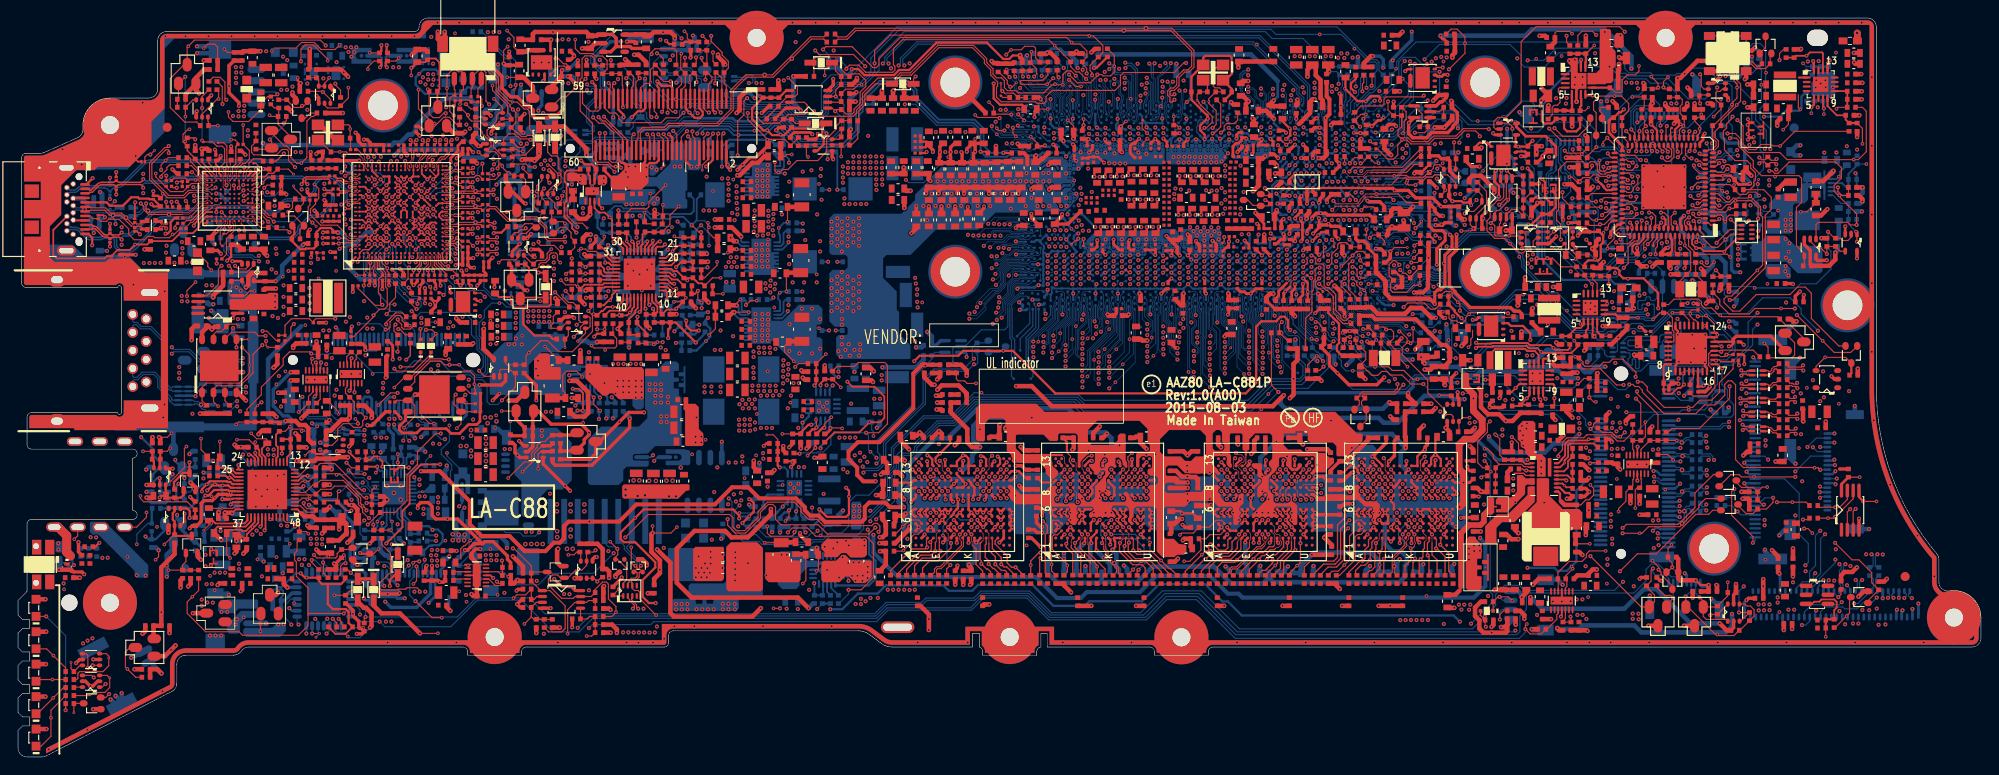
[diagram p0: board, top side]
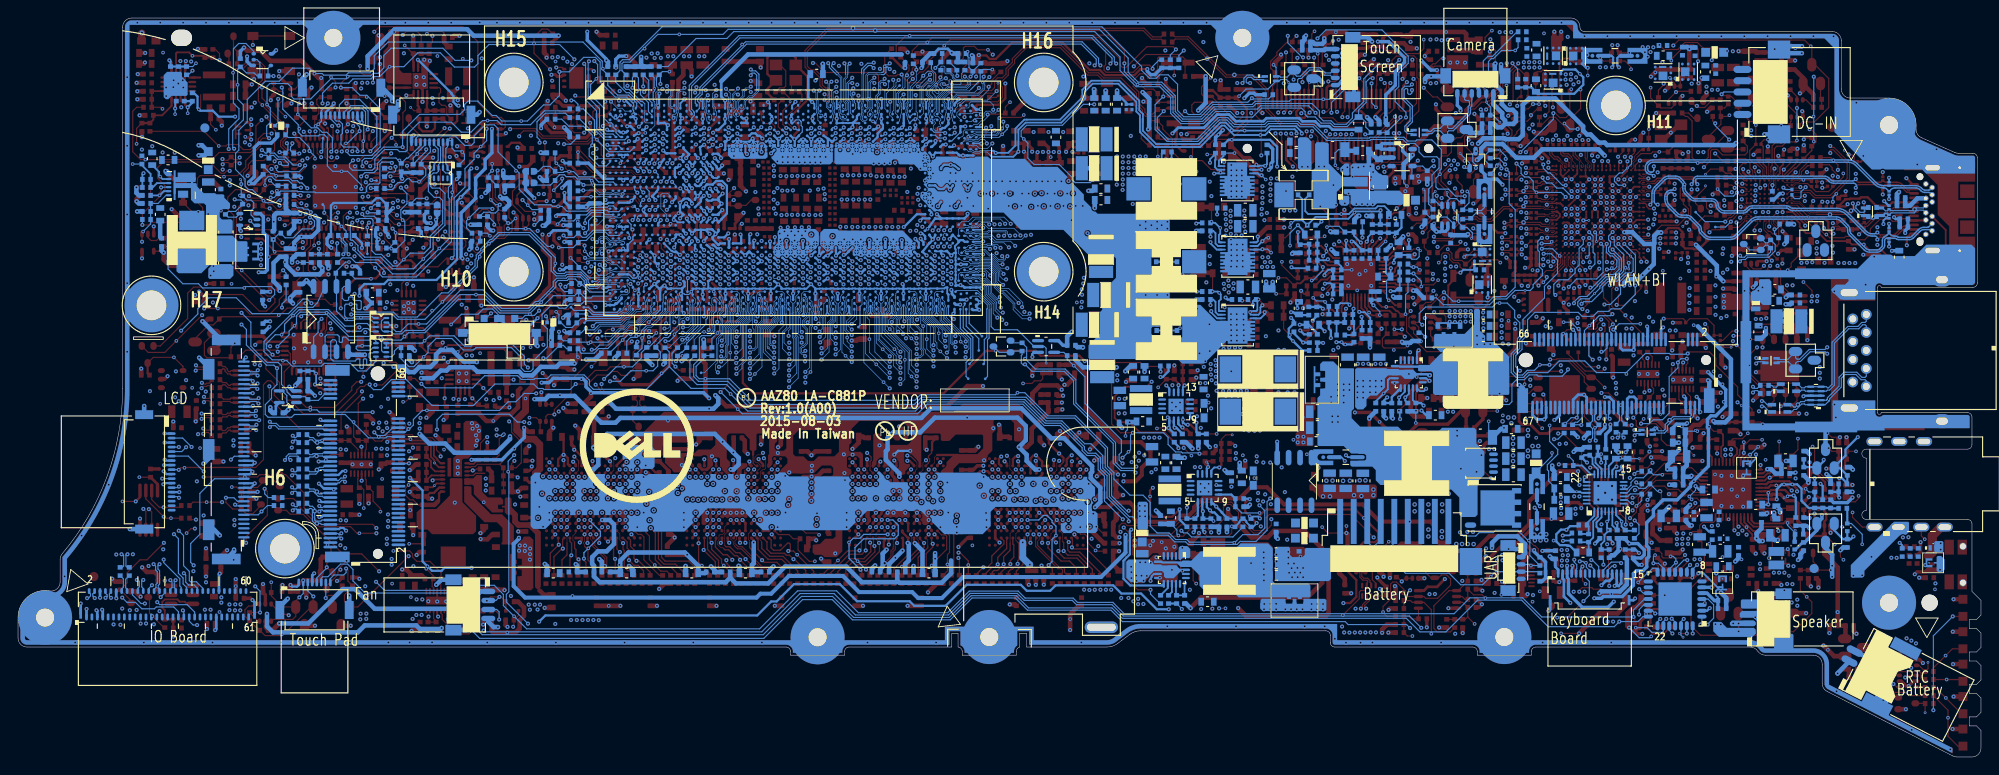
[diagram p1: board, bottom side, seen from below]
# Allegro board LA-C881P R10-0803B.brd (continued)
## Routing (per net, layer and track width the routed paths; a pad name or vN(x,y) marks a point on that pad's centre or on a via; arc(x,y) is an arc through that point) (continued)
+1.0VA_XDP: length 114.6
  TOP w0.127: RC138.1 77.11,77.2 v2(77.11,78.19) ; JXDP1.44 68.1,68.87 v2(68.33,69.1) ; JXDP1.43 68.1,74.3 68.28,74.49 68.28,75.54 67.92,75.9 CC28.1 67.79,75.62 v2(67.49,75.32)
  IN1 w0.081: v2(67.49,75.32) 67.49,75.32 67.49,75.31 68.55,76.36 69.67,76.36 70.15,76.85 70.69,76.85 72.31,78.47 76.84,78.47 v2(77.11,78.19)
  BOTTOM w0.127: RC216.2 69.06,71.79 68.22,72.62 68.22,74.91 67.82,75.32 v2(67.49,75.32) ; RC216.2 69.27,71.01 70.32,69.96 71.83,69.96 72.21,70.34 73.19,70.34 73.88,71.03 74.74,71.03 74.99,71.28 74.99,71.61 75.39,72.01 79.82,72.01 80.82,71.01 82.67,71.01 83.29,71.63 84.91,71.63 86.26,70.28 88.77,70.28 89.91,71.41 89.91,73.16 91.12,74.38 93.74,74.38 95.53,76.17 95.53,77.68 98.34,80.49 138.4,80.49 139.16,79.73 142.58,79.73 145.69,76.62 RC115.2 ; RC216.2 68.83,71.01 68.26,70.44 68.26,69.9 CC29.1 67.87,69.1 v2(68.33,69.1)
+1.0VAP: length 22.1
  IN1 w0.203: v2(203.89,64.78) 203.43,64.32 203.43,58.76 202.46,57.79 202.46,54.97 200.46,52.97 196.14,52.97 195.58,53.53 195.58,54.85 196.14,55.41 v2(196.17,55.41)
  BOTTOM w0.203: v2(203.89,64.78) 204.01,64.65 PC707.1 PR704.1
  vias: v2(196.13,57.49) v2(196.55,57.02) v2(196.62,55.03) v3(196.47,56.07)
+1.0VS_VCCIO: length 170.5
  TOP w0.127: RC132.1 76.43,79.54 v2(75.95,80.02)
  TOP w0.305: UE5.B51 177.8,59.06 177.47,59.06 176.72,58.31 176.72,57.78 v2(176.64,57.71)
  TOP w0.381: v2(127.43,57.79) 127.86,57.36 CC252.1 128.12,57.11 128.63,56.6 CC186.1 128.63,55.94 v2(128.91,55.66)
  TOP w0.508: CC248.1 CC251.1 CC250.1 CC253.1 ; RC2.1 122.28,67.33 v2(122.49,67.12) ; CC252.1 128.75,57.36 CC249.1 ; RE70.1 177.39,72.32 v2(176.94,72.78)
  IN1 w0.381: v2(75.95,80.02) 75.35,80.61 70.62,80.61 69.08,79.07 69.08,77.75 68.64,77.31 68.13,77.31 67.57,76.74 67.05,76.74 66.58,76.27 61.75,76.27 60.45,74.98 v2(60.45,74.8) ; v2(122.49,67.12) 122.16,67.45 122.16,69.36 120.82,70.7 118.16,70.7 117.22,71.64 114.28,71.64 113.28,70.64 113.28,69.7 113,69.43 112.49,69.43 112.49,69.43 111.23,69.43 110.52,68.72 108.18,68.72 107.65,68.18 99.79,68.18 99.52,68.46 94.8,68.46 v2(94.34,68.92) ; v2(165.23,69.71) 165.23,69.5 165.61,69.12 166.12,69.12 168.36,71.36 175.7,71.36 176.94,72.6 v2(176.94,72.78)
  IN2 w0.381: v2(60.45,74.8) 58.46,72.81 58.46,71.65 v2(58.27,71.46)
  IN3 w0.381: v2(94.34,68.92) 94.06,68.92 92.08,66.94 83.53,66.94 81.93,68.54 79.95,68.54 79.38,67.97 74.05,67.97 73.46,68.57 73.46,69.79 72.98,70.27 71.97,70.27 71.69,69.99 59.73,69.99 v2(58.27,71.46)
  IN3 w0.457: v2(168.51,55.34) 168.49,55.34 168.49,55.32 169.06,54.75 171.56,54.75 171.73,54.92 174.49,54.92 176.64,57.07 v2(176.64,57.71)
  IN4 w0.508: v2(122.49,67.12) 124.42,65.19 126.57,65.19 127.08,64.68 127.08,60.82 128.5,59.39 133.48,59.39 135.3,57.57 v2(135.3,57.26)
  BOTTOM w0.254: UCPU1.AM42 128.51,56.05 v2(128.91,55.66) 128.91,56.5 UCPU1.AL42
  BOTTOM w0.381: v2(168.51,55.34) 168.49,55.32 168.49,55.29 168.64,55.44 168.64,60.37 167.03,61.98 167.03,64.25 165.99,65.29 165.99,66.29 165.23,67.05 v2(165.23,69.71) ; CE50.1 177.06,58.31 176.77,58.02 176.77,57.83 v2(176.64,57.71)
  vias: v2(134.37,55.66) v2(135.28,55.66) v2(167.5,55.65) v2(167.54,54.77) v2(167.94,55.2) v2(167.94,54.34) v3(166.57,55.51)
+1.0VS_VCCIOP: length 7.5
  TOP w0.508: v2(170.69,45.98) 170.89,45.78 171.27,45.78 PR1408.1
  IN4 w0.254: v2(170.69,45.98) 168.99,47.68 168.98,47.68 167.46,49.2 167.46,50.2 167.64,50.38 168.4,50.38 168.4,50.37 v2(168.58,50.2)
+1.2V_DDR: length 207.2
  TOP w0.076: 115.83,33.51 115.88,33.46 115.9,33.46 116.1,33.26 116.1,32.64 116.44,32.3 UD20.C12
  TOP w0.127: UD22.F2 152.02,24.3 ; UD19.H3 104.17,25.1 ; 101.82,32.83 101.82,32.71 101.97,32.56 UD19.E12 ; 136.25,33.54 136.25,32.6 135.94,32.3 UD21.E12 ; 141.27,28.3 141.27,28.89 141.06,29.1 UD21.N8
  TOP w0.152: v2(138.56,21.88) 139.12,22.44 139.57,22.44 140.43,23.29 140.43,24.05 140.35,24.12 UD21.M2
  TOP w0.254: v2(129.8,28.43) 129.29,28.94 CD157.1 ; v2(120.02,28.7) 119.69,29.03 UD20.H8 ; CD6.1 125.93,33.82 v2(126.17,33.58) ; UD20.K8 120.99,29.18 v2(120.67,29.5) ; 101.82,32.83 101.82,33.2 v2(102.29,33.68) 103.42,34.81 CD152.1 ; UD20.G12 UD20.H12 ; UD20.H12 119.69,33.34 119.84,33.49 120.52,33.49 v2(120.58,33.55) ; UD20.H12 UD20.H11 ; UD19.A8 99.62,28.82 v2(99.11,28.3) 99.09,28.33 99.09,29.68 99.24,29.83 99.55,29.83 UD19.A9 ; UD20.M2 UD20.L2 121.64,24.01 121.74,23.91 121.74,23.3 v2(121.44,23) ; UD19.G5 103.84,27.02 103.84,27.17 104.17,27.5 UD19.H6 104.19,27.5 104.29,27.6 104.29,28.55 v2(104.32,28.57) 104.17,28.72 104.17,29.1 UD19.H8 ; CD60.1 157.28,35.34 v2(157.28,33.52) ; CD7.1 129.04,33 v2(129.72,32.32) ; v2(153,25.5) 153.32,25.18 UD22.H3 ; UD19.R12 108.97,32.55 108.97,33.08 v2(108.71,33.33) ; UD20.P6 UD20.P5 ; UD19.K8 UD19.K6 105.47,27.42 v2(105.78,27.11) 106.12,26.77 UD19.L5 ; v2(149.75,31.9) 150.07,32.22 UD22.C12 ; UD19.E8 102.22,29.03 v2(101.9,28.7) ; UD19.D6 101.57,27.43 v2(101.9,27.1) ; v2(157.28,33.52) 157.16,33.52 156.8,33.16 156.8,32.53 ; v2(157.28,33.52) 157.39,33.52 157.87,33.04 157.87,32.3 ; v2(104.5,27.1) 104.17,26.78 UD19.H5 ; v2(104.5,27.1) 104.82,26.78 UD19.J5 ; v2(104.5,27.1) 104.82,27.43 UD19.J6 ; v2(137.1,23.77) 137.1,23.77 137.1,24.3 UD21.G2 ; v2(151.7,28.7) 151.7,28.77 UD22.E8 ; v2(125.2,33.55) 124.57,33.55 124.24,33.22 UD20.R12 ; 156.8,32.53 UD22.N12 ; 156.8,32.53 156.8,32.49 156.61,32.3 156.57,32.3 ; UD21.A9 132.64,29.9 132.24,29.5 v2(132.24,28.63) 132.72,29.1 UD21.A8 ; UD22.U9 159.17,29.82 159.64,29.35 159.64,29.24 v2(159.66,29.22) 159.54,29.1 UD22.U8 ; UD22.G2 152.67,24.22 v2(152.35,23.9) 152.02,24.23 152.02,24.3 ; 117.74,32.3 UD20.E12 ; v2(99.26,31.89) 99.62,31.53 UD19.A11 ; 157.87,32.3 UD22.R12 ; 157.87,32.3 157.87,32.3 ; v2(139.83,23.76) 139.7,23.88 UD21.L2 ; UD19.M2 106.77,24.26 v2(106.32,23.81) 106.12,24.01 UD19.L2 ; UD22.P4 157.22,25.98 v2(157.55,26.3) 157.55,26.37 UD22.P5 157.22,26.78 v2(157.55,27.1) 157.32,27.33 157.32,27.36 157.22,27.46 UD22.P6 ; 154.96,26.31 v2(154.96,26.3) ; UD19.K12 105.47,33.12 105.16,33.44 104.9,33.44 v2(104.86,33.47) 104.17,32.79 104.17,32.3 UD19.H12 UD19.G12 ; UD19.K12 UD19.L12 ; UD19.K12 UD19.K11 ; v2(129.76,30.46) 129.76,30.45 129.73,30.48 128.81,30.48 128.45,30.84 CD158.1 ; UD20.F2 118.39,24.3 118.39,23.82 v2(118.29,23.72) ; 136.25,34.25 136.25,33.54 ; 104.17,25.1 103.99,25.28 103.99,25.29 103.85,25.43 v2(103.85,25.5) ; v2(135.48,26.3) 135.15,26.63 UD21.D5 134.83,27.02 v2(134.83,27.1) ; 101.25,27.04 v2(101.25,27.1) ; v2(107.26,28.56) 107.42,28.72 UD19.N8 ; UD21.U9 144.02,29.9 v2(144.13,29.79) ; v2(156.09,34.09) 156.01,34.09 155.27,33.36 UD22.L12 UD22.K12 ; v2(137.43,24.7) 137.75,25.03 UD21.H3 ; v2(118.07,28.67) 117.74,29 UD20.E8 ; v2(156.9,28.7) 156.9,28.77 UD22.N8 ; UD21.F2 136.43,24.3 136.18,24.04 v2(136.18,23.8) ; UD19.U11 110.23,31.71 110.23,31.71 v2(110.67,31.71) 111.06,31.71 111.82,30.95 CD29.1 ; UD22.E12 151.37,32.4 150.43,33.34 v2(150.29,33.34) ; UD19.D4 101.74,26.07 101.75,26.07 101.9,26.21 v2(101.9,26.3) ; UD19.P5 108.07,26.8 v2(107.77,27.1) 108.07,27.4 UD19.P6 ; UD20.H9 119.69,29.83 v2(120.02,29.5) 120.02,29.58 UD20.J9 UD20.J10 ; UD22.U11 159.21,31.5 v2(159.56,31.15) ; UD20.H3 119.69,24.95 UD20.G2 119.04,24.3 119.04,23.79 v2(119.08,23.74) ; 142.3,32.3 UD21.R12 ; v2(116.77,26.3) 116.77,26.38 UD20.D5 116.77,27.02 v2(116.77,27.1) ; UD19.H9 UD19.J9 104.83,29.9 105.15,30.21 v2(105.15,30.3) 104.82,30.63 UD19.J10 104.17,31.35 UD19.H11 ; v2(129.74,31.73) CD175.1 ; CD57.1 147.09,31.58 147.85,32.34 v2(148.16,32.34) 148.16,32.34 148.64,31.86 148.64,31.63 UD22.A11 ; UD19.N12 107.42,32.3 107.42,33.05 107.14,33.33 106.9,33.33 v2(106.84,33.4) ; UD19.P4 108.07,25.97 v2(107.75,26.29) ; CD155.1 113.53,33.51 115.83,33.51 ; v2(100.87,32.81) 100.92,32.76 100.92,32.3 UD19.C12 ; UD22.M2 UD22.L2 155.27,24.03 155.47,23.83 v2(155.47,23.81) ; v2(138.06,31.11) 137.75,31.42 UD21.H11 ; UD20.U11 v2(126.11,31.5)
  TOP w0.305: UD19.K5 105.47,26.8 v2(105.78,27.11) ; v2(103.85,24.7) 103.52,24.38 UD19.G2 ; UD19.F2 102.87,24.04 v2(102.64,23.81)
  TOP w0.32: v2(127.97,53.1) 127.61,52.75 CC258.1 ; CD170.1 162.03,28.94 v2(162.08,28.89) ; v2(138.03,53.1) 138.02,53.1 CC259.1 ; CD169.1 v2(160.73,32.87) ; v2(134.24,49.08) 134.34,49.18 CC178.1 CC176.1 ; CC257.1 131.67,53.06 v2(131.63,53.1)
  TOP w0.381: v2(156.09,34.09) 156.13,34.13 156.13,34.4 156.38,34.65 CD172.1 ; CD179.1 151.81,34.86 v2(150.29,33.34) ; v2(122.22,34.58) 122.5,34.86 CD5.1 ; v2(118.81,33.97) 118.05,34.72 CD1.1 ; CD155.1 CD148.1
  TOP w0.508: RC171.1 130.02,57.74 v2(129.79,57.97) ; CD159.1 115.01,35.85 114.33,36.53 109.65,36.53 v2(109.6,36.48) 110.28,35.8 CD86.1 ; CD4.1 97.84,29.06 v2(98.32,28.58) ; RD17.1 100.56,42.15 101.4,41.3 v2(101.69,41.3) ; v2(98.4,32.9) 98.32,32.98 CD8.1 ; v2(105.54,21.34) 105.54,21.19 105.77,20.96 CD149.1 CD151.1 ; CD168.1 147.45,33.74 v2(148.01,34.3) 148.89,35.18 CD59.1 ; RD21.1 v2(101.98,39.33) ; v2(157.3,38.72) 156.89,38.31 RD22.1 ; v2(106.74,36.36) 106.85,36.24 CD37.1 ; CD3.1 97.68,31.58 v2(98.11,31.15) ; v2(98.91,25.56) 98.91,25.31 97.33,23.73 CD153.1 ; CC179.1 123.1,48.98 v2(123.23,49.11) ; CD33.1 100.5,35.55 v2(100.05,36) 99.7,35.65 CD2.1 ; v2(127.13,22.59) CD160.1 CD154.1 ; CD91.1 v2(143.56,22.44) ; CD63.1 CD175.1
  IN2 w0.254: v2(118.07,28.67) 118.07,28.01 117.16,27.1 v2(116.77,27.1) v2(116.77,26.3)
  IN3 w0.508: v2(165.71,47.28) 162.89,47.28 162.3,46.68 161.64,46.68 160.83,45.88 160.83,44.69 159.66,43.52 159.21,43.52 157.45,41.76 157.45,38.87 v2(157.3,38.72)
  BOTTOM w0.127: UCPU1.AU23 138.33,52.8 v2(138.03,53.1)
  BOTTOM w0.152: UCPU1.BB41 129.33,49.21 ; v2(134.24,49.08) 134.29,49.13 UCPU1.BB32
  BOTTOM w0.178: UCPU1.BB23 139.27,49.9 139.29,49.85 139.29,49.12 v2(139.44,48.96) ; v2(123.23,49.11) 123.22,49.12 123.22,49.66 123.22,49.95 UCPU1.BB51
  BOTTOM w0.254: UCPU1.BB47 125.58,49.91 125.58,49.19 v2(125.65,49.11) ; UCPU1.AU28 v2(135.28,53.1) ; UCPU1.AU35 v2(131.63,53.1) ; 129.33,49.21 129.33,48.64 129.29,48.6 v2(129.29,48.6) ; UCPU1.AU42 v2(127.97,53.1) ; v2(120.58,33.55) 120.16,33.97 v2(118.81,33.97)
  BOTTOM w0.381: CC240.1 101.85,45.68 102.38,46.2 UC2.5
  BOTTOM w0.508: CD34.1 117.45,22.87 v2(118.29,23.72) ; v2(100.89,47.18) 101.4,46.67 CC240.1 ; CD171.1 151.11,20.53 CD64.1 150.98,21.8 150.09,22.69 143.82,22.69 v2(143.56,22.44) 142.34,21.22 CD58.1 141.58,20.41 CD89.1 ; v2(119.08,23.74) 118.97,23.64 118.97,21.8 119.36,21.42 CD41.1 ; CD85.1 136.25,20.53 CD62.1 136.37,21.29 136.18,21.49 v2(136.18,23.8) ; v2(121.44,23) 121.87,22.56 121.87,21.12 122.15,20.84 CD156.1
  BOTTOM w0.762: v2(105.54,21.34) 105.56,21.34 106.32,22.11 v2(106.32,23.81)
  vias: v2(101.25,26.3) v2(110.62,32.93) v2(110.64,28.98) v2(119.37,27.1) v2(120.67,27.1) v2(121.32,27.1) v2(129.77,29.19) v2(132.24,31.58) v2(133.5,33.74) v2(135.62,28.61) v2(137.44,27.11) v2(138.07,29.49) v2(138.08,27.11) v2(138.73,27.09) v2(138.78,28.61) v2(139.38,27.09) v2(140.81,33.36) v2(141.33,27.1) v2(141.33,26.3) v2(144.15,32.39) v2(150.4,27.1) v2(150.4,26.3) v2(151.05,27.1) v2(153,27.1) v2(153.65,30.3) v2(153.65,29.5) v2(153.65,28.7) v2(154.3,29.5) v2(154.3,27.1) v2(154.95,28.7) v2(160.99,23.13) v2(161,22.51) v2(161.01,21.9) v2(161.55,23.45) v2(161.57,22.86) v2(162.14,23.47) v2(162.22,22.88) v3(145.69,37.32)
+1.2V_DDRP: length 17.8
  TOP w0.508: v2(174.32,30.97) 174.04,30.69 PC609.1 PR603.1
  BOTTOM w0.254: v2(174.32,30.97) 172.92,29.57 172.92,21.7 v3(172.38,21.15) 171.88,20.66 170.82,20.66 170.49,20.99 v2(167.49,20.99)
+1.2V_MEM_CPUCLK: length 2
  TOP w0.127: v3(130.18,55.18) 130.04,55.32 130.04,55.44 129.82,55.66 v2(129.79,55.66)
  TOP w0.254: RC171.2 130.02,55.89 v2(129.79,55.66)
  BOTTOM w0.254: v2(129.79,55.66) 129.4,56.05 UCPU1.AM40
+1.8V_PGPP: length 8
  TOP w0.381: RC304.2 149.98,60.14 145.29,60.14 145.1,60.33 v3(144.53,60.33) 144.04,60.33 143.6,59.89 v2(143.6,59.75)
  BOTTOM w0.254: UCPU1.AF16 143.6,59.59 v2(143.6,59.75)
+1.8VA: length 357.2
  TOP w0.254: v2(108.26,74.74) 108.26,73.08 108.97,72.37 111.42,72.37 111.65,72.14 R1334.1
  TOP w0.457: RH150.2 156.46,52.1 155.91,51.55 v2(154.89,51.55)
  TOP w0.508: R79.1 161.2,36.09 v2(161.65,36.53) ; RC304.1 152.38,60.16 152.38,60.62 152.62,60.87 153.31,60.87 CC272.1 154.15,60.41 v2(154.79,61.05) ; RH150.2 RH144.2 156.52,54.36 RH149.2 RH152.2 RH151.2 ; C1169.1 v2(30.28,42.71) ; v2(82.42,16.52) 81.48,15.58 72.77,15.58 72.39,15.96 72.39,21.55 v2(70.92,23.02)
  IN1 w0.508: v2(167.89,69.75) 167.89,69.71 167.23,69.05 167.23,68.16 167.46,67.93 167.46,66.33 167.11,65.97 163.83,65.97 161.19,63.33 161.19,61.76 160.48,61.05 158.83,61.05 158.37,61.5 v2(158.37,61.68)
  IN2 w0.381: v2(167.49,32.98) 167.92,33.41 170.05,33.41 171.17,32.29 171.17,28.36 171.91,27.62 171.91,20.41 168.45,16.95 164.01,16.95 163.89,16.84 162.81,16.84 161.33,15.35 160.79,15.35 160.55,15.11 160.55,14.6 160.34,14.4 158.56,14.4 v2(158.2,14.76) ; v2(161.65,36.53) 161.9,36.53 162.22,36.85 162.22,38.42 161.84,38.8 161.84,41.78 163.36,43.31 163.36,46.43 161.84,47.95 161.17,47.95 160.83,48.29 160.83,49.55 158.83,51.55 v2(154.89,51.55)
  IN2 w0.457: v2(42.91,17.61) 42.93,17.63 42.93,18.42 43.43,18.93 46.13,18.93 46.6,18.46 49.19,18.46 49.53,18.8 53.31,18.8 53.57,19.06 56.83,19.06 57.37,18.53 60.15,18.53 60.36,18.74 62.22,18.74 64.11,20.62 66.31,20.62 67.92,22.23 70.13,22.23 v2(70.92,23.02)
  IN2 w0.508: v2(154.79,61.05) 154.64,61.05 152.65,63.03 152.65,65.76 v2(152.86,65.97)
  IN3 w0.381: v2(82.42,16.52) 83.24,15.71 94.97,15.71 95.53,16.26 99.59,16.26 100.27,15.59 125.36,15.59 125.53,15.77 131.16,15.77 133.25,13.67 157.11,13.67 v2(158.2,14.76) ; v2(126.98,74.99) 126.63,74.99 126.14,74.49 126.14,73.01 126.55,72.6 127.63,72.6 127.99,72.24 128.42,72.24 129.46,73.29 135.18,73.29 136.3,72.16 136.77,72.16 137.34,72.73 137.34,74.57 138.9,76.13 144.41,76.13 144.77,75.78 151.24,75.78 152.59,74.43 153.62,74.43 155.56,72.49 155.56,69 155.22,68.67 154.74,68.67 154.56,68.84 153.42,68.84 153.11,68.54 152.17,68.54 151.71,68.08 151.71,66.48 152.22,65.97 v2(152.86,65.97)
  IN3 w0.508: v2(154.79,61.05) 157.73,61.05 v2(158.37,61.68)
  VCC w0.254: v2(108.26,74.74) 108.42,74.9 111.31,74.9 112.1,74.11 120.85,74.11 121.33,73.63 123.04,73.63 123.48,74.08 123.48,74.6 124.75,75.87 125.8,75.87 126.68,74.99 v2(126.98,74.99)
  IN4 w0.356: v2(154.79,61.05) 154.31,61.05 153.09,59.83 153.09,58.58 151.56,57.06 151.56,54.87 v2(154.89,51.55)
  BOTTOM w0.203: 153.18,61.43 153.13,61.38 152.44,61.38 152.31,61.51 UCPU1.AA1
  BOTTOM w0.381: v2(161.65,36.53) 161.65,35.45 164.12,32.98 v2(167.49,32.98) ; v2(42.91,17.61) 42.11,17.61 41.92,17.8 39.82,17.8 38.57,19.05 38.57,20.35 38.24,20.67 37.5,20.67 37.08,21.09 37.08,22 36.86,22.23 36.86,23.18 37.1,23.42 37.1,26.01 36.35,26.76 36.35,27.46 35.27,28.53 33.71,28.53 32.23,30.01 32.23,30.29 30.24,32.28 30.24,36.48 30.35,36.6 30.35,37.47 29.97,37.85 29.43,37.85 28.32,38.96 28.32,40.75 v2(30.28,42.71)
  BOTTOM w0.508: 153.18,61.43 154.41,61.43 v2(154.79,61.05) CC212.1
  vias: v3(29.67,42.78)
+1.8VAP: length 16
  TOP w0.254: PU800.14 173.42,77.34 v2(173.44,77.36) ; 169.09,71.69 169.09,70.57 169.37,70.29 170.18,70.29 170.66,70.77 PC801.1 PR802.1 171.55,69.76 171.89,69.42 172.91,69.42 173.33,69.84 PR806.2
  BOTTOM w0.254: v2(168.94,72.27) 169.09,72.27 169.21,72.4 169.49,72.68 169.49,73.35 169.7,73.55 169.7,73.65 173.41,77.36 v2(173.44,77.36)
  vias: v3(168.45,77.48)
+1.8VS_AUDIO: length 39.7
  TOP w0.203: v2(23.75,27.06) 24.17,27.48 UA2.36
  TOP w0.508: v2(23.75,27.06) 23.7,27.11 v2(22.96,27.11) 22.96,26.64 CA78.1 ; v2(33.1,23.02) 33.49,22.63 RA81.1
  IN3 w0.508: v2(33.52,34.88) 32.82,35.58 32.82,36.28 33.3,36.76 33.3,37.42 32.94,37.78 32.18,37.78 31.75,38.21 29.86,38.21 v2(29.19,38.88) ; v2(23.75,27.06) 26.8,27.06 31.01,22.84 32.21,22.84 32.39,23.02 v2(33.1,23.02)
  IN4 w0.508: v2(23.75,27.06) 24.41,27.06 26.34,28.99 29.82,28.99 30.91,30.08 30.91,31.61 32.84,33.54 32.84,34.41 33.31,34.88 v2(33.52,34.88)
  BOTTOM w0.508: CA83.1 22.96,26.69 v2(22.96,27.11) ; RA82.1 v2(33.52,34.88) ; v2(23.75,27.06) 23.85,26.96 RA63.1
  vias: v3(28.55,39.4)
+1.8VU: length 61.6
  TOP w0.254: UD21.A6 133.02,27.5 v2(132.65,27.12) 133.07,26.7 UD21.A5 ; UD21.U3 143.6,25.17 v2(143.93,25.5) 143.89,25.54 143.76,25.54 143.6,25.7 UD21.U4 143.6,25.98 v2(143.93,26.3) 143.6,26.63 143.6,26.7 ; UD19.A4 99.62,25.86 99.95,25.54 v2(99.95,25.5) 99.95,25.48 99.62,25.16 UD19.A3 ; CD147.1 98.88,30.44 v2(99.01,30.31) 99.4,30.7 UD19.A10 ; 143.6,26.7 143.6,26.77 v2(143.93,27.1) 143.6,27.43 UD21.U6 ; 143.6,26.7 UD21.U5 ; UD19.U10 110.3,30.7 v2(110.67,31.07) ; UD20.U10 126.03,30.7 v2(126.05,30.72) ; v2(148.4,31.07) 148.77,30.7 UD22.A10 ; v2(143.98,31.11) 143.98,31.08 UD21.U10 ; CD90.1 130.37,27.04 v2(129.16,27.04) 129.16,27.1 128.98,27.28 CD42.1 ; v2(110.35,26.3) 110.02,26.63 110.02,26.7 UD19.U5 110.03,26.7 v2(110.4,27.08) 110.02,27.46 UD19.U6 ; UD20.A3 115.14,25.19 115.45,25.5 v2(115.47,25.5) 115.47,25.55 115.14,25.87 UD20.A4 ; UD21.A10 133.18,30.7 v2(132.69,31.19) ; UD22.A3 148.77,25.17 v2(149.1,25.5) 148.77,25.83 UD22.A4 ; CD145.1 113.61,30.46 v2(114.69,30.46) 114.9,30.46 UD20.A10 ; UD22.A6 148.77,27.49 v2(148.39,27.11) 148.77,26.73 UD22.A5 ; UD20.U3 125.54,25.17 v2(125.87,25.5) 125.54,25.83 UD20.U4 125.54,25.98 v2(125.87,26.3) 125.54,26.63 UD20.U5 125.54,26.78 v2(125.87,27.1) 125.54,27.43 UD20.U6 ; UD21.A3 133.2,25.17 v2(133.53,25.5) 133.2,25.83 UD21.A4 ; v2(160.4,30.45) 159.42,30.45 UD22.U10 ; UD20.A5 115.01,26.7 v2(114.59,27.12) 114.88,27.41 115.05,27.41 UD20.A6 ; UD19.A6 99.42,27.5 99.09,27.17 v2(99.09,27.12) 99.08,27.12 99.07,27.1 99.47,26.7 UD19.A5
  TOP w0.305: UD19.U3 110.35,25.43 v2(110.35,25.5) 110.02,25.83 UD19.U4 110.02,25.98 v2(110.35,26.3)
  TOP w0.32: v2(160.4,30.45) 161.07,30.45 CD144.1
  TOP w0.381: CD143.1 113.01,25.99 113.46,25.54 v2(113.64,25.54) ; v2(143.93,27.1) 144.15,26.88 CD165.1 ; v2(143.98,31.11) 143.98,31.12 144.81,31.12 145.24,30.69 CD163.1 ; v2(113.64,24.9) 113.08,24.9 112.75,25.23 CD164.1 ; v2(143.93,25.5) 144.04,25.61 CD162.1
  TOP w0.508: v2(98.49,27.01) 98.27,26.78 CD92.1 97.33,26.12 97.2,25.99 CD146.1
  TOP w0.762: v2(159.97,27.75) 160.4,28.18 v2(160.4,30.45) 160.4,31.48 159.92,31.96 159.92,34.68 160.5,35.26 161.44,35.26 161.51,35.33 161.52,35.33 162.41,36.22 162.41,36.23 162.47,36.29 162.47,37.42 161.49,38.4 v3(161.49,39.79) 161.49,40.24 160.57,41.17
  vias: v2(158.86,27.1) v2(158.86,26.3) v2(159.55,25.55)
+1.8VUP: length 17.5
  TOP w0.203: PU900.14 168.72,44.63 168.3,45.04 167.48,45.04 167.25,45.27 163.91,45.27 163.33,44.69 PL901.2
  TOP w0.508: 162.08,40.9 162.33,40.65 162.33,38.81 163.11,38.03 164.33,38.03 v3(165.08,37.29) 165.83,37.29 PC901.1 PR902.1 168.94,38.19 PR906.2
+3.3V_ALW_DEG: length 3.8
  BOTTOM w0.127: RE76.2 168.28,66.3 168.28,66.89 v3(168.52,67.13) 168.64,67.25 169.35,67.25 169.65,67.55 JDEG1.1
+3.3V_PGPP: length 14.9
  TOP w0.305: v2(144.35,59.78) 144.37,59.75 CC268.1 144.37,58.75 v2(143.7,58.07)
  TOP w0.381: CC268.1 144.53,59.04 145.25,59.04 145.38,59.17 v3(145.4,59.17) 145.68,58.89 146.6,58.89 147.04,58.44 RC211.2 ; CC267.1 144.81,62.29 144.45,61.93 144.45,61.6 v2(144.36,61.51) ; v2(143.03,63.1) CC265.1 v2(143.03,61.4)
  IN4 w0.381: v2(143.7,58.07) 143.98,58.07 144.44,57.61 v2(144.44,57.28)
  BOTTOM w0.254: v2(144.35,59.78) 144.35,59.8 143.99,60.16 UCPU1.AD15 144.36,60.54 144.36,60.85 144.36,60.86 144.36,61.16 144.36,61.16 v2(144.36,61.51) 144.02,61.85 UCPU1.Y15 143.88,61.96 143.45,61.96 UCPU1.Y16 143.32,61.85 143.03,61.55 v2(143.03,61.4) ; v2(144.44,57.28) 143.99,56.83 UCPU1.AK15 ; UCPU1.AG15 143.99,58.36 v2(143.7,58.07) ; UCPU1.T16 143.34,63.42 v2(143.03,63.1)
+3.3V_SPI: length 2.5
  TOP w0.254: 144.26,57.89 v2(143.63,57.26) ; 144.26,57.89 144.63,58.25 RC213.2 ; 144.26,57.89 v3(144.26,57.89)
  BOTTOM w0.254: v2(143.63,57.26) 143.63,57.36 143.34,57.65 UCPU1.AJ16
+3.3VDX_SSD:
  vias: v2(176.74,26.2) v2(176.75,39.74) v2(176.76,26.91) v2(176.76,25.54) v2(176.95,37.1) v2(176.86,36.5) v2(176.88,24.22) v2(176.89,23.62) v2(177.36,36.14) v2(177.74,37.1) v2(177.82,36.52) v3(177.52,38.85)
+3V_LDO: length 71.9
  TOP w0.381: PR281.1 63.48,33.04 64.11,33.67 PQ222.1 64.56,35.01 v3(66.73,37.18) 67.78,38.24 v2(69.47,38.24) ; v2(56.21,71.37) 55.73,70.89 PC210.1
  IN3 w0.508: v2(56.21,71.37) 56.21,70.77 58.01,68.97 58.01,67.4 ; 58.01,67.4 56.67,66.05 56.67,61.94 57.2,61.41 60.39,61.41 62.54,59.26 63.91,59.26 64.49,58.68 66.57,58.68 67.29,57.97 67.29,56.24 68.28,55.25 68.28,51.75 68.86,51.16 70.08,51.16 74.57,46.67 77.29,46.67 v2(77.95,47.33) ; 58.01,67.4 59.54,67.4 v2(60.77,66.16)
  IN4 w0.381: v2(77.95,47.33) 73.64,43.01 73.64,40.08 72.2,38.64 70.89,38.64 70.49,38.24 v2(69.47,38.24)
+3V_PCH: length 292
  TOP w0.254: RC23.2 156.24,65.39 156.23,65.39 156.08,65.24 156.08,65.24 155.7,64.86 RC12.2
  TOP w0.305: v2(141.71,57.24) 141.71,57.75 CC223.1 ; RC26.2 150.67,55.61 149.78,56.5 RH148.1
  TOP w0.356: v2(158.9,57.95) 159.12,57.73 159.12,56.48 158.33,55.69 158.33,52.31 157.86,51.84 157.52,51.84 157.2,51.51 v2(157.2,50.26) ; v2(141.71,57.24) 141.54,57.24 141.35,57.43 R9.1
  TOP w0.381: CC209.1 141.03,62.32 v2(141.09,62.26) ; RC213.1 146.15,57.85 v2(146.51,57.49) ; v2(157.44,63.15) 156.75,63.84 RC14.2 ; v2(142.6,56.23) 142.79,56.42 CC224.1 ; v2(64.19,75.24) 63.98,75.45 RC133.1 ; RC211.1 148.44,57.49 148.68,57.24 149.37,57.24 149.78,56.83 RH148.1 ; 156.6,50.86 v2(157.2,50.26)
  TOP w0.508: RC187.1 RC74.1 141.96,44.04 141.53,43.62 v3(141.53,41.97) 141.53,40.22 v2(141.12,39.81) ; RC12.2 155.63,64.9 155.06,64.9 v2(154.94,64.78) ; RC26.2 RC184.1 150.67,53.81 RC186.1 150.85,53.68 151.74,52.79 RC183.1 151.74,51.46 152.34,50.86 156.6,50.86
  IN1 w0.254: v2(86.69,80.48) 86.11,80.48 82.99,77.36 79.89,77.36 78.07,79.18 72.69,79.18 72.39,79.48 72.39,79.69 72,80.08 71.04,80.08 69.52,78.56 69.52,77.5 68.88,76.87 68.34,76.87 67.77,76.3 67.24,76.3 66.74,75.8 64.75,75.8 v2(64.19,75.24)
  IN1 w0.381: v2(159.59,58.96) 158.9,58.28 v2(158.9,57.95) 158.9,57.59 159.28,57.21 159.28,56.22 158.39,55.32 158.39,53.91 157.74,53.25 153.33,53.25 152.68,53.91 v2(152.68,54.57) ; v2(154.94,64.78) 156.57,66.41 156.57,70.16 157.57,71.17 157.57,73.25 154.15,76.67 153.16,76.67 v2(152.53,77.3)
  IN1 w0.508: v2(185.8,52.89) 183.85,52.89 182.8,51.85 182.8,49.12 180.68,47 179.4,47 v2(179.27,47.13)
  IN2 w0.381: v2(154.94,64.78) 154.69,64.78 153.9,63.99 153.9,62.59 154.88,61.61 156.76,61.61 157.74,60.63 158.33,60.63 159.59,59.37 v2(159.59,58.96)
  IN2 w0.508: v2(154.76,44.1) 155.14,44.48 156.77,44.48 v2(159.72,41.54)
  IN3 w0.254: v2(86.69,80.48) 86.92,80.7 152.63,80.7 153.31,80.02 154.18,80.02 v2(154.65,80.49)
  IN3 w0.508: v2(181.41,26.24) 181.41,26.39 180.82,26.99 180.82,28.08 178.77,30.13 178.21,30.13 177.04,31.3 177.04,32.29 178.08,33.33 ; v2(179.27,47.13) 180.57,45.83 180.62,45.83 182.98,43.47 182.98,39.18 178.82,35.01 178.82,34.07 178.08,33.33 ; 178.08,33.33 182.25,33.33 184,35.09 184.86,35.09 186.18,36.41 187.52,36.41 189.5,34.43 192.31,34.43 193.71,35.82 195.81,35.82 196.42,35.21 198.38,35.21 199.06,35.89 201.54,35.89 v2(201.55,35.9)
  BOTTOM w0.203: UCPU1.V19 141.39,62.56 v2(141.09,62.26)
  BOTTOM w0.254: JAPS1.1 201.54,35.89 v2(201.55,35.9) ; v2(142.6,56.23) 142.69,56.32 UCPU1.AK17 ; UCPU1.AJ19 v2(141.71,57.24) ; UCPU1.AJ21 139.44,57.66 v2(139,58.1)
  BOTTOM w0.305: v2(157.2,50.26) 157.2,50.51 156.95,50.76 RH59.1 ; v2(158.9,57.95) 158.42,58.43 156.87,58.43 RC283.1
  BOTTOM w0.381: v2(154.65,80.49) 154.65,79.55 152.53,77.43 v2(152.53,77.3) ; RC17.2 156.87,63.71 v2(157.44,63.15) ; v2(159.72,41.54) 158.9,41.54 158.42,42.02 155.16,42.02 154.79,41.65 154.79,41.08 154.13,40.42 141.73,40.42 v2(141.12,39.81) ; v2(157.21,47.29) 157,47.08 RC288.1 ; RC13.1 159.77,70.14 v2(159.77,69.77)
  BOTTOM w0.508: RC191.2 RC189.2 ; RC189.2 RC185.2 RC188.2 ; RC189.2 148.67,76.85 v2(148.67,77.69) ; UH8.8 185.13,52.22 v2(185.8,52.89) 186.21,52.49 CC9.1 ; v2(152.53,77.3) 152.35,77.12 152.35,76.64 RC236.1 ; RH58.1 174.4,44.13 174.11,43.84 v2(174.11,43.83) ; v2(159.59,58.96) 159.36,58.96 158.9,59.42 RC284.1 RC285.1 ; RC73.2 153.8,44.1 v2(154.76,44.1) ; RC25.2 RC15.2 RC17.2
  vias: v2(182.02,26.27)
+3V_PCH_DSW: length 363.1
  TOP w0.305: v2(142.35,59.73) 142.35,59.46 142.52,59.29 142.52,57.36 142.36,57.21 v2(142.36,57.24)
  TOP w0.381: v2(151.6,42.13) 150.77,41.31 147.68,41.31 v3(146.4,42.58) 145.52,43.47 145.52,44.54 144.63,45.42 RC67.1
  TOP w0.457: RC214.2 158.85,45.31 158.43,45.73 157.93,45.73 155.09,48.57 150.62,48.57 150.24,48.95 148.84,48.95
  TOP w0.508: RC95.1 148.84,48.95 RC72.2 ; v2(156.08,43) 156.74,43 CC280.1 CC279.1 158.85,43.9 RC214.2 ; RC243.2 144.91,45.83 RC67.1 ; v2(68.37,77.92) 68.87,77.92 69.7,77.1 RC241.1
  IN1 w0.457: 55.89,78.89 57.3,80.3 67.84,80.3 68.43,79.71 68.43,77.98 v2(68.37,77.92) ; v2(23.85,71.13) 22.18,69.45 17.49,69.45 15.29,67.25 15.29,64.13 15.65,63.77 16.69,63.77 17.34,64.42 18.38,64.42 18.92,63.88 20.23,63.88 20.68,63.43 20.68,61.6 18.92,59.84 18.92,57.9 20.75,56.07 20.75,54.19 22.4,52.53 22.4,38.95 20.96,37.5 19.94,37.5 v2(19.36,38.08)
  IN1 w0.508: v2(151.6,42.13) 152.04,42.58 155.66,42.58 v2(156.08,43) ; 55.89,78.89 46.87,78.89 v2(45.85,79.91)
  IN2 w0.381: 149.56,51.98 149.56,48.37 154.93,43 v2(156.08,43)
  IN3 w0.457: v2(78.79,28.05) 77.47,28.05 76.56,28.97 76.56,30.85 72.07,35.34 66.17,35.34 64.69,36.81 54.36,36.81 52.76,35.21 52.76,31.78 51.23,30.26 46.81,30.26 45.82,29.27 45.82,26.48 44.27,24.93 37.69,24.93 35.54,27.09 35.54,32.43 34.76,33.21 34.76,36.93 33.1,38.59 32.37,38.59 31.61,39.35 29.87,39.35 29.55,39.68 28.34,39.68 26.16,37.5 19.94,37.5 v2(19.36,38.08)
  IN4 w0.457: v2(94.92,24.65) 93.96,24.65 92.99,25.61 92.56,25.61 91.75,26.42 85.4,26.42 84.2,27.62 84.2,27.8 83.69,28.31 82.32,28.31 81.27,27.26 79.25,27.26 78.79,27.72 v2(78.79,28.05) ; v2(23.85,71.13) 23.85,72.6 27.64,76.39 36.5,76.39 38.42,78.31 42.03,78.31 42.37,78.65 44.81,78.65 45.85,79.69 v2(45.85,79.91) ; v2(162.23,24.32) 162.03,24.32 160.99,25.35 160.99,31.31 161.39,31.71 161.39,33.04 160.95,33.49 160.18,33.49 159.39,34.28 159.39,36.79 158.78,37.4 157.77,37.4 154.55,40.62 154.55,41.31 153.33,42.53 151.99,42.53 v2(151.6,42.13)
  BOTTOM w0.254: v2(142.36,57.24) 142.36,57.33 UCPU1.AJ17 ; v2(142.35,59.73) 142.32,59.75 142.32,59.88 UCPU1.AD18
  BOTTOM w0.305: v2(142.35,59.73) 142.35,59.83 UCPU1.AD17
  BOTTOM w0.457: v2(162.23,24.32) 162.23,24.22 162.82,23.63 162.82,18.96 161.54,17.69 135.87,17.69 135.43,18.12 134.24,18.12 132.27,20.09 126.28,20.09 124.49,18.3 118.59,18.3 117.93,17.64 115.29,17.64 112.96,19.97 97.64,19.97 94.92,22.69 v2(94.92,24.65)
+3V_TBT: length 12.7
  TOP w0.127: v2(50.49,56.71) 49.97,57.24 RT21.1
  TOP w0.203: v2(40.22,58.89) UT1.H9
  TOP w0.254: RT33.1 RT34.1 46.84,52.36 v2(46.89,52.31)
  TOP w0.381: v2(32.39,58.51) 32.21,58.33 RT46.2 ; RT51.1 v2(34.19,48.19) ; RT26.1 v2(37.15,51.61)
  IN3 w0.089: v2(46.89,52.31) 47.31,51.89 47.54,51.89 47.74,51.69 48.43,51.69 48.65,51.91 48.65,52.54 48.86,52.74 49.43,52.74 50.07,53.38 50.07,56.28 v2(50.49,56.71)
  vias: v2(24.4,48.59) v2(24.98,48.6) v2(32.39,53.93) v2(32.51,54.82) v2(36.95,56.23) v2(44.75,48.73) v2(44.76,48.15) v2(45.73,50.21)
+3V_TBT_PWR:
  vias: v3(47.93,48.27)
+3V_TBT_S0: length 0.5
  TOP w0.203: UT1.R13 v2(44.13,60.84)
  vias: v2(24.24,52.1) v2(24.7,51.74)
+3V_VC: length 199.6
  TOP w0.203: U722.B1 25.66,64.62 25.81,64.77 v2(25.81,64.96) ; C1354.1 21.95,65.74 22.31,65.38 22.31,64.76 22.51,64.57 U722.H1
  TOP w0.305: PU203.8 61.81,18.46 61.39,18.88 60.35,18.88 v2(59.49,19.74)
  TOP w0.381: v2(22.49,66.7) 22.49,66.52 22.18,66.21 C1354.1 ; PQ223.5 56.6,33.88 57.12,34.41 57.12,35.64 PR275.1 PC218.1 57.13,38.31 PQ221.3 57.71,38.39 59.16,36.93 62.5,36.93 63.36,36.07 v2(63.36,35.98) 63.36,35.75 62.83,35.21 62.83,34.84 PQ222.3 61.93,33.95 PR281.2 PR278.1 ; PR260.1 56.01,18.6 55.47,18.6 v2(55.32,18.45)
  TOP w0.508: v2(54.92,22.26) 56.03,21.14 PR261.1 ; PR259.1 65.59,16.47 v2(65.74,16.33) ; v2(65.59,19.88) 65.59,20.58 65.3,20.86 PR256.1 64.87,23.07 64.29,23.66 PR255.1 PR257.1
  IN1 w0.508: v2(22.49,66.7) 22.98,66.21 25.45,66.21 25.76,65.91 ; v2(25.81,64.96) 25.76,65.01 25.76,65.91 ; 25.76,65.91 26.79,66.94 26.79,67.74 v2(27.18,68.13)
  IN3 w0.508: v2(65.59,19.88) 65.59,20.44 68.01,22.86 69.6,22.86 75.05,28.31 75.05,31.5 71.81,34.73 64.61,34.73 v2(63.36,35.98)
  IN4 w0.508: v2(59.49,19.74) 59.49,19.85 57.07,22.26 v2(54.92,22.26) ; v2(55.32,18.45) 55.32,17.87 54.03,16.57 51.58,16.57 50,14.99 42.69,14.99 42.11,14.41 39.86,14.41 39.21,15.07 39.21,16.19 38.89,16.51 38.04,16.51 35.71,18.83 35.71,24.22 36.3,24.8 36.3,31.76 35.73,32.33 35.73,33.16 36.03,33.46 36.03,34.62 35.51,35.14 35.51,39.46 36.17,40.12 36.17,40.39 36.17,40.4 36.17,40.9 36.17,40.9 36.17,41.27 36.78,41.88 38.83,41.88 39.68,42.74 41.12,42.74 41.43,42.43 42.55,42.43 46.71,46.59 46.71,47.95 50.28,51.52 51.22,51.52 54.65,54.96 54.65,59.43 55.28,60.06 55.28,67.55 v2(55.8,68.07)
  BOTTOM w0.508: v2(55.8,68.07) 55.22,68.65 52.85,68.65 52.75,68.56 51.3,68.56 50.85,69 50.85,72.36 50.14,73.07 47.23,73.07 44.15,69.98 44.15,69.51 43.71,69.07 43.31,69.07 42.41,68.18 41.75,68.18 41.48,67.9 27.41,67.9 v2(27.18,68.13)
+3VA_TBT: length 26.4
  TOP w0.254: UT1.F8 v2(39.57,58.24) ; QT19.2 30.66,58.73 30.66,58.01 30.38,57.73 R1462.1 30.38,57.27 31.31,56.34 31.87,56.34 31.95,56.43 32.82,56.43 33.12,56.73 RT113.1 RT46.1 33.12,58.25 33.57,58.69 34.71,58.69 34.95,58.45 CT57.1
  TOP w0.305: RT36.1 44.3,52.74 43.89,52.33 v2(43.89,52.36) 43.89,52.38 43.66,52.61 RT35.1 ; v2(46.3,51.98) 46.36,52.04 46.36,52.51 46.2,52.66 RT23.1 RT22.1 ; RT25.1 v2(39.6,52.33)
  TOP w0.356: RT47.1 45.19,51.99 v2(45.15,52.02)
  TOP w0.381: v2(35.5,58.17) 35.42,58.25 CT57.1
  BOTTOM w0.508: v2(39.57,58.24) 38.69,58.24 37.38,56.93 36.34,56.93 36.31,56.9 ; v2(39.6,52.33) 39.6,52.6 39.18,53.02 37.99,53.02 v3(36.85,54.16) 36.31,54.69 36.31,56.9 ; 36.31,56.9 36.25,56.97 36.25,57.82 35.87,58.2 35.52,58.2 v2(35.5,58.17)
+3VA_TBT_LC: length 45.8
  TOP w0.127: v2(48.34,72.26) 48.49,72.4 RT6.1 RT7.1 49.2,72.9 50.06,72.9 RT8.1 RT9.1 ; UT1.R6 44.13,57.59 v2(44.13,57.59) ; v2(47.22,51.27) 46.97,51.52 CT50.1
  IN4 w0.081: v2(48.34,72.26) 48.55,72.05 50.08,72.05 51.2,73.17 52.53,73.17 52.92,72.78 52.92,71.93 52.65,71.66 52.36,71.66 52.07,71.37 52.07,70.82 53.46,69.43 53.46,66.88 54.2,66.14 54.2,61.5 53.61,60.91 53.61,59.9 53.79,59.72 53.79,55.3 51.71,53.22 49.9,53.22 49.53,52.85 49.01,52.85 48.56,52.4 48.56,51.89 47.94,51.27 v2(47.22,51.27)
  BOTTOM w0.127: v2(44.13,57.59) 44.13,56.91 44.59,56.45 44.59,54.59 45.04,54.14 45.04,53.73 45.81,52.95 46.89,52.95 47.4,52.44 47.4,51.45 v2(47.22,51.27)
+3VALW: length 412.6
  TOP w0.127: C1162.1 183.06,33.56 v3(183.66,32.96)
  TOP w0.254: PU401.5 171.8,58.27 172.26,58.73 173.94,58.73 PU402.5 175.25,58.27 PC405.1 175.9,57.84 175.9,57.1 175.62,56.82 175.62,55.36 175.36,55.1 174.22,55.1 173.84,54.72 PR1423.1 ; PR404.1 170.03,60.42 170.62,61.01 170.62,62.46 170.36,62.72 PJP15.1 ; PU600.13 171.08,29.9 171.67,29.3 172.11,29.3 PC606.1 ; PR403.1 169.09,60.23 167.92,59.06 v2(167.59,59.06) ; v2(164.31,62.19) 164.31,63.38 163.85,63.85 PU400.8 163.85,64.94 v2(163.97,65.07)
  TOP w0.305: v2(86.86,71.75) 86.6,72.01 PU201.8 85.18,72.01 PR254.1 ; UC9.5 166.28,69.91 167.3,68.88 169.5,68.88 v3(169.85,68.54) 170.64,67.75 170.64,66.76 170.41,66.53 ; PR252.1 85.7,68.89 86.11,69.3 87.93,69.3 v2(88.13,69.11) ; PR403.1 PR404.1
  TOP w0.381: PR224.1 92.87,73.62 v2(93.02,73.77) ; UC8.5 v2(204.05,55.33) ; v2(173.07,57.85) 173.49,58.27 PU402.5 ; QH8.5 7.48,8.4 v2(8.01,7.87) 8.31,7.87 8.84,8.4 QH8.2 ; UC13.5 199.51,55.27 199.67,55.11 200.7,55.11 200.7,55.11 v2(200.7,55.11) ; v2(6.44,10.42) 6.83,10.82 7.15,10.82 QH9.5 ; QH9.2 8.36,10.82 v2(8.34,10.83) ; RT113.2 31.78,56.98 v2(31.62,56.83) ; v2(66.98,19.92) 66.98,19.85 PR100.1 ; C375.1 45.95,21.19 v2(45.92,21.22) ; v3(53.42,40.32) v2(52.68,39.58) ; v2(28.59,52.79) C1289.1 26.24,52.79 U699.5
  TOP w0.457: v2(84.91,34.51) 84.91,34.02 PR1523.1
  TOP w0.508: v2(86.03,75.54) 87.39,75.54 PR226.1 ; C1322.1 v2(195.94,14.08) ; Q41.2 v2(8.33,5.3) ; v2(156.07,43.67) 155.93,43.8 CC271.1 157.2,44.41 RC214.1 ; PR1415.1 v2(204.57,72.98) ; v2(197.84,78.57) 197.79,78.52 PR1424.1 ; PR708.1 v2(204.67,63.2) ; PR1405.1 178.54,47.52 v2(177.57,46.55) 176.82,45.81 PR1404.1 ; v2(171.86,28.66) 172.24,28.66 PC606.1 ; v2(51.69,47.51) 51.66,47.48 51.66,45.3 52.8,44.17 UC11.5 ; PR1522.1 v2(89.51,43.44) ; PR253.1 92.25,69.5 v2(92.41,69.66) ; v2(204.06,68.79) PR1414.1 ; v2(54.46,39.55) 55.32,39.55 PQ221.1 ; v2(187.48,72.53) 187.88,72.53 RE84.1 ; PR1503.1 v2(86.84,34.25)
  IN1 w0.381: v2(40.74,17.24) 38.8,17.24 38.61,17.05 38.14,17.05 35.47,19.72 27.39,19.72 v2(27.06,20.05)
  IN1 w0.508: v2(164.31,62.19) 165.38,63.25 167.04,63.25 169.9,66.12 v2(169.9,66.58) ; v2(204.57,72.98) 203.66,72.07 203.66,69.2 v2(204.06,68.79) 204.67,68.18 v2(204.67,63.2) ; v2(8.33,5.3) 8.33,7.55 v2(8.01,7.87) 6.44,9.44 v2(6.44,10.42) 6.85,10.83 v2(8.34,10.83) 8.34,11.22 7.85,11.72 5.77,11.72 4.01,13.47 4.01,19.24 5.04,20.27 6.1,20.27 6.81,20.98 11.01,20.98 13.77,18.22 13.77,15.77 14.25,15.29 16.33,15.29 19.24,18.2 22.61,18.2 23.53,19.12 26.14,19.12 v2(27.06,20.05)
  IN2 w0.508: 34.9,45.05 34.9,45.4 31.62,48.68 v2(31.62,56.83) 31.62,61.32 30.58,62.36 30.58,63.12 30.13,63.57 30.13,67.34 28.17,69.3 26.6,69.3 ; v2(187.43,34.33) 186.72,34.33 185.78,35.27 185.78,42.34 185.02,43.1 183.79,43.1 183.07,43.82 v2(183.07,47.52) ; v2(204.57,72.98) 203.33,74.23 203.33,76.49 201.83,77.99 198.43,77.99 v2(197.84,78.57)
  IN3 w0.381: v2(59.03,29.22) 55.88,26.07 48.79,26.07 47.6,24.88 47.6,24.3 47.22,23.92 47.22,21.16 46.73,20.67 46.28,20.67 45.92,21.03 v2(45.92,21.22)
  IN3 w0.457: v2(61.06,74.76) 61.06,74.05 62.18,72.93 64.4,72.93 65.12,73.65 78.4,73.65 78.49,73.57 78.51,73.57 80,72.07 86.53,72.07 v2(86.86,71.75)
  IN3 w0.508: v2(86.86,71.75) 87.76,72.65 89.93,72.65 90.31,72.27 91.52,72.27 v2(93.02,73.77) ; v2(173.07,57.85) 173.01,57.9 171.67,57.9 170.51,59.06 v2(167.59,59.06) ; v2(92.41,69.66) 91.24,68.49 88.47,68.49 88.13,68.83 v2(88.13,69.11)
  IN4 w0.508: v2(61.06,74.76) 61.06,75.93 61.1,75.97 61.1,77.39 61.1,77.39 61.1,79.6 v2(61.09,79.61) ; v2(204.06,68.79) 202.16,68.79 200.42,67.06 v2(200.42,67.06) ; v2(187.48,72.53) 187.87,72.92 187.87,77.13 v2(189.17,78.43) 190.61,79.87 196.55,79.87 v2(197.84,78.57) ; 199.83,48.75 199.33,48.75 193.89,54.19 193.89,57.78 193.3,58.37 v2(193.08,58.37) ; 199.83,48.75 203.18,45.4 v2(203.18,40.6) ; 199.83,48.75 199.83,54.24 v2(200.7,55.11) 203.83,55.11 v2(204.05,55.33) 204.85,56.13 204.85,59.19 203.11,60.93 203.11,61.64 v2(204.67,63.2)
  IN4 w1.016: 26.75,70.57 28.84,72.66 30.64,72.66 31.12,73.14 32.09,73.14 32.75,72.48 34.82,72.48 38.66,76.31
  BOTTOM w0.254: v2(201.54,32.99) 201.44,32.89 200.76,32.89 JAPS1.7 ; v2(201.54,34.89) JAPS1.3
  BOTTOM w0.305: v2(195.94,14.08) 195.81,14.2 195.81,15.54 JIO1.49 ; 45.77,19.31 45.77,19.77 45.92,19.92 JKB1.3 45.92,21.21 v2(45.92,21.22)
  BOTTOM w0.381: v2(173.07,57.85) 173.07,57.85 173.08,57.85 173.08,58.3 PC402.1 ; 45.77,19.31 45.77,18.13 44.24,16.6 41.38,16.6 v2(40.74,17.24) ; v2(189.17,78.43) 189.57,78.03 U729.5 ; UC10.5 193.2,58.49 v2(193.08,58.37)
  BOTTOM w0.508: v2(163.97,65.07) 163.97,64.46 PC401.1 PC400.1 ; v2(156.07,43.67) 157.69,43.67 158.06,43.29 159.79,43.29 160.74,42.34 161.78,42.34 162.19,42.75 166.85,42.75 167.34,43.24 169.9,43.24 170.26,42.88 170.92,42.88 171.77,42.03 v2(173.09,42.03) ; v2(93.02,73.77) 92.3,73.05 92.3,69.77 v2(92.41,69.66) ; v2(31.62,56.83) 29.31,54.52 29.31,53.51 v2(28.59,52.79) ; v2(86.84,34.25) PR1503.1 ; v2(164.31,62.19) 164.11,61.98 163.64,61.98 163.3,61.64 163.3,61.29 PR411.1 ; PR410.1 v2(167.59,59.06) ; PR705.1 204.39,62.32 204.67,62.59 v2(204.67,63.2) ; v2(86.03,75.54) 86.03,72.57 v2(86.86,71.75)
  vias: v2(25.5,69.54) v2(25.5,68.92) v2(34.19,43.6) v2(34.82,44.28) v2(35.13,40.1) v2(35.33,40.75) v2(40.51,41.52) v2(40.5,40.92) v2(40.46,40.31) v2(41.63,76.54) v2(42.27,76.54) v2(51.68,48.09) v2(57.25,77.05) v2(58.1,77.08) v2(58.9,77.05) v2(60.42,79.64) v2(73,16.98) v2(73.03,16.38) v2(73.64,16.98) v2(73.66,16.38) v2(74.27,16.98) v2(74.3,16.38) v2(75.29,16.39) v2(75.92,16.39) v2(76.56,16.39) v2(77.19,16.39) v2(78.21,17) v2(78.21,16.39) v2(78.84,17) v2(78.84,16.39) v2(79.53,16.98) v2(79.55,16.39) v2(168.55,15.76) v2(173.03,15.76) v2(173.61,15.76) v2(173.99,34.32) v2(174.03,15.32) v2(174.42,33.93) v2(176.84,34.18) v2(176.86,33.48) v2(177.47,34.21) v2(178.09,34.21) v2(181.41,34.1) v2(182.02,34.15) v2(199.97,39.48) v2(200.38,39.91) v3(198.49,40.96)
+3VALW_5085: length 145
  TOP w0.203: UE5.A52 180.36,57.82 180.36,57.46 179.85,56.95 179.45,56.95 179.15,56.65 179.15,56.12 179.48,55.79 CE41.1
  TOP w0.254: UE5.B3 187.21,60.27 186.53,60.27 v2(186.51,60.28) ; UE5.A26 181.86,68.72 181.86,69.56 v2(181.2,70.21) ; CE64.1 183.24,55.86 183.54,56.16 183.54,57.37 183.36,57.54 183.36,57.82 UE5.A58 ; v2(178.18,71.87) 177.85,71.54 177.65,71.54 RE69.1 ; CE38.1 190.05,64.52 188.06,64.52 UE5.A11 ; v2(169.12,64.13) 169.44,63.8 PJP15.2 169.44,62.09 CE46.1 ; CE63.1 184.32,70.63 184.32,70.07 183.86,69.61 183.86,68.72 UE5.A22 ; UE5.A41 176.93,63.02 176.81,62.9 176.28,62.9 175.95,63.23 175.95,63.28 175.18,64.04 v2(175.18,64.17)
  TOP w0.305: v2(192.19,63.63) 192.09,63.53 190.91,63.53 190.48,63.97 CE38.1 ; RE69.1 176.89,70.95 176.53,70.6 176.53,69.28 178.01,67.8 UE5.B35 ; RE55.2 173.15,59.29 172.06,59.29 v2(172.01,59.24)
  TOP w0.381: CE41.1 179.68,56.46 v2(179.65,56.49) ; v2(183.06,56.51) 183.03,56.47 182.83,56.47 182.35,55.99 CE17.1 CE64.1
  TOP w0.508: CE14.1 CE63.1 184,70.54 v2(183.74,70.29) ; v2(181.2,70.21) CE40.1 ; RE25.1 184.13,75.29 v2(184.18,75.35) 184.45,75.35 v3(184.93,75.82) 186.35,77.25 189.82,77.25 190.94,78.37 192.38,78.37 v2(192.73,78.72) ; RE3.1 173.18,62.09 CE44.1 173,62.95 172.4,63.55 v2(171.59,63.55)
  IN1 w0.381: v2(186.51,60.28) 186.72,60.28 187.1,59.9 187.1,59.17 186.64,58.71 185.32,58.71 183.19,56.57 183.13,56.57 v2(183.06,56.51)
  IN2 w0.381: v2(176.21,60.91) 176.43,60.91 176.84,61.31 176.84,61.96 176.41,62.38 174.81,62.38 173.79,63.41
  IN2 w0.508: v2(179.65,56.49) 179.64,56.5 179.64,56.86 180.42,57.64 181.13,57.64 181.61,57.16 181.61,56.85 182.17,56.3 182.83,56.3 183.04,56.51 v2(183.06,56.51)
  IN3 w0.381: v2(186.51,60.28) 190.41,60.28 191.34,61.22 v2(192.24,61.22)
  IN3 w0.508: v2(172.01,59.24) 172.34,59.24 173.18,60.09 173.18,62.78 174.57,64.17 v2(175.18,64.17)
  IN4 w0.508: v2(192.24,61.22) 192.24,61.27 192.84,61.87 192.84,62.62 ; 192.84,62.62 192.84,62.92 192.19,63.57 v2(192.19,63.63) ; 192.84,62.62 192.98,62.62 193.7,63.34 193.7,65.38 194.32,65.99 194.32,66.48 195.04,67.21 195.04,69.3 194.36,69.98 194.36,77.09 v2(192.73,78.72) ; v2(178.18,71.87) 178.36,71.87 181.84,75.35 v2(184.18,75.35)
  BOTTOM w0.254: RE53.1 183.08,57.97 183.08,61.19 182.8,61.48 178.59,61.48 178.05,62.02 177.6,62.02 RE87.2 ; RE52.1 179.65,57.03 v2(179.65,56.49)
  BOTTOM w0.381: v2(176.21,60.91) 176.68,60.44 RE88.2 ; RE102.1 189.04,68.81 189.34,68.51 189.34,68.49 189.66,68.17 189.68,68.17 189.73,68.12 191.08,68.12 191.59,67.6 191.59,64.39 192.19,63.8 v2(192.19,63.63) 191.63,63.63 191.62,63.63 RE79.2 ; RE75.1 175.18,64.86 RE74.1 175.29,64.27 v2(175.18,64.17) ; RE53.1 183.52,57.53 183.52,56.91 183.18,56.57 183.13,56.57 v2(183.06,56.51) ; v2(172.01,59.24) 172.47,59.24 172.72,59.5 172.72,60.18 RE65.1 ; RE88.2 RE87.2 ; RE88.2 RE56.2 ; RE76.1 168.89,64.36 v2(169.12,64.13) ; RE93.2 193.14,78.31 v2(192.73,78.72)
  BOTTOM w0.508: RE81.1 189.39,58.46 189.39,60.1 189.13,60.36 187.63,60.36 ; 187.63,60.36 CE43.1 186.59,60.36 v2(186.51,60.28) ; 187.63,60.36 188.09,60.82 RE73.2 RE86.2 ; RE72.1 RE75.1
+3VALW_23017: length 24.2
  TOP w0.203: RE13.1 35.23,13.65 36.34,13.65 RE14.1
  TOP w0.254: 34.37,19.19 34.37,16.96 34.93,16.41 36.36,16.41 36.68,16.09 36.68,14.88 RE14.1 ; 34.37,19.19 33.73,19.19 33.38,19.54 RE27.1 v3(32.03,19.9) 31.85,19.9 v2(31.37,20.38) ; 34.37,19.19 35.84,19.19 36.3,19.64 RE24.1
  BOTTOM w0.203: 28.98,18.86 29.41,18.42 29.41,17.93 29.19,17.7 CE3.1 ; 28.98,18.86 29.26,18.86 30.79,20.38 v2(31.37,20.38) ; 28.98,18.86 PJP14.2
  BOTTOM w0.381: CE10.1 CE3.1 29.58,17.36 30.4,18.18 30.96,18.18 UE4.5
+3VALWP: length 12.7
  IN1 w0.203: v2(88.34,19.29) 88.09,19.03 80.12,19.03 v2(79.57,19.59)
  BOTTOM w0.203: PU500.14 89.32,19.21 89.32,18.01 PR504.2 PR502.1 88.37,19.26 v2(88.34,19.29)
  vias: v2(79.59,22.71) v2(79.59,22.11) v2(79.58,21.53) v2(79.57,20.84) v2(79.57,20.2) v3(81,21.51)
+3VLP: length 223.5
  TOP w0.254: v2(184.91,54.24) 185.01,54.34 RE57.2
  TOP w0.508: v2(17.48,12.36) 17.46,12.36 v3(16.98,11.88) 16.29,11.18 D122.2
  IN1 w0.254: v2(159.99,15.02) 160.69,14.31 161.48,14.31 162.91,15.74 165.65,15.74 165.96,15.44 166.33,15.44 166.95,14.82 174.21,14.82 179.88,20.49 179.88,25.34 175.94,29.28 175.94,34.9 175.68,35.16 175.68,42.07 175.74,42.13 175.74,42.86 175.56,43.04 175.56,43.93 176.79,45.17 177.58,45.17 178.21,45.8 178.21,47.42 179.16,48.37 180.78,48.37 181.48,49.07 181.48,50.43 181.92,50.86 181.92,52.31 182.7,53.09 182.7,54.23 183.21,54.75 184.4,54.75 v2(184.91,54.24) ; v2(17.48,12.36) 17.46,12.36 17.46,12.44 19.18,14.16 26.95,14.16 27,14.21 29.85,14.21 30.14,13.91 31.12,13.91 31.42,14.21 37.98,14.21 38.53,13.65 39.16,13.65 39.65,14.14 39.65,14.82 39.64,14.82 39.64,15.22 39.65,15.22 39.65,15.33 39.84,15.52 41.66,15.52 42.7,14.48 49.22,14.48 49.78,14.48 50.86,15.56 54.17,15.56 54.5,15.24 58.47,15.24 59.3,16.07 64.51,16.07 64.85,15.73 70.09,15.73 71.88,17.53 85.42,17.53 v2(86.53,16.42) 87.13,17.02 89.5,17.02 v2(90.12,16.39)
  BOTTOM w0.254: v2(159.99,15.02) 159.3,15.71 135.79,15.71 134.24,17.26 133.64,17.26 131.71,19.18 126.62,19.18 124.72,17.28 118.87,17.28 118.36,16.77 114.88,16.77 112.55,19.1 106.54,19.1 105.88,18.44 103.28,18.44 102.68,19.04 96.28,19.04 95.38,18.14 93.2,18.14 91.45,16.39 v2(90.12,16.39)
+3VS: length 619.4
  TOP w0.254: v2(159.16,61.68) 160.17,61.68 160.33,61.53 160.99,61.53 UC7.5
  TOP w0.305: v2(159.16,61.68) 158.8,62.04 RN20.1 158.8,63.27 QC2.2
  TOP w0.356: v2(157.43,54.62) 157.43,56.39 158.36,57.32 158.36,58.1 158.05,58.4 157.1,58.4 156.59,58.91 RC280.2
  TOP w0.381: C1204.1 60.3,76.16 v2(60.36,76.22) ; v2(158.12,60.03) 157.73,60.03 157.23,60.54 157.23,60.79 RC280.2 ; v2(62.12,77.3) R1179.2 ; 51.54,23.65 48.78,26.41 v3(47.65,26.41) 46.36,26.41 45.95,26.82 45.95,27.8 45.52,28.23 44.68,28.23 44.35,27.9 v2(44.35,27.62) ; 51.54,23.65 51.78,23.9 52.72,23.9 54.31,22.31 54.31,21.93 54.66,21.58 R1141.2 ; 51.54,23.65 50.58,23.65 49.89,22.96 v2(49.58,22.96) ; RC177.2 RC176.2 156.67,66.71 157.61,66.71 157.94,66.38 RN19.1 158.87,66.16 158.87,65.23 QC2.5 158.87,65.23 158.87,65.02 159.56,64.32 v2(159.92,64.32) ; v2(45.34,21.22) 45.24,21.12 45.24,20.66 C377.1 ; PR905.2 164.49,39.98 164.39,39.89 v2(164.39,39.81) ; 156.84,48.74 v2(157.33,48.74) ; v2(176.84,34.96) 176.84,35.06 176.63,35.26 PR600.2 PR601.2 ; RC291.1 152.63,72.71 v2(152.65,72.73) ; RC225.1 159.7,71.5 159.7,70.48 159.22,70 159.22,69.86 158.65,69.29 156.85,69.29 156.28,68.71 154.77,68.71 154.3,69.18 154.3,70.33 v2(154.34,70.36) 154.34,70.39 UC12.5
  TOP w0.457: v2(36.73,34.46) 37.06,34.79 R81.1
  TOP w0.508: v2(204.04,21.04) 203.53,20.53 202.67,20.53 202.29,20.15 RC190.1 ; RC49.1 RC237.1 149.53,49.87 RC50.1 150.14,49.92 150.88,49.18 153.9,49.18 154.56,49.84 155.73,49.84 156.84,48.74 ; v2(185.24,74.28) 185.65,73.87 RE83.1 ; v2(176.58,38.26) 176.2,37.88 RC59.1 ; v2(169.83,72.3) 169.77,72.24 169.77,71.71 ; R884.2 163.7,14.64 v2(163.5,14.44) ; v2(150.32,77.78) 150.12,77.78 149.33,76.98 RC178.2 RC175.2 ; 41,44.54 40.87,44.41 40.87,42.17 v2(40.81,42.11) ; 171.43,14.06 170.99,14.06 170.81,14.24 v2(170.81,14.31) ; C1324.1 195.3,20.48 v2(195.43,20.35) ; RC225.1 159.11,72.73 v2(159.03,72.81) ; v2(62.99,51.75) 63.14,51.9 PR1095.1 ; v2(167.14,15.33) 167.14,15.75 166.68,16.21 R1103.2 ; QZ9.3 59.2,74.41 59.84,75.05 C1204.1
  IN1 w0.381: v2(51.26,48.9) 51.26,49.54 53.37,51.65 53.37,51.9 53.8,52.33 54.89,52.33 56.87,50.35 61.6,50.35 v2(62.99,51.75) ; v2(159.03,72.81) 159.03,72.32 161.65,69.7 161.65,66.05 v2(159.92,64.32) ; v2(191.54,72.6) 190.42,73.72 185.8,73.72 v2(185.24,74.28) 184.69,73.72 180.7,73.72 180.51,73.53 175.62,73.53 174.01,71.92 170.22,71.92 v2(169.83,72.3) ; v2(150.32,77.78) 150.32,77.64 150.04,77.35 150.04,76.23 152.55,73.72 152.55,72.82 v2(152.65,72.73) ; v2(192.54,44.35) 192.54,45.48 196.19,49.13 v2(196.19,50.43) ; v2(151.61,44.23) 150.78,44.23 149.07,45.93 v2(149.07,46.08)
  IN1 w0.457: v2(36.73,34.46) 36.73,34.96 36.14,35.54 36.14,38.11 36.79,38.76 38.86,38.76 39.51,39.4 39.51,41.51 40.16,42.16 40.77,42.16 v2(40.81,42.11)
  IN1 w0.508: v2(176.58,38.26) 176.94,38.26 178,39.33 178,39.46 v2(178.6,40.06) 178.82,39.85 178.82,39.4 179.17,39.05 179.17,36.03 178.36,35.21 177.04,35.21 176.84,35.01 v2(176.84,34.96) ; v2(66.93,79.38) 65.61,78.06 62.88,78.06 v2(62.12,77.3)
  IN2 w0.381: v2(124.56,73.39) 124.54,73.41 124.28,73.41 123.95,73.08 123.95,72.5 124.33,72.13 125.02,72.13 125.25,72.36 126.97,72.36 127.59,72.98 127.59,73.65 128.14,74.2 128.34,74.2 128.63,74.5 130.06,74.5 130.5,74.06 134.42,74.06 134.77,74.42 134.77,77.26 135.15,77.63 138.43,77.63 139.11,76.95 144.58,76.95 144.71,76.81 149.5,76.81 150.32,77.64 v2(150.32,77.78) ; v2(169.83,72.3) 169.83,72.21 170.33,71.71 177.01,71.71 178.31,70.42 v2(179.68,70.42) ; v2(157.43,54.62) 157.08,54.62 154.29,51.83 154.29,51.3 156.86,48.74 v2(157.33,48.74) ; v2(124.23,76.92) 124.23,77.63 121.34,80.53 91.57,80.53 91.06,80.02 88.24,80.02 85.93,77.71 84.27,77.71 83.89,77.34 80.72,77.34 77.38,80.67 70.84,80.67 70.34,80.17 67.41,80.17 66.93,79.69 v2(66.93,79.38)
  IN2 w0.508: v2(170.81,14.31) 170.7,14.21 168.96,14.21 167.84,15.33 v2(167.14,15.33) 165.8,15.33 165.26,15.86 164.09,15.86 163.5,15.27 v2(163.5,14.44) ; v2(195.43,20.35) 193.19,22.59 193.19,23.98 188.92,28.24 188.92,33.19 188.44,33.66 186.42,33.66 185.1,34.98 185.1,39.84 v2(184.86,40.09) 183.22,38.44 179.22,38.44 178.6,39.06 v2(178.6,40.06) ; v2(44.35,27.62) 43.87,28.1 43.87,30.29 43.11,31.04 42.04,31.04 41.1,31.99 41.1,33.12 42.21,34.23 43.85,34.23 44.73,35.1 v2(44.73,35.49) 44.73,35.6 44.32,36.01 43.99,36.01 43.06,36.94 43.06,40.31 41.63,41.74 41.19,41.74 v2(40.81,42.11)
  IN3 w0.381: v2(152.65,72.73) 152.65,72.61 154.34,70.92 v2(154.34,70.36) ; v2(158.12,60.03) 159.16,61.07 v2(159.16,61.68) 158.88,61.96 158.88,63.28 v2(159.92,64.32) ; v2(169.83,72.3) 169.83,72.33 169.22,71.71 167.72,71.71 167.28,72.14 166.35,72.14 165.38,71.17 160.92,71.17 159.28,72.81 v2(159.03,72.81) ; v2(51.26,48.9) 48.51,46.16 48.51,43.16 46.46,41.11 41.82,41.11 v2(40.81,42.11)
  IN3 w0.508: v2(178.6,40.06) 177.64,40.06 176.72,40.98 174.18,40.98 173.46,40.26 171.14,40.26 170.97,40.42 167.02,40.42 166.92,40.32 164.7,40.32 164.39,40.01 v2(164.39,39.81) ; v2(151.61,44.23) 152.69,44.23 153.11,44.65 153.11,45.51 153.41,45.81 154.4,45.81 v2(157.33,48.74) ; v2(149.07,46.08) 149.07,45.23 147.42,43.58 v2(147.42,43.49) ; v2(85.42,38.69) 86.06,38.69 87.55,40.19 87.55,41.64 88.72,42.81 90.07,42.81 90.68,43.42 95.73,43.42 v2(95.91,43.24) ; v2(190.19,15.87) 190.19,16.69 192.3,18.8 192.3,20.01 192.65,20.35 v2(195.43,20.35) 197.05,21.98 199.47,21.98 200.94,20.51 203.51,20.51 v2(204.04,21.04)
  IN4 w0.356: v2(49.58,22.96) 47.31,20.68 45.56,20.68 45.34,20.9 v2(45.34,21.22)
  IN4 w0.381: v2(66.04,70.98) 66.04,67.54 64.01,65.51 64.01,63.69 63.27,62.95 63.27,62.32 61.26,60.31 61.26,56.34 60.21,55.29 60.21,51.48 60.63,51.06 62.31,51.06 v2(62.99,51.75) ; v2(124.23,76.92) 123.95,76.64 123.95,74 v2(124.56,73.39) ; v2(196.19,50.43) 192.05,54.57 192.05,58.09 191.05,59.09 191.05,66.18 191.38,66.51 191.38,71.84 191.35,71.87 191.35,72.32 191.38,72.35 191.38,72.44 v2(191.54,72.6)
  IN4 w0.508: v2(85.42,38.69) 84.81,38.08 78.18,38.08 76.81,36.71 74.17,36.71 73.21,35.75 70.95,35.75 69.23,37.47 68.94,37.47 67.39,39.02 63.76,39.02 63.2,39.59 63.2,41.33 61.65,42.88 61.65,45.35 62.74,46.44 62.74,47.48 64.18,48.93 64.18,50.81 63.25,51.75 v2(62.99,51.75)
  BOTTOM w0.203: JKB1.4 45.42,20.86 45.34,20.94 v2(45.34,21.22)
  BOTTOM w0.254: JLPDE1.1 179.63,71.19 179.63,70.47 v2(179.68,70.42) 179.83,70.42 180.15,70.74 JLPDE1.2 ; v2(192.54,44.35) 192.75,44.13 JEDP.40
  BOTTOM w0.305: RC245.1 149.2,45.96 v2(149.07,46.08) ; U683.5 188.82,39.33 189.21,38.95 189.21,38.31 CS44.1 ; RC292.1 156.82,60.18 157.96,60.18 v2(158.12,60.03) ; v2(195.43,20.35) 195.51,20.27 195.51,18.41 JIO1.50
  BOTTOM w0.381: v2(150.32,77.78) 151.12,77.78 151.49,77.41 RC277.1 ; RH563.1 48.69,19.49 48.31,19.87 48.31,21.63 48.84,22.16 RH562.1 49.58,22.8 v2(49.58,22.96) ; v2(157.33,48.74) 157.02,49.05 RC246.1 156.73,49.04 RC272.1 ; RH440.2 RH441.2 ; v2(184.86,40.09) 185.37,40.6 R220.1 ; v2(60.36,76.22) 61.04,76.22 v2(62.12,77.3) ; v2(66.93,79.38) 65.74,79.38 63.96,77.6 63.96,77.1 64.99,76.07 64.99,74.54 66.04,73.48 v2(66.04,70.98)
  BOTTOM w0.457: v2(44.73,35.49) 45.19,35.95 RC47.1
  BOTTOM w0.483: v2(23.86,47.6) 23.86,46.92 24.32,46.47 RT241.1
  BOTTOM w0.508: RC63.1 62.64,51.75 v2(62.99,51.75) ; RC27.1 151.18,44.69 151.59,44.28 151.61,44.28 v2(151.61,44.23) ; RH441.2 159.56,63.97 v2(159.92,64.32) ; v2(66.04,70.98) 66.04,70.34 RC137.1 ; RC16.1 RC21.1 148.06,44.13 v2(147.42,43.49) ; v2(190.19,15.87) 190.19,14.5 189.51,13.83 180.11,13.83 179.34,14.6 173.62,14.6 173.23,14.21 170.91,14.21 v2(170.81,14.31) ; v2(189.81,38.79) 189.81,38.44 189.56,38.19 CS44.1 ; RE60.1 100.48,44.08 99.64,43.24 v2(95.91,43.24) ; RC228.1 R220.1
  vias: v2(38.75,47.54) v2(39.34,47.55)
+3VS_AUDIO: length 269.4
  TOP w0.381: RC9.1 157.71,49.16 158.15,48.72 v2(158.35,48.72)
  TOP w0.508: LA14.1 37.18,24.41 v2(36.55,23.78) ; RA37.1 14.9,35.45 v2(14.92,35.48) ; RA18.1 19.15,19.21 v2(18.87,18.93)
  IN1 w0.508: v2(14.92,35.48) 14.92,34.95 15.37,34.51 15.37,32.57 16.56,31.38 v2(17.14,31.38) ; v2(32.61,37.04) 33.73,37.04 34.73,36.04 34.73,33.07 35.56,32.24 35.56,26.42 35.03,25.89 35.03,24.9 36.14,23.78 v2(36.55,23.78)
  IN2 w0.381: v2(162.66,28.03) 163.53,27.16 163.53,21.54 161.8,19.81 158.44,19.81 156.49,17.87 132.31,17.87 131.34,18.84 126.81,18.84 125.3,17.33 118.61,17.33 116.94,19 108.26,19 106.89,19 105.76,17.87 103.86,17.87 99.16,22.57 99.16,23.72 98.86,24.02 98.86,24.04 v2(98.68,24.22) ; v2(57.56,19.54) 58.03,19.07 59.91,19.07 60.12,19.28 62,19.28 63.88,21.17 64.46,21.17 65.51,22.21 v2(65.51,22.84) ; v2(158.35,48.72) 158.64,48.72 159.93,47.43 161.65,47.43 162.8,46.28 162.8,43.47 161.32,41.99 161.32,37.73 161.07,37.49 v2(161.07,37.04)
  IN3 w0.508: v2(19.03,33.61) 22.07,36.66 30.49,36.66 30.59,36.76 32.33,36.76 v2(32.61,37.04) ; v2(41.48,23.61) 41.48,22.44 41.28,22.23 41.28,20.96 40.08,19.77 39,19.77 ; v2(98.68,24.22) 97.48,25.42 97.48,34.23 96.37,35.34 95.62,35.34 93.15,37.8 v2(87,37.8) ; v2(36.55,23.78) 36.55,22.85 37.39,22.01 37.9,22.01 39,20.91 39,19.77 ; 39,19.77 30.84,19.77 30.46,20.15 30.46,21.17 28.93,22.69 27.03,22.69 25.25,20.91 25.25,20.66 24.43,19.84 19.78,19.84 v2(18.87,18.93)
  IN4 w0.381: v2(162.66,28.03) 164.3,29.66 164.3,33.65 163.24,34.71 162.54,34.71 161.07,36.17 v2(161.07,37.04) ; v2(57.56,19.54) 57.56,19.62 56.34,20.83 54.46,20.83 54.25,20.62 53.1,20.62 53.06,20.66 50.7,20.66 48.5,18.46 46.73,18.46 45.66,19.53 43.91,19.53 42.44,21 42.44,21.78 41.48,22.74 v2(41.48,23.61)
  IN4 w0.508: v2(65.51,22.84) 65.51,23.5 71.9,29.89 74.05,29.89 79.54,35.38 83.5,35.38 85.93,37.8 v2(87,37.8) ; v2(19.03,33.61) 18.09,32.67 18.09,32 17.47,31.38 v2(17.14,31.38)
  BOTTOM w0.381: RA80.2 34.2,36.52 33.78,36.94 32.72,36.94 v2(32.61,37.04)
  BOTTOM w0.508: RA19.1 19.36,33.94 v2(19.03,33.61) ; RA38.1 16.68,30.92 v2(17.14,31.38)
  vias: v3(33.2,36.69)
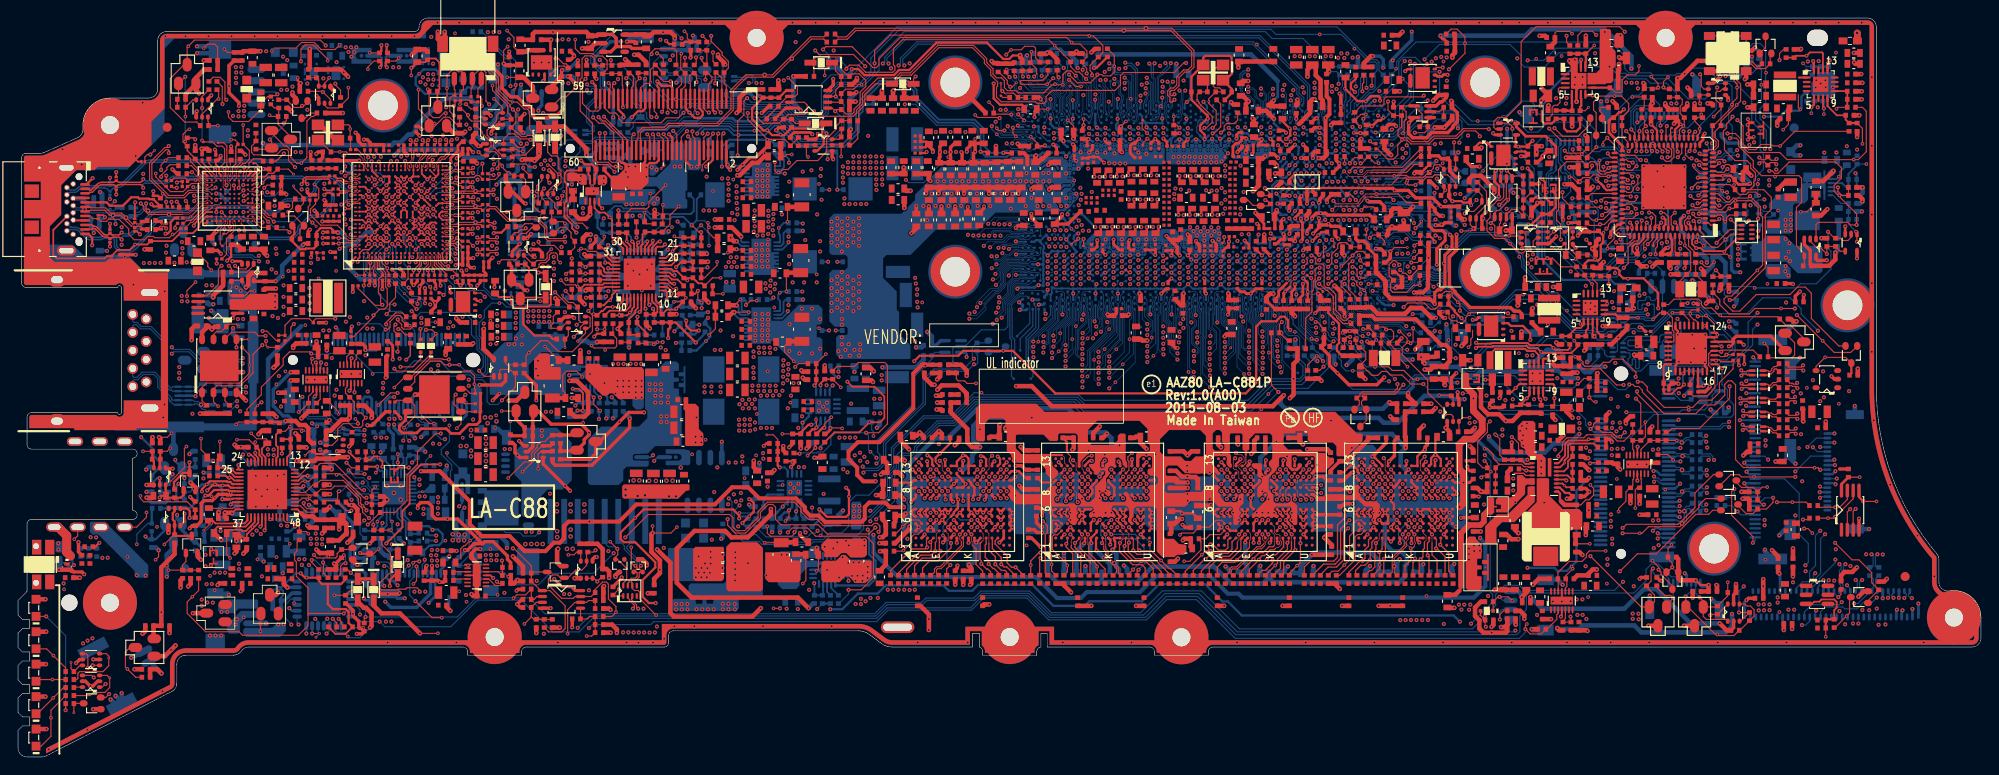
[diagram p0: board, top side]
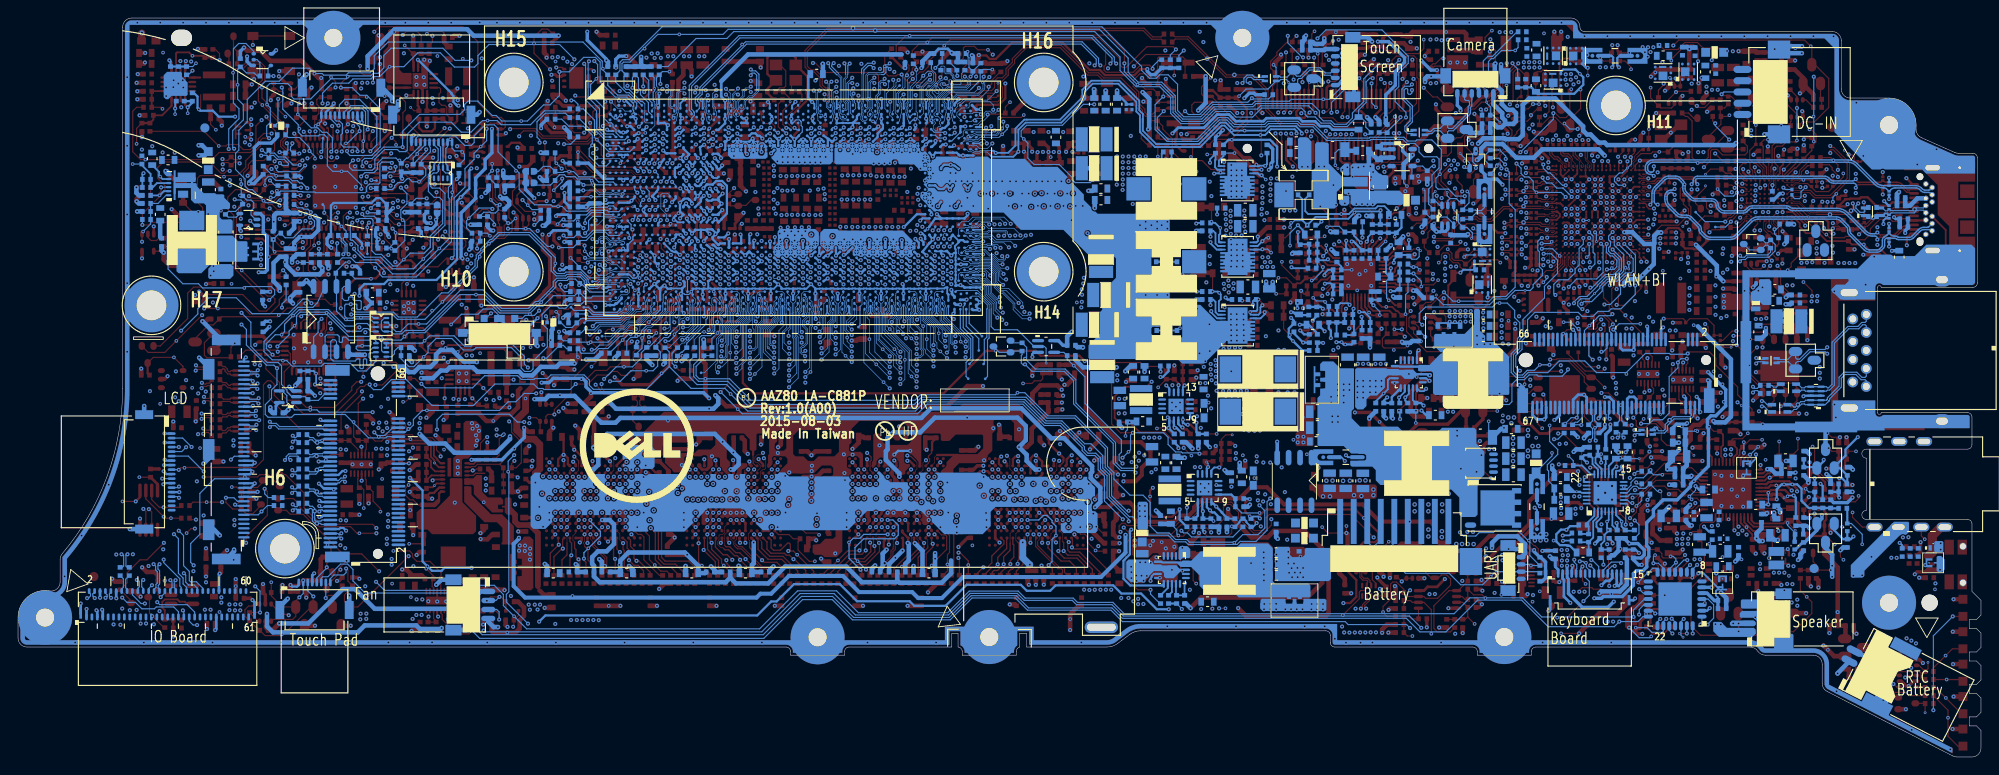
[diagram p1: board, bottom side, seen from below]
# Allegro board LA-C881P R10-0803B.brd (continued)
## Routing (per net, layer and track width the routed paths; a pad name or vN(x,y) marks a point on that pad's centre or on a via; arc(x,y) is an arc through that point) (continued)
+3VS_CAM: length 19.8
  TOP w0.127: v3(54.32,78.83) 53.89,78.4 v2(53.89,76.95)
  TOP w0.381: R2670.2 55.54,76.76 C1220.1 54.07,76.76 v2(53.89,76.95)
  BOTTOM w0.508: 52.81,70.25 51.91,70.25 51.6,70.56 51.6,71.46 51.96,71.81 52.53,71.81 53.16,72.45 53.16,73.91 53.95,74.7 53.95,76.88 v2(53.89,76.95) ; 52.81,70.25 53.19,69.87 53.66,69.87 54.05,70.27 C4.1 C1221.1 ; 52.81,70.25 52.81,70.63 53.12,70.95 53.12,71.46 54.1,72.44 JCAM.1
+3VS_CR: length 1.1
  TOP w0.508: C1325.1 v2(196.95,20.02)
  vias: v2(179.16,15.91) v2(179.17,15.33) v2(179.8,15.9) v2(179.83,15.27) v2(196.44,16.34) v2(196.95,19.39) v2(197.08,16.34) v3(176.3,19.24)
+3VS_NGFF: length 18.7
  TOP w0.508: R80.1 32.59,34.83 32.22,35.2 32.22,36.49 31.86,36.84 31.23,36.84 30.79,37.28 v2(29.68,37.28)
  BOTTOM w0.508: 31.41,47.79 27.75,44.13 27.75,37.76 28.39,37.13 29.53,37.13 v2(29.68,37.28)
  vias: v2(33.88,47.33) v2(34.52,47.33) v2(47.73,47.62) v2(48.29,47.8) v3(31.88,47.91)
+3VS_TP: length 101.2
  TOP w0.254: v3(186.17,19.6) 186.69,19.08 v2(187.58,19.08)
  TOP w0.381: QH7.5 190.36,16.97 190.36,17.98 R1104.2 ; R1105.2 190.36,14.35 190.36,15.07 QH7.2
  TOP w0.508: R1299.1 184.22,21.96 Q40.2 184.22,19.83 184.44,19.6 v3(186.17,19.6) ; v2(190.63,19.19) R1104.2 ; v2(187.58,19.08) 187.58,18.4 C1225.1 C7.1 ; v2(188.82,14.82) 189.59,14.06 R1105.2 ; v2(172.14,65.44) 172.95,65.44 RE6.1 173.13,64.8 RE7.1 ; C1159.1 v2(167.82,17.74)
  IN1 w0.508: v2(167.82,17.74) 168.58,18.5 171.74,18.5 173.94,20.7 v2(173.94,21.17) ; v2(172.14,65.44) 171.8,65.44 170.51,64.15 170.51,63.52 169.33,62.34 169.33,60.98 168.37,60.02 168.37,56.06 v2(168.1,55.79)
  IN2 w0.508: v2(173.94,21.17) 172.92,22.19 172.92,32.85 169.92,35.86 169.92,37.77 171.31,39.16 171.31,40.51 170.18,41.64 170.18,42.76 171.3,43.88 171.3,55.23 170.16,56.37 168.68,56.37 v2(168.1,55.79)
  BOTTOM w0.254: JTP1.1 186.66,19.09 186.84,18.91 187.4,18.91 v2(187.58,19.08)
  BOTTOM w0.508: v2(188.82,14.82) 185.6,14.82 181.79,18.63 180.41,18.63 178.23,16.45 169.11,16.45 v2(167.82,17.74)
+3VS_TPM: length 21.4
  TOP w0.254: U15.22 188.21,46.07 190.29,46.07 C96.1 190.31,45.84 190.04,45.58 v2(189.84,45.58) ; U15.14 186.41,42.77 186.41,41.11 C95.1 186.92,41.11 v2(187.05,41.23) ; RH126.1 190.89,43.53 v2(190.96,43.47)
  TOP w0.381: Q72.3 194.48,46.69 190.65,46.69 190.31,46.35 C96.1
  IN3 w0.508: v2(189.84,45.58) 189.84,45.73 187.69,47.88 183.77,47.88 183.52,48.13 v2(183.17,48.13)
  BOTTOM w0.508: RC229.1 186.54,41.74 v2(187.05,41.23)
  vias: v2(184.28,40.37)
+3VS_TS: length 17.8
  TOP w0.381: 66.36,78.84 65.78,78.26 U728.3 ; 66.36,78.84 66.37,78.85 66.37,79.76 65.94,80.2 65.01,80.2 U728.1 ; 66.36,78.84 67.91,78.84 68.11,78.63 RH357.1
  TOP w0.508: R2671.2 55.79,79.59 C1208.1 57.13,80.22 57.35,80.45 v3(59.35,80.45) 63.06,80.45 C8.1 64.22,80.03 64.34,80.16 U728.1
+3VS_TSLDO: length 12
  TOP w0.508: U728.5 68.54,80.16 C1223.1 69.56,80.17 RH357.2 70.14,80.03 70.54,80.43 v3(71.58,80.43) 72.44,80.43 72.87,79.99 v2(72.87,79.74)
  BOTTOM w0.508: v2(72.87,79.74) 72.87,79.35 73.09,79.13 73.94,79.13 74.14,79.33 C1222.1 C5.1 72.87,78.44 72.76,78.56 71.65,78.56 JTS.6
+5V_USB_P2: length 2
  TOP w0.127: v2(18.75,51.14) 18.75,51.75 v3(19.7,52.7)
  vias: v2(18.16,51.16) v2(18.19,50.58) v2(18.8,50.56)
+5VALW: length 209.8
  TOP w0.076: U722.H10 22.76,59.72 22.76,59.31 22.32,58.87
  TOP w0.127: v2(22.01,58.33) 22.01,58.56 22.32,58.87
  TOP w0.203: v2(36.78,40.65) 36.93,40.8 36.93,41.48 U720.4 ; U716.4 171.3,16.33 171.3,15.68 v2(171.2,15.58) ; U719.4 51.93,20.15 52.43,20.15 52.61,19.96 52.61,19.95 52.63,19.93 52.61,19.91 52.61,19.89 52.64,19.92 52.67,19.92 v2(52.72,19.86) ; v2(179.71,34.43) 179.68,34.4 179.68,33.5 U717.4 ; v2(33.05,43.77) 33.12,43.7 33.12,42.9 U664.4
  TOP w0.254: CZ86.1 167.23,67.19 166.28,67.19 UZ19.3 ; v2(51.31,50.6) 50.96,50.6 UZ23.3 ; v2(167.81,46.29) 167.81,47.01 166.99,47.83 165.65,47.83 165.34,48.14 164.81,48.14 UZ22.3
  TOP w0.305: CZ88.1 158.52,79.38 158.24,79.66 158.09,79.66 157.83,79.92 v2(157.83,80.04) ; UZ25.3 157.21,75.68 157.35,75.68 157.51,75.52 157.99,75.52 158.19,75.73 158.6,75.73 v2(158.62,75.7) ; UZ26.3 58.42,75.17 v2(58.27,75.02)
  TOP w0.381: CZ86.1 167.31,66.66 v2(166.78,66.66)
  TOP w0.457: v2(22.01,58.33) 21.34,57.66 C1347.1
  TOP w0.508: PR1127.2 69.7,47.96 v2(70.1,47.56) ; LED14.2 v2(3.12,13.9) ; v2(193.65,19.73) v3(193.65,18.96) C1321.1 ; PR105.2 v2(36.04,71.46) ; v2(75.22,49.81) 74.68,50.35 PR1128.2 ; LED11.2 v2(3.04,6.7) ; LED10.2 v2(3.09,10.3) ; LED13.2 v2(3.15,3.1) ; LED12.2 v2(3.04,17.5)
  IN1 w0.508: v2(179.02,76.37) 179.02,76.39 179.83,75.57 182.47,75.57 183.36,74.68 184.48,74.68 184.71,74.91 190.04,74.91 190.96,74 192.79,74 196.43,70.35 196.43,62.71 195.1,61.38 195.1,53.31 198.22,50.19 198.22,46.64 200.29,44.57 v2(200.29,42.79) ; v2(167.81,46.29) 166.75,45.23 166.75,43.98 v2(166.9,43.82) ; 158.88,75.7 v2(158.62,75.7) ; 158.88,75.7 158.9,75.68 158.93,75.68 159.16,75.45 159.16,74.1 160.1,73.16 160.1,72.3 162.56,69.83 162.56,69.4 162.84,69.12 162.84,68.74 164.92,66.66 v2(166.78,66.66) ; 158.88,75.7 159.23,75.7 159.79,76.26 159.79,78.08 v2(157.83,80.04)
  IN2 w0.508: v2(36.04,71.46) 36.04,70.92 36.29,70.67 36.29,66.88 v2(36.14,66.72) ; v2(179.71,34.43) 179.89,34.43 182.28,32.04 184.71,32.04 186.36,30.39 186.36,27.31 187.22,26.45 189.81,26.45 191.87,24.39 191.87,21.51 v2(193.65,19.73)
  IN3 w0.508: v2(179.71,34.43) 180.49,34.43 181.1,35.04 182.52,35.04 184.2,36.71 185.29,36.71 185.7,37.12 187.71,37.12 189.76,35.06 192.05,35.06 195.73,38.74 197.59,38.74 200.29,41.45 v2(200.29,42.79)
  IN4 w0.508: v2(24.51,58.44) 24.02,57.95 22.39,57.95 v2(22.01,58.33) ; v2(176.13,43.32) 176.13,42.05 177.93,40.25 177.93,39.3 178.31,38.92 178.74,38.92 179.25,38.41 179.25,34.88 v2(179.71,34.43)
  BOTTOM w0.305: C376.1 47.22,21.09 46.92,20.79 JKB1.1
  BOTTOM w0.508: v2(166.9,43.82) 166.95,43.87 168.35,43.87 169.65,45.17 170.92,45.17 171.43,44.66 171.43,43.9 172.06,43.27 173.3,43.27 173.86,42.71 174.46,42.71 175.07,43.32 v2(176.13,43.32) ; v2(157.83,80.04) 167.26,80.04 167.97,80.76 176.02,80.76 177.58,79.2 179.02,77.76 v2(179.02,76.37) ; v2(65.47,56.79) 65.47,56.79 PR1080.2 ; v2(47.84,22.26) 47.56,21.98 C376.1
  vias: v2(27.71,54.95) v2(28.15,54.11) v2(28.53,51.17) v2(28.52,50.51) v2(28.52,49.9) v2(28.61,56.43) v2(28.63,53.73) v2(28.68,55.82) v2(51.89,22.42) v2(51.92,21.83) v2(52.48,22.42) v2(52.5,21.84) v2(53.13,22.42) v2(53.09,21.83) v2(53.97,18.21) v2(56.61,49.48) v2(56.61,48.89) v2(56.61,48.31) v2(57.2,49.5) v2(57.2,48.9) v2(57.2,48.31) v2(57.78,49.5) v2(57.79,48.9) v2(57.79,48.29) v2(58.37,49.48) v2(58.37,48.85) v2(58.37,48.27) v2(58.97,49.5) v2(58.95,48.91) v2(58.95,48.29) v2(60.68,49.36) v2(67.13,13.83) v2(67.73,13.83) v2(68.31,13.81) v2(68.89,13.81) v2(69.48,13.81) v2(70.08,13.8) v2(70.66,13.82) v2(96.51,18.56) v2(97.1,18.56) v2(97.71,18.56) v2(98.33,18.55) v2(98.93,18.53) v2(99.51,18.56) v2(153.37,15.18) v2(153.97,15.2) v2(154.56,15.2) v2(155.18,15.2) v2(155.8,15.2) v2(156.45,15.2) v2(193.13,16.93) v2(193.15,16.27) v2(193.71,16.94) v2(193.74,16.27) v2(194.35,16.93) v2(194.35,16.3) v3(52.42,23.07) v3(53.21,17.99)
+5VALWP: length 22.6
  IN1 w0.254: v2(54.46,45.81) 53.63,44.98 52.18,44.98 51.73,44.52 51.73,39.16 53.13,37.76 60.61,37.76 v2(61.85,39)
  BOTTOM w0.203: PU501.14 63.04,40.93 63.04,39.6 PR511.2
  BOTTOM w0.254: v2(61.85,39) 62.13,39.28 PR511.2
  vias: v2(55.09,45.81) v2(55.25,46.44) v2(55.91,45.78) v3(55.92,46.74)
+5VS: length 291.5
  TOP w0.254: v2(62.48,66.18) 62.89,65.77 63.68,65.77 64.16,65.29 PC1097.1 64.16,64.79 63.97,64.6 PU1305.6
  TOP w0.508: v2(164.55,14.41) 164.98,14.41 165.25,14.69 ; R886.2 162.32,17.23 161.67,16.58 161.67,15.65 162.15,15.16 162.15,14.25 162.61,13.8 v3(163.53,13.8) 165.07,13.8 165.25,13.98 165.25,14.69 ; 165.25,14.69 C1102.2
  IN1 w0.457: 57.63,57.9 57.13,57.39 57.13,56.98 v2(57.19,56.92)
  IN1 w0.508: 57.63,57.9 57.63,60.68 61.24,64.28 61.24,64.93 v2(62.48,66.18) ; v2(85.55,65.95) 85.12,65.95 84.28,65.11 84.28,61.58 85.5,60.36 v2(85.5,57.74) 85.22,57.74 84.81,57.34 84.81,51.72 85.5,51.04 v2(85.5,50.14) 85.46,50.17 84.07,50.17 84.05,50.15 83.54,50.15 83.52,50.17 81.69,50.17 79.35,47.84 v2(79.35,46.69)
  IN2 w0.508: v2(57.19,56.92) 57.13,56.98 56.61,56.98 56.07,56.44 56.07,54.69 54.47,53.09 52.6,53.09 50.39,50.89 50.39,49.92 v2(49.33,48.85)
  IN3 w0.508: v2(57.19,56.92) 57.13,56.98 56.62,56.98 56.32,56.69 56.32,56.07 56.74,55.65 57.63,55.65 58.36,56.38 59.51,56.38 59.92,55.97 61.8,55.97 62.74,55.03 63.17,55.03 66.24,51.95 66.24,49.66 71.36,44.54 78.6,44.54 79.35,45.3 v2(79.35,46.69) ; 54.69,17.82 54.69,17.36 54.23,16.9 50.52,16.9 49.71,17.71 v2(49.71,17.97) ; 54.69,17.82 54.74,17.77 59.49,17.77 60.14,17.12 61.85,17.12 62.22,17.49 67.09,17.49 68.94,19.34 78.08,19.34 80.19,17.23 91.8,17.23 92.69,16.34 94.69,16.34 95.19,16.84 99.83,16.84 100.5,16.16 125.12,16.16 125.3,16.34 131.4,16.34 133.43,14.31 156.69,14.31 157.82,15.44 158.5,15.44 158.9,15.04 158.9,13.86 159.01,13.75 163.91,13.75 164.52,14.36 164.52,14.37 v2(164.55,14.41) ; 54.69,17.82 54.69,21.57 54.28,21.98 54.28,23.17 v2(54.25,23.2)
  IN4 w0.508: v2(49.33,48.85) 49.33,47.66 46.84,45.17 46.84,44.28 47.23,43.89 47.23,42.35 43.19,38.31 41.1,38.31 40.44,37.65 40.44,36.55 40.87,36.12 41.12,36.12 41.51,35.72 41.51,31.95 43.28,30.18 43.28,27.15 44.5,25.93 51.53,25.93 v2(54.25,23.2) ; v2(49.71,17.97) 48.84,17.1 v2(45.57,17.1)
  BOTTOM w0.203: PU1102.2 84.65,49.08 84.94,49.36 84.94,50.5 85.19,50.76 PC1129.1 v2(85.5,50.14) ; PU1101.2 84.66,56.7 84.94,56.98 84.94,58.12 85.19,58.38 PC1119.1 v2(85.5,57.74) ; v2(85.55,65.95) 85.55,66.33 84.94,66.94 ; 84.94,66.94 PC1114.1 ; 84.94,66.94 84.94,66.28 84.99,66.23 84.99,65.44 84.72,65.17 PU1100.2
  BOTTOM w0.305: v2(45.57,17.1) 46.28,17.81 46.28,19.65 46.42,19.8 JKB1.2
  BOTTOM w0.508: JFAN1.4 165.62,15 165.03,14.41 v2(164.55,14.41) ; JUART.1 50.6,22.6 50.6,23.63 51.44,24.47 53.54,24.47 54.25,23.76 v2(54.25,23.2)
+5VS_AUDIO: length 1
  BOTTOM w0.508: v2(32.28,27.97) 32.74,27.52 CA97.1
  vias: v2(21.81,20.45) v2(22.4,20.45) v2(22.98,20.45) v2(32.48,24.23) v2(32.51,23.64) v2(33.03,24.8) v2(33.14,24.21) v2(33.15,23.63) v2(33.74,24.19) v2(33.74,23.6) v2(45.82,22.39) v2(45.92,22.97) v2(45.92,21.8) v2(46.41,22.39) v2(46.53,22.97) v2(46.51,21.8) v2(46.51,21.22) v3(21.31,20.1)
+AVDD1: length 18.6
  TOP w0.203: v2(23.7,31.94) 24.16,31.48 UA2.26
  IN2 w0.508: v2(23.7,31.94) 21.34,31.94 21.06,32.22 20.27,32.22 19.81,31.75 19.81,30.2 19.38,29.78 18.87,29.78 18.28,29.18 18.28,28.26 21.46,25.08 v2(22.48,25.08)
  BOTTOM w0.508: v2(23.7,31.94) 23.27,31.94 22.79,31.45 CA103.1 22.15,32.46 CA102.1
  vias: v3(23.9,32.98)
+AVDD2: length 7.9
  TOP w0.203: UA2.40 26.66,25.98 25.38,24.7 CA80.1
  TOP w0.508: CA80.1 25.36,24.15 24.93,24.15 24.42,24.66 CA82.1 v2(24.23,23.96)
  BOTTOM w0.508: RA63.2 24.36,25.36 24.9,24.83 v3(24.9,24.25) 24.9,24.25 24.61,23.96 v2(24.23,23.96)
+DVDD: length 22.3
  TOP w0.203: UA2.1 30.99,27.48 31.43,27.03
  TOP w0.508: CA5.1 35.94,26.37 35.64,26.07 v2(35.64,25.26) ; CA5.1 35.9,26.32 CA31.1 CA42.1 CA4.1 32.74,26.7 31.76,26.7 31.43,27.03 ; CA5.1 36.43,25.9 36.43,24.85 ; RA76.1 31.95,34.38 v2(32,34.32) ; 36.43,24.85 35.61,24.02 RA81.2 ; 36.43,24.85 LA14.2
  IN3 w0.508: v2(35.64,25.26) 33.25,27.64 33.25,33.08 v2(32,34.32)
+DVDDIO: length 10.1
  TOP w0.203: UA2.9 31.13,30.68 31.65,31.2 v2(32.13,31.2)
  BOTTOM w0.127: v3(31.47,36.15) RA80.1
  BOTTOM w0.508: CA104.1 33.02,31.1 32.23,31.1 v2(32.13,31.2) ; CA104.1 CA7.1 32.65,32.36 CA6.1 32.8,33.51 RA82.2 RA80.1 ; CA104.1 CA105.1
+PVDD1: length 1.1
  TOP w0.203: UA2.41 27.06,25.72 v2(26.9,25.56)
  vias: v2(26.01,24.67) v2(26.47,25.12) v3(26.01,25.51)
+PVDD2:
  vias: v2(29.19,25.71) v2(29.86,25.64) v3(28.01,26.37)
+V1.8S_EDRAM: length 10.1
  TOP w0.127: v3(114.27,71.89) R1334.2
  TOP w0.254: v2(112.79,71) 112.79,71.64 R1334.2
  TOP w0.508: v2(116,68.36) 115.74,68.63 RC232.1
  IN4 w0.508: v2(116,68.36) 116,70.3 114.84,71.46 113.25,71.46 v2(112.79,71)
  BOTTOM w0.254: UCPU1.H63 116.41,67.7 116,68.11 v2(116,68.36)
+VBUS_DC_SS: length 138.3
  TOP w0.127: v2(44.59,13.72) v3(46.59,13.72)
  TOP w0.508: PD302.2 39.47,16.79 40.33,15.94 42.38,15.94 v2(44.59,13.72) ; PR267.1 v2(60.12,14.36)
  IN2 w0.508: v2(32.1,71.82) 31.89,71.61 31.27,71.61 30.62,72.25 28.29,72.25 27.28,73.27 24.63,73.27 22.63,71.26 22.63,69.22 21.22,67.81 21.22,66.48 19.96,65.22 19.96,64.4 20.65,63.71 20.65,60.35 20.14,59.84 20.14,58.45 20.56,58.03 20.56,57.02 21.31,56.27 22.06,56.27 22.85,57.05 24.68,57.05 25.15,56.58 25.15,54.04 26.75,52.43 26.75,48.62 29.02,46.35 29.02,42.35 v2(28.95,42.27)
  IN4 w0.508: v2(46.05,76.93) 45.42,76.93 44.03,75.54 39.14,75.54 35.06,71.46 32.47,71.46 v2(32.1,71.82) ; v2(60.12,14.36) 58.01,14.36 56.44,15.93 51.84,15.93 49.63,13.72 v2(44.59,13.72) 38.39,13.72 37.47,14.64 32.56,14.64 32.09,15.11 32.09,15.71 33.2,16.81 33.2,21.86 34.52,23.18 34.52,26.37 33.3,27.59 33.3,32.88 34.16,33.74 34.16,34.95 34.42,35.2 34.42,38.92 34.06,39.28 34.06,40.45 33.48,41.03 29.93,41.03 28.95,42.02 v2(28.95,42.27)
+VCC0V9_CIO: length 5.4
  TOP w0.203: UT1.R12 UT1.R11 v2(44.13,59.54)
  TOP w0.254: v2(44.13,59.54) UT1.R9 v2(44.13,58.89) UT1.R8
  TOP w0.305: CT101.1 49.24,54.67 48.65,54.67 v2(48.55,54.57)
  TOP w0.356: CT103.1 CT102.1 CT101.1
  BOTTOM w0.127: v2(44.13,59.54) v1(43.52,59.54)
+VCC0V9_DP: length 9.8
  TOP w0.203: UT1.L12 41.85,60.52 v2(41.52,60.19) 41.85,59.87 UT1.L11 ; UT1.M6 42.49,57.92 v2(42.18,58.23) 41.87,57.92 UT1.L6 ; UT1.V12 45.1,60.51 v2(44.78,60.19) 44.45,60.52 UT1.T12 ; UT1.T11 v2(44.78,59.54) 44.97,59.74 44.97,59.74 UT1.V11
  TOP w0.254: UT1.M8 42.49,58.57 v2(42.17,58.88) UT1.L8 ; UT1.V13 44.78,60.84 v2(44.78,60.84) ; v2(49.2,53.98) 49.38,53.81 CT62.1
  TOP w0.305: CT62.1 CT63.1 CT65.1 CT64.1 CT66.1 51.92,53.65 51.66,53.91 CT67.1 CT68.1
  vias: v3(49.76,54.03)
+VCC0V9_PCIE: length 4.6
  TOP w0.203: UT1.M13 42.5,61.17 v2(42.17,61.49) 42.17,61.51 42.32,61.65 42.34,61.65 UT1.M15 ; UT1.N19 v2(42.82,63.44) UT1.N18 ; v2(42.17,62.14) UT1.M16 42.18,62.79 v2(42.17,62.79) UT1.M18 v2(42.17,63.44) ; v2(42.17,63.44) UT1.L19 ; v2(42.17,63.44) 41.85,63.12 UT1.L18
  vias: v2(42.52,66.63)
+VCC0V9_USB: length 2.4
  TOP w0.127: UT1.R16 43.8,62.46 v2(43.48,62.14) UT1.R15
  TOP w0.381: CT93.1 CT94.1 49.15,66.89 v2(48.69,66.43)
+VCC_CORE: length 46.6
  TOP w0.508: RC140.1 134.87,72.4 v2(134.6,72.67)
  IN3 w0.508: v2(134.6,72.67) 134.56,72.7 v2(131.55,72.7) 129.72,72.7 v2(129.69,72.68)
  BOTTOM w0.127: 132.54,68.13 UCPU1.J33 ; UCPU1.J33 132.54,67.5 ; UCPU1.J33 132.2,67.83 ; UCPU1.J33 132.85,67.83 ; UCPU1.AM33 133,55.75 ; UCPU1.AM33 133,56.35 ; UCPU1.AM33 133.32,56.05 ; UCPU1.AM33 132.66,56.05 ; 129.9,67.4 129.93,67.36 UCPU1.K38 ; 131.17,56.4 131.17,56.39 UCPU1.AM37 ; 132.46,56.04 132.45,56.05 UCPU1.AM35 ; UCPU1.AL33 133.45,56.2 133.45,56.19 ; UCPU1.AL33 133.45,56.83 ; UCPU1.AL33 133.12,56.53 133.12,56.52 ; UCPU1.AL33 133.78,56.53 133.78,56.52 ; 132.08,67.69 UCPU1.K35 ; UCPU1.K35 132.08,66.97 ; UCPU1.K35 132.39,67.36 ; UCPU1.K35 131.72,67.36 131.7,67.34 ; 129.02,56.99 UCPU1.AK40 ; UCPU1.AK40 129.34,57.41 ; UCPU1.AK40 129.34,56.61 ; UCPU1.AK40 129.7,56.99 129.71,56.98 ; 133.38,56.98 133.37,56.99 UCPU1.AK33 ; 133.35,67.34 133.33,67.36 UCPU1.K33 ; 131.17,67.66 UCPU1.K37 ; UCPU1.K37 130.86,67.36 ; UCPU1.K37 131.51,67.36 131.52,67.34 ; UCPU1.K37 131.17,67.02 ; v2(133.23,57.43) 133.23,57.54 133,57.31 UCPU1.AK33 ; 130.71,67.52 UCPU1.J37 ; UCPU1.J37 131.02,67.83 ; UCPU1.J37 130.38,67.83 ; UCPU1.J37 130.71,68.14 ; v2(130.7,68.54) 130.71,68.53 ; UCPU1.K38 130.25,67 ; UCPU1.K38 130.56,67.36 ; UCPU1.K38 130.25,67.68 ; UCPU1.AK37 131.17,56.65 131.17,56.65 ; UCPU1.AK37 131.17,57.33 131.17,57.34 ; UCPU1.AK37 131.49,56.99 ; 131.63,56.85 UCPU1.AL37 ; UCPU1.AL37 131.95,56.53 131.95,56.52 ; UCPU1.AL37 131.29,56.53 131.29,56.52 ; UCPU1.AM38 129.94,56.05 129.8,56.19 UCPU1.AL40 ; UCPU1.AM38 130.57,56.05 ; UCPU1.AM38 130.25,56.39 ; UCPU1.AM38 130.25,55.76 ; UCPU1.K33 133,67.69 ; UCPU1.K33 132.69,67.36 ; UCPU1.K33 133,66.92 ; 127.86,67.34 127.85,67.36 UCPU1.K43 ; 129.71,67.4 129.67,67.36 UCPU1.K40 ; UCPU1.AK35 132.08,57.31 132.08,57.31 ; UCPU1.AK35 131.76,56.99 ; UCPU1.AK35 132.08,56.65 132.08,56.65 ; UCPU1.AM35 132.08,55.76 ; UCPU1.AM35 132.08,56.39 132.08,56.4 ; UCPU1.AM35 131.74,56.05 ; 127.51,67.69 UCPU1.K43 ; UCPU1.K43 127.51,66.95 127.52,66.94 ; 130.25,56.69 UCPU1.AK38 130.25,57.28 ; UCPU1.K42 128.42,67.69 128.38,67.74 ; UCPU1.K42 128.73,67.36 ; UCPU1.K42 128.42,66.98 ; UCPU1.K42 128.08,67.36 128.07,67.34 ; 134.37,68.12 UCPU1.J30 134.06,67.83 ; UCPU1.AM32 133.91,56.38 ; UCPU1.AM32 133.57,56.05 ; UCPU1.AM32 133.91,55.81 133.8,55.71 ; 129.8,56.82 UCPU1.AL40 ; UCPU1.AL40 129.46,56.53 ; UCPU1.AL40 130.14,56.53 ; UCPU1.J40 128.56,67.83 ; UCPU1.J40 129.19,67.83 ; UCPU1.J40 128.88,68.13 ; UCPU1.J40 128.88,67.52 ; UCPU1.K40 129.34,66.97 ; UCPU1.K40 129.03,67.36 ; UCPU1.K40 129.34,67.68 ; 131.17,55.74 UCPU1.AM37 ; UCPU1.AM37 130.82,56.05 ; UCPU1.AM37 131.48,56.05 ; UCPU1.AK33 133,56.68
  BOTTOM w0.203: UCPU1.A34 131.92,72.28 131.67,72.53 131.67,72.58 v2(131.55,72.7) ; v2(129.69,72.68) 129.67,72.68 129.44,72.46 UCPU1.A39 ; UCPU1.A30 134.4,72.48 v2(134.6,72.67) ; UCPU1.G30 134.8,68.29 v2(134.39,68.52) 133.97,68.29 UCPU1.G32 ; UCPU1.G33 133,68.32 v2(132.49,68.6) 132.08,68.37 UCPU1.G35 ; UCPU1.A44 v2(126.97,73.17)
  BOTTOM w0.254: UCPU1.G40 129.09,68.54 v2(128.87,68.54) 128.67,68.54 UCPU1.G42 ; UCPU1.G38 130.5,68.54 v2(130.7,68.54) 130.92,68.54 UCPU1.G37
  BOTTOM w0.305: PC1237.1 130.12,75.55 130.12,73.11 v2(129.69,72.68)
  vias: v2(91.53,65.52) v2(91.53,64.89) v2(91.53,64.31) v2(91.53,63.72) v2(91.7,61.99) v2(91.68,61.35) v2(92.09,66) v2(92.09,65.37) v2(92.09,64.73) v2(92.27,61.36) v2(92.69,66.63) v2(92.69,66) v2(92.69,65.36) v2(92.69,64.73) v2(92.91,61.36) v2(93.32,66.63) v2(93.32,66) v2(93.32,65.36) v2(93.32,64.73) v2(93.54,61.36) v2(93.96,66.63) v2(93.96,66) v2(93.96,65.36) v2(93.96,64.73) v2(94.12,61.37) v2(94.59,66.63) v2(94.59,66) v2(94.59,65.36) v2(94.59,64.73) v2(95.23,66.63) v2(95.23,66) v2(95.23,65.36) v2(95.23,64.73) v2(95.23,64.09) v2(95.23,63.51) v2(95.24,62.92) v2(95.86,66.63) v2(95.86,66) v2(95.86,65.36) v2(95.89,64.73) v2(95.89,64.09) v2(95.89,63.51) v2(101.84,69.35) v2(103.47,69.35) v2(105.12,69.35) v2(128.19,66.58) v2(128.3,62.47) v2(128.3,61.88) v2(128.42,63.08) v2(128.8,66.61) v2(128.75,65.97) v2(129.03,62.98) v2(129.34,65.97) v2(129.34,60.13) v2(129.41,66.58) v2(129.52,64.47) v2(129.92,65.97) v2(130,66.61) v2(130.05,58.78) v2(130.44,58.35) v2(130.51,65.97) v2(130.61,66.58) v2(130.72,64.48) v2(130.66,60.16) v2(130.71,55.61) v2(130.85,58.77) v2(130.83,57.87) v2(131.09,65.97) v2(131.19,66.56) v2(131.24,58.32) v2(131.6,58.78) v2(131.63,57.89) v2(131.64,57.3) v2(131.62,55.63) v2(131.8,66.58) v2(131.75,66) v2(131.93,64.47) v2(131.93,60.16) v2(132.01,58.33) v2(132.39,66.58) v2(132.39,66) v2(132.44,62.85) v2(132.4,58.78) v2(132.4,57.87) v2(132.54,55.63) v2(132.77,58.33) v2(132.97,66.58) v2(132.97,66) v2(133.02,62.85) v2(133.1,60.13) v2(133.2,64.47) v2(133.2,58.73) v2(133.3,58.08) v2(133.53,61.43) v2(133.55,66.1) v2(133.55,63.13) v2(133.73,60.28) v2(133.93,65.06) v2(133.93,64.45) v2(133.93,62.67) v2(133.93,60.87) v2(133.96,65.64) v2(133.96,61.83) v3(126.8,72.22)
+VCC_CORE_G0: length 1.1
  TOP w0.127: v2(134.25,66.99) 133.91,66.65 T122.1
  BOTTOM w0.254: v2(134.25,66.99) 133.91,67.33 UCPU1.K32
+VCC_CORE_G1: length 1.5
  TOP w0.127: v2(133.83,57.69) 133.83,57.23 T123.1
  BOTTOM w0.127: UCPU1.AK32 133.83,57.07 v2(133.83,57.69)
+VCC_EDRAM:
  vias: v2(95.01,39.75) v2(95.01,38.13) v2(95.64,39.75) v2(95.67,38.13) v2(117.7,61.23) v2(117.88,63.15) v2(117.93,61.83) v2(118.01,62.49) v3(117.2,63.97)
+VCC_EDRAM_P: length 15.8
  TOP w0.203: v2(92.02,41.64) 92.58,41.08 95.05,41.08 96.13,40 96.13,37.61 95.66,37.14 v3(94.46,37.14) 93.35,36.03 90.6,36.03 PR1506.1
  TOP w0.508: PC1505.1 94.68,41.8 v2(94.87,41.61)
+VCC_EOPIO: length 0.1
  BOTTOM w0.254: UCPU1.AG62 117.21,58.39
  vias: v2(91.15,35.44) v2(91.73,35.44) v2(92.32,35.44) v2(92.9,35.44) v2(117.46,58.83) v2(118.03,59.03) v2(118.15,58.41) v2(118.81,58.38) v3(116.89,58.61)
+VCC_EOPIO_P: length 9.1
  TOP w0.254: v2(88.91,27.48) 89.75,26.65 91.89,26.65 92.2,26.96 v3(92.2,28.91) 92.2,29.55 v2(91.89,29.87)
  BOTTOM w0.254: v2(88.91,27.48) 88.91,26.34 PR1519.1
  vias: v2(91.56,31.93) v2(92.04,31.59)
+VCC_GT: length 90.7
  TOP w0.254: v2(123.85,61.86) 123.85,61.48 PC1346.1 ; PC1219.1 126.54,58.45 126.54,58.81 v2(126.57,58.84) ; PC1336.1 125.25,58.43 v2(125.25,58.81) ; PC1345.1 126.42,61.5 v2(126.42,61.86) ; PC1221.1 125.73,64.88 v2(125.73,64.55) ; v2(121.92,64.42) 121.92,64.75 PC1347.1 ; PC1344.1 121.41,58.4 v2(121.41,58.84) ; v2(123.19,64.55) 123.19,64.88 PC1223.1 ; PC1342.1 117.2,66.36 v2(117.41,66.15) ; PC1222.1 124.49,64.91 v2(124.49,64.55) ; PC1348.1 120.63,64.73 v2(120.63,64.39) ; PC1220.1 123.98,58.43 v2(123.98,58.81) ; PC1330.1 125.12,61.48 v2(125.12,61.86) ; PC1337.1 122.68,58.4 v2(122.68,58.81) ; v2(120.14,58.81) 120.14,58.4 PC1333.1 ; PC1349.1 119.43,64.8 v2(119.43,64.39)
  TOP w0.305: v2(118.85,67.09) 119.22,67.46 PC1338.1
  TOP w0.381: v2(99.67,61.15) PC1249.1
  TOP w0.457: RC161.1 111.61,67.01 111.99,66.63 111.99,65.74
  BOTTOM w0.127: UCPU1.K55 121.48,67.36 ; UCPU1.K55 120.77,67.36 ; UCPU1.K55 121.11,67.67 ; UCPU1.K55 121.11,67.02 ; 117.52,65.71 UCPU1.M62 ; UCPU1.M62 117.16,65.4 ; UCPU1.M62 116.82,65.71 ; 119.28,57.34 119.28,57.33 UCPU1.AK58 ; UCPU1.K60 118.37,67.72 118.36,67.73 ; UCPU1.K60 118.37,66.99 ; UCPU1.K60 118.71,67.36 ; UCPU1.J52 122.81,67.83 ; UCPU1.J52 122.48,68.13 ; UCPU1.J52 122.15,67.83 ; UCPU1.L62 117.16,66.95 ; UCPU1.L62 116.85,66.62 ; UCPU1.L62 117.51,66.62 ; UCPU1.L62 117.16,66.32 ; 123.04,67.83 UCPU1.J50 ; UCPU1.J50 123.4,68.13 ; UCPU1.J50 123.4,67.47 ; UCPU1.J50 123.75,67.83 ; 125.81,67.83 UCPU1.J45 ; UCPU1.J45 126.49,67.83 ; UCPU1.J45 126.14,67.47 ; UCPU1.J45 126.14,68.13 ; 126.02,56.99 UCPU1.AK46 ; UCPU1.AK46 125.68,56.6 ; UCPU1.AK46 125.33,56.99 ; UCPU1.AK46 125.68,57.33 ; UCPU1.AK53 122.02,56.65 122.02,56.65 ; UCPU1.AK53 122.02,57.36 122.02,57.36 ; UCPU1.AK53 122.42,56.99 ; 124.77,55.74 UCPU1.AM48 ; UCPU1.AM48 124.42,56.05 ; UCPU1.AM48 125.08,56.05 ; UCPU1.AM48 124.77,56.42 ; UCPU1.AL60 118.82,56.88 118.82,56.88 ; UCPU1.AL60 118.82,56.17 118.82,56.17 ; UCPU1.AL60 119.18,56.53 119.18,56.52 ; UCPU1.AL60 118.41,56.53 118.36,56.57 118.37,56.58 UCPU1.AK60 ; 124.42,67.36 UCPU1.K48 ; UCPU1.K48 124.77,66.99 ; UCPU1.K48 124.77,67.7 ; UCPU1.K48 125.14,67.36 ; UCPU1.R63 116.98,64.34 117.16,64.16 UCPU1.T62 ; UCPU1.R63 116.69,63.97 ; UCPU1.R63 116.37,64.34 ; UCPU1.R63 116.69,64.68 ; 122.81,56.52 122.81,56.53 UCPU1.AL53 ; 117.52,62.05 UCPU1.Y62 ; UCPU1.Y62 116.83,62.05 ; UCPU1.Y62 117.16,61.72 ; UCPU1.Y62 117.16,62.4 ; 122.48,56.19 122.48,56.2 UCPU1.AL53 ; 120.19,56.4 120.2,56.39 UCPU1.AM56 119.83,56.05 119.81,56.07 ; UCPU1.AK42 128.72,56.99 ; UCPU1.AK42 128.42,56.68 ; UCPU1.AK42 128.11,56.99 ; UCPU1.AK42 128.42,57.33 ; 121.11,56.63 121.11,56.63 UCPU1.AK55 ; UCPU1.AU63 116.23,53.1 v2(116.08,53.1) ; 116.69,65.56 UCPU1.N63 ; UCPU1.N63 116.32,65.25 ; UCPU1.N63 117.01,65.25 ; UCPU1.N63 116.69,64.93 ; UCPU1.J58 118.82,67.5 118.82,67.5 ; UCPU1.J58 119.15,67.83 119.15,67.83 ; UCPU1.J58 118.82,68.13 ; UCPU1.J58 118.49,67.83 ; 118.99,56.05 UCPU1.AM58 ; UCPU1.AM58 119.28,56.39 ; UCPU1.AM58 119.61,56.05 ; UCPU1.AM58 119.28,55.76 ; 118.92,57.01 118.94,56.99 UCPU1.AK58 ; 117.03,62.51 UCPU1.W63 116.69,62.16 ; UCPU1.AM53 121.71,56.05 ; UCPU1.AM53 122.36,56.05 ; UCPU1.AM53 122.02,55.74 ; UCPU1.AM53 122.02,56.39 ; UCPU1.AK56 120.48,56.99 ; UCPU1.AK56 120.2,56.65 ; UCPU1.AK56 120.2,57.36 120.19,57.36 ; 127.51,57.31 UCPU1.AK43 ; UCPU1.AK43 127.14,56.99 ; UCPU1.AK43 127.51,56.65 ; UCPU1.AK43 127.86,56.99 ; 122.62,56.05 UCPU1.AM52 ; UCPU1.AM52 122.94,56.37 ; UCPU1.AM52 123.28,56.05 ; UCPU1.AM52 122.94,55.74 ; UCPU1.J56 119.74,67.47 ; UCPU1.J56 119.74,68.1 ; UCPU1.J56 119.36,67.83 ; UCPU1.J56 120.09,67.83 ; UCPU1.AL46 126.49,56.53 ; UCPU1.AL46 125.81,56.53 ; UCPU1.AL46 126.14,56.2 ; UCPU1.AL46 126.14,56.85 ; UCPU1.J60 118.26,67.83 ; UCPU1.J60 117.91,68.13 ; UCPU1.J60 117.91,67.54 ; UCPU1.AL56 120.33,56.53 ; UCPU1.AL56 120.95,56.53 ; UCPU1.AL56 120.65,56.26 ; UCPU1.AL56 120.65,56.85 ; 124.92,67.83 UCPU1.J46 ; UCPU1.J46 125.22,67.47 ; UCPU1.J46 125.58,67.83 ; UCPU1.J46 125.22,68.13 ; 123.85,67.02 UCPU1.K50 ; UCPU1.K50 123.85,67.7 ; UCPU1.K50 123.53,67.36 ; UCPU1.K50 124.22,67.36 ; 123.85,57.33 UCPU1.AK50 ; UCPU1.AK50 123.85,56.65 ; UCPU1.AK50 124.19,56.99 ; UCPU1.AL53 122.48,56.85 122.48,56.85 ; UCPU1.AL53 122.15,56.53 122.15,56.52 ; UCPU1.T62 116.82,63.88 ; UCPU1.T62 117.16,63.55 ; 122.94,56.6 122.94,56.6 UCPU1.AK52 ; UCPU1.J43 127.05,67.51 ; UCPU1.J43 127.05,68.11 ; UCPU1.J43 126.72,67.83 ; UCPU1.BB57 119.56,48.45 v2(119.46,48.35) ; 121.21,67.83 UCPU1.J53 ; UCPU1.J53 121.57,67.5 ; UCPU1.J53 121.94,67.83 ; UCPU1.J53 121.57,68.1 ; 122.56,56.99 UCPU1.AK52 ; UCPU1.AK52 122.94,57.26 ; UCPU1.K58 119.28,67.02 ; UCPU1.K58 119.28,67.7 119.28,67.7 ; UCPU1.K58 119.63,67.36 ; UCPU1.K58 118.96,67.36 ; UCPU1.AK55 120.77,56.99 120.75,57.01 ; UCPU1.AK55 121.11,57.33 121.11,57.34 ; UCPU1.AU58 119.13,52.8 v2(118.82,53.1) ; 119.28,56.65 119.28,56.65 UCPU1.AK58 ; 124.31,56.85 UCPU1.AL50 ; UCPU1.AL50 124.31,56.2 ; UCPU1.AL50 124.66,56.53 ; UCPU1.AL50 123.98,56.53 ; UCPU1.K56 120.54,67.36 ; UCPU1.K56 119.87,67.36 ; UCPU1.K56 120.2,67.7 ; UCPU1.K56 120.2,67.02 ; 116.69,61.96 UCPU1.AA63 ; UCPU1.AA63 116.34,61.59 ; UCPU1.AA63 117.03,61.59 ; UCPU1.AA63 116.69,61.25 ; 120.3,67.83 UCPU1.J55 ; UCPU1.J55 120.65,68.1 ; UCPU1.J55 120.65,67.45 ; UCPU1.J55 121.03,67.83 ; 122.02,67.67 UCPU1.K53 ; UCPU1.K53 121.68,67.36 ; UCPU1.K53 122.02,67.04 ; 124.43,56.99 UCPU1.AK48 ; UCPU1.AK48 125.11,56.99 ; UCPU1.AK48 124.77,56.65 ; UCPU1.AK48 124.77,57.36 ; 122.94,67.02 UCPU1.K52 ; UCPU1.K52 122.94,67.7 ; UCPU1.K52 123.26,67.36 ; 124.31,68.13 UCPU1.J48 ; UCPU1.J48 124.66,67.83 ; UCPU1.J48 123.98,67.83 ; UCPU1.J48 124.31,67.5 ; 127.97,56.2 UCPU1.AL43 ; UCPU1.AL43 128.32,56.53 ; UCPU1.AL43 127.97,56.85 ; UCPU1.AL43 127.64,56.53 ; UCPU1.BB66 114.58,50.01 114.58,49.06 114.12,48.6 v2(113.97,48.6) ; 124.19,56.05 UCPU1.AM50 ; UCPU1.AM50 123.85,55.74 ; UCPU1.AM50 123.85,56.42 ; UCPU1.AM50 123.51,56.05 ; UCPU1.AK45 126.25,56.99 ; UCPU1.AK45 126.93,56.99 ; UCPU1.AK45 126.6,57.31 ; UCPU1.AK45 126.6,56.65 ; 116.76,66.51 116.69,66.43 UCPU1.L63 ; UCPU1.L63 116.69,65.82 ; UCPU1.L63 116.98,66.17
  BOTTOM w0.152: 118.63,56.99 UCPU1.AK60
  BOTTOM w0.178: v2(110.71,57.21) 110.89,57.19 111.8,57.19 UCPU1.AK70
  BOTTOM w0.203: UCPU1.A48 124.54,72.04 124.54,72.8 v2(124.54,72.8) ; UCPU1.A53 121.95,72.05 121.95,72.94 v2(122.04,73.02) ; v2(117.03,72.9) 117.05,72.87 UCPU1.A62 ; v2(119.51,72.94) 119.54,72.91 119.54,71.99 UCPU1.A58 ; UCPU1.A66 v2(114.58,73)
  BOTTOM w0.254: 113.44,63.56 UCPU1.U68
  vias: v2(90.27,59.39) v2(90.27,58.63) v2(90.27,57.87) v2(90.27,57.11) v2(90.27,52.92) v2(90.27,52.03) v2(90.27,51.27) v2(90.27,50.38) v2(90.27,49.49) v2(90.91,59.78) v2(90.91,59.01) v2(90.91,58.25) v2(90.91,57.49) v2(90.91,56.73) v2(90.91,53.3) v2(90.91,52.54) v2(90.91,51.65) v2(90.91,50.76) v2(90.91,49.87) v2(91.03,45.04) v2(91.29,44.41) v2(91.42,59.39) v2(91.42,58.63) v2(91.42,57.87) v2(91.42,57.11) v2(91.42,56.09) v2(91.42,53.81) v2(91.42,52.92) v2(91.42,52.03) v2(91.42,51.27) v2(91.42,50.38) v2(91.42,49.49) v2(91.42,48.6) v2(91.42,47.96) v2(91.42,46.57) v2(91.42,45.81) v2(91.8,45.17) v2(92.05,59.78) v2(92.05,59.01) v2(92.05,58.25) v2(92.05,57.49) v2(92.05,56.73) v2(92.05,53.3) v2(92.05,52.54) v2(92.05,51.65) v2(92.05,50.76) v2(92.05,49.87) v2(92.18,45.81) v2(92.3,44.54) v2(92.69,59.39) v2(92.69,58.63) v2(92.69,57.87) v2(92.69,57.11) v2(92.69,52.92) v2(92.69,52.03) v2(92.69,51.27) v2(92.69,50.38) v2(92.69,49.49) v2(92.81,45.17) v2(93.32,59.78) v2(93.32,59.01) v2(93.32,58.25) v2(93.32,57.49) v2(93.32,56.73) v2(93.32,53.3) v2(93.32,52.54) v2(93.32,51.65) v2(93.32,50.76) v2(93.32,49.87) v2(93.32,44.54) v2(93.45,45.81) v2(93.45,45.17) v2(100.46,61.15) v2(100.89,59.57) v2(101.4,62.52) v2(101.8,61.15) v2(102.04,63.88) v2(102.74,63.89) v2(102.79,62.52) v2(103.25,61.15) v2(103.53,63.88) v2(103.58,62.52) v2(104.17,63.88) v2(104.65,61.16) v2(104.78,63.88) v2(105.41,57.95) v2(105.49,63.88) v2(105.66,62.52) v2(106.23,63.88) v2(106.4,62.52) v2(106.48,61.16) v2(107.07,63.88) v2(107.73,63.88) v2(107.87,61.15) v2(108.38,62.52) v2(108.61,63.89) v2(109.12,62.52) v2(109.3,63.88) v2(110,63.88) v2(110.16,60.84) v2(110.36,62.49) v2(110.63,63.9) v2(111.23,63.92) v2(111.81,61.14) v2(111.9,64.79) v2(111.86,63.87) v2(112.46,63.88) v2(112.46,62.05) v2(113.11,63.91) v2(113.11,61.14) v2(113.76,64.8) v2(113.76,63.88) v2(114.35,64.8) v2(114.43,63.92) v2(114.41,61.14) v2(116.29,64.76) v2(116.31,62.05) v2(116.36,61.15) v2(117.42,62.51) v2(117.68,65.29) v2(117.91,67.12) v2(118.74,65.3) v2(118.88,55.67) v2(119.74,67.09) v2(119.72,55.63) v2(120.65,67.06) v2(120.68,57.43) v2(121.08,65.89) v2(121.59,55.67) v2(121.67,66.99) v2(121.67,65.86) v2(122.28,65.86) v2(122.48,57.44) v2(122.47,55.67) v2(122.88,65.87) v2(123.38,55.67) v2(124.32,67.08) v2(124.29,57.42) v2(124.31,55.73) v2(125.2,66.91) v2(125.19,57.44) v2(126.14,57.44) v3(123.47,73.03)
+VCC_SA: length 39.1
  TOP w0.127: PC1327.1 135.97,68.73
  TOP w0.305: PC1315.1 137.34,68.59 137.96,68.59 v2(138,68.54) 138,68.39 137.64,68.03 PC1325.1 PC1324.1 ; PC1328.1 134.8,66.68 134.8,67.75 135.15,68.11 135.41,68.11 135.79,68.49 PC1327.1 ; PC1317.1 138.02,59.42 138.25,59.19 138.25,58.66 PC1322.1 PC1323.1 ; 135.97,68.73 136.22,68.73 136.3,68.65 136.3,68.62 v2(136.3,68.62) ; v2(140.69,69.27) 140.46,69.5 RC168.1
  TOP w0.381: PC1326.1 136.41,67.43 136.22,67.24 v2(136.22,67.06)
  TOP w0.508: PC1317.1 137.8,59.9 v2(137.31,60.38) ; v2(135.41,76.51) 135.41,77.1 PC1310.1 PC1313.1 ; v2(138.38,66.68) 138.07,66.38 137.77,66.38 PC1319.1 PC1320.1 PC1318.1 137.64,63.38 v2(137.03,62.77) ; PC1314.1 135.92,73.36 v2(136.53,72.75) 136.25,72.48 PC1311.1 ; v2(138.97,64.05) 138.97,64.04 138.79,64.22 PC1316.1
  IN4 w0.254: v2(140.69,69.27) 140.36,69.27 139.19,68.11 138.44,68.11 v2(138,68.54)
  BOTTOM w0.127: UCPU1.J27 136.2,68.18 136.2,68.18 ; UCPU1.J27 136.5,67.83 ; UCPU1.J27 135.89,67.83 ; UCPU1.J27 136.2,67.52 ; UCPU1.K25 137.57,67.67 ; UCPU1.K25 137.57,67.06 ; UCPU1.K25 137.87,67.36 ; 135.74,67.97 UCPU1.G28 136.07,68.29 ; 135.74,67.06 UCPU1.K28 ; UCPU1.K28 136.06,67.36 136.07,67.37 ; UCPU1.K28 135.74,67.67 ; 138.48,67.67 UCPU1.K23 ; UCPU1.K23 138.18,67.36 ; UCPU1.K23 138.82,67.36 138.84,67.34 ; UCPU1.K23 138.48,67.06 ; 134.83,67.67 UCPU1.K30 134.83,67.06 ; 136.54,67.09 136.65,67.2 UCPU1.K27 ; 138.94,67.53 UCPU1.J22 138.64,67.83 ; 136.35,67.36 UCPU1.K27 ; UCPU1.K27 136.65,67.67 ; UCPU1.J23 138.03,68.15 ; UCPU1.J23 138.03,67.53 ; UCPU1.J23 138.32,67.83 ; UCPU1.J23 137.67,67.83
  BOTTOM w0.203: UCPU1.G23 138.43,68.29 138.43,68.3 v2(138,68.54) 137.59,68.32 137.57,68.32 UCPU1.G25 UCPU1.G27
  BOTTOM w0.254: UCPU1.G27 v2(136.3,68.62) ; UCPU1.AK23 UCPU1.AK25 137.57,57.89 v2(137.65,57.97)
  vias: v2(76.07,60.65) v2(76.4,64.4) v2(76.68,60.64) v2(77.33,60.63) v2(78.12,64.19) v2(78.78,64.2) v2(78.84,63.61) v2(78.84,62.98) v2(78.84,62.34) v2(78.84,61.71) v3(77.11,62.8)
+VCCPLL_OC: length 34.6
  TOP w0.305: CC261.1 139.39,57.5 138.97,57.5 138.95,57.48 v2(138.91,57.48)
  IN4 w0.457: v2(159.52,45.74) 159.52,47.09 160.81,48.39 160.81,49.56 159.48,50.89 155.65,50.89 155.36,50.6 154.3,50.6 153.93,50.98 152.72,50.98 152.06,51.64 152.06,52.78 150.65,54.18 150.65,55.51 149.16,57 149.16,57.73 148.58,58.31 145.31,58.31 144.89,58.73 140.19,58.73 139.73,58.27 139.73,57.77 139.32,57.36 139.04,57.36 v2(138.91,57.48)
  BOTTOM w0.305: v2(138.91,57.48) 138.91,57.45 138.92,57.45 138.92,56.55 UCPU1.AL23
  vias: v3(158.73,46.26)
AGND: length 36.7
  TOP w0.127: v3(20.31,35.33) 20.31,34.1 20.99,33.42 CA109.2 ; v2(15.65,35.48) 16.57,35.48 v3(17.03,35.94) ; v3(15.26,21.88) 15.6,22.22 v2(15.6,22.95)
  TOP w0.203: CA110.1 21.76,25.17 22.15,25.56 25.25,25.56 25.86,26.17 UA2.38 ; UA2.25 24.46,32.03 24.46,32.03 v2(24.46,32.39)
  TOP w0.254: QA1.4 18.77,27.58 19.05,27.3 19.05,26.55 v2(19.03,26.53)
  TOP w0.381: CA68.1 6.71,22.77 v2(6.71,23.83) ; v2(17.16,32) 16.46,32 QA3.1
  TOP w0.457: v2(20.3,21.87) 19.93,22.23 QA9.3
  TOP w0.508: v2(15.65,35.48) 15.79,35.34 CA40.2 ; v2(16.69,24.88) 16.69,25.64 QA1.1 ; QA3.4 v2(14.27,30.19) ; v2(22.54,24.08) 21.77,24.85 CA110.1 ; CA107.1 27.08,36.22 v2(26.69,35.82) ; CA82.2 24.23,22.79 v2(24.03,22.59) ; v2(14.26,28.79) 14.83,28.79 CA74.2 ; CA80.2 25.38,22.95 v2(24.99,22.56) ; v2(19.15,30.44) 19.68,29.92 QA6.3
  BOTTOM w0.203: v2(24.97,33.56) 24.97,33.13 25.55,32.55 JPA1.1
  BOTTOM w0.381: RA60.2 16.36,28.23 14.82,28.23 v2(14.26,28.79) ; v2(20.57,31.57) 20.63,31.52 21.17,31.52 CA103.2 ; v2(19.03,26.53) 19.61,26.53 RA61.2
  BOTTOM w0.508: CA101.2 22.91,24.08 v2(22.54,24.08) ; CA102.2 v2(21.64,32.85) ; CA29.1 19.69,22.86 20.04,22.5 20.04,22.12 v2(20.3,21.87) ; CA69.2 15.29,23.25 v2(15.6,22.95) ; RA30.2 19.15,30.74 v2(19.15,30.44) ; RA35.2 14.49,32.17 v2(14.22,31.89) ; RA20.2 v2(14.26,29.42)
  vias: v2(6.2,21.29) v2(20.57,30.91) v2(20.8,22.44) v2(21.44,23.07)
GND: length 2697.7
  TOP w0.127: v3(83.83,16.49) v2(84.54,16.49) ; RT187.2 RT188.2 17.74,63.86 v2(17.63,63.75) ; UT1.A22 UT1.B22 UT1.C22 ; v2(36.96,62.35) 36.96,62.36 UT1.A16 ; 116.43,34.01 116.43,33.74 116.79,33.38 116.79,33.21 116.66,33.07 116.66,32.79 116.81,32.64 116.81,32.58 UD20.D12
  TOP w0.152: v2(43.42,54.91) UT1.P1 UT1.P2 ; UT1.G22 UT1.G23 40.2,65.58 40.2,65.82 40.03,65.99 v2(40.03,66.06) ; 44.34,55.46 UT1.T1 ; 44.34,55.46 44.34,55.92 UT1.T2 ; 44.34,55.46 44.34,55.35 44.14,55.14 v2(44.14,54.91) ; 37.9,55.46 UT1.B2 38.28,56.3 38.93,56.3 UT1.E4 ; 37.9,55.46 UT1.B1 ; 37.9,55.46 UT1.B1 ; UT1.AC2 UT1.AC1 ; 38.36,65.12 UT1.C22 38.36,65.12 ; 38.36,65.12 UT1.C23 38.36,65.66 v2(37.85,66.18) ; UT1.AB6 UT1.AC6 48.01,57.76 v2(48.13,57.63) ; v2(42.96,66.14) 42.96,65.58 UT1.N23 UT1.N22 ; UT1.W23 45.72,65.58 45.72,65.96 v2(46.03,66.26) ; UT1.AC12 UT1.AB12 ; v2(37.7,54.95) 37.7,55.26 UT1.B1 ; UT1.AB18 UT1.AC18 47.56,63.28 48.01,63.28 v2(48.18,63.1) ; 47.1,55.46 47.1,55.32 v2(47.45,54.97) ; 47.1,55.46 UT1.AB2 ; 47.1,55.46 UT1.AB1 ; UT1.AB22 UT1.AC22 47.73,65.12 v2(48.01,65.39) ; v2(41.38,66.13) 41.38,65.95 41.12,65.69 UT1.J23 41.12,65.12 UT1.J22 ; v2(36.28,60.87) 36.28,60.88 36.35,60.82 36.83,60.82 37.09,61.08 37.09,61.28 37.25,61.44 UT1.A14 UT1.B14 ; UT1.R23 43.88,65.58 43.88,65.12 ; 47.56,58.68 UT1.AC8 ; 47.56,58.68 47.1,58.68 UT1.AB8 ; 47.56,58.68 48.01,58.68 v2(48.17,58.51) ; UT1.A18 37.44,63.28 v2(36.8,63.28) ; v2(39.22,66.09) 39.28,66.04 39.28,65.58 ; UT1.Y20 45.72,65.1 UT1.W22 ; 166.03,31.48 167.05,31.48 167.29,31.25 167.99,31.25 PU600.4 ; 40.66,55.46 UT1.H1 ; 40.66,55.46 UT1.H2 ; 40.66,55.46 40.66,55.1 v2(40.91,54.85) ; 39.28,65.58 UT1.E23 ; 39.28,65.58 39.28,65.12 ; v2(48.06,64.23) 48.03,64.2 47.56,64.2 UT1.AC20 UT1.AB20 ; UT1.M2 UT1.M1 42.5,55.03 42.36,54.89 v2(42.36,54.89) ; 39.28,65.12 UT1.E22 ; 39.28,65.12 39.28,65.12 ; v2(48.18,59.55) 48.13,59.6 47.56,59.6 UT1.AC10 UT1.AB10 ; UT1.B20 37.9,64.2 37.44,64.2 ; UT1.U23 UT1.U22 ; 37.44,64.2 37.44,64.2 v2(36.91,64.2) ; 37.44,64.2 UT1.A20 ; UT1.AB14 UT1.AC14 47.97,61.44 48.17,61.23 v2(48.17,61.29) ; v2(36.86,58.68) 36.86,58.68 UT1.A8 ; v2(42.04,66.13) UT1.L23 UT1.L22 ; 43.88,65.12 43.88,64.5 UT1.R20 ; 43.88,65.12 UT1.R22 ; v2(48.25,62.21) 48.14,62.21 47.99,62.36 47.56,62.36 UT1.AC16 47.56,62.36 47.1,62.36 UT1.AB16 ; v2(36.92,57.96) 37.12,57.76 UT1.A6 ; UT1.A10 37.44,59.6 36.96,59.6 v2(36.93,59.62) ; v2(41.5,54.92) 41.5,54.96 41.58,55.03 UT1.K1 UT1.K2 ; UT1.A12 UT1.B12 ; UT1.AA23 UT1.AA22
  TOP w0.203: D76.2 v2(10.9,62.42) ; UT1.AA22 46.64,64.66 UT1.Y20 46.39,64.42 v2(46.06,64.09) ; UT1.B6 38.44,57.76 UT1.D6 38.6,57.92 v2(38.93,57.59) ; v2(13.06,66.7) 13.06,66.32 13.31,66.06 D87.2 ; UT1.V16 45.42,62.79 v2(45.42,62.79) 45.75,63.12 UT1.W18 ; v2(38.93,57.59) 39.25,57.27 UT1.E5 ; v2(38.93,57.59) UT1.E6 ; v2(38.93,57.59) UT1.D5 ; v2(45.43,58.24) 45.75,57.92 UT1.W6 ; U722.G8 U722.H8 22.13,60.97 22.01,60.85 v2(22.01,60.46) ; UT1.L5 v2(42.17,57.59) 42.5,57.27 UT1.M5 ; UT1.A1 37.09,55.11 v2(37.09,54.95) ; UT1.N9 43.15,59.22 v2(42.82,58.89) ; JXDP1.31 71.1,74.25 70.94,74.4 v2(70.94,74.96) ; UT1.T6 44.45,57.92 v2(44.77,58.24) ; UT1.R18 v2(44.13,62.79) 44.32,62.98 44.32,62.98 UT1.T18 v2(44.78,62.79) ; UT1.E15 39.25,61.82 v2(38.92,61.49) UT1.D15 ; UT1.H15 40.87,61.49 v2(40.87,61.49) UT1.J15 ; UT1.R5 43.8,57.27 v2(43.47,57.59) UT1.N5 ; D75.2 v2(10.9,64.91) ; v2(32.94,40.01) 33.12,40.19 33.12,40.84 U664.11 ; 39.28,65.12 39.28,65.04 UT1.F20 ; U719.11 U719.15 ; UT1.D11 v2(38.92,60.19) 39.25,59.87 UT1.E11 ; UT1.W20 45.74,64.42 v2(45.43,64.11) 45.12,64.42 UT1.V20 44.8,64.72 UT1.U22 ; v2(37.01,44.26) 36.93,44.18 U720.11 ; v2(38.29,62.14) 38.3,62.14 38.08,62.36 UT1.B16 ; UT1.B18 38.48,63.28 38.6,63.15 UT1.D18 v2(38.93,62.79) ; PU600.15 171.7,30.8 v2(171.81,30.69) ; UT1.D8 38.6,58.57 v2(38.93,58.89) 39.25,58.57 UT1.E8 ; UT1.D16 v2(38.93,62.14) ; UT1.AB12 47.01,60.52 46.73,60.23 46.73,59.97 UT1.AB10 ; UT1.M11 UT1.M12 v2(42.82,60.84) UT1.N12 UT1.N11 ; UT1.F16 39.9,62.47 39.88,62.47 39.58,62.16 v2(39.58,62.14) 39.58,62.11 39.25,62.44 UT1.E16 ; v2(169.49,39.73) 169.22,40.01 PU900.8 ; PU1305.4 64.47,61.68 64.47,61.25 v2(64.82,60.89) ; v2(13.01,61.55) 12.95,61.5 D82.2 ; UT1.H12 40.55,60.52 v2(40.22,60.84) UT1.H13 ; UT1.B12 UT1.D12 38.6,60.52 v2(38.93,60.84) UT1.D13 ; UT1.L13 41.85,61.16 v2(41.53,60.84) ; UT1.T5 44.53,57.35 45.02,57.35 UT1.V5 45.1,57.27 v2(45.43,57.59) UT1.W5 ; v2(41.52,61.49) UT1.L15 ; UT1.J13 41.2,61.17 v2(40.87,60.84) 41.2,60.52 UT1.J12 ; UT1.N15 43.15,61.8 42.84,61.49 42.84,61.5 42.83,61.51 42.82,61.5 v2(42.82,61.49) 42.84,61.51 43.15,61.2 UT1.N13 ; UT1.F6 v2(39.58,57.59) UT1.F5 ; UT1.V9 v2(44.78,58.89) UT1.T9 ; v2(13.53,58.01) 13.53,58.01 13.21,58.33 12.96,58.33 D83.2 ; U716.11 U716.15 171.3,17.26 v2(171.3,17.26) ; UT1.A10 UT1.B10 38.22,59.6 UT1.D9 38.6,59.22 v2(38.92,59.54) 39.25,59.22 UT1.E9 ; UT1.Y13 46.67,61.44 UT1.AB14 ; v2(39.57,59.54) 39.9,59.22 UT1.F9 ; UT1.J5 41.06,57.12 40.69,57.12 UT1.H5 40.55,57.27 ; v2(47.45,54.97) 47.56,55.09 UT1.AC1 ; D78.2 9.41,60.12 arc(9.46,60.11) 9.5,60.08 9.65,59.93 v2(9.65,59.9) ; UT1.B8 38.07,58.68 v2(38.29,58.89) ; PJP300.2 41.76,31.68 42.19,32.11 43.36,32.11 v2(43.36,32.11) ; UT1.W13 UT1.V15 v2(44.78,62.14) UT1.T16 ; UT1.J18 v2(40.87,62.79) 40.87,62.79 UT1.H16 ; UT1.Y9 46.3,59.32 45.85,59.32 UT1.W9 ; v2(179.68,30.66) 179.68,31.45 U717.11 ; UT1.T20 UT1.R20 ; 168.22,40.65 PU900.6
  TOP w0.254: U722.L1 20.6,64.88 v2(20.57,64.88) ; UD21.M4 140.52,25.73 140.53,25.73 140.68,25.57 v2(140.68,25.5) ; 152.02,26.7 UD22.F5 ; 152.02,26.7 152.02,26.78 v2(151.7,27.1) ; 152.02,26.7 152.02,25.9 UD22.F4 151.37,25.9 ; JXDP1.49 66.6,73.05 66.6,71.85 67.18,71.27 v2(67.18,71) ; v2(191.55,43.58) 191.55,44.53 191.41,44.66 C135.2 ; UD22.P3 157.22,25.18 v2(156.9,25.5) 156.9,25.57 UD22.N4 ; UD20.M12 122.29,32.3 122.29,32.61 v2(122.12,32.77) ; v2(132.51,60.16) 132.51,60.55 PC1205.2 ; v2(135.64,33.05) 135.59,33 135.59,32.93 135.15,32.49 135.15,32.3 UD21.D12 ; v2(184.17,46.85) 184.17,47.24 183.91,47.51 U15.32 ; v2(74.7,65.49) 74.1,66.09 JXDP1.20 ; v2(16.37,58.07) 16.59,58.07 16.93,58.42 16.93,59.36 17.39,59.81 C618.2 ; UD22.E5 151.37,26.78 v2(151.7,27.1) ; v2(154.3,25.5) 154.3,25.57 UD22.J4 ; UD22.R5 157.87,26.7 157.87,26.63 v2(158.2,26.3) 158.52,26.62 158.52,26.7 UD22.T5 ; JUSBC1.A12 7.82,58.04 8.23,57.63 v2(8.23,56.78) ; UD21.P12 141.65,32.3 141.65,33.03 v2(141.66,33.04) ; v2(157.55,28.7) 157.55,28.77 UD22.P8 ; UD20.M6 122.29,27.43 v2(122.62,27.1) ; U15.16 187.41,43.13 187.17,43.37 v2(187.17,43.8) ; v2(103.2,27.1) 103.52,27.43 UD19.G6 ; UT1.W8 45.75,58.57 v2(45.43,58.89) ; PC1271.2 100.69,67.65 PC1245.2 100.81,68.28 PC1270.2 PC1273.2 ; v2(122.62,27.1) 122.62,27.02 UD20.N5 122.62,26.38 v2(122.62,26.3) 122.94,25.98 UD20.N4 ; v2(122.62,27.1) 122.94,27.43 UD20.N6 ; v2(123.27,25.5) 123.59,25.18 UD20.P3 ; UT1.L20 v2(42.17,64.09) UT1.M19 ; v2(140.68,27.1) 140.35,27.43 UD21.M6 ; v2(140.68,27.1) 141,26.78 UD21.N5 141,26.63 v2(140.68,26.3) 140.9,26.08 140.9,26 UD21.N4 141.33,25.57 v2(141.33,25.5) 141.65,25.18 141.65,25.1 UD21.P3 ; v2(140.68,27.1) 140.68,27.15 141,27.47 141,27.5 UD21.N6 ; PU800.8 174.04,73.41 v2(174.73,73.41) ; UD22.C6 149.75,27.18 v2(149.75,27.1) 149.73,27.08 150.07,26.74 UD22.C5 ; RT40.1 32.58,55.57 32.5,55.49 v2(32.5,55.45) ; UT1.R19 v2(43.47,64.09) UT1.R20 ; UD20.H10 119.69,30.62 119.04,29.97 UD20.G9 119.04,29.84 119.22,29.66 119.22,29.28 UD20.G8 119.04,29.03 v2(118.72,28.7) ; UT1.V6 45.1,57.92 v2(44.77,58.24) 44.45,58.57 UT1.T8 ; UD21.G3 UD21.G4 137.1,25.97 v2(137.43,26.3) ; v2(134.37,57.21) 134.37,57.24 134.39,57.26 CC181.2 ; UD22.K10 154.62,30.48 155.2,29.9 UD22.L9 155.27,29.82 v2(154.95,29.5) 155.27,29.18 UD22.L8 ; UD21.K10 139.33,30.42 139.7,30.05 UD21.L9 139.7,29.82 v2(139.38,29.5) 139.7,29.18 UD21.L8 ; v2(118.07,26.3) 117.74,25.98 UD20.E4 ; v2(118.07,26.3) 118.39,25.98 UD20.F4 ; v2(118.07,26.3) 118.07,26.38 UD20.F5 118.07,27.02 v2(118.07,27.1) ; UD19.E5 102.22,26.78 v2(102.55,27.1) ; v2(103.2,25.5) 103.52,25.82 UD19.G4 ; UD22.T3 158.52,25.03 v2(158.2,24.7) 158.52,24.38 UD22.T2 ; UD22.E6 151.37,27.5 151.37,27.43 v2(151.7,27.1) ; UE5.B54 179.61,59.28 179.63,59.3 v2(179.63,59.31) ; v2(102.55,27.1) 102.55,27.2 102.85,27.5 UD19.F6 ; v2(102.55,27.1) 102.87,26.78 UD19.F5 102.87,26.63 v2(102.55,26.3) ; v2(102.55,27.1) 102.22,27.43 UD19.E6 ; UD20.C6 116.44,27.43 v2(116.12,27.1) 116.12,27.02 UD20.C5 ; v2(118.07,27.1) 117.74,27.43 UD20.E6 ; v2(118.07,27.1) 118.39,27.43 UD20.F6 UD20.G6 ; v2(118.07,27.1) 117.74,26.78 UD20.E5 ; UD19.M5 106.82,26.7 107.1,26.43 v2(107.1,26.28) 107.42,26.61 UD19.N5 ; v2(185.35,59.28) 185.35,59.18 185.61,58.92 185.61,58.67 UE5.B66 ; U15.23 188.21,46.57 187.47,46.57 187.22,46.82 v2(187.22,46.85) ; v2(143.28,32.7) 142.95,32.37 142.95,32.3 UD21.T12 ; 67.16,65.87 67.09,65.94 66.93,65.94 66.6,66.28 66.6,67.33 JXDP1.50 ; UD20.J4 120.43,25.82 120.43,25.74 v2(120.67,25.5) ; UD21.B5 133.53,27.02 v2(133.53,27.1) 133.53,27.18 UD21.B6 ; v2(69.72,65.41) 69.72,65.54 70.1,65.92 70.82,65.92 71.1,66.2 JXDP1.32 ; v2(101.25,28.66) 101.25,28.74 101.57,29.07 UD19.D8 ; UD22.D8 150.4,28.78 v2(150.4,28.7) ; UT1.J8 41.2,58.57 v2(40.87,58.89) 40.55,58.57 UT1.H8 ; RC141.2 134.67,73.68 CC22.2 134.67,74.13 YC1.4 133.96,75.09 134.66,75.79 134.66,77.62 134.48,77.8 131.74,77.8 131.51,77.57 131.51,76.79 YC1.2 130.69,75.98 130.2,75.49 CC21.2 130.2,73.44 130.21,73.43 130.21,72.92 132.01,71.12 v2(132.01,70.83) 131.93,70.83 131.17,70.06 131.17,69.55 131.67,69.05 v2(131.67,68.55) ; UD21.D8 135.15,28.83 v2(134.94,28.62) ; UE5.B11 187.21,64.27 186.38,64.27 v2(186.39,64.28) ; UD19.B12 100.27,32.4 99.97,32.7 v2(99.95,32.7) ; v2(138.89,23.77) 139.05,23.93 UD21.K2 ; UD22.T4 158.21,25.59 v2(158.21,25.5) ; v2(76.35,65.52) 77.1,66.26 JXDP1.8 ; UZ25.5 154.17,76.33 153.95,76.11 v2(153.92,76.11) ; UD22.H10 153.32,30.62 152.94,30.24 152.94,30.17 UD22.G9 152.67,29.9 152.67,29.98 v2(152.35,30.3) ; CC209.2 139.74,61.4 v2(139.74,61.4) ; v2(123.92,26.29) 123.92,26.22 UD20.R4 ; UD20.F12 118.39,32.37 118.88,32.86 v2(119.13,32.86) ; v2(37.05,47.76) 36.93,47.65 RT49.1 ; UD21.M12 140.35,32.3 140.35,32.84 v2(140.42,32.91) ; v2(151.7,27.1) 152.02,27.43 152.02,27.5 UD22.F6 ; UD20.G3 119.04,25.1 119.04,25.9 UD20.G4 119.04,25.98 v2(119.37,26.3) ; v2(119.67,22.89) 119.61,22.95 119.61,24.22 UD20.H2 ; UD22.R6 157.87,27.5 157.87,27.43 v2(158.2,27.1) 158.52,27.42 158.52,27.5 UD22.T6 ; UD21.F5 136.45,26.78 v2(136.13,27.1) ; JXDP1.19 74.1,71.91 v2(74.5,71.51) 75.08,70.93 75.67,70.93 75.97,71.23 75.97,71.61 75.6,71.98 JXDP1.13 ; JXDP1.7 77.1,71.76 v2(77.34,71.51) ; UD22.B5 149.42,26.78 v2(149.1,27.1) 149.1,27.18 UD22.B6 ; v2(45.43,58.89) 45.1,58.57 UT1.V8 ; v2(45.43,58.89) 45.75,59.21 UT1.W9 ; v2(136.78,30.3) 137.1,29.98 137.1,29.9 UD21.G9 137.75,30.55 UD21.H10 ; v2(131.29,60.16) 131.29,60.6 PC1204.2 ; v2(68.12,71) 68.78,71.66 69.29,71.66 69.6,71.97 JXDP1.37 ; v2(79.02,65.15) 78.6,65.58 JXDP1.2 ; UD22.J12 154.06,32.39 v2(154.06,32.84) ; v2(8.28,64.23) 7.59,63.54 JUSBC1.A1 ; UD21.G8 136.78,28.78 v2(136.78,28.7) 136.78,27.82 UD21.G6 ; UD22.K2 154.62,23.75 v2(154.62,23.74) ; v2(105.97,28.58) 105.97,28.95 UD19.L8 UD19.L9 105.76,30.26 105.76,30.41 UD19.K10 ; UZ22.5 161.82,48.51 v2(161.42,48.51) ; CD159.2 116.38,34.95 116.38,34.07 116.43,34.01 ; UD20.R5 124.24,26.63 v2(124.57,26.3) 124.89,26.62 124.89,26.7 UD20.T5 ; UD19.P3 108.07,25.17 v2(108.4,25.5) 108.72,25.82 UD19.R4 ; UD20.J12 120.34,32.66 v2(120.58,32.9) ; UD22.G8 152.67,29.02 v2(152.35,28.7) 152.35,28.38 152.67,28.06 152.67,27.5 UD22.G6 ; UD19.D12 101.45,32.42 101.45,33.03 101,33.48 v2(100.89,33.48) ; 134.5,25.1 134.5,25.12 134.18,25.45 v2(134.18,25.5) ; 134.5,25.1 UD21.C3 ; 134.5,25.1 UD21.D3 ; v2(157.55,25.5) 157.87,25.82 UD22.R4 ; v2(70.94,74.96) 71.42,74.48 72.39,74.48 72.6,74.27 JXDP1.25 ; UD21.P8 141.65,29.1 141.65,28.63 v2(141.69,28.59) ; v2(155.6,27.1) 155.6,27.13 155.92,27.46 UD22.M6 UD22.N6 156.57,27.5 156.57,27.43 v2(156.9,27.1) ; v2(155.6,27.1) 155.27,27.43 UD22.L6 ; v2(155.6,27.1) 155.92,26.78 UD22.M5 ; 151.37,25.9 151.37,25.95 151.05,26.28 v2(151.05,26.3) ; 151.37,25.9 UD22.E4 ; v2(137.7,23.77) 137.75,23.82 UD21.H2 ; UD20.R6 124.24,27.43 v2(124.57,27.1) 124.57,27.18 UD20.T6 ; v2(132.56,64.45) 132.56,64.16 PC1206.2 ; UD20.K2 121.21,24.08 121.21,23.58 v2(121.19,23.57) ; v2(106.45,26.3) 106.45,26.22 UD19.M4 106.77,25.83 v2(107.1,25.51) 107.42,25.83 UD19.N4 ; PC1290.2 100.69,67.01 v2(100.81,67.14) ; v2(23.2,55.08) 23.65,55.52 R1468.2 ; UD21.T2 142.95,24.38 v2(142.63,24.7) 142.95,25.03 UD21.T3 ; UD21.M5 140.21,26.84 140.03,27.02 v2(140.03,27.1) 140.03,27.17 UD21.L6 ; UT1.T13 44.45,61.17 v2(44.13,61.49) 44.45,61.81 UT1.T15 ; v2(124.57,25.5) 124.57,25.58 UD20.T4 ; v2(138.46,32.94) 138.4,32.88 138.4,32.3 UD21.J12 ; v2(123.92,28.7) 123.59,29.03 UD20.P8 ; v2(149.75,24.7) 149.42,24.38 UD22.B2 ; UD20.K10 120.99,30.55 UD20.L9 UD20.L8 121.64,29.03 v2(121.32,28.7) ; v2(134.18,24.7) 133.85,24.38 UD21.B2 ; UD22.M4 155.92,25.98 v2(155.6,26.3) ; UD21.T4 142.95,25.82 v2(142.63,25.5) 142.3,25.83 UD21.R4 ; UD20.B12 115.79,32.39 v2(115.48,32.7) ; PC1207.2 131.32,64.13 v2(131.32,64.47) ; v2(122.62,25.5) 122.62,25.57 UD20.M4 121.96,26.23 v2(121.96,26.32) 122.29,26.64 UD20.M5 122,26.99 122,27.14 UD20.L6 ; JXDP1.14 75.6,65.75 v2(75.34,65.49) ; D79.2 v2(10.2,59.17) ; UD20.T2 124.89,24.38 v2(124.57,24.7) 124.89,25.03 UD20.T3 ; U722.L11 21.01,59.35 v2(20.75,59.09) ; UD20.B6 115.76,27.5 115.47,27.2 v2(115.47,27.1) 115.79,26.78 UD20.B5 ; UD20.B2 115.79,24.38 v2(116.12,24.7) ; RH129.1 153.52,53.17 152.88,53.81 RH139.1 ; v2(136.13,27.1) 135.8,27.43 UD21.E6 ; v2(136.13,27.1) 135.8,26.78 UD21.E5 ; v2(136.13,27.1) 136.45,27.43 UD21.F6 ; v2(102.87,32.96) 102.87,32.96 102.87,32.3 UD19.F12 ; PC1277.2 PC1343.2 118.85,66.58 PC1287.2 119.86,66.58 v2(120.5,65.95) ; v2(109.7,32.7) 109.37,32.37 109.37,32.37 UD19.T12 ; UD19.T5 109.37,26.63 v2(109.05,26.31) ; v2(157.21,57.16) 157.21,57.25 156.59,57.87 RH146.1 ; UD21.R5 142.3,26.63 v2(142.63,26.3) 142.95,26.63 UD21.T5 ; UD19.T4 109.37,25.82 v2(109.05,25.5) ; CZ82.2 161.72,67.73 162.15,68.16 163.05,68.16 UZ19.5 ; v2(152.13,32.81) 152.02,32.71 152.02,32.3 UD22.F12 ; v2(106.84,32.81) 106.77,32.74 106.77,32.3 UD19.M12 ; 172.92,72.71 v2(172.93,72.7) ; v2(184.29,43.86) 183.91,43.48 U15.9 ; C1279.2 15.53,62.28 D77.2 v2(15.01,62.78) ; UD22.G3 152.35,25.42 v2(152.35,25.5) 152.35,25.56 152.67,25.88 UD22.G4 ; UD21.F4 136.45,25.98 v2(136.13,26.3) 135.8,25.98 UD21.E4 ; UD21.T6 142.95,27.43 v2(142.63,27.1) 142.3,27.43 UD21.R6 ; v2(128.75,60.16) 128.75,60.6 PC1202.2 ; PR290.2 53.63,58.19 52.84,58.19 v2(52.78,58.12) ; v2(23.82,48.69) 23.82,48.84 24.22,49.23 US2.1 ; UD22.D12 150.3,32.72 v2(150.3,32.75) ; v2(42.82,58.89) 43.15,58.57 UT1.N8 ; UD21.C5 134.49,26.7 134.18,27.01 v2(134.18,27.1) 134.18,27.19 134.49,27.5 UD21.C6 ; PC1209.2 128.88,64.03 v2(128.88,64.47) ; JXDP1.59 64.1,74.49 v2(63.7,74.89) ; UD21.B12 133.85,32.38 v2(133.53,32.7) ; v2(88.75,69.14) 88.75,68.87 PQ218.1 ; PU1401.16 199.25,76.22 199.25,76.98 199.28,77.01 199.25,77.03 199.28,77.06 199.25,77.09 199.25,77.11 199.28,77.14 v2(199.19,77.22) ; U722.A1 26.39,64.86 v2(26.39,65.24) ; UD22.C3 150.07,25.1 150.07,25.18 v2(150.4,25.5) 150.72,25.18 UD22.D3 ; UD22.H2 153.32,23.75 v2(153.32,23.74) ; v2(157.28,32.94) 157.22,32.88 157.22,32.3 UD22.P12 ; UD22.M12 155.92,32.3 155.92,32.47 v2(156.22,32.76) ; UD19.P12 108.07,32.3 108.07,32.54 v2(108.34,32.81) ; UD19.H10 104.17,30.62 103.87,30.32 v2(103.85,30.32) 103.52,29.99 UD19.G9 ; v2(149.1,32.7) 149.42,32.38 149.42,32.3 UD22.B12 ; UD19.N6 107.42,27.43 v2(107.1,27.11) 106.77,27.44 UD19.M6 106.61,27.34 106.61,27.33 106.44,27.16 v2(106.44,27.12) 106.12,27.44 UD19.L6 ; v2(102.55,26.3) 102.87,25.98 UD19.F4 ; v2(102.55,26.3) 102.22,25.98 UD19.E4 ; UE5.B60 182.61,58.9 182.8,59.09 182.8,59.65 182.6,59.85 v2(182.49,59.85) ; UT1.H20 UT1.J20 UT1.J19 v2(40.87,63.44) ; v2(138.73,26.3) 138.4,25.97 UD21.J4 ; UD20.D3 117.09,25.18 v2(116.77,25.5) 116.44,25.17 UD20.C3 ; UD22.N5 156.57,26.7 156.57,26.63 v2(156.9,26.3) ; UD22.T12 158.52,32.3 158.52,32.37 v2(158.85,32.7) ; JXDP1.26 72.6,68.74 v2(72.24,69.1) ; UD20.D8 116.77,28.78 v2(116.77,28.7) ; PC1203.2 130.02,60.6 v2(130.02,60.16) ; 40.55,57.27 v2(40.23,57.59) ; UT1.N20 42.83,64.09 v2(42.82,64.09) UT1.M20 ; D80.2 v2(10.2,56.65) ; JXDP1.38 69.6,66.08 69.16,65.64 69.16,65.49 v2(69.09,65.41) ; CC217.2 141.1,58.07 v2(141.07,58.05)
  TOP w0.305: UD19.J4 104.82,25.82 v2(104.5,25.5) ; v2(138.96,68.59) 139.24,68.31 PC1324.2 ; v2(42.44,37.58) 42.44,37.69 CT47.2 ; C96.2 191.16,46.06 v2(191.49,45.73) ; UD19.C3 100.92,25.27 101.15,25.5 v2(101.25,25.5) 101.32,25.5 101.57,25.25 UD19.D3 ; UD19.G3 103.2,25.42 v2(103.2,25.5) ; v2(55.67,56.92) 54.82,56.08 PQ206.4 ; PC1300.2 127.48,68.23 v2(127.1,68.62) ; v2(120.63,68.54) 120.63,68.33 120.85,68.11 PC1339.2 ; UD19.F6 103.17,27.21 103.17,27.13 v2(103.2,27.1) ; U699.3 24.85,54.89 24.73,55.01 v2(23.79,55.01) ; R1405.2 41.15,52.38 v2(41.18,52.35) ; v2(118.78,68.55) 118.63,68.4 PC1338.2 ; v2(125.22,32.7) 124.89,32.37 124.89,32.3 UD20.T12 ; UD19.C5 100.72,26.9 100.72,26.91 100.6,27.03 v2(100.6,27.1) 100.6,27.18 100.71,27.29 UD19.C6 ; PC1291.2 132.94,56.93 132.6,57.27 v2(132.54,57.27) ; RT44.1 v2(33.81,57.62) ; PC1279.2 122.2,56.27 121.57,56.9 v2(121.57,57.42) ; v2(59.16,79.59) 59.07,79.5 UZ26.5 ; UD21.F12 136.6,32.45 136.6,32.73 v2(136.66,32.79) ; v2(109.05,26.31) 108.72,26.64 UD19.R5 ; PC1327.2 135.47,69.31 135.2,69.05 135.2,68.62 v2(135.21,68.62) ; v2(120.66,55.71) 120.37,56 PC1278.2 ; v2(41.58,44.12) 41.58,45.65 41.1,46.14 C1216.2 ; v2(50.5,67.12) 50.09,67.52 CT93.2 CT94.2 ; C1354.2 21.95,67.29 v2(21.84,67.4) ; PC1097.2 65.08,65.06 65.89,64.25 ; v2(47.92,52.12) 47.92,51.59 UZ23.5 ; UD19.P8 108.07,29.03 v2(108.4,28.7) ; v2(126.19,55.71) 126.21,55.73 PC1281.2 PC1283.2 ; v2(103.76,28.33) 103.76,28.36 103.52,28.59 103.52,29.1 UD19.G8 ; UD19.H2 104.17,23.77 v2(104.17,23.77) ; v2(179.93,47.68) 180.13,47.68 C97.2 ; v2(163.68,69.22) 163.87,69.03 164.38,69.03 UC9.3 ; CT62.2 49.38,52.59 v2(49.1,52.31) 48.74,52.66 R1403.2 ; v2(105.47,23.77) 105.47,24.3 UD19.K2 ; v2(136.11,57.3) 136.2,57.22 136.2,57.22 136.58,56.84 CC182.2 ; PC1275.2 129.34,68.08 v2(129.8,68.54) ; UD19.T6 109.22,27.34 109.21,27.34 109.05,27.18 109.05,27.17 ; v2(104.88,32.86) 104.82,32.8 104.82,32.3 UD19.J12 ; CT74.2 CT84.2 CT83.2 34.38,59.44 v2(33.77,59.44) ; PC1322.2 137.69,59.01 137.49,59.22 137.49,59.17 v2(137.49,59.17) ; UD20.P12 123.59,32.3 123.59,33.03 v2(123.6,33.04) ; PC1284.2 126.59,68.18 v2(126.19,68.59) PC1341.2 ; v2(119.76,57.35) 119.76,57.24 119.74,57.21 119.74,56.65 119.37,56.29 119.12,56.29 PC1282.2 ; UD19.B6 100.09,27.32 99.95,27.18 v2(99.95,27.1) 99.95,27.03 100.1,26.88 100.1,26.87 UD19.B5 ; v2(40.42,51.93) 40.42,51.97 40.44,51.98 RT39.1 ; UD19.R6 108.9,27.32 108.9,27.32 109.05,27.17 ; UD19.B2 100.46,24.49 100.6,24.63 v2(100.6,24.7) ; UD19.T3 UD19.T2 109.37,24.27 v2(108.9,23.8) ; v2(136.93,66.91) 137.06,67.04 PC1325.2 ; PC1301.2 134.14,56.6 CC185.2 134.33,57.17 v2(134.37,57.21) ; CT71.2 CT81.2 ; v2(38.95,52.36) 39.04,52.45 RT3.1 ; v2(162.83,60.42) 162.44,60.04 UC7.3 ; 109.05,27.17 v2(109.05,27.1) ; v2(50.95,52.31) 51.28,52.64 CT64.2 CT66.2 ; v2(124.38,68.59) 123.93,68.13 PC1340.2 123.7,68.11 123.42,67.83 123.42,66.99 123.9,66.51 PC1286.2 ; PC407.2 165.8,58.46 PU400.4 ; v2(127.97,55.63) 128.04,55.71 CC186.2 127.39,56.22 PC1285.2 ; v2(202.75,58.88) UC8.3 ; v2(143.03,58.07) 143.03,58.45 CC268.2 ; PC1280.2 123.44,56.27 123.23,56.48 123.23,57.22 v2(123.34,57.34) ; CC177.2 138.58,50.58 139.45,49.72 RC5.2 ; RT45.1 v2(33.86,56.98) ; CT57.2 33.89,58.25 v2(33.84,58.2) ; v2(42.36,54.18) 42.77,53.77 RT2.1 ; v2(50.27,52.26) 50.01,52.51 CT63.2 CT65.2 ; UE5.B18 186.61,67.87 186.61,68.13 186.97,68.49 186.97,68.98 v2(187.16,69.17)
  TOP w0.32: CC258.2 127.38,51.95 v2(126.85,51.43) ; v2(160.81,32.24) 160.81,32.03 161.09,31.75 CD144.2 ; CC259.2 137.31,51.95 v2(136.79,51.43) 136.29,51.43 136.09,51.62 135.64,51.62 CC256.2 ; CC257.2 131.67,51.56 v2(131.81,51.43)
  TOP w0.356: CC261.2 139.64,56.94 140.12,57.43 CC125.2 140.49,57.94 v2(140.41,58.01) ; CT102.2 50.48,55.33 v2(50.51,55.37) ; CT102.2 CT103.2 RT4.1 ; CT102.2 CT101.2 50.2,54.29 v2(50.6,54.29) ; CT67.2 CT68.2 52.25,55 v2(52.66,55.41) ; RT37.1 44.93,52.65 44.55,52.27 v2(44.55,52.19) RT38.1 ; CT50.2 46.71,50.81 v2(46.3,50.4) RT43.1 ; PQ217.1 53.26,70.17 52.52,69.43 v2(52.52,69.17) ; PC1021.1 66.9,47.91 v2(66.51,47.52) 66.9,47.12 PC1095.1
  TOP w0.381: v2(32.11,62.98) 32.11,62.63 32.36,62.38 RT50.1 RT48.1 ; v2(61.69,74.91) 61.22,75.38 C1204.2 ; PQ209.1 21.07,73.05 v2(21.44,73.41) ; RC85.1 162.44,58.68 162.44,59.77 ; v2(147.78,29.42) 147.5,29.7 CD87.2 ; v2(112.45,60.28) 112.45,59.83 PC1226.2 ; v2(141.68,67.93) 141.02,67.27 RC166.2 ; CZ92.2 158.47,73.16 158.01,72.7 157.81,72.7 157.36,72.25 156.69,72.25 UC12.3 ; v2(189.76,72.88) 189.76,73.15 QE12.4 ; v2(51.28,23.07) 50.78,23.07 50.32,22.61 C1199.2 ; CC24.2 147.22,47.28 v2(147.78,47.28) 148.39,47.28 CC25.2 ; PQ216.1 51.6,68.05 51.35,67.79 v2(51.08,67.79) ; v2(148.08,28.1) 147.17,28.1 146.86,27.8 CD165.2 ; v2(27.23,65.26) 27.25,65.24 CT152.2 ; v2(130.71,57.26) 130.71,57.17 131.09,56.79 PC1303.2 131.09,56.18 PC1292.2 ; PC1244.2 105.28,67.48 v2(105.28,67.17) ; PC1244.2 PC1232.2 ; PC1244.2 106.2,67.79 v2(106.2,67.17) 106.02,66.99 PC1247.2 ; v2(149.74,61.72) 149.85,61.62 151.11,61.62 151.59,61.13 RC44.2 ; v2(86.77,24.85) 86.77,24.62 87.55,23.83 PC510.2 ; QE13.1 158.58,36.71 v2(158.41,36.53) ; 61.07,48.87 PQ208.4 ; 61.07,48.87 60.96,48.87 60.91,48.81 60.64,48.81 60.31,48.48 PR282.2 ; 61.07,48.87 61.55,48.87 v2(61.71,48.71) ; PR273.2 55.91,17.48 v2(55.37,16.95) 55.73,16.6 PC216.2 ; v2(32.47,67.13) 32.47,66.37 CT97.2 ; v2(104.67,67.12) 104.75,67.04 PC1252.2 ; v2(201.22,42.25) 201.54,41.93 UZ24.2 ; CD164.2 112.45,24.32 v2(113.46,23.3) ; v2(59.1,16.51) 58.18,16.51 PU203.4 ; CC224.2 144.12,55.97 v2(144.37,55.72) ; CT80.2 CT72.2 42.81,67.23 43.16,66.89 v2(43.16,66.76) ; PC1350.2 110.96,58.97 v2(110.71,58.72) ; PC1408.2 179.16,49.64 v2(179.31,49.79) 179.15,49.95 179.15,50.76 PC1402.2 ; PC212.2 84.43,69.86 v2(84.12,69.56) ; PQ219.4 63.74,21.94 63.98,22.18 v2(64.21,22.18) ; v2(58.94,65.1) 58.96,65.1 59.43,64.63 PQ215.1 ; PQ218.4 90.33,66.57 90.45,66.46 v2(90.45,66.33) ; PC1208.2 130.1,64.08 v2(130.1,64.45) ; CZ87.2 168.62,66 169.16,66.54 v2(169.16,66.69) 169.74,67.27 CE42.2 ; v2(88.37,33.21) 89.11,33.21 PC1506.2 ; v2(48.67,22.87) 48.64,22.89 C1200.2 ; PC1291.2 132.94,56.18 PC1305.2 ; v2(172.84,56.51) 172.51,56.84 PU402.3 ; v2(187.7,41.09) 187.7,41.03 187.2,40.52 C95.2 ; QE13.4 159.88,39.14 159.88,39.76 159.74,39.9 v2(159.74,40.47) ; v2(33.1,66.94) 33.3,67.14 CT43.2 33.81,66.53 CT96.2 ; CT144.2 24.81,67.26 v2(25.24,66.83) ; CE46.2 169.1,61.52 168.73,61.52 168.58,61.36 ; v2(171.44,59.6) 171.4,59.65 RE85.2 ; v2(37.01,27.95) 36.7,27.95 CA23.1 ; v2(57.51,39.58) 57.51,41.23 56.16,42.58 RE101.2 ; RE103.2 198.86,54.64 198.86,56.22 198.21,56.87 198.21,57.49 UC13.3 ; CD145.2 CD29.2 111.81,31.86 111.35,32.32 v2(110.69,32.32) ; PR406.2 168.68,63.59 v2(168.76,63.66) ; CT52.2 34.69,56 34.66,56.04 v2(34.66,56.06) ; v2(191.8,17.41) 192,17.61 C1321.2 ; CC179.2 121.86,49.22 CC260.2 ; v2(64.12,57.76) 64.12,57.23 63.58,56.69 PR1121.2 ; PC1252.2 PC1251.2 ; PC1252.2 PC1247.2 ; PC1251.2 103.48,66.49 103.46,66.51 103.46,67.12 v2(103.47,67.13) 103.47,67.64 103.92,68.09 PC1243.2 ; PC1251.2 PC1250.2 102.21,66.51 102.29,66.59 v2(102.29,67.12) 102.29,67.75 PC1242.2 ; v2(185.9,50.33) 186.28,50.33 R60.2 ; 162.44,59.77 UC7.3 162.44,59.77 ; v2(52.46,71.15) 52.14,71.47 PQ217.4 ; RT164.1 38.16,67.94 37.77,68.33 CT44.2 37.77,68.97 v2(37.46,69.28) ; v2(153.52,46.47) 153.04,45.99 CC23.2 ; RC114.2 118.74,68.59 v2(118.78,68.55) ; CT85.2 33.21,60.32 v2(32.89,60.64) ; U48.4 v2(204.28,26.45) ; v2(144.12,70.87) 143.98,70.87 RC3.2 ; PC1352.2 PC1217.2 108.62,66.06 PC1224.2 108.5,65.93 PC1246.2 PC1247.2 ; R1162.2 61.32,77.38 v2(61.71,77.77) 61.71,77.87 C1203.2 ; v2(135.31,67.14) 135.83,67.66 PC1326.2 ; v2(56.93,58.02) 56.49,57.58 PQ206.1 ; v2(33.12,73.36) 33.36,73.13 33.36,72.54 PQ207.4 ; PR301.2 35.89,22.11 35.23,21.45 v2(35.08,21.45) ; C1167.2 C1293.2 38.23,45.84 38.54,45.53 v2(38.54,45.16) ; v2(19.84,71.66) 19.77,71.6 PQ209.4 ; v2(142.4,62.24) 142.24,62.08 CC206.2 ; v2(143.68,66.46) 143.68,66.99 143.88,67.18 CC264.2 ; v2(115.85,60.23) 115.85,60.02 115.04,59.21 PC1351.2 116.48,59.14 CC187.2 ; v2(51.22,41.28) 53.64,41.28 54.1,41.73 UC11.3 ; PC606.2 173.84,28.91 v2(174.35,29.42) 173.97,29.8 PC607.2 ; C614.2 198.12,51.23 v2(198.16,51.27) ; v2(143.68,63.1) 143.68,62.71 CC265.2 ; PR269.2 83.31,72.22 82.58,71.48 82.5,71.48 v2(82.53,71.46) ; CD120.2 152.73,35.09 152.73,33.42 v2(152.13,32.81) ; v2(145.24,61.56) 145.24,61.89 145.72,62.37 CC267.2 ; PC1335.2 107.19,60.91 v2(107.19,61.1) ; v2(142.59,67.97) 142.59,67.94 142.98,67.55 CC203.2 ; PU201.4 90.45,74.55 v2(90.45,75.24) ; C1278.2 C355.2 47.21,19.41 v2(46.79,19.41) 46.61,19.59 45.97,19.59 C375.2 C377.2 ; C1229.2 180.09,19.92 v2(179.93,19.77) ; v2(37.58,13.66) 38.12,13.66 RE89.2 38.1,14.27 37.9,14.27 37.82,14.36 37.82,15.03 37.17,15.68 v3(37.17,15.88) 37.17,16.27 36.4,17.04 RE59.2 ; v2(56.06,69.25) 55.73,69.58 PC210.2 ; CT81.2 40.54,67.94 CT100.2 RT12.2 39.09,68.16 38.74,68.51 v2(38.37,68.51) ; v2(4.55,20.77) 5.93,20.77 6.17,20.53 7.09,20.53 v2(7.34,20.28) ; PC907.2 163.29,39.22 v2(163.29,38.78) 164.71,38.78 PR904.2 ; v2(46.3,50.4) 46.3,49.96 45.86,49.51 CZ90.2 ; C1226.2 182.18,19.58 182.37,19.58 v2(182.42,19.53) ; CD38.2 160.14,26.56 v2(160.11,26.53) ; v2(44.57,68.94) 44.17,69.33 CT99.2 ; v2(165.74,34.91) 165.74,33.99 PR608.2 ; 168.58,61.36 v2(168.58,61.5) ; 168.58,61.36 168.13,60.92 PR412.2 ; v2(148.15,31.6) 148.11,31.56 147.94,31.56 147.05,30.67 CD57.2 ; 169.71,56.97 169.89,56.97 v2(170.69,57.77) ; 169.71,56.97 PU401.3 ; 169.71,56.97 PQ400.4 ; v2(33.99,61.79) 34.14,61.65 34.14,61.38 CT86.2 CT91.2 CT92.2 ; CC211.2 146.61,65.54 v2(146.61,65.87) 146.28,66.2 RC1.1 ; CC195.2 v2(141.83,70.81) ; PC1317.2 139.46,59.86 PC1323.2 ; v2(150.67,56.41) 151.17,56.41 151.26,56.31 151.3,56.31 151.61,56 CC204.2 ; v2(113.64,26.78) 113.64,27.34 113.31,27.67 CD143.2 ; CD168.2 145.64,31.81 CD163.2 ; PC1342.2 117.2,67.83 v2(117.06,67.97) ; CC34.2 127.99,45.83 128.45,45.37 v2(128.65,45.37) ; v2(149.71,46.11) 149.89,45.93 CC26.2 ; C1223.2 68.43,79.38 v2(67.56,79.38) ; v2(129.21,25.76) 129.49,25.49 RD58.2 ; v2(55.6,35.06) 56.13,34.53 PQ223.4 ; v2(20.37,67.5) 20.42,67.45 C1345.2 ; PQ218.1 87.67,68.55 PC213.2 ; C1220.2 v2(54.5,78.28) ; v2(37.85,66.18) 35.75,66.18 35.7,66.23 CT98.2 CT95.2 ; RC219.1 74.65,77.65 v2(74.61,77.61) ; PC1245.2 101.07,67.8 101.52,67.35 v2(101.52,67.15) ; v2(85.57,34.37) 85.95,34.76 PR1507.2 ; C1347.2 22.14,56.22 v2(22.52,55.84) ; v2(157.3,59.01) 158.05,59.01 158.33,59.29 CC225.2 ; RT190.2 23.65,67.75 v2(23.65,67.75) ; PQ223.1 58.27,32.52 v3(60.71,30.08) 61.25,29.54 v2(61.25,29.55) ; QE12.1 188.1,74.76 v2(188.87,75.53) ; PC214.2 v2(61.49,14.39) ; RC139.1 v2(63.09,77.38) ; v2(184.24,41.4) 184.16,41.49 CA72.2 183.19,41.16 C98.2 ; v2(105.39,61.05) PC1248.2
  TOP w0.406: QE14.4 v2(35.38,33.93)
  TOP w0.508: v2(186.74,54.19) 187.07,53.86 CE53.2 ; v2(76.56,54.95) PC1132.1 ; CC271.2 155.92,46.11 v2(155.04,45.23) ; CD153.2 v2(95.58,23.73) ; CC179.2 121.02,48.98 v2(120.9,49.09) ; v2(94.95,42.81) 94.55,43.2 PC1505.2 ; PC1500.2 87.3,41.87 v2(87.07,42.1) ; PR215.2 20.64,77.3 v2(20.63,77.29) ; PC1415.2 PC1416.2 v2(191.87,74.63) ; v2(142.98,59.73) 142.98,60.13 143.26,60.41 CC205.2 ; v2(13.82,13.67) 14.12,13.98 CH95.2 ; CD178.2 v2(162.3,25.02) ; v2(64.24,46.06) PR1067.1 PC1020.1 ; PC1257.2 104.24,63.2 ; PC1257.2 104.98,63.18 v2(104.98,62.52) ; PC1257.2 PC1218.2 PC1258.2 ; 104.24,63.2 104.24,62.57 v2(104.24,62.56) ; 104.24,63.2 PC1332.2 PC1331.2 ; v2(25.3,52.12) 25.54,52.36 25.54,53.31 25.93,53.7 C1289.2 ; v2(95.76,31.35) 95.98,31.58 CD3.2 96.44,32.59 CD8.2 ; v2(152.27,37.79) 152.63,37.42 RD26.2 ; CD166.2 145.26,34.15 v2(143.05,34.15) ; v2(170.33,52.16) PC1403.2 ; v2(111,62.52) 111,62.85 PC1225.2 PC1228.2 ; RC65.2 161.01,64.12 161.39,64.5 162.33,64.5 163.81,63.03 v2(163.81,62.65) ; v2(191.44,33.46) 191.85,33.87 C6.2 C1145.2 ; v2(62.84,55.79) 63.04,55.58 PR1094.2 ; 101.07,60.28 v2(101.07,61.1) ; C1341.2 v2(29.97,61.17) ; v2(139.61,63.18) 140.16,63.73 CC218.2 ; v2(101.24,63.92) 101.07,64.09 101.07,64.73 PC1235.2 PC1211.2 ; PC1419.2 195.2,70.49 v2(195.2,70.06) ; CC280.2 CC279.2 158.28,41.32 v2(158.34,41.26) ; CD92.2 95.93,26.35 96.29,25.99 CD146.2 RD53.2 95.93,24.39 v2(95.61,24.39) ; v2(24.97,42.71) 24.22,42.71 23.53,43.39 UT6.9 ; CMOS1.2 149.05,42.4 v2(149.5,41.94) ; v2(174.73,63.28) 174.4,62.95 CE44.2 174.12,62.98 RE58.1 ; v2(73.1,51.16) 73.33,51.39 PR1126.1 ; RE68.2 174.12,68.79 v2(173.91,69) ; v2(180.72,54.44) 180.11,54.44 CE41.2 ; v2(61.44,39.84) PC524.2 ; PC204.2 92.58,74.63 93.09,75.14 v2(93.09,75.35) ; PC1210.2 98.31,73.1 PC1230.2 98.3,73.97 v2(98.43,74.1) ; RH153.2 146.96,55.85 v2(147.17,55.64) ; v2(173.79,45.09) 173.97,45.27 PR1425.2 PC1411.2 PR1406.2 ; CD167.2 135.33,34.74 v2(135.38,34.68) ; C1199.2 50.32,22.11 50.9,21.52 U719.15 50.9,17.91 C1201.2 50.52,17.87 v2(50.32,18.07) ; C1164.2 176.89,32.67 177.04,32.52 C1158.2 177.52,32.17 v2(177.78,31.91) ; PC1418.2 v2(204.52,75.78) ; C1159.2 166.9,17.69 v2(166.85,17.74) 167.36,18.25 PC612.2 ; v2(50.5,45.91) 50.37,45.78 C1298.2 C713.2 ; CA106.2 31.17,35.54 v2(30.79,35.92) ; CA27.1 v2(34.62,29.17) ; v2(34.8,31.94) 34.65,32.09 CA24.1 ; v2(69.75,21.27) 69.75,21.45 69.27,21.93 PD101.1 ; v2(111.1,30.11) 111.51,29.7 CD150.2 CD161.2 ; CD160.2 128.37,21.67 v2(128.7,22.01) ; CC217.2 141.25,58.91 CC223.2 ; SW2.3 v2(188.82,76.11) ; v2(142.57,34.68) 142.21,35.04 CD30.2 142.08,35.41 CD176.2 ; CA35.2 113.27,73.19 v2(113.45,73) ; v2(174.35,31.84) 174.31,31.84 173.68,32.47 PR605.2 ; PC1354.2 112.67,63.2 v2(112.45,62.98) ; C1254.2 v2(170.1,15.3) ; PR247.2 50.72,69.2 50.5,68.97 50.5,68.44 RT1.1 50.59,68.28 v2(51.08,67.79) ; v2(133.89,46.68) 134.09,46.88 CC31.2 ; RH557.2 159.44,80.17 CZ88.2 CZ84.2 159.44,78.14 159.16,77.86 v2(159.16,77.61) ; RC293.1 R1216.2 22.76,52.31 21.67,51.22 21.67,51.01 v2(21.64,51.01) ; CD133.2 100.13,16.77 101.07,15.83 v3(101.07,15.3) v2(101.07,14.09) ; v2(111.25,34.42) 111.65,34.02 CD148.2 CD155.2 ; v2(139.66,60.69) 139.66,60.48 139.42,60.23 PC1317.2 ; v2(47.45,44.61) 47.45,45.02 47.73,45.3 ; CD132.2 107.19,16.93 v2(107.77,16.93) ; CA5.2 37.66,27.5 37.2,27.95 v2(37.01,27.95) ; R1188.1 178.91,37.82 178.41,37.32 v2(178.41,37.02) ; v2(47.35,80.48) 47.35,79.38 JAR1.5 46.58,79.67 v2(46.58,80.48) ; v2(166.83,47.2) 166.8,47.18 CZ89.2 ; PR106.2 29.97,72.02 v2(30.39,71.6) ; v2(141.71,48.9) 141.33,49.28 RC7.2 ; CC28.2 66.85,76.82 CC33.2 ; CC28.2 CC269.2 ; CC28.2 67.79,77 v2(67.36,77.43) ; C1102.1 166.17,14.72 v2(166.19,14.69) ; PC905.2 171.81,38.34 v2(172.49,37.65) ; v2(108.97,36.86) 108.89,36.78 CD86.2 107.89,35.54 CD37.2 ; RC86.1 119.48,78.57 v2(119.1,78.19) ; CE21.2 187.58,50.61 v2(187.3,50.33) ; CC202.2 139.36,65.97 v2(139.69,65.64) ; PC616.2 165.27,31.59 PC614.2 ; v2(136.5,75.02) 135.93,75.02 135.67,74.76 ; CD139.2 v2(140.31,16.77) ; CD63.2 130.2,33.91 v2(129.77,33.49) 129.34,33.91 CD7.2 ; v2(107.75,62.52) 107.75,63 PC1258.2 ; CE62.2 v2(183.36,53.55) ; CA54.1 CA56.1 29.49,19.21 v2(29.9,18.8) ; R7.2 CA33.2 28.33,38.08 v2(28.68,37.74) ; v2(160.17,45.6) 160.66,46.08 CZ83.2 ; PR1407.2 v2(175.84,47.81) ; PR709.2 204.24,62.32 204.65,61.91 v2(204.65,61.65) ; v2(166.4,50.1) 166.45,50.15 166.45,50.86 PC1404.2 ; CD60.2 158.85,36.09 v2(158.41,36.53) ; PC806.2 PC804.2 PC803.2 177.56,76.14 177.65,76.23 177.65,76.89 v2(177.66,76.89) ; R1175.1 v2(167.97,14.18) ; RH129.1 153.57,52.16 152.96,52.16 v2(152.86,52.05) ; v2(165.08,58.41) 165.11,58.44 PC407.2 ; CD135.2 v2(119.1,16.77) ; v2(129.17,26.41) 128.85,26.41 128.6,26.16 128.6,26.16 128.33,25.89 CD42.2 127.96,24.9 CD154.2 ; C722.2 174.27,27.36 v2(174.3,27.39) 174.27,27.42 C720.2 ; CD129.2 v2(146.91,16.77) ; CD196.2 158.65,16.54 v2(159.37,16.54) ; QE14.1 34.18,36.11 C1218.2 34.67,36.2 35.9,37.44 36.59,37.44 v2(36.78,37.63) 36.81,37.65 R1186.1 C1166.2 ; CC220.2 145.95,70.37 v2(145.7,70.12) ; v2(163.83,18.51) 163.88,18.56 PC611.2 PC613.2 ; v2(30.53,45.4) 30.53,45.58 30.86,45.91 C715.2 C1297.2 ; PR1502.2 87.07,42.76 v2(86.92,42.91) ; v2(182.78,72.53) 182.78,72.32 183.11,71.99 CE14.2 CE63.2 ; v2(81.64,32.88) 81.64,32.15 PC1513.2 ; v2(203.73,77.07) 203.87,76.92 PC1413.2 ; v2(149.05,68.59) 148.95,68.49 RC312.1 RC242.1 ; v2(180.7,32.47) 180.87,32.65 C1162.2 ; PC604.2 173.25,22.74 v2(173.58,22.41) ; v2(44.04,40.19) 44.07,40.22 UT5.9 ; v2(28.85,18.25) 28.6,17.99 DA4.1 ; v2(144.26,51.4) 144.5,51.16 CC270.2 CC213.2 ; C1213.2 33.3,45.25 C712.2 v2(33.12,46.11) ; PR606.2 173.74,33.36 173.92,33.17 v2(174.22,33.17) ; v2(174.14,13.98) 174.07,14.06 172.31,14.06 ; v2(168.07,49.82) 168,49.74 PC1410.2 ; v2(32.11,25.69) 32.33,25.46 33.07,25.46 CA4.2 ; YT1.4 33.54,70.15 v2(34.42,69.27) 35.24,68.45 YT1.2 ; RT5.2 50.67,66.13 v2(50.93,65.87) ; R1468.2 24.36,56.83 C1348.2 ; PC1212.2 PC1216.2 v2(95.86,73.95) ; RE91.2 196.72,48.6 196.98,48.35 v2(197.33,48.35) ; v2(100.76,62.54) 100.76,62.9 PC1256.2 PC1331.2 ; v2(129.33,51.43) 129.26,51.36 CC175.2 129.03,50.15 CC194.2 ; RC227.2 159.13,70.72 v3(158.28,69.88) 158.27,69.86 v2(157.2,69.86) ; RC90.2 111.2,67.78 v2(110.92,68.06) ; v2(177.11,69.45) 177.11,69.48 177.06,69.53 CE61.2 ; RC91.2 113.71,66.4 113.59,66.4 113.18,66 PC1353.2 112.88,66.67 v2(112.95,66.74) ; v2(109.73,62.52) 109.73,62.85 PC1228.2 ; v2(170.59,37.4) 170.28,37.7 PC906.2 ; C1169.2 v2(30.28,41.79) ; CE13.2 184.89,71.89 185.22,72.22 v2(185.22,72.53) ; v2(34.6,30.21) 33.99,30.21 CA30.1 ; v2(125.3,46.21) 124.76,46.21 124.59,46.38 CC35.2 ; v2(66.29,20) 66.29,20.15 66.68,20.53 PD100.1 ; v2(114.33,65.72) 114.61,66 PC1227.2 ; CD172.2 155.47,36.28 155.96,36.76 v2(155.98,36.76) ; C1212.2 C1214.2 v2(31.45,37.58) ; C1168.2 198.07,38.59 198.07,37.27 v2(198.1,37.25) ; v2(47.98,16.21) 47.55,16.65 C352.2 ; RC109.1 107.34,71.51 H16.1 ; PC1331.2 102.16,62.9 v2(102.16,62.54) ; CD197.2 96.29,21.34 RD51.2 v2(95.64,22.84) ; PC1511.2 87.73,34.45 v2(87.5,34.22) ; v2(172.45,69.97) 172.44,69.98 PR804.2 ; RD116.2 v2(156.82,39.2) ; RD115.2 102.44,40.09 v2(101.85,40.09) ; RC20.2 152.02,58.05 152.02,58.42 v2(152.46,58.86) 152.61,58.71 CC272.2 153.77,59.52 v2(153.73,59.56) ; v2(136.84,33.63) 137.17,33.96 137.17,35.1 CD119.2 ; v2(28.36,43.21) 28.37,43.21 28.78,43.62 RE90.2 ; CD168.2 147.45,32.83 v2(148.23,33.61) 149.8,35.18 CD59.2 CD179.2 ; C1280.2 v2(14.03,56.33) ; C1275.2 74.11,38.69 PC314.2 ; v2(194.62,22.95) 195.3,22.26 C1324.2 ; v2(144.63,41.74) 144.37,42 RC75.1 143.97,41.97 RC220.2 ; RE77.2 CE55.2 v2(186.03,72.53) ; PC1414.2 v2(203.71,78.13) ; PC903.2 PC904.2 172.44,42.66 v2(173.03,42.66) ; v2(70.64,60.71) PC1134.2 ; CD174.2 CD175.2 130.65,31.07 130.02,31.07 130.01,31.07 129.8,31.07 v2(129.75,31.12) 129.13,31.12 128.49,31.75 CD158.2 ; C1304.2 C721.2 175.21,42.55 v2(175.26,42.6) ; v2(30.46,73.75) 30.46,73.47 30.82,73.1 PQ101.3 ; PC1316.2 140.08,64.75 v2(139.49,64.75) ; CE49.2 v2(189.84,51.62) ; v2(188.47,19.08) 188.52,19.03 C1225.2 ; PC1315.2 137.14,70.71 v2(136.99,70.86) ; v2(177.65,77.66) 177.75,77.56 PC805.2 ; v2(35.08,21.45) 35.28,21.24 RE22.1 RE23.1 ; RC7.2 RC89.2 RC88.2 ; RC7.2 RC6.2 RC5.2 ; PC1229.2 114.63,63.2 v2(114.4,62.98) ; PC1228.2 PC1334.2 PC1258.2 ; CD182.2 130.12,23.32 RD57.2 129.41,24.22 v2(129.25,24.05) ; CC176.2 CC178.2 134.34,51.37 v2(134.29,51.43) ; CD61.2 CD87.2 ; PC102.1 v2(69.88,18.17) ; v2(84.37,75.09) 84.37,74.55 84.43,74.48 PC211.2 PR268.2 ; PC1311.2 138.51,71.71 CC199.2 138.79,71.38 v2(139.36,70.81) ; v2(180.34,74.79) 180.44,74.68 CE52.2 ; v2(73.06,49.13) PC1084.2 ; v2(34.6,27.77) 34.21,27.39 CA25.1 ; v2(22.28,27.15) 22.23,27.1 CA78.2 ; PR219.2 32.36,76.44 v2(32.36,78.57) ; PC1240.2 PC1236.2 v2(98.27,65.41) ; C2.2 27.41,51.98 v2(28.61,51.98) ; v2(161.09,34.5) 161.46,34.13 CD169.2 ; RD25.2 102.44,38.57 v2(101.93,38.57) ; CD140.2 v3(152.26,16.77) v2(150.98,16.77) ; RD19.2 102.29,42.6 RD112.2 102.31,42.22 v2(101.98,41.9) ; PR271.2 PC215.2 64.95,18.88 v2(65.02,18.96) ; CE17.2 181.81,54.87 v2(181.36,54.42) ; v2(95.2,29.06) CD4.2 95.99,29.12 CD147.2 ; v2(169.01,72.88) 169.49,73.36 PC802.2 169.82,73.41 v2(169.06,74.18) ; v2(132.36,27.97) 132.28,27.9 CD90.2 ; RA41.2 18.03,19.59 v2(18.03,18.8) ; R540.2 MC3.2 191.97,28.66 v2(191.36,28.66) ; v2(105.64,19.11) 105.77,19.23 CD149.2 ; R1187.1 181.08,36.41 v2(181.33,36.66) ; v2(146.08,52.31) 146.79,51.6 CC214.2 ; C1161.2 v2(179.93,26.88) ; RC96.2 CC267.2 ; PQ219.1 v2(61.76,19.84) ; v2(19.26,46.25) 19.26,47.48 19.62,47.84 C1346.2 ; v2(173.97,24.62) 173.97,25.55 C719.2 ; CA31.2 CA42.2 34.01,25.08 v2(33.73,24.8) ; CC177.2 138.53,51.01 138.94,51.42 v2(139.29,51.42) ; R545.2 v2(191.24,29.42) ; v2(153.62,80.48) 153.24,80.1 CZ85.2 ; v2(124.45,51.43) 124.56,51.32 CC174.2 ; CZ82.2 162.28,67.52 v2(162.38,67.62) ; v2(204.22,17.79) 204.82,18.39 Q71.3 ; PC807.2 169.44,80.03 v2(168.83,80.03) ; v2(62.87,50.24) 62.33,50.77 PC1006.1 ; DA3.1 v2(19.41,15.96) ; PC1417.2 v2(204.65,74.81) ; v2(116.99,34.1) 117.14,34.24 CD1.2 CD159.2 ; PC1249.2 99.67,58.66 v2(99.14,58.12) ; R1161.2 207.06,19.47 v2(207.37,19.77) ; CD173.2 133.17,34.67 133.48,34.36 v2(133.48,34.38) ; CZ86.2 RZ75.2 v2(169.09,67.78) ; PC205.2 PR230.2 v2(92.94,72.73) ; v2(97.13,73.95) 97.08,73.9 PC1233.2 ; MD10.1 v2(184.86,14.56) ; C1217.2 v2(28.87,40.42) ; v2(173.97,80.04) PC800.2 ; v2(27.64,55.61) 27.28,55.97 C1349.2 C1350.2 ; PC900.2 v2(170.56,44.31) ; v2(125.22,34.18) 124.53,34.87 CD6.2 124.04,35.54 123.91,35.41 CD5.2 ; v2(35.06,73.93) 34.66,74.33 PQ207.1 ; v2(83.92,31.84) 83.62,31.53 PC1517.2 ; RC122.2 78.33,77.05 77.67,77.71 v2(77.67,77.94) ; PR1108.2 v2(77.32,58.76) ; v2(25.29,39.57) 24.41,40.44 UT6.4 ; CD157.2 129.77,29.85 v2(129.77,29.85) ; CD136.2 v2(133.83,16.77) ; CZ92.2 157.66,73.47 v2(157.02,72.83) ; RE63.2 CE64.2 183.24,54.34 v2(183.36,54.21) ; PC406.2 PR412.2 ; PQ220.3 60.23,21.18 59.82,21.6 59.82,23 v4(59.92,23.1) ; CD33.2 101.44,35.41 v2(102.19,36.16) 102.51,35.84 CD152.2 ; CA53.1 24.87,18.55 v2(24.71,18.4) ; RE54.1 181.23,71.84 CE40.2 181.2,72.37 v2(181.36,72.53) 181.33,72.55 RE78.2 ; RE103.2 200.95,54.5 201.65,55.2 v2(201.65,55.97) ; v2(167.23,53.22) 167.23,53.22 PC1405.2 ; v2(20.37,67.5) 20.99,67.5 21.21,67.28 R1472.1 ; CD162.2 145.3,24.7 v2(144.96,24.36) 144.96,24.35 145.77,23.53 CD91.2 ; CD118.2 119.3,35.94 v2(120.04,36.68) ; v2(62.6,78.63) C8.2 64.05,79.21 U728.2 ; C1325.2 v2(196.95,23.15) ; v2(191.9,72.09) PC1406.2 ; 102.46,60.28 v2(102.46,61.1) ; PR270.2 65.91,14.69 66.45,14.16 v2(66.45,13.78) ; CD151.2 v2(104.88,19.1) ; CD2.2 97.89,35.11 v2(98.87,34.14) ; PC1400.2 174.85,54.26 PR1402.2 175.62,54.59 v2(175.94,54.92) ; CZ78.2 v2(153.34,73.87) ; PC610.2 165.19,24.69 165.72,24.16 166.45,24.16 v2(166.48,24.19) ; PC1096.2 76.15,50.91 v2(76.62,50.44) ; v2(108.03,77.22) 108.26,77 108.68,77 RC112.1 RC110.1 110.4,76.93 RC113.1 ; C1211.2 v2(200.58,37.22) ; PR1417.2 v2(204.32,71.21) ; v2(48.62,48.68) 49.07,48.22 CZ91.2 ; C1292.2 v2(178.92,28.15) ; PC405.2 175.11,57.21 175.11,56.75 174.78,56.42 v2(174.68,56.42) 175.06,56.04 PR407.2 ; C2973.2 v2(12.93,9.74) ; CD180.2 v2(103.99,19.12) ; v2(166.5,24.85) 166.47,24.85 166.09,25.22 PC608.2 ; R1140.2 R290.1 55.04,19.26 v2(55.42,19.64) 55.55,19.52 PC217.2 ; MD9.1 v2(180.9,14.56) ; v2(171.48,35.7) 170.92,35.14 PC603.2 ; v2(175.18,20.81) 174.73,20.81 174.27,20.35 C1264.2 173.03,20.15 C1258.2 ; v2(116.84,18.27) 116.05,19.06 RD52.2 RD54.2 ; v2(103.95,34.59) 104.42,35.06 CD117.2 ; RE2.1 v2(171.76,66.51) ; 103.99,60.28 v2(103.99,61.1) ; RC163.2 v2(108.51,67.8) ; PC1103.2 v2(77.32,59.65) ; C7.2 v2(185.83,17.69) ; v2(146.67,18.65) 146.28,19.04 RD55.2 RD56.2 ; 180.06,44.54 179.43,44.54 v2(179.32,44.64) ; C1163.2 v2(179.93,28.09) ; CA55.1 22.33,19.26 v2(22.15,19.08) ; v2(39.22,37.63) 39.27,37.68 39.27,38.19 38.46,39 C1160.2 ; PR272.2 v2(57.51,13.75) ; v2(99.04,62.82) 98.59,62.82 PC1215.2 ; v2(204.57,73.87) PR1418.2 ; C1208.2 v2(59.16,79.59) ; v2(192.33,64.5) 191.75,65.08 CE45.2 191.39,64.88 CE38.2 ; v2(168.09,19.12) 168.74,19.77 C1257.2 ; v2(191.62,75.22) 191.75,75.35 SW2.1 ; C1215.2 v2(34.27,45.12) ; v2(76.43,55.84) PC1099.1 ; CD170.2 161.92,29.85 162.32,29.46 v2(162.33,29.47) 162.38,29.42 PC618.2 PR610.2 ; PC617.2 PR608.2 ; C1322.2 v2(196.85,14.21) ; PC1214.2 v2(98.34,60.92) ; R1027.1 v2(204.14,43.09) ; C1143.2 v2(195.02,32.79) ; C2983.2 v2(6.86,19.9) ; CT151.2 v2(19.66,67.89) ; RC167.2 v2(138.28,57.97) ; RE97.2 v2(200.1,57.57) ; v2(161.16,44.03) PC902.2 ; C1309.2 v2(16.82,13.75) ; CD142.2 v2(124.05,16.77)
  GND1 w0.203: 14.61,50.58 JUSB2.10 ; JUSB2.10 13.1,50.58 ; JUSB2.10 14.61,52.48 ; JUSB2.10 13.1,52.48 ; JUSB2.10 16.13,52.48 ; JUSB2.10 16.13,50.58 ; JUSB2.10 16.13,51.53 ; JUSB2.10 13.1,51.53 ; H18.1 53.96,12.24 ; H18.1 51.82,14.38 ; H18.1 52.89,11.87 ; H18.1 54.33,13.31 ; H18.1 51.45,13.31 ; H18.1 52.89,14.75 ; H18.1 53.96,14.38 ; H18.1 51.82,12.24 ; 5.73,63.98 JUSBC1.B12 ; JUSBC1.B12 6.6,63.59 ; JUSBC1.B12 6.12,63.11 ; JUSBC1.B12 6.51,63.2 ; H17.1 204.52,51.64 ; H17.1 203,48.04 ; H17.1 200.92,50.12 ; H17.1 205.08,50.12 ; H17.1 201.48,51.64 ; H17.1 203,52.2 ; H17.1 204.52,48.6 ; H17.1 201.48,48.6 ; JUSB2.11 16.13,37.78 ; JUSB2.11 14.61,37.78 ; JUSB2.11 13.1,37.78 ; JUSB2.11 14.61,39.68 ; JUSB2.11 16.13,38.73 ; JUSB2.11 13.1,38.73 ; JUSB2.11 13.1,39.68 ; JUSB2.11 16.13,39.68 ; 13.63,42.21 JUSB2.4 ; JUSB2.4 13.45,41.61 ; JUSB2.4 13.63,41.01 ; JUSB2.4 14.82,42.21 ; JUSB2.4 14.23,40.83 ; JUSB2.4 14.23,42.39 ; JUSB2.4 15,41.61 ; JUSB2.4 14.82,41.01 ; H19.1 111.48,13.31 ; H19.1 110.04,14.75 ; H19.1 108.6,13.31 ; H19.1 108.97,14.38 ; H19.1 111.11,12.24 ; H19.1 108.97,12.24 ; H19.1 110.04,11.87 ; H19.1 111.11,14.38 ; 38.98,73.82 H11.1 ; H11.1 42.58,72.3 ; H11.1 42.02,73.82 ; H11.1 40.5,74.38 ; H11.1 42.02,70.78 ; H11.1 40.5,70.22 ; H11.1 38.42,72.3 ; H11.1 38.98,70.78 ; SW3.4 2.54,18.79 ; SW3.4 1.45,19.88 ; SW3.4 2.54,19.88 ; SW3.4 2.7,19.33 ; SW3.4 2,18.63 ; SW3.4 2,20.03 ; SW3.4 1.45,18.79 ; H13.1 215.88,16.54 ; H13.1 216.25,15.47 ; H13.1 213.37,15.47 ; H13.1 214.81,16.91 ; H13.1 213.74,14.4 ; H13.1 215.88,14.4 ; H13.1 214.81,14.03 ; H13.1 213.74,16.54 ; 9.13,16.05 H12.1 ; H12.1 10.2,15.68 ; H12.1 11.27,18.19 ; H12.1 9.13,18.19 ; H12.1 10.2,18.56 ; H12.1 11.64,17.12 ; H12.1 11.27,16.05 ; H12.1 8.76,17.12 ; 161.28,76.37 H15.1 ; H15.1 161.28,73.33 ; H15.1 164.32,76.37 ; H15.1 162.8,76.93 ; H15.1 164.88,74.85 ; H15.1 162.8,72.77 ; H15.1 164.32,73.33 ; H15.1 160.72,74.85 ; 5.73,57.6 JUSBC1.B1 ; JUSBC1.B1 6.51,58.38 ; JUSBC1.B1 6.12,58.47 ; 4.14,56.19 JUSBC1.3 ; JUSBC1.3 5.37,56.91 ; JUSBC1.3 6.6,56.19 ; JUSBC1.3 4.14,56.91 ; JUSBC1.3 6.6,55.47 ; JUSBC1.3 4.14,55.47 ; JUSBC1.3 5.37,55.47 ; H10.1 164.32,55.37 ; H10.1 162.8,55.93 ; H10.1 162.8,51.77 ; H10.1 160.72,53.85 ; H10.1 161.28,55.37 ; H10.1 164.88,53.85 ; H10.1 164.32,52.33 ; H10.1 161.28,52.33 ; 12.13,45.71 JUSB2.7 ; JUSB2.7 12.72,45.89 ; JUSB2.7 13.32,45.71 ; JUSB2.7 12.72,44.33 ; JUSB2.7 12.13,44.51 ; JUSB2.7 13.5,45.11 ; JUSB2.7 11.95,45.11 ; JUSB2.7 13.32,44.51 ; 1.14,66.11 JUSBC1.1 ; JUSBC1.1 3.6,66.11 ; JUSBC1.1 2.37,64.67 ; JUSBC1.1 3.6,64.67 ; JUSBC1.1 3.6,65.39 ; JUSBC1.1 1.14,65.39 ; JUSBC1.1 1.14,64.67 ; JUSBC1.1 2.37,66.11 ; JUSB2.12 5.53,52.97 ; JUSB2.12 3.12,53.92 ; JUSB2.12 5.53,53.92 ; JUSB2.12 3.12,52.97 ; JUSB2.12 4.33,53.92 ; 186.68,24.64 H6.1 ; H6.1 189.72,21.6 ; H6.1 186.12,23.12 ; H6.1 189.72,24.64 ; H6.1 188.2,21.04 ; H6.1 188.2,25.2 ; H6.1 190.28,23.12 ; H6.1 186.68,21.6 ; SW3.3 2.54,22.84 ; SW3.3 2.7,23.38 ; SW3.3 2.54,23.93 ; SW3.3 1.45,22.84 ; SW3.3 2,22.68 ; 9.13,69.05 H1.1 ; H1.1 10.2,71.56 ; H1.1 11.27,69.05 ; H1.1 10.2,68.68 ; H1.1 11.64,70.12 ; H1.1 11.27,71.19 ; H1.1 9.13,71.19 ; H1.1 8.76,70.12 ; H9.1 184.26,79.8 ; H9.1 183.89,78.73 ; H9.1 182.82,81.24 ; H9.1 181.38,79.8 ; H9.1 181.75,78.73 ; H9.1 181.75,80.87 ; H9.1 182.82,78.36 ; H9.1 183.89,80.87 ; 102.48,52.33 H14.1 ; H14.1 101.92,53.85 ; H14.1 104,55.93 ; H14.1 105.52,55.37 ; H14.1 105.52,52.33 ; H14.1 102.48,55.37 ; H14.1 106.08,53.85 ; H14.1 104,51.77 ; H4.1 81.96,81.24 ; H4.1 80.89,78.73 ; H4.1 81.96,78.36 ; H4.1 80.89,80.87 ; H4.1 83.4,79.8 ; H4.1 80.52,79.8 ; H4.1 83.03,78.73 ; H4.1 83.03,80.87 ; JUSBC1.2 6.6,66.11 ; JUSBC1.2 6.6,65.39 ; JUSBC1.2 5.37,66.11 ; JUSBC1.2 5.37,64.67 ; JUSBC1.2 4.14,66.11 ; JUSBC1.2 4.14,64.67 ; JUSBC1.2 4.14,65.39 ; 1.14,56.19 JUSBC1.4 ; JUSBC1.4 1.14,55.47 ; JUSBC1.4 3.6,56.91 ; JUSBC1.4 3.6,55.47 ; JUSBC1.4 2.37,56.91 ; JUSBC1.4 1.14,56.91 ; JUSBC1.4 3.6,56.19 ; JUSBC1.4 2.37,55.47 ; JUSB2.13 5.53,37.27 ; JUSB2.13 5.53,37.75 ; JUSB2.13 5.53,36.79 ; 101.92,74.85 H16.1 ; H16.1 104,72.77 ; H16.1 102.48,73.33 ; H16.1 105.52,76.37 ; H16.1 105.52,73.33 ; H16.1 106.08,74.85 ; H16.1 102.48,76.37 ; H16.1 104,76.93 ; H7.1 130.16,14.35 ; H7.1 130.16,12.21 ; H7.1 129.09,14.72 ; H7.1 130.53,13.28 ; H7.1 128.02,12.21 ; H7.1 129.09,11.84 ; H7.1 128.02,14.35 ; H7.1 127.65,13.28
  GND2 w0.203: JUSB2.11 14.61,39.68 ; JUSB2.11 13.1,39.68 ; JUSB2.11 13.1,38.73 ; JUSB2.11 14.61,37.78 ; JUSB2.11 16.13,37.78 ; JUSB2.11 16.13,39.68 ; JUSB2.11 16.13,38.73 ; JUSB2.11 13.1,37.78 ; H1.1 11.27,69.05 ; H1.1 11.27,71.19 ; H1.1 9.13,69.05 ; H1.1 10.2,71.56 ; H1.1 9.13,71.19 ; H1.1 8.76,70.12 ; H1.1 11.64,70.12 ; H1.1 10.2,68.68 ; H19.1 111.11,14.38 ; H19.1 110.04,14.75 ; H19.1 108.97,14.38 ; H19.1 108.97,12.24 ; H19.1 111.48,13.31 ; H19.1 108.6,13.31 ; H19.1 110.04,11.87 ; H19.1 111.11,12.24 ; JUSB2.12 5.53,53.92 ; JUSB2.12 3.12,53.92 ; JUSB2.12 3.12,52.97 ; JUSB2.12 5.53,52.97 ; JUSB2.12 4.33,53.92 ; JUSBC1.B1 6.12,58.47 ; JUSBC1.B1 5.73,57.6 ; JUSBC1.B1 6.51,58.38 ; 10.2,15.68 H12.1 ; H12.1 9.13,16.05 ; H12.1 10.2,18.56 ; H12.1 8.76,17.12 ; H12.1 11.64,17.12 ; H12.1 11.27,16.05 ; H12.1 9.13,18.19 ; H12.1 11.27,18.19 ; H6.1 189.72,24.64 ; H6.1 186.12,23.12 ; H6.1 188.2,25.2 ; H6.1 188.2,21.04 ; H6.1 186.68,24.64 ; H6.1 190.28,23.12 ; H6.1 189.72,21.6 ; H6.1 186.68,21.6 ; H4.1 81.96,81.24 ; H4.1 81.96,78.36 ; H4.1 83.03,78.73 ; H4.1 80.89,80.87 ; H4.1 80.52,79.8 ; H4.1 83.4,79.8 ; H4.1 83.03,80.87 ; H4.1 80.89,78.73 ; 1.14,66.11 JUSBC1.1 ; JUSBC1.1 3.6,66.11 ; JUSBC1.1 3.6,65.39 ; JUSBC1.1 1.14,65.39 ; JUSBC1.1 3.6,64.67 ; JUSBC1.1 2.37,66.11 ; JUSBC1.1 2.37,64.67 ; JUSBC1.1 1.14,64.67 ; SW3.3 2.54,23.93 ; SW3.3 1.45,22.84 ; SW3.3 2,22.68 ; SW3.3 2.7,23.38 ; SW3.3 2.54,22.84 ; H17.1 204.52,48.6 ; H17.1 200.92,50.12 ; H17.1 204.52,51.64 ; H17.1 201.48,48.6 ; H17.1 203,52.2 ; H17.1 203,48.04 ; H17.1 205.08,50.12 ; H17.1 201.48,51.64 ; 214.81,14.03 H13.1 ; H13.1 215.88,14.4 ; H13.1 216.25,15.47 ; H13.1 215.88,16.54 ; H13.1 213.37,15.47 ; H13.1 214.81,16.91 ; H13.1 213.74,16.54 ; H13.1 213.74,14.4 ; 104,51.77 H14.1 ; H14.1 106.08,53.85 ; H14.1 102.48,55.37 ; H14.1 104,55.93 ; H14.1 105.52,52.33 ; H14.1 101.92,53.85 ; H14.1 102.48,52.33 ; H14.1 105.52,55.37 ; 12.13,44.51 JUSB2.7 ; JUSB2.7 13.5,45.11 ; JUSB2.7 12.13,45.71 ; JUSB2.7 13.32,44.51 ; JUSB2.7 12.72,45.89 ; JUSB2.7 13.32,45.71 ; JUSB2.7 12.72,44.33 ; JUSB2.7 11.95,45.11 ; 162.8,51.77 H10.1 ; H10.1 162.8,55.93 ; H10.1 164.32,55.37 ; H10.1 164.88,53.85 ; H10.1 161.28,52.33 ; H10.1 161.28,55.37 ; H10.1 164.32,52.33 ; H10.1 160.72,53.85 ; H15.1 164.32,76.37 ; H15.1 164.32,73.33 ; H15.1 162.8,72.77 ; H15.1 164.88,74.85 ; H15.1 161.28,73.33 ; H15.1 162.8,76.93 ; H15.1 161.28,76.37 ; H15.1 160.72,74.85 ; 4.14,56.91 JUSBC1.3 ; JUSBC1.3 6.6,55.47 ; JUSBC1.3 4.14,55.47 ; JUSBC1.3 5.37,55.47 ; JUSBC1.3 6.6,56.19 ; JUSBC1.3 4.14,56.19 ; JUSBC1.3 5.37,56.91 ; JUSBC1.4 3.6,56.91 ; JUSBC1.4 1.14,56.91 ; JUSBC1.4 2.37,55.47 ; JUSBC1.4 3.6,55.47 ; JUSBC1.4 1.14,56.19 ; JUSBC1.4 1.14,55.47 ; JUSBC1.4 3.6,56.19 ; JUSBC1.4 2.37,56.91 ; 127.65,13.28 H7.1 ; H7.1 128.02,12.21 ; H7.1 130.53,13.28 ; H7.1 129.09,11.84 ; H7.1 128.02,14.35 ; H7.1 129.09,14.72 ; H7.1 130.16,12.21 ; H7.1 130.16,14.35 ; 13.45,41.61 JUSB2.4 ; JUSB2.4 14.82,42.21 ; JUSB2.4 14.23,40.83 ; JUSB2.4 13.63,42.21 ; JUSB2.4 13.63,41.01 ; JUSB2.4 14.82,41.01 ; JUSB2.4 14.23,42.39 ; JUSB2.4 15,41.61 ; 181.75,78.73 H9.1 ; H9.1 183.89,80.87 ; H9.1 181.38,79.8 ; H9.1 181.75,80.87 ; H9.1 183.89,78.73 ; H9.1 182.82,81.24 ; H9.1 184.26,79.8 ; H9.1 182.82,78.36 ; JUSBC1.B12 6.51,63.2 ; JUSBC1.B12 6.6,63.59 ; JUSBC1.B12 5.73,63.98 ; JUSBC1.B12 6.12,63.11 ; 1.45,18.79 SW3.4 ; SW3.4 2.54,19.88 ; SW3.4 2.54,18.79 ; SW3.4 1.45,19.88 ; SW3.4 2.7,19.33 ; SW3.4 2,18.63 ; SW3.4 2,20.03 ; JUSBC1.2 6.6,66.11 ; JUSBC1.2 5.37,66.11 ; JUSBC1.2 6.6,65.39 ; JUSBC1.2 4.14,65.39 ; JUSBC1.2 4.14,64.67 ; JUSBC1.2 4.14,66.11 ; JUSBC1.2 5.37,64.67 ; JUSB2.13 5.53,37.27 ; JUSB2.13 5.53,36.79 ; JUSB2.13 5.53,37.75 ; 101.92,74.85 H16.1 ; H16.1 105.52,73.33 ; H16.1 105.52,76.37 ; H16.1 106.08,74.85 ; H16.1 102.48,76.37 ; H16.1 104,76.93 ; H16.1 102.48,73.33 ; H16.1 104,72.77 ; 51.82,12.24 H18.1 ; H18.1 53.96,14.38 ; H18.1 51.45,13.31 ; H18.1 54.33,13.31 ; H18.1 51.82,14.38 ; H18.1 52.89,11.87 ; H18.1 52.89,14.75 ; H18.1 53.96,12.24 ; H11.1 42.02,70.78 ; H11.1 40.5,74.38 ; H11.1 42.58,72.3 ; H11.1 38.98,70.78 ; H11.1 38.98,73.82 ; H11.1 38.42,72.3 ; H11.1 40.5,70.22 ; H11.1 42.02,73.82 ; 13.1,52.48 JUSB2.10 ; JUSB2.10 14.61,52.48 ; JUSB2.10 14.61,50.58 ; JUSB2.10 13.1,50.58 ; JUSB2.10 13.1,51.53 ; JUSB2.10 16.13,51.53 ; JUSB2.10 16.13,50.58 ; JUSB2.10 16.13,52.48
  VCC w0.203: JUSB2.7 13.5,45.11 ; JUSB2.7 13.32,44.51 ; JUSB2.7 13.32,45.71 ; 14.61,50.58 JUSB2.10 ; JUSB2.10 13.1,52.48 ; JUSB2.10 16.13,51.53 ; JUSB2.10 13.1,50.58 ; JUSB2.10 14.61,52.48 ; JUSB2.10 13.1,51.53 ; JUSB2.10 16.13,50.58 ; JUSB2.10 16.13,52.48 ; 4.14,66.11 JUSBC1.2 ; JUSBC1.2 4.14,64.67 ; JUSBC1.2 4.14,65.39 ; H14.1 106.08,53.85 ; H14.1 102.48,55.37 ; H14.1 104,55.93 ; H14.1 104,51.77 ; H14.1 102.48,52.33 ; H14.1 105.52,52.33 ; H14.1 101.92,53.85 ; H14.1 105.52,55.37 ; 13.1,37.78 JUSB2.11 ; JUSB2.11 14.61,39.68 ; JUSB2.11 16.13,39.68 ; JUSB2.11 13.1,39.68 ; JUSB2.11 13.1,38.73 ; JUSB2.11 16.13,38.73 ; JUSB2.11 16.13,37.78 ; JUSB2.11 14.61,37.78 ; 201.48,51.64 H17.1 ; H17.1 203,52.2 ; H17.1 204.52,51.64 ; H17.1 201.48,48.6 ; H17.1 204.52,48.6 ; H17.1 203,48.04 ; H17.1 200.92,50.12 ; JUSB2.4 14.23,42.39 ; JUSB2.4 13.45,41.61 ; JUSB2.4 14.82,41.01 ; JUSB2.4 14.82,42.21 ; JUSB2.4 14.23,40.83 ; JUSB2.4 15,41.61 ; JUSB2.4 13.63,42.21 ; JUSB2.4 13.63,41.01 ; 4.14,56.91 JUSBC1.3 ; JUSBC1.3 4.14,56.19 ; JUSBC1.3 5.37,56.91 ; JUSBC1.3 4.14,55.47 ; JUSBC1.3 5.37,55.47 ; JUSBC1.3 6.6,55.47 ; 5.61,36.64 4.96,36.64 4.32,37.27 3.69,36.64 3.02,36.64 ; 2.37,64.67 JUSBC1.1 ; JUSBC1.1 3.6,65.39 ; JUSBC1.1 3.6,64.67 ; 2.37,55.47 JUSBC1.4 ; JUSBC1.4 3.6,55.47 ; JUSBC1.4 3.6,56.19 ; JUSBC1.4 3.6,56.91 ; JUSBC1.4 2.37,56.91 ; JUSB2.12 4.33,53.92 ; JUSB2.12 3.12,53.92 ; JUSB2.12 5.53,53.92
  GND3 w0.203: 1.45,22.84 SW3.3 ; SW3.3 2.54,22.84 ; SW3.3 2,22.68 ; SW3.3 2.7,23.38 ; SW3.3 2.54,23.93 ; 38.42,72.3 H11.1 ; H11.1 42.58,72.3 ; H11.1 42.02,73.82 ; H11.1 38.98,70.78 ; H11.1 40.5,70.22 ; H11.1 42.02,70.78 ; H11.1 38.98,73.82 ; H11.1 40.5,74.38 ; 10.2,15.68 H12.1 ; H12.1 11.27,16.05 ; H12.1 10.2,18.56 ; H12.1 9.13,18.19 ; H12.1 11.64,17.12 ; H12.1 11.27,18.19 ; H12.1 9.13,16.05 ; H12.1 8.76,17.12 ; 14.23,40.83 JUSB2.4 ; JUSB2.4 14.82,41.01 ; JUSB2.4 15,41.61 ; JUSB2.4 13.63,42.21 ; JUSB2.4 13.45,41.61 ; JUSB2.4 14.23,42.39 ; JUSB2.4 13.63,41.01 ; JUSB2.4 14.82,42.21 ; 8.76,70.12 H1.1 ; H1.1 9.13,69.05 ; H1.1 10.2,71.56 ; H1.1 9.13,71.19 ; H1.1 11.27,71.19 ; H1.1 10.2,68.68 ; H1.1 11.64,70.12 ; H1.1 11.27,69.05 ; 1.14,56.19 JUSBC1.4 ; JUSBC1.4 2.37,56.91 ; JUSBC1.4 2.37,55.47 ; JUSBC1.4 3.6,56.19 ; JUSBC1.4 3.6,56.91 ; JUSBC1.4 1.14,56.91 ; JUSBC1.4 3.6,55.47 ; JUSBC1.4 1.14,55.47 ; 14.61,50.58 JUSB2.10 ; JUSB2.10 13.1,52.48 ; JUSB2.10 16.13,51.53 ; JUSB2.10 13.1,51.53 ; JUSB2.10 16.13,50.58 ; JUSB2.10 13.1,50.58 ; JUSB2.10 14.61,52.48 ; JUSB2.10 16.13,52.48 ; 214.81,14.03 H13.1 ; H13.1 214.81,16.91 ; H13.1 213.74,16.54 ; H13.1 215.88,14.4 ; H13.1 216.25,15.47 ; H13.1 215.88,16.54 ; H13.1 213.74,14.4 ; H13.1 213.37,15.47 ; 3.12,53.92 JUSB2.12 ; JUSB2.12 5.53,53.92 ; JUSB2.12 3.12,52.97 ; JUSB2.12 5.53,52.97 ; JUSB2.12 4.33,53.92 ; JUSBC1.2 6.6,65.39 ; JUSBC1.2 4.14,64.67 ; JUSBC1.2 6.6,66.11 ; JUSBC1.2 5.37,64.67 ; JUSBC1.2 5.37,66.11 ; JUSBC1.2 4.14,66.11 ; JUSBC1.2 4.14,65.39 ; 51.45,13.31 H18.1 ; H18.1 53.96,14.38 ; H18.1 51.82,14.38 ; H18.1 52.89,14.75 ; H18.1 52.89,11.87 ; H18.1 51.82,12.24 ; H18.1 54.33,13.31 ; H18.1 53.96,12.24 ; 186.68,21.6 H6.1 ; H6.1 189.72,21.6 ; H6.1 188.2,25.2 ; H6.1 186.12,23.12 ; H6.1 189.72,24.64 ; H6.1 190.28,23.12 ; H6.1 188.2,21.04 ; H6.1 186.68,24.64 ; JUSB2.11 16.13,38.73 ; JUSB2.11 13.1,39.68 ; JUSB2.11 16.13,37.78 ; JUSB2.11 13.1,38.73 ; JUSB2.11 14.61,37.78 ; JUSB2.11 16.13,39.68 ; JUSB2.11 14.61,39.68 ; JUSB2.11 13.1,37.78 ; 102.48,76.37 H16.1 ; H16.1 105.52,76.37 ; H16.1 106.08,74.85 ; H16.1 102.48,73.33 ; H16.1 104,76.93 ; H16.1 104,72.77 ; H16.1 101.92,74.85 ; 4.14,56.19 JUSBC1.3 ; JUSBC1.3 6.6,56.19 ; JUSBC1.3 4.14,55.47 ; JUSBC1.3 5.37,55.47 ; JUSBC1.3 5.37,56.91 ; JUSBC1.3 6.6,55.47 ; JUSBC1.3 4.14,56.91 ; H10.1 164.32,52.33 ; H10.1 164.32,55.37 ; H10.1 161.28,55.37 ; H10.1 164.88,53.85 ; H10.1 162.8,51.77 ; H10.1 162.8,55.93 ; H10.1 161.28,52.33 ; H10.1 160.72,53.85 ; 1.14,66.11 JUSBC1.1 ; JUSBC1.1 3.6,65.39 ; JUSBC1.1 3.6,66.11 ; JUSBC1.1 3.6,64.67 ; JUSBC1.1 2.37,66.11 ; JUSBC1.1 1.14,64.67 ; JUSBC1.1 1.14,65.39 ; JUSBC1.1 2.37,64.67 ; H19.1 111.11,12.24 ; H19.1 111.48,13.31 ; H19.1 108.97,12.24 ; H19.1 108.6,13.31 ; H19.1 108.97,14.38 ; H19.1 110.04,11.87 ; H19.1 111.11,14.38 ; 200.92,50.12 H17.1 ; H17.1 204.52,51.64 ; H17.1 205.08,50.12 ; H17.1 203,52.2 ; H17.1 203,48.04 ; H17.1 201.48,51.64 ; H17.1 204.52,48.6 ; H17.1 201.48,48.6 ; SW3.4 2.54,18.79 ; SW3.4 2.7,19.33 ; SW3.4 1.45,18.79 ; SW3.4 2.54,19.88 ; SW3.4 2,18.63 ; SW3.4 1.45,19.88 ; SW3.4 2,20.03 ; JUSB2.13 5.53,37.75 ; JUSB2.13 5.53,37.27 ; JUSB2.13 5.53,36.79 ; H14.1 104,55.93 ; H14.1 105.52,52.33 ; H14.1 104,51.77 ; H14.1 102.48,52.33 ; H14.1 105.52,55.37 ; H14.1 106.08,53.85 ; H14.1 102.48,55.37 ; H14.1 101.92,53.85 ; 12.13,45.71 JUSB2.7 ; JUSB2.7 13.5,45.11 ; JUSB2.7 11.95,45.11 ; JUSB2.7 12.72,45.89 ; JUSB2.7 12.13,44.51 ; JUSB2.7 13.32,44.51 ; JUSB2.7 13.32,45.71 ; JUSB2.7 12.72,44.33 ; 162.8,72.77 H15.1 ; H15.1 162.8,76.93 ; H15.1 164.88,74.85 ; H15.1 164.32,76.37 ; H15.1 161.28,76.37 ; H15.1 164.32,73.33 ; H15.1 161.28,73.33 ; H15.1 160.72,74.85 ; 181.75,80.87 H9.1 ; H9.1 182.82,81.24 ; H9.1 181.38,79.8 ; H9.1 183.89,78.73 ; H9.1 184.26,79.8 ; H9.1 181.75,78.73 ; H9.1 182.82,78.36 ; H9.1 183.89,80.87 ; H4.1 83.4,79.8 ; H4.1 80.89,80.87 ; H4.1 83.03,78.73 ; H4.1 83.03,80.87 ; H4.1 80.89,78.73 ; H4.1 81.96,78.36 ; H4.1 80.52,79.8 ; H4.1 81.96,81.24 ; 128.02,12.21 H7.1 ; H7.1 129.09,11.84 ; H7.1 130.16,12.21 ; H7.1 130.53,13.28 ; H7.1 130.16,14.35 ; H7.1 128.02,14.35 ; H7.1 127.65,13.28
  BOTTOM w0.127: UCPU1.F68 113.24,69.32 114.21,68.35 UCPU1.G66 ; v2(144.26,51.4) 143.91,51.4 143.82,51.32 143.38,51.32 142.95,51.75 UCPU1.AW16 ; UCPU1.D34 131.86,70.32 131.48,70.7 131.1,70.7 130.99,70.58 130.99,70.56 130.91,70.48 130.91,70.06 130.79,69.94 130.79,69.36 131.17,68.98 UCPU1.F37 ; v2(78.18,22.46) 78.16,22.46 ; UCPU1.AK18 142.04,56.79
  BOTTOM w0.152: v2(149,53.74) 149,53.4 149.27,53.13 149.59,53.13 150.02,53.55 UCPU1.AT4 ; UCPU1.AJ4 150.12,56.87 149.58,57.41 149.58,57.74 UCPU1.AH6 ; v2(150.9,71.18) 151.03,71.18 151.38,70.82 151.61,70.82 152.12,71.33 UCPU1.C1 ; UCPU1.BB60 118.25,49.99 118.25,49.12 v2(118.22,49.09)
  BOTTOM w0.178: v2(133.07,48.22) 132.99,48.3 132.99,49.71 UCPU1.BB34 ; UCPU1.BB38 130.64,50 130.64,49.05 v2(130.67,49.03) ; UCPU1.AG71 110.89,58.5 110.73,58.66 v2(110.71,58.72) ; v2(135.76,48.88) 135.61,49.03 135.61,49.92 135.62,49.93 UCPU1.BB30 ; v2(110.74,55.76) 110.82,55.84 111.53,55.84 UCPU1.AM71 ; UCPU1.BB43 128.03,49.15 v2(127.99,49.11) ; v2(115.88,49.09) 115.9,49.11 115.9,49.97 115.92,50 UCPU1.BB64 ; v2(138.02,49.05) 137.97,49.1 137.97,49.61 UCPU1.BB26 ; v2(110.92,68.06) 110.96,68.09 UCPU1.H71 ; UCPU1.BB18 141.64,49.93 141.64,49.09 141.67,49.06 141.67,48.94 v2(141.71,48.9) ; v2(110.72,53.5) 110.72,53.49 110.89,53.49 UCPU1.AT71
  BOTTOM w0.203: UCPU1.AW12 145.34,51.99 144.16,51.99 UCPU1.AW14 ; 113.76,52.3 113.76,52.67 113.81,52.72 113.81,52.9 113.76,53.07 UCPU1.AT68 113.76,53.88 113.79,53.91 113.79,54.2 113.76,54.23 UCPU1.AP68 113.76,55.1 113.79,55.13 113.79,55.43 113.76,55.46 UCPU1.AM68 ; PU1100.3 85.05,64.77 v2(85.08,64.74) ; UCPU1.G10 146.56,68.29 v2(146.25,67.98) ; UCPU1.P21 140.11,64.36 140.23,64.25 140.63,64.25 UCPU1.P20 ; 141.25,51.99 141.23,52.02 UCPU1.AU20 ; 141.25,51.99 141.28,51.96 UCPU1.AW18 142.2,51.96 142.23,51.99 142.52,51.99 142.55,51.96 UCPU1.AW16 ; 141.25,51.99 140.96,51.99 140.93,51.96 UCPU1.AW21 140.13,51.96 140.1,51.99 139.81,51.99 139.78,51.96 UCPU1.AW23 138.81,51.96 138.78,51.99 138.48,51.99 138.45,51.96 UCPU1.AW26 137.58,51.96 137.55,51.99 137.26,51.99 137.23,51.96 UCPU1.AW28 136.35,51.96 136.32,51.99 136.03,51.99 136,51.96 UCPU1.AW30 135.13,51.96 135.1,51.99 134.8,51.99 134.77,51.96 UCPU1.AW32 133.95,51.96 v2(133.45,52.45) 133.09,52.08 UCPU1.AW34 132.6,51.96 132.57,51.99 132.28,51.99 132.24,51.96 UCPU1.AW36 131.37,51.96 131.34,51.99 131.05,51.99 131.02,51.96 UCPU1.AW38 130.33,51.96 v2(129.82,52.47) 129.33,51.98 UCPU1.AW41 128.87,51.96 128.85,51.98 128.53,51.98 128.52,51.96 UCPU1.AW43 127.64,51.96 127.61,51.99 127.32,51.99 127.29,51.96 UCPU1.AW45 126.42,51.96 126.39,51.99 126.09,51.99 126.06,51.96 UCPU1.AW47 125.25,51.96 125.22,51.99 124.93,51.99 124.9,51.96 UCPU1.AW49 124,51.96 123.97,51.99 123.67,51.99 123.64,51.96 UCPU1.AW51 122.83,51.96 122.8,51.99 122.51,51.99 122.48,51.96 UCPU1.AW53 121.6,51.96 121.57,51.99 121.28,51.99 121.25,51.96 UCPU1.AW55 120.38,51.96 120.35,51.99 120.05,51.99 120.02,51.96 UCPU1.AW57 119.1,51.96 119.07,51.99 118.78,51.99 118.75,51.96 UCPU1.AW60 117.88,51.96 117.85,51.99 117.55,51.99 117.52,51.96 UCPU1.AW62 116.65,51.96 116.62,51.99 115.84,51.99 UCPU1.AW64 115.78,51.98 115.02,51.98 114.91,52.1 UCPU1.AW66 114.71,51.44 UCPU1.AY66 UCPU1.BA66 ; UCPU1.AH67 113.44,57.29 UCPU1.AK68 113.44,57.1 113.85,56.69 113.85,56.42 113.76,56.33 UCPU1.AM68 ; UCPU1.AK11 145.31,56.17 145.21,56.17 145.1,56.05 UCPU1.AM13 ; UCPU1.D44 UCPU1.D45 126.28,70.36 125.9,70.36 125.88,70.33 125.58,70.33 125.55,70.36 UCPU1.D47 UCPU1.D48 ; D84.2 v2(10.2,64.27) ; PU1101.3 84.79,56.3 85.5,57.01 v2(85.5,57.13) ; JEDP.36 191.91,41.87 v2(191.76,41.72) ; v2(152.45,69.62) 152.3,69.46 UCPU1.F1 ; v2(136.93,66.91) 137.11,67.09 UCPU1.J25 ; UCPU1.J28 135.34,67.77 135.34,67.17 v2(135.31,67.14) ; UCPU1.AL64 115.94,56.15 115.89,56.11 115.51,56.11 115.47,56.15 UCPU1.AL65 115.3,56.15 115.26,56.11 114.88,56.11 114.83,56.15 UCPU1.AL66 ; v2(120.9,49.09) 120.86,49.14 UCPU1.BB55 ; v2(114.25,55.64) 113.95,55.94 UCPU1.AM68 ; v2(43.97,31.05) 44.07,30.95 44.07,30.62 43.97,30.51 PU300.22 ; PU1500.16 90.06,40.89 v2(90.4,41.23) ; v2(85.41,49.48) 85.5,49.48 85.5,49.41 84.76,48.68 PU1102.3 ; UCPU1.F40 v2(129.8,68.54) UCPU1.F38 ; v2(10.82,59.14) 10.82,59.53 10.57,59.78 D91.2 ; v2(191.06,37.37) JEDP.27 ; UCPU1.AF15 144.62,59.33 144.89,59.6 v2(145.04,59.6)
  BOTTOM w0.254: UCPU1.AU38 130.25,52.78 v2(129.82,52.47) ; UCPU1.L11 146.53,65.79 v2(146.61,65.87) 146.61,65.58 UCPU1.N10 ; UCPU1.AN58 v2(118.82,55.01) ; v2(184.46,32.79) JNGFF2.39 ; UCPU1.L4 150.48,66.81 v2(150.65,66.64) 150.83,66.81 UCPU1.L2 ; UCPU1.V18 142.04,62.6 v2(142.4,62.24) ; UCPU1.E6 148.35,69.59 148.06,69.88 v2(148.06,69.91) ; UCPU1.AD62 118.08,60.22 119.5,58.81 v2(119.53,58.81) ; UCPU1.AR53 121.94,54.1 121.64,53.81 v2(121.54,53.81) ; v2(139.62,62.52) 140.09,62.05 UCPU1.Y21 ; UCPU1.AW49 v2(124.45,51.43) UCPU1.BA49 ; UCPU1.E56 120.07,69.71 119.85,69.71 v2(119.72,69.85) 119.72,69.85 119.53,70.04 UCPU1.D58 UCPU1.B58 ; UCPU1.AR58 v2(118.82,53.74) UCPU1.AT58 ; UCPU1.Y21 UCPU1.Y20 140.85,61.73 141.28,61.73 UCPU1.Y19 ; UCPU1.Y21 140.09,61.75 v2(139.74,61.4) 140.09,61.05 UCPU1.AB21 ; UCPU1.AP38 v2(129.8,54.37) ; UCPU1.AN38 130.25,55.31 130.6,55.01 v2(130.71,55.01) UCPU1.AN37 ; UCPU1.G60 118.37,68.32 v2(118.78,68.55) 119.25,68.29 UCPU1.G58 ; JTAG1.2 171.3,59.75 v2(171.44,59.6) ; UCPU1.J42 127.95,67.84 127.95,68.54 127.9,68.59 ; UCPU1.AD19 141.39,60.22 141.69,60.52 v2(141.69,60.59) 142.04,60.94 UCPU1.AB18 ; UCPU1.T2 150.83,64.16 v2(150.65,63.98) 150.48,64.16 UCPU1.T4 ; v2(122.46,53.74) 122.58,53.74 UCPU1.AR52 ; v2(116.08,55.01) 116.26,55.16 116.28,55.16 116.42,55.3 UCPU1.AN63 ; UCPU1.AK16 143.04,57.12 v2(143.04,57.24) ; v2(110.93,70.06) 111.1,69.9 UCPU1.E71 ; UCPU1.D30 134.17,70.55 v2(134.17,70.82) 134.17,71.11 UCPU1.B30 ; UCPU1.AW62 v2(117.08,51.43) UCPU1.BA62 ; JNGFF2.15 183.96,26.79 184.13,26.63 v2(184.38,26.63) ; UCPU1.E15 144.33,69.23 v2(144.43,69.23) 144.59,69.23 UCPU1.F13 ; v2(127.97,54.4) 128.4,54.75 UCPU1.AP42 ; v2(141.68,54.37) 142.12,54.73 UCPU1.AP18 ; UCPU1.AR23 v2(138.03,53.74) UCPU1.AT23 ; UCPU1.P20 140.75,64.36 v2(141.04,64.75) 141.39,65.18 UCPU1.N19 141.39,65.25 v2(141.73,65.67) 142,66.04 UCPU1.L18 ; UCPU1.AM55 121,56.05 v2(120.66,55.71) ; v2(144.37,55.72) 144.4,55.72 144.78,56.06 144.79,56.06 UCPU1.AM13 ; UCPU1.U10 146.79,62.99 146.97,62.72 146.97,62.7 147.44,62.24 UCPU1.W9 147.41,62.2 147.08,61.87 v2(147.08,61.79) ; v2(123.34,69.9) 123.65,69.59 UCPU1.E50 ; UCPU1.AR5 v2(149,53.74) ; UCPU1.AN33 v2(132.54,55.01) ; UCPU1.AK22 139.92,56.99 UCPU1.AK21 140.74,57.47 UCPU1.AJ20 140.74,57.69 v2(140.41,58.01) ; UCPU1.V17 142.69,62.53 v2(142.4,62.24) ; 142.04,56.79 142.04,56.61 v2(141.68,56.25) ; UCPU1.AM45 v2(127.05,55.63) UCPU1.AL45 ; v2(149.05,68.59) 149.35,68.29 UCPU1.G5 ; UCPU1.F23 138.56,68.94 138.9,68.59 v2(138.96,68.59) ; UCPU1.AG21 140.09,58.34 v2(140.41,58.01) ; v2(110.89,51.97) 111.02,52.1 UCPU1.AV71 UCPU1.AV70 UCPU1.AV69 112.94,52.25 113.12,52.25 v2(113.24,52.36) 113.26,52.34 113.72,52.34 UCPU1.AV68 ; UCPU1.B14 144.31,71.07 v2(144.12,70.87) 144.31,70.68 UCPU1.D14 ; UCPU1.AW28 v2(136.79,51.43) UCPU1.BA28 ; UCPU1.AR43 v2(127.05,53.74) ; JNGFF2.9 182.18,25.29 182.07,25.41 181.71,25.41 v2(181.41,25.11) ; UCPU1.D39 129.65,70.52 v2(129.65,70.82) 129.65,71.13 UCPU1.B39 ; D89.2 v2(10.2,59.17) ; UCPU1.AG18 UCPU1.AG17 142.69,58.41 v2(143.03,58.07) 143.03,58.18 UCPU1.AG16 ; UCPU1.AG18 UCPU1.AJ18 ; UCPU1.AG18 UCPU1.AG19 ; UCPU1.AE65 115.43,59.73 116,59.73 UCPU1.AE64 UCPU1.AF63 ; UCPU1.AE65 115.39,59.8 115.82,60.23 v2(115.85,60.23) ; UCPU1.AE65 UCPU1.AE66 UCPU1.AE67 UCPU1.AE68 UCPU1.AE69 112.47,60.08 112.47,60.26 v2(112.45,60.28) ; UCPU1.J35 131.63,68.51 v2(131.67,68.55) ; 149.74,61.73 149.96,61.51 UCPU1.AA4 UCPU1.AA2 ; 149.74,61.73 149.39,62.08 UCPU1.W6 ; 149.74,61.73 v2(149.74,61.72) ; UCPU1.B44 v2(126.97,70.84) UCPU1.D44 ; JEDP.10 192.75,28.87 191.58,28.87 v2(191.36,28.66) ; UCPU1.BA57 v2(119.56,51.43) UCPU1.AW57 119.56,52.38 v2(119.66,52.48) ; D90.2 10.24,61.17 v2(10.74,61.68) ; UCPU1.A67 113.9,72.49 113.45,72.94 v2(113.45,73) ; v2(152.46,58.86) 152.41,58.91 151.84,58.91 UCPU1.AF1 ; UCPU1.J38 v2(129.8,68.54) ; UCPU1.AN28 v2(135.28,55.01) UCPU1.AP28 ; JNGFF1.1 31.25,39.67 v2(31.55,39.96) ; v2(147.17,53.74) UCPU1.AR8 ; UCPU1.B22 v2(139.36,70.81) UCPU1.D22 140.09,69.59 UCPU1.E21 ; v2(182.78,72.53) 182.78,72.42 183.65,71.55 JLPDE1.9 ; JNGFF2.21 183.15,28.29 184.14,28.29 184.28,28.43 v2(184.38,28.43) ; UCPU1.AB8 148.11,61.13 148.4,60.85 v2(148.4,60.7) 148.4,60.49 148.09,60.18 UCPU1.AD8 ; UCPU1.AJ4 UCPU1.AL4 150.46,56.21 150.67,56.42 v2(150.67,56.41) 150.67,56.37 150.84,56.21 UCPU1.AL2 ; UCPU1.AU10 146.77,52.8 147.07,52.5 v2(147.2,52.5) ; UCPU1.AR55 120.75,53.74 v2(120.63,53.74) ; UCPU1.AU20 141.23,52.8 v2(140.77,53.1) 141.23,53.45 UCPU1.AT20 ; v2(148.06,68.57) 148.26,68.57 UCPU1.G6 ; UCPU1.AH67 114.09,57.91 114.18,57.82 v2(114.43,57.48) ; UCPU1.AP32 v2(133.45,54.37) ; UCPU1.K65 UCPU1.K64 v2(116.31,66.63) UCPU1.K63 ; v2(136.2,55.66) UCPU1.AM27 ; UCPU1.F68 UCPU1.D69 112.72,69.97 v2(112.71,69.97) ; UCPU1.F32 133.91,68.92 133.58,68.59 133.37,68.59 v2(133.37,68.6) ; v2(191.24,29.42) 191.29,29.37 192.75,29.37 JEDP.11 ; PC1289.2 PC1274.2 94.84,72.6 95.36,73.12 PC1241.2 ; v2(141.68,67.93) 142.14,67.67 UCPU1.H18 UCPU1.K18 ; UCPU1.AW18 141.84,51.83 v2(141.84,51.32) 141.84,50.87 UCPU1.BA18 ; UCPU1.P17 v2(142.36,64.78) ; UCPU1.AN30 v2(134.37,55.01) ; UCPU1.F27 136.39,69.2 136,69.2 UCPU1.F28 135.53,68.94 v2(135.21,68.62) ; UCPU1.AR16 v2(142.6,53.74) ; UCPU1.G63 116.68,68.35 v2(117.06,67.97) 117.45,67.58 UCPU1.K61 ; UCPU1.G48 v2(124.38,68.59) ; UCPU1.F8 v2(147.17,69.18) ; UCPU1.AN40 v2(128.88,55.01) ; v2(139.66,60.69) 139.66,60.7 140.09,60.28 UCPU1.AD21 UCPU1.AD20 ; v2(133.37,68.6) 133.03,68.94 UCPU1.F33 ; v2(133.37,68.6) 133.45,68.52 UCPU1.J32 ; UCPU1.AR42 v2(127.97,53.74) UCPU1.AT42 ; UCPU1.AW10 146.66,51.96 v2(147.2,52.5) ; UCPU1.AW10 UCPU1.BA10 ; UCPU1.AW10 146.21,52.31 v2(146.08,52.31) 145.73,51.96 UCPU1.AW12 ; UCPU1.AU32 v2(133.45,52.45) ; UCPU1.BA14 144.13,51.1 144.26,51.23 v2(144.26,51.4) 144.13,51.53 UCPU1.AW14 143.85,52.25 143.85,52.68 UCPU1.AU15 ; v2(139.69,65.64) 139.69,65.55 140.04,65.2 UCPU1.N21 140.29,65.4 140.29,65.54 140.74,65.98 UCPU1.L20 ; v2(138.96,68.59) 139.05,68.59 139.4,68.94 UCPU1.F22 ; v2(138.96,68.59) 139.27,68.29 UCPU1.G22 139.33,68.22 139.33,67.43 UCPU1.K22 ; UCPU1.U70 v2(112.45,62.98) UCPU1.U69 ; UCPU1.BA53 v2(122.04,51.43) UCPU1.AW53 ; v2(125.25,53.74) 125.68,54.08 UCPU1.AR46 ; UCPU1.AF17 142.98,59.62 v2(142.98,59.73) 142.98,59.81 UCPU1.AD16 ; v2(191.75,38.97) 191.84,38.87 192.75,38.87 JEDP.30 ; UCPU1.F2 150.99,69.31 150.66,69.31 v2(150.65,69.3) 150.63,69.31 150.32,69.31 UCPU1.F4 ; UCPU1.H15 143.97,67.51 UCPU1.K16 v2(143.68,66.46) ; UCPU1.AB16 143.68,61.35 v2(143.68,61.43) 143.99,61.12 UCPU1.AB15 ; UCPU1.AJ15 144.31,57.97 144.8,57.97 UCPU1.AH13 144.84,57.69 v2(145.16,57.36) ; UCPU1.AW8 147.74,51.96 v2(147.2,52.5) ; v2(114.25,55.64) 114.74,56.13 UCPU1.AL66 ; v2(149.76,63.88) 149.49,64.33 UCPU1.R6 ; UCPU1.E18 v2(141.68,69.81) ; UCPU1.AR48 124.77,54.09 v2(124.32,53.74) ; UCPU1.AP70 v2(113.19,54.67) UCPU1.AP68 ; v2(149.03,65.02) 149.39,65.37 UCPU1.N6 ; UC2.3 104.88,44.9 104.88,44.9 105.07,44.9 105.28,44.69 105.28,44.42 v2(105.25,44.39) ; UCPU1.AT63 v2(116.08,53.74) UCPU1.AR63 ; 136.92,70.36 UCPU1.D25 ; 136.92,70.36 UCPU1.D26 ; 136.92,70.36 136.99,70.44 136.99,70.86 ; UCPU1.E65 115.37,69.65 115.23,69.8 115,69.8 114.58,70.22 UCPU1.D66 v2(114.58,70.84) UCPU1.B66 ; UCPU1.AP63 v2(116.08,54.37) ; UCPU1.AT28 v2(135.28,53.74) UCPU1.AR28 ; UCPU1.AR35 v2(131.63,53.74) UCPU1.AT35 ; UCPU1.AM8 v2(147.17,55.64) 147.17,54.95 146.98,54.75 UCPU1.AP10 ; 127.9,68.59 128.41,68.94 UCPU1.F42 ; 127.9,68.59 127.51,68.31 UCPU1.G43 127.43,68.29 v2(127.1,68.62) ; CA111.2 30.2,25.03 v2(30.73,25.56) ; v2(142.4,62.24) 142.69,61.95 UCPU1.Y17 ; JNGFF2.33 183.15,31.3 182.25,31.3 181.81,31.73 v2(181.48,31.73) ; UCPU1.AN42 128.19,55.63 v2(127.97,55.63) UCPU1.AM43 ; UCPU1.AY3 150.83,50.85 151.37,50.31 UCPU1.BA2 151.65,50.15 UCPU1.BA1 v2(152.63,50.15) ; v2(147.09,67.32) 147.1,67.32 UCPU1.J8 ; UCPU1.C5 149.47,71.01 v2(149.28,70.82) 149.24,70.78 UCPU1.D6 ; UCPU1.AL35 v2(132.54,57.27) ; 136.99,70.86 v2(136.99,70.86) ; 136.99,70.86 137.4,70.86 UCPU1.C25 ; UCPU1.AP20 141.23,54.72 v2(140.74,54.32) ; UCPU1.AW32 v2(134.29,51.43) UCPU1.BA32 ; v2(144.41,65.65) 144.65,65.4 UCPU1.N13 144.93,65.3 144.93,64.43 UCPU1.R13 ; UCPU1.AW6 148.95,51.94 v2(148.95,51.4) 148.98,51.38 UCPU1.BA6 UCPU1.BB6 ; v2(126.19,55.71) 126.03,55.71 UCPU1.AM46 125.68,56.07 UCPU1.AL48 ; UCPU1.AF4 150.4,58.86 v2(150.62,58.63) 150.85,58.86 UCPU1.AF2 ; D85.2 v2(10.2,61.91) ; UCPU1.P19 141.39,64.23 v2(141.71,63.92) 142.04,63.58 UCPU1.T18 142.21,63.36 142.52,63.36 UCPU1.T17 ; UCPU1.AK8 148.09,57.08 v2(147.74,57.43) ; JEDP.17 192.75,32.37 191.82,32.37 v2(191.54,32.65) 191.76,32.87 192.75,32.87 JEDP.18 ; v2(131.67,68.55) 131.69,68.55 UCPU1.F35 ; v2(131.67,68.55) 131.56,68.55 UCPU1.F37 ; v2(19.7,40.03) 19.63,40.09 DI1.8 DI1.3 ; UCPU1.AG19 141.33,58.55 140.79,58.55 UCPU1.AG20 140.41,58.17 v2(140.41,58.01) ; UCPU1.AG19 141.39,58.37 v2(141.07,58.05) ; UCPU1.AP35 v2(131.63,54.37) ; UCPU1.AH64 116.06,57.93 116.06,57.82 v2(116.31,57.43) ; UCPU1.BB70 111.85,49.59 111.18,49.59 v2(111.15,49.62) 111.49,49.95 UCPU1.BA71 111.39,50.15 v2(111.08,50.46) 111.42,50.8 UCPU1.AY71 ; UCPU1.AL65 115.39,55.87 v2(115.17,55.64) ; JNGFF2.27 183.89,29.79 184.38,30.29 184.38,30.33 v2(184.42,30.33) ; v2(139.61,63.18) 139.61,63.29 139.83,63.52 UCPU1.T21 ; v2(136.11,57.3) 136.2,57.22 UCPU1.AL28 ; UCPU1.K66 UCPU1.K67 113.66,67.05 UCPU1.K68 113.35,66.74 v2(112.95,66.74) UCPU1.K70 UCPU1.K71 ; v2(126.85,51.43) UCPU1.BA45 ; UCPU1.AD13 145.04,59.86 v2(145.04,59.6) ; v2(143.51,53.74) UCPU1.AR15 ; UCPU1.AW36 v2(131.81,51.43) UCPU1.BA36 ; UCPU1.D18 v2(141.83,70.81) UCPU1.B18 ; UCPU1.AN32 v2(133.45,55.01) ; 139.32,51.42 139.32,50.79 UCPU1.BA23 ; 139.32,51.42 139.32,51.91 UCPU1.AW23 ; 139.32,51.42 v2(139.29,51.42) ; UCPU1.AF10 146.79,59.22 146.49,59.51 v2(146.49,59.58) ; UCPU1.G45 v2(126.19,68.59) ; JEDP.16 192.01,31.87 v2(191.8,31.66) 192.08,31.37 JEDP.15 ; UCPU1.AN35 v2(131.63,55.01) ; UCPU1.D62 116.95,70.42 116.95,70.73 v2(117.04,70.82) 117.05,70.84 UCPU1.B62 ; JNGFF2.57 184.12,37.3 v2(184.25,37.42) ; UCPU1.B48 124.52,71.31 124.52,71.31 124.72,71.11 124.72,70.8 UCPU1.D47 125.16,69.94 v2(125.22,69.88) 125.42,69.68 125.59,69.68 UCPU1.E46 ; UCPU1.BB67 113.9,49.3 v2(114.02,49.18) ; v2(201.68,30.26) 201.55,30.39 200.76,30.39 JAPS1.12 ; UCPU1.AW41 v2(129.33,51.43) UCPU1.BA41 ; v2(199.92,29.39) JAPS1.14 ; UCPU1.AA65 v2(115.75,61.12) ; UCPU1.AN20 141.2,55.4 140.85,55.09 140.81,55.09 v2(140.79,55.11) ; v2(150.54,72.82) 150.36,72.82 UCPU1.A5 ; UCPU1.L17 142.69,65.98 v2(142.99,65.59) 142.99,65.65 143.29,66.04 UCPU1.L16 ; UCPU1.AT2 UCPU1.AT4 ; UCPU1.T15 143.68,63.21 v2(143.68,63.1) 143.34,62.77 UCPU1.V16 ; D88.2 v2(10.2,56.65) ; v2(146.23,67.3) 145.92,66.99 UCPU1.J11 UCPU1.J13 ; UCPU1.N65 115.39,65.39 115.06,65.72 v2(114.33,65.72) 113.89,65.62 UCPU1.N68 ; v2(191.77,40.37) JEDP.33 ; v2(152.86,52.05) 152.5,52.05 152.38,52.17 UCPU1.AV1 ; v2(136.55,58.01) 136.65,57.91 UCPU1.AK27 ; v2(145.24,61.56) 145.24,61.57 144.84,61.98 UCPU1.W13 ; JNGFF2.45 183.15,34.3 v2(184.46,34.3) ; UCPU1.AP23 v2(138.03,55.01) UCPU1.AN23 ; v2(201.65,31.71) 201.33,31.39 JAPS1.10 ; 191.57,30.34 191.57,30.29 191.98,29.87 192.75,29.87 JEDP.12 ; 191.57,30.34 191.6,30.37 JEDP.13 ; 191.57,30.34 v2(191.54,30.36) ; v2(110.97,71.89) 111.01,71.85 UCPU1.B71 UCPU1.A70 ; UCPU1.AK69 112.77,57.17 112.95,57.35 113.26,57.35 UCPU1.AK68 ; JAPS1.8 v2(201.61,32.39) ; UCPU1.AR11 145.8,54.08 145.8,54.06 v2(145.39,53.74) ; UCPU1.B34 132.01,71.25 v2(132.01,70.83) 132.01,70.41 UCPU1.D34 ; UCPU1.AP58 v2(118.82,54.37) ; v2(116.31,57.43) 116.61,57.04 116.69,57.04 UCPU1.AK63 UCPU1.AM61 v2(116.99,55.66) ; v2(116.31,57.43) 116.67,57.89 116.67,57.93 UCPU1.AH63 ; UCPU1.B53 v2(122.01,70.81) UCPU1.D53 121.84,70.16 121.84,69.73 121.99,69.59 UCPU1.E53 122.43,69.19 122.43,68.8 UCPU1.G52 ; v2(148.37,65.88) UCPU1.L8 ; UCPU1.U67 v2(114.4,62.98) UCPU1.U66 115.14,63.02 115.64,63.02 UCPU1.U64 UCPU1.U63 ; UCPU1.AL32 v2(134.37,57.21) ; JNGFF2.51 183.15,35.79 v2(184.46,35.79) ; UCPU1.AA68 v2(113.77,61.12) ; v2(137.11,55.66) UCPU1.AM25 ; v2(126.18,53.74) 126.18,53.76 126.53,54.1 UCPU1.AR45 ; v2(140.77,53.74) 140.92,53.74 141.23,53.98 141.23,54.1 UCPU1.AR20 ; UCPU1.AL38 v2(130.71,57.26) ; UCPU1.E11 145.8,70.02 v2(145.7,70.12) 146.04,70.36 UCPU1.D11 UCPU1.D10 UCPU1.B10 ; UCPU1.AM60 v2(117.91,55.66) ; UCPU1.AM21 v2(139.85,55.64) ; UCPU1.G55 v2(120.63,68.54)
  BOTTOM w0.305: JKB1.15 39.92,20.36 39.92,19.27 40.21,18.98 v2(40.64,18.98) 40.42,19.2 40.42,20.36 JKB1.14 ; v2(157.7,54.09) 157.66,54.05 157.26,54.05 157,54.31 RC4.2 ; UCPU1.AL58 119.74,57.33 v2(119.76,57.35) ; 48.48,37.46 49.29,37.46 49.75,37.92 JNGFF1.67 ; 48.48,37.46 48.25,37.69 JNGFF1.61 ; 48.48,37.46 v2(48.46,37.45) ; UCPU1.AL55 v2(121.57,57.42) ; v2(41.73,39.94) 41.23,39.94 40.75,39.45 40.75,38.78 JNGFF1.31 ; JIO1.63 191.56,15.91 191.56,17.18 v2(191.8,17.41) ; UCPU1.AT56 120.49,53.74 v2(120.63,53.74) ; JNGFF1.21 38.25,39.71 38.5,39.96 39.03,39.96 39.25,39.74 JNGFF1.25 39.25,37.66 v2(39.22,37.63) ; v2(36.78,37.63) 36.75,37.66 36.75,38.77 JNGFF1.15 ; v2(47.98,16.21) 47.81,16.39 JKB1.17 ; v2(32.94,40.01) 32.75,39.82 32.75,38.78 JNGFF1.7 ; UCPU1.AL52 123.34,56.58 v2(123.34,57.34) ; v2(35.27,47.67) 35.5,47.44 JNGFF1.10 ; v2(208.7,17.67) 208.71,17.68 JIO1.6 ; v2(137.11,55.66) 136.72,56.05 UCPU1.AM27 ; JNGFF1.28 40,45.39 39.75,45.14 38.57,45.14 v2(38.54,45.16) 38.5,45.21 38.5,46.32 JNGFF1.22 ; C401.1 9.46,59.71 v2(9.65,59.9) ; JKB1.13 40.92,19.85 41.22,19.54 41.63,19.54 v2(42.11,19.06) ; JNGFF1.55 46.75,38.77 46.75,37.92 47.27,37.4 v2(47.35,37.4) ; v2(37.05,47.76) 37,47.71 JNGFF1.16 ; JIO1.1 210.21,16.42 v2(210.21,16.42) ; JIO1.62 210.86,17.02 v2(210.86,17.03) ; JTP1.4 185.16,19.36 185.16,20.17 v2(184.95,20.38) ; v2(42.44,37.58) 42.25,37.77 JNGFF1.37 ; UCPU1.AR50 123.87,54.1 124.23,53.74 v2(124.32,53.74) ; v2(209.11,16.28) 209.01,16.18 209.01,15.54 JIO1.5 ; v2(173.91,69) 174.15,68.76 JDEG1.10 ; JNGFF1.43 43.75,39.56 43.75,39.56 43.75,39.9 v2(44.04,40.19) 44.7,40.19 45.25,39.65 45.25,38.78 JNGFF1.49 ; CC212.2 157.18,61.63 v2(157.18,62.59) ; JIO1.12 206.91,18.41 206.91,17.62 v2(206.91,17.61) ; JIO1.7 208.41,15.54 208.41,16.27 v2(208.48,16.34) ; v2(38.38,17.59) 38.58,17.4 39.03,17.4 JKB1.16
  BOTTOM w0.356: PC402.2 171.85,58.63 171.4,59.08 171.4,59.56 v2(171.44,59.6) ; PU200.2 59.16,58.58 59.42,58.31 59.68,58.31 59.81,58.44 ; 59.81,58.44 59.97,58.28 60.39,58.28 v2(60.43,58.31) ; 59.81,58.44 PU200.1
  BOTTOM w0.381: v2(79.02,65.15) 78.77,65.41 78.77,65.68 v3(78.76,65.69) 78.76,65.89 78.59,66.06 78.59,67.46 79.05,67.93 PR1104.2 ; v2(157.3,59.01) RH556.2 ; PR413.2 165.71,58.8 165.32,58.41 v2(165.08,58.41) ; UC10.3 191.3,60.3 190.93,60.3 190.59,59.96 190.59,58.19 190.14,57.75 190.14,54.06 190.41,53.79 v2(191.11,53.79) ; v2(41.73,36.89) 41.73,36.51 42.29,35.95 C1302.2 ; v2(81.74,73.11) 81.19,73.66 80.67,73.66 80.51,73.49 RC136.1 ; v2(29.9,18.8) 29.92,18.83 30.96,18.83 UE4.6 ; v2(186.39,64.28) 186.59,64.47 CE54.2 ; v2(4.47,23.01) 4.66,23.2 DA5.2 ; PR1507.2 85.95,34.76 v2(85.57,34.37) ; PC1114.2 84.94,68.74 v3(84.61,69.06) v2(84.12,69.56) ; v2(160.53,62.01) 161.49,62.98 RH443.2 ; C616.2 190.48,47.17 v2(189.92,47.74) ; v2(57.75,71.72) 57.75,71.95 58.1,72.31 JCAM.6 ; v2(180.72,54.44) 180.23,54.44 179.86,54.07 CC8.1 ; v2(21.99,62.52) 22.3,62.52 22.97,61.86 R1473.2 ; v2(157.21,57.16) 156.64,57.16 RC19.2 ; v2(25.3,52.12) 24.96,52.46 CT163.2 ; C617.2 v2(189.84,51.62) ; U683.3 187.3,40.63 187.7,41.03 v2(187.7,41.09) ; v2(70.94,74.96) 71.35,74.56 JTS.1 ; CE50.2 178.13,58.48 178.13,57.77 v2(177.8,57.44) 177.98,57.26 177.98,56.6 CE68.2 ; JCAM.3 55.7,74.05 55.8,74.15 v2(55.8,74.61) ; v2(53.09,63.51) 53.7,64.12 54.86,64.12 55.04,64.3 55.04,64.64 55.43,65.03 PQ224.3 ; U729.3 191.95,76.73 192.39,77.17 v2(192.39,77.74) ; v2(48.67,22.87) 48.64,22.89 C376.2 ; v2(179.31,49.79) 179.15,49.79 PC1409.2 179.17,50.99 PC1401.2
  BOTTOM w0.457: v2(69.57,75.27) 69.57,73.38 JTS.8
  BOTTOM w0.508: PC1129.2 v2(87.1,50.76) ; PR283.2 63.12,46.16 63.32,45.96 64.14,45.96 v2(64.24,46.06) ; C1301.2 44.04,35.44 v2(44.04,35.37) ; PR246.2 v2(61.44,63.53) ; PR1099.1 PC1131.1 ; v2(111.96,77.86) 111.86,77.76 CA32.2 ; v2(23.39,17.99) 23.27,18.12 JSPK1.5 ; JEDP.43 196.65,34.12 196.65,33.13 v2(197.23,32.55) ; v2(21.67,50.24) 21.16,50.24 21.02,50.38 C265.2 ; v2(166.6,71.56) 166.89,71.27 JDEG1.12 ; PC1215.2 98.59,62.82 v2(99.04,62.82) ; v2(72.2,58.34) 72.12,58.25 PC1074.2 ; C1274.2 58.79,57.9 57.05,57.9 v2(56.93,58.02) ; v2(27.26,21.7) 26.9,22.06 CA3.2 ; C398.1 C401.1 ; v2(95.3,36.53) 95.63,36.86 PC1510.2 ; v2(197.71,44.31) 196.65,43.24 196.65,43.02 JEDP.44 ; v2(67.56,79.38) 68.04,79.86 69.7,79.86 JTS.7 ; CD156.2 123.06,20.89 v2(122.71,21.24) ; CA98.2 35.5,26.87 v2(34.6,27.77) ; JFAN1.1 166.48,18.37 166.85,17.99 v2(166.85,17.74) ; v2(67.18,71) 66.78,70.6 CC32.2 ; CA112.2 31.13,22.82 CA2.2 ; PC1238.2 98.4,74.08 v2(98.43,74.1) ; JDEG1.11 175.66,71.86 v2(175.66,72.75) ; PC107.2 32.21,78.72 v2(32.36,78.57) 32.56,78.77 PC106.2 ; v4(141.73,46.31) 141.71,46.29 CC27.2 ; v2(185.78,75.75) 186.25,75.28 186.25,74.27 JLPDE1.11 ; v2(34.6,30.21) 33.99,30.21 CA30.1 ; CE10.2 CE3.2 28.27,17.66 v2(28.85,18.25) ; RE66.2 CE59.2 174.91,60.46 v2(174.92,60.45) ; v2(67.75,65.53) 67.92,65.7 PC1086.2 66.97,66.32 PC209.2 66.59,66.51 PU202.2 ; JCAM.8 53.25,76.03 v2(53.25,76.86) ; v2(98.27,65.41) 98.27,65.36 98.3,65.33 PC1309.2 ; v2(21.18,48.71) 21.55,48.35 C303.2 22.69,48.35 21.52,49.51 v2(21.44,49.51) ; 22.04,78.86 JP100.6 ; 22.04,78.86 v2(19.86,78.86) ; 22.04,78.86 22.04,78.86 22.41,78.5 22.41,78.49 22.02,78.1 v2(19.88,78.1) ; JNGFF1.69 50.85,39.55 50.85,40.91 v2(51.22,41.28) ; PR509.2 65.38,37.68 v2(65.27,37.57) ; RC48.2 146.03,43.75 v2(146.2,43.57) ; SW1.5 160.32,45.75 v2(160.17,45.6) ; CA97.2 32.74,26.15 32.28,25.69 v2(32.11,25.69) ; v2(83.67,24.95) PR1517.2 ; PC1517.2 83.62,31.53 v2(83.92,31.84) ; v2(22.28,27.15) 22.29,27.16 22.29,27.42 CA83.2 ; v2(30.28,41.79) 30.15,41.66 JNGFF1.68 ; v2(187.88,17.56) 188.76,16.68 JTP1.9 ; C3.2 21.39,51.27 v2(21.64,51.01) ; DA1.1 17.25,36.56 H22.1 ; JTP1.10 181.06,16.31 v2(181.06,17.91) ; v2(183.36,54.21) 183.36,54.54 183.49,54.67 CE56.2 ; RE82.1 187.17,58.68 CE43.2 186.56,59.44 v2(186.54,59.42) ; v2(157.2,69.86) 156.59,69.25 RH145.1 ; v2(163.81,62.65) PC401.2 PC400.2 ; v2(33.5,34.1) 34.24,33.36 CA6.2 34.35,32.81 34.8,32.37 v2(34.8,31.94) 33.99,31.94 CA7.2 CA104.2 ; JLPDE1.12 177.4,74.27 176.3,73.17 v2(176.3,72.78) ; JEDP.45 195.26,46.27 v2(197.33,48.35) ; JP100.7 v2(24.03,69.09) ; v2(91.54,27.34) 91.03,26.83 PC1519.2 ; CD34.2 v3(116.05,22) v2(116.05,22.61) ; JAPS1.19 203.81,37.99 v2(203.81,38.94) ; v2(179.32,44.64) 180.87,44.64 UH8.4 ; v2(94.95,42.81) 94.36,43.39 PC1503.2 ; v2(166.83,47.2) 168.33,47.2 SW1.4 ; v2(167.97,14.18) 168.08,14.07 JFAN1.5 ; CD58.2 v2(143.74,21.2) ; C4.2 C1221.2 55.42,69.25 v2(56.06,69.25) 56.74,69.25 DI3.1 ; v2(60.43,58.31) 60.81,58.7 PC203.2 ; PC1119.2 v2(87.08,58.38) ; v2(187.4,54.87) 187.4,55.28 CE65.2 186.89,55.79 CE22.2 ; v2(88.37,33.21) 88.37,33.21 89.14,33.21 PC1515.2 ; v2(78.59,52.71) 78.59,52.32 PC1109.2 79.32,52.29 v2(79.32,52.74) ; v2(78.03,24.22) 78.21,24.39 PC100.2 ; PC1239.2 v2(97.13,73.95) ; JEDP.42 196.65,25.22 196.05,25.22 v2(195.43,24.6) ; v2(150.01,21.19) 149.58,20.76 CD64.2 ; v2(81.13,28) 81.36,27.77 PR1518.2 ; v2(204.65,61.65) 204.42,61.43 PC700.2 ; PC701.2 201.88,56.19 v2(201.65,55.97) ; CD181.2 121.16,21.41 v3(120.46,22.1) v2(119.67,22.89) ; v2(82.26,32.64) 82.26,32.01 PC1513.2 ; CC9.2 186.98,51.57 v3(187.62,50.94) 187.62,50.64 v2(187.3,50.33) ; PR1526.2 88.21,34.93 v2(87.5,34.22) ; JCAM.7 59.46,75.52 v3(61.01,75.52) 61.44,75.52 61.69,75.28 v2(61.69,74.91) ; PC1005.2 64.62,57.11 64.62,57.21 64.12,57.71 v2(64.12,57.76) ; v2(140.92,21.14) 140.54,20.76 CD89.2 CD183.2 ; CS44.2 188.19,38.19 187.82,38.56 v2(187.82,38.55) ; DI4.1 73.48,75.27 v2(73.05,74.84) ; CE4.2 v2(29.38,20.39) ; v2(68.99,60.05) 69.11,60.05 69.52,59.65 PC1091.2 ; PC403.2 165.58,62.95 v2(165.94,62.59) ; v2(68.12,71) 67.67,70.54 CC29.2 ; v2(173.79,45.09) 174.12,45.42 RH56.1 ; JAPS1.20 203.81,25.29 v2(205.39,25.29) ; CD171.2 153.04,21.68 v2(153.31,21.95) ; v2(193.84,23.01) 193.84,22.83 JEDP.41 ; PC1237.2 128.5,76.89 v2(128.52,76.92) ; CD88.2 159.11,21.17 v2(159.36,21.42) ; PC1064.1 71.6,55.84 v2(72.09,56.32) ; v2(10.82,6.78) 10.82,6.79 11.51,6.1 ; C397.1 C402.1 9.32,62.47 v2(9.1,62.69) ; v2(84.56,24.92) PC1520.2 PR1527.2 ; v2(65.23,51.11) 65.1,50.99 PC1004.2 ; v2(137.85,21.21) 137.77,21.13 CD62.2 ; PC312.2 47.35,31.71 47.57,31.93 v2(47.57,32.33) ; v2(10.28,6.37) 10.28,6.4 10.82,5.86 JRTC1.3 11.51,6.1 ; PC1312.2 75.34,66.96 v2(75.34,65.49) ; 11.51,6.1 v2(11.51,7.09) ; PC1098.1 PC1019.1 v2(67.79,45.45) ; v2(68.2,60.05) 68.17,60.03 PC1087.2 ; v2(20.75,59.09) 20.79,59.14 RT200.2 ; v2(76.43,55.84) 76.33,55.94 PC1083.2 ; v2(74.91,80.04) 75.06,79.89 75.06,79.59 C1222.2 C5.2 ; CD85.2 134.44,20.68 v2(133.99,21.14) ; CC240.2 100.28,45.47 99.67,45.47 v2(99.64,45.45) ; JFAN1.6 169.5,19.67 170.84,19.67 v2(171.4,19.11) ; JUART.6 51.64,23.07 v2(51.28,23.07) ; CD41.2 v2(118.44,21.19) ; v2(155.92,21.39) 155.78,21.26 CD177.2 CD184.2 ; PC1214.2 v2(98.34,60.92) ; v2(95.86,73.95) PC1241.2 ; RH147.1 159.77,67.04 v2(159.82,67.09) ; v2(16.51,20) v3(16.51,21.22) 16.51,22.46 17.25,23.2 DA2.1 ; v2(204.6,60.54) PR701.2 ; CC4.1 CC5.1 158.6,47.35 158.5,47.46 v2(158.5,48.01) ; CC266.2 143.61,44.48 v2(144.17,43.93) ; PR1071.1 PC1065.1 ; RH442.2 RH443.2 ; 14.02,11.75 v2(12.55,11.01) ; v2(92.81,42.73) PC1504.2 ; PC1420.2 PR1422.2
  vias: v2(3.4,0.85) v2(4.47,23.71) v2(4.93,67.44) v2(7.06,65.74) v2(7.21,12.61) v2(7.72,12.91) v2(7.68,3.01) v2(8.26,13.17) v2(11.5,58.78) v2(11.5,56.83) v2(12.8,52.41) v2(13.18,20.16) v2(13.83,72.61) v2(13.89,64.71) v2(13.89,62.58) v2(13.96,54.81) v2(14.16,20.12) v2(14.59,54.81) v2(15.19,54.82) v2(15.82,54.82) v2(16.03,7.29) v2(16.1,37.68) v2(16.28,51.67) v2(16.26,39.11) v2(16.36,79.97) v2(16.42,55.97) v2(16.49,56.73) v2(17.36,54.84) v2(17.88,43.27) v2(17.88,42.63) v2(17.88,42) v2(18.19,57.14) v2(18.59,79.99) v2(20.8,21.17) v2(20.9,52.34) v2(21.13,79.99) v2(21.3,13.47) v2(21.39,21.22) v2(21.52,52.34) v2(21.91,13.47) v2(22.54,13.47) v2(23.6,60.47) v2(23.69,79.99) v2(24.17,76.55) v2(24.21,75.97) v2(24.19,75.37) v2(24.19,74.79) v2(24.2,60.47) v2(24.64,38.37) v2(24.78,76.55) v2(24.79,75.94) v2(25.02,60.46) v2(26.26,79.97) v2(26.39,31.2) v2(26.39,29.68) v2(26.39,27.77) v2(27.66,31.2) v2(27.66,29.68) v2(27.66,27.77) v2(28.24,48.92) v2(28.8,79.97) v2(28.84,48.71) v2(28.8,31.2) v2(28.8,29.68) v2(28.8,27.87) v2(29.21,74.04) v2(29.47,52.34) v2(29.46,51.06) v2(29.46,49.96) v2(29.85,74.03) v2(29.95,56.04) v2(30.01,53.93) v2(30.46,74.38) v2(31.18,21.94) v2(31.31,79.99) v2(31.47,62.98) v2(31.79,21.94) v2(32.11,41.87) v2(32.92,41.87) v2(33.78,79.99) v2(33.99,63.61) v2(34.16,41.87) v2(35.88,64.88) v2(35.92,42.5) v2(36.32,79.99) v2(36.98,42.5) v2(37.95,42.5) v2(38.43,35.11) v2(38.93,79.99) v2(40.89,35.42) v2(41.02,12.7) v2(41.45,79.99) v2(43.99,79.99) v2(45.89,68.92) v2(46.55,81.48) v2(46.58,27.62) v2(46.59,26.99) v2(47.16,68.97) v2(48.64,12.7) v2(48.7,68.6) v2(48.95,81.48) v2(50.01,41.87) v2(50.99,64.07) v2(51.03,60.46) v2(51.03,58.69) v2(51.05,61.86) v2(51.49,81.48) v2(52.13,80.43) v2(52.43,45.81) v2(52.61,56.73) v2(52.77,80.43) v2(53.14,61.93) v2(53.14,49.16) v2(53.06,45.87) v2(53.19,48.47) v2(53.19,47.84) v2(53.19,47.14) v2(53.19,46.5) v2(53.4,80.43) v2(54.17,81.48) v2(55.24,49.33) v2(55.24,48.74) v2(55.21,48.16) v2(55.22,47.57) v2(56.78,81.48) v2(58.57,38.3) v2(59.16,38.31) v2(59.32,81.48) v2(59.91,12.7) v2(60.3,56.6) v2(61.16,42.36) v2(61.79,81.48) v2(63.48,42.5) v2(63.88,62.78) v2(64.41,81.5) v2(66.52,41.74) v2(66.52,41.11) v2(66.95,81.5) v2(67.16,41.74) v2(67.16,41.11) v2(67.16,40.47) v2(67.45,64.92) v2(67.53,12.7) v2(67.56,63.15) v2(67.68,64.36) v2(67.67,54.7) v2(67.67,52.28) v2(67.79,41.74) v2(67.79,41.11) v2(67.79,40.47) v2(68.49,65.53) v2(68.56,41.74) v2(68.56,41.11) v2(68.56,40.47) v2(68.56,39.85) v2(68.85,12.68) v2(68.96,53.56) v2(69.19,41.74) v2(69.19,41.11) v2(69.19,40.47) v2(69.2,39.89) v2(69.41,81.48) v2(69.4,16.46) v2(70.21,52.28) v2(70.33,54.7) v2(70.46,12.68) v2(71.32,45.45) v2(71.69,13.12) v2(71.87,45.15) v2(71.96,81.48) v2(72.35,77.34) v2(72.66,77.85) v2(72.82,14.5) v2(74.5,81.48) v2(75.04,14.5) v2(75.18,35.54) v2(75.18,34.91) v2(75.22,20.97) v2(75.21,19.95) v2(75.29,37.68) v2(75.53,20.45) v2(75.81,35.54) v2(75.81,34.91) v2(75.85,20.98) v2(75.82,19.95) v2(76.13,20.46) v2(76.23,21.47) v2(76.43,19.95) v2(76.49,20.95) v2(76.77,20.44) v2(76.86,22.76) v2(76.85,22.12) v2(76.86,21.46) v2(77.03,81.48) v2(78.16,21.71) v2(78.16,20.97) v2(79.65,28.36) v2(80.05,39.15) v2(80,37.43) v2(80.02,36.84) v2(80.02,36.22) v2(80.38,39.63) v2(80.42,38.69) v2(80.62,37.46) v2(80.62,36.85) v2(80.6,36.19) v2(80.75,39.17) v2(81.12,39.67) v2(81.09,38.69) v2(81.22,37.46) v2(81.21,36.84) v2(81.23,36.21) v2(81.45,39.18) v2(81.49,41.21) v2(81.47,40.62) v2(81.64,58.3) v2(81.61,44.99) v2(81.62,44.39) v2(81.59,43.23) v2(81.61,42.64) v2(81.62,42.06) v2(81.74,60.64) v2(81.74,60.05) v2(81.74,59.47) v2(81.74,58.89) v2(81.83,49.15) v2(81.83,48.54) v2(81.83,47.95) v2(81.8,47.37) v2(81.8,46.78) v2(81.8,46.2) v2(81.75,39.68) v2(81.77,38.69) v2(81.77,37.12) v2(81.8,36.35) v2(81.92,56.87) v2(81.92,56.26) v2(81.92,55.66) v2(81.92,55.05) v2(81.92,54.42) v2(82.02,65.11) v2(82.02,64.52) v2(82.02,63.94) v2(82.02,63.36) v2(82.02,62.77) v2(82.02,62.19) v2(82.04,57.87) v2(82.13,40.62) v2(82.19,45.44) v2(82.23,44.86) v2(82.16,41.2) v2(82.43,40.1) v2(82.43,36.51) v2(82.53,74.79) v2(82.53,55.05) v2(82.6,65.11) v2(82.6,64.52) v2(82.6,63.94) v2(82.6,63.36) v2(82.6,62.77) v2(82.6,62.19) v2(82.55,56.87) v2(82.55,56.26) v2(82.55,55.66) v2(82.58,54.42) v2(82.59,49.15) v2(82.57,48.55) v2(82.59,47.95) v2(82.56,47.37) v2(82.56,46.78) v2(82.56,46.2) v2(82.65,57.87) v2(82.67,33.72) v2(82.7,33.1) v2(82.66,14.5) v2(82.78,45.42) v2(82.81,44.84) v2(82.8,41.2) v2(82.78,40.61) v2(82.93,52.55) v2(82.97,51.95) v2(83.12,40.11) v2(83.07,36.51) v2(83.19,65.69) v2(83.19,65.11) v2(83.19,64.52) v2(83.19,63.94) v2(83.19,63.36) v2(83.19,62.77) v2(83.19,62.19) v2(83.24,58.05) v2(83.19,56.87) v2(83.19,56.26) v2(83.19,55.66) v2(83.17,55.05) v2(83.21,54.42) v2(83.22,49.15) v2(83.22,48.54) v2(83.22,47.95) v2(83.2,47.37) v2(83.2,46.78) v2(83.2,46.2) v2(83.26,60.61) v2(83.26,60.03) v2(83.26,59.42) v2(83.26,58.78) v2(83.41,45.42) v2(83.45,44.84) v2(83.43,41.2) v2(83.44,40.61) v2(83.51,52.88) v2(83.46,52.27) v2(83.47,51.55) v2(83.74,58.45) v2(83.66,36.51) v2(83.82,60.26) v2(83.8,59.67) v2(83.77,59.09) v2(83.82,57.84) v2(83.78,40.1) v2(84.01,52.51) v2(83.95,51.91) v2(84.04,45.28) v2(84.07,41.2) v2(84.1,40.61) v2(84.47,40.15) v2(84.82,40.64) v2(84.94,44.03) v2(84.91,43.44) v2(84.9,42.83) v2(84.9,42.19) v2(84.89,41.46) v2(85.29,16.46) v2(85.45,42.43) v2(85.37,41.82) v2(85.46,43.61) v2(85.49,43.02) v2(85.7,30.31) v2(85.7,29.42) v2(85.93,81.48) v2(86.06,41.49) v2(86.13,29.85) v2(86.64,41.49) v2(86.64,32.17) v2(86.59,30.31) v2(86.59,29.42) v2(87.22,32.17) v2(88.51,81.48) v2(88.88,39.33) v2(88.88,38.44) v2(89.33,38.87) v2(89.72,41.25) v2(89.76,39.33) v2(89.76,38.44) v2(89.77,20.76) v2(90.28,14.5) v2(91.05,81.48) v2(91.49,22.16) v2(92.12,21.54) v2(92.55,20.09) v2(92.72,21.6) v2(92.92,19.56) v2(93.14,20.12) v2(93.31,21.6) v2(93.45,32.88) v2(93.55,81.48) v2(93.74,20.12) v2(93.69,19.54) v2(93.89,21.58) v2(94.29,21.11) v2(94.27,20.51) v2(94.27,19.85) v2(95.83,42.38) v2(95.83,41.79) v2(96.09,81.48) v2(96.87,76.42) v2(98.63,81.48) v2(98.93,76.97) v2(99.54,53.17) v2(99.52,46.14) v2(99.62,52.54) v2(99.75,51.29) v2(99.77,51.9) v2(99.77,50.5) v2(99.83,49.89) v2(99.82,12.71) v2(101.17,81.48) v2(102.19,34.72) v2(102.89,67.14) v2(103.71,81.48) v2(104.08,67.14) v2(105.39,12.71) v2(106.15,49.39) v2(106.25,81.48) v2(107.16,57.87) v2(108.15,48.07) v2(108.79,81.48) v2(108.76,49.87) v2(108.86,59.11) v2(109.02,57.84) v2(109.22,55.91) v2(111.33,81.48) v2(112.67,44.36) v2(113.81,46.7) v2(113.76,44.87) v2(113.87,81.48) v2(115.94,12.7) v2(116.23,43.34) v2(116.41,81.48) v2(118.09,45.3) v2(118.09,43.52) v2(118.11,41.03) v2(118.95,81.48) v2(119.14,62.7) v2(119.28,46.47) v2(119.91,43.8) v2(119.91,41.97) v2(120.02,64.37) v2(120.58,76.02) v2(120.8,58.81) v2(121.08,43.87) v2(121.28,64.44) v2(121.49,81.48) v2(122.07,58.81) v2(122.17,76.36) v2(122.56,64.42) v2(122.81,74.15) v2(123.24,61.86) v2(123.37,58.81) v2(123.56,12.7) v2(123.83,64.55) v2(124.03,81.48) v2(124.51,61.86) v2(124.64,58.81) v2(124.69,74.61) v2(125.12,64.55) v2(125.3,44.41) v2(125.81,61.86) v2(125.93,58.81) v2(126.37,64.52) v2(126.57,81.48) v2(126.72,76.69) v2(127.08,47.13) v2(127.08,45.27) v2(129.11,81.48) v2(129.33,75.06) v2(129.31,47.61) v2(129.95,62.85) v2(130.48,43.9) v2(130.45,41.54) v2(130.86,45.98) v2(131.65,81.48) v2(131.83,62.88) v2(132.23,45.98) v2(132.23,44.15) v2(132.26,42.33) v2(133.91,43.14) v2(134.19,81.48) v2(135.27,12.7) v2(135.61,60.21) v2(135.66,65.62) v2(135.66,60.87) v2(135.99,62.7) v2(136.6,47.3) v2(136.58,46.11) v2(136.6,44.28) v2(136.6,42.53) v2(136.73,81.48) v2(138.07,47.23) v2(138.13,44.31) v2(139.27,81.48) v2(139.73,45.04) v2(140.51,74.58) v2(141.5,74) v2(141.66,77.76) v2(141.81,81.48) v2(142.24,77.76) v2(142.89,12.7) v2(143.33,77.76) v2(143.92,77.76) v2(143.87,74.84) v2(144.35,81.48) v2(145.1,77.76) v2(145.69,77.76) v2(146.3,74.13) v2(146.89,81.48) v2(148.4,59.58) v2(149.43,81.48) v2(150.51,12.7) v2(151.97,81.48) v2(154.06,57.47) v2(154.23,55.89) v2(154.51,81.48) v2(157.05,81.48) v2(158.13,12.7) v2(159.59,81.48) v2(162.13,81.48) v2(164.67,81.48) v2(165.75,12.7) v2(165.91,30.9) v2(165.87,30.18) v2(165.91,29.58) v2(166.59,81.5) v2(166.67,36.19) v2(166.87,36.74) v2(166.89,35.13) v2(166.99,35.7) v2(167.01,34.55) v2(167.44,44.54) v2(167.44,37.04) v2(167.37,36.43) v2(168.04,44.57) v2(168.04,41.7) v2(168.06,42.57) v2(168.22,39.71) v2(168.89,42.56) v2(168.9,41.71) v2(169.01,32.85) v2(169.02,32.15) v2(169.01,31.45) v2(169.75,81.48) v2(170.31,17.26) v2(171.87,12.72) v2(172.12,77.24) v2(172.29,81.48) v2(172.29,17.28) v2(172.74,77.37) v2(172.73,74.59) v2(172.78,75.43) v2(173.6,75.46) v2(173.59,74.59) v2(173.93,50.38) v2(173.93,49.36) v2(173.97,52.28) v2(174.36,12.71) v2(174.51,50.38) v2(174.46,49.69) v2(174.83,81.48) v2(174.98,50.02) v2(174.98,49.34) v2(176.72,12.71) v2(177.06,81.47) v2(178.66,32.47) v2(179.68,32.47) v2(180.32,63.25) v2(180.34,60.97) v2(180.42,65.54) v2(180.99,12.7) v2(181.51,23.17) v2(182.04,23.5) v2(182.6,65.57) v2(182.61,63.27) v2(182.6,60.99) v2(184.26,42) v2(184.84,61.17) v2(184.91,65.49) v2(184.91,63.23) v2(185.62,43.8) v2(185.78,46.85) v2(185.98,45.33) v2(186.79,81.48) v2(187.2,45.35) v2(188.61,12.7) v2(189.33,81.48) v2(191.87,81.48) v2(194.41,81.48) v2(195.1,65.19) v2(196.13,59.6) v2(196.13,59) v2(196.13,58.42) v2(196.13,54.48) v2(196.09,53.9) v2(196.23,12.7) v2(196.44,53.43) v2(196.71,60.25) v2(196.71,59.61) v2(196.71,59.02) v2(196.71,58.43) v2(196.95,81.48) v2(196.98,40.55) v2(197.22,26.8) v2(197.82,40.35) v2(197.84,35.82) v2(198.35,20.61) v2(198.6,77.17) v2(199.16,41.82) v2(199.49,81.48) v2(199.53,75.09) v2(199.47,74.29) v2(199.7,72.09) v2(199.8,77.22) v2(200.03,74.73) v2(200.54,75.09) v2(200.58,74.33) v2(201.37,73.34) v2(201.52,19.57) v2(201.77,67.08) v2(202.03,81.48) v2(202.11,16.19) v2(202.73,14.73) v2(202.92,67.78) v2(203.33,21.19) v2(203.61,14.81) v2(203.85,12.7) v2(204.06,67.4) v2(204.21,14.8) v2(204.57,81.48) v2(204.65,16.32) v2(205.07,22.49) v2(205.41,16.29) v2(205.7,75.44) v2(205.7,67.82) v2(205.7,60.2) v2(205.7,52.58) v2(205.7,44.96) v2(205.92,37.35) v2(206.25,16.47) v2(206.45,14.66) v2(206.91,22.47) v2(207.21,14.71) v2(207.75,30.21) v2(210.76,24.56) v2(211.47,12.7) v2(212.64,20.04) v3(11.85,55.52) v3(12.15,22.21) v3(27.05,28.94) v3(29.38,53.3) v3(29.52,31.36) v3(48.95,18.38) v3(52.43,48.41) v3(52.93,36.52) v3(53.05,37.9) v3(65.06,41.49) v3(68.28,53.95) v3(69.22,51.78) v3(69.73,64.38) v3(75.51,22.25) v3(76.29,35.2) v3(81.9,33.47) v3(81.97,38.06) v3(83.22,57.43) v3(83.19,42.8) v3(83.92,49.88) v3(84.84,30.19) v3(91.11,19.9) v3(100.33,50.44) v3(103.23,66.57) v3(137.47,79.07) v3(194.12,52.5) v3(195.29,60.63) v3(201.38,74.29) v4(51.82,37.68) v4(51.92,35.37) v4(51.92,34.73) v4(51.92,34.1) v4(51.92,33.46) v4(51.92,32.83) v4(51.92,32.19) v4(52.11,37.03) v4(52.45,37.68) v4(53.09,37.25) v4(56.3,23.62) v4(56.95,23.63) v4(57.58,23.63) v4(58.22,23.63) v4(59.79,28.03) v4(59.79,27.26) v4(59.82,25.05) v4(59.83,24.39) v4(60.91,23.1) v4(61.32,28.03) v4(61.32,27.26) v4(61.32,25.23) v4(61.32,24.47) v4(61.54,23.1) v4(62.84,28.03) v4(62.84,27.26) v4(67.41,29.68) v4(67.41,29.04) v4(68.75,28.96) v4(69.57,29.04) v4(72.24,28.91) v4(73,28.91)
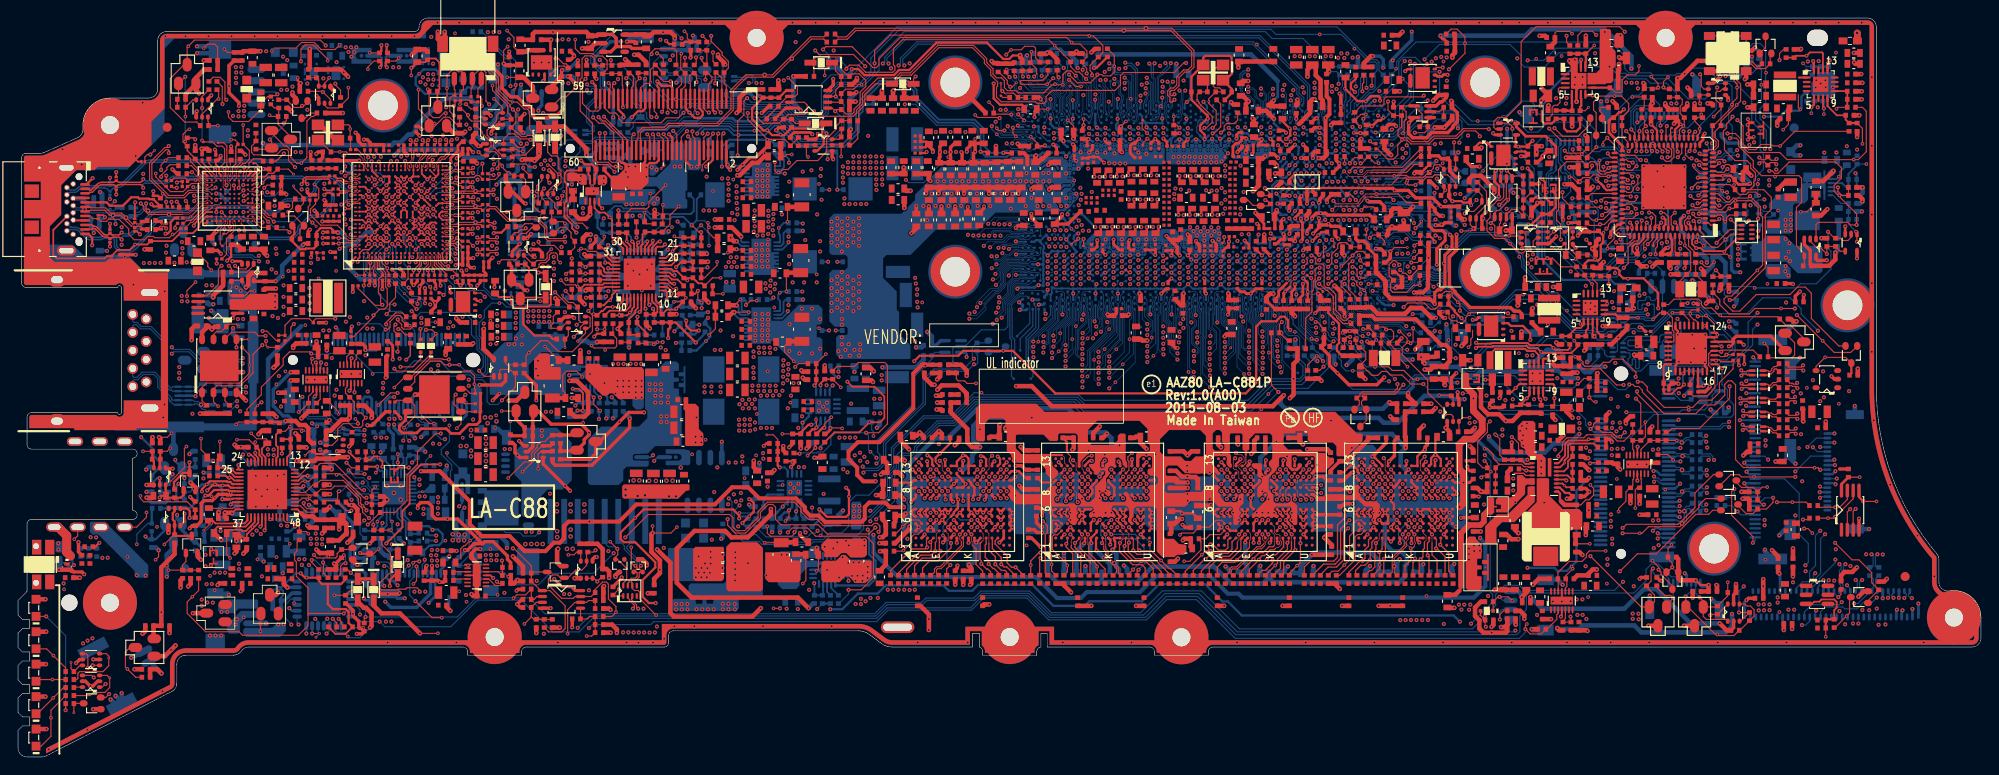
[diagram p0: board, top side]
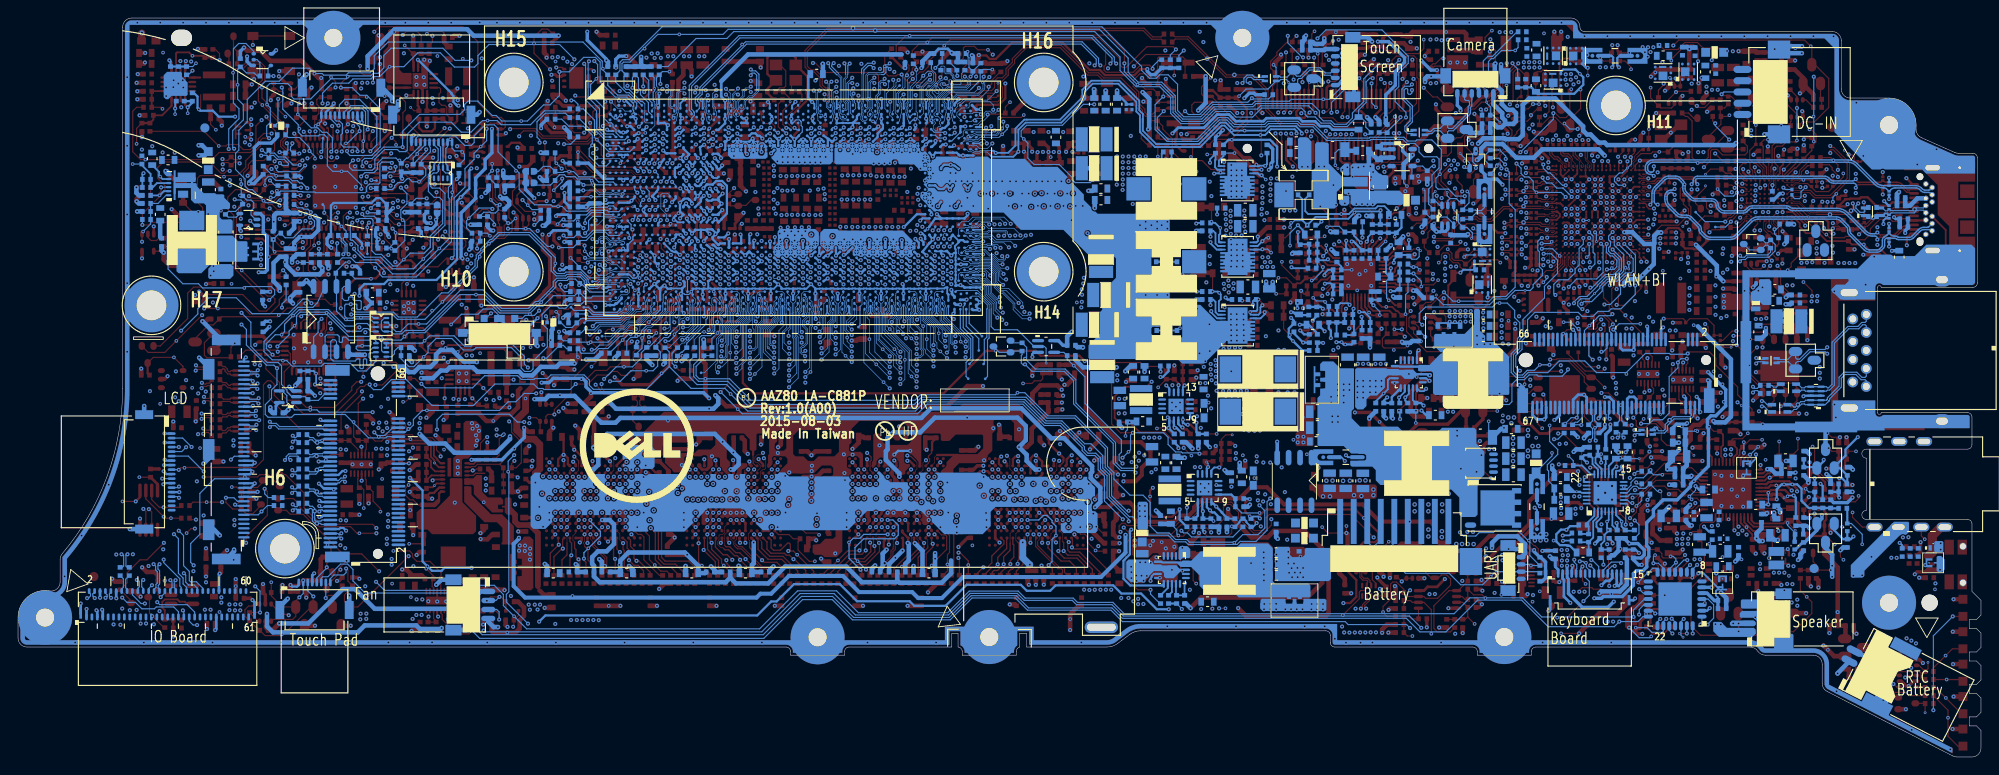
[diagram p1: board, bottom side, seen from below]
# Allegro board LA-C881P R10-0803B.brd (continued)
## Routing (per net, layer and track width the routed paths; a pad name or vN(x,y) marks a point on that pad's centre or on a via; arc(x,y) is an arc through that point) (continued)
GNDA_CHG: length 41.1
  TOP w0.381: v2(39.01,23.68) 39.47,24.14 PC331.2
  TOP w0.508: PR322.2 40.41,28.03 v4(40.94,28.55) 40.58,28.91 PC332.2 ; v2(37.64,21.32) 37.13,21.84 PQ302.3
  IN3 w0.508: v2(46,25.21) 45.11,24.32 39.65,24.32 v2(39.01,23.68) ; v2(45.19,33.87) 44.81,34.25 40.68,34.25 v2(40.23,33.8)
  IN4 w0.508: v2(46,25.21) 45.97,25.23 44.3,25.23 42.62,26.91 42.62,28.39 v4(42.46,28.55)
  BOTTOM w0.254: PC311.2 44.76,25.61 45.59,25.61 v2(46,25.21) 46.03,25.23 46.61,25.23 47.12,24.72 47.12,23.91 46.71,23.5 45.97,23.5 45.92,23.45 45.78,23.45 45.75,23.43 45.61,23.43 PC309.1
  BOTTOM w0.381: PC331.2 39.47,24.14 v2(39.01,23.68) 38.08,23.68 37.36,22.97 37.36,22.44 37.72,22.08 38.56,22.08 PR310.1 38.58,21.9 38,21.32 v2(37.64,21.32)
  BOTTOM w0.508: v2(45.19,33.87) 44.92,34.13 PC334.1 44.06,34.38 PC336.2 ; PR317.2 40.97,22.39 40.73,22.39 40.21,22.9 40.21,24.11 PC318.1 PC331.2 ; v2(40.23,33.8) 40.49,34.06 PC337.2
  vias: v4(40.94,30.07) v4(41.7,29.31) v4(42.46,30.07)
VBUS_ACOK: length 83.8
  TOP w0.127: PQ220.1 57.07,20.53 PR261.2 ; PR263.2 58.88,13.88 60.33,13.88 60.71,14.26 60.71,16.77 59.02,18.46 PU203.1 58,18.46 PC217.1 PR261.2 ; v2(54.92,23.15) 55.02,23.15 56.95,21.22 PR261.2 ; PR213.1 59.5,56.76 58.23,56.76 58.23,56.77 57.97,56.77 57.76,56.98 v2(57.76,57.17) ; v2(56.46,68.06) 56.06,67.65 55.46,67.65 54.84,68.27 PR248.1
  IN4 w0.081: v2(56.46,68.06) 56.74,67.78 56.74,59.9 57.76,58.89 v2(57.76,57.17) 57.76,56.46 51.48,50.17 50.62,50.17 49.75,49.3 49.75,47.48 48.29,46.02 48.29,42.81 42.07,36.59 42.07,33.35 42.57,32.85 42.57,31.52 43.7,30.38 43.7,27.32 44.68,26.35 52.07,26.35 54.92,23.5 v2(54.92,23.15)
VBUS_HV_DIS#: length 143.6
  TOP w0.127: v2(129.6,77.01) 129.34,77.01 128.28,75.95 122.69,75.95 122.33,75.59 122.33,74.58 121.71,73.97 114.75,73.97 114.08,73.3 114.08,72.75 113.85,72.53 113.08,72.53 112.9,72.71 109.09,72.71 108.57,73.23 108.57,74.33 108.7,74.45 108.7,74.9 107.93,75.67 107.93,76.26 107.23,76.96 107.23,77.39 105.91,78.7 102.16,78.7 99.12,75.66 98,75.66 97.04,74.7 PD206.1 95.12,74.7 93.95,73.53 93.95,72.35 93.29,71.69 93.29,70.71 PR287.1 93.18,68.61 92.47,67.9 PR274.2 ; UE5.B2 186.82,59.77 186.74,59.85 186.18,59.85 185.88,60.14 v2(185.88,60.28)
  IN1 w0.081: v2(174.99,78.09) 172.27,78.09 171.91,77.73 166.56,77.73 v2(166.35,77.52)
  IN3 w0.089: v2(166.35,77.52) 166.06,77.82 160.52,77.82 159.74,77.05 157.71,77.05 157.33,76.67 157.33,76.23 156.32,75.22 154.25,75.22 154.04,75.44 153.2,75.44 153.01,75.44 151.66,76.79 145.9,76.79 145.55,77.14 140.87,77.14 139.97,78.05 130.42,78.05 129.6,77.24 v2(129.6,77.01) ; v2(174.99,78.09) 177.33,75.76 184.61,75.76 185.42,74.95 189.76,74.95 193.17,71.54 193.17,71.02 194.96,69.22 194.96,67.17 193.85,66.06 193.85,62.69 192.94,61.78 192.94,61.07 192.39,60.52 192.09,60.52 190.11,58.54 187.89,58.54 187.07,59.37 187.07,59.46 186.64,59.88 186.28,59.88 v2(185.88,60.28)
VBUSSENSE: length 3.1
  TOP w0.127: v2(149.99,57.59) 150.32,57.93 RC20.1 151.61,57.29 v1(151.61,56.92)
  BOTTOM w0.127: v2(149.99,57.59) 149.99,58.02 UCPU1.AG4
VCC0V9_LVR_OUT: length 5.2
  TOP w0.203: UT1.J11 41.2,59.87 v2(40.87,60.19) 40.55,59.87 UT1.H11 ; UT1.H18 v2(40.22,62.79) 40.22,62.79 UT1.F18
  TOP w0.254: v2(31.97,65.23) 32.05,65.31 CT97.1 CT96.1 CT95.1 CT98.1
VCC0V9_SVR: length 4.1
  TOP w0.203: v2(39.58,60.84) 39.25,60.52 UT1.E12 ; v2(39.58,60.84) 39.25,61.17 UT1.E13 ; v2(39.58,60.84) 39.9,61.17 UT1.F13 ; UT1.F12 39.58,60.19 v2(39.58,60.19) 39.58,60.19 UT1.F11 ; UT1.F15 v2(39.58,61.49)
  TOP w0.229: v2(42.18,59.54) 42.5,59.22 UT1.M9 ; UT1.J9 41.2,59.22 v2(41.52,59.54) 41.85,59.22 UT1.L9
  vias: v2(32.33,52.04) v2(32.35,51.21) v2(32.36,50.37) v2(32.36,49.61) v2(36.16,60.28) v2(36.25,59.69) v2(36.36,59.09) v3(33.35,53.09)
VCC1V8A_TBT_LDO: length 7
  TOP w0.127: RT201.2 18.31,68.25 18.31,69.1 18.85,69.64 v3(19.03,69.64)
  TOP w0.152: RT201.2 18.78,67.3 19.66,66.41 CT151.1 19.66,66.24 20.55,65.35 20.68,65.35 21.4,64.64 21.4,64.59 U722.K1
VCC1V8D_TBT_LDO: length 5.3
  TOP w0.127: v1(30.57,64.66) 30,65.24 CT152.1
  TOP w0.152: U722.A2 26.27,63.97 26.68,64.39 27.39,64.39 27.79,64.78 28.35,64.78 CT152.1
VCC3V3_TBT_LDO: length 106.1
  TOP w0.203: U722.G1 23.01,64.48 23.01,65.19 v2(22.91,65.29)
  TOP w0.305: RT17.1 RT16.1 RT18.1 51.26,38.25 51.26,37.25 50.9,36.89 49.99,36.89 49,35.9 48.06,35.9 47.52,36.43 44.73,36.43 44.26,35.96 42.66,35.96 42.31,36.31 42.31,36.71 43,37.39 43,38.05 UT5.8
  TOP w0.381: v2(29.78,62.42) 29.63,62.57 R1460.1 R1454.1 29.24,63.51 R1475.1 ; v2(38.76,36.81) 38.79,36.79 39.27,36.79 40.79,38.31 CT47.1 ; v2(17.13,65.21) 17.62,64.73 R1478.1
  TOP w0.508: R1474.1 R1477.1 v2(20.19,38.11) ; R1476.1 21.81,47.75 v2(21.51,47.46) 21.13,47.84 C1346.1 20.88,47.6 20.42,47.14 UT6.8
  IN1 w0.508: v2(20.19,38.11) 21.51,39.43 v2(21.51,47.46)
  IN2 w0.508: v2(22.91,65.29) 23.54,65.29 24.38,66.13 27.31,66.13 28.36,65.07 28.36,63.84 v2(29.78,62.42)
  IN3 w0.381: v2(20.19,38.11) 24.09,42.01 25.31,42.01 25.63,42.33 27.13,42.33 28.27,41.18 31.52,41.18 32.36,40.34 32.36,39.81 32.82,39.35 33.42,39.35 34.58,38.19 37.31,38.19 38.68,36.81 v2(38.76,36.81)
  IN3 w0.508: v2(22.91,65.29) 21.82,66.38 18.3,66.38 v2(17.13,65.21) 16.55,65.8 15.62,65.8 15.09,65.27 15.09,63.98 15.81,63.25 15.81,61.2 16.31,60.7 18.03,60.7 18.79,59.94 20.78,59.94 21.41,59.31 21.41,58.85 21.17,58.61 21.17,57.56 v2(21.82,56.9)
  IN4 w0.508: v2(21.51,47.46) 22.71,48.65 22.71,52.56 21.21,54.06 21.21,56.32 21.82,56.93 v2(21.82,56.9)
  BOTTOM w0.508: RT199.2 21.55,57.17 v2(21.82,56.9)
VCC3V3_TBT_SX: length 3.3
  TOP w0.076: 21.76,64.66 21.76,64.38 21.92,64.22 22.26,64.22 U722.H2
  TOP w0.152: C1345.1 20.42,66 21.76,64.66
VCC_3V3_PCIE: length 15.7
  TOP w0.203: v2(41.52,62.14) 41.52,62.14 UT1.L16
  TOP w0.381: CT99.1 44.46,69.97 v2(44.76,69.68)
  IN2 w0.381: v2(44.76,69.68) 43.79,69.68 42.98,68.87 42.98,68.11 43.46,67.62 44.78,67.62 45.03,67.37 45.03,66.53 43.56,65.06 42.09,65.06 41.58,64.55 41.58,62.18 41.53,62.13 v2(41.52,62.14)
  BOTTOM w0.127: v3(46.22,70.3) 45.6,69.68 v2(44.76,69.68)
VCC_3V3_USB2: length 6.5
  TOP w0.127: v2(40.27,66.61) 39.73,67.15 CT100.1 ; UT1.J16 40.88,62.14 v2(40.87,62.14)
  IN4 w0.081: v2(40.27,66.61) 40.54,66.34 40.54,66.23 41.34,65.43 41.34,62.61 40.87,62.14 v2(40.87,62.14)
VCC_EDRAM_SENSE: length 49.9
  IN2 w0.102: v2(89.05,34.27) 89.05,34.2 88.67,33.82 88.24,33.82 87.99,34.07 87.99,34.96 87.61,35.34 87.61,37.03 88.3,37.73 92.2,37.73 92.53,37.4 96.78,37.4 98.44,39.05 98.44,42.21 102.56,46.34 104,46.34 107.36,49.7 107.36,51.11 108.2,51.95 108.71,51.95 108.97,52.21 108.97,54.15 109.54,54.72 110.43,54.72 112.52,56.82 112.52,57.99 113.78,59.24 116.43,59.24 116.6,59.42 116.6,59.46 116.69,59.55 116.69,59.83 116.46,60.05 v2(116.46,60.21)
  BOTTOM w0.254: v2(89.05,34.27) 89.05,34.44 89.51,34.89 PR1509.2 ; v2(116.46,60.21) 116.46,60.45 UCPU1.AC63
VCC_EOPIO_SENSE: length 53.4
  IN2 w0.102: v2(116.08,55.64) 115.58,56.14 113.41,56.14 112.14,54.87 112.14,53.6 110.97,52.43 110.59,52.43 109.58,51.42 109.58,48.45 106.5,45.37 104.29,45.37 103.61,44.69 102.78,44.69 99.72,41.63 99.72,38.36 97.03,35.67 94.64,35.67 94.36,35.39 93.73,35.39 92.99,36.13 90.8,36.13 90.07,35.4 90.07,34.02 88.63,32.58 88.21,32.58 87.86,32.22 87.86,29.42 87.08,28.64 87.08,25.25 87.4,24.93 v2(87.38,24.93)
  BOTTOM w0.076: UCPU1.AL63 116.59,56.07 v2(116.08,55.64)
  BOTTOM w0.254: PR1520.2 87.22,25.08 v2(87.38,24.93)
VCC_GT_SENSE: length 81
  TOP w0.203: v2(68.73,48.85) 68.68,48.8 PR1093.1 68.68,48.09 69.7,47.08 PC1014.1
  TOP w0.254: RC161.2 109.32,67.01 v2(109.32,67.04)
  IN2 w0.254: v2(68.73,48.85) 68.43,49.16 68.43,49.87 66.52,51.77 66.52,56.6 67.16,57.24 67.16,58.84 67.74,59.42 70.46,59.42 71.55,60.51 71.55,65.49 72.67,66.61 74.19,66.61 75.46,67.88 75.46,69.07 v2(75.36,69.17)
  BOTTOM w0.076: UCPU1.J70 111.99,67.43 111.85,67.29 111.84,67.29 111.84,67.28 111.59,67.17 111.17,67.17 111.01,67.32 109.81,67.32 109.76,67.27
  BOTTOM w0.203: 109.76,67.27 109.55,67.27 v2(109.32,67.04) 107.95,67.04 107.14,67.85 107.14,69.73 106.15,70.72 105.87,70.72 102.18,70.72 99.72,73.19 99.72,74.02 98.7,75.04 95.61,75.04 93.4,72.83 93.4,71.76 92.99,71.36 92.99,69.49 91.52,68.02 86.77,68.02 84.39,70.4 83.8,70.4 82.91,69.5 v3(81.71,69.5) 79.41,69.5 78.93,69.99 76.02,69.99 75.36,69.34 v2(75.36,69.17) ; PC1098.2 PR1093.1 68.68,48.8 v2(68.73,48.85)
VCCIO_SENSE: length 46.9
  TOP w0.203: PR1409.2 172.19,45.37 171.98,45.17 170.6,45.17 v3(170.38,45.39) 170.07,45.7 167.75,45.7 167.52,45.93 163.52,45.93 163.45,45.86 161.89,45.86 161.84,45.91 v2(161.78,45.97)
  TOP w0.254: v2(138.03,55.66) 137.39,56.3 RC165.2
  IN2 w0.254: v2(138.03,55.66) 138.03,55.76 139.55,57.29 139.55,58.38 140.18,59.01 147.55,59.01 148.63,57.93 148.63,56.69 151.7,53.62 151.7,52.45 152.66,51.49 153.17,51.49 155.93,48.73 155.93,47.53 157.5,45.96 158.52,45.96 159.36,45.12 160.56,45.12 161.31,45.86 161.68,45.86 v2(161.78,45.97)
  BOTTOM w0.254: UCPU1.AM23 138.42,56.05 v2(138.03,55.66)
VCCSENSE: length 88.9
  TOP w0.127: RC140.2 135.33,70.67 134.95,70.29 134.13,70.29 133.83,70 133.83,69.63 v2(133.48,69.27)
  TOP w0.203: PR1079.1 PC1090.1 74.88,54.09 PC1132.2 PC1092.1 73.61,54.95 v2(73.03,54.36)
  IN2 w0.089: v2(133.48,69.27) 133.33,69.27 132.94,68.89 132.94,68.46 132.32,67.84 127.6,67.84 127.29,67.53 124.04,67.53 122.88,66.37 120.26,66.37 119.93,66.04 118.84,66.04 118.3,65.5 118.3,64.94 117.96,64.6 117.96,64.35 117.58,63.97 116.43,63.97 114.99,62.52 111.61,62.52 110.91,63.22 100.7,63.22 100.52,63.39 98.24,63.39 97.03,64.6 97.03,66.1 96.09,67.04 83.19,67.04 82.08,65.93 79.74,65.93 79.3,66.38 78.08,66.38 77.62,65.92 77.62,62.09 78.77,60.94 78.77,58.12 77.37,56.73 75.82,56.73 74.05,54.96 73.27,54.96 73.03,54.72 v2(73.03,54.36)
  BOTTOM w0.127: v3(74.27,52.88) 74.13,52.88 73.03,53.98 v2(73.03,54.36) ; v2(133.48,69.27) 133.6,69.27 133.91,69.58 UCPU1.E32
VCCST_EN: length 72.8
  TOP w0.127: v2(158.09,76.51) 157.38,76.51 UZ25.4 ; 198.21,55.59 198.21,54.63 RE103.1 ; 198.21,55.59 198.21,55.87 197.33,56.74 197.33,60.98 197.9,61.55 197.9,64.22 197.61,64.51 193.46,64.51 192.55,65.43 192.55,66.17 190.91,67.81 190.91,68.41 190.65,68.67 v2(189.95,68.67) ; 198.21,55.59 UC13.4
  IN3 w0.089: v2(167.51,77.3) 167.2,76.98 167.2,74.24 164.72,71.76 161.51,71.76 159.26,74.01 159.26,76.46 158.98,76.74 158.31,76.74 v2(158.09,76.51)
  BOTTOM w0.127: v2(189.95,68.67) 189.98,68.67 190.22,68.91 190.22,70.01 189.81,70.42 189.81,72.03 v3(190.18,72.4) 190.18,74.42 189.87,74.74 187.9,74.74 187.48,74.32 187.48,73.3 187.2,73.02 185.33,73.02 183.1,75.26 181.37,75.26 181.05,75.57 178.69,75.57 178.4,75.87 177.83,75.87 177.23,76.46 177.23,77.83 176.42,78.65 170.66,78.65 169.32,77.3 v2(167.51,77.3)
VCCST_PWRGD: length 9
  BOTTOM w0.076: UCPU1.B65 115.04,71.87 115.04,72.09 114.99,72.21 114.99,72.47 115.18,72.66 115.18,73.2 114.47,73.91 112.26,73.91 112.09,74.08
  BOTTOM w0.127: 112.09,74.08 111.05,75.12 111.05,76.01 RC78.2 110.77,76.29 v3(109.7,76.29)
VCCSTG_EN: length 80.8
  TOP w0.254: PR1401.1 177.39,54.26 177.68,53.97 177.68,53.54 178.11,53.12 180.36,53.12 181.99,51.49 v2(181.99,49.79) ; v2(168.05,68.38) 167.54,67.87 RZ75.1 167.5,67.74 166.17,67.74 UZ19.4 166.17,68.92 UC9.4
  TOP w0.381: v2(159.61,57.97) 159.61,56.27 158.83,55.48 158.83,52.27 159.48,51.62 159.48,51.52 161.13,49.87 165.61,49.87 166.01,49.46 166.57,49.46 166.85,49.18 RZ76.1
  IN1 w0.381: v2(159.61,57.97) 159.79,57.79 161.19,57.79 163.66,60.27 163.66,61.33 163.22,61.77 163.22,62.85 164.21,63.84 166.81,63.84 168.52,65.55 168.52,67.9 v2(168.05,68.38)
  IN2 w0.254: v2(159.61,57.97) 159.76,57.97 159.84,57.9 161.27,57.9 163.09,59.72 163.62,59.72 164.06,59.29 164.06,58.75 164.88,57.93 168.56,57.93 169.41,58.78 170.85,58.78 171.31,58.33 172.39,58.33 172.59,58.52 173.07,58.52 173.56,58.03 173.56,57.62 173.53,57.59 173.53,56.78 174.61,55.7 174.61,51.58 176.84,49.35 177.24,49.35 177.75,49.86 177.75,50.89 179.27,52.41 180.67,52.41 181.99,51.09 v2(181.99,49.79)
VIN_1V_PRIM:
  vias: v2(83.17,29.99) v3(80.62,30.95)
VIN_PRIM:
  vias: v3(201.72,78.16)
VIN_VCC_EDRAM:
  vias: v2(85.77,40.1) v3(85.7,39.33)
VIN_VCCIO:
  vias: v2(176.88,50.48) v2(177.04,49.83) v2(177.09,51.7) v3(176.33,50.3)
VSS_EDRAM_SENSE: length 48.6
  TOP w0.127: v2(88.47,34.3) v3(87.61,33.44)
  TOP w0.254: PR1510.2 88.47,34.78 v2(88.47,34.3)
  IN2 w0.102: v2(117.7,59.52) 117.15,59.52 116.84,59.22 116.8,59.22 116.54,58.96 113.89,58.96 112.8,57.87 112.8,56.7 110.54,54.44 109.65,54.44 109.25,54.03 109.25,52.06 108.88,51.7 108.35,51.7 107.64,50.99 107.64,49.58 104.12,46.06 102.82,46.06 98.82,42.06 98.82,38.89 96.94,37.02 92.37,37.02 92.04,37.35 89.7,37.35 89.02,36.67 89.02,36.03 88.47,35.49 v2(88.47,34.3)
  BOTTOM w0.254: v2(117.7,59.52) 117.46,59.77 UCPU1.AE63
VSS_EOPIO_SENSE: length 59.4
  TOP w0.127: v2(86.16,24.95) 86.16,24.78 85.87,24.5 83.49,24.5 83.14,24.85 v3(83.14,25.6)
  IN2 w0.102: v2(117.65,58.1) 116.84,58.1 116.66,57.92 115.88,57.92 115.82,57.97 114.28,57.97 113.37,57.07 113.37,56.66 111.79,55.08 111.79,53.83 110.8,52.84 110.57,52.84 109.2,51.47 108.59,51.47 107.93,50.81 107.93,49.54 103.45,45.07 102.62,45.07 99.33,41.78 99.33,38.58 96.8,36.05 95.1,36.05 94.64,36.51 90.79,36.51 89.73,35.44 89.73,34 88.54,32.81 88.04,32.81 87.63,32.39 87.63,29.52 86.85,28.74 86.85,25.64 v2(86.16,24.95)
  BOTTOM w0.254: PR1521.2 86.34,25.13 v2(86.16,24.95) ; v2(117.65,58.1) 117.48,58.1 117.16,57.78 UCPU1.AJ62
VSS_GT_SENSE: length 81.5
  TOP w0.203: RC163.1 107.44,67.17 v2(106.81,67.17) ; PU1000.6 69.16,51.01 69.16,49.56 v2(68.99,49.39)
  IN2 w0.254: v2(68.99,49.39) 68.81,49.56 68.81,50.12 66.9,52.03 66.9,56.44 67.54,57.08 67.54,58.68 67.9,59.04 70.62,59.04 71.93,60.35 71.93,65.33 72.83,66.23 74.35,66.23 75.87,67.75 75.87,69.12 v2(75.95,69.2)
  BOTTOM w0.076: 109.91,66.76 110.28,67.13 110.96,67.13 111.1,67 111.62,67 112.04,67.17 112.32,67.17 112.58,67.43 UCPU1.J69
  BOTTOM w0.203: v2(68.99,49.39) 68.96,49.36 68.38,49.36 67.77,48.75 PC1022.2 67.77,47.38 PC1019.2 ; 109.91,66.76 109.76,66.61 107.37,66.61 v2(106.81,67.17) 106.81,69.6 106.01,70.39 102.05,70.39 99.39,73.05 99.39,73.89 98.57,74.71 95.74,74.71 93.73,72.69 93.73,71.63 93.32,71.22 93.32,69.35 91.66,67.69 86.64,67.69 84.26,70.07 83.94,70.07 82.89,69.02 v3(79.96,69.02) 79.43,69.02 78.79,69.66 76.15,69.66 75.95,69.45 v2(75.95,69.2)
VSSIO_SENSE: length 47
  TOP w0.203: v2(161.78,45.38) 161.9,45.51 161.97,45.51 161.99,45.53 163.59,45.53 163.66,45.6 167.38,45.6 167.61,45.37 168.58,45.37 v3(169.01,44.95) 169.12,44.84 172.36,44.84 173.08,45.55 PR1410.2
  TOP w0.381: RC167.1 138.28,56.32 v2(138.94,55.66)
  IN2 w0.254: v2(138.94,55.66) 138.94,56.14 139.93,57.13 139.93,58.22 140.34,58.63 147.36,58.63 148.25,57.74 148.25,56.54 151.32,53.46 151.32,52.29 153.25,50.37 153.25,49.63 154.24,48.64 154.73,48.64 155.54,47.83 155.54,47.38 157.34,45.58 158.37,45.58 159.2,44.74 160.72,44.74 161.46,45.48 161.67,45.48 v2(161.78,45.38)
  BOTTOM w0.254: v2(138.94,55.66) UCPU1.AM22
VSSSENSE: length 87.3
  TOP w0.127: RC141.1 133.45,72.46 133.45,69.94 132.72,69.2 v2(132.56,69.2)
  TOP w0.203: PC1099.2 74.85,55.86 PC1092.2 73.28,55.86 v2(73,55.58) 73,55.08 72.49,54.56 71.51,54.56 PU1000.18
  IN2 w0.089: v2(132.56,69.2) 132.51,69.2 132.08,68.77 132.08,68.36 131.78,68.06 127.51,68.06 127.2,67.75 123.95,67.75 122.79,66.58 120.17,66.58 119.84,66.25 118.75,66.25 118.09,65.59 118.09,65.03 117.88,64.83 116.97,64.83 115.57,63.43 100.79,63.43 100.61,63.61 98.32,63.61 97.24,64.69 97.24,66.19 96.18,67.26 83.1,67.26 81.99,66.15 79.83,66.15 79.39,66.59 77.99,66.59 77.41,66.01 77.41,62 78.55,60.85 78.55,58.21 77.28,56.94 75.73,56.94 73.96,55.18 73.25,55.18 73,55.43 v2(73,55.58)
  BOTTOM w0.127: v2(73,55.58) 72.64,55.94 v3(72.64,56.78) ; UCPU1.E33 132.96,69.59 v2(132.56,69.2)
+AC_IN: length 4.4
  TOP w0.381: v2(56.33,61.41) 56.2,61.41 54.89,62.72 PQ213.3
  TOP w0.508: PR233.1 54.13,63.84 54.38,63.59 PQ213.3
  vias: v2(48.97,77.1) v2(48.97,76.51) v2(49.56,77.1) v2(49.56,76.51) v2(50.14,77.1) v2(50.14,76.51) v2(50.72,77.1) v2(50.72,76.51) v2(58.04,65.77) v2(58.32,65.24) v2(58.47,66.18) v2(59.08,66.24) v2(59.46,65.78)
+DC_IN: length 47.5
  TOP w0.127: v2(31.39,77.2) 31.39,78.55 31.88,79.03 32.76,79.03 34.36,77.43 v3(34.36,77.27)
  TOP w0.508: v2(36.62,75.49) v3(36.14,75.97) 35.83,76.29 PR208.1 ; PD204.2 57.81,66.66 v3(57.31,66.16) 57.15,66.32 55.99,66.32 v2(55.93,66.25)
  IN1 w0.508: v2(31.39,77.2) 31.39,77.4 31.81,77.81 35.92,77.81 36.62,77.11 v2(36.62,75.49)
  IN2 w0.508: v2(36.62,75.49) 37.24,74.88 37.24,70.93 41.01,67.15 41.34,67.15 v2(41.76,66.73)
  BOTTOM w0.508: v2(55.93,66.25) 55.87,66.25 55.45,66.67 55.45,67.52 54.95,68.02 53.09,68.02 51.58,66.51 49.61,66.51 48.69,67.43 42.45,67.43 v2(41.76,66.73)
  vias: v2(29.41,77.71) v2(29.87,77.33)
+DC_IN_SS: length 122.1
  TOP w0.508: PR266.1 v2(65.76,13.8) ; v2(39.05,14.35) 39.22,14.53 39.22,15.95 38.62,16.55 38.38,16.55 37.69,17.23 PD301.2
  IN2 w0.508: v2(65.76,13.8) 64.75,13.8 63.51,15.04 54.51,15.04 54.1,15.44 51.61,15.44 50.9,14.73 43.45,14.73 42.87,14.15 39.25,14.15 v2(39.05,14.35) 38.48,14.93 37.95,14.93 37.26,15.62 37.26,15.81 33.4,19.67 31.22,19.67 30.53,20.35 30.53,22.44 31.47,23.37 31.47,24.19 33.15,25.87 33.15,31.76 34.13,32.74 34.13,38.58 33.55,39.15 33.55,42.1 31.55,44.1 31.55,46.23 29.68,48.1 28.17,48.1 27.39,48.88 27.39,52.7 25.79,54.3 25.79,56.85 24.94,57.69 21.79,57.69 21.4,58.08 21.4,59.89 21.29,60 21.29,63.98 21.27,63.99 21.27,65.43 21.86,66.02 22.84,66.02 24.67,67.85 24.67,69.76 25.1,70.2 25.45,70.2 26.23,70.97 33.67,70.97 34.45,71.75 34.45,74.75 33.89,75.3 v2(33.88,75.3)
  BOTTOM w0.127: v2(39.05,14.35) 37.93,13.23 36.73,13.23 v3(36.59,13.38)
+DCIN_JACK: length 12.2
  TOP w0.127: v3(22.89,78.55) 23.25,78.19 PC105.1 ; v3(35.68,79.01) 35.18,78.51 33.64,78.51 32.86,79.29 31.46,79.29 30.84,78.67 28.45,78.67
  TOP w0.508: PC105.1 PC104.1 24.99,78.32 PC103.1 v2(26.9,78.32)
  vias: v2(27.53,78.32) v3(28.17,78.34)
+INV_PWR_SRC:
  vias: v2(193.8,26.3) v2(193.8,25.72) v3(193.88,21.88)
+LCDVDD: length 0.9
  TOP w0.381: 202.16,31.96 202.16,31.96 R289.1
  vias: v2(193.9,35.14) v2(193.91,34.55) v3(197.61,34.27)
+PBATT: length 65.8
  TOP w0.254: PD300.2 41.77,20.16 41.25,19.64 v2(41.25,18.98)
  IN1 w0.254: v2(39.42,33.82) 39.23,33.82 36.36,30.95 36.36,25.02 37.43,23.95 37.43,22.3 38.25,21.47 38.25,20.96 38.74,20.48 39.88,20.48 41.25,19.11 v2(41.25,18.98)
  IN4 w0.406: v2(76.99,24.11) 74.17,24.11 67.01,16.95 65.35,16.95 64.21,15.81 58.88,15.81 55.63,19.06 55.09,19.06 54.74,18.7 54.74,18.11 53.78,17.15 51.34,17.15 49.76,15.58 43.56,15.58 41.25,17.89 v2(41.25,18.98)
  BOTTOM w0.254: v2(39.42,33.82) 39.22,34.02 PR324.2
+PP_HV: length 63.5
  TOP w0.127: U722.A6 U722.A7 U722.B7
  TOP w0.254: U722.A8 26.55,60.97 v2(26.65,61.07)
  TOP w0.508: PR289.1 62.69,57.59 63.07,57.97 v2(63.55,57.97) ; v2(60.26,68.94) 59.59,68.27 PD205.2
  IN2 w0.508: v2(32.1,74.72) 32.1,75.64 33.24,76.78 34.46,76.78 34.87,76.37 35.68,76.37 36.09,76.78 38.31,76.78 39.41,77.87 41.85,77.87 43.24,79.27 53.77,79.27 54.14,79.64 v2(54.44,79.64)
  IN3 w0.508: v2(63.55,57.97) 62.95,57.97 62.52,57.55 61.73,57.55 61.28,58 61.28,58.42 60.6,59.09 59.13,59.09 v2(58.41,59.81)
  IN4 w0.508: v2(54.44,79.64) 58.22,79.64 59.32,78.54 60.06,78.54 60.47,78.12 60.47,77.45 59.75,76.74 59.75,74.28 61.14,72.89 61.14,69.82 60.26,68.94 v2(60.26,68.94) 60.05,68.73 60.05,66.81 60.08,66.77 60.08,64.67 59.89,64.47 59.89,63.57 58.41,62.1 v2(58.41,59.81)
  vias: v2(26.54,61.88) v2(27.14,61.68) v2(28.49,61.78) v2(28.47,61.16)
+PWR_SRC_AC: length 2.8
  BOTTOM w0.127: v3(47.6,33.74) 47.6,33.4 PL300.1
+RTC_CELL_VBAT: length 8.2
  TOP w0.254: UE5.B64 184.61,58.93 184.45,59.1 184.45,59.64 v2(184.86,60.05)
  BOTTOM w0.457: v2(184.86,60.05) 184.48,59.67 184.48,58.46 185.22,57.72 v3(186.36,57.72) 186.56,57.72 187.17,57.11 CE65.1
  BOTTOM w0.508: RE32.2 CE65.1
+RTCBATT: length 4.2
  TOP w0.508: v2(15.91,9.28) 15.45,9.74 C2973.1 RTCR1.2
  BOTTOM w0.508: JRTC1.1 15.91,9.28 v2(15.91,9.28)
+RTCVCC: length 293.9
  TOP w0.254: 147.17,44.51 RC56.2 146.91,44.51 146.36,45.07 146.36,45.7 146.58,45.93 146.58,48.08 145.39,49.27 CC213.1
  TOP w0.305: v2(143.93,49.25) 144.42,49.74 CC270.1
  TOP w0.457: v2(44.7,31.71) 46.79,31.71 50.14,28.36 50.14,25.82 51.44,24.52 54.53,24.52 56.21,22.84 58.52,22.84 59.46,23.78 60.12,23.78 60.58,24.24 60.58,25.61 61.09,26.12 v3(63.4,26.12) 66.7,26.12 68.61,28.03 77.32,28.03 79.22,29.93 81.02,29.93 82.25,28.7 86.33,28.7 87.31,27.72 87.31,27.37 87.9,26.79 88.84,26.79 89.53,26.1 93.62,26.1 93.95,26.43 93.95,27.73 94.45,28.23 96.24,28.23 96.75,27.72 v2(98.3,27.72)
  TOP w0.508: CC270.1 CC213.1 ; v2(188.77,51.72) 188.95,51.9 RE31.1 ; D122.3 15.04,13.19 CH95.1 C1309.1 v2(15.9,16.07) 15.9,21.04 17.37,22.52 RA16.1 ; v2(24.03,34.65) 24.31,34.38 RA54.1 ; RC57.2 RC69.2 147.17,44.51 ; v2(30.91,32.85) 32.91,32.85 33.16,33.11 35.28,33.11 35.45,33.27 36.58,33.27 v2(36.6,33.24)
  IN1 w0.508: v2(15.9,16.07) 15.9,18.23 17.49,19.82 25.8,19.82 26.98,20.99 27.45,20.99 31.4,24.95 31.4,27.46 30.91,27.95 v2(30.91,32.85) 30.23,33.54 30.23,33.59 28.94,34.87 26.46,34.87 26.25,34.65 v2(24.03,34.65)
  IN2 w0.508: v2(184.05,54.26) 184.05,54.44 183.67,54.82 182.88,54.82 181.69,53.63 179.1,53.63 178.55,53.08 176.13,53.08 175.72,52.67 v2(175.72,51.8) ; v2(160.5,39.71) 160.31,39.52 158.79,39.52 156.16,42.15 154.66,42.15 154.05,42.76 149.53,42.76 146.89,45.4 146.89,48.02 144.83,50.07 144.07,50.07
  IN3 w0.508: v2(175.72,51.8) 175.72,48.78 175.16,48.22 175.16,43.9 174.45,43.19 173.71,43.19 173.25,43.65 172.32,43.65 171.71,43.04 169.76,43.04 169.39,43.41 167.38,43.41 166.69,42.72 164.57,42.72 163.03,41.18 162.22,41.18 160.76,39.71 v2(160.5,39.71) ; v2(44.7,31.71) 44.7,32.6 44.02,33.28 41.17,33.28 40.71,32.83 39.07,32.83 38.65,33.24 v2(36.6,33.24) ; v2(188.77,51.72) 189.43,52.38 190.7,52.38 193.04,54.72 193.04,57.69 v2(193.05,57.7)
  BOTTOM w0.152: UCPU1.BB14 144.13,49.46 v2(143.93,49.25)
  BOTTOM w0.254: v2(140.79,56.3) 141.39,56.82 UCPU1.AK19
  BOTTOM w0.508: v2(188.77,51.72) 188.77,52.1 189.46,52.79 189.46,54.82 188.77,55.51 RE32.1 188.06,54.57 187.05,53.55 184.38,53.55 184.05,53.88 v2(184.05,54.26) 184.38,54.59 RE36.1 ; v2(160.5,39.71) 159.3,39.71 158.93,40.07 156.06,40.07 153.09,37.09 151.51,37.09 150.98,37.63 117.58,37.63 116.51,38.69 106.47,38.69 103.15,35.37 101.73,35.37 98.63,32.27 98.63,31.63 98.78,31.48 98.78,30.95 97.71,29.88 97.71,28.3 v2(98.3,27.72)
+SDC_IN: length 82.9
  TOP w0.508: PR206.1 20.66,76.29 19.74,75.36 PQ205.3 19.74,74.66 ; 19.74,74.66 18.59,73.52 PR204.1 ; 19.74,74.66 19.74,74 v2(20.09,73.64)
  IN1 w0.508: v4(48.24,24.71) 47.13,25.82 45.16,25.82 44.55,25.21 41.86,25.21 41.17,25.89 41.17,26.25 40.31,27.12 40.31,30.81 41.4,31.91 41.4,32.8 42.45,33.84 43.94,33.84 46.74,36.64 46.74,40.88 48.69,42.83 48.69,45.25 50.06,46.62 51.66,46.62 52.31,47.26 52.31,49.69 54,51.38 v2(54,51.72) ; v2(35.35,77.1) 34.61,76.36 29.57,76.36 28.37,77.56 23.85,77.56 22.66,76.36 21.72,76.36 20.09,74.74 v2(20.09,73.64)
  IN3 w0.508: v2(62.06,58.81) 61.92,58.95 61.92,58.99 60.13,60.78 57.24,60.78 55.05,58.59 55.05,53.84 54,52.79 v2(54,51.72)
  BOTTOM w0.508: v2(62.06,58.81) 61.7,59.17 PR223.1
  vias: v2(20.39,17.46) v2(20.38,16.79) v2(20.92,19.18) v2(21.01,17.14) v2(21.51,19.2) v2(21.62,17.13) v2(36.36,78.75) v2(36.67,78.23) v2(36.94,78.76) v2(36.98,77.71) v2(37.29,78.21) v2(37.54,78.76) v3(47.42,24.01) v4(48.24,24.06) v4(48.9,24.67) v4(48.87,24.04) v4(49.51,24.04) v4(49.56,24.67)
+TPM_LPM: length 9.5
  TOP w0.203: v2(184.86,41.33) 184.47,40.94 184.15,40.94 183.5,40.3 182.77,40.3 182.6,40.47 C98.1 CA72.1 182.6,43.45 182.73,43.57 U15.8
  BOTTOM w0.203: v2(184.86,41.33) 184.73,41.46 v3(184.73,42.55) 185.01,42.83 RC228.2 RC229.2
+V_DDR_REF_CA: length 19.9
  TOP w0.508: RD111.1 CD185.1 104.65,43.52 105.27,42.9 v2(105.27,42.3)
  IN2 w0.508: v2(105.27,42.3) 106.83,42.3 108.54,44 108.54,46.14 110.41,48.01 110.41,50.73 110.9,51.22 111.33,51.22 111.9,51.79 112.93,51.79 113.14,51.57 113.99,51.57 v2(114.26,51.84)
  BOTTOM w0.305: v2(114.26,51.84) 114.18,51.76 114.18,51.38 113.9,51.1 UCPU1.AY67
+V_DDR_REFA_R: length 22.8
  TOP w0.508: RD113.1 CD186.1 105.26,40.34 104.36,41.23 102.49,41.23 v2(102.01,40.75)
  IN2 w0.508: v2(112.56,50.75) 112.22,50.42 112.22,48.35 109.73,45.86 109.73,43.49 107.26,41.03 102.29,41.03 v2(102.01,40.75)
  BOTTOM w0.305: v2(112.56,50.75) 112.58,50.73 UCPU1.AY68
+V_DDR_REFB_R: length 57.4
  TOP w0.508: v2(110.74,41.16) 112.47,41.16 114.71,38.92 139.22,38.92 v2(140.44,40.14) ; v2(152.17,39.36) 152.34,39.2 CD187.1 RD114.1
  IN2 w0.508: v2(113.27,50.19) 113.27,47.9 110.74,45.37 v2(110.74,41.16)
  BOTTOM w0.305: UCPU1.BA67 113.76,50.19 v2(113.27,50.19)
  BOTTOM w0.508: v2(152.17,39.36) 151.45,38.64 v3(141.12,38.64) 140.64,38.64 140.11,39.18 140.11,39.81 v2(140.44,40.14)
+VCHGR:
  vias: v3(74.8,33.59) v4(68.3,30.69) v4(68.94,30.69) v4(70.03,30.65) v4(70.78,30.64) v4(71.95,30.66) v4(72.63,30.66) v4(73.53,32.11)
+VR_CAP: length 7.3
  TOP w0.127: v2(189.15,65.48) 189.23,65.48 189.5,65.75 189.84,65.75 CE45.1 ; v2(185.95,65.64) 185.93,65.64 185.93,65.39 186.55,64.77 187.21,64.77 UE5.B12
  BOTTOM w0.127: v2(189.15,65.48) 189.15,65.14 188.96,64.95 186.62,64.95 185.95,65.61 v2(185.95,65.64)
+VREFCA: length 86.8
  TOP w0.254: v2(120.02,26.3) 119.76,26.04 119.76,25.97 UD20.H4 ; UD19.H4 104.17,25.96 v2(103.84,26.29) ; v2(138.08,26.3) 137.75,25.97 UD21.H4 ; UD22.H4 153.32,25.98 v2(153,26.3)
  TOP w0.381: CD180.1 103.99,20.74 104.22,20.98 104.22,21.23 v2(104.24,21.24)
  TOP w0.457: v2(95.15,30.59) 93.8,30.59 93.12,31.28 93.12,32.1 92.15,33.07 92.15,33.9 93.19,34.93 95.58,34.93 99.34,38.69 99.34,42.55 100.33,43.54 RD17.2 100.58,43.52 RD19.1 RD111.2
  IN2 w0.508: 100.1,26.37 98.78,26.37 98.57,26.16 98,26.16 96.98,27.19 96.98,28.76 v2(95.15,30.59)
  BOTTOM w0.508: 114.28,21.8 114.28,20.38 115.32,19.34 120.02,19.34 120.24,19.57 ; CD183.1 138.79,19.9 ; 138.79,19.9 138.15,19.26 134.57,19.26 132.7,21.13 125.9,21.13 124.17,19.4 120.41,19.4 120.24,19.57 ; 138.79,19.9 139.29,19.39 153.26,19.39 153.9,20.02 CD184.1 153.9,21.22 154.1,21.42 154.1,22.18 153.47,22.82 152.5,22.82 151.69,23.63 151.69,25.81 152.18,26.3 v2(153,26.3) ; CD181.1 120.24,19.57
  vias: v3(111.91,23.48)
+VREFDQ_A: length 37.5
  TOP w0.127: UD20.J11 120.34,31.42 v2(120.02,31.1)
  TOP w0.254: v2(104.5,31.9) 104.82,31.58 UD19.J11
  TOP w0.508: RD113.2 RD21.2 103.51,38.46 RD25.1 103.48,38.26 105.33,36.41 CD117.1 105.33,34.93 105.88,34.39 v2(106.75,34.39) ; CD118.1 120.37,35.41 v2(120.83,35.87)
  BOTTOM w0.508: v2(120.02,31.1) 120.02,31.47 121.51,32.97 121.51,33.93 121.33,34.12 121.33,35.37 v2(120.83,35.87) 120.67,36.03 117.7,36.03 116.08,37.65 v3(112.5,37.65) 106.91,37.65 105.99,36.74 105.99,35.14 v2(106.75,34.39) 105.89,33.54 105.89,32.85 104.94,31.9 v2(104.5,31.9)
+VREFDQ_B: length 30.7
  TOP w0.254: v2(154.3,31.9) 153.97,31.57 153.97,31.5 UD22.J11 ; UD21.J11 138.4,31.57 v2(138.73,31.9)
  TOP w0.508: CD119.1 138.4,33.82 v2(138.44,33.79) ; RD22.2 RD114.2 153.9,38.29 RD26.1 153.9,35.48 CD120.1 v2(153.97,34.31)
  BOTTOM w0.508: v2(138.73,31.9) 138.41,31.9 137.85,32.46 137.85,33.2 v2(138.44,33.79) v3(139.62,34.97) 140.5,35.85 152.44,35.85 v2(153.97,34.31) 153.42,33.77 153.42,32.43 153.95,31.9 v2(154.3,31.9)
-DCIN_JACK: length 6.6
  TOP w0.381: v3(23.41,74.45) 23.41,73.71 24.51,72.61 v2(24.51,72.26)
  TOP w0.406: PC105.2 23.41,76.71 v3(23.41,74.45)
  TOP w0.508: PC104.2 PC105.2
  vias: v2(24.47,71.68) v2(24.47,71.08) v2(25.11,72.27) v2(25.07,71.69) v2(25.07,71.09)
AC_DET: length 4.4
  TOP w0.127: v3(20.6,78.66) 21.05,79.11 21.82,79.11 22.15,78.78 PR215.1
  TOP w0.508: PR206.2 PR215.1
AC_DIS: length 267.2
  TOP w0.127: UE5.A50 179.36,57.82 179.36,57.64 178.69,56.96 177.47,56.96 v2(177.32,57.11) ; v2(32.84,22.41) 33.17,22.08 35.26,22.08 35.41,22.23 35.41,22.58 35.85,23.02 PR301.1 36.93,23.02 PQ302.2 ; v2(35.21,74.71) 35.21,74.58 35.79,74 PR228.1
  IN1 w0.081: v2(32.84,22.41) 33.12,22.41 34.39,23.68 34.39,25.65 33.89,26.15 33.89,32.19 32.89,33.2 32.89,35.25 29.87,38.27 28.42,38.27 27.48,37.33 24.22,37.33 23.22,38.34 23.22,52.87 21.57,54.52 21.57,56.4 21.38,56.59 21.38,59.61 21.17,59.82 21.17,60.94 21.49,61.26 21.49,64.58 18.92,67.15 18.92,68.55 19.41,69.04 20.53,69.04 21.05,68.52 22.87,68.52 24.77,70.41 27.69,70.41 30.85,73.58 30.85,75.38 31.41,75.94 34.16,75.94 34.8,75.3 34.8,74.71 v2(35.21,74.71)
  IN2 w0.089: v2(35.21,74.71) 35.21,74.58 36.78,73.01 36.78,70.78 37.03,70.53 37.03,67.62 39.09,65.57 43.26,65.57 44.4,66.71 v2(44.4,66.81)
  IN3 w0.089: v2(44.4,66.81) 44.87,67.28 48.6,67.28 51.08,69.76 51.08,70.98 52.1,71.99 52.53,71.99 52.76,72.22 52.76,73.9 57.78,78.92 61.75,78.92 61.98,79.14 62.79,79.14 62.97,78.96 68.77,78.96 70.91,76.82 79.22,76.82 80.28,75.75 83.95,75.75 85.03,76.83 90.69,76.83 92.91,79.05 151.11,79.05 151.87,78.29 155.52,78.29 155.61,78.2 169.45,78.2 171.16,76.49 171.16,73.61 v2(170.66,73.11)
  IN4 w0.081: v2(177.32,57.11) 177.29,57.11 177.17,57.24 177.17,58.61 176.26,59.52 176.1,59.52 ; 171.66,72.02 170.66,73.02 v2(170.66,73.11)
  IN4 w0.089: 176.1,59.52 175.03,59.52 174.4,60.15 174.4,61.49 173.23,62.66 173.23,64.27 173.14,64.36 173.14,66.4 173.6,66.86 173.6,68.65 173.43,68.82 173.43,70.89 172.3,72.02 171.66,72.02
AC_PRESENT: length 61.8
  TOP w0.127: RC243.1 144.58,47.79 144.58,47.89 144.2,48.27 v2(143.99,48.27) ; UE5.A54 181.36,57.41 v2(180.84,56.89)
  IN3 w0.089: v2(180.84,56.89) 180.84,56.84 180.59,57.08 178.79,57.08 175.65,53.95 173.09,53.95 172.57,53.43 168.91,53.43 164.7,49.22 161.25,49.22 160.32,48.28 159.88,48.28 154.56,42.96 151.46,42.96 151.19,42.69 144.31,42.69 139.52,47.48 139.52,48.4 140.03,48.9 141.17,48.9 141.68,48.4 142.89,48.4 143.19,48.09 143.82,48.09 v2(143.99,48.27)
  BOTTOM w0.076: UCPU1.AY15 143.25,50.53 143.25,50.25 143.14,50.14 143.14,48.31 143.45,48 143.72,48 v2(143.99,48.27)
ACAV_IN: length 202.5
  TOP w0.127: v3(187.05,56.73) 186.64,57.13 v2(186.21,57.13) 186.36,57.29 UE5.A64
  IN1 w0.081: v2(41.9,21.34) 41.9,20.75 43.1,19.54 43.1,18.02 43.35,17.78 43.35,17.04 43.7,16.68 46.7,16.68 47.32,17.31 48.49,17.31 49.66,18.48 53.42,18.48 55.17,20.23 62.22,20.23 64.85,17.6 67.17,17.6 69.53,19.96 71.61,19.96 76.26,24.61 78.48,24.61 79.02,24.07 89.33,24.07 89.97,23.43 89.97,22.79 91.2,21.56 91.2,18.36 91.63,17.94 92.41,17.94 93.17,18.7 94.53,18.7 94.78,18.96 101.15,18.96 102.74,17.37 111.31,17.37 111.76,16.91 115.75,16.91 116.94,15.72 125.63,15.72 127.13,17.21 131.6,17.21 133.78,15.04 151.33,15.04 152.7,16.41 157.32,16.41 159.1,18.19 161.74,18.19 163.11,19.55 171.91,19.55 173.17,20.81 173.17,33.12 171.91,34.39 171.91,36.58 171.46,37.03 171.46,38.08 172.57,39.19 172.57,42.81 172.97,43.21 172.97,44.84 173.71,45.58 174.17,45.58 176.34,47.75 176.34,48.14 178.14,49.94 178.14,51.81 179.49,53.15 179.49,54.92 179.25,55.15 179.25,56.65 179.93,57.33 180.97,57.33 181.39,56.91 181.39,56.78 182.51,55.65 184.57,55.65 185.1,56.19 185.1,56.22 186.01,57.13 v2(186.21,57.13)
  BOTTOM w0.127: PR314.1 41.9,21.86 v2(41.9,21.34)
ACAV_IN_NB: length 6.5
  TOP w0.127: UE5.B20 185.61,67.87 185.61,67.38 v2(185.47,67.24)
  BOTTOM w0.127: v3(184.86,66.39) 184.86,66.62 v2(185.47,67.24) 185.47,67.64 186.57,68.74 187.82,68.74 RE102.2 187.91,69.27 187.91,70.05 DE11.2
ALW_PWRGD_3V_5V: length 120.4
  TOP w0.381: v2(56.93,56.33) 57.78,56.33 58.14,55.97 PR280.2 ; v2(67.87,37.55) 67.87,36.55 63.69,32.38 59.61,32.38 59.3,32.68 PR277.1
  TOP w0.508: v2(87.71,16.52) 86.54,17.69 74.75,17.69 73.1,19.33 73.1,23.12 75.06,25.08 78.46,25.08 79.17,24.37 80.98,24.37 83.54,26.93 v2(83.54,27.52)
  IN1 w0.508: v2(79.63,32.67) 79.63,32.95 79.27,33.31 74.35,33.31 72.01,35.65 69.77,35.65 v2(67.87,37.55)
  IN2 w0.406: v2(50.02,41.19) 49.42,41.19 49.02,41.59 49.02,45.58 50.17,46.72 51.94,46.72 52.49,47.27 52.49,50.08 53.39,50.99 53.39,51.95 53.75,52.31 54.51,52.31 56.72,54.52 56.72,55.46 56.93,55.67 v2(56.93,56.33)
  IN2 w0.508: v2(92.15,19.54) 91.59,20.1 87.48,20.1 86.72,19.34 86.72,17.51 v2(87.71,16.52) ; v2(83.54,27.52) 83.54,28.43 79.63,32.34 v2(79.63,32.67)
  IN4 w0.508: v2(50.02,41.19) 50.02,41.2 51,40.22 58.9,40.22 61.32,37.8 63.29,37.8 64.53,36.56 66.88,36.56 v2(67.87,37.55)
  BOTTOM w0.203: v2(92.15,19.54) 92.15,19.8 92.02,19.92 92.02,20.06 91.77,20.31 PU500.9
  BOTTOM w0.508: PR506.1 67.87,37.65 v2(67.87,37.55) ; v2(87.71,16.52) 88.21,17.03 PR502.2
ALWON: length 182.5
  TOP w0.127: v2(92.15,18.55) 93.56,18.55 94.92,19.91 94.92,23.68 94.11,24.49 88.52,24.49 87.6,25.41 85.91,25.41 v2(85.42,24.93) ; UE5.A60 184.36,57.13 v2(184.46,57.03)
  IN1 w0.081: v2(78.87,32.67) 78.65,32.89 74.17,32.89 71.83,35.22 66.73,35.22 v2(64.46,37.5)
  IN1 w0.089: v2(184.46,57.03) 183.5,56.08 182.69,56.08 181.81,56.96 181.81,57.08 181.1,57.79 179.66,57.79 178.82,56.95 178.82,54.98 179.06,54.73 179.06,53.34 178.27,52.55 177.98,52.26 177.71,51.99 177.71,51.4 177.4,51.09 176.49,51.09 175.97,50.57 175.97,48.9 175.17,48.1 175.17,47.67 172.54,45.04 172.54,43.39 172.14,42.99 172.14,39.36 170.99,38.22 170.99,37.22 170.54,36.76 170.54,35.15 172.75,32.94 172.75,20.99 171.74,19.98 162.93,19.98 161.57,18.63 158.92,18.63 157.12,16.84 152.53,16.84 151.16,15.46 133.96,15.46 131.78,17.65 126.95,17.65 125.45,16.15 117.12,16.15 115.93,17.34 111.94,17.34 111.48,17.8 102.92,17.8 101.23,19.48 94.7,19.48 94.36,19.14 92.74,19.14 v2(92.15,18.55)
  IN2 w0.089: v2(78.87,32.67) 78.87,32.42 82.88,28.41 82.88,27.47 v2(85.42,24.93)
  BOTTOM w0.127: v2(92.15,18.55) 92.15,18.08 91.1,17.03 PR503.1
  BOTTOM w0.203: v2(64.46,37.5) 64.49,37.53 PR510.1
AUD_PWR_EN: length 214.5
  TOP w0.127: v2(32.64,44.19) 32.54,44.1 32.54,43.67 32.72,43.49 U664.5 ; U664.3 33.52,43.66 v2(33.63,43.77) ; v2(53.7,21.79) 53.75,21.74 R1141.1 R1140.1 53.67,20.15 53.27,20.55 U719.5 ; v3(37.43,37.51) 37.72,37.22 v2(37.72,36.99)
  IN4 w0.081: v2(154.04,47.8) 154.04,47.77 154.82,46.99 154.82,46.31 155.73,45.4 155.73,44.59 156.71,43.61 156.71,41.15 160.44,37.42 160.44,36.01 162.31,34.14 163,34.14 163.73,33.41 163.73,29.97 162.06,28.3 162.06,27.44 163.46,26.05 163.46,22.97 160.6,20.11 147.98,20.11 147.57,20.51 145.07,20.51 144.57,20.01 124,20.01 123.6,20.41 107.2,20.41 105.85,21.77 100.85,21.77 99.68,22.94 97.84,22.94 97.52,23.26 97.52,25.45 97.43,25.54 97.43,29.26 96.61,30.08 96.61,33.5 95.54,34.57 90.81,34.57 90,35.38 86.55,35.38 85.96,34.79 85.96,34.17 85.63,33.84 84.39,33.84 84.03,33.48 84.03,33.48 82.57,32.02 78.8,32.02 77.7,30.92 76.85,30.92 74.03,28.1 71.57,28.1 69.12,25.65 69.12,24.46 66.02,21.36 63.89,21.36 61.85,19.31 59.3,19.31 56.8,21.82 53.72,21.82 ; 53.72,21.82 53.8,21.89 53.8,22.54 52.83,23.5 51,23.5 50.88,23.38 45.27,23.38 41.99,26.65 41.99,28.13 41.79,28.33 41.79,28.6 40.49,29.9 40.49,31.38 40.88,31.78 40.88,32.86 40.39,33.36 39.15,33.36 38.54,33.98 38.54,34.42 37.38,35.58 37.38,36.65 v2(37.72,36.99) ; 53.72,21.82 v2(53.7,21.79)
  BOTTOM w0.076: UCPU1.BA7 148.72,50.03 148.72,49.84 148.87,49.69 149.17,49.69 150.09,48.78 150.34,48.78 150.93,48.19
  BOTTOM w0.127: v2(37.72,36.99) 36.78,36.99 36.35,37.42 35.33,37.42 34.6,38.16 34.6,42.21 33.63,43.18 v2(33.63,43.77) 33.63,43.86 33.29,44.19 v2(32.64,44.19) ; 150.93,48.19 153.65,48.19 v2(154.04,47.8)
AUDIO_VREF: length 2.7
  TOP w0.203: UA2.28 23.99,30.68 23.67,31 v2(23.44,31) 23.25,31 23.05,31.2 CA87.1
AUX_EN_WOWL: length 201.5
  TOP w0.127: QE14.2 34.85,34.58 35.47,35.2 35.47,36.38 36.09,36.99 36.81,36.99 37.22,36.57 38.04,36.57 38.25,36.79 38.25,37.32 v2(38.58,37.65) 38.05,38.19 37.68,38.19 37.31,38.56 37.31,39.4 R1186.2 36.33,40.39 36.33,40.89 36.53,41.1 U720.3 ; UE5.B38 178.01,65.77 178.53,65.77 v2(178.74,65.57)
  IN2 w0.089: v2(38.58,37.65) 38.58,39.38 39.35,40.14 39.35,46.62 40.07,47.34 40.07,49.24 41.1,50.27 41.1,51.36 42.27,52.53 42.27,53.21 42.98,53.93 42.98,55.05 43.36,55.43 45.83,55.43 47.26,56.86 47.26,66.12 50.94,69.8 50.94,70.52 53.15,72.73 53.15,73.82 57.92,78.58 58.89,78.58 v2(59.84,79.54)
  IN3 w0.089: v2(179.74,74.19) 179.52,73.96 177.51,73.96 172.32,79.15 155.46,79.15 155.25,78.93 152.14,78.93 151.33,79.74 91.19,79.74 89.95,78.51 89.95,78.24 89.2,77.48 84.76,77.48 83.69,76.4 80.55,76.4 79.48,77.47 77.15,77.47 76.15,78.46 73.58,78.46 73.24,78.81 72.44,78.81 72.26,78.63 71.3,78.63 69.89,80.04 60.26,80.04 59.84,79.63 v2(59.84,79.54)
  IN4 w0.089: v2(179.74,74.19) 179.74,74.09 177.71,72.05 177.71,71.32 177.91,71.13 177.91,69.37 178.14,69.14 178.14,66.16 v2(178.74,65.57)
B+: length 104.8
  TOP w0.254: v2(167.51,65.31) 167.95,64.88 PR402.1 ; PR409.1 168.06,61.81 168.37,62.11 v2(168.68,62.11)
  TOP w0.381: v2(197.71,51.65) 197.21,51.14 C614.1 ; R78.1 159.04,42.06 v2(159.59,42.6) ; v2(196.95,52.47) 196.89,52.54 C615.1 ; v2(56.52,51.77) 56.24,51.77 55.6,52.41 55.3,52.41 PQ204.3 54.76,54.44 PR201.1
  TOP w0.762: PL1402.1 204.1,80.31 v5(204.06,80.35)
  IN1 w0.381: v2(159.59,42.6) 160.22,42.6 162.36,40.47 162.36,37.19 163.22,36.33 v2(163.22,35.57)
  IN1 w0.508: v5(204.06,80.35) 201.68,77.96 196.43,77.96 194.51,79.89 189.07,79.89 186.02,76.83 181.04,76.83 v2(177.8,80.07)
  IN3 w0.762: 197.33,71.61 197.33,77.02 198.5,78.19 201.91,78.19 v5(204.06,80.35)
  BOTTOM w0.254: v2(179.92,51.19) 179.92,51.94 179.38,52.48 177.2,52.48 176.74,52.94 171.38,52.94 169.1,55.21 169.1,61.7 v2(168.68,62.11) 167.73,63.07 167.73,65.1 v2(167.51,65.31)
  BOTTOM w0.381: C616.1 190.37,48.35 v2(189.84,48.35) ; C617.1 190.67,50.27 v2(190.4,50)
  BOTTOM w0.508: v2(66.02,37.58) 66.27,37.83 PR508.1 ; v2(173.25,35.85) 172.18,34.78 170.41,34.78 169.39,33.77 164.74,33.77 163.22,35.29 v2(163.22,35.57) ; v2(197.76,67.88) 197.4,67.88 PL700.1 197.11,66.76 v2(197.76,66.76)
  vias: v2(58.24,54.43) v2(58.83,54.42) v2(59.44,55.5) v2(59.45,54.87) v2(59.47,54.18) v2(59.47,53.48) v2(59.47,52.81) v2(70.08,41.36) v2(70.08,40.73) v2(70.71,41.36) v2(70.71,40.73) v2(70.71,40.09) v2(70.71,39.33) v2(71.35,41.36) v2(71.35,40.73) v2(71.35,40.09) v2(71.35,39.33) v2(71.35,37.8) v2(71.35,37.17) v2(71.98,37.8) v2(71.98,37.17) v2(72.11,39.96) v2(72.11,39.33) v2(80.37,33.36) v2(80.37,32.76) v2(92.74,26.7) v2(92.76,27.86) v2(92.77,27.28) v2(92.94,16.98) v2(93.35,27.87) v2(93.33,26.71) v2(93.36,27.29) v2(93.53,17.55) v2(93.53,16.96) v2(94.04,17.28) v2(94.59,17.64) v2(95.4,17.64) v2(159.89,16.9) v2(160.16,16.36) v2(160.47,16.9) v2(161.01,16.34) v2(161.15,16.91) v2(163.12,17.87) v2(172.95,17.48) v2(173.15,37.63) v2(173.25,36.45) v2(173.26,37.05) v2(173.58,17.48) v2(174.39,36.99) v2(176.35,21.97) v2(176.35,21.33) v2(180.47,51.39) v2(195.25,17.71) v2(195.25,17.13) v3(195.45,16.09)
B+_1.0V: length 1.7
  TOP w0.508: PC702.1 196.08,63.8 PC705.1
  vias: v2(194.31,64.02) v2(194.31,63.43) v3(194.96,64.4)
B+_3V:
  vias: v2(89.51,23.33) v2(90.45,23.15) v2(91.88,23.98) v2(92.18,23.48) v2(93.9,24.04) v2(93.91,23.45) v3(90.91,23.83)
B+_5V:
  vias: v2(63.35,44.92) v2(66.02,43.62) v2(66.61,43.62) v2(67.2,43.62) v2(67.97,43.63) v2(68.56,43.62) v2(69.15,43.63) v3(65.15,45.17)
BAT1_LED#: length 187.6
  TOP w0.127: v2(175.63,61.02) 174.14,61.02 RE104.2 ; UE5.A40 177.16,63.52 176.59,63.52 v2(176.47,63.39)
  IN1 w0.081: v2(43.24,21.86) 42.94,21.56 42.94,20.9 43.87,19.97 48.42,19.97 50.88,22.43 50.88,23.23 51.25,23.6 55.07,23.6 56.25,22.41 63.04,22.41 63.89,21.57 67.23,21.57 67.99,22.32 71.54,22.32 76.5,27.29 82.88,27.29 83.52,26.64 91.31,26.64 91.93,26.03 92.47,26.03 94.93,23.57 94.93,23 96.94,20.98 102.76,20.98 103.12,20.62 109.94,20.62 110.15,20.42 110.99,20.42 112.3,19.11 117.2,19.11 118,18.31 125.48,18.31 126.31,19.14 132.42,19.14 133.51,18.04 147.08,18.04 147.42,18.38 156.49,18.38 158.22,20.1 160.9,20.1 163.68,22.88 163.68,25.13 166.31,27.76 166.31,31.97 166.17,32.12 166.17,35.84 166.07,35.94 166.07,37.51 166.52,37.96 166.52,40.01 167.17,40.66 168.78,40.66 169.65,41.52 169.65,44.28 172.57,47.2 172.57,52.05 174.91,54.4 174.91,54.82 175.5,55.4 175.5,57.71 175.15,58.06 175.15,59.38 175.36,59.6 175.36,60.75 v2(175.63,61.02)
  IN2 w0.089: v2(175.63,61.02) 175.63,60.92 176.04,60.51 176.54,60.51 177.2,61.16 177.2,62.66 v2(176.47,63.39)
  BOTTOM w0.127: JKB1.10 42.42,21.14 43.13,21.86 v2(43.24,21.86)
BAT2_LED#: length 184.7
  TOP w0.127: UE5.B43 178.01,63.27 178.52,63.27 v2(178.66,63.13)
  IN1 w0.081: v2(43.36,21.25) 43.36,20.79 43.96,20.18 48.34,20.18 50.66,22.5 50.66,23.4 51.07,23.81 55.16,23.81 56.34,22.63 63.13,22.63 63.98,21.78 67.14,21.78 67.9,22.54 71.4,22.54 71.65,22.79 v2(71.65,23.2) 75.95,27.49 82.98,27.49 83.62,26.85 91.94,26.85 95.17,23.63 95.17,23.59 95.5,23.25 95.89,23.25 97.94,21.19 102.88,21.19 103.24,20.84 110.03,20.84 110.24,20.63 111.08,20.63 112.39,19.33 117.29,19.33 117.84,18.78 125.65,18.78 126.21,19.35 132.51,19.35 133.61,18.25 147,18.25 147.33,18.59 156.41,18.59 158.13,20.31 160.81,20.31 163.47,22.97 163.47,25.22 165.16,26.91 165.16,34.02 165.31,34.17 165.31,37.09 166.31,38.08 166.31,40.09 167.08,40.87 168.7,40.87 169.44,41.61 169.44,45.33 172.35,48.24 172.35,52.18 174.71,54.53 174.71,54.91 175.28,55.48 175.28,57.63 174.52,58.39 174.52,60.77 174.65,60.9 174.65,61.89 174.92,62.17 176.98,62.17 177.94,63.13 v2(178.66,63.13)
  BOTTOM w0.127: RE105.2 178.61,63.08 v2(178.66,63.13) ; JKB1.9 42.92,20.82 v2(43.36,21.25)
BAT_LED#_LV1: length 13.2
  TOP w0.127: R910.2 v2(5.28,5.19) ; LED12.1 v2(3.13,15.6)
  BOTTOM w0.127: v2(5.28,5.19) 5.28,13.45 v2(3.13,15.6)
BAT_LED#_LV2: length 4.6
  TOP w0.127: R911.2 5.28,9.89 v3(3.93,11.25) 3.17,12 LED14.1
BAT_LED#_LV3: length 3.4
  TOP w0.127: R912.2 v3(3.81,8.59) 2.19,8.59 LED10.1
BAT_LED#_LV4: length 4.5
  TOP w0.127: LED11.1 2.15,4.8 v3(3.9,6.55) 5.06,7.71 R913.2
BAT_LED#_LV5: length 7.3
  TOP w0.127: LED13.1 2.55,1.2 3.66,2.31 v3(3.66,4.35) 3.66,5.19 R916.2
BATBTN#: length 244.5
  TOP w0.203: RPE5.4 190.7,57.51 189.32,56.13 187.03,56.13 186.69,56.48 v2(186.21,56.48) 185.75,56.93 185.75,57.39 185.86,57.5 UE5.A63
  IN1 w0.508: v2(5.06,19.26) 5.55,19.26 7.26,17.55 7.26,16.49 10.95,12.8 14.92,12.8 17.2,15.07 20.57,15.07 22.89,17.38 36.48,17.38 37.45,16.41 38.78,16.41 39,16.63 42.12,16.63 43.16,15.59 49.32,15.59 50.41,16.67 54.63,16.67 54.95,16.34 57.45,16.34 58.67,17.56 59.95,17.56 60.34,17.18 67.71,17.18 69.62,19.09 77.14,19.09 78.79,20.74 78.79,22.78 79.33,23.32 85.64,23.32 91.49,17.48 92.54,17.48 93.35,18.28 95.93,18.28 96.3,17.91 101.07,17.91 102.74,16.23 115.83,16.23 116.76,15.3 125.81,15.3 127.31,16.79 131.42,16.79 133.6,14.61 151.5,14.61 152.7,15.81 157.34,15.81 159.3,17.77 161.92,17.77 163.28,19.13 164.48,19.13 166.5,17.1 168.12,17.1 168.88,17.87 172,17.87 174.57,20.44 174.57,21.24 175.08,21.75 175.08,25.2 173.6,26.68 173.6,33.3 172.33,34.57 172.33,36.76 171.88,37.21 171.88,37.9 173.7,39.72 173.7,43 173.46,43.24 173.46,44.05 173.86,44.46 174.01,44.46 176.48,46.92 176.48,47.15 176.78,47.46 176.78,47.98 178.59,49.78 178.59,51.23 179.93,52.58 179.93,55.03 v2(180.47,55.56)
  IN4 w0.381: v2(186.21,56.48) 185.42,55.69 183.41,55.69 182.86,55.13 180.9,55.13 v2(180.47,55.56)
  vias: v3(5.11,18.6)
BATDRV#: length 46.8
  IN3 w0.508: v2(41.12,36.89) 40.87,36.89 40.59,37.17 40.59,37.93 41.17,38.52 49.43,38.52 v2(50.5,37.45)
  IN4 w0.406: v2(78.09,34.98) 77.2,34.1 71.78,34.1 69.9,35.98 64.29,35.98 63.65,36.61 58.83,36.61 58.46,36.97 54.25,36.97 52.96,38.26 51.21,38.26 50.5,37.55 v2(50.5,37.45)
  BOTTOM w0.381: PR323.2 41.63,35.8 41.12,36.31 v2(41.12,36.89)
  BOTTOM w0.406: PQ305.4 v2(78.09,34.98)
BATT_LED#_LV1: length 39.9
  TOP w0.127: Q41.3 9.73,6.6 v2(10.11,6.98)
  IN3 w0.089: v2(34.32,15.34) 33.62,16.04 24.17,16.04 23.26,15.13 16.89,15.13 14.88,13.13 11.11,13.13 10.39,12.4 7.79,12.4 6.01,10.63 6.01,8.28 7.3,6.98 v2(10.11,6.98)
  BOTTOM w0.127: v2(34.32,15.34) 33.94,14.97 UE4.25
BATT_LED#_LV2: length 30.3
  TOP w0.127: v2(8.28,10.17) QH9.1
  IN3 w0.089: v2(32.98,15.32) 32.47,15.83 24.26,15.83 23.35,14.92 16.98,14.92 14.97,12.91 11.28,12.91 8.53,10.17 v2(8.28,10.17)
  BOTTOM w0.127: v1(33.06,13.29) 33.29,13.52 UE4.26 33.29,15.01 v2(32.98,15.32)
BATT_LED#_LV3: length 32.4
  TOP w0.127: QH9.4 7.54,11.47 7.75,11.26 v2(7.75,9.89) ; v2(32.64,13.7) v1(33.47,13.7)
  IN3 w0.089: v2(7.75,9.89) 7.96,9.67 8.36,9.67 11.38,12.7 16.52,12.7 18.08,14.25 23.95,14.25 23.96,14.24 24.3,14.24 24.31,14.25 24.5,14.25 25.79,15.54 31.61,15.54 32.64,14.51 v2(32.64,13.7)
  BOTTOM w0.127: UE4.27 v2(32.64,13.7)
BATT_LED#_LV4: length 31.9
  TOP w0.127: v2(9.72,8.1) 9.68,8.1 9.33,7.75 QH8.1
  IN3 w0.089: v2(9.72,8.1) 9.41,8.4 8.26,8.4 7.99,8.67 7.99,8.98 11.49,12.48 16.61,12.48 17.11,12.98 23.53,12.98 25.88,15.33 31.47,15.33 31.99,14.81 v2(31.99,13.7)
  BOTTOM w0.127: UE4.28 v2(31.99,13.7)
BATT_LED#_LV5: length 27.6
  TOP w0.127: v2(8.41,8.82) 8.18,9.05 QH8.4
  IN3 w0.089: v2(8.41,8.82) 8.41,9.06 11.6,12.25 16.74,12.25 17.25,12.76 23.62,12.76 24.7,13.84 30.35,13.84 31.13,14.62 v2(31.13,14.69)
  BOTTOM w0.127: UE4.1 30.96,14.86 v2(31.13,14.69)
BATT_PRS: length 10.2
  TOP w0.127: v3(65.71,23.89) v2(66.5,23.1) 66.55,23.05 66.55,22.44 66.28,22.17 PD100.3 66.52,21.93 67.54,20.91 67.54,19.67 67.16,19.29 PRP100.8
  BOTTOM w0.127: v2(66.5,23.1) 66.27,23.33 65.51,23.33 65.1,23.73 65.1,26.14 JBATT1.5
BATT_VREF: length 12.1
  TOP w0.127: v2(164.36,61.28) 164.43,61.28 165.15,62 PU400.6 ; PC407.1 164.38,58.47 ; 164.38,58.47 164.38,59.12 164.5,59.24 PU400.2 ; 164.38,58.47 v2(164.97,59.06)
  BOTTOM w0.127: v2(164.97,59.06) 164.97,59.32 165.63,59.98 PR413.1 PR410.2 166.13,60.45 165.41,60.45 165.33,60.37 164.84,60.37 164.54,60.66 164.54,61.1 v2(164.36,61.28) 164.82,61.28 v3(165.35,61.82)
BC_CLK_ECE1117: length 195.2
  TOP w0.127: v3(43.83,21.55) 43.99,21.71 v2(44.52,21.71) ; UE5.A20 184.86,68.72 184.86,69.33 184.81,69.38 v2(184.81,69.43)
  IN1 w0.081: v2(184.81,69.43) 184.81,66.34 183.44,64.96 180.46,64.96 180.31,65.12 178.56,65.12 177.65,64.2 177.65,63.72 176.72,62.79 174.67,62.79 174,62.12 174,61.13 173.9,61.03 173.9,58.13 174.41,57.62 174.41,57.08 174.06,56.74 174.06,54.79 168.78,49.51 168.78,44.75 165.08,41.05 164.8,41.05 164.63,41.05 163.79,40.21 163.79,39.56 164.06,39.29 164.06,37.12 163.87,36.94 163.87,33.91 164.06,33.73 164.06,28.49 155.75,20.18 125.86,20.18 125.29,19.61 118.55,19.61 117.75,20.42 112.84,20.42 110.8,22.46 102.9,22.46 102.66,22.23 98.09,22.23 96.66,23.65 96.66,26.68 92.16,31.18 91.75,31.18 90.25,32.69 88.19,32.69 87.85,33.03 83.88,33.03 81.59,30.74 76.62,30.74 72.87,27 63.95,27 63.24,26.29 60.14,26.29 58.29,24.44 50.81,24.44 50.03,23.66 50.03,22.82 48.03,20.82 45.18,20.82 44.52,21.48 v2(44.52,21.71)
  BOTTOM w0.127: v2(44.52,21.71) 44.17,21.71 43.79,21.33 43.79,21.06 43.42,20.7 JKB1.8
BC_DAT_ECE1117: length 219.3
  TOP w0.127: RPE5.1 190.68,59.01 v2(190.05,59.65) ; v2(44.11,17.29) 45.94,15.46 v3(47.02,15.46) ; v2(185.7,66.43) 185.69,66.42 185.44,66.42 185.02,66.84 185.02,67.78 UE5.B21
  IN1 w0.089: v2(190.05,59.65) 188.12,57.72 186.23,57.72 184.89,56.38 184.89,56.29 184.46,55.86 182.6,55.86 181.6,56.87 181.6,56.99 181.05,57.54 179.84,57.54 179.04,56.74 179.04,55.06 179.27,54.82 179.27,53.25 177.93,51.9 177.93,50.15 176.37,48.6 176.06,48.6 175.39,47.92 175.39,47.58 172.76,44.95 172.76,43.3 172.35,42.9 172.35,39.27 171.21,38.13 171.21,37.13 170.92,36.84 170.92,35.07 172.96,33.03 172.96,20.9 171.83,19.77 163.02,19.77 161.65,18.4 159.01,18.4 157.22,16.62 152.62,16.62 151.25,15.25 133.87,15.25 131.69,17.43 127.03,17.43 125.54,15.93 117.03,15.93 115.84,17.13 111.85,17.13 111.4,17.58 102.83,17.58 101.24,19.17 94.7,19.17 94.45,18.92 93.09,18.92 92.32,18.15 91.71,18.15 91.42,18.45 91.42,21.65 91.03,22.03 91.03,23.13 89.88,24.28 79.11,24.28 78.57,24.82 76.17,24.82 71.52,20.18 69.44,20.18 67.08,17.81 64.95,17.81 62.32,20.44 55.09,20.44 53.33,18.69 49.57,18.69 48.4,17.52 47.23,17.52 47.21,17.5 44.32,17.5 v2(44.11,17.29)
  IN4 w0.089: v2(190.05,59.65) 190.05,59.99 189.46,60.58 189.46,61.5 189.15,61.8 189.15,63.08 187.54,64.69 187.54,65.78 186.76,66.56 186.76,66.56 186.43,66.56 186.25,66.73 186,66.73 v2(185.7,66.43)
  BOTTOM w0.127: v2(44.11,17.29) 43.46,17.94 43.46,19.49 43.92,19.95 JKB1.7
BC_INT#_ECE1117: length 196.2
  TOP w0.127: UE5.A19 185.36,69.34 v2(185.45,69.43) ; v3(43.87,19.21) 44.22,19.55 v2(44.22,21.14)
  IN1 w0.081: v2(44.22,21.14) 44.22,21.13 44.74,20.61 48.17,20.61 50.24,22.68 50.24,23.57 50.9,24.23 55.33,24.23 55.5,24.06 58.21,24.06 60.22,26.07 63.33,26.07 64.04,26.78 72.96,26.78 76.71,30.53 81.68,30.53 83.97,32.82 87.76,32.82 88.11,32.47 90.17,32.47 91.67,30.98 92.08,30.98 96.45,26.6 96.45,23.56 98.01,22.01 102.76,22.01 103,22.25 110.72,22.25 112.76,20.21 117.66,20.21 118.47,19.4 125.38,19.4 125.95,19.97 155.9,19.97 164.27,28.34 164.27,33.81 164.08,34 164.08,36.85 164.27,37.04 164.27,39.38 164,39.65 164,40.12 164.72,40.84 165.17,40.84 169,44.68 169,45.5 171.92,48.42 171.92,52.34 174.27,54.69 174.27,56.65 174.63,57.01 174.63,57.69 174.11,58.22 174.11,60.95 174.21,61.05 174.21,62.04 174.75,62.58 176.8,62.58 177.86,63.64 177.86,64.12 178.65,64.91 180.21,64.91 180.4,64.72 183.53,64.72 185.06,66.26 185.06,69.05 v2(185.45,69.43)
  BOTTOM w0.127: v2(44.22,21.14) 44.42,20.93 44.42,20.36 JKB1.6
BEEP: length 243.9
  TOP w0.127: v2(32.54,44.77) 32.36,44.95 30.13,44.95 29.42,44.24 29.42,43.47 27,41.06 27,40.19 25.4,38.59 RA24.1 ; v2(186.06,67.24) 186.06,67.25 186.07,67.24 186.09,67.26 186.09,67.84 UE5.B19
  IN3 w0.089: v2(186.06,67.24) 185.66,66.84 185.54,66.84 184.38,65.68 184.38,64.83 183.08,63.53 183.08,60.03 182.93,59.88 182.93,57.95 183.46,57.42 183.46,55.65 181.82,54.02 179.08,54.02 177.49,52.42 177.49,51.53 177.17,51.22 176.71,51.22 176.36,50.87 176.36,48.66 176.42,48.59 176.42,45.89 180.52,41.79 180.52,40.05 179.81,39.34 174.29,39.34 174.01,39.61 171.15,39.61 170.52,38.99 166.43,38.99 165.9,38.46 163.75,38.46 163.57,38.46 163.22,38.11 162.87,38.11 162.2,37.45 162.2,34.66 163.16,33.7 163.16,32.28 162.64,31.76 162.46,31.76 160.53,29.83 160.53,28.88 159.45,27.79 159.45,26.13 158.95,25.63 158.95,23.85 155.83,20.74 135.22,20.74 134.42,21.54 133.32,21.54 133.22,21.45 125.17,21.45 124.51,22.11 118.19,22.11 116.73,20.64 105.58,20.64 104.35,21.88 98.9,21.88 96.74,24.04 96.74,33.16 95.26,34.63 90.07,34.63 89.87,34.83 87.69,34.83 84.79,37.73 84.79,39.89 85.22,40.32 85.22,40.81 84.97,41.06 84.58,41.06 84.48,41.16 84.48,41.54 82.37,43.65 70.91,43.65 68.39,46.17 65.55,46.17 64.67,47.05 62.9,47.05 v2(61.99,47.96)
  BOTTOM w0.127: v2(32.54,44.77) 32.63,44.69 34.47,44.69 34.56,44.78 37.24,44.78 39.36,42.65 42.67,42.65 43.96,43.95 46.78,43.95 48.08,42.65 50.24,42.65 50.76,42.13 51.59,42.13 52.13,42.67 52.13,44.74 51.43,45.44 51.43,46.44 51.17,46.7 51.17,48.19 51.74,48.76 51.74,49.55 52.56,50.37 v3(53.42,50.37) 53.77,50.37 54.2,49.93 61.63,49.93 62.33,49.23 62.33,48.3 v2(61.99,47.96)
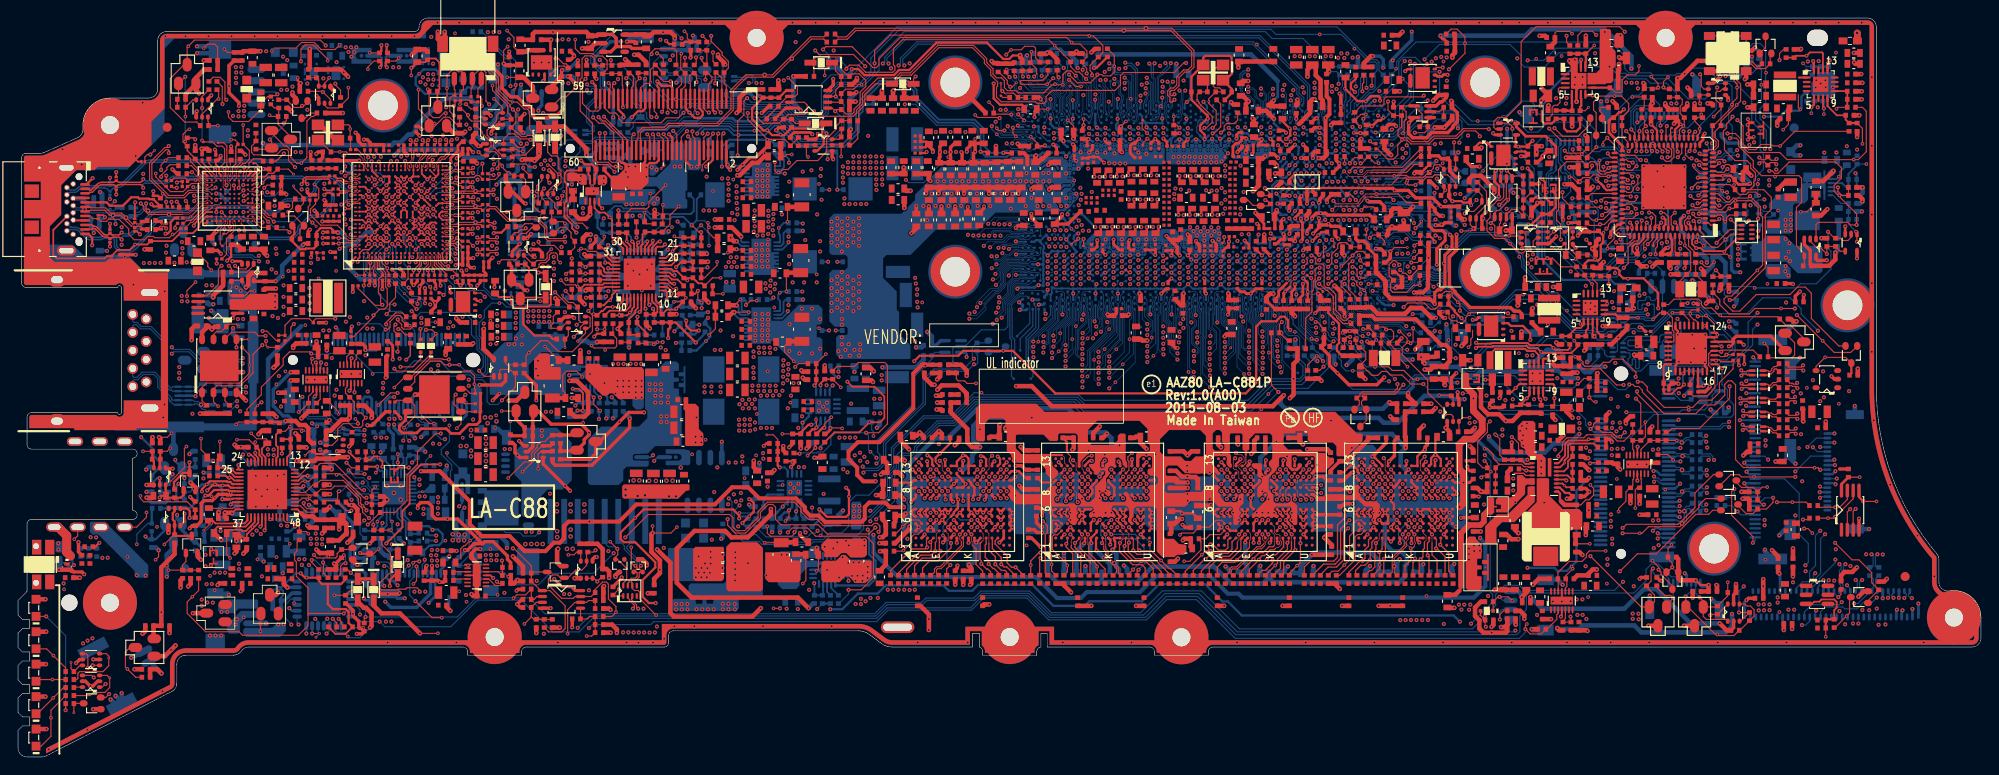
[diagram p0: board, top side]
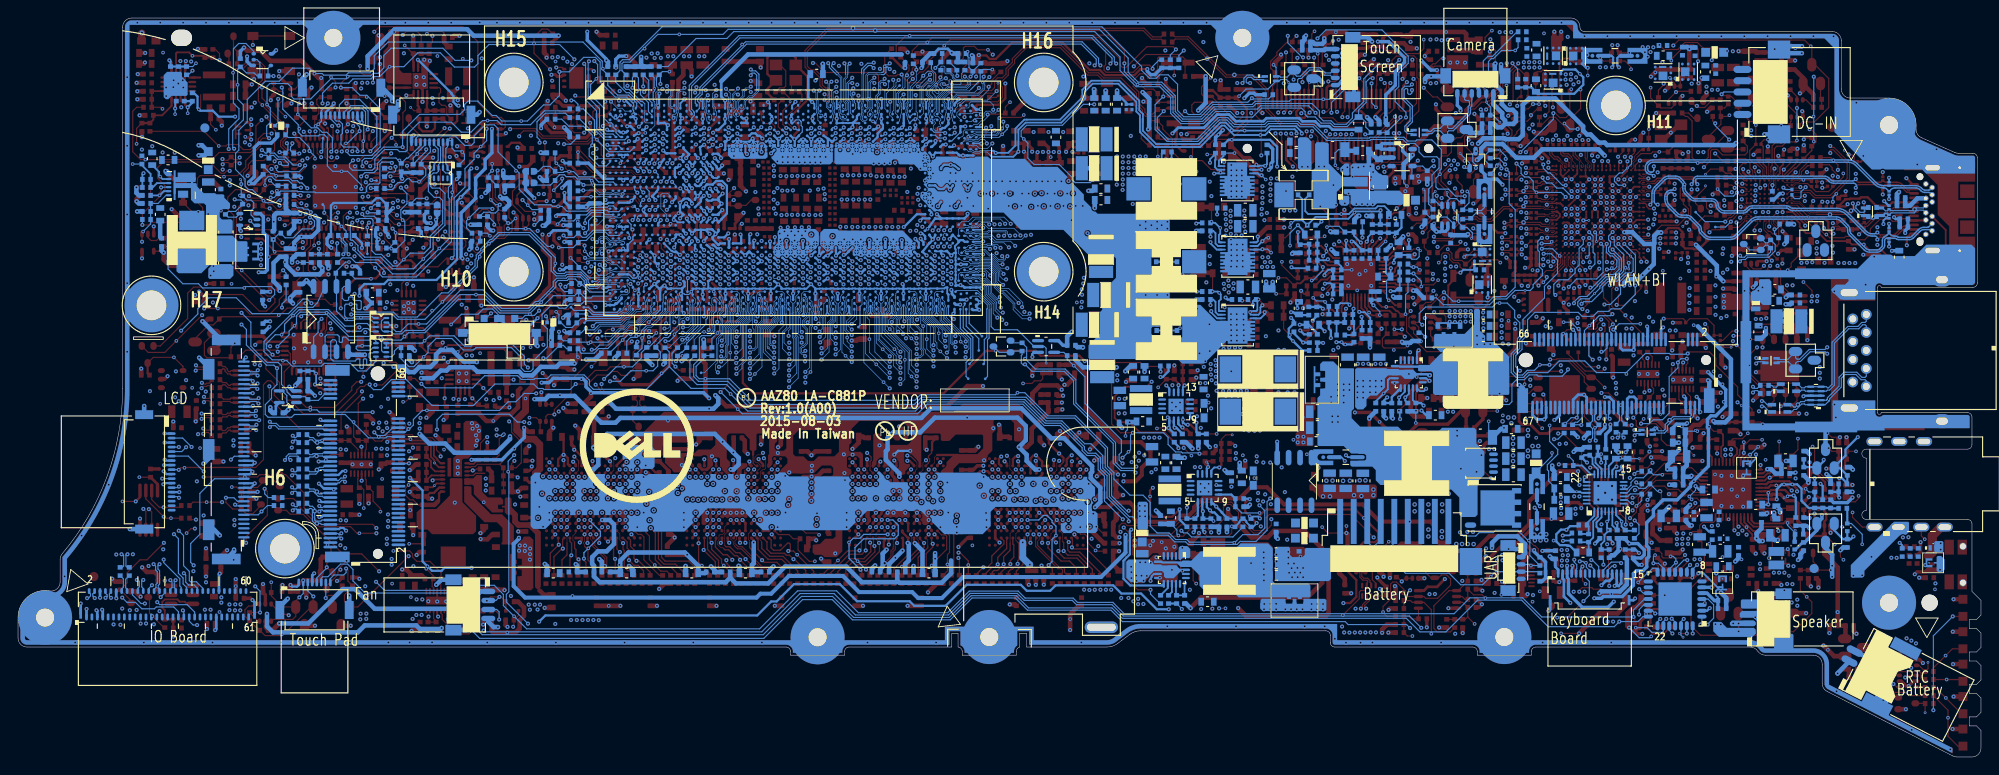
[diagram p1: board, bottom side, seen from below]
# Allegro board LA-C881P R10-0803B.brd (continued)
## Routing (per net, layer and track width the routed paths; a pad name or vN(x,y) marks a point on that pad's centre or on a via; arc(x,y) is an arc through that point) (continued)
BIA_PWM_EC: length 53.7
  TOP w0.127: UE5.B25 183.11,67.72 183.48,67.35 183.48,66.74 183.29,66.56 v2(183.03,66.56) ; D73.3 190.05,31.33 190.98,31.33 191.24,31.07 v3(192.63,31.07) v2(197.21,31.07)
  IN4 w0.089: v2(197.21,31.07) 197.67,31.54 197.67,33.42 195.22,35.87 195.22,48.56 193.45,50.33 193.21,50.33 189.72,53.82 189.72,57.6 188.98,58.35 188.3,58.35 187.66,58.99 187.66,60.64 187.5,60.79 187.5,62.74 186.46,63.78 185.5,63.78 183.03,66.25 v2(183.03,66.56)
BOARD_ID: length 7.7
  TOP w0.127: v2(185.71,63.11) 186.37,63.77 UE5.B10
  BOTTOM w0.127: v2(185.71,63.11) 186.3,63.7 186.57,63.7 186.82,63.95 187.39,63.95 187.91,64.47 CE54.1 189.15,64.47 v3(189.17,64.49) 189.41,64.73 189.76,64.73 RE79.1
BQ24777_REGN: length 25.6
  TOP w0.203: PR325.1 37.57,32.98 36.79,33.75 v2(36.79,33.88) ; v2(40.87,23.7) 42.65,25.48 42.65,27.29 43.45,28.09 43.45,31.19 44.73,32.47 v2(46.84,32.47)
  IN3 w0.203: v2(46.84,32.47) 45.7,32.47 44.4,33.77 40.97,33.77 40.53,33.32 39.26,33.32 38.7,33.88 v2(36.79,33.88)
  BOTTOM w0.203: PR312.1 40.87,23.88 v2(40.87,23.7)
BST_1.0V: length 2.4
  TOP w0.508: PR703.1 200.32,63.9 201.44,65.02 v2(201.44,65.05)
BST_3V: length 2.7
  TOP w0.127: PR500.1 88.81,20.85 v3(88.62,20.66)
  TOP w0.508: PR500.1 88.62,22.63 v2(88.62,23.21)
BST_5V: length 2.3
  TOP w0.508: PR505.1 v2(62.4,45.13)
  BOTTOM w0.203: v2(62.4,45.13) 62.59,44.94 PU501.1
BT_RADIO_DIS#: length 46.3
  TOP w0.127: DZ2.1 44.68,44.16 43.81,43.29 v2(42.44,43.29) ; v2(34.93,15.33) 35.36,14.89 RE13.2
  IN4 w0.081: v2(42.44,43.29) 42.25,43.49 35.59,43.49 34.65,42.54 34.65,41.49 34.52,41.37 34.52,39.47 34.84,39.15 34.84,35.03 34.59,34.77 34.59,33.57 33.72,32.7 33.72,27.77 34.95,26.54 34.95,22.27 34.44,21.76 34.44,16.6 34.93,16.11 v2(34.93,15.33)
  BOTTOM w0.127: v2(34.93,15.33) 35.24,15.01 UE4.23 35.24,13.97 35.37,13.84 36.52,13.84 37.04,14.35 v3(38.31,14.35)
BT_RADIO_DIS#_R: length 4.4
  TOP w0.127: DZ2.2 44.68,47.47 v2(44.65,47.51)
  BOTTOM w0.127: v3(46.31,48.25) 45.49,48.25 44.75,47.51 v2(44.65,47.51) 44.5,47.36 44.5,46.32 JNGFF1.46
CAM_CBL_DET#: length 142.4
  TOP w0.102: 150.09,62.48 149.54,62.48 148.9,61.84 148.9,61.71 148.57,61.38 146.27,61.38 145.96,61.69 v2(145.96,61.71)
  TOP w0.127: RC280.1 155.58,61.52 154.1,61.52 153.15,62.48 v3(150.7,62.48) 150.09,62.48
  IN3 w0.089: v2(145.96,61.71) 147.36,63.11 150.61,63.11 153.34,65.84 153.34,66.2 153.01,66.53 153.01,67.57 153.8,68.36 154.29,68.36 154.57,68.08 155.2,68.08 155.96,68.84 155.96,72.45 155.92,72.48 155.92,72.64 153.77,74.79 153.47,74.79 153.47,74.79 152.74,74.79 151.39,76.14 145.63,76.14 145.28,76.49 138.75,76.49 136.97,74.71 136.97,73.67 136.66,73.36 135.96,73.36 135.66,73.66 130.38,73.66 129.57,74.47 129.33,74.47 128.02,75.78 124.41,75.78 123.51,74.87 123.51,73.93 123.09,73.52 121.03,73.52 119.82,72.31 119.21,72.31 118.87,72.65 118.87,73.6 118.61,73.85 112.7,73.85 111.81,72.97 110.47,72.97 110.33,72.83 108.59,72.83 106.36,70.6 100.6,70.6 99.69,71.51 91.49,71.51 91,71.02 89.59,71.02 89.24,70.68 79.61,70.68 77.88,72.4 65.64,72.4 64.89,71.65 60.23,71.65 59.46,72.42 56.07,72.42 v2(55.5,71.85)
  BOTTOM w0.127: UCPU1.AB11 146.14,61.53 v2(145.96,61.71) ; RH438.1 55.36,71.71 v2(55.5,71.85)
CAM_CBL_DET#_R: length 4
  BOTTOM w0.127: v1(53.38,70.44) 54.15,71.22 RH438.2 54.45,72.15 54.9,72.61 JCAM.2
CFG0: length 52.1
  TOP w0.127: v2(110.66,75.48) 110.53,75.61 RC113.2 ; v2(76.27,75.17) 76.3,75.19 76.3,75.9 RC126.1 76.55,75.9 77,75.46 77,75.02 v1(76.81,74.82) 76.6,74.61 76.6,73.06 JXDP1.9
  IN4 w0.081: v2(110.66,75.48) 110.21,75.93 108.71,75.93 107.35,74.57 107.35,73.37 105.71,71.73 105.37,71.73 105.03,71.39 100.16,71.39 98.58,72.98 95.6,72.98 95.26,73.31 92.61,73.31 92.11,73.81 87.8,73.81 87.42,73.43 82.61,73.43 82.46,73.58 77.86,73.58 v2(76.27,75.17)
  BOTTOM w0.076: v2(110.66,75.48) 110.74,75.4 110.74,74.17 111.34,73.57 113.66,73.57 114.18,73.04 114.18,72.84 114.33,72.69 114.33,72.54 114.34,72.54 114.34,72.18 114.33,72.17 114.3,72.08 114.3,71.94 114.31,71.85 114.33,71.77 114.34,71.71 114.34,71.6 114.33,71.59 114.33,71.55 114.31,71.49 114.28,71.4 114.24,71.21 114.2,70.96 114.12,70.69 114.12,70.58 UCPU1.E68
CFG1: length 47.4
  TOP w0.127: v2(76.66,71.51) 76.52,71.51 76.1,71.93 JXDP1.11 ; v1(110.78,74.82) 110.33,74.37 v2(110.1,74.37) 109.77,74.71 109.77,75.08 108.83,76.02 RC112.2
  IN4 w0.081: v2(110.1,74.37) 110.1,73.28 109.5,72.68 108.33,72.68 106.2,70.54 105.86,70.54 105.49,70.18 99.31,70.18 98.91,70.58 96.1,70.58 95.37,71.31 91.63,71.31 91.22,70.9 84.59,70.9 84.44,71.04 79.48,71.04 78.61,71.92 77.06,71.92 v2(76.66,71.51)
  BOTTOM w0.076: v2(110.1,74.37) 110.1,74.03 111.08,73.06 112.8,73.06 113.23,72.63 113.35,72.63 113.54,72.43 113.54,72.2 113.77,71.97 113.77,71.79 UCPU1.B67
CFG2: length 49.2
  TOP w0.127: v2(75.41,71.43) 75.1,71.75 JXDP1.15
  IN4 w0.081: v2(111.19,74.24) 110.61,74.82 109.99,74.82 109.68,74.5 109.68,73.24 109.37,72.93 108.29,72.93 106.11,70.75 105.77,70.75 105.41,70.39 99.4,70.39 99,70.79 96.19,70.79 95.46,71.52 91.55,71.52 91.13,71.1 84.67,71.1 83.91,71.87 79.97,71.87 79.35,72.48 76.45,72.48 75.41,71.44 v2(75.41,71.43)
  BOTTOM w0.076: UCPU1.D65 115.04,70.58 115.04,70.69 114.96,70.96 114.96,71.07 114.93,71.18 114.83,71.5 114.82,71.55 114.82,71.8 114.86,71.89 114.86,72.08 114.82,72.18 114.82,72.54 114.99,72.71 114.99,73.14 114.39,73.75 111.68,73.75 v2(111.19,74.24)
CFG3: length 50.8
  TOP w0.127: v2(75.29,74.89) 75.29,75.62 RC121.2 74.82,75.88 74.52,75.58 v1(74.52,74.82) 74.6,74.75 JXDP1.17 ; RC110.2 109.64,75.84 v2(110.03,75.45)
  IN4 w0.081: v2(75.29,74.89) 75.97,74.89 77.59,73.27 79.66,73.27 80.24,72.69 92.04,72.69 92.41,72.32 97.61,72.32 97.97,71.97 99.29,71.97 100.08,71.18 105.11,71.18 105.45,71.53 105.79,71.53 108.05,73.79 108.05,73.92 109.58,75.45 v2(110.03,75.45)
  BOTTOM w0.076: UCPU1.D67 114.05,71.16 114.05,71.26 114.08,71.32 114.17,71.57 114.17,71.75 114.11,71.94 114.11,72.09 114.17,72.21 114.17,72.62 114.02,72.77 114.02,72.97 113.61,73.38 111.29,73.38 110.54,74.14 110.54,74.94 v2(110.03,75.45)
CFG4: length 48.4
  TOP w0.127: JXDP1.27 72.1,72.93 72.1,72.09 72.6,71.59 v2(72.96,71.59) ; v2(110.22,71.29) 110.18,71.33 108.38,71.33 RC109.2 108.26,72.14 107.74,72.66 v3(107.74,72.66)
  IN4 w0.081: v2(110.22,71.29) 110.22,72.04 109.81,72.45 108.4,72.45 106.28,70.34 105.95,70.34 105.58,69.97 99.23,69.97 98.83,70.37 96.02,70.37 95.29,71.1 91.72,71.1 91.3,70.69 84.5,70.69 84.35,70.83 79.4,70.83 79.13,71.1 75.87,71.1 75.79,71.03 73.52,71.03 v2(72.96,71.59)
  BOTTOM w0.076: UCPU1.E70 111.93,70.01 111.74,70.21 111.33,70.21 110.94,70.6 110.67,70.6 110.22,71.04 v2(110.22,71.29)
CFG5: length 48.6
  TOP w0.127: JXDP1.29 71.6,71.73 v2(71.45,71.59)
  IN4 w0.081: v2(109.6,71.81) 109.2,72.22 108.46,72.22 106.37,70.13 106.03,70.13 105.67,69.76 99.14,69.76 98.74,70.16 95.93,70.16 95.2,70.9 91.81,70.9 91.39,70.48 84.41,70.48 84.27,70.63 79.31,70.63 79.08,70.85 75.92,70.85 75.88,70.82 72.14,70.82 71.45,71.51 v2(71.45,71.59)
  BOTTOM w0.076: v2(109.6,71.81) 109.6,72.37 109.94,72.71 112.09,72.71 112.27,72.53 112.27,72.14 112.4,72.02 113.11,72.02 113.64,71.48 113.64,71.15 113.18,70.69 UCPU1.C68
CFG6: length 47.7
  TOP w0.127: v2(70.87,71) 70.87,71.4 70.6,71.66 JXDP1.33
  IN4 w0.081: v2(70.87,71) 71.28,70.59 76.56,70.59 76.62,70.65 78.99,70.65 79.22,70.42 84.18,70.42 84.33,70.27 91.48,70.27 91.89,70.69 95.11,70.69 95.84,69.96 98.65,69.96 99.78,68.83 105.48,68.83 105.61,68.97 105.61,69.41 106.12,69.92 106.49,69.92 108.57,72 108.84,72 v2(109.02,71.81)
  BOTTOM w0.076: UCPU1.D68 111.99,70.53 111.67,70.85 110.82,70.85 110.62,71.05 110.62,71.43 110.39,71.66 109.98,71.66 109.78,71.46 109.37,71.46 v2(109.02,71.81)
CFG7: length 49.6
  TOP w0.127: v2(70.28,71) 70.1,71.18 70.1,73.05 JXDP1.35 ; v3(111.65,70.63) 110.97,71.3 v2(110.97,71.31)
  IN4 w0.081: v2(110.97,71.31) 110.55,70.88 109.95,70.88 109.45,71.38 108.25,71.38 107.2,70.34 107.2,69.82 106.01,68.62 99.69,68.62 98.57,69.75 95.76,69.75 95.03,70.48 91.98,70.48 91.56,70.06 84.24,70.06 84.09,70.21 79.14,70.21 78.91,70.44 76.71,70.44 76.65,70.38 71.44,70.38 71.35,70.29 70.99,70.29 v2(70.28,71)
  BOTTOM w0.076: UCPU1.C67 113.23,71.38 111.9,71.38 111.77,71.51 111.08,71.51 110.97,71.4 v2(110.97,71.31)
CFG8: length 43.6
  TOP w0.127: 76.6,67.33 76.6,68.56 77.11,69.07 v2(77.11,69.17) ; 76.6,67.33 76.6,66.36 75.92,65.68 v1(75.92,65.11) ; 76.6,67.33 JXDP1.10
  IN4 w0.081: v2(77.11,69.17) 77.11,68.94 77.32,68.74 78.54,68.74 78.76,68.96 82.07,68.96 82.99,68.05 91.43,68.05 91.88,68.5 98.05,68.5 99.83,66.71 106.96,66.71 107.23,66.98 107.23,68.08 107.8,68.65 108.19,68.65 109.02,69.48 109.02,69.74 109.28,70 v2(109.82,70)
  BOTTOM w0.076: UCPU1.F71 111.87,69.45 110.19,69.45 109.82,69.82 v2(109.82,70)
CFG9: length 42.3
  TOP w0.127: v2(76.53,69.17) 76.1,68.74 76.1,67.33 JXDP1.12
  IN4 w0.081: v2(76.53,69.17) 76.53,69.38 76.97,69.81 78.65,69.81 78.88,69.58 82.33,69.58 83.25,68.67 91.17,68.67 91.62,69.12 93.11,69.12 93.74,69.75 94.87,69.75 95.5,69.12 98.31,69.12 99.43,68 106.27,68 107.54,69.27 107.67,69.27 108.05,69.66 v2(108.05,70.01)
  BOTTOM w0.076: 108.86,68.84 108.96,68.75 111.07,68.75 111.33,68.49 111.6,68.49 111.71,68.55 111.85,68.55 112.08,68.48 112.22,68.48 112.43,68.56 112.69,68.56 UCPU1.G69
  BOTTOM w0.127: v2(108.05,70.01) 108.05,69.66 v3(108.61,69.1) 108.86,68.84
CFG10: length 45.2
  TOP w0.127: v3(108.6,69.77) 108.85,69.52 v2(109.45,69.52) ; JXDP1.16 75.1,68.65 74.83,68.92 v2(74.83,69.43)
  IN4 w0.081: v2(109.45,69.52) 109.37,69.52 108.3,68.44 107.89,68.44 107.44,67.99 107.44,66.82 107.12,66.51 99.75,66.51 97.96,68.29 91.96,68.29 91.51,67.84 82.9,67.84 81.99,68.75 78.84,68.75 78.62,68.53 75.21,68.53 74.83,68.92 v2(74.83,69.43)
  BOTTOM w0.076: UCPU1.F70 112.3,69.02 112.04,69.02 111.47,69.27 109.7,69.27 v2(109.45,69.52)
CFG11: length 46.5
  TOP w0.127: v2(110.4,69.82) 110.4,69.19 v3(110.72,68.87) ; v2(74.35,68.87) 74.6,68.62 JXDP1.18
  IN4 w0.081: v2(110.4,69.82) 110.4,69.59 109.71,68.9 109.05,68.9 108.38,68.23 107.98,68.23 107.65,67.9 107.65,66.73 107.21,66.3 99.66,66.3 97.88,68.07 92.04,68.07 91.6,67.63 82.81,67.63 81.9,68.54 78.93,68.54 78.71,68.32 74.89,68.32 v2(74.35,68.87)
  BOTTOM w0.076: UCPU1.G68 113.01,68.88 112.93,68.95 112.93,69.43 112.78,69.58 112.17,69.58 112.1,69.65 111.66,69.65 111.64,69.63 110.59,69.63 v2(110.4,69.82)
CFG12: length 47.5
  TOP w0.127: JXDP1.28 72.1,68.58 71.64,69.04 v2(71.64,69.11)
  IN4 w0.081: v2(71.64,69.11) 73.1,67.65 79.84,67.65 81.03,66.47 82.78,66.47 83.32,67 91.86,67 92.3,67.45 97.63,67.45 99.4,65.67 108.82,65.67 109.75,66.61 109.75,68.03 v2(109.7,68.08)
  BOTTOM w0.076: UCPU1.H70 112.23,67.86 112,67.86 111.87,67.81 111.76,67.81 111.62,67.86 111.47,67.86 111.13,67.52 110.26,67.52 v2(109.7,68.08)
CFG13: length 49.1
  TOP w0.127: v2(71.04,69.1) 71.6,68.54 JXDP1.30 71.6,65.55 v1(71.35,65.3)
  IN4 w0.081: v2(71.04,69.1) 71.91,69.96 76.82,69.96 76.88,70.02 78.74,70.02 78.96,69.79 82.42,69.79 83.27,68.94 87.35,68.94 88.05,69.65 91.74,69.65 92.15,70.06 94.85,70.06 95.59,69.33 98.4,69.33 99.52,68.21 106.18,68.21 107.62,69.65 107.62,70.16 107.95,70.49 v2(108.48,70.49)
  BOTTOM w0.076: v2(108.48,70.49) 108.48,69.66 108.67,69.46 108.76,69.46 108.98,69.25 108.98,69.16 109.2,68.94 111.31,68.94 UCPU1.G71
CFG14: length 49.4
  TOP w0.127: JXDP1.34 70.6,67.33 70.6,68.93 v2(70.43,69.1)
  IN4 w0.081: v2(110.31,68.08) 110.31,66.79 108.99,65.46 99.31,65.46 97.54,67.24 92.39,67.24 91.94,66.8 83.41,66.8 82.87,66.26 80.94,66.26 79.75,67.45 71.68,67.45 70.43,68.69 v2(70.43,69.1)
  BOTTOM w0.076: UCPU1.H69 112.84,68.36 112.38,68.36 112.22,68.31 112.08,68.31 111.86,68.37 111.74,68.37 111.63,68.33 111.22,68.33 111.03,68.51 110.59,68.51 110.31,68.23 v2(110.31,68.08)
CFG15: length 52.2
  TOP w0.127: v2(69.82,69.1) 70.1,68.82 70.1,67.33 JXDP1.36 ; v3(106.21,71.24) 106.48,70.97 108.85,70.97 v2(108.92,70.9)
  IN4 w0.081: v2(69.82,69.1) 70.63,69.91 71.26,69.91 71.52,70.17 76.73,70.17 76.79,70.23 78.82,70.23 79.05,70 82.5,70 83.35,69.15 87.27,69.15 87.97,69.85 91.65,69.85 92.07,70.27 94.94,70.27 95.67,69.54 98.48,69.54 99.6,68.42 106.1,68.42 107.41,69.73 107.41,70.25 108.06,70.9 v2(108.92,70.9)
  BOTTOM w0.076: v2(108.92,70.9) 109.07,70.75 109.07,69.39 109.14,69.32 109.14,69.25 109.29,69.1 111.43,69.1 111.84,68.91 111.84,68.9 111.85,68.9 111.99,68.76 UCPU1.G70
CFG16: length 45.7
  TOP w0.127: JXDP1.6 77.6,67.33 77.6,69.07 v2(77.7,69.17)
  IN4 w0.081: v2(114.94,69.24) 115.1,69.24 115.39,69.53 115.39,70.04 115.01,70.42 114.25,70.42 114.18,70.49 111.5,70.49 111.32,70.67 109.36,70.67 107.75,69.07 107.63,69.07 106.36,67.79 99.34,67.79 98.22,68.91 95.41,68.91 94.79,69.54 93.82,69.54 93.2,68.91 91.7,68.91 91.25,68.46 83.16,68.46 82.25,69.38 78.79,69.38 78.56,69.6 78.05,69.6 77.7,69.26 v2(77.7,69.17)
  BOTTOM w0.127: v2(114.94,69.24) 115.02,69.33 116.15,69.33 116.48,69.65 UCPU1.E63
CFG17: length 44.9
  TOP w0.127: v2(78.28,69.2) 78.1,69.01 JXDP1.4
  IN4 w0.081: v2(78.28,69.2) 78.31,69.2 78.34,69.17 82.16,69.17 83.07,68.25 91.34,68.25 91.79,68.71 93.28,68.71 93.91,69.33 94.7,69.33 95.33,68.71 98.14,68.71 99.26,67.58 106.44,67.58 107.72,68.86 107.84,68.86 109.44,70.46 111.15,70.46 112.07,69.55 112.99,69.55 113.24,69.8 113.24,69.88 113.63,70.27 114.1,70.27 114.53,69.84 114.53,69.03 114.92,68.64 v2(114.96,68.64)
  BOTTOM w0.127: UCPU1.F63 116.04,69 115.72,68.68 115,68.68 v2(114.96,68.64)
CFG18: length 49.5
  TOP w0.127: v2(72.7,69.48) 73.1,69.07 73.1,67.33 JXDP1.24
  IN4 w0.081: v2(72.7,69.48) 74.31,67.86 79.92,67.86 81.11,66.67 82.7,66.67 83.24,67.21 91.77,67.21 92.22,67.66 97.71,67.66 99.49,65.88 107.5,65.88 109.27,67.65 109.27,68.33 109.42,68.49 113.05,68.49 113.43,68.87 114.02,68.87 114.28,69.12 114.28,69.46 v2(113.87,69.86)
  BOTTOM w0.076: UCPU1.E66 114.45,69.68 v2(113.87,69.86)
CFG19: length 47.3
  TOP w0.127: JXDP1.22 73.6,67.33 73.6,68.81 v2(74.24,69.45)
  IN4 w0.081: v2(74.24,69.45) 73.89,69.1 73.89,68.74 74.51,68.12 78.8,68.12 79.01,68.33 81.81,68.33 82.73,67.42 91.69,67.42 92.13,67.86 97.8,67.86 99.57,66.09 107.41,66.09 109.04,67.72 109.04,68.41 109.33,68.7 112.96,68.7 113.54,69.28 v2(113.87,69.28)
  BOTTOM w0.127: UCPU1.F66 114.15,69 v2(113.87,69.28)
CFG_RCOMP: length 1.9
  TOP w0.127: v2(118.24,70.11) v3(118.24,70.8)
  TOP w0.254: RC114.1 118.09,69.81 118.24,69.97 v2(118.24,70.11)
  BOTTOM w0.254: v2(118.24,70.11) 118.24,69.72 UCPU1.E60
CHAGER_SRC:
  vias: v3(49.35,35.42) v4(49.12,34.5) v4(49.76,34.5) v4(50.27,36.28) v4(50.27,35.65) v4(50.27,33.99) v4(50.27,33.36)
CHARGER_SMBCLK: length 202.3
  TOP w0.127: v2(179.61,60.25) 179.61,60.17 179.22,59.77 UE5.B50 ; v3(36.67,31.85) 37.11,31.4 v2(38.46,31.4)
  IN1 w0.081: v2(43.99,18.34) 43.99,18.47 44.52,19 45.49,19 45.78,18.71 48.09,18.71 49.38,20 50.64,20 52.01,21.36 54.51,21.36 54.72,21.58 62.7,21.58 63.45,20.82 67.1,20.82 68.17,21.89 71.72,21.89 76.7,26.87 82.69,26.87 83.33,26.23 91.13,26.23 91.77,25.59 92.23,25.59 93.01,24.81 93.01,23.49 93.66,22.85 94.47,22.85 96.75,20.57 102.52,20.57 102.9,20.19 109.76,20.19 109.97,19.99 110.81,19.99 112.12,18.68 117.02,18.68 117.83,17.87 125.65,17.87 126.5,18.72 132.22,18.72 133.33,17.61 147.24,17.61 147.59,17.96 156.68,17.96 158.4,19.69 161.1,19.69 164.11,22.69 164.11,24.95 166.75,27.59 166.75,32.15 166.66,32.24 166.66,33.57 168.02,34.94 168.02,37.1 170.07,39.15 170.07,42.44 171.47,43.84 171.47,45.49 173,47.02 173,50.68 177.36,55.04 177.36,55.8 176.21,56.95 176.21,57.86 178.33,59.99 179.35,59.99 v2(179.61,60.25)
  IN4 w0.081: v2(38.46,31.4) 38.46,30.87 38.79,30.54 38.79,30.32 39.4,29.71 39.4,28.6 40.85,27.14 40.85,25.67 39.79,24.61 39.79,23.53 39.33,23.07 39.33,20.98 40.02,20.28 41.76,20.28 43.7,18.34 v2(43.99,18.34)
  BOTTOM w0.127: RE56.1 178.3,60.02 179.46,60.02 179.61,60.17 v2(179.61,60.25) ; PR311.1 38.15,31.71 v2(38.46,31.4)
CHARGER_SMBDAT: length 192.8
  TOP w0.127: UE5.A47 176.95,60.02 176.03,59.1 v2(175.55,59.1) 175.43,58.99 174.37,58.99 RE55.1
  IN1 w0.081: v2(175.55,59.1) 175.55,58.02 175.79,57.77 175.79,55.4 175.12,54.73 175.12,54.31 172.78,51.98 172.78,47.11 171.25,45.58 171.25,43.93 169.86,42.53 169.86,41.43 168.87,40.45 167.25,40.45 166.73,39.93 166.73,37.88 166.27,37.42 166.27,36.02 166.43,35.86 166.43,32.16 166.52,32.07 166.52,27.67 163.89,25.04 163.89,22.81 160.98,19.9 158.31,19.9 156.59,18.17 147.5,18.17 147.16,17.82 133.42,17.82 132.32,18.93 126.41,18.93 125.58,18.1 117.91,18.1 117.11,18.89 112.21,18.89 110.9,20.2 110.06,20.2 109.85,20.41 102.98,20.41 102.61,20.77 96.84,20.77 94.56,23.05 93.74,23.05 93.23,23.57 93.23,24.89 92.31,25.8 91.85,25.8 91.22,26.44 83.43,26.44 82.79,27.08 76.6,27.08 71.62,22.1 68.08,22.1 67.34,21.36 63.21,21.36 62.78,21.79 54.65,21.79 53.62,22.82 51.69,22.82 47.88,19.01 45.77,19.01 45.05,19.74 43.81,19.74 42.73,20.82 42.73,21.87 42,22.6 41.11,22.6 38,25.72 38,30.21 v2(38.25,30.46)
  BOTTOM w0.127: PR309.1 38.1,30.31 v2(38.25,30.46)
CHG_BTS:
  vias: v1(44.85,29.43)
CHG_BTS_C: length 9.4
  BOTTOM w0.127: v3(47.86,36.79) 47.86,35.02 46.97,34.12 46.97,33.58 48.12,32.43 48.12,31.87 47.98,31.73 47.98,30.63 47.35,30 PR308.2
  BOTTOM w0.254: PC322.1 PR308.2
CHG_LGATE: length 10.3
  IN1 w1.016: 54.29,33.15 54.29,32.08 53.5,31.29 45.66,31.29 45.44,31.07
  vias: v2(44.54,30.79) v2(44.55,30.18) v2(54,34.17) v2(54.59,34.16)
CHG_SW: length 14.8
  IN1 w1.016: 47.47,28.41 47.78,28.71 54.65,28.71 58.14,32.2 58.14,34.76
  vias: v2(46.6,28.84) v2(46.62,28.25) v2(58.13,36.22) v2(58.13,35.64)
CHG_UGATE: length 11
  IN4 w1.016: 46.46,29.93 50.9,29.93 55.44,25.39
  BOTTOM w0.127: v2(57,24.98) 56.87,25.1
  vias: v2(44.55,28.91) v2(45.14,28.92) v2(56.36,24.98)
CL_CK: length 164.4
  TOP w0.127: R1212.2 41.72,47.27 41.72,47.82 v2(41.89,47.99)
  IN3 w0.089: v2(41.89,47.99) 43.1,47.99 43.32,48.2 43.32,48.33 42.9,48.74 42.9,48.88 43.01,48.99 43.16,48.99 43.57,48.58 43.69,48.58 44.64,49.53 46.58,49.53 46.8,49.74 46.8,50.31 46.89,50.4 47.06,50.4 47.15,50.31 47.15,49.74 47.24,49.65 47.42,49.65 47.51,49.74 47.51,50.31 47.6,50.4 47.78,50.4 47.87,50.31 47.87,49.74 47.95,49.65 48.13,49.65 48.25,49.77 48.25,50.14 48.33,50.22 48.51,50.22 48.6,50.14 48.6,49.72 48.67,49.65 49.48,49.65 49.66,49.83 49.66,49.96 49.32,50.3 49.32,50.42 49.45,50.55 49.57,50.55 49.91,50.21 50.04,50.21 54.21,54.38 54.21,59.05 54.92,59.77 54.92,67.5 54.48,67.95 54.48,72.11 55.79,73.43 56.62,73.43 56.7,73.51 56.7,74.02 56.8,74.13 56.95,74.13 57.05,74.02 57.05,73.4 57.15,73.3 57.3,73.3 57.41,73.4 57.41,74.08 57.49,74.17 57.67,74.17 57.76,74.08 57.76,73.4 57.87,73.3 58.01,73.3 58.12,73.4 58.12,74.08 58.21,74.17 58.5,74.17 58.59,74.08 58.59,73.4 58.7,73.3 58.84,73.3 58.95,73.4 58.95,74.07 60.15,75.27 60.59,75.27 61.46,76.13 64.29,76.13 65.25,77.1 65.25,77.4 65.58,77.73 65.96,77.73 66.19,77.5 66.19,77.2 67.17,76.22 69.91,76.22 70.44,75.7 78.23,75.7 79.99,73.94 89.89,73.94 90.34,74.39 91.55,74.39 93.04,75.88 99.14,75.88 101.17,77.91 106.33,77.91 109.2,75.04 113.84,75.04 115.8,77 120.45,77 121.44,77.99 130.01,77.99 130.28,78.26 140.06,78.26 140.96,77.36 145.64,77.36 145.99,77 151.75,77 151.86,76.89 153.54,76.89 v2(153.87,77.22)
  BOTTOM w0.127: v2(153.87,77.22) 153.5,76.85 153.5,75.4 v3(153.64,75.25) 154.28,74.62 154.28,73.49 152.82,72.03 152.82,70.91 152.27,70.37 151.97,70.37 151.79,70.19 151.79,69.92 151.46,69.59 151.46,69.27 150.99,68.8 UCPU1.G3
CL_CK_R: length 2.7
  TOP w0.127: v2(42.11,44.96) 42.16,45.01 42.16,45.91 R1212.1
  BOTTOM w0.127: v2(42.11,44.96) 41.91,44.96 41.5,45.37 41.5,46.32 JNGFF1.34
CL_DAT: length 160.9
  TOP w0.127: v2(43.68,49.48) 43.99,49.16 R1210.2
  IN3 w0.089: v2(154.46,77.2) 154.46,77.33 154.08,77.71 151.66,77.71 151.57,77.62 151.57,77.3 151.49,77.22 151.29,77.22 151.21,77.3 151.21,78.03 150.8,78.44 149.76,78.44 149.67,78.36 149.67,77.36 149.58,77.27 149.4,77.27 149.31,77.36 149.31,78.36 149.23,78.44 148.57,78.44 148.48,78.36 148.48,78.23 148.39,78.14 148.22,78.14 148.13,78.23 148.13,78.36 148.03,78.45 144.81,78.45 144.7,78.34 144.7,77.65 144.63,77.57 144.42,77.57 144.35,77.65 144.35,78.36 144.26,78.44 143.21,78.44 143.12,78.36 143.12,78.13 143.03,78.04 142.85,78.04 142.76,78.13 142.76,78.36 142.68,78.44 130.11,78.44 129.88,78.21 121.35,78.21 120.36,77.21 115.71,77.21 115.32,76.82 107.73,76.82 106.41,78.14 94.72,78.14 93.35,76.77 93.35,76.49 91.46,74.61 90.25,74.61 89.8,74.16 80.1,74.16 78.33,75.93 70.51,75.93 70,76.44 67.26,76.44 66.41,77.29 66.41,77.59 66.05,77.95 65.49,77.95 65.04,77.49 65.04,77.19 64.2,76.35 61.37,76.35 60.5,75.48 59.96,75.48 58.86,74.39 56.52,74.39 55.96,73.82 55.88,73.82 54.26,72.2 54.26,67.5 54.35,67.41 54.54,67.41 54.65,67.31 54.65,67.16 54.54,67.05 54.35,67.05 54.26,66.97 54.26,66.79 54.35,66.7 54.48,66.7 54.59,66.59 54.59,66.45 54.48,66.34 54.35,66.34 54.26,66.25 54.26,66.08 54.35,65.99 54.4,65.99 54.49,65.9 54.49,65.72 54.4,65.63 54.35,65.63 54.26,65.54 54.26,65.37 54.35,65.28 54.4,65.28 54.49,65.19 54.49,65.01 54.4,64.92 54.35,64.92 54.26,64.83 54.26,64.65 54.35,64.57 54.4,64.57 54.49,64.48 54.49,64.3 54.4,64.21 54.35,64.21 54.26,64.12 54.26,63.94 54.35,63.85 54.4,63.85 54.49,63.76 54.49,63.59 54.4,63.5 54.35,63.5 54.26,63.41 54.26,63.23 54.35,63.14 54.4,63.14 54.49,63.05 54.49,62.88 54.4,62.79 54.35,62.79 54.26,62.7 54.26,62.52 54.35,62.43 54.4,62.43 54.49,62.34 54.49,62.16 54.4,62.08 54.35,62.08 54.26,61.99 54.26,61.81 54.35,61.72 54.4,61.72 54.49,61.63 54.49,61.45 54.4,61.36 54.35,61.36 54.26,61.28 54.26,61.1 54.35,61.01 54.4,61.01 54.71,60.7 54.71,59.86 53.77,58.93 53.77,54.56 50.96,51.74 50.52,51.74 50.43,51.65 50.43,50.97 50.34,50.89 50.16,50.89 50.07,50.97 50.07,51.65 49.98,51.74 49.77,51.74 49.55,51.53 49.55,51.4 49.68,51.28 49.68,51.15 49.56,51.02 49.43,51.02 49.3,51.15 49.18,51.15 48.64,50.62 46.67,50.62 46.41,50.89 43.88,50.89 43.64,50.64 43.64,49.55 43.68,49.51 v2(43.68,49.48)
  BOTTOM w0.127: UCPU1.G2 151.79,69.13 152.6,69.13 153.29,69.82 153.29,71.94 154.55,73.2 154.55,77.11 v2(154.46,77.2)
CL_DAT_R: length 5
  TOP w0.127: v2(40.84,48.01) 40.84,48.24 41.88,49.28 42.66,49.28 R1210.1
  BOTTOM w0.127: JNGFF1.32 41,47.03 41.22,47.25 41.22,47.63 v2(40.84,48.01)
CL_RST#: length 158.8
  TOP w0.127: R1200.2 43.51,47.48 42.76,47.48 42.57,47.67 42.57,47.98 42.14,48.41 v2(42.14,48.55)
  IN3 w0.089: v2(42.14,48.55) 43.41,49.82 43.41,50.77 43.78,51.14 46.46,51.14 46.76,50.83 48.55,50.83 49.76,52.04 49.76,52.46 50.03,52.72 51.64,52.72 53.56,54.65 53.56,60.72 54.05,61.21 54.05,66.28 53.96,66.36 53.27,66.36 53.16,66.47 53.16,66.62 53.27,66.72 53.96,66.72 54.05,66.81 54.05,66.99 53.96,67.08 52.42,67.08 52.31,67.18 52.31,67.33 52.42,67.43 53.96,67.43 54.05,67.52 54.05,72.32 55.83,74.1 55.88,74.1 56.38,74.6 58.75,74.6 59.84,75.7 60.41,75.7 61.28,76.56 62.97,76.56 64.57,78.16 66.14,78.16 66.62,77.68 66.62,77.38 67.35,76.66 70.09,76.66 70.59,76.16 78.46,76.16 80.24,74.38 88.97,74.38 93.19,78.6 107.72,78.6 108.88,77.44 119.02,77.44 120.01,78.42 129.73,78.42 129.93,78.63 150.92,78.63 151.66,77.89 154.36,77.89 154.99,77.25 v2(154.99,76.92)
  BOTTOM w0.127: v2(154.99,76.92) 154.84,76.77 154.84,72.92 153.61,71.69 153.61,69.75 152.67,68.8 UCPU1.G1
CL_RST#_R: length 8.4
  TOP w0.127: v2(40.79,47.43) 41.02,47.43 41.28,47.68 41.28,48.31 41.97,49.01 42.37,49.01 42.62,48.75 42.62,48.42 R1200.1
  BOTTOM w0.127: JNGFF1.30 40.5,47.14 v2(40.79,47.43) 40.15,48.07 v3(37.8,48.07)
CLK0_PCIE_TBT: length 114.5
  TOP w0.127: v2(44.78,63.44) UT1.V19
  IN4 w0.091: v2(127.02,74.37) 127.13,74.48 127.28,74.48 127.42,74.34 127.42,74.2 127.51,74.12 128.09,74.12 128.64,74.66 128.64,75.5 128.99,75.86 128.99,77.81 126.32,80.48 91.52,80.48 90.93,79.88 86.44,79.88 86.37,79.96 85.92,79.96 83.24,77.28 80.93,77.28 77.72,80.49 54.33,80.49 53.61,79.76 49.28,79.76 47.44,77.93 47.44,73.39 43.13,69.07 43.13,68.27 43.54,67.86 44.22,67.86 45.21,66.87 45.21,64.77 44.73,64.28 44.73,63.91 44.8,63.85 45.11,63.85 45.2,63.76 45.2,63.57 45.15,63.51 44.84,63.51 v2(44.78,63.44)
  BOTTOM w0.076: UCPU1.C42 127.53,71.13 127.53,71.19 127.47,71.28 127.38,71.57 127.38,71.75 127.43,71.94 127.43,72.09 127.38,72.21 127.38,72.49 127.53,72.65 127.53,73.86 v2(127.02,74.37)
CLK0_PCIE_TBT#: length 115
  TOP w0.127: v2(44.13,63.44) UT1.T19
  IN4 w0.091: v2(126.99,73.79) 127.13,73.92 128.17,73.92 128.83,74.58 128.83,75.42 129.18,75.78 129.18,77.89 126.4,80.67 91.44,80.67 90.85,80.07 86.52,80.07 86.45,80.15 85.84,80.15 83.16,77.47 81.01,77.47 77.8,80.68 54.25,80.68 53.53,79.96 49.2,79.96 47.24,78.01 47.24,73.47 42.93,69.15 42.93,68.19 43.46,67.67 44.14,67.67 45.02,66.79 45.02,64.85 44.54,64.36 44.54,63.85 v2(44.13,63.44)
  BOTTOM w0.076: UCPU1.D42 127.43,70.58 127.43,70.69 127.35,70.96 127.35,71.07 127.32,71.18 127.22,71.5 127.21,71.55 127.21,71.8 127.25,71.89 127.25,72.08 127.21,72.18 127.21,72.56 127.37,72.72 127.37,73.74 127.27,73.84 127.04,73.84 v2(126.99,73.79)
CLK1_PCIE_WLAN: length 130.9
  IN4 w0.091: v2(127.56,74.93) 127.77,75.14 127.77,75.24 127.3,75.71 125.83,75.71 124.85,76.69 124.85,77.5 122.48,79.88 93.23,79.88 90.78,77.43 88.08,77.43 87.32,76.66 80.71,76.66 78.22,79.15 72.83,79.15 70.38,76.69 66.82,76.69 65.1,74.97 65.1,72.88 63.32,71.1 63.32,70.69 64.06,69.95 64.06,66.47 63.37,65.78 63.37,63.97 62.64,63.23 62.64,62.57 59.78,59.71 59.78,56.82 55.8,52.85 55.8,50.91 55.21,50.32 53.61,50.32 52.53,49.24 52.53,47.44 51.64,46.54 50.27,46.54 49.17,45.45 49.17,41.51 45.49,37.83 45.49,35.36 44.48,34.35 43.26,34.35 42.99,34.62 42.99,34.87 v2(42.75,35.11)
  BOTTOM w0.076: v2(127.56,74.93) 127.76,74.73 127.76,72.7 127.95,72.51 127.95,72.18 127.82,72.04 127.69,72.04 127.64,72.09 UCPU1.A42
  BOTTOM w0.127: JNGFF1.39 42.75,38.06 42.87,37.94 42.87,37.34 C1302.1 42.85,36.41 42.85,35.21 v2(42.75,35.11)
CLK1_PCIE_WLAN#: length 131.1
  IN4 w0.091: v2(128.14,74.93) 127.96,75.12 127.96,75.32 127.38,75.9 125.91,75.9 125.04,76.77 125.04,77.58 122.56,80.07 93.15,80.07 90.7,77.62 88,77.62 87.24,76.85 80.79,76.85 78.3,79.34 72.75,79.34 70.3,76.88 66.74,76.88 64.91,75.05 64.91,72.96 63.13,71.18 63.13,70.61 63.87,69.87 63.87,66.55 63.18,65.86 63.18,64.05 62.44,63.31 62.44,62.65 59.59,59.79 59.59,56.9 55.61,52.93 55.61,50.99 55.13,50.51 53.53,50.51 52.34,49.32 52.34,47.52 51.56,46.74 50.19,46.74 48.98,45.53 48.98,41.59 45.3,37.91 45.3,35.44 44.4,34.54 43.34,34.54 43.18,34.7 43.18,34.86 v2(43.41,35.09)
  BOTTOM w0.076: v2(128.14,74.93) 127.93,74.72 127.93,72.77 128.12,72.58 128.12,72.11 127.67,71.66 UCPU1.B42
  BOTTOM w0.127: v2(43.41,35.09) 43.1,35.4 43.1,36.43 C1301.1 43.12,37.28 43.12,37.9 43.25,38.03 JNGFF1.41
CLK_ITPXDP_N: length 28.8
  TOP w0.127: RC297.2 89.44,79.92 87.94,79.92 83.7,75.69 v4(82.84,75.69) 80.75,75.69 79.11,74.04 79.11,71.87 77.54,70.31 72.14,70.31 71.7,69.87 69.33,69.87 68.8,69.34 68.8,68.61 68.6,68.41 JXDP1.42
CLK_ITPXDP_N_R: length 55.3
  TOP w0.127: RC297.1 90.97,79.9 91.9,79.9 92.86,80.87 v4(125.15,80.87) 128.03,80.87 130.48,78.41 130.48,76.55 129.93,76 129.45,76 128.83,75.38 128.83,74.49 128.31,73.98 127.98,73.98 127.82,73.82 127.82,73.53 127.96,73.39 128.17,73.39 v2(128.32,73.54)
  IN4 w0.091: v2(128.32,73.54) 128.5,73.36 129.06,73.36 129.26,73.16 129.26,72.45 129.17,72.36 129.17,70.74 127.74,69.31 127.16,69.31 v2(127.08,69.23)
  BOTTOM w0.127: v2(127.08,69.23) 127.38,68.94 UCPU1.F43
CLK_ITPXDP_P: length 28.3
  TOP w0.127: JXDP1.40 69.1,68.53 69.05,68.58 69.05,69.23 69.44,69.62 71.81,69.62 72.24,70.05 77.65,70.05 79.36,71.77 79.36,73.94 80.86,75.44 83.81,75.44 v4(85.86,77.49) 88.04,79.67 89.4,79.67 RC298.2
CLK_ITPXDP_P_R: length 55.7
  TOP w0.127: RC298.1 90.97,79.65 92,79.65 92.97,80.61 v4(122.7,80.61) 127.92,80.61 130.23,78.31 130.23,76.65 129.83,76.25 129.34,76.25 128.58,75.49 128.58,74.6 128.21,74.23 127.88,74.23 127.57,73.92 127.57,73.42 127.81,73.19 127.81,72.79 127.91,72.68 128.07,72.68 v2(128.32,72.93)
  IN4 w0.091: v2(128.32,72.93) 128.47,72.78 128.65,72.78 128.73,72.86 128.73,73.09 128.8,73.17 128.98,73.17 129.07,73.08 129.07,72.53 128.98,72.44 128.98,70.82 127.66,69.5 127.46,69.5 127.38,69.58 127.38,69.76 127.31,69.83 v2(127.08,69.83)
  BOTTOM w0.127: UCPU1.E43 127.51,69.73 127.41,69.83 v2(127.08,69.83)
CLK_LPC_DEBUG: length 47
  IN1 w0.081: v2(183.44,72.53) 182.51,71.59 178.62,71.59 177.13,70.11 176.85,70.11 176.25,69.5 173.15,69.5 171.09,67.45 171.09,66 169.62,64.52 169.62,63.89 168.96,63.23 168.5,63.23 167.69,62.41 167.69,61.78 166.25,60.34 166.25,52.42 161.87,48.04 159.17,48.04 158.31,47.18 v2(157.79,47.18)
  BOTTOM w0.127: 184.15,71.22 JLPDE1.10 ; 184.15,71.22 184.15,70.55 v3(184.49,70.21) ; 184.15,71.22 184.15,71.74 183.44,72.45 v2(183.44,72.53) ; RC22.2 157.3,46.19 CC5.2 157.79,46.67 v2(157.79,47.18)
CLK_PCI_MEC: length 45.3
  TOP w0.127: RE80.1 180.49,70.65 180.49,70.14 v2(180.62,70.01) 180.3,69.69 180.3,69.24 180.36,69.18 180.36,68.72 UE5.A29
  IN1 w0.081: v2(180.62,70.01) 180.32,69.71 180.32,69.12 179.92,68.72 178.67,68.72 177.39,67.45 176.91,67.45 176.88,67.42 175.82,67.42 175.79,67.45 175.54,67.45 174.03,65.94 174.03,64.96 173.97,64.89 173.97,64.52 172.89,63.45 172.89,61.83 169.78,58.72 169.78,57.53 170.98,56.33 170.98,54.62 166.83,50.46 166.83,49.44 164.88,47.49 164.88,46.75 162.64,44.5 159.77,44.5 v2(159.53,44.26)
  BOTTOM w0.127: RC18.2 156.92,45.3 157.3,45.68 CC4.2 157.73,45.68 159.16,44.26 v2(159.53,44.26)
CLK_PCIE_MMI: length 129.7
  IN4 w0.091: v2(204.62,19.64) 204.43,19.83 204.43,20.05 203.71,20.78 202.04,20.78 200.09,22.73 196.53,22.73 194.79,24.47 194.79,27.84 193.84,28.79 193.84,31.9 190.6,35.14 190.47,35.14 186.61,38.99 186.61,47.08 179.52,54.17 179.52,54.78 178.45,55.84 178.45,57.28 178.66,57.5 178.66,58.05 176.85,59.86 176.85,61.68 176.13,62.41 175.02,62.41 174.31,63.11 174.31,64.81 174.24,64.88 174.24,65.84 174.69,66.29 174.69,67.89 175.34,68.54 175.34,71.13 172.22,74.25 172.22,76.41 169.19,79.43 168.62,79.43 168.15,79.91 159.2,79.91 158.87,79.58 155.67,79.58 155.46,79.37 153.2,79.37 152.59,79.98 137.24,79.98 134.81,77.56 134.81,74.23 134.31,73.73 131.06,73.73 130.53,73.21 130.53,69.93 130.22,69.62 129.96,69.62 v2(129.8,69.79)
  BOTTOM w0.127: JIO1.20 204.51,18.72 204.34,18.89 204.34,19.49 204.5,19.64 v2(204.62,19.64) ; UCPU1.E38 129.99,69.59 v2(129.8,69.79)
CLK_PCIE_MMI#: length 129.6
  IN4 w0.091: v2(203.91,19.64) 204.09,19.64 204.24,19.8 204.24,19.97 203.63,20.58 201.96,20.58 200.01,22.54 196.45,22.54 194.6,24.39 194.6,27.76 193.65,28.71 193.65,31.82 190.52,34.94 190.39,34.94 186.42,38.91 186.42,47 179.32,54.09 179.32,54.7 178.26,55.76 178.26,57.36 178.47,57.58 178.47,57.97 176.66,59.78 176.66,61.6 176.05,62.21 174.94,62.21 174.12,63.03 174.12,64.73 174.05,64.8 174.05,65.92 174.5,66.37 174.5,67.97 175.14,68.62 175.14,71.05 172.02,74.17 172.02,76.33 169.11,79.24 168.54,79.24 168.07,79.71 159.28,79.71 158.95,79.38 155.75,79.38 155.54,79.18 153.12,79.18 152.51,79.79 137.32,79.79 135,77.48 135,74.15 134.39,73.54 131.14,73.54 130.72,73.13 130.72,69.85 130.3,69.43 130.04,69.43 v2(129.8,69.18)
  BOTTOM w0.127: v2(129.8,69.18) 129.39,69.59 UCPU1.E40 ; v2(203.91,19.64) 203.99,19.64 204.09,19.54 204.09,18.88 203.91,18.7 203.91,18.41 JIO1.22
CLK_PCIE_SSD: length 111.8
  IN4 w0.091: v2(189.87,37.19) 189.79,37.12 189.33,37.12 188.52,37.93 188.52,46.56 187.29,47.79 186.76,47.79 180.13,54.42 180.13,55 179.14,55.99 179.14,57.01 179.26,57.13 179.26,58.31 177.49,60.08 177.49,61.89 176.37,63 176.27,63 175.99,63.29 175.99,63.42 175.79,63.61 175.79,64.59 175.39,65 175.39,66.97 175.94,67.52 175.94,71.8 175.2,72.54 175.2,72.93 175.48,73.21 175.48,76.75 173.36,78.87 171.86,78.87 170.09,80.64 155.65,80.64 155.02,80.02 153.43,80.02 152.83,80.62 131.7,80.62 130.23,79.14 130.23,74.91 129.87,74.55 129.36,74.55 129.08,74.27 129.08,74.15 v2(128.88,73.95)
  BOTTOM w0.076: UCPU1.C40 128.59,71.01 128.52,71.08 128.52,71.26 128.59,71.32 128.83,71.32 128.98,71.41 129.04,71.57 129.04,71.77 129.01,71.82 129,71.85 129,71.9 128.99,71.94 128.99,72.05 129.04,72.19 129.04,72.89 129.11,72.96 129.11,73.72 v2(128.88,73.95)
  BOTTOM w0.127: JNGFF2.55 183.81,36.79 183.95,36.66 188.79,36.66 189.16,37.02 189.69,37.02 v2(189.87,37.19)
CLK_PCIE_SSD#: length 111.8
  IN4 w0.091: v2(189.87,36.61) 189.55,36.93 189.25,36.93 188.33,37.85 188.33,46.48 187.21,47.59 186.68,47.59 179.93,54.34 179.93,54.92 178.94,55.91 178.94,57.09 179.07,57.21 179.07,58.23 177.29,60 177.29,61.81 176.29,62.81 176.19,62.81 175.79,63.21 175.79,63.34 175.6,63.53 175.6,64.51 175.19,64.92 175.19,67.05 175.74,67.6 175.74,71.72 175.01,72.46 175.01,73.01 175.29,73.29 175.29,76.67 173.28,78.67 171.78,78.67 170.01,80.45 155.73,80.45 155.1,79.83 153.35,79.83 152.75,80.43 131.78,80.43 130.42,79.06 130.42,74.83 129.95,74.35 129.44,74.35 129.28,74.19 129.28,74.1 129.43,73.95 v2(129.52,73.95)
  BOTTOM w0.076: UCPU1.D40 129.06,70.65 129.06,71.07 129.12,71.27 129.14,71.35 129.19,71.5 129.19,71.52 129.2,71.55 129.2,71.8 129.17,71.89 129.17,71.89 129.17,71.92 129.15,71.97 129.15,72.02 129.2,72.16 129.2,72.82 129.27,72.89 129.27,73.71 v2(129.52,73.95)
  BOTTOM w0.127: JNGFF2.53 183.86,36.29 183.97,36.4 188.9,36.4 189.26,36.77 189.71,36.77 v2(189.87,36.61)
CLK_SMB: length 13.8
  TOP w0.127: 69.29,20.53 68.96,20.86 68.96,21.07 v2(69.11,21.22) ; 69.29,20.53 PD101.3 ; 69.29,20.53 69.01,20.53 68.92,20.44 68.92,19.96 68.58,19.62 68.15,19.62 68.05,19.52 68.05,19.39 68.16,19.29 PRP100.6 68.16,18.72 68.4,18.47 68.81,18.47 68.99,18.3 68.99,17.56 v3(70.8,15.75)
  BOTTOM w0.127: v2(69.11,21.22) 68.96,21.37 68.96,21.72 67.54,23.14 67.54,23.33 68.1,23.89 JBATT1.3
CLK_TP_SIO: length 70.3
  TOP w0.127: v2(174.47,22.28) 180.11,16.65 MD9.3 181.59,17.23 181.59,17.98 180.7,18.87 C1229.1 181.2,19.52 181.2,20.71 v2(181.41,20.91) ; v2(171.2,57.41) 171.15,57.46 171.15,59.14 170.71,59.57 170.71,60.49 170.94,60.71 170.94,65.18 171.81,66.05 173.61,66.05 RE6.2 174.48,66.05 174.92,66.05 175.23,65.74 175.23,65.08 175.64,64.68 176.13,64.68 176.31,64.86 176.62,64.86 176.78,65.02 177.16,65.02 UE5.A37
  IN2 w0.089: v2(174.47,22.28) 174.47,26.34 173.48,27.34 173.48,33.06 170.84,35.7 170.84,36.43 171.04,36.64 171.04,38.29 171.74,38.99 171.74,56.87 v2(171.2,57.41)
  BOTTOM w0.127: JTP1.8 183.16,19.79 182.75,20.2 181.67,20.2 181.41,20.46 v2(181.41,20.91)
CLKREQ_PCIE#0: length 264.9
  TOP w0.127: 48.72,57.59 48.82,57.59 49.17,57.24 RT21.2 ; 48.72,57.59 48.38,57.25 47.94,57.25 47.89,57.3 UT1.AC5 ; 48.72,57.59 v2(48.72,57.59)
  IN1 w0.081: v2(63.35,18.5) 62.28,18.5 61.7,19.08 56.25,19.08 56.23,19.06 54.99,19.06 54.58,18.66 54.58,18.05 54.08,17.55 50.1,17.55 49.65,17.1 47.41,17.1 46.74,16.42 43.52,16.42 41.37,18.57 39.76,18.57 37.08,21.24 37.08,23.87 36.06,24.9 36.06,31.07 37.52,32.53 37.52,35.3 37.06,35.76 37.06,36.99 38.3,38.24 40.12,38.24 41.39,39.51 41.95,39.51 43.49,41.04 43.49,48.41 43.22,48.68 43.22,49.75 44.55,51.09 46.25,51.09 47.3,52.13 47.3,53.27 47.9,53.88 48.5,53.88 49.38,54.76 49.38,56.93 v2(48.72,57.59)
  IN4 w0.081: v2(146.26,53.74) 146.44,53.74 146.71,54.01 146.71,55.87 147.03,56.19 148.7,56.19 149.64,55.25 149.64,54.01 151.22,52.43 151.22,50.55 152.5,49.27 154.24,49.27 154.56,49.59 154.91,49.59 156.07,48.43 156.07,46.83 156.98,45.92 156.98,45.1 157.96,44.13 157.96,42.67 159.04,41.58 159.04,40.59 161.34,38.29 163.42,38.29 164.29,37.42 164.29,35.3 165.31,34.28 165.31,23.35 161.03,19.07 147.54,19.07 147.14,19.47 145.5,19.47 145,18.97 123.53,18.97 123.12,19.37 106.77,19.37 106.26,19.88 101.27,19.88 99.24,21.9 97.41,21.9 96.48,22.83 96.48,25.02 96.38,25.11 96.38,28.84 95.54,29.68 94.22,29.68 92.78,31.12 92.78,31.73 91.93,32.58 88.2,32.58 87.39,31.76 85.6,31.76 84.32,30.48 79.47,30.48 75.52,26.53 72.96,26.53 67.65,21.22 67.65,19.63 67.11,19.09 66.46,19.09 65.87,18.5 v2(63.35,18.5)
  BOTTOM w0.076: v2(146.26,53.74) 146.35,53.74 UCPU1.AR10
  BOTTOM w0.127: v2(48.72,57.59) 48.81,57.59 49.17,57.22 49.17,56.24 49.01,56.08 49.01,54.42 48.67,54.07 48.67,53.44 49.7,52.41 49.7,52.09 50.01,51.77 v1(50.58,51.77) 51.69,51.77 52.63,50.83 53.89,50.83 54.53,50.19 59.65,50.19 60.42,50.95 RC63.2
CLKREQ_PCIE#1: length 195
  IN2 w0.089: v2(44.35,36.84) 44.58,36.84 45.49,35.92 45.49,34.96 44.12,33.59 42.48,33.59 41.74,32.85 41.74,32.34 42.39,31.68 43.66,31.68 44.35,32.37 46.23,32.37 53.54,25.05 55.68,25.05 56.21,24.52 58.01,24.52 60.02,26.53 63.07,26.53 64.43,27.89 75.73,27.89 v2(77.24,29.4)
  IN4 w0.081: v2(77.24,29.4) 77.8,29.4 79.33,30.92 84.17,30.92 85.15,31.9 85.15,32.5 85.44,32.79 87.35,32.79 88.16,33.61 88.58,33.61 88.99,33.19 91.9,33.19 93.2,31.9 93.2,31.3 94.4,30.1 95.71,30.1 96.8,29.01 96.8,25.29 96.9,25.19 96.9,23 97.59,22.32 99.42,22.32 101.44,20.29 106.44,20.29 106.94,19.79 123.3,19.79 123.7,19.38 144.83,19.38 145.33,19.89 147.32,19.89 147.72,19.49 160.86,19.49 164.89,23.52 164.89,34.1 163.87,35.12 163.87,37.25 163.25,37.87 161.17,37.87 157.54,41.5 157.54,43.96 156.57,44.93 156.57,45.74 155.65,46.66 155.65,47.46 155.65,48 155.16,48.49 154.56,48.49 154.43,48.62 152.56,48.62 150.8,50.38 150.8,52.11 149.81,53.1 148.72,53.1 v2(148.08,53.74)
  BOTTOM w0.127: UCPU1.AT7 148.25,53.74 v2(148.08,53.74) ; JNGFF1.45 44.25,37.66 44.76,37.14 45.03,37.14 RC47.2 44.37,36.86 v2(44.35,36.84)
CLKREQ_PCIE#3: length 42.9
  TOP w0.127: RC59.2 174.83,36.94 174.83,36.73 v2(174.49,36.4)
  IN2 w0.089: v2(160.31,40.34) 159.93,39.96 158.98,39.96 156.37,42.58 154.83,42.58 154.23,43.18 149.71,43.18 148.57,44.32 148.57,46.69 148.69,46.82 148.69,48.98 146.53,51.14 146.53,52.83 v2(146.26,53.1)
  BOTTOM w0.076: UCPU1.AT10 146.6,53.45 v2(146.26,53.1)
  BOTTOM w0.127: JNGFF2.52 175.6,36.05 174.84,36.05 v2(174.49,36.4) 174.38,36.4 173.94,36.84 173.94,37.45 172.94,38.45 v3(172.44,38.45) 164.39,38.45 163.42,39.42 162.57,39.42 161.64,40.34 v2(160.31,40.34)
CLKREQ_PCIE#5: length 80.8
  TOP w0.127: v2(201.98,17.74) 202.29,18.04 RC190.2
  IN4 w0.081: v2(171.32,36.33) 170.47,35.47 170.47,31.36 173.75,28.07 173.75,26.94 175.83,24.86 175.83,23.19 180.35,18.67 186.55,18.67 187.01,18.21 193.47,18.21 193.65,18.39 196.79,18.39 197.9,17.28 201.52,17.28 v2(201.98,17.74) ; v2(149,52.54) 149,51.95 149.42,51.53 149.42,51.1 152.31,48.21 154.25,48.21 154.39,48.07 154.99,48.07 155.24,47.82 155.24,47.04 155.24,46.48 156.15,45.57 156.15,44.76 157.12,43.78 157.12,41.33 161,37.45 161.36,37.45 v2(161.65,37.17)
  BOTTOM w0.076: v2(149,52.54) 148.93,52.54 148.67,52.8 UCPU1.AU7
  BOTTOM w0.127: v2(201.98,17.74) 201.51,18.21 201.51,18.41 JIO1.30 ; v2(171.32,36.33) 171.32,37.4 170.69,38.03 163.27,38.03 162.41,37.17 v2(161.65,37.17)
CLKRUN#: length 57.9
  TOP w0.127: UE5.A32 178.86,69.03 178.51,69.38 178.51,69.38 v2(178.44,69.46)
  IN1 w0.081: v2(149.2,46.72) 149.35,46.57 149.84,46.57 150.74,45.66 158.63,45.66 159.33,44.97 162.45,44.97 164.3,46.82 164.3,47.57 165.86,49.13 165.86,50.16 170.52,54.81 170.52,56.14 169.32,57.34 169.32,59.42 172.29,62.39 172.29,63.87 173.57,65.15 173.57,66.72 174.93,68.08 175.77,68.08 175.82,68.03 175.83,68.03 175.83,68.03 175.84,68.03 175.88,67.99 175.9,67.99 176.02,67.88 176.69,67.88 176.81,67.99 177.26,67.99 177.29,68.03 177.3,68.03 177.31,68.03 177.32,68.03 178.44,69.15 v2(178.44,69.46)
  BOTTOM w0.076: 148.13,47.79 148.06,47.86 147.63,47.86 146.79,48.7 146.79,48.94 146.28,49.45 146.28,50.43 146.23,50.48 146.23,51.29 145.95,51.57 UCPU1.AW11
  BOTTOM w0.127: RC27.2 150.27,46.14 149.84,46.57 149.35,46.57 v2(149.2,46.72) 148.9,46.72 148.64,46.97 148.64,47.28 148.13,47.79
COMP_IA: length 3.7
  TOP w0.203: v2(72.85,53.45) 72.61,53.45 72.3,53.76 PU1000.16
  BOTTOM w0.203: v2(72.85,53.45) 72.85,53.63 72.42,54.06 PR1123.2
  BOTTOM w0.254: PC1056.2 PR1123.2
COMP_VSA: length 3.7
  TOP w0.203: v2(69.83,57.21) 69.83,57.21 69.83,56.92 69.56,56.66 PU1000.24
  BOTTOM w0.254: PR1090.1 PC1081.1 68.68,56.27 69.62,57.21 69.83,57.21 69.83,57.21 v2(69.83,57.21)
CORE_SNUB: length 3.2
  TOP w0.127: PC1115.1 v3(85.38,59.39)
  TOP w0.508: PR1101.2 PC1115.1
CORE_SW:
  vias: v2(85.4,62.24) v2(85.57,63.84) v2(87.07,64.96) v2(88.04,65.11) v2(88.67,60.21) v2(89.1,65.26) v2(89.05,64.47) v2(89.15,61.83) v3(88.88,63.59)
CORE_VID0: length 80.1
  TOP w0.127: PR1419.1 204.65,72.09 205.08,71.66 205.08,67.17 204.2,66.29 v3(203.68,66.29) 196.28,66.29 195.49,67.08 191.99,67.08 191.16,67.91 191.16,68.58 190.55,69.19 v2(189.68,69.19)
  IN3 w0.089: v2(189.68,69.19) 188.6,70.27 185.03,70.27 183.83,71.47 179.11,71.47 178.71,71.08 174.82,71.08 170.89,67.15 168.59,67.15 168.21,67.53 164.44,67.53 162.93,66.03 161.78,66.03 161.15,65.4 161.15,61.59 160.7,61.15 160.17,61.15 159.69,60.67 159.69,60.41 157.6,58.31 157.14,58.31 156.27,57.44 154.67,57.44 154.13,57.98 151.27,57.98 150.03,56.74 146.46,56.74 145.85,56.13 145.2,56.13 144.96,55.89 144.96,55.44 v2(145.37,55.03)
  BOTTOM w0.076: v2(145.37,55.03) 145.74,55.4 UCPU1.AN11
CORE_VID1: length 86.2
  TOP w0.127: PR1420.1 197.16,69.43 v3(195.53,67.8) 194.73,67.8 194.56,67.97 193.39,67.97 192.83,67.4 192.03,67.4 191.41,68.02 191.41,70.04 v2(190.78,70.67)
  IN1 w0.081: v2(190.78,70.67) 190.78,71.1 189.89,71.99 188.61,71.99 187.68,72.92 184.54,72.92 184.31,73.15 180.94,73.15 180.42,72.63 177.83,72.63 175.99,70.79 170.28,70.79 169.44,69.96 169.44,69.35 170.63,68.17 170.63,66.25 167.23,62.85 167.23,61.97 165.79,60.53 165.79,52.61 164.01,50.83 156.39,50.83 156.26,50.71 152.4,50.71 149.44,53.68 149.44,55.18 148.47,56.14 145.22,56.14 144.88,55.8 144.88,55.64 v2(144.38,55.14)
  BOTTOM w0.127: UCPU1.AN13 144.64,55.4 v2(144.38,55.14)
CPU_B+: length 18.7
  IN1 w0.203: v2(63.48,57.36) 63.73,57.11 64.53,57.11 66.31,58.89 74.22,58.89 77.65,55.46 v2(79.1,55.46)
  BOTTOM w0.203: PR1066.2 v2(63.48,57.36)
  vias: v2(76.18,41.11) v2(76.18,40.47) v2(76.94,41.11) v2(76.94,40.47) v2(77.32,45.17) v2(77.95,45.17) v2(77.95,41.11) v2(77.95,40.47) v2(78.55,54.38) v2(78.86,54.92) v2(79.24,60.37) v2(79.19,54.39) v2(79.51,59.57) v2(79.46,54.92) v2(79.73,63.33) v2(79.73,62.7) v2(79.73,62.06) v2(79.74,61.46) v2(79.73,55.46) v2(79.81,60.82) v2(79.83,60.2) v2(79.77,54.37)
CPU_DDI1_AUXN: length 100.5
  TOP w0.127: v2(53.13,55.83) 53,55.96 52.37,55.96 CT26.2
  IN2 w0.076: v2(123.4,68.57) 123.16,68.81 123.04,68.81 122.99,68.76 122.99,68.27 122.92,68.2 122.82,68.2 122.76,68.26 122.76,70.5 122.73,70.53 122.73,70.54
  IN2 w0.102: 122.73,70.54 122.73,70.85 121.59,71.99 115.73,71.99 115.43,72.29 112.22,72.29 111.64,71.71 111.64,71.02 111.21,70.6 109.7,70.6 108.38,69.27 107.77,69.27 107.04,68.54 100.25,68.54 96.95,71.84 91.25,71.84 90.91,72.18 80.91,72.18 80.33,72.75 79.38,72.75 78.71,73.42 70.59,73.42 70.44,73.27 68.97,73.27 67.82,72.12 65.07,72.12 64.35,71.41 63.66,71.41 59.01,66.76 58.38,66.76 57.52,65.9 57.03,65.9 56.69,65.57 56.69,65.07 55.09,63.47 55.09,62.96 53.41,61.29 51.43,61.29 50.98,60.84 50.27,60.84 49.7,60.27 49.7,58.2 50.09,57.81 50.09,55.13 50.28,54.94 51.81,54.94 52.03,54.72 53.07,54.72 53.86,55.51 53.86,56.08 53.75,56.19 53.49,56.19 v2(53.13,55.83)
  BOTTOM w0.127: UCPU1.G50 123.85,68.51 123.8,68.57 v2(123.4,68.57)
CPU_DDI1_AUXN_C: length 9.7
  TOP w0.127: v2(45.43,60.19) 45.75,59.87 UT1.W11 ; v2(50.95,55.76) 51.1,55.91 51.34,55.91 CT26.1
  IN4 w0.091: v2(50.95,55.76) 50.93,55.78 50.32,55.78 49.46,56.64 49.46,57.23 49.16,57.54 49.16,58.32 48.56,58.92 47.3,58.92 46.92,59.3 45.69,59.3 45.44,59.56 45.44,59.82 45.43,59.84 v2(45.43,60.19)
CPU_DDI1_AUXP: length 100.5
  TOP w0.127: CT25.2 52.26,56.21 52.92,56.21 v2(53.13,56.42)
  IN2 w0.076: 122.95,70.54 122.95,70.53 122.92,70.5 122.92,69.06 123.01,68.98 123.18,68.98 v2(123.39,69.19)
  IN2 w0.102: 122.95,70.54 122.95,70.95 121.68,72.22 115.82,72.22 115.53,72.51 112.13,72.51 111.42,71.8 111.42,71.12 111.12,70.82 109.61,70.82 108.29,69.5 107.68,69.5 106.94,68.76 100.35,68.76 97.05,72.06 91.34,72.06 91,72.4 81,72.4 80.42,72.98 79.47,72.98 78.8,73.64 70.5,73.64 70.35,73.49 68.87,73.49 67.73,72.35 64.97,72.35 64.26,71.63 63.57,71.63 58.92,66.98 58.28,66.98 57.43,66.13 56.93,66.13 56.47,65.66 56.47,65.16 54.86,63.56 54.86,63.06 53.32,61.52 51.34,61.52 50.89,61.07 50.17,61.07 49.47,60.37 49.47,58.1 49.86,57.72 49.86,55.04 50.19,54.71 51.72,54.71 51.94,54.5 53.16,54.5 54.08,55.42 54.08,56.18 53.84,56.42 v2(53.13,56.42)
  BOTTOM w0.127: UCPU1.F50 v2(123.39,69.19)
CPU_DDI1_AUXP_C: length 9.7
  TOP w0.127: UT1.Y11 46.4,59.87 v2(46.08,60.19) ; v2(50.95,56.35) 51.14,56.16 51.35,56.16 CT25.1
  IN4 w0.091: v2(46.08,60.19) 45.63,59.74 45.63,59.64 45.77,59.5 47,59.5 47.38,59.11 48.64,59.11 49.35,58.4 49.35,57.62 49.66,57.31 49.66,56.72 50.4,55.98 50.6,55.98 50.95,56.33 v2(50.95,56.35)
CPU_DDI2_AUXN: length 117.2
  TOP w0.127: v2(53.15,57.66) 53.02,57.53 52.33,57.53 CT107.2
  IN2 w0.076: v2(124.31,69.81) 124.15,69.66 123.98,69.66 123.9,69.73 123.9,70.42 123.93,70.45 123.93,70.46
  IN2 w0.102: 123.93,70.46 123.93,70.98 123.24,71.68 123.24,73.53 123.54,73.83 123.54,77.44 121.09,79.89 91.85,79.89 91.31,79.35 90.49,79.35 89.82,78.69 89.82,78.17 89.56,77.91 87.8,77.91 86.88,77 84.66,77 84.35,76.69 80.48,76.69 78.33,78.85 76.46,78.85 76.37,78.75 66.17,78.75 65.13,77.71 65.13,77.27 64.72,76.86 59.6,76.86 59.06,76.31 58.41,76.31 53.85,71.75 53.85,71.05 52.91,70.11 52.38,70.11 49.4,67.14 49.4,66.47 49.05,66.12 49.05,64.06 48.67,63.67 48.67,58.23 49.16,57.74 49.16,54.7 50.4,53.46 51.07,53.46 51.4,53.78 53.51,53.78 54.79,55.06 54.79,56.99 54.12,57.66 53.15,57.66 v2(53.15,57.66)
  BOTTOM w0.127: UCPU1.E48 124.53,69.59 v2(124.31,69.81)
CPU_DDI2_AUXN_C: length 9.2
  TOP w0.127: UT1.W12 45.75,60.52 v2(45.43,60.84) ; v2(50.95,57.65) 51.1,57.51 51.3,57.51 CT107.1
  IN4 w0.091: v2(45.43,60.84) 45.63,61.04 45.63,61.24 45.87,61.49 47.25,61.49 50.04,58.71 50.04,57.89 50.31,57.61 50.91,57.61 v2(50.95,57.65)
CPU_DDI2_AUXP: length 117.2
  TOP w0.127: CT108.2 52.29,57.28 52.95,57.28 v2(53.15,57.08)
  IN2 w0.076: 123.71,70.46 123.71,70.45 123.74,70.42 123.74,69.66 123.85,69.55 123.85,69.02 123.93,68.94 124.21,68.94 124.31,69.05 v2(124.31,69.18)
  IN2 w0.102: 123.71,70.46 123.71,70.89 123.01,71.59 123.01,73.62 123.32,73.92 123.32,77.35 121,79.67 91.94,79.67 91.4,79.13 90.58,79.13 90.04,78.6 90.04,78.08 89.65,77.69 87.89,77.69 86.98,76.77 84.75,76.77 84.44,76.46 80.39,76.46 78.23,78.62 76.56,78.62 76.46,78.53 66.26,78.53 65.35,77.62 65.35,77.17 64.81,76.63 59.69,76.63 59.15,76.09 58.5,76.09 54.07,71.66 54.07,70.96 53,69.89 52.47,69.89 49.63,67.05 49.63,66.37 49.28,66.02 49.28,63.97 48.89,63.58 48.89,58.32 49.38,57.83 49.38,54.8 50.5,53.68 50.98,53.68 51.3,54 53.42,54 54.57,55.16 54.57,56.9 54.03,57.44 53.79,57.44 53.68,57.33 53.68,57.2 53.81,57.08 53.81,56.85 53.71,56.75 53.53,56.75 53.43,56.85 53.43,57 53.35,57.08 v2(53.15,57.08)
  BOTTOM w0.127: v2(124.31,69.18) 124.55,68.94 UCPU1.F48
CPU_DDI2_AUXP_C: length 9.2
  TOP w0.127: v2(50.95,57.07) 51.14,57.25 51.39,57.25 CT108.1 ; v2(46.08,60.84) 46.08,60.82 46.38,60.52 UT1.Y12
  IN4 w0.091: v2(46.08,60.84) 46.03,60.8 45.94,60.8 45.82,60.92 45.82,61.16 45.95,61.3 47.17,61.3 49.85,58.63 49.85,57.81 50.25,57.4 50.62,57.4 v2(50.95,57.07)
CPU_DP1_CTRL_CLK: length 260.8
  TOP w0.127: v2(46.08,57.59) 46.4,57.27 UT1.Y5 ; RC175.1 150.24,75.62 150.24,74.53 v2(150.19,74.48)
  IN2 w0.089: v2(46.08,57.59) 46.53,57.14 46.53,56.54 45.68,55.68 43.3,55.68 42.76,55.14 42.76,54.02 42.05,53.3 42.05,52.64 37.9,48.49 37.9,43.21 38.36,42.75 38.36,41.58 37.74,40.96 37.74,39.96 37.19,39.4 37.19,37.45 36.79,37.06 36.79,36.03 37.52,35.3 37.52,34.85 37.88,34.48 37.88,32.31 36.79,31.22 36.79,29.89 36.13,29.23 36.13,26.14 36.79,25.48 36.79,24.9 35.93,24.03 35.93,20.57 36.62,19.88 38.24,19.88 39.84,18.28 41.33,18.28 42.16,17.46 42.16,17.46 42.68,16.94 43.17,16.94 43.95,17.72 49.08,17.72 49.45,17.35 50.47,17.35 50.91,17.79 55.17,17.79 59.66,17.79 60.04,17.41 63.17,17.41 63.88,18.12 67.13,18.12 68.68,19.67 70.39,19.67 75.79,25.07 79.17,25.07 79.72,24.52 86,24.52 86.13,24.39 87.78,24.39 88.09,24.7 89.21,24.7 89.84,25.33 92.64,25.33 93.46,24.51 93.46,23.23 93.79,22.89 94.97,22.89 95.56,22.31 96.14,22.31 97.84,22.31 103.29,16.86 106.18,16.86 107.31,17.99 107.85,17.99 115.38,17.99 116.19,17.17 116.92,17.17 118.38,15.72 125.12,15.72 127.23,17.83 130.92,17.83 133.03,15.72 150.92,15.72 152.03,16.84 157.04,16.84 158.88,18.68 162.13,18.68 164.61,21.16 164.61,34.35 165.1,34.85 165.1,38.2 163.77,39.53 163.77,40.65 164.62,41.49 164.62,47.19 159.01,52.79 159.01,54.64 157.54,56.11 157.13,56.11 157.13,56.11 156.77,56.11 155.7,57.18 154.54,57.18 154.09,56.73 152.83,56.73 152.58,56.99 152.58,58.1 152.04,58.63 152.04,60.6 149.49,63.15 148.11,63.15 147.63,63.63 147.63,64.02 147.33,64.32 146.76,64.32 v2(145.2,65.88)
  IN3 w0.089: v2(150.19,74.48) 150.01,74.66 149.35,74.66 148.77,74.08 148.77,73.52 146.43,71.18 146.43,70.06 145.77,69.4 145.77,66.68 145.2,66.11 v2(145.2,65.88)
  BOTTOM w0.076: v2(145.2,65.88) 144.84,66.28 UCPU1.L13
CPU_DP1_CTRL_DATA: length 256.7
  TOP w0.127: UT1.R4 43.79,56.62 v2(43.47,56.93) ; RC178.1 149.33,74.84 149.17,74.68 v2(149.17,73.87)
  IN2 w0.089: v2(43.47,56.93) 43.47,56.29 42.57,55.39 42.26,55.39 41.91,55.04 41.91,53.89 40.78,52.76 40.78,52.14 40.86,52.05 40.86,51.75 37.69,48.58 37.69,44.02 37.47,43.8 37.47,41.9 36.38,40.81 36.38,36.13 37.3,35.21 37.3,34.76 37.67,34.39 37.67,32.4 36.58,31.31 36.58,29.98 35.92,29.32 35.92,26.05 36.58,25.39 36.58,24.99 35.71,24.12 35.71,20.48 36.53,19.67 38.15,19.67 39.75,18.07 41.24,18.07 42.63,16.68 44.39,16.68 45.22,17.51 48.99,17.51 49.36,17.13 50.56,17.13 51,17.57 55.08,17.57 59.57,17.57 59.95,17.19 63.26,17.19 63.97,17.9 67.22,17.9 68.77,19.45 70.48,19.45 75.88,24.85 79.08,24.85 79.63,24.3 85.92,24.3 86.04,24.18 87.87,24.18 88.18,24.48 89.29,24.48 89.93,25.12 92.55,25.12 93.24,24.42 93.24,23.14 93.7,22.68 94.88,22.68 95.47,22.09 96.23,22.09 97.75,22.09 103.2,16.64 106.27,16.64 107.4,17.77 107.76,17.77 115.29,17.77 116.1,16.96 116.83,16.96 118.29,15.5 125.21,15.5 127.32,17.61 130.83,17.61 132.94,15.5 151.03,15.5 152.15,16.62 157.24,16.62 159.08,18.46 162.22,18.46 164.82,21.07 164.82,34.26 165.32,34.76 165.32,38.29 163.99,39.62 163.99,40.56 164.84,41.41 164.84,47.27 159.23,52.88 159.23,54.73 157.63,56.33 157.04,56.33 156.86,56.33 155.79,57.4 154.72,57.4 153.05,59.07 153.05,59.25 153.05,60.45 152.77,60.73 152.23,60.73 149.56,63.39 148.25,63.39 147.87,63.77 147.87,64.12 147.43,64.56 146.96,64.56 145.83,65.68 145.83,65.83 v2(145.78,65.88)
  IN3 w0.089: v2(149.17,73.87) 149.17,73.62 146.71,71.15 146.71,66.81 v2(145.78,65.88)
  BOTTOM w0.127: v2(43.47,56.93) 43.47,55.72 v3(43.74,55.46) ; UCPU1.L12 145.49,66.18 v2(145.78,65.88)
CPU_DP1_HPD: length 255.1
  TOP w0.076: 46.86,55.13 46.86,55.69 UT1.AA2
  TOP w0.127: v2(147.78,65.87) 147.74,65.91 147.74,65.93 148.31,66.51 148.84,66.51 RC312.2 ; v2(47.73,54.46) 47.71,54.46 47.68,54.49 47.33,54.49 46.86,54.96 46.86,55.13
  IN1 w0.081: v2(47.73,54.46) 47.7,54.43 47.7,53.97 46.54,52.81 43.51,52.81 41.34,50.64 39.64,50.64 37.38,48.38 36.46,48.38 v2(36.38,48.3)
  IN2 w0.089: v2(147.78,65.87) 148.18,65.46 150.22,65.46 151.56,64.12 151.56,62.31 152.49,61.38 153.09,61.38 154.39,60.08 155.36,60.08 157.05,58.4 157.35,58.4 157.94,57.81 157.94,57.68 158.51,57.11 164.05,57.11 165.99,55.16 165.99,48.24 166.18,48.05 166.18,42.67 166.58,42.27 166.58,40.78 166.49,40.69 166.49,39.47 168.28,37.68 168.28,34.95 166.49,33.16 166.49,27.16 165.57,26.25 165.57,20.9 162.49,17.81 159.51,17.81 157.58,15.88 152.33,15.88 151.3,14.86 132.67,14.86 130.56,16.96 127.59,16.96 125.48,14.86 118.02,14.86 116.56,16.31 115.83,16.31 115.02,17.12 108.67,17.12 107.54,16 102.93,16 97.48,21.45 95.2,21.45 94.61,22.03 93.43,22.03 92.6,22.87 92.6,24.15 92.36,24.39 90.12,24.39 89.56,23.83 88.45,23.83 83.42,18.8 69.04,18.8 67.49,17.26 64.24,17.26 63.53,16.54 59.68,16.54 59.32,16.91 56.42,16.91 55.84,16.32 55.13,16.32 54.53,16.92 51.27,16.92 50.83,16.49 49.09,16.49 48.72,16.86 46.69,16.86 45.86,16.03 42.36,16.03 42.32,16.07 40.3,16.07 39.18,17.19 38.09,17.19 34.46,20.82 34.46,21.7 35.02,22.26 35.02,27.26 35.27,27.5 35.27,29.59 35.93,30.25 35.93,32.29 35.69,32.53 35.69,33.26 36,33.57 36,34.56 35.73,34.82 35.73,41.58 35.52,41.79 35.52,43.7 36.4,44.59 36.4,48.32 v2(36.38,48.3)
  BOTTOM w0.127: UCPU1.L9 147.44,66.26 147.78,65.92 v2(147.78,65.87)
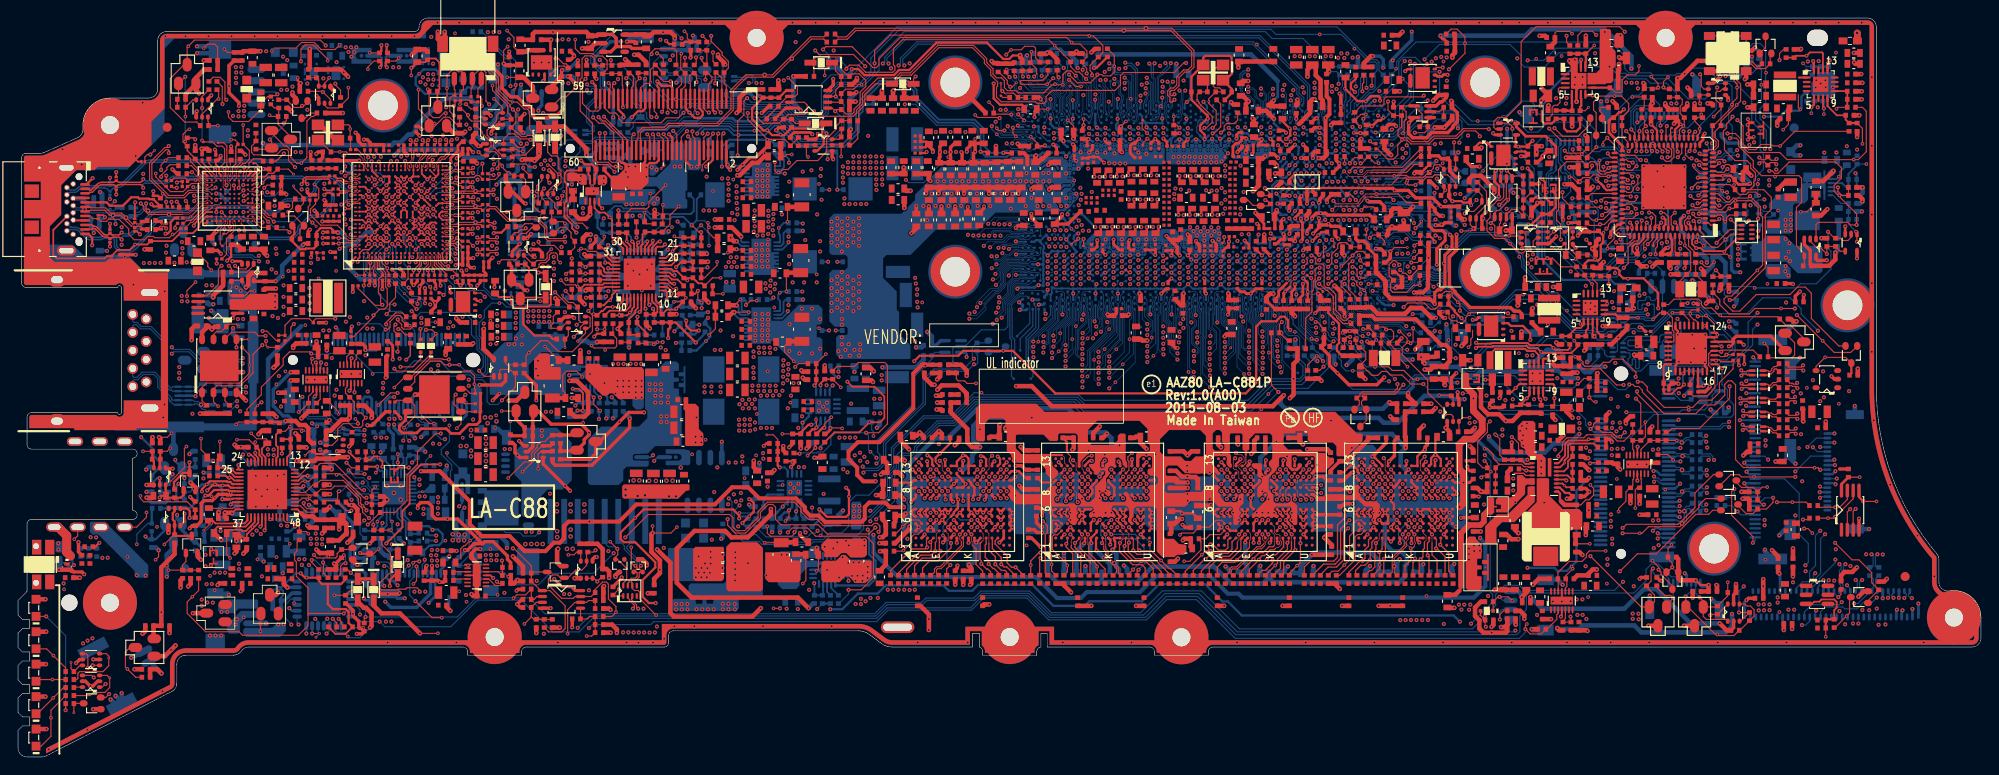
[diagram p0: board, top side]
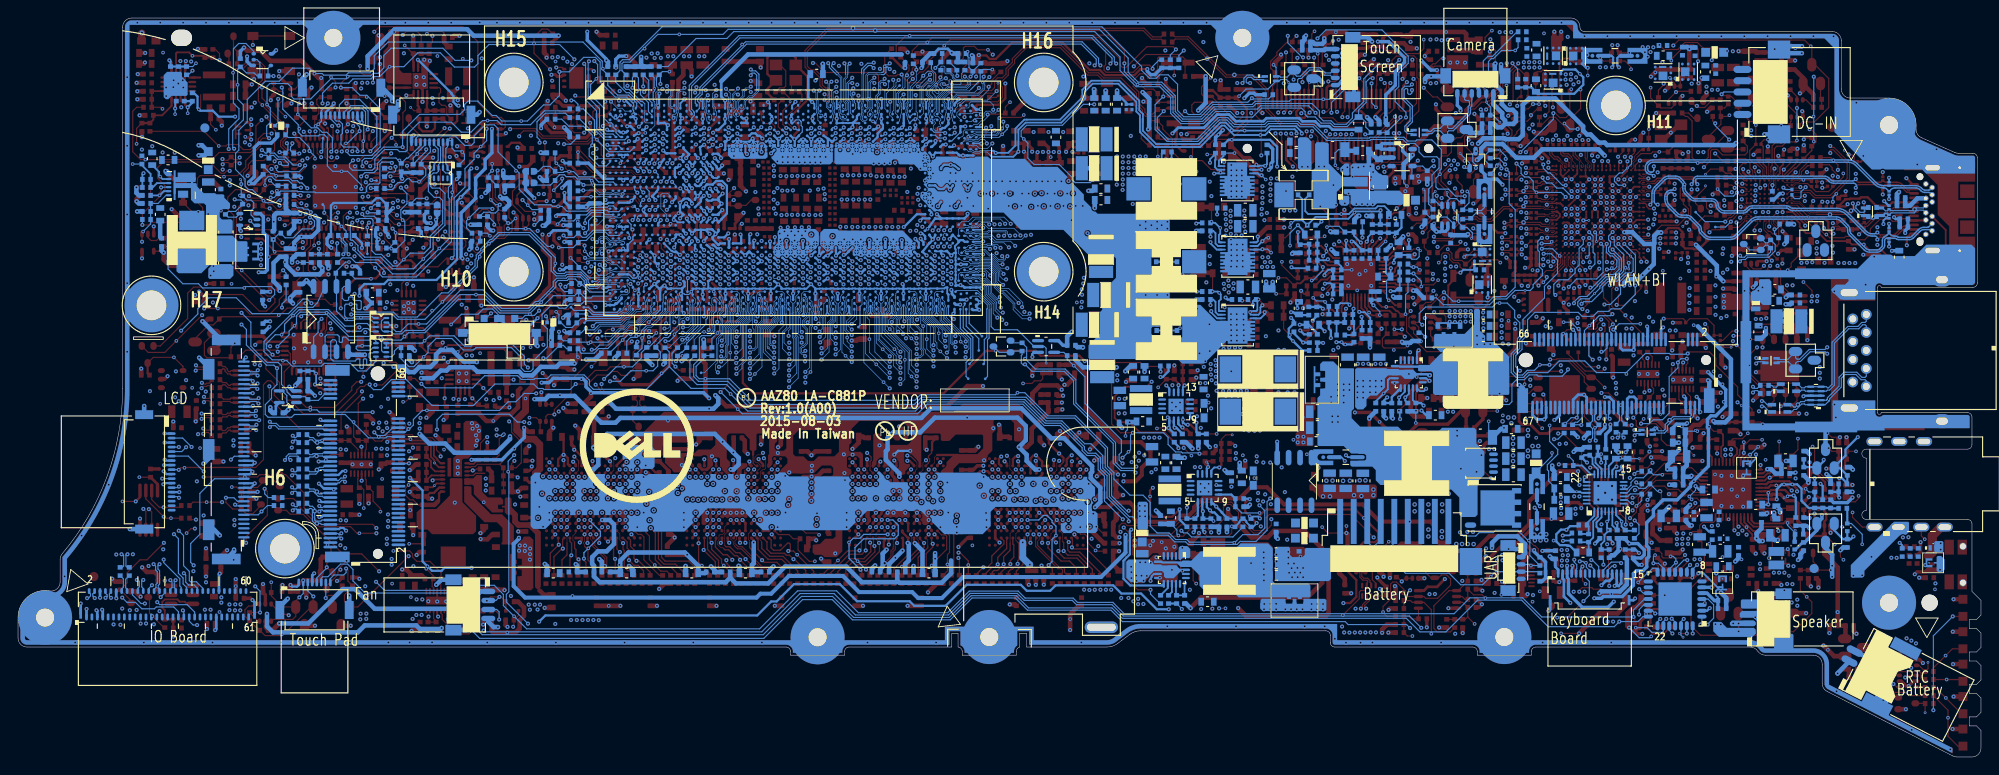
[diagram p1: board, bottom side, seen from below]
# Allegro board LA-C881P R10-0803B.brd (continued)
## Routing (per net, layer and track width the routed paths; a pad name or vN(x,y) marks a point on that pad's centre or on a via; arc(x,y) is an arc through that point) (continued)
CPU_DP2_CTRL_CLK: length 264.8
  TOP w0.076: 150.3,65.13 150.28,65.13 150.26,65.11 149.7,65.11 149.21,64.62 148.72,64.62 v2(148.37,64.97)
  TOP w0.127: UT1.Y8 46.4,58.57 v2(46.08,58.89) ; RC176.1 155.37,66.63 153.88,65.13 150.3,65.13
  IN1 w0.081: v2(36.82,48.8) 37.49,48.8 39.54,50.85 41.25,50.85 43.42,53.02 46.15,53.02 47.02,53.88 47.02,55.61 47.42,56.02 47.42,58.4 46.97,58.86 46.1,58.86 v2(46.08,58.89)
  IN2 w0.089: v2(36.82,48.8) 36.82,48.1 36.61,47.9 36.61,44.5 36.37,44.25 36.37,41.68 35.95,41.27 35.95,34.91 36.21,34.64 36.21,33.48 35.9,33.17 35.9,32.62 36.14,32.38 36.14,30.16 35.48,29.5 35.48,27.41 35.24,27.17 35.24,22.17 34.68,21.61 34.68,20.91 37.59,17.99 38.63,17.99 38.99,17.64 41.06,17.64 42.45,16.25 45.63,16.25 46.46,17.07 48.81,17.07 49.18,16.7 50.74,16.7 51.18,17.14 54.62,17.14 55.22,16.54 55.75,16.54 56.35,17.14 59.39,17.14 59.77,16.76 63.44,16.76 64.15,17.47 67.4,17.47 68.95,19.02 70.66,19.02 75.23,23.59 78.75,23.59 79.03,23.87 85.74,23.87 85.86,23.75 88.05,23.75 88.36,24.05 89.47,24.05 90.11,24.68 92.37,24.68 92.81,24.24 92.81,22.96 93.52,22.25 94.7,22.25 95.29,21.66 97.57,21.66 103.02,16.21 106.45,16.21 107.58,17.34 115.11,17.34 115.92,16.53 116.65,16.53 118.11,15.07 125.39,15.07 127.5,17.18 130.65,17.18 132.76,15.07 151.21,15.07 152.33,16.19 157.54,16.19 159.38,18.03 162.4,18.03 165.25,20.89 165.25,32.23 168.06,35.04 168.06,37.59 166.27,39.38 166.27,40.23 165.68,40.81 165.68,46.43 165.3,46.81 165.3,48.57 164.88,48.99 164.88,49.91 165.78,50.81 165.78,55.07 163.96,56.89 159.94,56.89 159.28,56.23 158.35,56.23 157.82,56.76 157.04,56.76 156.78,57.02 156.78,57.96 154.89,59.85 154.31,59.85 153,61.16 152.41,61.16 151.35,62.22 151.35,64.03 150.82,64.55 148.79,64.55 v2(148.37,64.97)
  BOTTOM w0.127: UCPU1.N7 148.74,65.33 v2(148.37,64.97)
CPU_DP2_CTRL_DATA: length 255.7
  TOP w0.127: RC177.1 153.6,65.45 148.15,65.45 147.74,65.04 v2(147.74,64.97) ; UT1.N4 43.14,56.62 42.82,56.93 v2(42.82,58.23)
  IN2 w0.089: v2(147.74,64.97) 148.37,64.33 149.96,64.33 150.22,64.08 150.22,63.04 152.32,60.94 152.86,60.94 153.26,60.54 153.26,59.16 154.81,57.62 155.88,57.62 156.95,56.54 157.72,56.54 159.45,54.82 159.45,52.97 165.08,47.34 165.08,46.72 165.45,46.36 165.45,38.95 166.21,38.2 166.21,33.49 165.04,32.32 165.04,20.98 162.31,18.25 159.26,18.25 157.42,16.4 152.24,16.4 151.12,15.29 132.85,15.29 130.74,17.4 127.41,17.4 125.3,15.29 118.2,15.29 116.74,16.74 116.01,16.74 115.2,17.55 107.67,17.55 107.49,17.55 106.36,16.43 103.11,16.43 97.66,21.88 96.32,21.88 95.38,21.88 94.79,22.46 93.61,22.46 93.03,23.05 93.03,24.33 92.46,24.9 90.02,24.9 89.38,24.27 88.27,24.27 87.96,23.96 85.95,23.96 85.83,24.09 79.54,24.09 78.99,24.63 75.97,24.63 70.57,19.24 68.86,19.24 67.31,17.69 64.06,17.69 63.35,16.98 59.86,16.98 59.48,17.35 51.09,17.35 50.65,16.92 49.27,16.92 48.9,17.29 46.37,17.29 45.54,16.46 42.54,16.46 41.15,17.85 39.08,17.85 38.72,18.21 37.68,18.21 35.5,20.39 35.5,24.21 36.36,25.08 36.36,25.3 35.7,25.96 35.7,29.41 36.36,30.07 36.36,31.4 37.45,32.49 37.45,34.3 37.08,34.67 37.08,35.12 36.16,36.04 36.16,41.18 36.58,41.6 36.58,43.22 37.47,44.11 37.47,48.67 40.01,51.21 40.01,53.73 40.5,54.22 40.5,55.04 41.12,55.65 42.3,55.65 42.82,56.18 v2(42.82,58.23)
  BOTTOM w0.127: UCPU1.N8 148.09,65.32 v2(147.74,64.97) ; v1(42.67,57.2) 42.67,58.07 v2(42.82,58.23)
CPU_DP2_HPD: length 258.8
  TOP w0.127: v2(148.98,65.88) 149.11,65.88 RC242.2 150.55,65.9 v3(150.97,65.9) ; UT1.Y6 46.4,57.93 v2(46.08,58.25)
  IN1 w0.081: v2(38.4,50.59) 38.86,51.05 41.17,51.05 43.38,53.27 46.11,53.27 46.81,53.97 46.81,55.7 47.21,56.1 47.21,57.86 46.82,58.25 v2(46.08,58.25)
  IN2 w0.089: v2(148.98,65.88) 150.1,65.88 151.79,64.2 151.79,63.29 154.49,60.59 156.98,60.59 158.37,59.2 158.37,57.86 158.69,57.54 164.23,57.54 166.42,55.34 166.42,50.96 167.04,50.34 167.04,48.69 168.44,47.3 168.44,43.74 167.01,42.31 167.01,40.6 166.95,40.54 166.95,39.61 168.71,37.86 168.71,34.77 166.97,33.04 166.97,31.98 167.19,32.2 167.52,32.2 167.75,31.96 167.75,31.63 167.52,31.4 167.19,31.4 166.97,31.61 166.97,19.78 164.54,17.35 163.78,17.35 163.64,17.21 162.5,17.21 161.15,15.87 158.56,15.87 157.12,14.42 132.38,14.42 130.93,15.87 130.36,16.44 127.78,16.44 125.76,14.42 117.24,14.42 116.48,15.19 115.83,15.83 112.07,15.83 111.64,16.27 111.46,16.44 108.71,16.44 107.8,15.53 101.44,15.53 100.05,16.93 95.35,16.93 94.98,16.56 91.45,16.56 91.22,16.79 89.95,16.79 89.18,16.02 83.49,16.02 81.61,17.9 70.83,17.9 69.96,17.04 64.33,17.04 63.4,16.11 55.04,16.11 54.44,16.71 51.36,16.71 50.92,16.27 49,16.27 48.66,16.61 46.75,16.61 45.95,15.82 42.27,15.82 42.23,15.86 40.21,15.86 39.09,16.98 38,16.98 34.25,20.73 34.25,21.79 34.8,22.35 34.8,27.35 35.05,27.59 35.05,29.68 35.71,30.34 35.71,32.2 35.47,32.44 35.47,33.35 35.78,33.66 35.78,34.47 35.51,34.74 35.51,38.72 34.73,39.5 34.73,40.71 35.3,41.28 35.3,43.79 35.91,44.41 35.91,48.79 37.71,50.59 v2(38.4,50.59)
  BOTTOM w0.127: UCPU1.L7 148.74,66.13 v2(148.98,65.88)
CPU_POPIRCOMP: length 3.3
  TOP w0.254: v2(142.6,53.1) 143.1,52.6 v3(143.1,51.62) RC88.1
  BOTTOM w0.305: UCPU1.AT16 v2(142.6,53.1)
CPU_XDP_PRDY#: length 48.8
  TOP w0.127: v2(77.98,71.51) 77.6,71.89 JXDP1.5
  IN3 w0.089: v2(118.2,73.45) 118.17,73.41 113.18,73.41 112.52,72.75 110.56,72.75 110.42,72.62 108.68,72.62 106.45,70.38 100.51,70.38 99.6,71.29 91.58,71.29 91.09,70.8 89.68,70.8 89.05,70.18 86.4,70.18 85.29,69.07 83.64,69.07 82.58,70.13 79.41,70.13 78.02,71.51 v2(77.98,71.51)
  BOTTOM w0.076: UCPU1.D61 117.73,70.55 118.03,70.85 118.03,71.18 118.01,71.21 118.01,71.48 118.16,71.64 118.16,73.41 v2(118.2,73.45)
CPU_XDP_PREQ#: length 54.4
  TOP w0.127: JXDP1.3 78.1,75.3 RC138.2 77.36,75.87 v2(77.36,74.76)
  IN3 w0.089: v2(77.36,74.76) 78.19,74.76 80.25,72.69 82.37,72.69 82.97,73.3 90.16,73.3 90.61,73.74 92.05,73.74 92.72,74.42 94.47,74.42 95.67,73.21 100.45,73.21 102.24,71.42 106.51,71.42 108.35,73.27 110.16,73.27 110.29,73.4 111.64,73.4 112.52,74.28 118.79,74.28 v2(119.55,73.52)
  BOTTOM w0.076: v2(119.55,73.52) 119.93,73.15 119.93,72.69 119.78,72.54 119.78,72.17 119.81,72.1 119.81,71.89 119.8,71.86 119.8,71.83 119.79,71.82 119.78,71.8 119.78,71.55 119.79,71.5 119.88,71.18 119.92,71.07 119.92,70.96 119.99,70.69 119.99,70.58 UCPU1.D56
CPVEE: length 3.1
  TOP w0.203: UA2.34 23.85,28.28 v2(23.6,28.03)
  BOTTOM w0.127: v2(23.6,28.03) v3(23.6,29.32)
  BOTTOM w0.254: C1205.1 23.62,28 v2(23.6,28.03)
CSI2_COMP: length 1.6
  TOP w0.381: v2(144.43,69.84) 143.86,69.84 RC3.1
  BOTTOM w0.254: UCPU1.E13 144.64,69.84 v2(144.43,69.84)
CSSN_1: length 7.2
  IN3 w0.203: v2(48.95,27.82) 49.05,27.72 49.05,27.47 46.84,25.25 46.84,24.6 46.71,24.47 46.51,24.47 v2(46.41,24.57)
  BOTTOM w0.203: v2(46.41,24.57) 46.38,24.6 45.64,24.6 PR304.1 ; PR300.2 49.27,28.15 v2(48.95,27.82)
CSSP_1: length 7.5
  IN3 w0.203: v2(49.53,27.67) 49.38,27.52 49.38,27.33 47.17,25.11 47.17,24.46 46.82,24.11 46.51,24.11 v2(46.38,23.99)
  BOTTOM w0.203: v2(49.53,27.67) 49.27,27.41 PR300.3 ; PR303.1 45.44,24.01 46.36,24.01 v2(46.38,23.99)
CV2_ON: length 5.9
  TOP w0.127: UE5.A9 188.06,63.52 189.95,63.52 R251.2 190.53,62.88 190.98,62.42 191.74,62.42 192,62.68 192.81,62.68 v3(193.19,62.3)
DAT_SMB: length 11.7
  TOP w0.127: 68.31,20.53 PD101.2 ; 68.31,20.53 68.31,20.53 68.71,20.93 68.71,21.01 v2(68.5,21.22) 68.38,21.22 68.05,21.55 v3(68.05,23.28) ; 68.31,20.53 68.63,20.53 68.7,20.46 68.7,20.05 68.49,19.84 68.06,19.84 67.8,19.58 67.8,19.4 67.66,19.26 PRP100.7
  BOTTOM w0.127: v2(68.5,21.22) 68.71,21.42 68.71,21.62 67.28,23.04 67.28,23.43 66.6,24.11 JBATT1.4
DAT_TP_SIO: length 89.7
  TOP w0.127: C1226.1 181.84,18.8 182.72,17.93 183.38,17.93 v2(183.67,17.64) 182.93,16.9 MD9.2 ; RE7.2 174.12,64.83 174.6,65.31 174.6,65.56 v2(174.65,65.61) ; v2(179.12,64.41) 178.75,64.77 178.01,64.77 UE5.B40
  IN2 w0.089: v2(174.65,65.61) 174.97,65.61 175.74,66.38 176.97,66.38 177.15,66.2 177.15,65.67 178.38,64.45 178.99,64.45 179.12,64.32 v2(179.12,64.41)
  IN3 w0.089: v2(183.67,17.64) 184.28,18.24 190.27,18.24 191.03,19.01 191.03,19.65 193.1,21.71 194.83,21.71 196.7,23.58 199.87,23.58 200.41,23.05 v2(201.7,23.05)
  IN4 w0.089: v2(179.12,64.41) 179.17,64.41 179.69,63.88 180.98,63.88 183.13,61.73 183.13,59.42 184.2,58.36 186.48,58.36 188.01,56.82 188.01,54.53 187.83,54.35 187.83,53.82 188.64,53.01 189.02,53.01 190.8,51.23 190.8,49.11 193.99,45.91 193.99,35.88 196.01,33.86 196.01,26.17 198.22,23.96 200.79,23.96 v2(201.7,23.05)
  BOTTOM w0.127: v2(183.67,17.64) 183.66,17.64 JTP1.7
DBC_I2C_EN: length 193.5
  TOP w0.127: v2(204.75,28.36) v3(206.22,28.36)
  TOP w0.254: v2(204.75,28.36) 204.28,28.84 U48.5
  IN1 w0.254: v2(58.34,13.67) 58.47,13.8 63.93,13.8 64.88,14.75 70.49,14.75 71.15,15.41 94.16,15.41 94.96,16.21 100.59,16.21 101.95,14.86 115.23,14.86 116.23,13.86 126.44,13.86 127.91,15.33 130.82,15.33 132.93,13.22 175,13.22 175.58,13.8 192.86,13.8 197.87,18.8 197.87,20.02 197.45,20.44 197.45,21.97 198.81,23.33 200.08,23.33 201.32,24.57 201.67,24.57 204.75,27.66 v2(204.75,28.36)
  IN2 w0.254: v2(30.1,16.52) 30.76,16.52 33.02,14.26 38.18,14.26 38.94,13.5 42.93,13.5 43.66,14.22 51.11,14.22 51.82,14.94 53.89,14.94 54.3,14.53 57.49,14.53 v2(58.34,13.67)
  BOTTOM w0.254: v2(30.1,16.52) 30.39,16.23 30.96,16.23 UE4.2
DCIN_ACOK: length 321.5
  TOP w0.127: v2(51.35,76.97) 51.35,76.92 53.05,75.21 53.05,73.92 54.59,72.39 54.59,72.17 v2(54.91,71.85) 55.25,71.51 55.25,70.39 PR250.1 55.28,69.29 55.4,69.29 55.86,68.84 56.36,68.84 56.49,68.97 57.1,68.97 57.3,68.77 57.3,68.24 57.29,68.23 57.29,67.82 56.25,66.79 55.04,66.79 PR249.1 ; v2(23.1,72.93) 22.96,73.07 22.96,74.89 22.42,75.43 21.65,75.43 PR217.1 ; v2(64.08,22.95) 63.88,22.74 PR255.2 63.09,22.61 PQ219.5 63.09,21.27 62.56,20.74 61.87,20.74 61.02,19.88 PQ220.2 60.19,19.88 59.87,20.2 59.29,20.2 58.85,19.76 58.85,19.07 60.31,17.61 61.63,17.61 61.82,17.81 PU203.7 63.6,17.81 PC215.1 64.03,18.6 64.85,19.41 65.28,19.41 65.51,19.19 65.51,17.54 66.35,16.7 v3(66.35,16.09) 66.35,16.04 65.89,15.58 PR262.2
  IN2 w0.089: v2(23.1,72.93) 24.15,73.98 27.47,73.98 28.53,72.92 31.33,72.92 33.12,74.71 33.12,75.7 33.56,76.14 34.2,76.14 34.6,75.73 35.95,75.73 36.36,76.14 38.58,76.14 39.67,77.23 42.11,77.23 43.42,78.54 49.86,78.54 51.35,77.06 v2(51.35,76.97) ; v2(64.08,22.95) 64.08,22.94 61.64,20.49 51.78,20.49 51.25,19.96 42.18,19.96 42.11,19.9 38.84,19.9 38.37,20.37 37.91,20.37 37.02,21.26 37.02,21.73 36.88,21.87 36.88,23.06 37.22,23.4 37.22,25.66 36.56,26.32 36.56,29.05 37.22,29.71 37.22,31.04 38.32,32.13 38.32,34.66 37.95,35.03 37.95,36.64 38.18,36.86 38.18,37.14 37.8,37.52 37.8,39.4 38.18,39.78 38.18,40.78 38.91,41.52 38.91,44.21 v2(38.55,44.57)
  IN3 w0.089: v2(54.91,71.85) 54.91,71.91 55.64,72.64 59.55,72.64 60.32,71.87 64.8,71.87 65.55,72.62 77.97,72.62 79.69,70.9 89.16,70.9 89.5,71.23 90.91,71.23 91.41,71.73 99.77,71.73 100.69,70.82 106.27,70.82 108.5,73.05 110.24,73.05 110.38,73.19 111.72,73.19 112.61,74.07 118.7,74.07 119.08,73.69 119.08,72.74 119.3,72.52 119.73,72.52 120.94,73.73 123,73.73 123.29,74.02 123.29,74.96 124.32,75.99 129.19,75.99 129.74,75.44 129.74,74.6 130.47,73.87 135.03,73.87 135.95,74.79 135.95,76.46 136.18,76.69 138.64,76.69 138.66,76.71 145.37,76.71 145.72,76.35 151.48,76.35 152.83,75.01 153.38,75.01 153.86,75.01 154.08,74.79 158.12,74.79 161.36,71.55 165.24,71.55 166.2,72.51 167.66,72.51 168.55,73.39 169.51,73.39 170.88,72.03 173,72.03 173.98,73.01 173.98,73.52 174.52,74.06 176.82,74.06 177.17,73.71 179.93,73.71 181.13,74.92 183.78,74.92 185.68,73.02 v2(188.95,73.02)
  IN4 w0.081: v2(54.91,71.85) 54.26,71.21 54.26,66.96 54.86,66.37 54.86,60.23 54.23,59.61 54.23,55.16 51.85,52.77 50.06,52.77 49.75,52.46 49.75,51.58 46.16,47.99 46.16,47.28 45.6,46.72 40.7,46.72 v2(38.55,44.57)
  BOTTOM w0.127: v2(188.95,73.02) 188.97,73 188.97,70.39 DE11.1
DCIN_ACOK#: length 184.8
  TOP w0.127: v2(60.39,62.28) 60.33,62.21 60.33,61.82 60.07,61.57 PR284.1 ; v2(22.7,72.45) 22.7,72.49 22.66,72.53 22.66,74.38 PR220.1 ; v2(49.71,72.45) 50.24,71.92 PR251.1 ; PQ219.2 PQ219.3 63.91,19.84 v2(64.27,19.48) 64.74,19.95 PR256.2
  IN2 w0.089: v2(22.7,72.45) 23.19,72.45 24.51,73.76 27.38,73.76 28.44,72.7 31.42,72.7 33.34,74.62 33.34,75.61 33.65,75.92 34.11,75.92 34.51,75.51 36.04,75.51 36.44,75.92 38.67,75.92 39.69,76.94 42.12,76.94 43.51,78.33 46.32,78.33 49.71,74.94 v2(49.71,72.45) 50.15,72.45 58.06,80.36 62.6,80.36 63.3,79.66 v2(63.3,79.36) ; v2(64.27,19.48) 64.27,18.81 63.08,17.62 60.13,17.62 59.71,18.04 54.97,18.04 54.36,18.66 53.73,18.66 53.48,18.4 51.22,18.4 50.38,17.57 49.54,17.57 49.17,17.94 43.86,17.94 43.08,17.15 42.77,17.15 41.42,18.5 39.93,18.5 38.28,20.15 37.82,20.15 36.81,21.17 36.81,21.64 36.15,22.3 36.15,23.95 37.01,24.81 37.01,25.57 36.35,26.23 36.35,29.14 37.01,29.8 37.01,31.13 38.1,32.22 38.1,34.57 37.73,34.94 37.73,35.39 37.01,36.11 37.01,36.97 37.4,37.36 37.4,39.31 37.96,39.87 37.96,40.87 38.7,41.61 38.7,42.8 38.12,43.38 38.12,48.13 v2(38.75,48.76)
  IN4 w0.081: v2(63.3,79.36) 63.86,78.8 63.86,76.93 62.47,75.54 62.47,74.73 62.64,74.55 62.64,66.96 62,66.33 62,65.16 60.9,64.05 60.9,62.8 60.39,62.29 v2(60.39,62.28) ; v2(38.75,48.76) 40.58,46.93 45.51,46.93 45.95,47.37 45.95,48.08 49.54,51.67 49.54,52.54 49.97,52.98 51.76,52.98 53.99,55.21 53.99,59.81 53.81,59.99 53.81,60.82 54.4,61.41 54.4,66.23 53.67,66.96 53.67,69.51 53.27,69.91 53.27,72.86 52.76,73.38 50.64,73.38 v2(49.71,72.45)
  BOTTOM w0.127: v2(49.71,72.45) v3(49.04,72.45)
DDI1_PTX_TBRX_N0: length 83.1
  TOP w0.127: CT18.2 50.11,58.45 50.26,58.45 v2(50.44,58.63)
  IN2 w0.102: v2(120.65,69.81) 120.52,69.81 120.42,69.91 120.42,70.07 119.69,70.8 117.95,70.8 117.38,70.23 116.6,70.23 116.37,70.46 114.77,70.46 114.69,70.39 114.39,70.39 114.27,70.51 113.6,70.51 113.16,70.08 113.16,69.7 110.98,67.52 109.83,67.52 109.67,67.67 108.96,67.67 108,66.71 100.37,66.71 98.89,68.19 96.53,70.54 87.3,70.54 86.94,70.19 80.23,70.19 78.2,72.22 71.12,72.22 70.97,72.07 69.93,72.07 68.35,70.49 67.5,70.49 60.85,63.84 59.68,63.84 56.08,60.23 54.7,60.23 54.47,60 52.64,60 52.15,59.51 52.15,59.03 51.41,58.28 50.79,58.28 v2(50.44,58.63)
  BOTTOM w0.127: UCPU1.E55 121.07,69.55 120.91,69.55 v2(120.65,69.81)
DDI1_PTX_TBRX_N0_C: length 2.7
  TOP w0.076: 48.67,58.46 48.63,58.46 48.32,58.15 48.03,58.15 47.73,58.45 47.42,58.45 47.35,58.38 47.35,58.3 47.43,58.22 UT1.AC7
  TOP w0.127: 48.67,58.46 48.82,58.46 49,58.63 CT18.1
DDI1_PTX_TBRX_N1: length 78
  TOP w0.127: v2(52.88,59.3) 52.77,59.18 52.67,59.18 52.56,59.29 52.26,59.29 52.13,59.41 CT20.2
  IN2 w0.102: v2(118.84,69.79) 118.53,69.48 118.14,69.48 118.03,69.37 116.09,69.37 115.37,68.66 115.37,67.76 115.03,67.42 111.88,67.42 110.47,66 100.06,66 96.51,69.55 93.53,69.55 93.18,69.19 91.01,69.19 90.38,69.83 87.61,69.83 86.93,69.14 82.62,69.14 82.49,69.27 80.13,69.27 78.5,70.9 72.26,70.9 71.6,70.24 69.11,70.24 68.66,69.78 67.79,69.78 63.02,65.01 63.02,63.84 62.31,63.13 59.97,63.13 56.21,59.37 55.13,59.37 54.98,59.22 52.96,59.22 v2(52.88,59.3)
  BOTTOM w0.127: UCPU1.E58 119.04,69.59 v2(118.84,69.79)
DDI1_PTX_TBRX_N1_C: length 4.7
  TOP w0.076: UT1.AC9 47.47,59.22 47.47,59.32 47.52,59.37 47.78,59.37 47.88,59.27 47.88,59.15 47.97,59.06 48.28,59.06 48.34,59.12 48.36,59.12
  TOP w0.127: CT20.1 51.35,59.33 v4(50.76,59.33) 48.9,59.33 48.69,59.12 48.36,59.12
DDI1_PTX_TBRX_N2: length 85.4
  TOP w0.127: CT22.2 49.93,60.41 50.11,60.22 50.28,60.22 v2(50.44,60.38)
  IN2 w0.102: v2(50.44,60.38) 50.74,60.09 51.2,60.09 51.86,60.74 53.55,60.74 57.38,64.58 60.47,64.58 61.83,65.94 61.83,66.49 63.58,68.24 63.58,69.42 64.53,70.37 66.08,70.37 66.48,70.76 66.48,71.22 66.89,71.64 68.04,71.64 69.17,72.77 70.63,72.77 70.79,72.94 78.49,72.94 79.34,72.09 80.02,72.09 80.54,71.57 80.54,71.21 80.83,70.92 86.67,70.92 87.01,71.26 96.84,71.26 100.09,68 107.22,68 107.98,68.76 110.28,68.76 112.14,70.62 112.14,71.33 112.59,71.78 115.12,71.78 115.4,71.5 120.01,71.5 121.36,70.15 121.36,69.71 121.44,69.63 121.67,69.63 121.77,69.53 121.77,69.38 v2(121.57,69.18)
  BOTTOM w0.127: UCPU1.F53 121.81,68.94 v2(121.57,69.18)
DDI1_PTX_TBRX_N2_C: length 2.5
  TOP w0.076: 48.41,60.23 48.4,60.23 48.37,60.2 47.93,60.2 47.84,60.29 47.4,60.29 47.35,60.23 47.35,60.13 47.42,60.06 UT1.AC11
  TOP w0.127: 48.41,60.23 48.42,60.24 49.24,60.24 49.34,60.34 CT22.1
DDI1_PTX_TBRX_N3: length 82.2
  TOP w0.127: v2(60.71,57.74) 60.49,57.53 58.9,57.53 58.67,57.76 58.67,58.82 57.56,59.94 55.93,59.94 55.67,59.68 54.42,59.68 53.03,61.08 52.35,61.08 CT24.2
  IN2 w0.102: v2(60.71,57.74) 60.84,57.61 61.09,57.61 61.32,57.84 61.32,61.13 63.78,63.59 63.78,64.21 67.88,68.31 72.13,68.31 74,70.18 78.2,70.18 79.82,68.56 82.1,68.56 82.24,68.43 96.61,68.43 99.76,65.29 110.76,65.29 111.39,65.92 112.76,65.92 113.19,66.35 114.75,66.35 114.88,66.22 115.18,66.22 115.65,66.69 115.65,66.93 116.27,67.55 117.24,67.55 117.82,68.13 119.01,68.13 119.33,68.45 119.33,68.72 119.74,69.13 119.74,69.13 v2(119.74,69.13)
  BOTTOM w0.127: v2(119.74,69.13) 119.74,69.13 119.74,69.12 119.93,68.94 UCPU1.F56
DDI1_PTX_TBRX_N3_C: length 4.5
  TOP w0.076: 48.87,61.12 48.81,61.06 48.5,61.06 48.35,60.91 48.04,60.91 47.78,61.17 47.57,61.17 47.52,61.12 47.52,61.01 UT1.AC13
  TOP w0.127: CT24.1 51.37,61.12 v4(50.76,61.12) 48.87,61.12
DDI1_PTX_TBRX_P0: length 83.2
  TOP w0.127: v2(50.44,58.05) 50.3,58.2 50.12,58.2 CT17.2
  IN2 w0.102: v2(120.63,69.18) 120.19,69.61 120.19,69.97 119.59,70.58 118.04,70.58 117.48,70.01 116.51,70.01 116.28,70.24 114.86,70.24 114.78,70.16 114.3,70.16 114.17,70.29 113.69,70.29 113.39,69.99 113.39,69.6 111.07,67.29 109.73,67.29 109.58,67.45 109.05,67.45 108.09,66.49 100.27,66.49 98.73,68.03 96.44,70.32 87.39,70.32 87.03,69.96 80.14,69.96 78.11,71.99 71.21,71.99 71.06,71.85 70.02,71.85 68.44,70.27 67.59,70.27 60.94,63.62 59.78,63.62 56.17,60.01 54.79,60.01 54.56,59.78 52.73,59.78 52.38,59.42 52.38,58.94 51.5,58.06 50.46,58.06 v2(50.44,58.05)
  BOTTOM w0.127: v2(120.63,69.18) 120.87,69.18 UCPU1.F55
DDI1_PTX_TBRX_P0_C: length 2.5
  TOP w0.076: UT1.AB7 47.26,58.06 47.33,58.06 47.41,57.98 48.39,57.98 48.61,58.2 48.67,58.2
  TOP w0.127: 48.67,58.2 48.94,58.2 49.15,58 CT17.1
DDI1_PTX_TBRX_P1: length 78
  TOP w0.127: CT19.2 52.29,59.04 52.46,59.04 52.57,58.93 52.67,58.93 v2(52.88,58.71)
  IN2 w0.102: v2(118.84,69.14) 118.72,69.26 118.23,69.26 118.12,69.15 116.18,69.15 115.6,68.56 115.6,67.66 115.13,67.19 111.98,67.19 110.56,65.77 99.97,65.77 96.42,69.33 93.62,69.33 93.27,68.97 90.92,68.97 90.29,69.6 87.71,69.6 87.02,68.92 82.53,68.92 82.4,69.05 80.04,69.05 78.41,70.67 72.35,70.67 71.7,70.02 69.21,70.02 68.75,69.56 67.89,69.56 63.24,64.91 63.24,63.75 62.4,62.9 60.06,62.9 56.3,59.15 55.22,59.15 55.08,59 53.17,59 v2(52.88,58.71)
  BOTTOM w0.127: UCPU1.F58 119.04,68.94 v2(118.84,69.14)
DDI1_PTX_TBRX_P1_C: length 4.7
  TOP w0.076: 48.36,58.87 48.35,58.87 48.32,58.9 47.9,58.9 47.88,58.92 47.32,58.92 UT1.AB9
  TOP w0.127: 48.36,58.87 48.8,58.87 49,59.07 51.36,59.07 CT19.1
DDI1_PTX_TBRX_P2: length 85.4
  TOP w0.127: CT21.2 50.12,59.97 50.27,59.97 v2(50.44,59.8)
  IN2 w0.102: v2(50.44,59.8) 50.51,59.87 51.3,59.87 51.95,60.52 53.64,60.52 57.47,64.35 60.56,64.35 62.05,65.85 62.05,66.39 63.81,68.15 63.81,69.33 64.62,70.14 66.17,70.14 66.7,70.67 66.7,71.13 66.99,71.41 68.13,71.41 69.27,72.55 70.73,72.55 70.89,72.71 78.4,72.71 79.25,71.87 79.92,71.87 80.32,71.47 80.32,71.12 80.74,70.7 86.77,70.7 87.1,71.03 96.74,71.03 100,67.78 107.32,67.78 108.08,68.54 110.37,68.54 112.37,70.53 112.37,71.24 112.68,71.56 115.03,71.56 115.3,71.28 119.91,71.28 121.13,70.06 121.13,68.98 v2(121.57,68.54)
  BOTTOM w0.127: UCPU1.G53 121.77,68.54 v2(121.57,68.54)
DDI1_PTX_TBRX_P2_C: length 2.5
  TOP w0.076: 48.42,59.99 48.41,59.99 48.36,60.03 48.01,60.03 47.8,59.83 47.35,59.83 47.11,60.06 UT1.AB11
  TOP w0.127: 48.42,59.99 49.13,59.99 CT21.1
DDI1_PTX_TBRX_P3: length 82
  TOP w0.127: CT23.2 52.3,60.83 52.92,60.83 54.32,59.43 55.78,59.43 56.03,59.69 57.45,59.69 58.42,58.72 58.42,57.65 58.8,57.28 60.59,57.28 v2(60.71,57.16)
  IN2 w0.102: v2(60.71,57.16) 60.93,57.39 61.19,57.39 61.54,57.74 61.54,61.03 64,63.49 64,64.11 67.98,68.09 72.22,68.09 74.09,69.96 78.11,69.96 79.73,68.34 82.01,68.34 82.14,68.21 96.52,68.21 99.67,65.06 110.85,65.06 111.48,65.69 112.85,65.69 113.28,66.13 114.66,66.13 114.78,66 115.28,66 115.88,66.6 115.88,66.84 116.36,67.32 117.33,67.32 117.91,67.91 119.11,67.91 119.36,68.16 119.56,68.16 119.74,68.34 v2(119.74,68.54)
  BOTTOM w0.127: v2(119.74,68.54) 119.9,68.54 120.15,68.29 UCPU1.G56
DDI1_PTX_TBRX_P3_C: length 4.7
  TOP w0.076: UT1.AB13 47.34,60.74 48.42,60.74 48.57,60.89 48.84,60.89 48.86,60.86 48.87,60.86
  TOP w0.127: CT23.1 51.35,60.86 48.87,60.86
DDI2_PTX_TBRX_N0: length 96.3
  TOP w0.127: CT30.2 50.14,61.97 50.35,61.97 v2(50.52,62.14)
  IN2 w0.102: v2(50.52,62.14) 50.52,62.38 50.45,62.45 50.17,62.45 50.1,62.38 50.1,62.02 49.97,61.89 49.79,61.89 49.65,62.03 49.65,63.33 49.91,63.59 49.91,65.64 50.67,66.4 51.29,66.4 51.74,66.86 51.74,67.14 52.99,68.39 53.99,68.39 55.28,69.68 55.5,69.68 56.85,71.03 56.85,72.2 60.2,75.55 61.64,75.55 61.88,75.8 64.88,75.8 65.78,76.7 72.66,76.7 72.86,76.9 79.04,76.9 80.11,75.83 84.97,75.83 85.23,76.1 87.45,76.1 88.35,77 91.25,77 92.54,78.29 108.37,78.29 109.44,77.22 114.38,77.22 115.94,78.78 120.85,78.78 122.2,77.43 122.2,76.98 122.49,76.69 122.66,76.69 122.87,76.48 v2(122.87,76.45)
  BOTTOM w0.076: 123.96,75.86 123.96,75.84 124,75.79 124,73.17 123.99,73.1 123.99,73.09 123.98,73.02 123.98,73 123.98,73 123.98,72.78 arc(124,72.62) 124.06,72.48 arc(124.11,72.34) 124.09,72.2 arc(124.05,72.01) 124.07,71.82 124.07,71.49 124.04,71.42 124.04,71.22 124.12,71.07 124.12,70.79 123.98,70.65 123.7,70.65 123.61,70.74 123.61,70.9 123.72,71.01 UCPU1.C50
  BOTTOM w0.127: 123.96,75.86 123.96,76.22 123.44,76.73 123.15,76.73 v2(122.87,76.45)
DDI2_PTX_TBRX_N0_C: length 2.4
  TOP w0.076: UT1.AC15 47.45,62.01 47.45,62.01 47.45,62.09 47.5,62.14 47.73,62.14 48.04,61.82 48.36,61.82 48.39,61.86 48.41,61.86
  TOP w0.127: 48.41,61.86 48.69,61.86 48.81,61.98 49.13,61.98 CT30.1
DDI2_PTX_TBRX_N1: length 84.9
  TOP w0.127: v2(52.77,62.97) 52.57,62.77 52.3,62.77 CT32.2
  IN2 w0.102: v2(121.65,75.26) 121.43,75.04 121.19,75.04 120.74,74.58 114.43,74.58 113.82,73.97 112.17,73.97 110.74,72.55 108.26,72.55 106.22,70.52 99.63,70.52 96.79,73.36 92.76,73.36 92.15,73.97 90.24,73.97 89.42,73.16 83.01,73.16 82.42,73.75 79.74,73.75 79.14,74.35 70.2,74.35 70.08,74.23 68.59,74.23 67.45,73.08 64.67,73.08 63.93,72.34 62.88,72.34 60.53,69.99 60.21,69.99 57.11,66.89 55.54,66.89 54.81,66.16 54.81,64.54 53.07,62.79 52.95,62.79 v2(52.77,62.97)
  BOTTOM w0.076: UCPU1.C52 122.69,71.01 122.76,71.09 122.76,71.28 122.7,71.34 122.53,71.34 122.47,71.39 122.43,71.55 122.42,71.57 122.42,71.75 122.48,71.94 122.48,72.09 122.42,72.21 122.42,72.47 122.57,72.62
  BOTTOM w0.089: v2(121.65,75.26) 121.65,75.16 121.78,75.03 122.1,75.03 122.33,74.81 122.33,73.65 122.63,73.35 122.63,72.9 122.57,72.83 122.57,72.62
DDI2_PTX_TBRX_N1_C: length 4.6
  TOP w0.076: 48.53,62.78 48.52,62.78 48.48,62.74 47.98,62.74 47.87,62.85 47.87,62.93 47.75,63.05 47.52,63.05 47.47,63 47.47,62.9 UT1.AC17
  TOP w0.127: 48.53,62.78 48.54,62.79 v4(50.76,62.79) 51.38,62.79 CT32.1
DDI2_PTX_TBRX_N2: length 90.8
  TOP w0.127: CT34.2 50.11,63.65 50.31,63.65 v2(50.44,63.79)
  IN2 w0.102: v2(121.08,76.97) 120.87,76.76 120.59,76.76 120.24,77.12 115.76,77.12 113.55,74.91 110.91,74.91 110.52,74.52 110.52,73.89 109.86,73.23 107.56,73.23 105.51,71.18 102.27,71.18 98.67,74.79 90.06,74.79 89.09,73.82 83.26,73.82 82.7,74.38 80.05,74.38 78.57,75.85 73.43,75.85 73.23,75.65 70.56,75.65 69.77,74.86 68.32,74.86 67.17,73.72 64.39,73.72 63.64,72.97 62.61,72.97 60.39,70.75 59.88,70.75 57.31,68.18 57.17,68.18 56.52,67.52 55.28,67.52 54.06,66.3 54.06,64.72 53.48,64.14 51.87,64.14 51.32,63.6 50.64,63.6 v2(50.44,63.79)
  BOTTOM w0.076: 121.97,75.98 121.99,75.98 122.03,75.93 123.45,75.93 123.74,75.65 123.74,72.88 123.54,72.69 123.54,72.14 123.62,72.06 123.72,72.06 123.81,72.15 UCPU1.A50
  BOTTOM w0.127: v2(121.08,76.97) 121.24,76.82 121.54,76.82 121.76,76.6 121.76,76.06 121.84,75.98 121.97,75.98
DDI2_PTX_TBRX_N2_C: length 2.6
  TOP w0.076: 48.39,63.84 48.38,63.84 48.32,63.79 47.93,63.79 47.75,63.97 47.45,63.97 47.37,63.89 47.37,63.79 47.42,63.74 47.56,63.74 UT1.AC19
  TOP w0.127: CT34.1 49.15,63.65 48.94,63.65 48.75,63.84 48.39,63.84
DDI2_PTX_TBRX_N3: length 91.6
  TOP w0.127: CT36.2 50.12,64.93 50.37,64.93 v2(50.5,64.8)
  IN2 w0.102: v2(122.79,74.79) 122.61,74.97 122.36,74.97 122.1,75.23 122.1,75.45 121.52,76.03 121.52,77.14 121.13,77.53 115.59,77.53 114.54,76.49 110.19,76.49 109.37,75.68 109.37,74.86 108.22,73.71 107.41,73.71 105.33,71.64 102.41,71.64 98.27,75.78 92.9,75.78 92.62,75.5 91.28,75.5 91.11,75.67 89.64,75.67 88.21,74.23 83.71,74.23 82.75,75.2 79.83,75.2 78.76,76.26 73.17,76.26 72.97,76.06 66.11,76.06 63.42,73.38 62.4,73.38 60.28,71.26 59.77,71.26 57.71,69.2 56.9,69.2 56.27,68.57 55.17,68.57 54.14,67.53 53.31,67.53 52.31,66.53 52.31,65.71 51.64,65.04 50.73,65.04 v2(50.5,64.8)
  BOTTOM w0.076: UCPU1.D51 123.25,70.88 122.94,71.18 122.94,71.49 123.15,71.7 123.15,71.81 123,71.97 123,72.96 123.24,73.21 123.24,74.81 123.06,74.99 122.91,74.99 122.79,74.87 v2(122.79,74.79)
DDI2_PTX_TBRX_N3_C: length 2.7
  TOP w0.076: 48.5,64.94 48.49,64.94 48.45,64.98 48.36,64.98 48.1,64.72 48.02,64.72 47.73,64.42 47.4,64.42 47.35,64.47 47.35,64.58 47.43,64.66 UT1.AC21
  TOP w0.127: 48.5,64.94 49.13,64.94 CT36.1
DDI2_PTX_TBRX_P0: length 96.3
  TOP w0.127: CT29.2 50.09,61.72 50.36,61.72 v2(50.52,61.55)
  IN2 w0.102: v2(50.52,61.55) 50.41,61.67 49.7,61.67 49.43,61.94 49.43,63.42 49.69,63.68 49.69,65.74 50.58,66.63 51.19,66.63 51.52,66.95 51.52,67.23 52.9,68.61 53.9,68.61 55.19,69.9 55.41,69.9 56.62,71.12 56.62,72.29 60.11,75.78 61.54,75.78 61.79,76.02 64.79,76.02 65.68,76.92 72.57,76.92 72.77,77.12 79.13,77.12 80.2,76.06 84.87,76.06 85.14,76.32 87.35,76.32 88.25,77.22 91.16,77.22 92.45,78.51 108.46,78.51 109.53,77.44 114.29,77.44 115.85,79 120.94,79 122.42,77.52 122.42,77.08 122.59,76.91 122.73,76.91 v2(122.86,77.05)
  BOTTOM w0.076: 124.21,75.86 124.21,75.84 124.17,75.79 124.17,73.16 124.16,73.08 124.16,73.07 124.16,73 124.15,73 124.15,72.78 arc(124.16,72.67) 124.21,72.56 arc(124.27,72.35) 124.24,72.14 arc(124.21,72) 124.23,71.87 124.23,71.84 124.23,71.46 124.21,71.39 124.21,71.26 124.29,71.11 124.29,70.72 124.05,70.48 123.93,70.48 UCPU1.D50
  BOTTOM w0.127: 124.21,75.86 124.21,76.32 123.55,76.98 122.93,76.98 v2(122.86,77.05)
DDI2_PTX_TBRX_P0_C: length 2.5
  TOP w0.076: UT1.AB15 47.28,61.72 47.34,61.66 48.34,61.66 48.4,61.6 48.41,61.6
  TOP w0.127: 48.41,61.6 48.79,61.6 48.91,61.72 49.17,61.72 CT29.1
DDI2_PTX_TBRX_P1: length 85
  TOP w0.127: v2(52.77,62.39) 52.64,62.52 52.32,62.52 CT31.2
  IN2 w0.102: v2(121.62,74.66) 121.47,74.81 121.28,74.81 120.83,74.36 114.52,74.36 113.91,73.75 112.26,73.75 110.84,72.33 108.35,72.33 106.32,70.3 99.54,70.3 96.7,73.14 92.67,73.14 92.06,73.75 90.33,73.75 89.51,72.93 82.92,72.93 82.33,73.52 79.65,73.52 79.05,74.13 70.29,74.13 70.17,74 68.69,74 67.54,72.86 64.76,72.86 64.02,72.12 62.98,72.12 60.62,69.76 60.31,69.76 57.21,66.66 55.63,66.66 55.32,66.35 55.32,64.73 53.16,62.57 52.95,62.57 v2(52.77,62.39)
  BOTTOM w0.076: 122.39,72.68 122.39,72.67 122.25,72.54 122.25,72.17 122.27,72.13 122.31,72.05 122.31,71.96 122.25,71.77 122.25,71.55 122.27,71.5 122.34,71.26 122.42,70.87 UCPU1.D52
  BOTTOM w0.089: 122.39,72.68 122.39,72.91 122.45,72.97 122.45,73.28 122.15,73.58 122.15,74.74 122.03,74.85 121.82,74.85 v2(121.62,74.66)
DDI2_PTX_TBRX_P1_C: length 4.6
  TOP w0.076: 48.54,62.54 48.53,62.54 48.49,62.57 47.88,62.57 47.86,62.6 47.32,62.6 UT1.AB17
  TOP w0.127: CT31.1 51.32,62.54 48.54,62.54
DDI2_PTX_TBRX_P2: length 90.8
  TOP w0.127: v2(50.44,63.2) 50.25,63.4 50.12,63.4 CT33.2
  IN2 w0.102: v2(50.44,63.2) 50.61,63.37 51.41,63.37 51.96,63.92 53.57,63.92 54.28,64.63 54.28,66.2 55.38,67.3 56.61,67.3 57.26,67.95 57.4,67.95 59.97,70.52 60.48,70.52 62.71,72.75 63.73,72.75 64.48,73.5 67.26,73.5 68.41,74.64 69.87,74.64 70.65,75.43 73.32,75.43 73.52,75.63 78.48,75.63 79.95,74.16 82.61,74.16 83.17,73.59 89.18,73.59 90.15,74.56 98.57,74.56 102.18,70.96 105.6,70.96 107.66,73.01 109.96,73.01 110.74,73.8 110.74,74.43 111,74.69 113.65,74.69 115.85,76.89 120.14,76.89 120.5,76.54 120.88,76.54 v2(121.08,76.34)
  BOTTOM w0.076: 121.97,75.72 121.99,75.72 122.03,75.77 123.39,75.77 123.57,75.58 123.57,72.95 123.38,72.76 123.38,72.07 123.55,71.9 123.69,71.9 123.81,71.78 UCPU1.B50
  BOTTOM w0.127: 121.97,75.72 121.74,75.72 121.5,75.95 121.5,76.49 121.43,76.56 121.31,76.56 v2(121.08,76.34)
DDI2_PTX_TBRX_P2_C: length 2.6
  TOP w0.076: UT1.AB19 47.24,63.6 47.34,63.49 47.75,63.49 47.88,63.62 48.35,63.62 48.38,63.59 48.39,63.59
  TOP w0.127: CT33.1 49.14,63.4 48.83,63.4 48.64,63.59 48.39,63.59
DDI2_PTX_TBRX_P3: length 91.7
  TOP w0.127: v2(50.5,65.39) 50.29,65.18 50.1,65.18 CT35.2
  IN2 w0.102: v2(122.79,75.39) 122.6,75.19 122.45,75.19 122.33,75.32 122.33,75.54 121.74,76.12 121.74,77.24 121.23,77.75 115.49,77.75 114.45,76.71 110.09,76.71 109.15,75.77 109.15,74.96 108.13,73.93 107.32,73.93 105.24,71.86 102.51,71.86 98.37,76 92.81,76 92.53,75.72 91.37,75.72 91.2,75.89 89.55,75.89 88.11,74.46 83.81,74.46 82.84,75.42 79.92,75.42 78.85,76.49 73.08,76.49 72.87,76.29 66.02,76.29 63.33,73.6 62.3,73.6 60.19,71.48 59.68,71.48 57.62,69.43 56.81,69.43 56.17,68.79 55.08,68.79 54.05,67.76 53.22,67.76 52.09,66.62 52.09,65.8 51.55,65.26 50.62,65.26 v2(50.5,65.39)
  BOTTOM w0.076: UCPU1.C51 123.25,71.16 123.3,71.11 123.45,71.11 123.55,71.21 123.55,71.47 123.32,71.71 123.32,71.88 123.16,72.04 123.16,72.89 123.41,73.14 123.41,74.88 123.13,75.15 123.02,75.15 v2(122.79,75.39)
DDI2_PTX_TBRX_P3_C: length 2.5
  TOP w0.076: UT1.AB21 47.32,64.88 48.03,64.88 48.29,65.15 48.45,65.15 48.49,65.19 48.5,65.19
  TOP w0.127: 48.5,65.19 49.17,65.19 CT35.1
DDR_A0_ZQ0: length 4.4
  TOP w0.127: UD19.B3 99.91,24.73 99.45,24.73 99.16,24.44 99.16,23.83 v3(98.25,22.92) 98.17,22.84 RD51.1
DDR_A0_ZQ1: length 3.9
  TOP w0.127: RD53.1 97.35,24.74 v3(98.16,25.55) 98.91,26.3 99.93,26.3 100.27,25.96 UD19.B4
DDR_A1_ZQ0: length 6.5
  TOP w0.127: RD52.1 116.43,20.53 v3(116.43,21.24) 116.43,21.38 114.77,23.04 114.77,24.49 114.92,24.65 115.34,24.65 UD20.B3
DDR_A1_ZQ1: length 7.7
  TOP w0.127: UD20.B4 115.42,26.27 114.81,26.27 114.76,26.23 114.76,24.89 114.45,24.58 114.45,22.68 114.68,22.45 v3(114.68,21.37) 114.68,20.63 RD54.1
DDR_A_CA1_0: length 44.6
  TOP w0.142: UD19.R2 108.72,24.3 108.41,23.99 108.41,23.64 109.76,22.29 109.76,21.53 110.24,21.05 v2(110.69,21.05) 111.48,20.26 RD59.1
  IN2 w0.102: v2(110.69,21.05) 110.69,21.19 110.72,21.19 114.15,24.62 114.15,27.3 114.93,28.09 115.45,28.09 115.79,28.42 115.79,28.83 115.96,29.01 115.96,30.57 115.65,30.88 115.65,32.07 116.05,32.47 116.05,34.86 118.55,37.36 118.55,37.5 118.21,37.84 118.21,37.98 118.36,38.13 118.5,38.13 118.84,37.79 118.98,37.79 119.13,37.93 119.13,38.07 118.79,38.41 118.79,38.56 118.93,38.7 119.07,38.7 119.41,38.36 119.56,38.36 119.7,38.51 119.7,38.65 119.36,38.99 119.36,39.13 119.51,39.28 119.65,39.28 119.99,38.94 120.13,38.94 120.66,39.47 120.66,42.87 v2(121.08,43.29)
  BOTTOM w0.076: v2(121.08,43.29) 122.73,44.94 122.73,49.21 122.99,49.46 122.99,49.82 122.99,49.82 122.95,49.91 122.95,50.11 122.99,50.2 122.99,50.2 122.99,50.2 122.99,50.21 122.99,50.44 UCPU1.BA51
DDR_A_CA1_1: length 45.4
  TOP w0.142: UD19.P2 108.11,24.26 108.11,23.14 109.1,22.14 v2(109.1,21.38) 109.4,21.08 109.72,21.08 110.59,20.21 RD61.1
  IN2 w0.102: v2(109.1,21.38) 109.86,21.38 110.33,21.85 110.41,21.85 110.88,22.32 110.88,22.47 110.68,22.67 110.68,22.82 110.82,22.96 110.96,22.96 111.17,22.75 111.32,22.75 112.81,24.25 112.81,27.13 113.98,28.3 113.98,31.86 114.08,31.96 114.59,31.96 114.7,32.07 114.7,32.27 114.59,32.37 114.08,32.37 113.98,32.47 113.98,32.72 114.09,32.83 114.61,32.83 115.47,33.69 115.47,34.62 115.37,34.72 114.91,34.72 114.81,34.82 114.81,35.02 114.91,35.13 115.37,35.13 115.47,35.23 115.47,36.08 115.7,36.31 115.84,36.31 116.16,35.99 116.3,35.99 116.45,36.14 116.45,36.28 116.13,36.6 116.13,36.74 116.27,36.88 116.42,36.88 116.73,36.57 116.88,36.57 117.02,36.71 117.02,36.85 116.7,37.17 116.7,37.32 119.76,40.37 119.76,41.18 119.91,41.34 v2(119.91,41.39)
  BOTTOM w0.076: UCPU1.BB54 121.63,49.58 121.63,49.2 121.72,49.11 121.72,47.3 119.41,44.99 v3(119.41,44.08) 119.41,41.89 v2(119.91,41.39)
DDR_A_CA1_2: length 46.5
  TOP w0.142: UD19.N2 107.42,24.3 107.42,23.63 107.32,23.53 107.32,22.15 107.7,21.77 v2(107.7,21.41) 108.19,20.92 108.3,20.92 108.81,20.41 RD63.1
  IN2 w0.102: v2(119.89,42.63) 119.62,42.63 119.47,42.48 119.47,40.49 114.49,35.51 114.49,34.82 114.42,34.75 113.78,34.75 113.65,34.62 113.65,34.44 113.75,34.34 115.06,34.34 115.17,34.22 115.17,34.06 115.06,33.94 113.75,33.94 113.65,33.83 113.65,33.63 113.75,33.53 114.51,33.53 114.63,33.41 114.63,33.26 114.49,33.12 113.75,33.12 113.65,33.02 113.65,28.43 112.48,27.26 112.48,24.41 111.37,23.31 110.22,23.31 109.89,22.97 109.89,22.2 109.69,22.01 108.3,22.01 v2(107.7,21.41)
  BOTTOM w0.076: UCPU1.BA52 122.55,50.11 122.29,49.85 122.29,49.48 122.38,49.39 122.38,46.28 120.68,44.57 120.68,43.42 v2(119.89,42.63)
DDR_A_CA1_3: length 46.1
  TOP w0.076: 107.73,23.72 107.73,24.79 UD19.N3
  TOP w0.142: RD65.1 109.7,20.5 109.51,20.7 109.12,20.7 v2(108.44,21.38) 108.44,22.22 107.73,22.93 107.73,23.72
  IN2 w0.102: v2(108.44,21.38) 108.9,20.93 109.87,20.93 110.47,21.52 110.57,21.52 113.16,24.11 113.16,27.01 114.3,28.15 114.3,29.37 114.4,29.47 114.81,29.47 114.91,29.57 114.91,29.77 114.81,29.87 114.4,29.87 114.4,29.89 114.27,30.03 114.27,31.16 114.99,31.89 114.99,32.8 115.76,33.57 115.76,35.57 115.87,35.68 116.46,35.68 117.48,36.71 117.48,36.85 117.14,37.19 117.14,37.34 117.29,37.48 117.43,37.48 117.77,37.14 117.92,37.14 118.06,37.28 118.06,37.42 117.72,37.77 117.72,37.91 120.37,40.56 120.37,43.75 v2(121.08,44.46)
  BOTTOM w0.076: UCPU1.AY52 122.65,50.72 122.75,50.62 122.82,50.43 122.82,50.23 122.79,50.14 122.79,49.89 122.79,49.88 122.82,49.79 122.82,49.53 122.56,49.26 122.56,45.93 v3(121.87,45.24) v2(121.08,44.46)
DDR_A_CA1_4: length 48.2
  TOP w0.076: 106.92,23.87 107.09,24.05 107.09,24.78 UD19.M3
  TOP w0.142: RD67.1 107.93,20.54 107.61,20.85 107.47,20.85 v2(106.89,21.43) 106.89,21.76 106.76,21.89 106.76,23.71 106.92,23.87
  IN2 w0.102: v2(106.89,21.43) 106.45,21.43 106.32,21.56 106.32,21.84 106.45,21.96 107.09,21.96 107.26,22.13 107.4,22.13 107.64,21.89 107.77,21.89 107.93,22.04 107.93,22.18 107.69,22.42 107.69,22.56 107.91,22.79 108.14,22.79 108.24,22.68 108.24,22.4 108.34,22.3 108.42,22.3 108.55,22.3 108.65,22.4 108.65,22.68 108.75,22.79 109.02,22.79 109.11,22.69 109.11,22.4 109.21,22.3 109.49,22.3 109.59,22.4 109.59,23.09 110.1,23.6 111.2,23.6 112.15,24.55 112.15,27.4 113.32,28.57 113.32,34.76 119.18,40.61 119.18,43.23 119.31,43.37 119.74,43.37 v2(119.89,43.21)
  BOTTOM w0.076: UCPU1.AW52 122.65,51.52 122.33,51.2 122.33,50.58 122.12,50.37 122.12,49.41 122.21,49.32 122.21,46.35 120.37,44.51 120.37,43.7 v2(119.89,43.21)
DDR_A_CA1_5: length 50.6
  TOP w0.076: UD19.F3 103.21,24.76 103.21,24.06 v2(103.52,23.74)
  TOP w0.142: v2(103.52,23.74) 103.52,23.2 102.06,21.74 101.14,21.74 100.38,20.98 RD69.1
  IN2 w0.102: v2(118.09,42.25) 117.33,42.25 115.87,40.79 115.87,40.64 116.54,39.97 116.54,39.83 116.39,39.69 116.25,39.69 115.58,40.36 115.43,40.36 115.29,40.21 115.29,40.07 115.96,39.4 115.96,39.26 115.82,39.11 115.67,39.11 115.25,39.53 115.08,39.53 114.96,39.42 114.96,39.25 115.39,38.82 115.39,38.68 112,35.29 112,29.12 110.83,27.95 110.83,25.11 110.48,24.77 108.12,24.77 106.63,23.27 104,23.27 v2(103.52,23.74)
  BOTTOM w0.076: v2(118.09,42.25) 118.87,43.04 118.87,45.04 120.83,47 120.83,47.23 v3(121.08,47.48) 121.39,47.79 121.39,48.98 121.3,49.06 121.3,49.26 121.09,49.46 121.09,49.83 121.11,49.86 121.14,49.94 121.14,50.06 121.08,50.27 121.08,50.42 121.13,50.58 121.13,50.76 121.06,50.92 120.76,51.21 UCPU1.AY55
DDR_A_CA1_6: length 49.9
  TOP w0.076: UD19.E3 101.89,24.76 101.89,23.9
  TOP w0.142: 101.89,23.9 101.78,23.8 v2(101.78,22.86) 101.33,22.4 100.18,22.4 98.6,20.82 RD71.1
  IN2 w0.102: v2(101.78,22.86) 101.78,22.75 102.28,22.25 106.97,22.25 107.79,23.08 109.17,23.08 109.98,23.89 111.02,23.89 111.82,24.68 111.82,27.54 112.99,28.71 112.99,34.86 118.85,40.72 118.85,43.32 v2(119.91,44.38)
  BOTTOM w0.076: UCPU1.AW54 121.43,51.42 121.74,51.11 121.74,50.56 121.96,50.34 121.96,49.34 122.05,49.25 122.05,46.74 v3(120.56,45.25) 120.31,45 120.31,44.78 v2(119.91,44.38)
DDR_A_CA1_7: length 48.7
  TOP w0.142: UD19.E2 102.22,24.3 102.22,23 v2(102.37,22.86) 102.37,22.72 101.72,22.07 100.32,22.07 99.49,21.24 RD73.1
  IN2 w0.102: v2(119.89,44.97) 119.65,44.97 119.38,44.7 119.38,44.28 119.18,44.08 119.05,44.08 118.95,44.18 118.95,44.59 118.82,44.71 118.64,44.71 118.52,44.59 118.52,40.86 118.28,40.62 118.27,40.62 112.66,35.01 112.66,28.85 111.49,27.67 111.49,24.82 110.85,24.18 109.86,24.18 109.05,23.37 108.61,23.37 108.48,23.5 108.48,23.76 108.36,23.88 108.19,23.88 108.08,23.78 108.08,23.5 107.94,23.37 107.67,23.37 106.89,22.58 102.64,22.58 v2(102.37,22.86)
  BOTTOM w0.076: UCPU1.BA54 121.53,50.12 121.79,49.86 121.79,49.27 121.88,49.18 121.88,47.09 120.2,45.41 120.2,45.27 v2(119.89,44.97)
DDR_A_CA1_8: length 49.2
  TOP w0.142: RD75.1 97.71,20.44 100,22.74 101.11,22.74 101.33,22.96 101.33,23.74 v2(101.23,23.85) 101.23,23.95 UD19.D2
  IN2 w0.102: v2(101.23,23.85) 101.56,23.85 101.97,24.25 107.08,24.25 107.89,25.06 109.43,25.06 109.92,25.55 109.92,27.51 111.67,29.26 111.67,35.39 114.3,38.01 114.3,38.16 113.63,38.82 113.63,38.97 113.78,39.11 113.92,39.11 114.58,38.44 114.73,38.44 114.87,38.59 114.87,38.73 114.21,39.4 114.21,39.54 117.52,42.86 v2(118.06,42.86)
  BOTTOM w0.076: UCPU1.BA55 120.63,50.43 120.63,50.19 120.58,50.06 120.58,49.96 120.63,49.82 120.63,49.41 120.49,49.27 120.49,48.95 120.74,48.7 120.99,48.7 121.21,48.48 121.21,48.12 120.9,47.81 120.85,47.81 120.63,47.58 120.63,47.03 118.69,45.1 118.69,43.49 v2(118.06,42.86)
DDR_A_CA1_9: length 51
  TOP w0.142: RD77.1 96.82,20.68 99.23,23.09 100.69,23.09 v2(100.87,23.26) 100.81,23.32 100.81,24.19 UD19.C2
  IN2 w0.102: v2(100.87,23.26) 100.92,23.31 102.73,23.31 103.13,22.91 106.8,22.91 108.36,24.48 110.67,24.48 111.16,24.96 111.16,27.81 112.33,28.98 112.33,35.21 117.08,39.96 117.08,40.1 116.41,40.77 116.41,40.92 116.55,41.06 116.69,41.06 117.36,40.39 117.51,40.39 117.65,40.53 117.65,40.68 117.44,40.89 117.44,41.35 117.75,41.66 v2(118.11,41.66)
  BOTTOM w0.076: UCPU1.AY54 121.33,50.88 121.33,50.63 121.25,50.41 121.25,50.28 121.31,50.05 121.31,49.91 121.26,49.79 121.26,49.53 121.46,49.33 121.46,49.13 121.55,49.04 121.55,47.42 119.04,44.91 119.04,42.59 v3(118.67,42.22) v2(118.11,41.66)
DDR_A_CA2_0: length 47.5
  TOP w0.127: UD20.R2 124.24,24.3 124.24,23.12 v2(124.44,22.92)
  TOP w0.142: RD79.1 127.88,20.89 127.74,20.89 v3(126.83,21.81) 125.77,22.87 124.49,22.87 v2(124.44,22.92)
  IN1 w0.117: v2(125.25,52.47) 125.44,52.47 125.62,52.29 125.62,51.65 125.45,51.48 125.08,51.48 124.91,51.3 124.91,50.94 124.67,50.71 124.31,50.71 124.14,50.53 124.14,39.27 124.5,38.91 124.5,38.74 124.3,38.55 124.3,38.38 124.47,38.22 124.63,38.22 124.83,38.41 124.99,38.41 125.16,38.25 125.16,38.08 124.97,37.89 124.97,37.72 125.13,37.56 125.3,37.56 125.49,37.75 125.65,37.75 125.82,37.58 125.82,37.42 125.63,37.22 125.63,37.06 125.79,36.89 125.96,36.89 126.15,37.09 126.32,37.09 126.48,36.92 126.48,36.76 126.29,36.56 126.29,36.4 126.45,36.23 126.62,36.23 126.81,36.43 126.98,36.43 127.14,36.26 127.14,36.1 126.95,35.9 126.95,35.74 127.12,35.57 127.28,35.57 127.47,35.76 127.64,35.76 127.95,35.45 127.95,25.44 126.5,23.99 126.21,23.99 125.67,24.53 125.51,24.53 125.32,24.33 125.32,24.17 125.91,23.57 125.91,23.41 125.75,23.24 125.58,23.24 125.42,23.4 124.92,23.4 v2(124.44,22.92)
  BOTTOM w0.076: UCPU1.AU46 125.58,52.8 v2(125.25,52.47)
DDR_A_CA2_1: length 44.9
  TOP w0.142: UD20.P2 123.75,24.14 v2(123.75,22.92) 124.18,22.49 125.58,22.49 127.74,20.33 RD81.1
  IN2 w0.102: v2(124.32,52.47) 124.31,52.47 124.21,52.37 124.21,51.95 124,51.75 124,51.27 124.12,51.15 124.12,39 127.79,35.33 127.79,28.6 127.69,28.5 127.36,28.5 127.25,28.4 127.25,28.19 127.36,28.09 127.95,28.09 128.07,27.97 128.07,27.8 127.95,27.69 127.36,27.69 127.25,27.58 127.25,27.38 127.36,27.28 127.95,27.28 128.07,27.16 128.07,26.99 127.95,26.87 127.36,26.87 127.25,26.77 127.25,26.57 127.36,26.47 127.69,26.47 127.79,26.36 127.79,25.59 124.69,22.49 124.18,22.49 v2(123.75,22.92)
  BOTTOM w0.076: v2(124.32,52.47) 124.66,52.8 UCPU1.AU48
DDR_A_CA2_2: length 44.7
  TOP w0.127: UD20.N2 122.89,24.24 122.89,23.52 v2(122.78,23.41)
  TOP w0.142: RD83.1 125.96,20.9 125.18,21.67 123.82,21.67 122.73,22.76 122.73,23.36 v2(122.78,23.41)
  IN1 w0.117: v2(122.78,23.41) 122.69,23.41 122.75,23.35 123.9,23.35 125.38,24.83 126.91,24.83 127.3,25.22 127.3,26.82 127.19,26.94 126.71,26.94 126.59,27.06 126.59,27.29 126.71,27.41 127.19,27.41 127.3,27.52 127.3,27.76 127.19,27.87 126.71,27.87 126.59,27.99 126.59,28.23 126.71,28.34 127.19,28.34 127.3,28.46 127.3,34.83 123.83,38.31 123.83,51.48 124.33,51.99 124.45,51.99 124.82,52.36 124.82,52.67 v2(125.25,53.1)
  BOTTOM w0.076: v2(125.25,53.1) 125.6,53.45 UCPU1.AT46
DDR_A_CA2_3: length 44.9
  TOP w0.076: UD20.N3 123.27,24.77 123.27,23.94
  TOP w0.142: 123.27,23.94 v2(123.27,23.78) 123.19,23.71 123.19,22.77 123.96,22 125.41,22 126.85,20.56 RD85.1
  IN2 w0.102: v2(123.4,52.47) 122.83,51.91 122.83,49.53 122.73,49.43 122.73,48.78 123.46,48.05 123.46,38.73 126.6,35.59 126.6,33.27 126.5,33.17 126.16,33.17 126.06,33.07 126.06,32.86 126.16,32.76 126.5,32.76 126.6,32.66 126.6,32.46 126.5,32.36 126.16,32.36 126.06,32.25 126.06,32.05 126.16,31.95 126.5,31.95 126.6,31.85 126.6,29.02 126.5,28.92 126.09,28.92 125.98,28.82 125.98,28.62 126.09,28.52 126.5,28.52 126.6,28.41 126.6,28.21 126.5,28.11 126.09,28.11 125.98,28.01 125.98,27.8 126.09,27.7 126.5,27.7 126.6,27.6 126.6,25.52 124.93,23.85 124.32,23.85 124.22,23.95 124.02,23.95 123.92,23.85 123.92,23.75 123.82,23.64 123.41,23.64 v2(123.27,23.78)
  BOTTOM w0.076: v2(123.4,52.47) 123.73,52.8 UCPU1.AU50
DDR_A_CA2_4: length 42.7
  TOP w0.076: UD20.M3 122.61,24.78 122.61,24.16 122.28,23.83
  TOP w0.142: v2(122.28,23.76) 122.28,23.83 122.23,23.78 122.23,22.8 123.68,21.34 124.7,21.34 125.07,20.97 RD87.1
  IN2 w0.102: v2(122.28,23.76) 122.28,23.81 122.71,24.24 124.91,24.24 125.16,24.5 125.16,27.73 125.64,28.2 125.64,34.21 125.74,34.32 126.19,34.32 126.29,34.42 126.29,34.62 126.19,34.72 125.74,34.72 125.64,34.82 125.64,35.03 125.74,35.13 126.19,35.13 126.29,35.23 126.29,35.43 126.19,35.53 125.74,35.53 125.64,35.64 125.64,36.08 123.13,38.59 123.13,47.91 122.4,48.64 122.4,49.56 122.5,49.67 122.5,52.39 v2(122.42,52.47)
  BOTTOM w0.076: UCPU1.AU52 122.75,52.8 v2(122.42,52.47)
DDR_A_CA2_5: length 44
  TOP w0.076: 118.81,23.46 118.7,23.57 118.7,24.68 v2(118.72,24.7)
  TOP w0.142: RD89.1 120.63,20.86 118.81,22.68 118.81,23.46 ; UD20.F3 118.39,25.03 v2(118.72,24.7)
  IN2 w0.102: v2(121.08,42.66) 121.41,42.99 121.82,42.99 121.91,42.9 121.91,42.69 121.62,42.4 121.62,42.13 121.91,41.84 121.91,36.83 121.81,36.73 121.46,36.73 121.36,36.63 121.36,36.42 121.46,36.32 122.2,36.32 122.3,36.22 122.3,36.02 122.2,35.91 121.46,35.91 121.36,35.81 121.36,35.61 121.46,35.51 122.07,35.51 122.2,35.38 122.2,35.19 122.07,35.07 121.71,35.07 121.61,34.97 121.61,34.63 121.51,34.53 121.31,34.53 121.2,34.63 121.2,34.97 121.1,35.07 120.9,35.07 120.8,34.97 120.8,34.63 120.7,34.53 120.49,34.53 120.39,34.63 120.39,34.97 120.29,35.07 119.98,35.07 119.85,34.94 119.85,34.17 119.98,34.04 121.03,34.04 121.16,33.92 121.16,32.69 120.51,32.04 120.51,30.73 119.47,29.69 119.47,28 118.9,27.43 118.9,24.89 v2(118.72,24.7)
  BOTTOM w0.076: v2(121.08,42.66) 123.34,44.92 v3(123.34,46.36) 123.34,48.5 123.6,48.75 123.6,49.31 123.45,49.46 123.45,49.83 123.49,49.94 123.49,50.06 123.43,50.27 123.43,50.42 123.49,50.58 123.49,51.08 UCPU1.AY51
DDR_A_CA2_6: length 46.8
  TOP w0.076: v2(118.07,24.7) 118.07,24.18 117.86,23.97 117.86,23.74
  TOP w0.142: UD20.E3 117.74,25.03 v2(118.07,24.7) ; 117.86,23.74 117.86,23.74 117.86,23.16 119.74,21.28 v3(119.74,21.12) RD91.1
  IN2 w0.102: v2(124.32,53.1) 124.22,53.1 123.83,52.71 123.83,52.26 123.67,52.1 123.67,51.13 123.79,51.01 123.79,38.86 126.89,35.76 126.89,25.4 124.84,23.35 123.57,23.35 123.22,23 122.61,23 122.2,22.59 121.03,22.59 120.31,23.31 120.14,23.31 119.21,24.23 118.54,24.23 v2(118.07,24.7)
  BOTTOM w0.076: v2(124.32,53.1) 124.67,53.45 UCPU1.AT48
DDR_A_CA2_7: length 45
  TOP w0.142: RD93.1 118.95,20.25 118.95,21.6 117.28,23.27 v2(117.28,23.74) 117.74,24.21 UD20.E2
  IN1 w0.117: v2(123.39,53.07) 123.83,52.64 123.83,52.28 123.11,51.57 123.11,49.67 122.81,49.36 122.81,48.85 123.52,48.14 123.52,38.18 127,34.71 127,29.29 125.22,27.52 118.95,27.52 118.62,27.19 118.62,26.25 117.28,24.91 v2(117.28,23.74)
  BOTTOM w0.076: v2(123.39,53.07) 123.78,53.45 UCPU1.AT50
DDR_A_CA2_8: length 43.2
  TOP w0.076: 116.87,23.45 116.87,24.07 UD20.D2
  TOP w0.142: v2(116.77,24.7) 117.09,24.38 UD20.D2 ; RD95.1 117.93,22.15 116.87,23.21 116.87,23.45
  IN2 w0.102: v2(116.77,24.7) 116.17,24.1 115.5,24.1 115.01,24.59 115.01,27.42 115.23,27.64 116.33,27.64 117.19,28.5 117.19,31.65 117.68,32.14 117.68,32.97 117.78,33.07 118.23,33.07 118.34,33.17 118.34,33.37 118.23,33.47 117.78,33.47 117.68,33.58 117.68,33.78 117.78,33.88 118.23,33.88 118.34,33.98 118.34,34.19 118.23,34.29 117.78,34.29 117.68,34.39 117.68,35.14 118,35.46 118,35.6 117.68,35.92 117.68,36.06 117.83,36.2 117.97,36.2 118.28,35.89 118.43,35.89 118.55,36.01 118.55,36.15 118.26,36.44 118.26,36.6 118.38,36.72 118.55,36.72 118.83,36.44 118.98,36.44 119.12,36.58 119.12,36.73 118.84,37.01 118.84,37.18 118.96,37.3 119.13,37.3 119.41,37.01 119.55,37.01 119.7,37.16 119.7,37.3 119.56,37.44 119.56,37.58 119.71,37.72 119.85,37.72 119.99,37.59 120.13,37.59 120.27,37.73 120.27,37.88 120.14,38.01 120.14,38.18 120.26,38.3 120.43,38.3 120.56,38.16 120.7,38.16 121.13,38.59 121.13,40.85 v2(121.08,40.9)
  BOTTOM w0.076: UCPU1.BB50 123.96,49.61 123.96,43.78 v3(121.77,41.59) v2(121.08,40.9)
DDR_A_CA2_9: length 40.2
  TOP w0.142: RD97.1 117.04,22.57 116.32,23.29 v2(116.32,23.66) 116.44,23.79 UD20.C2
  IN2 w0.102: v2(121.08,42.07) 121.18,42.07 121.58,41.67 121.58,37.44 121.4,37.26 121.26,37.26 120.81,37.71 120.67,37.71 120.52,37.57 120.52,37.43 120.97,36.98 120.97,36.83 120.13,35.99 119.99,35.99 119.75,36.22 119.6,36.22 119.46,36.08 119.46,35.94 119.7,35.7 119.7,35.56 119.56,35.42 119.56,35.27 119.46,35.17 118.46,35.17 118.34,35.05 118.34,34.88 118.46,34.76 119.46,34.76 119.56,34.66 119.56,31.25 119.14,30.83 119.14,28.37 118.52,27.75 118.52,26.05 117.58,25.1 117.58,24.67 116.56,23.66 v2(116.32,23.66)
  BOTTOM w0.076: v2(121.08,42.07) v3(122.58,43.57) 123.79,44.78 123.79,49.35 123.61,49.53 123.61,49.79 123.65,49.87 123.66,49.88 123.67,49.91 123.67,50.05 123.61,50.28 123.61,50.41 123.68,50.63 123.88,50.83 UCPU1.AY50
DDR_A_CKE0: length 59.4
  TOP w0.076: v2(105.8,24.7) 105.8,23.98 105.87,23.9 105.87,23.52
  TOP w0.142: v2(105.8,24.7) 105.47,25.03 UD19.K3 ; RD103.1 107.04,20.63 106.3,21.37 106.3,23.09 105.87,23.52
  IN2 w0.102: v2(119.61,46.95) 119.45,46.95 118.81,47.58 117.46,47.58 117.29,47.41 117.29,43.19 111.59,37.5 109.39,37.5 109.27,37.38 109.27,37.21 109.39,37.09 111.79,37.09 111.91,36.97 111.91,36.81 111.79,36.69 110.19,36.69 110.08,36.58 110.08,36.38 110.19,36.28 111.4,36.28 111.51,36.18 111.51,35.98 111.4,35.87 108.86,35.87 108.76,35.77 108.76,35.57 108.86,35.47 110.59,35.47 110.69,35.37 110.69,35.16 110.59,35.06 108.86,35.06 108.76,34.96 108.76,34.76 108.86,34.65 110.69,34.65 110.8,34.55 110.8,34.35 110.69,34.25 109.47,34.25 109.37,34.15 109.37,33.94 109.47,33.84 110.71,33.84 111.14,33.41 111.14,30.91 110.16,29.93 110.16,28.32 109.51,27.68 109.51,26.15 109.27,25.9 108.48,25.9 108.48,25.91 108.16,25.91 107.31,25.05 106.15,25.05 v2(105.8,24.7)
  BOTTOM w0.076: v2(119.61,46.95) 119.61,47.17 120.19,47.75 120.19,48.55 119.93,48.81 119.93,49.79 119.93,49.79 120.05,50.04 120.06,50.04 120.06,50.04 120.2,50.19 UCPU1.BA56
DDR_A_CKE1: length 63.7
  TOP w0.142: v2(105.8,26.3) 105.47,25.98 UD19.K4 ; RD105.1 103.04,20.88 v2(103.45,21.29)
  IN2 w0.102: v2(105.8,26.3) 106.2,26.71 106.79,26.71 106.8,26.7 107.27,26.7 107.28,26.69 107.56,26.69 107.57,26.68 107.58,26.69 107.92,26.69 107.93,26.69 107.93,26.69 108.19,26.69 108.36,26.87 108.36,27.76 107.77,28.35 107.77,28.71 108.56,29.5 108.56,29.8 109.25,30.49 109.7,30.49 110.18,30.97 110.18,33.34 109.98,33.54 109.27,33.54 108.86,33.94 107.24,33.94 107.14,34.04 107.14,34.25 107.24,34.35 108.26,34.35 108.36,34.45 108.36,34.71 108.26,34.81 106.75,34.81 106.63,34.93 106.63,35.1 106.75,35.22 108.26,35.22 108.36,35.32 108.36,35.52 108.26,35.62 107.24,35.62 107.14,35.72 107.14,35.93 107.24,36.03 108.26,36.03 108.36,36.13 108.36,36.33 108.26,36.43 107.24,36.43 107.14,36.54 107.14,36.74 107.24,36.84 108.44,36.84 108.56,36.96 108.56,37.13 108.44,37.25 106.55,37.25 106.43,37.37 106.43,37.53 106.55,37.65 108.26,37.65 108.36,37.76 108.36,38.21 108.46,38.31 108.73,38.31 108.83,38.21 108.83,37.8 108.93,37.7 109.13,37.7 109.24,37.8 109.24,38.21 109.34,38.31 111.94,38.31 116.99,43.36 116.99,47.53 117.35,47.89 118.92,47.89 119.46,47.35 119.99,47.35 v2(120.16,47.19)
  BOTTOM w0.076: v2(120.16,47.19) 120.37,47.4 120.37,48.6 120.16,48.81 120.16,49.65 UCPU1.BB56
  BOTTOM w0.142: v2(105.8,26.3) 104.54,26.3 104.04,26.81 103.63,26.81 103.07,26.25 103.07,26.04 102.64,25.61 v3(102.64,24.57) 103.07,24.14 103.07,21.68 v2(103.45,21.29)
DDR_A_CKE2: length 63.8
  TOP w0.142: v2(124.33,20.78) 124.18,20.63 RD107.1 ; v2(121.32,24.7) 120.99,25.03 UD20.K3
  IN2 w0.102: v2(120.85,48.27) 121.16,48.27 122.69,46.74 122.69,37.59 122.78,37.5 123.58,37.5 123.7,37.38 123.7,37.21 123.58,37.09 122.99,37.09 122.89,36.99 122.89,36.79 122.99,36.69 124.39,36.69 124.51,36.57 124.51,36.4 124.39,36.28 123.19,36.28 123.09,36.18 123.09,35.98 123.19,35.87 125.13,35.87 125.24,35.77 125.24,35.57 125.13,35.47 123.19,35.47 123.09,35.37 123.09,35.16 123.19,35.06 125.12,35.06 125.24,34.95 125.24,34.77 125.12,34.65 123.19,34.65 123.09,34.55 123.09,34.35 123.19,34.25 124.6,34.25 124.71,34.13 124.71,33.96 124.6,33.84 124.12,33.84 124,33.72 124,33.55 124.12,33.44 124.66,33.44 124.79,33.31 124.79,32.43 124.68,32.32 124.52,32.32 124.41,32.43 124.41,32.93 124.31,33.03 124.1,33.03 124,32.93 124,32.59 123.88,32.46 123.62,32.46 123.5,32.33 123.5,31.71 123.37,31.58 123.19,31.58 123.06,31.71 123.06,32.34 122.95,32.46 122.57,32.46 122.07,31.96 122.07,28.27 123.37,26.98 123.37,26.1 123.66,25.82 124,25.82 124.1,25.71 124.1,24.8 123.95,24.65 122.4,24.65 122.28,24.77 122.28,24.88 122.16,25 121.99,25 121.87,24.88 121.87,23.88 121.77,23.78 121.56,23.78 121.32,24.03 v2(121.32,24.7)
  BOTTOM w0.076: UCPU1.AW56 120.42,51.42 120.42,51.22 120.47,51.17 120.47,50.86 120.44,50.8 120.43,50.79 120.43,50.52 120.47,50.44 120.47,50.23 120.41,50.12 120.41,49.9 120.47,49.79 120.47,49.49 120.33,49.35 120.33,48.88 120.75,48.46 120.75,48.4 120.88,48.27 v2(120.85,48.27)
  BOTTOM w0.142: v2(124.33,20.78) 125.6,22.05 v3(125.6,23.81) 125.14,24.27 124.39,24.27 123.96,24.7 v2(121.32,24.7)
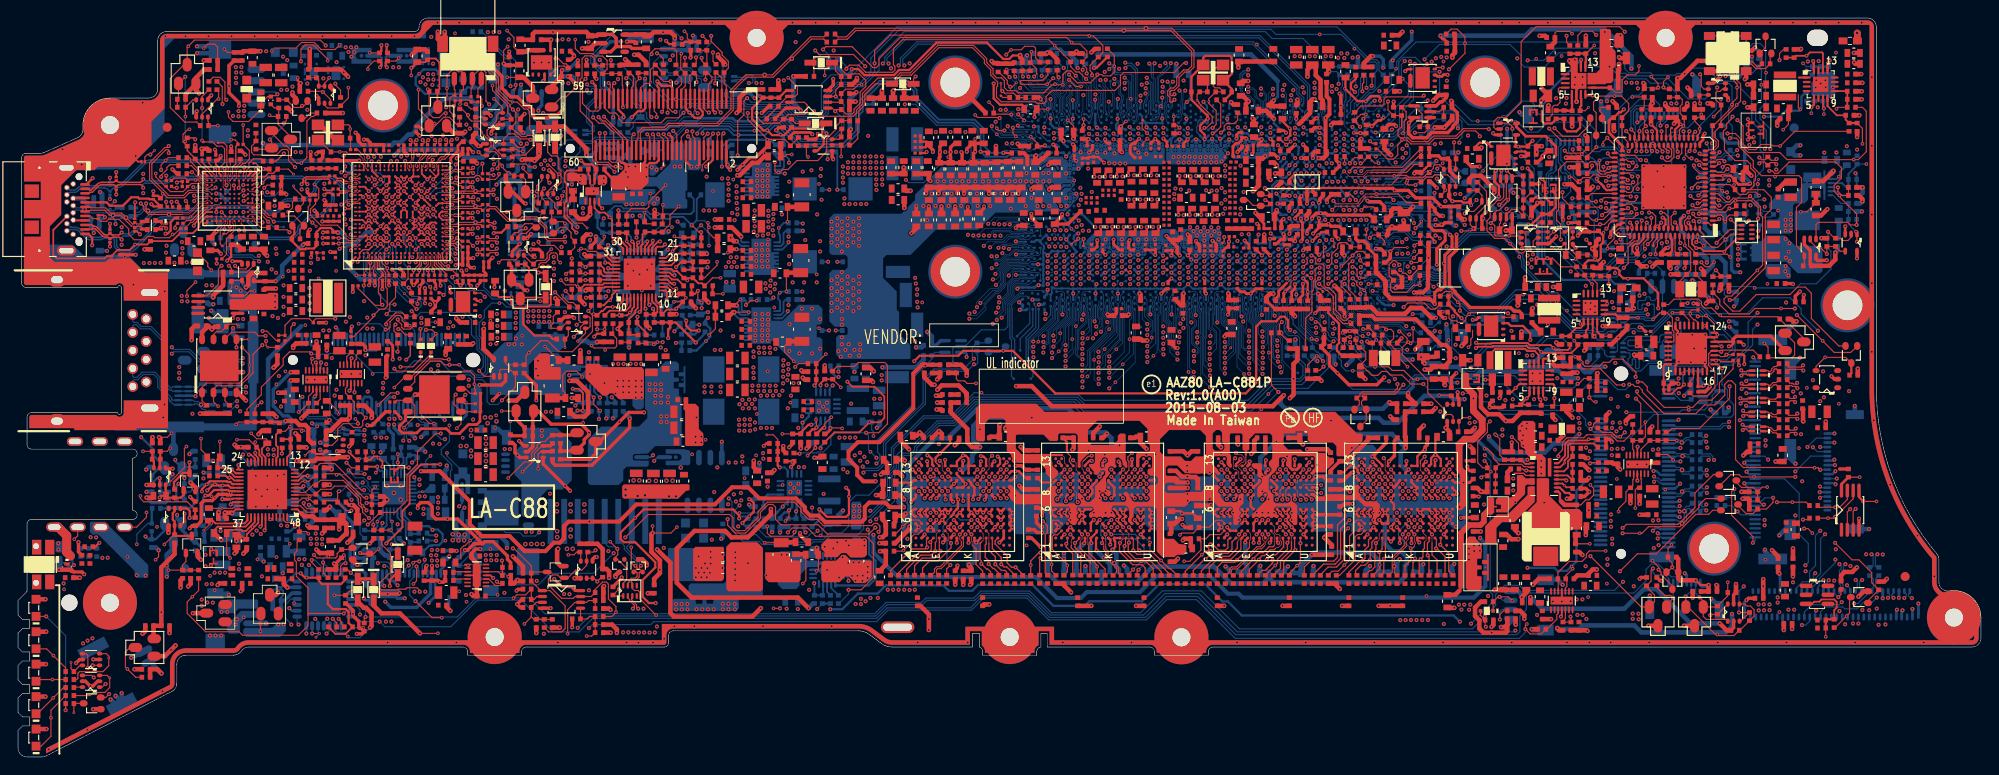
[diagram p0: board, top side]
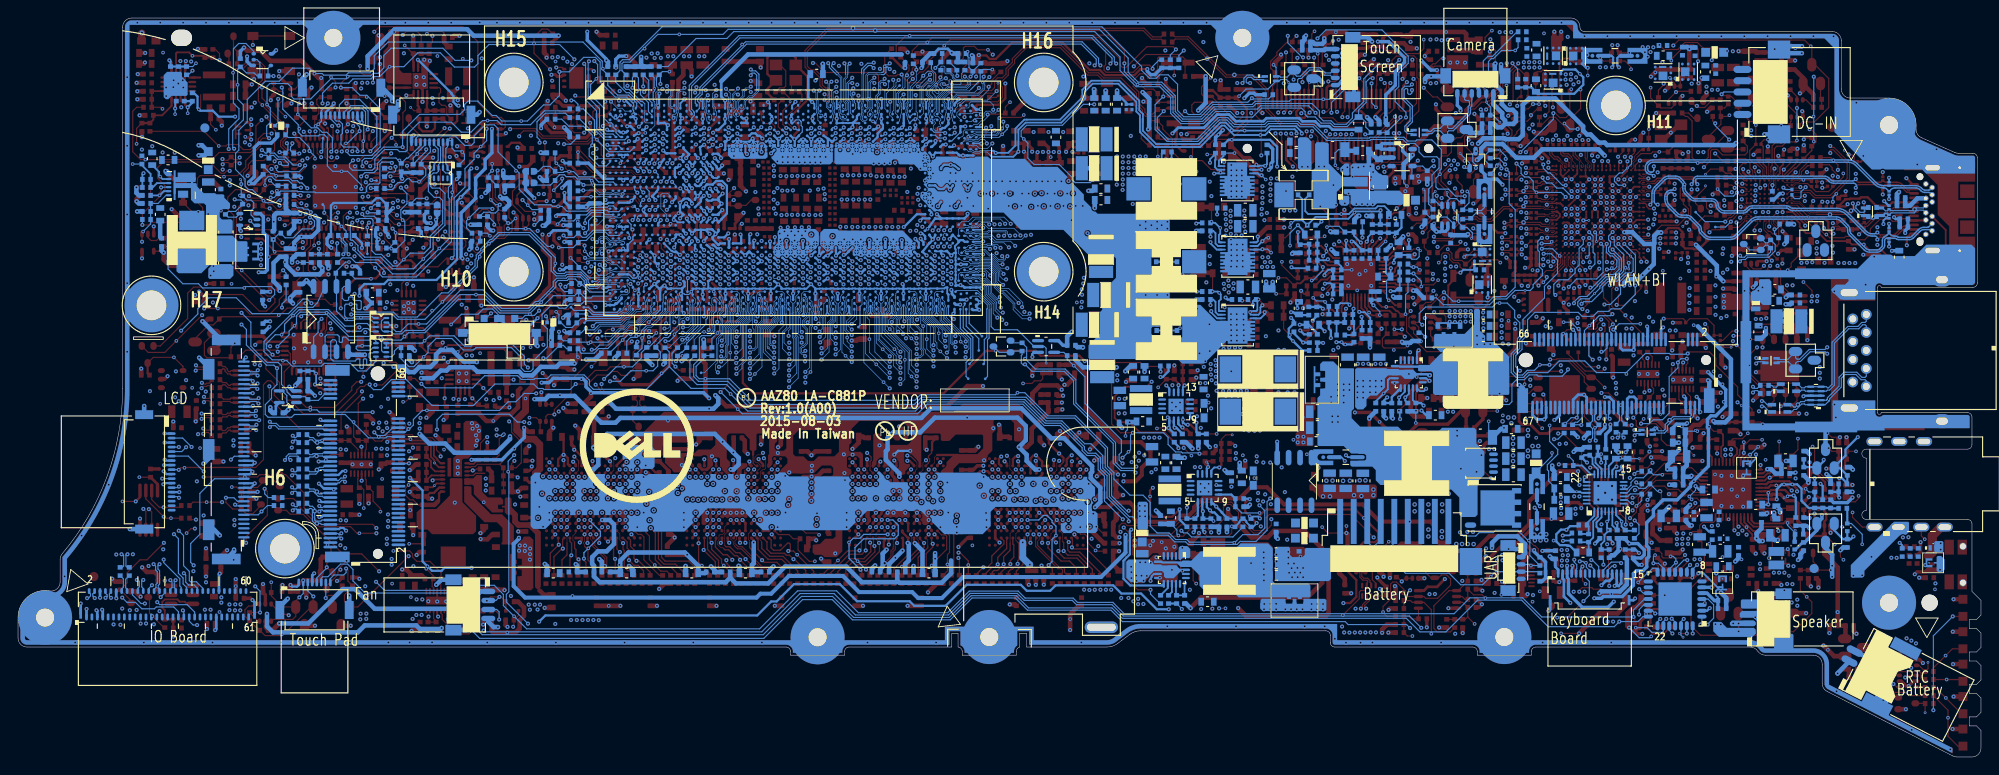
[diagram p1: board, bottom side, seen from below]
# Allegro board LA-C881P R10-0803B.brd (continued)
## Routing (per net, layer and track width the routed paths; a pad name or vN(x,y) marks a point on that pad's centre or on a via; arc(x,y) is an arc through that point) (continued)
DDR_B_D43: length 28.1
  TOP w0.142: UD22.B10 149.42,30.63 v2(149.1,30.3)
  IN4 w0.117: v2(140.03,43.29) 140.23,43.29 140.64,42.88 140.64,42.23 147.55,35.32 147.55,31.3 148.59,30.26 149.06,30.26 v2(149.1,30.3)
  BOTTOM w0.076: v2(140.03,43.29) 139.7,43.29 138.79,44.2 v3(138.79,44.87) 138.79,47.49 138.25,48.03 138.25,48.3 137.62,48.92 137.62,49.35 137.74,49.46 137.74,49.82 137.74,49.82 137.7,49.91 137.7,50.11 137.74,50.2 137.74,50.2 137.74,50.2 137.74,50.21 137.74,50.44 137.7,50.56 137.7,50.82 137.77,50.92 137.77,51.41 138,51.64 UCPU1.AW25
DDR_B_D44: length 29
  TOP w0.142: UD22.C10 150.07,30.79 149.75,31.11 v2(149.74,31.11)
  IN4 w0.117: v2(138.13,46.06) 138.81,46.06 139.4,46.64 139.93,46.64 140.47,46.11 140.47,45.78 140.85,45.4 140.85,45.24 142.31,43.78 142.31,43.66 143.88,42.09 143.88,41.43 144.31,40.99 144.98,40.99 151.11,34.86 151.11,32.5 151.54,32.06 151.54,31.77 151.26,31.49 150.14,31.49 149.74,31.09 v2(149.74,31.11)
  BOTTOM w0.076: v2(138.13,46.06) 138.46,46.39 138.46,47.35 137.9,47.91 137.9,48.18 137.29,48.79 137.29,49.67 UCPU1.BB27
DDR_B_D45: length 32
  TOP w0.142: UD22.C9 150.07,29.9 150.07,29.83 v2(150.4,29.5)
  IN4 w0.076: v2(150.4,29.5) 150.79,29.9 152.48,29.9 152.73,30.14 152.73,32.17 152.5,32.39 152.5,33 151.97,33.54 151.92,33.54
  IN4 w0.117: 151.92,33.54 151.49,33.97 151.49,34.92 145.1,41.3 144.44,41.3 144.2,41.54 144.2,42.2 142.62,43.79 142.62,43.91 141.16,45.37 141.16,45.53 140.77,45.91 140.77,46.23 140.06,46.95 139.27,46.95 138.96,46.64 v2(138.07,46.64)
  BOTTOM w0.076: v2(138.07,46.64) 137.9,46.64 137.64,46.9 137.64,48.2 137.13,48.72 137.13,49.44 137.04,49.53 137.04,50.07 UCPU1.BA27
DDR_B_D46: length 26.4
  TOP w0.142: v2(150.4,31.9) 150.07,31.57 UD22.C11
  IN4 w0.117: v2(139.73,46.21) 139.75,46.21 140.16,45.81 140.16,45.66 140.54,45.27 140.54,45.11 142,43.65 142,43.53 142.21,43.33 142.21,43.16 142,42.96 142,42.79 142.18,42.61 142.31,42.61 142.54,42.83 142.7,42.83 142.87,42.67 142.87,42.5 142.64,42.27 142.64,42.15 142.85,41.94 142.97,41.94 143.2,42.17 143.36,42.17 143.57,41.97 143.57,41.8 143.36,41.6 143.36,41.43 144.31,40.48 145.05,40.48 150.67,34.86 150.67,34.58 150.5,34.41 150.5,34.12 150.67,33.94 150.67,32.52 150.4,32.25 v2(150.4,31.9)
  BOTTOM w0.076: UCPU1.BA25 138.63,50.19 138.78,50.04 138.91,49.77 138.91,49.42 138.91,49.42 138.91,48.32 139.48,47.74 139.48,46.45 v2(139.73,46.21)
DDR_B_D47: length 25.5
  TOP w0.142: v2(149.1,31.9) 149.1,31.82 UD22.B11
  IN4 w0.117: v2(139.73,45.63) 139.75,45.63 140.23,45.14 140.23,44.99 141.7,43.52 141.7,42.66 144.18,40.18 144.92,40.18 149.83,35.27 149.83,34.96 149.72,34.85 149.56,34.85 149.44,34.73 149.44,34.5 149.56,34.38 150.06,34.38 150.19,34.25 150.19,34.04 150.06,33.91 149.56,33.91 149.44,33.79 149.44,33.56 149.56,33.44 149.72,33.44 149.83,33.33 149.83,32.64 v2(149.1,31.9)
  BOTTOM w0.076: v2(139.73,45.63) 139.32,46.03 139.32,47.67 138.74,48.25 138.74,49.35 138.61,49.49 138.61,49.66 UCPU1.BB25
DDR_B_D48: length 42.8
  TOP w0.127: v2(158.85,31.1) 158.52,30.77 158.52,30.7 UD22.T10
  IN1 w0.117: v2(136.2,52.45) 136.2,51.11 136.47,50.84 137.26,50.84 138.81,49.29 138.81,49 140.94,46.87 140.94,45.36 141.38,44.92 141.38,44.31 143.49,42.2 146.2,42.2 151.93,36.47 152.1,36.47 152.37,36.74 152.62,36.74 152.74,36.63 152.74,36.45 152.43,36.14 152.43,35.97 152.99,35.41 153.24,35.41 153.36,35.54 153.36,36.6 153.49,36.73 153.7,36.73 153.83,36.6 153.83,35.49 153.96,35.36 154.17,35.36 154.3,35.49 154.3,36.48 154.42,36.6 154.63,36.6 154.76,36.47 154.76,35.48 154.89,35.36 155.21,35.36 155.33,35.48 155.33,35.57 155.44,35.69 155.68,35.69 155.79,35.57 155.79,35.48 155.91,35.36 157.39,35.36 159.33,33.42 159.33,31.58 v2(158.85,31.1)
  BOTTOM w0.076: UCPU1.AU27 v2(136.2,52.45)
DDR_B_D49: length 43.7
  TOP w0.127: UD22.T11 158.52,31.5 158.52,31.6 158.82,31.9 v2(158.85,31.9)
  IN1 w0.076: v2(136.17,53.1) 136.17,53.05 135.79,52.67 135.79,52.56
  IN1 w0.117: v2(158.85,31.9) 158.85,32.07 158.41,32.51 158.41,33.9 157.26,35.06 155.66,35.06 155.35,34.75 155.35,34.2 155.22,34.07 154.83,34.07 154.7,34.2 154.7,34.75 154.39,35.06 152.91,35.06 146.65,41.31 145.96,41.31 145.85,41.43 145.85,41.77 145.73,41.89 145.49,41.89 145.38,41.77 145.38,41.43 145.26,41.31 143.93,41.31 143.23,42.02 143.06,42.02 142.69,41.65 142.53,41.65 142.36,41.81 142.36,41.98 142.73,42.35 142.73,42.52 142.57,42.68 142.4,42.68 142.03,42.31 141.86,42.31 141.7,42.47 141.7,42.64 142.07,43.01 142.07,43.18 141.91,43.34 141.74,43.34 141.37,42.97 141.2,42.97 141.04,43.13 141.04,43.3 141.41,43.67 141.41,43.84 140.87,44.38 140.87,44.99 140.63,45.23 140.63,46.75 138.51,48.87 138.51,49.16 137.81,49.85 137.65,49.85 137.38,49.59 137.22,49.59 137.05,49.75 137.05,49.92 137.32,50.18 137.32,50.35 137.14,50.52 136.31,50.52 135.79,51.03 135.79,52.56
  BOTTOM w0.076: v2(136.17,53.1) 136.52,53.45 UCPU1.AT27
DDR_B_D50: length 43.8
  TOP w0.127: v2(158.2,29.5) 158.2,29.58 UD22.T9
  IN1 w0.076: 138.15,51.92 138.1,51.98 138.05,51.98 137.62,52.41 137.62,52.51 137.14,52.99 v2(137.14,53.1)
  IN1 w0.117: v2(158.2,29.5) 158.34,29.65 160.63,29.65 161.19,30.21 161.19,31.53 161.59,31.92 161.59,33.8 161.85,34.07 161.85,34.81 159.11,37.55 156.92,37.55 155.88,38.59 152.15,38.59 147.88,42.86 147.88,43.72 146.89,44.71 143.77,44.71 143.15,45.33 143.15,47.31 142.29,48.16 142.29,48.95 141.89,49.36 141.09,49.36 139.82,50.63 139.44,50.63 138.15,51.92
  BOTTOM w0.076: UCPU1.AT25 137.14,53.13 v2(137.14,53.1)
DDR_B_D51: length 42.9
  TOP w0.127: UD22.R9 157.87,29.9 157.55,29.57 v2(157.55,29.5)
  IN1 w0.076: v2(137.11,52.47) 137.15,52.47 137.87,51.75 137.89,51.75 137.94,51.7
  IN1 w0.117: v2(157.55,29.5) 158,29.96 160.5,29.96 160.88,30.34 160.88,31.66 161.28,32.05 161.28,33.93 161.54,34.2 161.54,34.68 158.98,37.25 156.79,37.25 155.75,38.29 151.94,38.29 146.99,43.24 146.99,44.13 146.76,44.36 143.69,44.36 142.84,45.21 142.84,47.18 139.69,50.33 139.32,50.33 137.94,51.7
  BOTTOM w0.076: UCPU1.AU25 v2(137.11,52.47)
DDR_B_D52: length 43.4
  TOP w0.127: UD22.R11 157.87,31.57 v2(158.2,31.9)
  IN1 w0.076: 135.43,52.61 135.43,52.68 135.69,52.94 135.69,53.86 v2(136.2,54.37)
  IN1 w0.117: v2(158.2,31.9) 158.2,32.22 158.05,32.37 158.05,32.86 157.93,32.98 157.81,32.98 157.7,33.1 157.7,33.33 157.81,33.45 157.93,33.45 158.05,33.56 158.05,33.83 157.37,34.51 157.13,34.51 157,34.38 157,33.85 156.88,33.72 156.64,33.72 156.51,33.85 156.51,34.62 156.39,34.75 155.79,34.75 155.66,34.62 155.66,33.8 155.53,33.67 154.52,33.67 154.39,33.8 154.39,34.62 154.27,34.75 152.78,34.75 146.52,41.01 142.67,41.01 140.56,43.11 140.56,44.87 140.31,45.12 140.31,46.64 138.42,48.52 137.34,48.52 136.83,49.03 136.83,49.2 136.92,49.28 136.92,49.45 136.75,49.61 136.59,49.61 136.5,49.53 136.33,49.53 136.17,49.69 136.17,49.86 136.25,49.95 136.25,50.11 136.09,50.28 135.92,50.28 135.84,50.19 135.67,50.19 135.43,50.43 135.43,52.61
  BOTTOM w0.076: UCPU1.AP27 v2(136.2,54.37)
DDR_B_D53: length 41.8
  TOP w0.142: UD22.R10 157.87,30.7 158.2,31.03 v2(158.2,31.1)
  IN1 w0.117: v2(136.2,55.01) 135.78,54.59 135.23,54.59 134.86,54.22 134.86,52.78 135.11,52.52 135.11,50.31 137.21,48.22 138.3,48.22 139.29,47.23 139.29,43.63 139.57,43.35 139.57,42.63 140.2,41.99 141.14,41.99 142.44,40.7 146.39,40.7 153.73,33.36 154.97,33.36 155.15,33.18 155.15,33.02 154.75,32.61 154.75,32.45 154.91,32.28 155.08,32.28 155.48,32.68 155.64,32.68 156,32.33 157.12,32.33 158.2,31.25 v2(158.2,31.1)
  BOTTOM w0.076: UCPU1.AN27 v2(136.2,55.01)
DDR_B_D54: length 47.6
  TOP w0.127: v2(158.17,28.7) 158.17,28.77 157.87,29.08 UD22.R8
  IN1 w0.076: 139.67,52.08 138.76,52.08 138.25,52.59 138.04,52.59 137.67,52.96 137.67,54.09 137.49,54.27 137.49,54.62 137.11,55 v2(137.11,55.01)
  IN1 w0.117: v2(158.17,28.7) 158.62,28.26 160.43,28.26 161.81,29.63 161.81,31.27 162.2,31.67 162.2,33.55 162.47,33.81 162.47,35.06 157.42,40.11 152.07,40.11 150.37,41.82 150.37,42.12 147.17,45.33 146.15,45.33 145.47,46.01 145.47,48.88 144.63,49.72 142.52,49.72 142.24,50 141.75,50 139.67,52.08
  BOTTOM w0.076: UCPU1.AN25 v2(137.11,55.01)
DDR_B_D55: length 45.4
  TOP w0.127: UD22.T8 158.52,28.87 158.68,28.7 v2(158.85,28.7)
  IN1 w0.076: 139.54,51.77 138.76,51.77 138.15,52.38 138.01,52.38 137.51,52.89 137.51,54.02 137.15,54.37 v2(137.11,54.37)
  IN1 w0.117: 139.54,51.77 141.64,49.67 142.01,49.67 142.6,49.08 142.6,48.29 143.45,47.44 143.45,45.46 143.9,45.02 147.04,45.02 150.06,42 150.06,41.59 151.87,39.79 157.31,39.79 162.16,34.93 162.16,33.94 161.89,33.68 161.89,31.8 161.5,31.4 161.5,29.76 160.43,28.69 158.86,28.69 v2(158.85,28.7)
  BOTTOM w0.076: UCPU1.AP25 v2(137.11,54.37)
DDR_B_D56: length 33.9
  TOP w0.142: UD22.M9 156.24,29.58 v2(156.24,29.51)
  IN4 w0.076: v2(156.24,29.51) 156.22,29.53 156.22,29.54 156.21,29.56 156.21,29.56 155.54,30.24 154.74,30.24 154.03,30.94 154.03,31.13 153.48,31.69 153.48,32.39 153.42,32.45 153.42,33.49 153.14,33.77
  IN4 w0.117: 153.14,33.77 153.14,34.73 145.38,42.49 145.38,44.06 145,44.44 143.58,44.44 142.55,45.46 142.55,47.31 141.7,48.16 141.32,48.16 138.44,51.04 138.44,52.55 138.92,53.03 v2(138.92,53.1)
  BOTTOM w0.142: v2(138.92,53.1) 138.92,53.09 139.04,53.09 139.4,53.45 UCPU1.AT22
DDR_B_D57: length 32.3
  TOP w0.142: v2(156.24,30.31) 156.57,29.98 UD22.N9
  IN4 w0.076: v2(156.24,30.31) 156.24,30.31 156.23,30.3 155.98,30.54 154.87,30.54 154.31,31.1 154.31,31.29 153.78,31.81 153.78,32.56 153.68,32.66 153.68,33.6 153.45,33.84 153.45,33.91
  IN4 w0.117: 153.45,33.91 153.45,34.86 145.69,42.62 145.69,44.19 145.13,44.74 143.7,44.74 142.86,45.59 142.86,47.44 141.83,48.46 141.44,48.46 138.82,51.09 138.82,52.36 v2(138.92,52.45)
  BOTTOM w0.076: UCPU1.AU22 139.26,52.8 v2(138.92,52.45)
DDR_B_D58: length 31.2
  TOP w0.076: UD22.M11 155.6,31.82 155.6,32.53
  TOP w0.142: v2(156.08,33.33) 155.6,32.85 155.6,32.53
  IN4 w0.117: v2(156.08,33.33) 156.59,33.84 156.59,34.73 153,38.33 152.11,38.33 149.21,41.22 149.21,41.22 148.78,41.65 148.78,41.65 147.85,42.58 147.85,43.75 146.03,45.58 145.9,45.58 145.47,46.01 145.47,48.78 144.56,49.68 142.5,49.68 142.12,50.06 141.48,50.06 140.36,51.18 140.36,51.42 139.88,51.9 v2(139.88,52.45)
  BOTTOM w0.076: UCPU1.AU21 140.23,52.8 v2(139.88,52.45)
DDR_B_D59: length 31.9
  TOP w0.142: UD22.N11 156.57,31.5 156.57,31.78 156.44,31.91 v2(156.25,31.91)
  IN4 w0.076: 140.76,51.65 140.39,52.02 140.39,52.51 139.88,53.02 v2(139.88,53.1)
  IN4 w0.117: 140.76,51.65 140.76,51.22 141.6,50.37 142.25,50.37 142.63,49.99 144.71,49.99 145.97,48.73 145.97,48.66 146.61,48.02 146.61,45.53 148.25,43.89 148.25,42.62 149.09,41.78 149.09,41.77 149.33,41.53 149.34,41.53 152.24,38.63 153.13,38.63 156.9,34.86 156.9,33.71 156.68,33.5 156.68,32.34 v2(156.25,31.91)
  BOTTOM w0.142: v2(139.88,53.1) 139.96,53.1 UCPU1.AT21
DDR_B_D60: length 37.6
  TOP w0.142: v2(156.25,28.7) 156.25,28.77 UD22.M8
  IN4 w0.076: 152.53,33.61 152.53,33.52 152.88,33.16 152.88,32.3 152.93,32.25 152.93,31.51 153.22,31.23 153.22,29.42 153.53,29.1 155.11,29.1 155.51,28.7 v2(156.25,28.7)
  IN4 w0.117: v2(138.94,55.01) 138.85,55.01 138.15,54.31 137.9,54.31 137.6,54.02 137.6,50.83 138.56,49.87 138.56,48.49 139.67,47.37 140.23,47.37 141.19,46.41 141.19,46.09 141.58,45.7 141.58,45.54 143.04,44.08 143.04,43.96 152.53,34.47 152.53,33.61
  BOTTOM w0.076: UCPU1.AN22 139.22,55.25 v2(138.94,55.01)
DDR_B_D61: length 36.9
  TOP w0.142: UD22.P9 157.22,29.82 v2(156.9,29.5)
  IN4 w0.076: v2(156.9,29.5) 156.9,29.5 156.49,29.1 156.02,29.1 155.19,29.93 154.61,29.93 153.8,30.74 153.8,31.01 153.17,31.63 153.17,32.31 153.15,32.33 153.15,33.3 152.83,33.61 152.83,33.71
  IN4 w0.117: v2(138.94,54.37) 138.44,53.87 138.44,52.88 138.12,52.56 138.12,50.74 138.86,50 138.86,48.61 139.79,47.68 140.41,47.68 140.72,47.99 141.05,47.99 141.19,47.85 141.58,47.85 142.24,47.18 142.24,45.34 143.35,44.23 143.35,44.09 152.83,34.6 152.83,33.71
  BOTTOM w0.076: UCPU1.AP22 v2(138.94,54.37)
DDR_B_D62: length 35.1
  TOP w0.142: v2(156.25,31.1) 156.25,31.09 155.92,30.76 UD22.M10
  IN4 w0.076: 139.95,54.37 140.28,54.03 140.28,52.99 140.74,52.53 140.74,52.18 141.08,51.84
  IN4 w0.117: v2(156.25,31.1) 156.25,31.1 156.71,31.56 157.23,31.56 157.77,32.1 157.77,35.63 153.65,39.76 152.45,39.76 148.56,43.65 148.56,44.01 146.92,45.65 146.92,48.14 146.28,48.79 146.28,48.88 144.86,50.29 142.75,50.29 142.37,50.68 141.74,50.68 141.08,51.33 141.08,51.84 ; 139.95,54.37 v2(139.85,54.37)
  BOTTOM w0.142: UCPU1.AP21 140.27,54.75 139.89,54.37 v2(139.85,54.37)
DDR_B_D63: length 39.7
  TOP w0.142: v2(156.9,30.31) 156.9,30.38 UD22.N10
  IN4 w0.076: 141.5,51.88 141.22,52.16 141.22,54.44 140.95,54.72 140.49,54.72 140.2,55.01 v2(139.85,55.01)
  IN4 w0.117: v2(156.9,30.31) 157.28,29.93 158.95,29.93 160,30.97 160,32.37 158.08,34.28 158.08,35.78 153.79,40.07 152.58,40.07 148.87,43.78 148.87,44.14 147.24,45.76 147.24,48.25 146.58,48.91 146.58,49.03 145.01,50.6 143.18,50.6 141.91,51.88 141.5,51.88
  BOTTOM w0.142: UCPU1.AN21 140.31,55.4 139.91,55.01 v2(139.85,55.01)
DDR_B_DQS0: length 27.1
  TOP w0.076: UD21.G10 137.1,30.8 136.78,31.12 v2(136.78,31.09)
  IN4 w0.114: v2(130.45,45.07) 130.48,45.07 130.68,44.87 131.2,44.87 131.67,44.39 131.67,39.88 132.14,39.41 132.31,39.41 132.54,39.65 132.87,39.65 133.16,39.37 133.16,39.04 132.92,38.8 132.92,38.64 137.77,33.79 137.77,32 136.86,31.09 v2(136.78,31.09)
  BOTTOM w0.076: v2(130.45,45.07) 130.66,44.87 130.79,44.87 130.87,44.95 130.87,45.34 130.75,45.46 130.61,45.46 130.21,45.87 130.21,47.5 130.59,47.88 130.59,48.36 130.14,48.81 130.14,49.3 130.24,49.4 130.24,49.79 130.18,49.9 130.18,49.93 130.18,50.12 130.24,50.23 130.24,50.44 130.2,50.52 130.2,50.8 130.24,50.91 130.33,51.05 130.37,51.1 130.39,51.13 130.42,51.16 130.46,51.21 UCPU1.AY38
DDR_B_DQS1: length 34.2
  TOP w0.076: UD21.P10 141.65,30.7 141.65,30.47 141.7,30.43 141.92,30.43 141.99,30.49 v2(141.99,31.1)
  IN1 w0.114: v2(141.99,31.1) 141.82,30.94 141.82,30.83 142.22,30.44 143.71,30.44 143.91,30.64 144.08,30.64 144.68,31.24 144.68,33.25 142.7,35.23 138.32,35.23 133.06,40.49 133.06,45.57 133.36,45.86 133.71,45.86 v2(133.91,46.06)
  BOTTOM w0.076: v2(133.91,46.06) 133.91,45.93 134.03,45.82 134.24,45.82 134.3,45.88 134.3,47.29 133.54,48.05 133.54,48.26 133.22,48.59 133.22,49.83 133.27,49.94 133.27,49.96 133.27,50.06 133.22,50.19 133.22,50.47 133.25,50.55 133.25,50.77 133.23,50.83 133.18,50.91 133.13,50.93 133.05,50.93 132.99,50.87 UCPU1.BA34
DDR_B_DQS2: length 29.4
  TOP w0.076: v2(134.83,30.3) 135.15,30.63 UD21.D10
  IN1 w0.076: v2(129.87,53.79) 129.87,53.79 129.87,53.8 129.8,53.73 129.8,53.67 129.67,53.54 129.48,53.54 129.31,53.37 129.31,52.88 129.24,52.82 129.24,52.17 129.79,51.61 129.79,51.41 129.78,51.39 129.78,51.37
  IN1 w0.114: v2(134.83,30.3) 134.64,30.49 133.93,30.49 131.91,32.51 131.91,35.67 127.64,39.94 127.64,46.4 127.98,46.74 127.98,48.3 128.53,48.86 128.53,49.51 129.78,50.75 129.78,51.37
  BOTTOM w0.076: UCPU1.AR38 130.13,54 129.87,53.79 v2(129.87,53.79)
DDR_B_DQS3: length 41.3
  TOP w0.076: UD21.L10 139.7,30.77 v2(139.37,31.1)
  IN4 w0.076: 133.83,51.62 133.83,51.64 133.81,51.66 133.81,51.85 134,52.04 134,53.38 133.79,53.6 133.62,53.6 v2(133.45,53.76)
  IN4 w0.114: v2(139.37,31.1) 139.52,30.94 139.52,30.48 140.43,29.57 141.57,29.57 142.24,30.24 144.04,30.24 144.78,30.99 144.78,34.29 141.52,37.55 141.06,37.55 140.39,36.88 140.21,36.88 140.06,37.03 140.06,37.2 140.26,37.4 140.26,37.75 139.99,38.01 139.65,38.01 139.31,37.68 139.15,37.68 138.99,37.84 138.99,38 139.22,38.23 139.22,38.56 138.93,38.84 138.6,38.84 138.38,38.61 138.22,38.61 138.05,38.77 138.05,38.93 138.28,39.16 138.28,39.49 138,39.77 137.67,39.77 137.44,39.55 137.28,39.55 137.12,39.71 137.12,39.87 137.31,40.06 137.31,40.41 137.05,40.67 136.7,40.67 136.51,40.48 136.35,40.48 135.56,41.27 135.56,47.96 135.25,48.28 135.25,49.35 133.83,50.76 133.83,51.62
  BOTTOM w0.076: UCPU1.AR32 133.88,54.11 v2(133.45,53.76)
DDR_B_DQS4: length 32.1
  TOP w0.122: v2(152.35,31.1) 152.37,31.1 152.67,30.8 152.67,30.7 UD22.G10
  IN1 w0.114: v2(136.6,44.87) 136.68,44.87 136.86,45.04 137.11,45.04 137.31,44.84 137.31,41.44 140.08,38.67 145.57,38.67 150.83,33.41 150.83,32.88 151.53,32.17 151.53,31.79 151.9,31.43 152.03,31.43 152.35,31.11 v2(152.35,31.1)
  BOTTOM w0.076: UCPU1.AY30 135.41,51.17 135.31,51.05 135.22,50.91 135.18,50.8 135.18,50.52 135.22,50.44 135.22,50.23 135.16,50.12 135.16,49.9 135.22,49.79 135.22,49.5 135.12,49.4 135.12,48.38 135.78,47.72 135.78,45.46 136.09,45.14 136.32,45.14 v2(136.6,44.87)
DDR_B_DQS5: length 30.9
  TOP w0.122: UD22.D10 150.54,30.52 150.4,30.38 v2(150.4,30.3)
  IN4 w0.076: v2(150.4,30.3) 150.16,30.54 149.53,30.54 149.07,31 149.07,31.15 148.54,31.68 148.54,33.06 148.71,33.23 148.71,33.25 148.71,33.26
  IN4 w0.114: 148.71,33.26 148.82,33.37 148.82,34.65 148.47,35.01 148.47,35.34 148.58,35.45 148.58,35.61 148.41,35.77 148.25,35.77 148.14,35.66 147.81,35.66 147.53,35.94 147.53,36.27 147.64,36.38 147.64,36.54 147.48,36.7 147.32,36.7 147.21,36.6 146.88,36.6 146.6,36.88 146.6,37.21 146.71,37.32 146.71,37.48 146.54,37.64 146.38,37.64 146.27,37.53 145.94,37.53 145.66,37.81 145.66,38.14 145.77,38.25 145.77,38.41 145.61,38.57 145.45,38.57 145.34,38.46 145.01,38.46 144.73,38.75 144.73,39.08 144.84,39.18 144.84,39.35 144.67,39.51 144.51,39.51 144.4,39.4 144.07,39.4 141.07,42.4 141.07,43.27 140.26,44.08 140.01,44.08 v2(139.8,43.87)
  BOTTOM w0.076: v2(139.8,43.87) 139.56,44.12 139.43,44.12 139.15,44.39 139.15,45.56 138.99,45.73 138.99,47.53 138.41,48.11 138.41,49.2 138.2,49.41 138.2,49.82 138.25,49.96 138.25,50.06 138.2,50.19 138.2,50.47 138.23,50.55 138.23,50.77 138.21,50.83 138.16,50.91 138.11,50.93 138.03,50.93 137.96,50.87 137.96,50.66 UCPU1.BA26
DDR_B_DQS6: length 46.1
  TOP w0.076: UD22.P10 157.22,30.7 157.22,30.46 157.3,30.38 157.52,30.38 157.56,30.42 v2(157.56,31.1)
  IN1 w0.076: v2(136.2,53.74) 136.26,53.74 136.58,53.42 136.58,52.18 136.84,51.92 136.99,51.92 137.03,51.88 137.21,51.7 137.28,51.63 137.28,51.5 137.54,51.24 137.54,51.21 137.54,51.21
  IN1 w0.114: 137.54,51.21 139.12,49.63 139.51,49.63 142.22,46.92 142.22,44.43 143.97,42.68 146.47,42.68 151.99,37.16 154.67,37.16 155.7,36.13 157.46,36.13 158.13,35.45 158.46,35.45 159.05,36.04 159.21,36.04 159.37,35.88 159.37,35.72 158.78,35.13 158.78,34.8 159.06,34.52 159.39,34.52 159.98,35.11 160.14,35.11 160.31,34.94 160.31,34.78 159.72,34.2 159.72,33.87 160.01,33.58 160.01,30.97 159.71,30.68 157.53,30.68 157.36,30.85 157.36,30.99 157.47,31.1 v2(157.56,31.1)
  BOTTOM w0.076: UCPU1.AR27 136.53,54 v2(136.2,53.74)
DDR_B_DQS7: length 35.7
  TOP w0.122: v2(155.6,31.1) 155.27,30.78 UD22.L10
  IN4 w0.076: 140.02,50.85 140.01,50.85 139.99,50.85 139.89,50.95 139.89,51.56 139.47,51.99 139.47,53.32 v2(139.88,53.74)
  IN4 w0.114: 140.02,50.85 141.23,49.64 141.92,49.64 142.34,49.22 142.34,48.84 143.49,47.69 143.49,45.89 143.98,45.4 145.47,45.4 146.99,43.88 146.99,42.36 154.09,35.26 155.38,35.26 155.71,34.93 155.71,34.6 155.49,34.38 154.75,34.38 154.63,34.25 154.63,34.05 154.75,33.92 155.4,33.92 155.64,33.67 155.64,33.3 155.4,33.06 154.81,33.06 154.68,32.93 154.68,32.73 154.81,32.6 155.14,32.6 155.37,32.36 155.37,31.33 v2(155.6,31.1)
  BOTTOM w0.122: UCPU1.AR21 140.28,54.1 139.91,53.74 v2(139.88,53.74)
DDR_B_DQS#0: length 27.1
  TOP w0.076: UD21.G11 137.18,31.58 137.18,31.78 137.1,31.86 136.83,31.86 v2(136.78,31.91)
  IN4 w0.114: v2(136.78,31.91) 136.8,31.89 136.8,31.7 136.92,31.59 137.07,31.59 137.57,32.09 137.57,33.7 132.71,38.56 132.71,38.89 132.95,39.12 132.95,39.29 132.79,39.45 132.63,39.45 132.39,39.21 132.06,39.21 131.47,39.8 131.47,44.31 131.12,44.66 130.68,44.66 130.51,44.48 v2(130.48,44.48)
  BOTTOM w0.076: UCPU1.BA38 130.72,50.84 130.72,50.94 130.58,50.99 130.5,50.99 130.44,50.91 130.39,50.83 130.36,50.77 130.36,50.55 130.4,50.47 130.4,50.19 130.35,50.06 130.35,49.96 130.35,49.94 130.4,49.83 130.4,49.33 130.3,49.23 130.3,48.88 130.75,48.43 130.75,47.81 130.37,47.43 130.37,45.94 130.68,45.63 130.82,45.63 131.04,45.41 131.04,44.88 130.85,44.7 130.7,44.7 v2(130.48,44.48)
DDR_B_DQS#1: length 34.3
  TOP w0.076: v2(141.33,31.11) 141.65,31.43 UD21.P11
  IN1 w0.114: v2(141.33,31.11) 141.42,31.11 141.62,30.9 141.62,30.75 142.14,30.23 143.79,30.23 143.99,30.44 144.16,30.44 144.88,31.16 144.88,33.34 142.79,35.43 138.41,35.43 133.26,40.57 133.26,45.48 133.44,45.66 133.72,45.66 v2(133.91,45.47)
  BOTTOM w0.076: v2(133.91,45.47) 134.09,45.65 134.31,45.65 134.47,45.81 134.47,47.36 133.71,48.12 133.71,48.33 133.38,48.65 133.38,49.79 133.44,49.9 133.44,50.12 133.38,50.23 133.38,50.44 133.42,50.52 133.42,50.8 133.37,50.91 133.29,51.05 133.29,51.05 133.16,51.1 133.11,51.1 133.09,51.12 UCPU1.AY34
DDR_B_DQS#2: length 29.3
  TOP w0.122: v2(134.83,31.1) 135.15,31.43 UD21.D11
  IN1 w0.076: 129.98,51.37 129.98,51.39 129.96,51.41 129.96,51.68 129.41,52.24 129.41,52.75 129.47,52.81 129.47,53.3 129.55,53.37 129.67,53.37 129.8,53.25 129.8,53.24 129.87,53.17 v2(129.86,53.17)
  IN1 w0.114: 129.98,51.37 129.98,50.66 128.74,49.42 128.74,48.78 128.18,48.22 128.18,46.65 127.84,46.31 127.84,40.03 132.12,35.75 132.12,32.59 134.02,30.69 134.67,30.69 134.83,30.85 v2(134.83,31.1)
  BOTTOM w0.076: v2(129.86,53.17) 129.98,53.05 130.1,53.05 130.14,53.08 130.21,53.08 130.31,53.18 130.31,53.4 UCPU1.AT38
DDR_B_DQS#3: length 41.4
  TOP w0.076: UD21.L11 139.78,31.58 139.86,31.58 139.88,31.55 139.96,31.55 140.05,31.46 140.05,31.38 140.08,31.35 140.08,31.17 140.01,31.1 v2(140.03,31.1)
  IN4 w0.076: v2(133.4,53.13) 133.4,53.24 133.6,53.44 133.72,53.44 133.84,53.32 133.84,52.1 133.65,51.91 133.65,51.66 133.63,51.64 133.63,51.62
  IN4 w0.114: v2(140.03,31.1) 139.88,31.1 139.73,30.95 139.73,30.57 140.52,29.78 141.48,29.78 142.15,30.45 143.95,30.45 144.58,31.07 144.58,34.21 141.44,37.35 141.14,37.35 140.47,36.68 140.12,36.68 139.86,36.94 139.86,37.29 140.05,37.48 140.05,37.66 139.91,37.81 139.73,37.81 139.4,37.47 139.07,37.47 138.79,37.75 138.79,38.08 139.01,38.31 139.01,38.47 138.85,38.63 138.69,38.63 138.46,38.41 138.13,38.41 137.85,38.69 137.85,39.02 138.08,39.24 138.08,39.41 137.91,39.57 137.75,39.57 137.53,39.34 137.2,39.34 136.92,39.62 136.92,39.95 137.11,40.14 137.11,40.32 136.96,40.47 136.78,40.47 136.59,40.28 136.26,40.28 135.36,41.18 135.36,47.88 135.04,48.19 135.04,49.26 133.63,50.68 133.63,51.62
  BOTTOM w0.076: UCPU1.AT32 134.02,53.35 134.02,53.18 133.92,53.08 133.45,53.08 v2(133.4,53.13)
DDR_B_DQS#4: length 31.9
  TOP w0.122: UD22.G11 152.67,31.58 v2(152.35,31.9)
  IN1 w0.114: v2(152.35,31.9) 152.35,31.78 152.2,31.63 151.98,31.63 151.73,31.88 151.73,32.26 151.03,32.96 151.03,33.5 145.65,38.87 140.16,38.87 137.52,41.52 137.52,44.92 137.19,45.25 136.78,45.25 136.6,45.42 v2(136.6,45.47)
  BOTTOM w0.076: v2(136.6,45.47) 136.44,45.31 136.16,45.31 135.94,45.53 135.94,47.79 135.28,48.45 135.28,49.34 135.38,49.44 135.38,49.83 135.33,49.94 135.33,49.96 135.33,50.06 135.38,50.19 135.38,50.47 135.35,50.55 135.35,50.77 135.37,50.83 135.45,50.95 135.49,51.01 135.49,51.01 135.65,50.98 135.66,50.84 UCPU1.BA30
DDR_B_DQS#5: length 30.9
  TOP w0.122: v2(150.4,31.1) 150.4,31.18 UD22.D11
  IN4 w0.076: v2(150.4,31.1) 150.17,30.88 150.17,30.83 150.04,30.7 149.6,30.7 149.23,31.07 149.23,31.22 148.7,31.75 148.7,32.99 148.79,33.08 148.82,33.11 148.85,33.11 148.86,33.12
  IN4 w0.114: 148.86,33.12 149.02,33.28 149.02,34.74 148.67,35.09 148.67,35.25 148.78,35.36 148.78,35.69 148.5,35.97 148.17,35.97 148.06,35.86 147.9,35.86 147.74,36.03 147.74,36.19 147.85,36.3 147.85,36.63 147.56,36.91 147.23,36.91 147.12,36.8 146.96,36.8 146.8,36.96 146.8,37.12 146.91,37.23 146.91,37.56 146.63,37.84 146.3,37.84 146.19,37.73 146.03,37.73 145.87,37.89 145.87,38.06 145.98,38.17 145.98,38.5 145.69,38.78 145.36,38.78 145.25,38.67 145.09,38.67 144.93,38.83 144.93,38.99 145.04,39.1 145.04,39.43 144.76,39.71 144.43,39.71 144.32,39.6 144.16,39.6 141.28,42.49 141.28,43.35 140.34,44.28 139.98,44.28 v2(139.8,44.46)
  BOTTOM w0.076: v2(139.8,44.46) 139.62,44.28 139.5,44.28 139.32,44.46 139.32,45.63 139.15,45.8 139.15,47.6 138.58,48.18 138.58,49.27 138.36,49.48 138.36,49.79 138.42,49.9 138.42,50.12 138.36,50.23 138.36,50.44 138.4,50.52 138.4,50.8 138.36,50.91 138.27,51.05 138.15,51.1 138.11,51.1 138.06,51.15 138.06,51.3 UCPU1.AY26
DDR_B_DQS#6: length 46.1
  TOP w0.076: UD22.P11 157.22,31.42 v2(156.91,31.11)
  IN1 w0.076: 137.69,51.35 137.68,51.36 137.65,51.36 137.62,51.39 137.45,51.56 137.45,51.7 137.33,51.81 137.15,51.99 137.06,52.09 136.9,52.09 136.74,52.25 136.74,53.57 136.92,53.74 v2(137.11,53.74)
  IN1 w0.114: 137.69,51.35 139.2,49.83 139.59,49.83 142.42,47.01 142.42,44.52 144.05,42.88 146.55,42.88 152.07,37.37 154.75,37.37 155.79,36.33 157.54,36.33 158.21,35.66 158.37,35.66 158.96,36.25 159.29,36.25 159.57,35.96 159.57,35.63 158.99,35.05 158.99,34.88 159.15,34.72 159.31,34.72 159.9,35.31 160.23,35.31 160.51,35.03 160.51,34.7 159.92,34.11 159.92,33.95 160.21,33.66 160.21,30.89 159.8,30.48 157.45,30.48 157.16,30.77 157.16,30.9 156.91,31.15 v2(156.91,31.11)
  BOTTOM w0.076: UCPU1.AR25 137.44,54 v2(137.11,53.74)
DDR_B_DQS#7: length 35.8
  TOP w0.076: v2(154.94,31.1) 155.27,31.43 UD22.L11
  IN4 w0.076: v2(138.97,53.74) 139.25,53.74 139.3,53.69 139.3,51.92 139.73,51.49 139.73,50.88 139.86,50.74 139.86,50.72 139.88,50.7
  IN4 w0.114: v2(154.94,31.1) 155.17,31.33 155.17,32.28 155.05,32.39 154.73,32.39 154.48,32.64 154.48,33.01 154.73,33.26 155.31,33.26 155.44,33.39 155.44,33.59 155.31,33.72 154.67,33.72 154.42,33.96 154.42,34.33 154.67,34.58 155.41,34.58 155.51,34.68 155.51,34.84 155.3,35.06 154,35.06 146.79,42.27 146.79,43.8 145.39,45.2 143.89,45.2 143.28,45.81 143.28,47.61 142.14,48.75 142.14,49.13 141.83,49.44 141.14,49.44 139.88,50.7
  BOTTOM w0.122: v2(138.97,53.74) 138.97,53.74 139.34,54.1 UCPU1.AR22
DDR_B_ODT0: length 80
  TOP w0.076: v2(154.3,28.7) 153.97,29.03 UD22.J8 ; UD21.J8 138.4,28.91 138.07,28.58 v2(138.07,28.58)
  TOP w0.142: v2(147.27,27.36) 147.3,27.34 147.3,26.63 146.41,25.74 146.41,22.15 146,21.74 143.38,21.74 142.72,21.08 RD118.1
  IN1 w0.117: v2(138.07,28.58) 138.56,28.09 140.56,28.09 141.11,27.54 147.09,27.54 v2(147.27,27.36) 147.45,27.54 148.51,27.54 148.74,27.76 148.74,27.9 148.86,28.03 149.08,28.03 149.2,27.9 149.2,27.66 149.32,27.54 149.55,27.54 149.67,27.66 149.67,28.04 149.79,28.15 150.02,28.15 150.14,28.04 150.14,27.66 150.26,27.54 152.1,27.54 152.17,27.47 152.53,27.47 152.58,27.52 153.95,27.52 154.3,27.86 v2(154.3,28.7)
  IN2 w0.102: v2(128.88,47.2) 129.79,47.2 130.06,47.46 130.27,47.46 130.4,47.33 130.4,45.62 129.95,45.16 129.95,41.33 130.22,41.06 130.22,40.92 130.06,40.75 130.06,40.59 130.18,40.47 130.35,40.47 130.79,40.91 130.96,40.91 131.08,40.79 131.08,40.62 130.58,40.13 130.58,39.96 130.7,39.84 130.87,39.84 131.26,40.23 131.43,40.23 131.55,40.11 131.55,39.94 131.4,39.8 131.16,39.55 131.16,39.39 131.28,39.27 131.45,39.27 131.79,39.61 132.03,39.85 132.24,39.85 132.34,39.75 132.34,39.64 131.72,39.02 131.72,38.82 131.83,38.72 132.65,38.72 132.75,38.82 132.75,39.75 132.85,39.85 133.05,39.85 133.16,39.75 133.16,38.82 133.26,38.72 133.46,38.72 133.56,38.82 133.56,39.75 133.66,39.85 133.87,39.85 133.97,39.75 133.97,39.24 134.09,39.12 134.26,39.12 134.37,39.24 134.37,39.75 134.48,39.85 134.93,39.85 135.37,39.41 135.37,38.63 135.96,38.05 142.06,38.05 147.04,33.07 147.04,28.09 147.17,27.96 147.56,27.96 147.68,27.85 147.68,27.54 147.57,27.44 147.35,27.44 v2(147.27,27.36)
  BOTTOM w0.076: v2(128.88,47.2) 128.58,47.51 128.58,48.72 128.86,49 128.86,49.44 128.96,49.54 128.96,49.79 128.84,50.04 128.84,50.04 128.83,50.04 128.69,50.19 UCPU1.BA42
DDR_CHA_EN: length 10.2
  BOTTOM w0.127: RH442.1 160.07,64.98 159.51,65.54 158.78,65.54 RH440.1 158.1,64.87 157.29,64.87 157.2,64.96 v3(156.67,64.96) 156.16,64.96 155.58,64.38 153.95,64.38 153.38,63.8 151.77,63.8 UCPU1.U2
DDR_CHB_EN: length 9.5
  BOTTOM w0.127: UCPU1.U1 153.71,63.5 v3(154.15,63.94) 154.36,64.14 155.75,64.14 156,64.39 156.53,64.39 156.55,64.41 157,64.41 157.19,64.61 157.72,64.61 158.22,64.1 RH441.1 158.73,63.46 160.27,63.46 RH443.1
DDR_VTT_CNTL: length 15.9
  BOTTOM w0.089: 109.83,49.71 109.83,50.25 111.35,51.77 113.64,51.77 UCPU1.AW67
  BOTTOM w0.127: v1(103.73,43.71) 103.73,45.36 103.92,45.55 UC2.2 105.05,45.55 106.91,47.41 109.47,47.41 109.83,47.76 109.83,49.71
DDR_XDP_SMBCLK: length 115.5
  TOP w0.127: JXDP1.53 65.6,74.15 65.71,74.27 65.71,74.6 v2(65.53,74.79) ; v2(157.43,64.17) 157.5,64.17 158.22,63.46 QC2.1 158.22,62.65 RN20.2
  IN1 w0.089: v2(157.43,64.17) 157.64,64.17 158.17,64.7 158.17,66.71 158.34,66.89 158.34,69.09 157.93,69.49 157.93,74.31 155.42,76.82 155.42,77.3 152.26,80.46 88.41,80.46 86.37,78.43 85.36,78.43 83.39,76.46 79.91,76.46 79.65,76.21 70.42,76.21 69.94,75.73 68.81,75.73 68.58,75.5 68.58,74.63 68.05,74.11 66.01,74.11 65.74,74.38 65.74,74.6 65.55,74.79 v2(65.53,74.79)
  BOTTOM w0.127: v2(157.43,64.17) 157.43,63.83 v3(158.37,62.89)
DDR_XDP_SMBDAT: length 110.3
  TOP w0.127: JXDP1.51 66.1,74.12 65.97,74.25 65.97,74.59 v2(66.17,74.79) ; QC2.4 159.52,65.23 159.52,66.33 RN19.2 159.56,66.68 159.35,66.9 v2(159.35,68.2)
  IN1 w0.089: v2(159.35,68.2) 159.35,68.61 158.15,69.81 158.15,74.4 155.68,76.87 155.68,77.35 152.35,80.68 88.32,80.68 86.28,78.65 85.27,78.65 83.3,76.68 79.82,76.68 79.57,76.42 70.33,76.42 69.85,75.94 68.72,75.94 68.36,75.59 68.36,74.72 67.96,74.32 66.1,74.32 65.95,74.47 65.95,74.57 v2(66.17,74.79)
DISPOFF#: length 7.6
  TOP w0.127: D72.1 190.86,27.9 191.75,27.01 192.51,27.01 R540.1 194,27.52 194.74,28.25 v2(194.74,28.76)
  BOTTOM w0.127: JEDP.9 193.46,28.37 193.85,28.76 v2(194.74,28.76)
DMIC_CLK_CODEC: length 14.5
  TOP w0.127: RA58.1 34.14,28.46 35.28,28.46 CA23.2 ; CA23.2 35.46,29.3 v3(35.66,29.51) ; CA23.2 36.4,27.34 v2(36.98,27.34)
  IN1 w0.081: v2(40.64,21.19) 40.64,21.81 39.84,22.6 38.72,22.6 38.12,23.21 38.12,24.04 36.98,25.17 v2(36.98,27.34)
  BOTTOM w0.127: v2(40.64,21.19) 40.94,21.19 41.42,20.71 JKB1.12
DMIC_CLK_CODEC_R: length 2.7
  TOP w0.127: UA2.3 31.08,28.28 31.52,28.72 31.97,28.72 v3(32.11,28.58) 32.43,28.58 32.74,28.28 RA58.2
DMIC_DAT_CODEC: length 18.7
  TOP w0.127: UA2.2 30.71,27.88 31.33,27.88 32.04,27.16 32.82,27.16 CA25.2 32.88,27.55 32.07,27.55 31.7,27.92 v2(31.7,28.18)
  IN3 w0.089: v2(39.93,21.51) 37.15,24.29 34.85,24.29 31.7,27.44 v2(31.7,28.18)
  BOTTOM w0.127: JKB1.11 41.92,20.71 41.01,21.62 40.04,21.62 v2(39.93,21.51)
DPSRC_RBIAS: length 7
  TOP w0.127: v2(43.38,54.32) 43.28,54.22 43.28,53.04 RT2.2 ; v2(43.48,58.24) 43.15,57.92 UT1.N6
  BOTTOM w0.127: v2(43.38,54.32) 43.23,54.32 42.84,54.71 42.84,55.8 43.04,56 43.04,57.8 v2(43.48,58.24)
EC_SLP_S0IX#: length 42.7
  TOP w0.127: UE5.A43 177.11,62.07 176,62.07 v2(175.67,61.74)
  IN3 w0.089: v2(175.67,61.74) 175.37,62.04 174.8,62.04 174.44,61.68 174.44,58.59 174.64,58.39 174.64,57.12 173.42,55.89 171.17,55.89 170.03,57.04 166.6,57.04 166.24,56.67 166.24,52.28 164.35,50.39 158.33,50.39 157.51,49.57 155.18,49.57 v2(154.76,49.16)
  BOTTOM w0.076: UCPU1.AY5 149.47,50.97 149.86,50.58 149.86,50.2 150.03,50.04 150.03,49.6 150.29,49.34 150.68,49.34 150.96,49.05
  BOTTOM w0.127: 150.96,49.05 151.12,48.89 154.5,48.89 v2(154.76,49.16) 155.7,49.16 RC246.2
EDP_AUXN: length 116
  TOP w0.127: C1065.1 196.68,36.01 197.11,36.01 v2(197.25,35.87)
  IN2 w0.076: 125.87,70.36 125.87,70.35 125.84,70.32 125.84,70.15 125.79,70.1 125.79,69.62 125.85,69.57 126,69.57 126.19,69.76 v2(126.19,69.86)
  IN2 w0.102: 125.87,70.36 125.87,70.71 126.63,71.47 127.35,71.47 127.88,72 128.46,72 129.11,72.64 129.11,72.86 129.36,73.12 135.2,73.12 136.04,73.96 136.04,76.46 136.28,76.7 137.88,76.7 138.6,75.98 144.35,75.98 144.5,75.83 152.04,75.83 152.6,75.27 156.74,75.27 158.29,73.72 159.39,73.72 161.47,71.64 164.15,71.64 168.39,75.88 175.45,75.88 177.89,73.45 178.44,73.45 179.05,72.84 180.1,72.84 181.09,71.85 187.92,71.85 190.42,69.35 190.42,68.37 191.31,67.47 191.31,66.16 193.6,63.88 193.6,62.73 193.12,62.25 193.12,60.75 193.5,60.38 193.5,47.42 194.79,46.12 194.79,37.72 196.35,36.15 196.69,36.15 196.82,36.02 196.82,35.77 196.95,35.64 197.13,35.64 197.25,35.77 v2(197.25,35.87)
  BOTTOM w0.127: v2(126.19,69.86) 126.45,69.59 UCPU1.E45
EDP_AUXN_C: length 2.1
  TOP w0.127: L58.1 194.16,36.15 194.29,36.28 194.42,36.28 194.73,35.96 195.08,35.96 C1065.2
EDP_AUXN_CONN: length 2.7
  TOP w0.127: v2(191.38,36.28) 191.5,36.4 191.75,36.4 192,36.15 L58.2
  BOTTOM w0.127: JEDP.25 192.75,36.37 192.24,36.37 192.13,36.48 191.59,36.48 v2(191.38,36.28)
EDP_AUXP: length 116.1
  TOP w0.127: v2(197.25,36.45) 197.06,36.26 196.59,36.26 C1064.1
  IN2 w0.076: 125.65,70.36 125.65,70.35 125.68,70.32 125.68,70.22 125.63,70.16 125.63,69.56 125.78,69.4 125.98,69.4 v2(126.19,69.2)
  IN2 w0.102: v2(197.25,36.45) 197.18,36.38 196.45,36.38 195.02,37.81 195.02,46.22 193.72,47.51 193.72,60.47 193.34,60.85 193.34,62.15 193.83,62.64 193.83,63.97 191.54,66.26 191.54,67.56 190.64,68.46 190.64,69.44 188.01,72.07 181.18,72.07 180.19,73.06 179.15,73.06 178.54,73.67 177.98,73.67 175.54,76.1 168.3,76.1 164.05,71.86 161.56,71.86 159.48,73.94 158.39,73.94 156.84,75.49 152.7,75.49 152.14,76.05 144.59,76.05 144.44,76.2 138.7,76.2 137.98,76.92 136.18,76.92 135.82,76.56 135.82,74.05 135.11,73.34 129.27,73.34 128.88,72.96 128.88,72.73 128.37,72.22 127.79,72.22 127.26,71.69 126.54,71.69 125.65,70.8 125.65,70.36
  BOTTOM w0.127: v2(126.19,69.2) 126.44,68.94 UCPU1.F45
EDP_AUXP_C: length 2.1
  TOP w0.127: C1064.2 195.09,36.22 194.84,36.22 194.52,36.53 194.29,36.53 194.16,36.65 L58.4
EDP_AUXP_CONN: length 2.6
  TOP w0.127: v2(191.36,36.86) 191.41,36.86 191.63,36.65 L58.3
  BOTTOM w0.127: JEDP.26 192.21,36.87 192.07,36.73 191.49,36.73 v2(191.36,36.86)
EDP_BIA_PWM: length 78
  TOP w0.127: v2(178.05,25.41) 178.46,25.82 184.22,25.82 186.07,27.67 186.07,29.29 188.12,31.34 188.76,31.34 D73.2
  IN4 w0.089: v2(178.05,25.41) 177.78,25.14 176.6,25.14 175.98,25.75 175.98,26.82 172.55,30.25 172.55,31.44 172.12,31.87 172.12,36.78 170.87,38.03 170.87,39.97 169.82,41.03 169.82,42.89 169.2,43.5 169.2,44.7 168.27,45.64 167.64,45.64 166.41,46.87 166.41,47.59 165.8,48.2 165.14,48.2 164.47,48.88 164.47,50.34 165.79,51.66 165.79,55.32 161.37,59.74 161.37,62.37 160.33,63.41 158.56,63.41 158.2,63.76 157.09,63.76 156.54,64.31 154.51,64.31 153.55,63.35 146.88,63.35 146.49,63.75 v2(146.49,63.84)
  BOTTOM w0.127: v2(146.49,63.84) 146.14,64.2 UCPU1.R11
EDP_COMP: length 2.2
  TOP w0.127: v2(122.35,69.95) 122.36,69.95 v3(122.94,70.53)
  TOP w0.508: RC2.2 122.28,69.88 v2(122.35,69.95)
  BOTTOM w0.254: v2(122.35,69.95) 122.57,69.74 122.79,69.63 122.9,69.63 UCPU1.E52
EDP_HPD: length 101
  TOP w0.127: RC1.2 v2(147.19,65.85)
  IN4 w0.081: v2(147.19,65.85) 147.6,65.44 149.33,65.44 149.8,64.97 153.34,64.97 154.05,65.68 159.36,65.68 162.3,62.75 162.3,62.04 164.36,59.98 164.36,58.05 166.71,55.7 166.71,51.27 166,50.56 166,49.43 171.49,43.94 171.49,40.99 173.15,39.32 173.15,38.65 173.68,38.13 173.68,35.08 173.59,35 173.59,31.14 174.36,30.37 174.61,30.37 179.49,25.5 179.49,24.34 182.36,21.47 183.83,21.47 184.04,21.25 184.04,20.18 184.48,19.74 191.13,19.74 192.66,21.27 v2(198.32,21.27)
  BOTTOM w0.076: v2(147.19,65.85) 147.19,65.75 UCPU1.L10
  BOTTOM w0.127: v2(198.32,21.27) 198.65,21.6 198.65,23.69 197.64,24.7 197.64,29.25 196.01,30.87 JEDP.14
EDP_TXN_P0: length 116.4
  TOP w0.127: v2(197.43,38.11) 197.43,38.11 197.24,37.91 196.49,37.91 196.32,38.09 C1062.1
  IN2 w0.102: v2(197.43,38.11) 197.43,38.06 197.59,37.91 197.77,37.91 197.87,38.01 197.87,38.46 197.66,38.67 196.48,38.67 195.59,39.57 195.59,46.35 194.2,47.73 194.2,60.64 194.9,61.34 194.9,63.91 195.6,64.62 195.6,66.88 192.46,70.03 192.46,70.9 191.89,71.46 189.37,71.46 187.83,73.01 183.93,73.01 183.4,73.54 179.35,73.54 178.74,74.15 178.18,74.15 175.75,76.58 175.64,76.58 175.61,76.61 170.52,76.61 169.05,78.09 156.07,78.09 155.76,77.78 152.57,77.78 151.8,78.55 131.39,78.55 130.42,77.59 130.42,76.89 128.93,75.4 126.32,75.4 126.07,75.15 125.74,75.15 125.65,75.07 125.65,74.71 125.55,74.61 125.43,74.61 v2(125.25,74.79)
  BOTTOM w0.089: v2(125.25,74.79) 125.57,74.79 125.66,74.7 125.66,72.91 125.46,72.71 125.46,71.47 125.16,71.17 UCPU1.C47
EDP_TXN_P0_C: length 2
  TOP w0.127: C1062.2 195.09,37.99 194.73,37.99 194.56,38.16 194.28,38.16 194.15,38.28 L57.4
EDP_TXN_P0_CONN: length 2.6
  TOP w0.127: L57.3 192.01,38.28 191.95,38.22 191.61,38.22 v2(191.41,38.42)
  BOTTOM w0.127: v2(191.41,38.42) 191.61,38.22 192,38.22 192.16,38.37 JEDP.29
EDP_TXN_P1: length 118.5
  TOP w0.127: C1063.1 196.62,39.79 197,39.79 v2(197.18,39.96)
  IN2 w0.102: v2(127.91,77) 128.02,77 128.3,77.27 128.3,77.42 128.2,77.52 127.62,77.52 127.53,77.61 127.53,77.75 129.6,79.82 152.38,79.82 153.13,79.08 155.22,79.08 155.54,79.4 176.66,79.4 180.12,75.93 184.57,75.93 185.6,74.9 189.38,74.9 190.42,73.85 192.28,73.85 192.99,73.14 192.99,72.37 194.46,70.9 194.46,69.91 197.13,67.24 197.13,61.67 195.46,60 195.46,49.2 197.59,47.07 197.59,45.34 196.98,44.73 196.98,42.75 198.4,41.33 198.4,40.19 197.81,39.6 197.54,39.6 v2(197.18,39.96)
  BOTTOM w0.076: 126.98,75.71 126.96,75.7 126.9,75.7 126.57,75.37 126.57,72.77 126.72,72.62 126.72,72.18 126.69,72.08 126.69,71.89 126.72,71.8 126.72,71.55 126.71,71.5 126.66,71.35 126.63,71.22 126.61,71.18 126.58,71.07 126.58,70.88 126.39,70.69 UCPU1.D46
  BOTTOM w0.127: 126.98,75.71 127.79,76.52 127.79,76.87 v2(127.91,77)
EDP_TXN_P1_C: length 2
  TOP w0.127: L56.4 194.16,39.83 194.29,39.71 195.02,39.71 C1063.2
EDP_TXN_P1_CONN: length 3.1
  TOP w0.127: v2(191.11,39.81) 191.19,39.73 191.86,39.73 191.95,39.83 L56.3
  BOTTOM w0.127: JEDP.32 192.24,39.87 192.07,39.7 191.23,39.7 v2(191.11,39.81)
EDP_TXN_P2: length 114.9
  TOP w0.127: C1066.1 196.32,41.77 196.61,41.48 196.89,41.48 196.99,41.38 197.28,41.38 v2(197.41,41.51)
  IN2 w0.102: v2(197.41,41.51) 197.33,41.59 197.16,41.59 197.08,41.51 197.08,41.36 196.92,41.2 196.74,41.2 196.57,41.37 196.57,47.39 195.06,48.91 195.06,60.23 196.49,61.67 196.49,67.29 193.31,70.47 193.31,71.32 192.58,72.06 192.58,72.72 191.98,73.32 190.28,73.32 189.72,73.87 184.3,73.87 182.65,75.52 178.45,75.52 175.01,78.96 155.73,78.96 155.41,78.64 152.96,78.64 152.2,79.41 130.91,79.41 128.96,77.45 128.96,76.73 128.49,76.26 126.11,76.26 125.88,76.49 125.88,76.74 v2(126.11,76.97)
  BOTTOM w0.076: 125.99,75.78 125.99,75.76 125.95,75.71 125.95,75.48 126.19,75.24 126.19,72.7 125.98,72.49 125.98,71.93 126.01,71.89 126.12,71.89 126.19,71.96 126.23,71.96 126.3,72.03 126.3,72.31 UCPU1.A45
  BOTTOM w0.127: 125.99,75.78 125.99,76.85 v2(126.11,76.97)
EDP_TXN_P2_C: length 2.1
  TOP w0.127: C1066.2 195.09,41.55 194.73,41.55 194.41,41.23 194.29,41.23 194.16,41.35 L59.4
EDP_TXN_P2_CONN: length 2.9
  TOP w0.127: L59.3 192,41.35 191.88,41.23 191.44,41.23 v2(191.24,41.44)
  BOTTOM w0.127: v2(191.24,41.44) 191.42,41.26 192.06,41.26 192.17,41.37 JEDP.35
EDP_TXN_P3: length 120
  TOP w0.127: v2(198.07,43.46) 197.88,43.27 196.48,43.27 196.32,43.44 C1068.1
  IN2 w0.102: v2(125.13,74.21) 125.13,74.11 125.02,74 124.65,74 124.35,74.29 124.28,74.36 124.28,75.4 125.12,76.23 125.12,77.45 128.3,80.63 152.49,80.63 153.31,79.81 154.98,79.81 155.75,80.58 176.39,80.58 180.41,76.56 191.06,76.56 193.7,73.92 193.7,72.58 198.68,67.59 198.68,64.2 201.6,61.29 201.6,57.77 202.44,56.93 202.44,54.86 198.88,51.3 198.88,43.25 198.74,43.1 198.6,43.1 198.49,43.21 198.49,43.75 198.35,43.89 198.07,43.89 197.97,43.79 197.97,43.57 v2(198.07,43.46)
  BOTTOM w0.089: UCPU1.A47 125.16,72.8 125.35,72.98 125.35,73.34 125.48,73.46 125.48,73.86 v2(125.13,74.21)
EDP_TXN_P3_C: length 2.3
  TOP w0.127: C1068.2 195.09,43.33 194.86,43.33 194.58,43.05 194.58,42.92 194.41,42.75 194.29,42.75 194.16,42.88 L60.4
EDP_TXN_P3_CONN: length 3
  TOP w0.127: v2(191.21,42.92) 191.37,42.75 191.76,42.75 191.89,42.88 L60.3
  BOTTOM w0.127: JEDP.38 192.75,42.87 192.15,42.87 192.03,42.75 191.37,42.75 v2(191.21,42.92)
EDP_TXP_P0: length 116.4
  TOP w0.127: C1060.1 196.55,37.66 197.3,37.66 v2(197.43,37.52)
  IN2 w0.102: v2(197.43,37.52) 197.43,37.53 197.59,37.68 197.86,37.68 198.09,37.91 198.09,38.56 197.75,38.9 196.57,38.9 195.81,39.66 195.81,46.44 194.43,47.82 194.43,60.55 195.12,61.25 195.12,63.82 195.83,64.52 195.83,66.98 192.68,70.12 192.68,70.99 191.99,71.69 189.47,71.69 187.92,73.24 184.02,73.24 183.5,73.77 179.44,73.77 178.83,74.38 178.64,74.38 178.64,74.38 178.27,74.38 175.84,76.81 175.73,76.81 175.7,76.84 170.62,76.84 169.14,78.31 155.98,78.31 155.67,78.01 152.66,78.01 151.89,78.77 131.29,78.77 130.2,77.68 130.2,76.98 128.84,75.62 126.22,75.62 125.97,75.37 v2(125.25,75.37)
  BOTTOM w0.089: v2(125.25,75.37) 125.25,75.36 125.84,74.77 125.84,72.84 125.64,72.63 125.64,71.43 UCPU1.C46
EDP_TXP_P0_C: length 2
  TOP w0.127: L57.1 194.15,37.78 194.28,37.91 194.46,37.91 194.62,37.74 195.09,37.74 C1060.2
EDP_TXP_P0_CONN: length 2.5
  TOP w0.127: L57.2 192.06,37.78 191.87,37.97 191.56,37.97 v2(191.43,37.84)
  BOTTOM w0.127: JEDP.28 192.18,37.87 192.09,37.96 191.56,37.96 v2(191.43,37.84)
EDP_TXP_P1: length 118.5
  TOP w0.127: C1061.1 196.65,39.53 197.03,39.53 v2(197.18,39.38)
  IN2 w0.102: v2(127.31,77) 127.31,77.85 129.5,80.04 152.48,80.04 153.22,79.3 155.13,79.3 155.44,79.62 176.75,79.62 180.21,76.16 184.66,76.16 185.7,75.12 189.47,75.12 190.52,74.07 192.37,74.07 193.21,73.23 193.21,72.47 194.69,70.99 194.69,70 197.36,67.33 197.36,61.58 195.69,59.91 195.69,49.29 197.82,47.16 197.82,45.25 197.21,44.64 197.21,42.84 198.62,41.43 198.62,40.1 197.9,39.38 v2(197.18,39.38)
  BOTTOM w0.076: 126.8,75.89 126.78,75.88 126.78,75.81 126.4,75.43 126.4,72.71 126.56,72.55 126.56,72.2 126.52,72.11 126.52,71.86 126.56,71.77 126.56,71.57 126.5,71.41 126.49,71.41 126.4,71.32 126.11,71.32 125.87,71.08 125.87,70.94 125.96,70.85 126.13,70.85 UCPU1.C45
  BOTTOM w0.127: v2(127.31,77) 127.53,76.77 127.53,76.63 126.8,75.89
EDP_TXP_P1_C: length 1.9
  TOP w0.127: L56.1 194.16,39.33 194.29,39.45 195.15,39.45 C1061.2
EDP_TXP_P1_CONN: length 3.2
  TOP w0.127: v2(191.14,39.23) 191.39,39.48 191.86,39.48 192.01,39.33 L56.2
  BOTTOM w0.127: v2(191.14,39.23) 191.35,39.44 192.06,39.44 192.13,39.37 192.75,39.37 JEDP.31
EDP_TXP_P2: length 114.9
  TOP w0.127: v2(197.43,40.93) 197.24,41.13 196.88,41.13 196.79,41.22 196.56,41.22 C1067.1
  IN2 w0.102: v2(125.53,76.95) 125.65,76.82 125.65,76.4 126.02,76.04 128.58,76.04 129.18,76.64 129.18,77.36 131,79.19 152.1,79.19 152.87,78.42 155.5,78.42 155.82,78.74 174.92,78.74 178.36,75.3 182.56,75.3 184.21,73.65 189.63,73.65 190.19,73.09 191.89,73.09 192.35,72.63 192.35,71.97 193.09,71.23 193.09,70.38 196.27,67.2 196.27,61.76 194.83,60.32 194.83,48.82 196.35,47.3 196.35,41.28 196.65,40.98 197.38,40.98 v2(197.43,40.93)
  BOTTOM w0.076: 125.74,75.78 125.74,75.76 125.78,75.71 125.78,75.41 126.02,75.17 126.02,72.76 125.81,72.55 125.81,71.86 125.95,71.73 126.23,71.73 UCPU1.B45
  BOTTOM w0.127: 125.74,75.78 125.74,76.74 v2(125.53,76.95)
EDP_TXP_P2_C: length 2.1
  TOP w0.127: L59.1 194.16,40.85 194.29,40.98 194.52,40.98 194.84,41.3 195.09,41.3 C1067.2
EDP_TXP_P2_CONN: length 2.9
  TOP w0.127: v2(191.26,40.85) 191.39,40.98 191.91,40.98 192.04,40.85 L59.2
  BOTTOM w0.127: v2(191.26,40.85) 191.41,41 192.02,41 192.15,40.87 JEDP.34
EDP_TXP_P3: length 120.1
  TOP w0.127: v2(198.09,42.88) 197.96,43.01 196.57,43.01 C1069.1
  IN2 w0.102: v2(198.09,42.88) 198.83,42.88 199.11,43.16 199.11,51.21 202.67,54.77 202.67,57.02 201.82,57.86 201.82,61.38 198.91,64.3 198.91,67.69 193.92,72.67 193.92,74.02 191.15,76.79 180.5,76.79 176.49,80.8 155.66,80.8 154.89,80.03 153.41,80.03 152.58,80.86 128.21,80.86 124.9,77.55 124.9,76.33 124.06,75.49 124.06,74.27 124.2,74.13 124.55,73.78 124.95,73.78 v2(125.1,73.62)
  BOTTOM w0.089: v2(125.1,73.62) 125.17,73.55 125.17,73.06 124.99,72.87 124.99,72.6 124.87,72.48 124.87,71.96 UCPU1.B47
EDP_TXP_P3_C: length 2.3
  TOP w0.127: L60.1 194.16,42.38 194.29,42.5 194.52,42.5 194.83,42.81 194.83,42.94 194.96,43.07 195.08,43.07 C1069.2
EDP_TXP_P3_CONN: length 2.9
  TOP w0.127: L60.2 191.89,42.38 191.76,42.5 191.38,42.5 191.23,42.35 v2(191.23,42.33)
  BOTTOM w0.127: v2(191.23,42.33) 191.4,42.49 192.09,42.49 192.21,42.37 JEDP.37
EDRAM_OPIO_RCOMP: length 2.8
  TOP w0.127: RC90.1 113.08,68.12 v3(112.38,68.82)
  TOP w0.254: v2(113.95,67.87) 113.85,67.78 RC90.1
  BOTTOM w0.254: v2(113.95,67.87) 114.11,67.7 UCPU1.H66
EMMC_RCOMP: length 5.9
  BOTTOM w0.076: UCPU1.AT1 151.79,53.55 151.99,53.34 152.35,53.34 152.52,53.17 153.57,53.17
  BOTTOM w0.127: 153.57,53.17 154.41,53.17 155.55,54.31 RC4.1 155.6,54.48 v3(156.5,55.38)
EN_0.6V: length 9.6
  TOP w0.127: v3(162.73,34.2) 163.06,34.2 163.69,33.57 163.69,33.13 164.35,32.48 ; 164.35,32.48 166.84,32.48 167.1,32.22 167.53,32.22 167.61,32.15 PU600.2 ; 164.35,32.48 PR611.2 PR609.2 163.96,30.34 PR610.1 PC618.1
EN_1.0V_PRIM_COREP: length 6
  TOP w0.127: PR1512.2 84.29,35.25 83.8,35.75 v1(83.08,35.75)
  TOP w0.254: v2(84.52,32.13) 84.29,32.36 PC1512.1 PR1513.1 PR1512.2
  BOTTOM w0.203: v2(84.52,32.13) 85.08,32.13 85.4,31.8 PU1501.13
EN_1.2V: length 6.5
  TOP w0.127: PC617.1 164.41,33.51 164.41,35.3 v3(163.9,35.82)
  TOP w0.203: PU600.1 167.75,32.6 167.68,32.52 167.26,32.52 166.83,32.95 PR607.2
  TOP w0.254: PR607.2 166.7,32.98 PR608.1 PC617.1
EN_1.8VA: length 4.7
  TOP w0.127: PC800.1 174,78.06 v3(174.9,78.96)
  TOP w0.254: PR801.2 PR800.2 173.1,78.06 PC800.1 173.97,77.12 173.92,77.08 PU800.13
EN_1.8VU: length 4.8
  TOP w0.254: PU900.13 169.22,44.11 169.32,44.2 169.72,44.2 v2(170.1,43.82)
  TOP w0.508: PR901.2 PR900.2 172.26,43.37 171.45,43.37 PC900.1 170.54,43.39 v2(170.1,43.82)
EN_INVPWR: length 71.7
  TOP w0.127: Q71.2 205.27,17.34 R1161.1 205.69,19.34 205.69,20.46 204.27,21.88 203.51,21.88 v2(201.63,23.76) ; v2(182.36,69.43) 182.36,68.72 UE5.A25
  IN4 w0.089: v2(201.63,23.76) 201.17,24.22 198.27,24.22 196.23,26.26 196.23,33.95 194.21,35.97 194.21,46 192.58,47.63 192.58,48.24 193.47,49.13 193.47,49.39 193.18,49.68 192.94,49.68 189.08,53.55 189.08,57.34 188.71,57.7 188.03,57.7 187.01,58.72 187.01,60.37 186.56,60.82 185.53,60.82 185.24,61.1 185.24,61.72 181.09,65.87 181.09,66.34 180.7,66.73 179.45,66.73 179.15,67.04 179.15,67.45 179.45,67.75 180.39,67.75 182.04,69.4 182.34,69.4 v2(182.36,69.43)
EN_INVPWR_R: length 8.6
  TOP w0.127: R535.2 v3(200.58,13.34)
  TOP w0.203: R536.1 201.52,16.29 201.8,16.57 201.8,17.2 201.52,17.48 200.13,17.48 199.87,17.23 199.3,17.23 199.06,16.99 Q70.3
  TOP w0.254: R536.1 200.66,15.27 C613.2 R535.2
EN_PD_HV: length 31.6
  TOP w0.152: v2(29.49,66.96) 28.65,66.13 R1436.2
  IN3 w0.152: v2(29.49,66.96) 30.33,67.8 41.14,67.8 43.92,70.58 49.34,70.58 v2(49.75,70.18)
  IN4 w0.081: v2(49.75,70.18) 50.25,70.18 50.72,69.7 50.72,69.36 51.92,68.16 51.92,66.61 52.77,65.76 v2(52.81,65.76)
  BOTTOM w0.127: PR291.1 53.49,66.44 v2(52.81,65.76)
EN_PRIM_COREP: length 4.9
  TOP w0.254: v2(201.02,77.3) 200.78,77.06 200.78,76.2 PU1401.13
  BOTTOM w0.127: v3(198.06,76.98) 198.43,76.62 PR1412.2
  BOTTOM w0.254: v2(201.02,77.3) 200.89,77.17 PC1412.1 PR1413.1 PR1412.2
EN_VCC_EDRAM: length 4.9
  TOP w0.127: v3(89.63,44.71) PR1501.2
  TOP w0.203: v2(88.37,41.23) 88.57,41.44 PC1500.1 PR1502.1 PR1501.2
  BOTTOM w0.203: PU1500.13 88.56,41.04 v2(88.37,41.23)
EN_VCCIO: length 5
  TOP w0.127: v2(176.51,52.45) PR1401.2 PR1402.1 175.49,53.48 PC1400.1 174.73,53.04 175.22,52.55 PU1400.13
ENLDO_3V5V: length 53.5
  IN1 w0.254: v2(65.89,39.91) 66.43,39.37 68.35,39.37 68.35,39.37 68.76,39.37 68.76,39.37 69.55,39.37 70.08,38.85 76.66,38.85 79.97,35.54 81.64,35.54 82,35.9 89.37,35.9 90.49,34.78 92.05,34.78 92.85,33.99 v2(92.85,33.47)
  IN2 w0.254: v2(94.29,25.23) 93.85,25.66 93.85,28.31 92.85,29.32 v2(92.85,33.47)
  BOTTOM w0.254: PU501.11 64.65,40.66 64.65,40.66 65.38,39.94 PR509.1 PR508.2 66.27,39.53 v2(65.89,39.91) ; v2(94.29,25.23) 94.44,25.08 94.44,22.49 95.15,21.78 95.15,19.78 94.4,19.03 90.85,19.03 PU500.11
ENVDD: length 6.5
  TOP w0.127: D94.1 202.8,44.34 v3(200.51,44.34) 199.51,43.33 UZ24.4
  TOP w0.254: D94.1 203.43,42.58 R1027.2
ENVDD_PCH: length 109.1
  TOP w0.127: UE5.A7 188.6,62.52 189.5,61.62 189.93,61.62 190.33,62.02 191.97,62.02 v2(192.19,62.24) 192.19,62.23 193.34,61.08 193.34,60.14 193.58,59.9 193.58,54.58 v3(192.99,53.99) 190.14,51.14 189.61,51.14 189.3,50.84 189.3,50.43 190.26,49.48 191.04,49.48 192.88,51.32 196.62,51.32 197.45,52.14 198.32,52.14 198.98,51.47 198.98,48.66 202.03,45.61 D94.3
  IN3 w0.089: v2(192.19,62.24) 192.19,62.24 191.7,62.73 191.7,65.61 193.03,66.94 193.03,70.25 191.24,72.04 185.95,72.04 185.62,72.37 185.62,72.77 183.69,74.7 181.22,74.7 180.02,73.5 175.52,73.5 174.96,72.93 174.21,72.93 172.84,71.56 171.98,71.56 171.02,70.6 171.02,69.75 170.6,69.33 169.74,69.33 168.83,70.24 160.53,70.24 159.9,70.87 157.64,70.87 156.74,69.97 156.74,68.51 150.43,62.19 149.37,62.19 148.38,61.2 145.09,61.2 144.88,61.41 144.88,61.83 145.24,62.19 v2(145.24,63.81)
  BOTTOM w0.127: v2(145.24,63.81) 144.84,63.41 UCPU1.U13
EOPIO_RCOMP: length 1.8
  TOP w0.305: RC91.1 115.24,67.59 v2(114.87,67.96)
  BOTTOM w0.254: v2(114.87,67.96) 115.21,67.96 UCPU1.H65
FAN1_PWM: length 99.7
  TOP w0.127: v2(164.43,15.25) 164.43,15.82 164.82,16.21 R1103.1 ; v2(198.18,25.35) 198.6,25.35 v3(199.1,24.84) ; v2(182.96,70.01) 182.86,69.92 182.86,68.72 UE5.A24
  IN3 w0.089: v2(164.43,15.25) 165.2,14.48 165.2,13.91 165.56,13.55 170.97,13.55 172.19,14.77 173.41,14.77 173.62,14.55 176.62,14.55 180.54,18.47 189.08,18.47 192.88,22.27 194.86,22.27 197.94,25.35 v2(198.18,25.35)
  IN4 w0.089: v2(182.96,70.01) 183.69,69.27 183.69,66.13 185.09,64.73 186.59,64.73 187.72,63.6 187.72,60.88 187.87,60.73 187.87,59.97 189.94,57.91 189.94,53.91 191.65,52.2 192.34,52.2 195.44,49.1 195.44,35.96 198.13,33.27 198.13,31.39 196.7,29.96 196.7,26.5 197.85,25.35 v2(198.18,25.35)
  BOTTOM w0.127: v2(164.43,15.25) 164.43,16.1 164.7,16.37 165.62,16.37 JFAN1.3
FAN1_TACH: length 94.8
  TOP w0.127: UE5.B22 184.61,66.99 v2(184.18,66.56) ; D81.2 162.28,15.71 R884.1 162.79,14.53 v2(162.87,14.45)
  IN3 w0.089: v2(162.87,14.45) 162.87,14.87 163.68,15.68 166.1,15.68 167.16,14.63 168.26,14.63 169.05,13.84 170.91,13.84 172.06,14.98 173.5,14.98 173.71,14.77 176.53,14.77 180.45,18.68 185.86,18.68 186.68,19.5 189.61,19.5 195.86,25.76 198.24,25.76 199.47,26.99 199.47,29.09 v2(197.97,30.59)
  IN4 w0.089: v2(197.97,30.59) 197.97,30.57 198.35,30.94 198.35,33.36 195.66,36.05 195.66,49.19 192.06,52.78 191.37,52.78 190.16,54 190.16,58.55 189.42,59.29 189.42,59.67 187.97,61.12 187.97,63.65 186.65,64.97 185.66,64.97 185.33,65.3 185.33,65.83 184.61,66.56 v2(184.18,66.56)
FB_1.8VA: length 3.6
  TOP w0.254: PU800.5 172.42,72.55 172.44,72.53 PR804.1 171.91,71.71 171.88,71.74 PR802.2 PC801.2
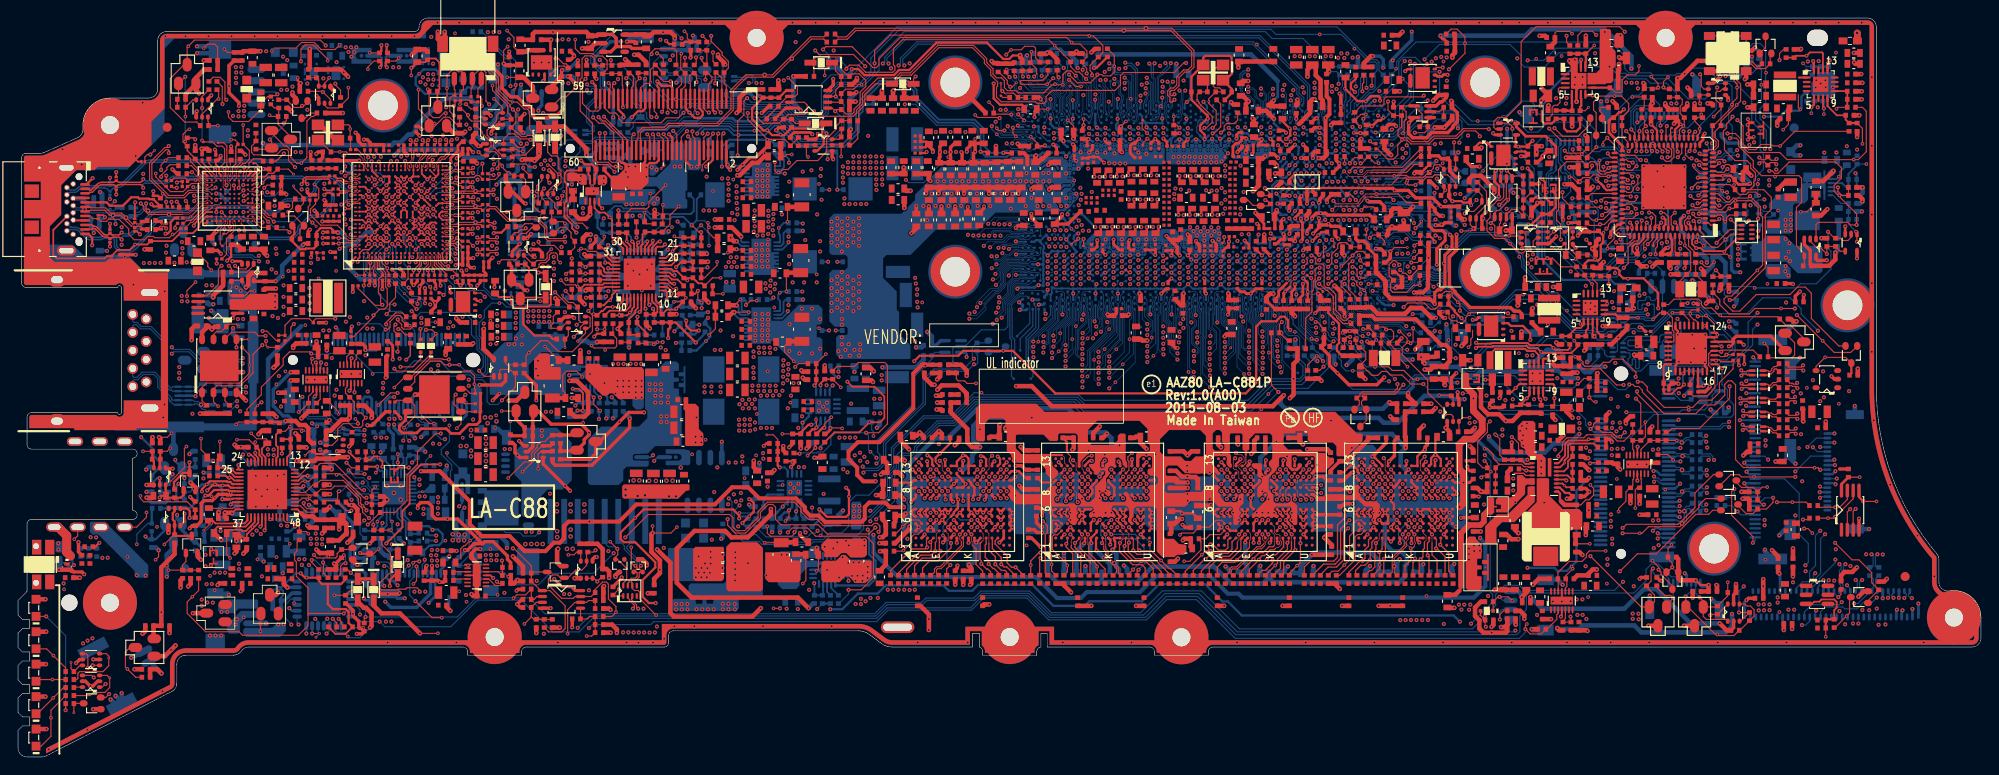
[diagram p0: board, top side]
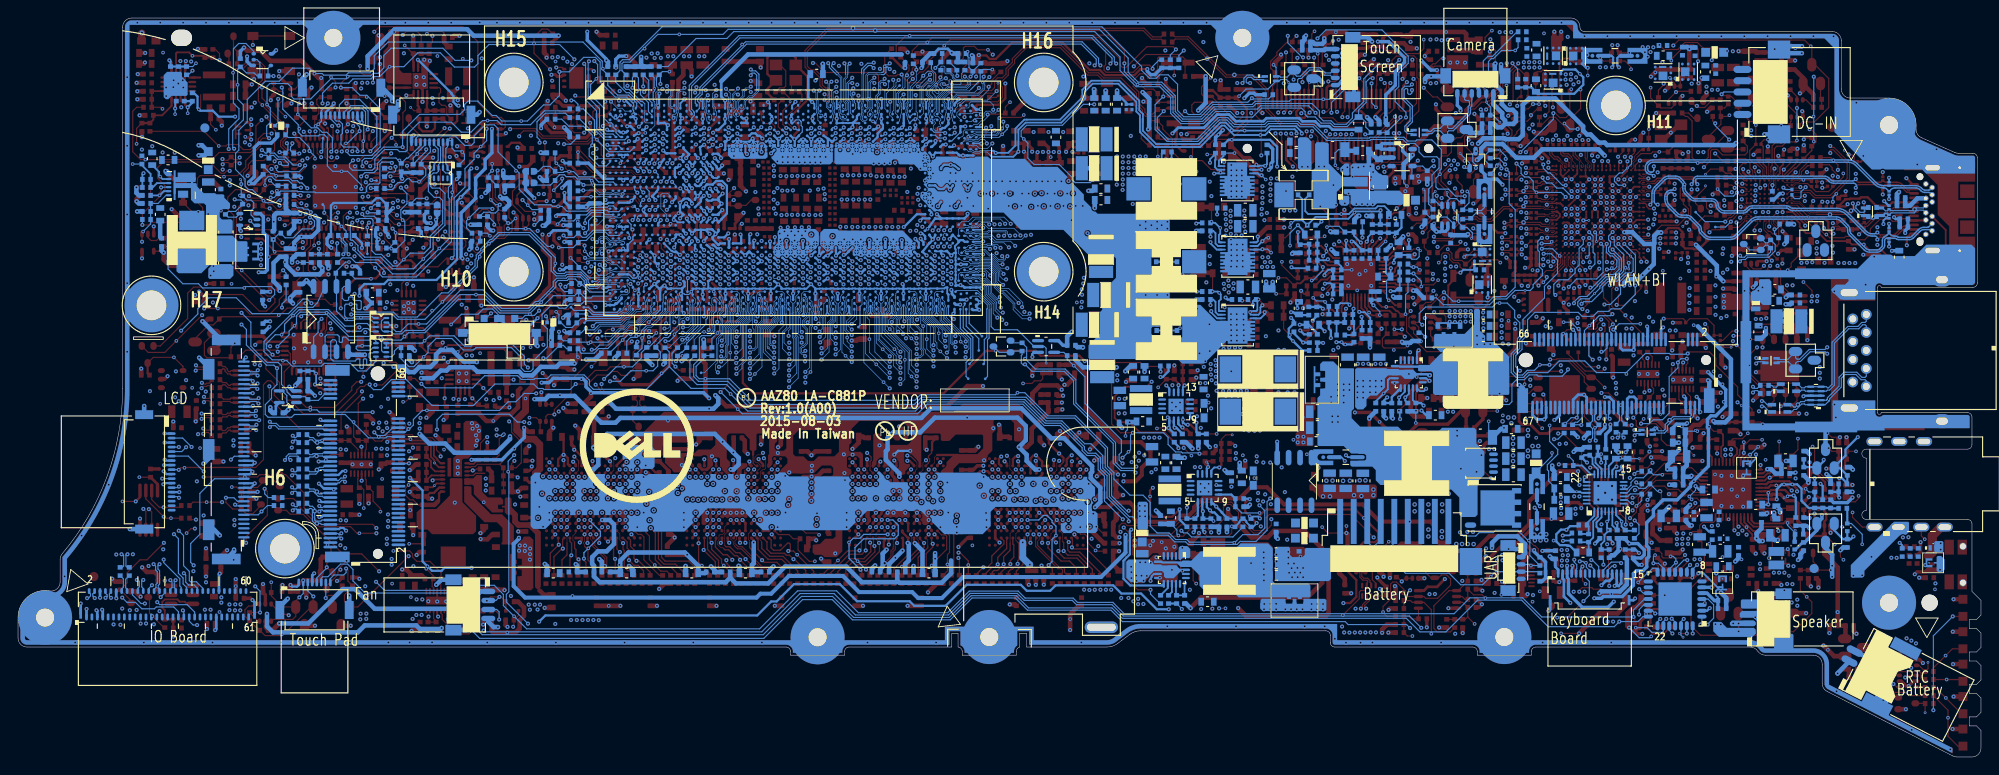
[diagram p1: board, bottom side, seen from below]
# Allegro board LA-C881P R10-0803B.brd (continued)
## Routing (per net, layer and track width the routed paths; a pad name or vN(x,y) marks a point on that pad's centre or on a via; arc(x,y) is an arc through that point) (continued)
FB_1.8VU: length 3.8
  TOP w0.203: PC901.2 166.73,39.12 v2(167.4,39.8) 167.72,40.11 167.72,40.65 PU900.5 ; PC901.2 166.57,38.95 PR904.1 ; PC901.2 PR902.2
FB_IA: length 7.6
  TOP w0.127: PR1096.1 77.06,53.17 v3(77.95,53.17)
  TOP w0.203: PU1000.17 72.5,54.16 72.76,53.91 73.13,53.91 PR1079.2 74.85,53.15 PR1081.2 75.27,52.78 75.49,52.56 75.9,52.56 PR1096.1
FB_VSA: length 7.8
  TOP w0.127: PR1060.1 72.33,59.11 72.33,60.11 v3(73.31,61.09)
  TOP w0.203: PU1000.25 69.16,56.11 69.16,56.77 69.29,56.9 69.29,57.97 PR1077.1 PR1073.1 PR1060.1
FCCM_GT: length 30.9
  TOP w0.203: v2(71.98,50.76) 71.98,51.62 71.84,51.76 PU1000.11
  IN2 w0.203: v2(87.02,51.65) 85.88,51.65 84.63,52.89 84.63,58 85.78,59.14 87.02,59.14 v2(87.08,59.19)
  IN3 w0.203: v2(87.02,51.65) 85.47,51.65 84.02,50.2 81.66,50.2 81.05,49.59 80.57,49.59 80.23,49.93 80.23,50.54 79.83,50.94 74.46,50.94 73.85,50.33 72.73,50.33 72.29,50.76 v2(71.98,50.76)
  BOTTOM w0.203: v2(87.08,59.19) 87,59.27 PR1110.2 ; PR1119.2 v2(87.02,51.65)
FCCM_IA: length 27.1
  TOP w0.203: PU1000.21 70.76,56.46 70.93,56.63 71.53,56.63 v2(71.78,56.88)
  IN4 w0.203: v2(78.11,65.52) 78.11,65.41 78.84,64.68 79.05,64.68 80.44,63.28 80.44,59.54 78.21,57.31 72.21,57.31 v2(71.78,56.88)
  BOTTOM w0.254: PR1103.2 83.49,68.49 v3(83.13,68.49) 78.88,68.49 78.11,67.71 78.11,65.54 78.08,65.52 v2(78.11,65.52)
FCCM_VSA: length 16.3
  TOP w0.203: v2(66.66,57.55) 67.11,57.11 67.11,57.06 67.56,56.6 67.56,56.11 PU1000.29 ; PR1059.2 62.23,65.08 60.96,65.08 60.66,64.78 60.66,63.84 60.87,63.62 60.87,61.72 60.63,61.48 60.63,59.95 61.48,59.1 61.48,58.67 v2(61.95,58.2)
  IN3 w0.203: v2(66.66,57.55) 66.02,58.2 64.29,58.2 64,58.49 62.7,58.49 62.41,58.2 v2(61.95,58.2)
FIVR_EN: length 3.4
  TOP w0.127: RC219.2 74.26,79.75 74.26,80.22 v3(73.95,80.53)
  TOP w0.254: RC218.2 73.99,79.36 RC219.2 75.51,79.36 RC217.1
FIVR_EN_R: length 17.7
  TOP w0.127: v2(75.86,77.58) 75.86,77.26 RC126.2 76.43,76.95 RC132.2 RC217.2 ; v2(67.63,74.75) 67.6,74.72 JXDP1.45
  IN1 w0.081: v2(75.86,77.58) 74.91,76.64 70.24,76.64 69.76,76.15 68.63,76.15 68.13,75.66 68.13,75.26 v2(67.63,74.75)
  BOTTOM w0.127: v3(67.13,72.09) 67.63,72.59 v2(67.63,74.75)
FWP#: length 9.9
  TOP w0.127: v2(185.42,59.88) 185.3,59.88 184.91,59.49 184.91,59.1 185.11,58.9 UE5.B65
  BOTTOM w0.127: v3(189.33,56.05) 189.51,56.22 RE81.2 188.81,58.12 RE82.2 188.65,58.1 188.16,57.62 187.27,57.62 186.28,58.6 185.24,58.6 184.91,58.93 184.91,59.46 185.33,59.88 v2(185.42,59.88)
GPP_B22: length 2.3
  TOP w0.127: RC184.2 149.34,54.7 v2(148.93,55.1) 148.93,55.53 v3(148.77,55.68)
  BOTTOM w0.127: v2(148.93,55.1) 149.22,55.4 UCPU1.AN5
GPP_B23: length 4.4
  TOP w0.127: v3(146.83,54.48) 146.92,54.48 v2(148.08,55.64) 148.55,56.11 149.23,56.11 RC26.1
  BOTTOM w0.076: UCPU1.AM7 148.49,56.05 v2(148.08,55.64)
GPP_C5: length 3.7
  BOTTOM w0.076: UCPU1.W1 153.21,62.17
  BOTTOM w0.127: RC25.1 155.44,62.17 v3(154.23,62.17) 153.21,62.17
GPP_E1: length 1.3
  TOP w0.127: RC51.1 150.31,68.06 v2(150.03,68.33)
  BOTTOM w0.127: v2(150.03,68.33) 150.22,68.14 UCPU1.H3
GT1N: length 25.4
  TOP w0.254: v2(75.54,47.33) 74.65,47.33 74.14,47.84 v2(74.14,48.41)
  IN2 w0.203: v2(90.73,47.33) 90.5,47.1 90.5,46.49 89.94,45.93 85.74,45.93 84.35,47.32 84.35,49.08 83.69,49.74 82.01,49.74 81.07,50.68 79.63,50.68 76.45,47.51 75.72,47.51 v2(75.54,47.33)
  BOTTOM w0.203: PR1135.2 v2(90.73,47.33)
  BOTTOM w0.254: v2(74.14,48.41) 74.14,48.47 73.7,48.92 PR1112.1 ; v2(75.54,47.33) 75.11,46.9 PR1115.1
GT1P: length 23.1
  IN2 w0.203: v2(89.99,47.33) 90.17,47.15 90.17,46.63 89.81,46.26 85.88,46.26 84.68,47.46 84.68,49.22 83.83,50.07 82.14,50.07 81.2,51.01 79.49,51.01 76.32,47.84 75.72,47.84 v2(75.59,47.96)
  BOTTOM w0.203: PR1134.2 v2(89.99,47.33)
  BOTTOM w0.254: PR1118.1 73.64,47.01 74.59,47.96 PR1116.2 v2(75.59,47.96)
GT2N: length 23.2
  IN4 w0.203: v2(90.91,54.95) 90.58,54.62 90.58,54.14 89.92,53.48 81.98,53.48 77.46,48.95 76.78,48.95 v2(76.56,48.73)
  BOTTOM w0.254: v2(76.56,48.73) 76.24,48.41 PR1107.1 76.81,47.53 76.81,46.63 v3(76.34,46.16) 75.29,45.11 PR1120.2 ; PR1133.2 v2(90.91,54.95)
GT2P: length 19.4
  IN4 w0.203: v2(89.89,54.95) 90.25,54.59 90.25,54.27 89.78,53.81 81.84,53.81 77.33,49.3 76.62,49.3 v2(76.56,49.36)
  BOTTOM w0.203: PR1132.2 v2(89.89,54.95)
  BOTTOM w0.254: PR1109.1 75.59,49.03 PR1111.2 76.05,49.11 76.3,49.36 v2(76.56,49.36)
GT_SNUB1: length 4.2
  TOP w0.127: PC1130.1 85.07,45.61 85.07,44.92 v3(86.07,43.91)
  TOP w0.508: PR1114.2 85.57,46.12 PC1130.1
GT_SNUB2: length 3.6
  TOP w0.127: v3(85.26,51.65) PC1125.1
  TOP w0.508: PC1125.1 85.32,53.74 PR1106.2
GT_SW1:
  vias: v2(85.61,48.01) v2(85.57,45.04) v2(86.72,44.79) v2(86.97,49.74) v2(88.11,49.74) v2(88.11,44.79) v2(89,48.6) v2(89,45.3) v3(88.88,47.58)
GT_SW2:
  vias: v2(85.57,55.58) v2(85.57,54.7) v2(85.95,52.66) v2(87.22,52.66) v2(87.35,57.36) v2(88.62,52.66) v2(89,57.24) v2(89,56.09) v3(88.62,53.55)
H_CATERR#: length 7.8
  BOTTOM w0.076: UCPU1.D63 116.6,70.58 116.6,70.69 116.67,70.96 116.67,71.07 116.7,71.18 116.8,71.5 116.81,71.55 116.81,71.8 116.78,71.89 116.78,72.08 116.81,72.18 116.81,72.54 116.66,72.69 116.66,73.06 117.04,73.44 117.04,74.17 116.77,74.45 v1(116.73,74.45) 116.54,74.45 116.02,74.96 116.02,75.9 116.46,76.34
  BOTTOM w0.127: 116.46,76.34 116.46,76.97 RC79.2
H_CPU_SVIDALRT#: length 13.4
  BOTTOM w0.076: RC153.1 115.42,76.58 115.34,76.66 115.07,76.66 114.96,76.55 114.96,75.9 114.88,75.82 114.37,75.82 114.14,75.58 114.14,75.33 113.84,75.03 113.28,75.03 113.18,74.92 113.18,74.7 113.27,74.61 114.13,74.61 114.2,74.68 114.2,75.07 114.29,75.15 114.42,75.15 114.51,75.07 114.51,74.68 114.59,74.61 114.72,74.61 114.82,74.51 114.9,74.51 v3(115.07,74.67) 115.21,74.81 115.37,74.81 115.5,74.68 115.5,74.56 115.19,74.25 115.19,74.14 115.3,74.03 115.41,74.03 115.74,74.37 115.87,74.37 115.96,74.28 115.96,74.15 115.62,73.82 115.62,73.71 115.73,73.6 115.84,73.6 116.16,73.92 116.28,73.92 116.37,73.83 116.37,73.71 116.05,73.39 116.05,73.28 116.05,73.28 116.05,71.99 UCPU1.B63
H_CPUPWRGD: length 8.5
  TOP w0.127: CA35.1 RC77.2 110.48,73.66 109.45,73.66 v2(109.22,73.89) 109.07,74.04 v1(109.07,74.76)
  BOTTOM w0.076: v2(109.22,73.89) 110.23,72.88 112.68,72.88 UCPU1.A68
H_CPUPWRGD_R: length 1.1
  TOP w0.127: RC77.1 109.25,73.19 T9.1
H_PROCHOT#: length 196.5
  TOP w0.127: RC84.1 RC83.2 111.42,75.59 v2(111.51,75.5) ; RE96.2 172.39,60.16 v2(172.09,59.85) ; v2(60.76,51.72) 60.76,51.67 PC1006.2 61.51,51.1 61.51,51.84 PR1124.1
  IN2 w0.089: v2(172.09,59.85) 171.86,60.08 165.91,60.08 v2(165.18,60.82)
  IN3 w0.089: v2(60.76,51.72) 60.76,51.24 59.85,50.33 55.71,50.33 55.22,49.84 53.11,49.84 52.6,49.34 52.6,47.71 51.4,46.51 51.4,45.05 52.28,44.16 52.28,39.26 51.21,38.19 51.21,33.56 48.64,31 46.48,31 45.11,29.63 44.02,29.63 42.72,30.92 39.85,30.92 39.19,30.26 38.66,30.26 38.46,30.06 37.49,30.06 37.01,29.57 v2(37.01,28.53)
  IN4 w0.081: v2(165.18,60.82) 164.08,60.82 162.69,62.2 162.69,62.91 158.97,66.63 154.45,66.63 153.18,65.36 150.15,65.36 149.2,66.3 146.41,66.3 146.2,66.1 146.2,64.98 145.57,64.35 142.09,64.35 142.06,64.32 141.53,64.32 140.84,63.63 128.47,63.63 127.68,64.42 127.68,64.93 126.82,65.78 125.03,65.78 122.4,68.41 122.4,69.33 120.93,70.8 120.5,70.8 119.94,71.36 119.71,71.36 117.58,73.49 113.51,73.49 v2(111.51,75.5) 111.09,75.08 109.76,75.08 108.67,73.99 108.67,73.85 105.95,71.14 105.61,71.14 105.25,70.77 99.67,70.77 98.86,71.58 97.81,71.58 97.45,71.94 92.18,71.94 91.82,72.3 80.08,72.3 79.5,72.88 71.55,72.88 69.24,70.57 69.24,69.1 65.79,65.64 65.79,62.65 64.25,61.11 64.25,58.74 64.57,58.43 64.57,57.49 63.54,56.46 62.87,56.46 62.42,56.02 62.42,53.39 v2(60.76,51.72)
  BOTTOM w0.127: v2(37.01,28.53) 36.73,28.81 PR316.1 ; PR405.2 168.04,58.72 168.04,59.53 v3(167.79,59.77) 166.65,60.92 165.28,60.92 v2(165.18,60.82)
H_PROCHOT#_EC: length 3.7
  TOP w0.127: RE96.1 174.68,59.57 v3(175.13,59.57) 175.21,59.65 175.9,59.65 176.78,60.52 177.16,60.52 UE5.A46
H_PROCHOT#_R: length 10.8
  TOP w0.127: v3(112.45,78.26) 112.45,77.2 RC84.2 113.02,76.34 113.02,75.77 v2(112.75,75.5)
  BOTTOM w0.076: UCPU1.C65 115.25,71.22 115.55,71.52 115.55,73.08 114.53,74.1 112.55,74.1 112.12,74.53 112.12,74.99 112.62,75.5 v2(112.75,75.5)
H_THERMTRIP#: length 80.5
  TOP w0.127: v2(170.49,69.78) 171.4,68.87 173.1,68.87 174.46,70.22 QE9.3 ; RC80.2 115.29,75.59 v2(115.47,75.42)
  IN3 w0.089: v2(170.49,69.78) 169.63,70.63 160.69,70.63 160.06,71.26 157.48,71.26 156.35,70.13 156.35,68.67 155.12,67.45 153.66,67.45 v2(153.62,67.48)
  IN4 w0.081: v2(153.62,67.48) 152.77,68.33 151.97,68.33 151.52,67.89 149.09,67.89 148.59,68.39 148.59,68.79 147.47,69.91 146.28,69.91 145.69,69.33 145.69,67.22 145.42,66.94 141.61,66.94 139.83,65.16 135.07,65.16 133.22,67.01 125.68,67.01 125.3,67.4 125.24,67.4 124.6,68.04 124.18,68.04 123.8,68.42 123.8,70.19 122.39,71.59 121.12,71.59 120.49,72.23 120.49,73.26 119.47,74.28 118.08,74.28 117.65,74.71 116.18,74.71 v2(115.47,75.42)
  BOTTOM w0.076: UCPU1.C63 116.52,71.16 116.52,71.25 116.56,71.32 116.65,71.57 116.65,71.75 116.59,71.94 116.59,72.09 116.65,72.21 116.65,72.47 116.49,72.62 116.49,73.13 116.88,73.51 116.88,73.83 115.47,75.25 v2(115.47,75.42)
H_VCCST_PWRGD: length 37.3
  TOP w0.127: UE5.A44 176.23,61.52 v2(176.2,61.49)
  IN1 w0.081: v2(193.83,67.49) 193.83,65.41 193.6,65.17 192.9,65.17 192.77,65.3 190.62,65.3 190.4,65.07 190.09,64.76 189.53,64.76 189.47,64.69 184.65,64.69 184.07,64.12 182.31,64.12 179.93,61.74 176.45,61.74 v2(176.2,61.49)
  BOTTOM w0.127: U729.2 191.29,77.38 190.98,77.06 190.98,75.58 RE94.2 191.27,75.57 191.61,75.91 192.47,75.91 RE93.1 193.45,76.28 v3(193.45,74.59) 193.45,73 192.81,72.36 192.81,70.7 193.99,69.51 193.99,67.65 v2(193.83,67.49)
H_VCCST_PWRGD_P: length 153.2
  TOP w0.127: v2(72.42,74.96) 71.63,74.96 RC123.1
  IN2 w0.089: v2(179.71,63.04) 179.33,63.04 178.79,63.59 178.36,63.59 177.07,64.87 175.83,64.87 175.58,65.12 174.47,65.12 174.39,65.04 171.76,65.04 171.65,65.15 168.02,65.15 167.79,64.91 166.63,64.91 165.48,66.06 159.39,66.06 158.29,67.16 158.29,68.29 157.93,68.65 156.67,68.65 155.04,67.01 v2(154,67.01)
  IN4 w0.081: v2(154,67.01) 153.37,67.01 153.09,67.29 149,67.29 148.39,66.69 146.25,66.69 145.84,66.28 145.03,66.28 144.8,66.05 144.8,65.72 144.83,65.69 144.83,65.41 144.6,65.19 140.87,65.19 140.03,64.35 139.28,64.35 139.13,64.5 136.5,64.5 136.02,64.02 128.63,64.02 128.06,64.58 128.06,65.09 126.97,66.18 125.27,66.18 124.71,66.73 124.71,67.37 124.44,67.65 123.71,67.65 122.79,68.57 122.79,70.59 122.18,71.21 120.63,71.21 120.1,71.74 120.09,71.74 119.03,72.81 119.03,73.36 118.5,73.89 113.72,73.89 v2(112.12,75.5) 111.56,76.06 111.22,76.06 110.89,76.39 108.62,76.39 106.96,74.73 106.96,73.53 105.55,72.12 105.18,72.12 104.84,71.78 100.32,71.78 98.74,73.36 95.76,73.36 94.93,74.2 87.64,74.2 87.26,73.82 82.77,73.82 82.62,73.97 80.08,73.97 78.01,76.04 73.23,76.04 72.42,75.22 v2(72.42,74.96) ; v2(189.47,75.56) 189.47,75.22 v2(188.54,74.29)
  BOTTOM w0.127: CA32.1 112.29,76.51 112.29,77.61 112.6,77.91 RC71.2 ; CA32.1 111.86,76.11 RC78.1 ; CA32.1 111.86,75.75 v2(112.12,75.5) ; U729.4 190.07,76.42 RE94.1 189.48,75.57 v2(189.47,75.56) ; v2(179.71,63.04) 179.71,63.47 181.24,64.99 v3(181.91,64.99) 182.9,64.99 183.49,65.58 183.49,68.72 183.81,69.04 184.37,69.04 184.49,68.92 186.3,68.92 186.72,69.34 186.72,70.17 188.43,71.89 188.43,74.18 v2(188.54,74.29)
H_VCCST_PWRGD_XDP: length 6
  TOP w0.127: RC124.2 71.6,75.9 RC123.2 70.18,76.26 v1(70.18,74.89) 70.03,74.74 69.57,74.74 69.1,74.26 JXDP1.39
HDA_AUDIO_PD#: length 4.1
  TOP w0.127: v3(32.22,24.77) 31.99,25 RA59.2 31.22,25.69 30.88,26.03 29.69,26.03 29.46,26.26 29.46,26.48 UA2.47
HDA_BIT_CLK: length 6.3
  BOTTOM w0.076: UCPU1.AY22 139.96,50.83 139.85,50.72 139.75,50.61 139.68,50.4 139.68,50.28 139.75,50.05 139.75,49.91 139.69,49.79 139.69,49.53 139.99,49.22 139.99,48.73 139.8,48.54 139.8,48.13 139.98,47.95 139.98,47.27 v3(140.21,47.05) 140.57,46.68
  BOTTOM w0.127: RC93.2 140.82,46.44 140.57,46.68
HDA_BIT_CLK_R: length 137.2
  TOP w0.127: v2(38.66,27.36) 38.66,27.48 38.02,28.12 38.02,28.75 36.08,30.69 33.55,30.69 CA30.2 32.72,30.18 31.88,29.35 31.29,29.35 31.16,29.48 UA2.6
  IN2 w0.089: v2(38.66,27.36) 42.95,27.36 44.04,26.27 50.95,26.27 53.19,24.04 55.09,24.04 56.19,22.95 58.57,22.95 59.33,23.71 61.85,23.71 65,26.86 76.96,26.86 77.75,27.64 79.78,27.64 v2(80.06,27.92)
  BOTTOM w0.127: RC93.1 CC27.1 141.71,44.21 142.57,43.34 142.57,42.32 142.22,41.97 138.86,41.97 136.47,39.58 118.29,39.58 117.68,40.19 107.14,40.19 v3(106.91,40.42) 106.1,40.42 103.53,37.85 100.46,37.85 96.92,34.32 96.92,32.26 96.21,31.55 96.21,30.84 94.43,29.05 92.98,29.05 92.18,28.25 92.18,25.64 91.41,24.86 90.09,24.86 89.36,24.13 88.11,24.13 87.82,23.83 82.75,23.83 81.92,24.67 80.21,24.67 79.47,25.41 79.47,27.33 v2(80.06,27.92)
HDA_SDIN0: length 141.3
  TOP w0.127: v2(38.66,28.77) 38.36,28.77 35.71,31.43 34.19,31.43 RA62.1
  IN2 w0.089: v2(38.66,28.77) 38.7,28.77 39.14,28.33 39.14,28.03 38.89,27.77 38.43,27.77 38.25,27.59 38.25,27.11 38.41,26.96 39.75,26.96 40.09,26.62 42.2,26.62 42.93,25.89 50.32,25.89 52.97,23.24 53.28,23.24 53.85,22.67 55.09,22.67 55.89,21.87 61.09,21.87 65.41,26.18 77.58,26.18 78.49,27.09 79.81,27.09 80.49,27.77 80.49,28.23 v2(80.24,28.48)
  IN4 w0.081: v2(94.56,27.32) 94.36,27.53 94.36,28.07 91.98,30.45 91.74,30.45 91.47,30.72 89.08,30.72 87.11,28.75 81.63,28.75 81.32,29.06 80.97,29.06 80.39,28.48 v2(80.24,28.48)
  BOTTOM w0.127: UCPU1.BA21 140.34,50.48 140.34,49.5 140.65,49.19 140.65,48.04 140.5,47.89 140.5,47.31 140.6,47.21 140.6,47.14 140.98,46.76 141.96,46.76 142.21,46.51 142.21,44.16 142.84,43.53 142.84,42.22 142.29,41.68 139.06,41.68 136.49,39.12 118.35,39.12 117.55,39.92 105.96,39.92 103.64,37.6 100.56,37.6 97.17,34.21 97.17,32.15 96.46,31.44 96.46,28.99 94.8,27.32 v2(94.56,27.32)
HDA_SDIN0_R: length 2.7
  TOP w0.127: UA2.8 31.19,30.28 31.51,30.59 v3(31.85,30.59) 32.28,30.59 32.88,31.2 RA62.2
HDA_SDOUT: length 26
  TOP w0.127: RC187.2 140.84,46.21 RC94.2 139.98,48.01 v2(140.23,48.27) ; RH24.2 157.79,50.25 157.22,49.68 156.75,49.68 156.06,50.38 154.2,50.38 v2(153.75,49.92)
  IN3 w0.089: v2(140.23,48.27) 140.82,48.27 143.69,45.4 145.97,45.4 147.35,46.77 147.35,47.48 148.56,48.69 152.52,48.69 v2(153.75,49.92)
  BOTTOM w0.076: v2(140.23,48.27) 140.18,48.32 140.18,49.31 139.96,49.54 UCPU1.BB22
HDA_SDOUT_R: length 138.8
  TOP w0.127: v2(38.95,26.51) 38.9,26.51 38.23,27.18 38.23,27.55 37.77,28.01 37.77,28.65 36.36,30.06 35.1,30.06 34.75,29.7 33.58,29.7 CA27.2 32.95,29.08 UA2.5 ; RC94.1 139.07,41.28 v2(139.85,40.5)
  IN2 w0.089: v2(80.21,29.3) 80.71,28.8 80.71,27.68 79.9,26.87 78.58,26.87 77.67,25.97 65.5,25.97 61.18,21.65 54.56,21.65 53.19,23.02 52.88,23.02 50.23,25.68 42.84,25.68 42.11,26.4 39.05,26.4 v2(38.95,26.51)
  IN4 w0.081: v2(80.21,29.3) 80.39,29.47 81.5,29.47 81.8,29.17 83.89,29.17 85.86,31.14 91.64,31.14 91.91,30.87 92.15,30.87 95.7,27.32 95.7,26.85 v2(95.23,26.37)
  BOTTOM w0.127: v2(139.85,40.5) v3(137.96,38.6) 137.45,38.09 117.99,38.09 116.93,39.15 106.3,39.15 103.94,36.78 102.2,36.78 99.74,34.32 99.74,34 99.18,33.45 98.33,33.45 97.96,33.08 97.96,31.85 97.26,31.16 97.26,28.41 v2(95.23,26.37)
HDA_SYNC: length 8.4
  BOTTOM w0.076: UCPU1.BA22 139.96,50.55 140.37,50.96 140.7,50.96 140.83,50.84 140.83,50.28 140.68,50.14 140.68,49.46 140.84,49.3 140.84,47.93 140.69,47.78 140.69,47.39 140.79,47.29 140.79,47.25 141.01,47.03 141.37,47.03 141.51,47.17 v3(141.68,47.17) 141.91,47.17 142.72,46.35 RC92.2
HDA_SYNC_R: length 152.8
  TOP w0.127: UA2.10 31.08,31.08 32.09,32.09 CA24.2 33.53,32.57 35.13,32.57 38.09,29.62 v2(38.4,29.62)
  IN4 w0.081: v2(78.87,28.69) 78.56,28.69 75.76,25.89 75.23,25.89 67.17,17.82 63.84,17.82 62.99,16.97 58.95,16.97 55.87,20.06 54.78,20.06 52.88,18.15 51.27,18.15 49.79,16.68 42.98,16.68 41.66,18 41.66,19.37 41.17,19.87 39.85,19.87 39.62,20.1 39.24,20.1 38.59,20.75 38.59,24.32 39.83,25.56 39.83,27.01 39.07,27.77 38.33,27.77 38.15,27.95 38.15,29.37 v2(38.4,29.62)
  BOTTOM w0.127: RC92.1 143.26,44 143.26,42.11 142.47,41.32 139.18,41.32 136.58,38.72 118.35,38.72 117.42,39.66 106.09,39.66 103.73,37.29 101.99,37.29 99.45,34.76 98.76,34.76 97.45,33.45 97.45,32.07 96.72,31.34 96.72,28.88 94.49,26.65 94.12,26.65 93.83,26.36 93.83,25.31 93.13,24.61 90.2,24.61 89.46,23.87 88.25,23.87 87.96,23.58 82.55,23.58 82.2,23.93 80.44,23.93 79.22,25.15 79.22,28.34 v2(78.87,28.69)
HOST_DEBUG_TX: length 12.4
  TOP w0.127: v2(179.74,64.42) 179.74,63.67 179.25,63.18 179.25,62.92 178.97,62.64 178.54,62.64 178.41,62.77 178.01,62.77 UE5.B44
  BOTTOM w0.127: v2(179.74,64.42) 179.32,64.84 178.31,64.84 177.93,65.23 177.93,65.87 177.34,66.46 175.88,66.46 175.29,65.87 174.7,66.46 174.55,66.46 173.15,67.85 JDEG1.8
HOST_SD_WP#: length 81.3
  IN4 w0.081: v2(157.28,59.65) 158.5,58.43 158.5,57.77 159.19,57.08 159.19,52.67 166.69,45.17 166.69,44.65 167.3,44.04 167.3,43.49 166.89,43.08 166.89,39.31 170.05,36.15 170.05,31.18 173.33,27.9 173.33,26.77 175.41,24.68 175.41,21.38 178.33,18.46 186.46,18.46 186.91,18 193.56,18 193.66,18.11 196.78,18.11 197.81,17.07 198.71,17.07 v2(199.52,16.26)
  BOTTOM w0.127: JIO1.37 199.41,16.16 v2(199.52,16.26) ; v3(157.94,59.12) 157.41,59.65 v2(157.28,59.65) 157.11,59.48 156.15,59.48 RC292.2 155.47,60.16 154.73,60.16 154.22,60.66 152.45,60.66 152.3,60.51 151.15,60.51 UCPU1.AB3
HP2_D_L: length 10.9
  TOP w0.203: UA2.32 23.66,29.08
  TOP w0.381: v2(19.04,25.37) 19.34,25.66 RA50.2 19.82,25.66 20.32,26.16 20.32,28.14 20.63,28.44 21.54,28.44 v1(21.85,28.76) 22.24,29.15 23.14,29.15 23.22,29.08 23.66,29.08
  BOTTOM w0.381: RA17.1 19.71,25.61 RA50.2 ; RA50.2 19.34,25.66 v2(19.04,25.37) ; RA50.2 RA48.2
HP2_D_L_C: length 15.1
  TOP w0.127: JHP1.1 13.16,25.51 14.25,26.6 v3(14.25,27.14)
  IN4 w0.381: v2(17.65,26.86) 15.62,26.86 14.28,25.51 JHP1.1
  BOTTOM w0.305: CA29.2 19.79,23.81 20.57,23.03 LA7.2
  BOTTOM w0.381: CA29.2 19.56,23.81 18.21,25.15 DA2.3 17.65,26.45 v2(17.65,26.86)
HP2_D_L_R1: length 2.5
  BOTTOM w0.127: RA17.2 20.63,24.87 21.46,25.71 v3(21.46,25.97)
  BOTTOM w0.381: RA17.2 20.68,24.67 LA7.1
HP2_D_R: length 12
  TOP w0.203: UA2.33 24.61,28.68 23.84,28.68 23.77,28.6 23.35,28.6
  TOP w0.381: 23.35,28.6 v2(22.66,28.6)
  BOTTOM w0.254: RA15.1 16.64,27.59 RA60.1 RA49.2 RA51.2 19.11,27.63 19.91,28.43 19.91,29.76 20.4,30.25 v3(21.85,30.25) 22.11,30.25 22.66,29.7 v2(22.66,28.6)
HP2_D_R_C: length 24.6
  IN1 w0.254: JHP1.2 7.34,36.03 13.97,36.03 14.4,35.59 14.4,34.76 14.86,34.3 14.86,25.18 v2(14.15,24.47)
  BOTTOM w0.254: LA6.2 CA69.1 ; CA69.1 14.45,24.16 v2(14.15,24.47) ; CA69.1 15.29,24.16 16.28,25.15 DA2.2
HP2_D_R_R2: length 5
  BOTTOM w0.127: v3(13.18,23.6) 13.18,24.71 14.38,25.91 LA6.1
  BOTTOM w0.254: RA15.2 14.83,27.54 LA6.1
I2C0_SCK_EDP: length 26.5
  TOP w0.127: R291.2 199.89,27.71 v2(201.65,27.71) 202.12,27.71 202.98,28.56 U48.7 ; v2(192.51,23.76) 192.51,24.46 190.14,26.82 190.14,29.46 v2(190.44,29.76)
  IN1 w0.081: v2(201.65,27.71) 197.76,27.71 195.58,29.89 190.57,29.89 v2(190.44,29.76)
  BOTTOM w0.127: v2(190.44,29.76) 190.44,29.2 190.03,28.79 R287.2 ; JEDP.1 192.75,24.01 v2(192.51,23.76)
I2C0_SCK_EDP_PCH: length 107.6
  TOP w0.127: R291.1 198.4,28.28 v3(196.89,28.28) v2(195.17,28.28)
  IN2 w0.089: v2(164.7,36.34) 164.7,38.29 163.56,39.44 163.56,40.74 164.4,41.58 164.4,47.1 158.76,52.74 158.76,54.59 157.47,55.88 156.66,55.88 156.26,56.28 154.71,56.28 154.48,56.5 152.75,56.5 152.36,56.9 152.36,58.01 151.83,58.54 151.83,60.51 149.72,62.62 v2(149.09,62.62)
  IN3 w0.089: v2(195.17,28.28) 195.17,25.74 189.51,20.08 186.05,20.08 185.08,19.12 180.16,19.12 177.62,16.58 163.42,16.58 162.27,15.43 159.55,15.43 158.7,16.28 158.7,18.4 161.72,21.41 163.85,23.55 163.85,25.91 164.63,26.69 164.63,29.31 165.47,30.14 165.47,34.55 165.19,34.83 165.19,35.85 v2(164.7,36.34)
  BOTTOM w0.127: v2(149.09,62.62) 149.39,62.92 UCPU1.U6
I2C0_SDA_EDP: length 20.6
  TOP w0.127: U48.6 203.63,28.65 v2(201.64,26.66) 201.48,26.5 v3(200.84,26.5) R292.2
  IN1 w0.081: v2(201.64,26.66) 198.3,26.66 197.73,27.24 v2(190.79,27.24)
  BOTTOM w0.127: R288.2 190.13,27.9 v2(190.79,27.24) 191.16,26.87 192.75,26.87 JEDP.6
I2C0_SDA_EDP_PCH: length 107.4
  TOP w0.127: R292.1 198.62,26.34 v2(198.06,26.34)
  IN2 w0.089: v2(148.42,62.64) 148.9,62.16 149.87,62.16 151.61,60.42 151.61,58.45 152.15,57.92 152.15,56.81 152.66,56.29 154.4,56.29 154.62,56.07 156.17,56.07 156.57,55.66 157.38,55.66 158.54,54.5 158.54,52.65 164.18,47.01 164.18,41.67 163.34,40.83 163.34,39.35 164.3,38.39 164.3,36.09 v2(164.7,35.69)
  IN3 w0.089: v2(164.7,35.69) 164.71,35.69 164.93,35.47 164.93,34.7 165.25,34.39 165.25,30.3 164.31,29.37 164.31,26.7 163.62,26.01 163.62,23.64 161.62,21.64 158.46,18.48 158.46,16.18 159.48,15.15 159.48,14.96 159.83,14.61 160.35,14.61 160.95,15.21 162.41,15.21 163.52,16.32 177.72,16.32 180.3,18.9 185.22,18.9 186.11,19.79 189.58,19.79 195.92,26.12 197.85,26.12 v2(198.06,26.34)
  BOTTOM w0.127: v2(164.7,35.69) 164.7,35.69 v3(164.02,35.69) ; UCPU1.U7 148.74,62.96 v2(148.42,62.64)
I2C1_SCK: length 15.4
  TOP w0.127: v2(185.04,17.81) 185.06,17.79 MD10.3 185.29,16.65 188.34,13.6 v3(188.54,13.6) 188.67,13.47 190.4,13.47 R1105.1 191.06,14.06 RH456.2 192.63,15.63 192.63,16.34 192.22,16.75 191.84,16.75 191.62,16.97 QH7.4
  BOTTOM w0.127: JTP1.3 185.66,19.36 185.66,18.43 v2(185.04,17.81)
I2C1_SCK_TP: length 89
  TOP w0.127: QH7.3 191.16,15.07 RH456.1 v2(190.96,16.04)
  IN4 w0.081: v2(191.49,18.93) 191.25,18.69 187.19,18.69 186.74,19.14 182.04,19.14 179.02,22.16 179.02,25.31 174.42,29.9 174.17,29.9 173.1,30.98 173.1,31.55 172.59,32.06 172.59,36.97 171.89,37.67 171.89,39.94 170.28,41.54 170.28,43.09 169.71,43.66 169.71,44.95 165.99,48.67 165.34,48.67 164.93,49.07 164.93,50.15 166.25,51.47 166.25,55.51 163.9,57.86 163.9,59.43 163.51,59.82 162.77,59.82 161.83,60.76 v2(161.83,61.81) 161.83,62.56 160.52,63.87 159.55,63.87 158.57,64.86 157.01,64.86 156.65,65.22 154.24,65.22 153.47,64.45 147.68,64.45 v2(147.1,63.88)
  BOTTOM w0.076: v2(147.1,63.88) 147.1,63.61 147.44,63.28 UCPU1.U9
  BOTTOM w0.127: v2(191.49,18.93) 190.96,18.4 v2(190.96,16.04) ; RC285.2 159.89,60.74 160.77,60.74 v3(161.25,61.23) v2(161.83,61.81)
I2C1_SDA: length 11.8
  TOP w0.127: MD10.2 188.47,16.65 RH461.2 189.71,17.89 R1104.1 v3(189.71,19.39) ; MD10.2 187,15.6 187.33,15.26 189.52,15.26 QH7.1 ; MD10.2 187,17.31 v2(186.59,17.71)
  BOTTOM w0.127: v2(186.59,17.71) 186.16,18.14 JTP1.2
I2C1_SDA_TP: length 83.9
  TOP w0.127: QH7.6 188.58,15.83 RH461.1 187.88,15.83 v2(187.78,15.73)
  IN2 w0.089: v2(179.29,18.95) 180.95,18.95 184.16,15.73 v2(187.78,15.73)
  IN4 w0.081: v2(147.78,61.8) 148.35,61.24 151.36,61.24 152.39,62.26 152.87,62.26 152.96,62.17 156.35,62.17 156.72,61.8 157.81,61.8 158.98,62.98 160.15,62.98 160.93,62.19 160.93,59.42 160.55,59.04 v2(160.53,59.04) 160.54,59.02 160.54,57.59 159.4,56.45 159.4,52.75 165.71,46.44 166.23,46.44 167.46,45.2 167.97,45.2 168.44,44.73 168.44,44.33 167.82,43.72 167.82,43.22 167.49,42.88 167.49,40.68 167.82,40.34 167.82,38.68 170.26,36.24 170.26,31.27 173.54,27.99 173.54,26.86 175.62,24.77 175.62,21.5 177.2,19.92 178.31,19.92 v2(179.29,18.95)
  BOTTOM w0.127: v2(147.78,61.8) 147.78,61.81 147.78,62.77 148.09,63.08 UCPU1.U8 ; v2(160.53,59.04) 160.45,59.04 159.82,59.67 RC284.2
I_ADP: length 206.9
  TOP w0.127: UE5.A12 188.16,65.02 188.16,65.02 188.39,65.02 188.56,64.86 189.27,64.86 189.66,65.25 v2(189.69,65.25)
  IN1 w0.081: v2(189.69,65.25) 189.48,65.25 189.31,65.08 184.45,65.08 183.89,64.51 180.58,64.51 179.42,63.35 179.05,63.35 178.83,63.57 178.09,63.57 176.89,62.37 174.84,62.37 174.44,61.98 174.44,60.99 174.32,60.86 174.32,58.3 175.07,57.55 175.07,55.57 174.5,54.99 174.5,54.62 172.14,52.26 172.14,48.33 169.22,45.41 169.22,44.6 166.68,42.07 166.68,40.89 166.12,40.32 165.81,40.32 165.45,39.96 165.45,37.92 164.29,36.76 164.29,34.09 164.47,33.9 164.47,28.25 155.99,19.77 126.03,19.77 125.46,19.2 118.38,19.2 117.57,20 112.67,20 110.63,22.05 103.1,22.05 102.86,21.8 97.93,21.8 96.25,23.48 96.25,26.51 91.99,30.77 91.58,30.77 90.09,32.26 87.98,32.26 87.63,32.61 84.07,32.61 81.77,30.32 76.8,30.32 73.05,26.56 64.13,26.56 61.3,23.73 59.84,23.73 59.31,23.2 56.07,23.2 55.24,24.02 50.99,24.02 50.45,23.49 50.45,22.59 48.26,20.4 44.39,20.4 43.82,20.98 43.82,22.09 43.01,22.89 41.11,22.89 38.4,25.6 38.4,26.23 v2(38.42,26.25)
  BOTTOM w0.127: v2(38.42,26.25) 37.95,25.78 37.95,24.77 PR315.1
I_BATT: length 185.8
  TOP w0.127: PR318.1 40.36,23.58 41.32,22.62 41.32,20.48 40.12,19.28 40.12,18.74 40.32,18.54 42.11,18.54 42.19,18.62 43.01,18.62 43.16,18.78 44.26,18.78 44.57,18.47 v2(44.57,18.34)
  IN1 w0.081: v2(177.2,53.71) 177.15,53.76 176.38,53.76 173.22,50.59 173.22,46.93 171.69,45.4 171.69,43.75 171.26,43.32 171.26,39.69 168.24,36.67 168.24,34.85 166.87,33.47 166.87,32.32 166.96,32.23 166.96,27.51 166.93,27.48 166.93,27.47 164.33,24.86 164.33,22.6 161.2,19.48 158.52,19.48 156.79,17.75 147.68,17.75 147.31,17.39 133.24,17.39 132.13,18.51 126.59,18.51 125.74,17.65 116.83,17.65 116.28,18.2 112.29,18.2 110.72,19.77 109.88,19.77 109.67,19.97 102.79,19.97 102.4,20.36 96.67,20.36 94.39,22.64 93.57,22.64 92.58,23.62 92.58,24.16 91.76,24.99 90.55,24.99 89.52,26.02 82.69,26.02 81.8,25.13 79.47,25.13 78.78,25.82 75.95,25.82 71.81,21.68 68.26,21.68 67.19,20.61 63.37,20.61 62.61,21.37 54.81,21.37 54.59,21.16 52.1,21.16 50.73,19.79 49.46,19.79 48.17,18.5 45.7,18.5 45.41,18.78 44.94,18.78 44.57,18.42 v2(44.57,18.34)
  BOTTOM w0.127: RE64.2 181.84,55.38 180.86,55.38 180.35,54.87 178.07,54.87 177.2,53.99 v2(177.2,53.71)
ILMT_1.0V: length 3.5
  TOP w0.127: v2(201.93,63.21) 201.93,62.76 202.37,62.32 PR709.1 PR708.2
  BOTTOM w0.127: PU700.3 201.91,63.23 v2(201.93,63.21)
ILMT_DDR: length 3.8
  TOP w0.203: PU600.17 171.54,31.7 171.98,32.14 171.98,32.83 172.49,33.33 PR606.1 PR604.2
IMON_IA: length 3.4
  TOP w0.203: v2(72.8,52.51) 72.77,52.54 72.5,52.54 72.07,52.96 71.51,52.96 PU1000.14
  BOTTOM w0.203: PC1065.2 72.16,52.56 72.75,52.56 v2(72.8,52.51)
  BOTTOM w0.254: PR1071.2 PC1065.2
IMON_VSA: length 3.3
  TOP w0.203: PU1000.23 69.96,56.11 69.96,56.59 70.43,57.07 v2(70.43,57.29)
  BOTTOM w0.203: PC1080.1 PR1069.1 70.46,57.26 v2(70.43,57.29)
IMVP_VR_ON: length 248.2
  TOP w0.127: v2(53.7,39.58) 55.2,41.08 RE100.2 54.99,42.6 54.59,43.01 53.57,43.01 53.45,42.89 UC11.2 ; v2(188.77,59.7) 188.6,59.52 UE5.A1
  IN1 w0.089: v2(188.77,59.7) 186.61,61.86 186.07,61.86 185.83,61.63 182.67,61.63 181.85,60.81 181.85,58.9 180.99,58.04 179.59,58.04 178.6,57.04 178.6,54.89 178.84,54.65 178.84,53.43 178.12,52.7 177.79,52.37 177.04,52.37 176.4,51.72 176.23,51.72 175.76,51.25 175.76,48.99 174.96,48.19 174.96,47.76 172.33,45.13 172.33,43.48 171.92,43.08 171.92,39.45 170.19,37.72 170.19,35.19 172.53,32.85 172.53,21.08 171.65,20.2 162.84,20.2 161.48,18.84 158.81,18.84 157.02,17.05 152.44,17.05 151.07,15.68 134.05,15.68 131.87,17.87 126.86,17.87 125.37,16.37 117.2,16.37 116.02,17.56 112.03,17.56 111.57,18.01 103.05,18.01 101.36,19.7 96.4,19.7 94.1,22 92.49,22 89.99,24.5 88.39,24.5 87.54,25.35 82.92,25.35 82.07,24.5 79.2,24.5 78.66,25.04 76.08,25.04 71.43,20.39 69.35,20.39 66.99,18.03 65.04,18.03 62.41,20.66 55,20.66 53.24,18.91 49.48,18.91 48.31,17.74 47.14,17.74 47.12,17.72 43.71,17.72 43.32,18.11 43.32,19.63 42.3,20.65 42.3,21.5 41.63,22.17 40.94,22.17 40.04,23.07 39.06,23.07 38.58,23.55 38.58,24.23 37.57,25.24 37.57,31.45 39.17,33.05 40.05,33.05 42.13,35.13 42.13,35.56 45.83,39.26 v2(45.83,43.01)
  BOTTOM w0.127: v2(45.83,43.01) 45.83,42.9 46.47,42.25 49.13,42.25 49.27,42.4 50.14,42.4 50.67,41.87 51.53,41.87 52.05,41.36 52.05,39.42 52.36,39.11 53.23,39.11 v2(53.7,39.58)
IMVP_VR_ON_P: length 58.8
  TOP w0.127: PR1029.1 63.6,49.81 v2(63.28,49.49) 63.73,49.04 63.73,47.2 61.51,44.98 59.98,44.98 58.78,46.19 58.01,46.19 v3(56.68,44.86) 56.36,44.54 56.36,43.72 RE101.1 RE100.1 54.27,43.52 54.1,43.69 54.1,44.14 UC11.4 ; v2(86.23,43.29) 86.59,43.65 PR1501.1
  TOP w0.254: v2(82.75,34.52) 83.02,34.79 PR1512.1
  IN1 w0.081: v2(63.28,49.49) 66.02,49.49 71.55,43.95 84.03,43.95 84.6,44.51 85.26,44.51 86.23,43.54 v2(86.23,43.29)
  IN4 w0.081: v2(86.23,43.29) 86.39,43.44 87.35,43.44 87.96,42.83 87.96,37.42 87.04,36.5 87.04,36.38 86.75,36.09 85.17,36.09 83.61,34.52 v2(82.75,34.52)
INA199_OUT: length 52.8
  TOP w0.127: PU201.3 89.85,73.31 90.71,73.31 v2(90.73,73.29) 90.73,74.02 PC204.1 PR227.1 90.71,76.15 90.71,76.67 PD201.1 89.51,76.23 v3(89.51,75.62)
  BOTTOM w0.127: v2(90.73,73.29) 91.64,72.37 91.64,69.65 90.31,68.31 86.9,68.31 84.51,70.69 83.68,70.69 82.92,69.93 79.4,69.93 79.04,70.29 75.9,70.29 75.55,69.94 74.12,69.94 72.6,68.42 67.78,68.42 67.68,68.52 64.13,68.52 63.71,68.09 62.83,68.09 62.36,67.63 62.36,67.15 61.81,66.6 60.39,66.6 60.13,66.35 60.13,65.37 60.91,64.59 60.91,63.39 61.29,63.01 61.29,61.35 60.81,60.87 PR214.1
INTRUDER#: length 14
  TOP w0.127: v2(142.6,54.37) 143.05,54.82 v1(143.05,55.33) ; v2(147.8,46.03) 147.93,45.91 RC69.1
  IN4 w0.081: v2(142.6,54.37) 142.89,54.37 143.08,54.19 143.08,52.93 144.14,51.87 144.56,51.87 144.98,51.45 145.46,51.45 148.26,48.65 148.26,46.49 v2(147.8,46.03)
  BOTTOM w0.076: UCPU1.AP16 v2(142.6,54.37)
INV_PWM_R: length 7.1
  TOP w0.127: v2(193.73,28) 193.55,28 MC3.1 R545.1 ; R545.1 193.54,29.95 v3(194.09,29.95) ; R545.1 192.53,29.9 191.24,29.9 190.66,30.48 D73.1
  BOTTOM w0.127: JEDP.8 193.6,27.87 v2(193.73,28)
IRQ_SERIRQ: length 60.4
  TOP w0.127: UE5.A28 180.86,68.72 180.86,69.29 v2(180.72,69.43)
  IN1 w0.081: v2(180.72,69.43) 180.82,69.33 180.82,68.59 180.49,68.26 178.87,68.26 177.15,66.54 175.83,66.54 175.22,65.94 175.22,65.12 173.35,63.25 173.35,61.63 172.76,61.04 172.76,59.2 171.63,58.07 171.63,54.61 167.29,50.27 167.29,49.25 166.57,48.52 166.57,48.52 166.21,48.16 166.21,47.02 161.84,42.65 161.11,42.65 160.27,43.49 157.2,43.49 155.85,42.15 152.98,42.15 v2(152.78,41.94)
  BOTTOM w0.076: UCPU1.AY11 145.72,50.62 145.72,49.54 146.46,48.8 146.46,46.85 147.08,46.22
  BOTTOM w0.127: v2(152.78,41.94) 151.44,43.29 v3(150.57,43.29) 149.63,43.29 148.64,44.28 148.64,44.87 RC21.2 147.82,45.45 147.08,46.19 147.08,46.22
ISEN1_GT: length 11.3
  TOP w0.203: PC1070.2 70.71,49.13 70.94,49.36 70.94,50 70.36,50.58 PU1000.9 ; PC1070.2 70.59,49.62 v2(70.46,49.74) ; PC1070.2 70.56,49.11 PR1127.1
  IN2 w0.254: v2(73,45.94) 73.44,46.39 73.44,47.9 71.6,49.74 v2(70.46,49.74)
  BOTTOM w0.254: PR1120.1 73.64,45.12 PR1118.2 73.04,45.98 v2(73,45.94)
ISEN2_GT: length 7.7
  TOP w0.127: v3(72.78,50.5) PR1128.1
  TOP w0.203: PU1000.10 70.76,50.66 71.29,50.14 71.29,49.32 PC1133.2 71.98,49.64 72.92,49.64 v2(73.03,49.74) 73.76,50.48 PR1128.1
  BOTTOM w0.254: v2(73.03,49.74) 73.23,49.95 PR1112.2 PR1109.2
ISUMN_GT: length 46.6
  TOP w0.203: PC1070.1 PC1133.1 PC1084.1
  TOP w0.254: v2(75.21,45.98) 72.97,48.22 PC1084.1 72.37,47.68 72.14,47.46 v2(72.14,46.49)
  IN2 w0.254: v2(91.03,42.76) 90.87,42.76 90.72,42.6 88.49,42.6 87.5,41.61 87.5,39.56 86.03,38.08 86.03,37.33 84.09,35.39 79.48,35.39 74.52,40.35 74.52,43.73 72.14,46.12 v2(72.14,46.49)
  BOTTOM w0.203: PR1062.2 71.5,48.19 PC1133.1 ; PC1133.1 PC1084.1 ; PC1133.1 PC1085.2 PC1094.2
  BOTTOM w0.254: v2(91.03,42.76) 91.03,43.37 PH1005.2 ; v2(72.14,46.49) 72.14,47.3 72.37,47.53 PC1084.1 ; PR1115.2 v2(75.21,45.98) 76.24,47.01 PR1107.2
ISUMN_IA: length 31.1
  TOP w0.127: v2(75.79,58.25) 75.54,58.25 v3(74.76,59.03)
  TOP w0.203: PR1085.2 PR1068.2 75.82,58.23 v2(75.79,58.25)
  IN3 w0.203: v2(90.91,62.95) 90.63,62.67 90.63,61.78 89.64,60.79 85.7,60.79 85.37,61.12 81.08,61.12 80.62,60.66 80.62,59.52 79.88,58.78 78.55,58.78 77.63,57.87 76.94,57.87 76.43,58.38 75.92,58.38 v2(75.79,58.25)
  BOTTOM w0.203: PR1078.2 PC1075.2 PC1067.2 75.49,56.9 PC1083.1 75.79,57.11 v2(75.79,58.25) ; PR1131.2 v2(90.91,62.95) 90.91,66.96 PH1009.2
ISUMN_VSA: length 19.5
  TOP w0.203: v2(66.62,60.66) PR1092.2 66.65,60 PR1075.2
  BOTTOM w0.127: v3(76.67,58.79) 76.67,59.03 76.19,59.51 75.25,59.51
  BOTTOM w0.203: PR1075.2 PC1087.1 66.65,60.64 ; PR1075.2 PC1071.2 ; PR1075.2 PR1058.2 ; v2(66.62,60.66) 66.65,60.64 ; 66.65,60.64 66.75,60.54 69.38,60.54 70.2,59.72 72.37,59.72 72.57,59.93 73.84,59.93 PH1006.2 75.31,59.57 75.31,61.91 PR1137.2
ISUMP_GT: length 16.2
  TOP w0.203: PU1000.7 69.56,50.57 69.53,50.54 69.53,49.83 v2(69.62,49.74)
  IN2 w0.254: v2(69.62,49.74) 70.26,49.11 71.48,49.11 72.82,47.76 v2(72.82,47.24)
  IN4 w0.254: v2(72.82,47.24) 74.18,47.24 75.86,48.92 v2(75.86,49.81)
  BOTTOM w0.203: v2(69.62,49.74) 69.7,49.67 PC1094.1 PC1085.1 69.57,48.09 PR1088.1 69.7,46.82 PR1062.1
  BOTTOM w0.254: PR1111.1 75.86,50.31 v2(75.86,49.81) ; v2(72.82,47.24) 73.44,47.86 PR1116.1
ISUMP_IA: length 6.1
  TOP w0.203: PU1000.19 72.2,54.96 v2(72.47,55.23)
  BOTTOM w0.203: 73.64,57.97 PC1067.1 PC1075.1 PR1078.1 ; PR1078.1 73.64,54.36 PR1097.1 ; PR1078.1 72.57,55.13 v2(72.47,55.23)
ISUMP_VSA: length 7.3
  TOP w0.203: PU1000.27 68.36,56.11 68.36,56.99 v2(68.15,57.19)
  BOTTOM w0.203: PC1071.1 68.02,57.69 68.02,57.32 v2(68.15,57.19)
  BOTTOM w0.254: PC1071.1 PC1078.1 PR1058.1 PR1089.1 64.3,58.75 PR1091.2
ITP_PMODE: length 104.2
  TOP w0.127: v2(65.02,71.05) 67.6,68.48 67.6,67.33 JXDP1.46
  IN3 w0.089: v2(146.53,74.68) 146.31,74.91 144.41,74.91 144.07,75.24 143.46,75.24 143.31,75.09 142.93,75.09 142.81,75.21 140.26,75.21 139.66,74.61 139.66,73.2 139.76,73.1 139.76,72.46 138.56,71.26 135.21,71.26 134.77,71.69 129.33,71.69 128.83,71.18 127.81,71.18 127.31,71.69 121.65,71.69 121.05,71.09 117.83,71.09 117.46,71.46 113.91,71.46 113.04,70.59 112.13,70.59 110.52,68.97 106.79,68.97 106.22,68.41 100.66,68.41 99.29,69.77 93.74,69.77 91.7,67.73 83.86,67.73 82.26,69.34 79.08,69.34 78.11,70.31 74.16,70.31 73.39,71.08 71.37,71.08 70.89,71.56 65.53,71.56 v2(65.02,71.05)
  BOTTOM w0.076: UCPU1.E8 147.15,70.07 147.15,71.92 147.05,72.02 147.05,72.44 146.98,72.5 146.98,73.08 147.05,73.14 147.05,73.71 146.79,73.97 146.79,74.29 146.97,74.47
  BOTTOM w0.127: RC115.1 146.53,75.57 v2(146.53,74.68) ; RC115.1 146.66,75.71 146.32,76.05 v3(145.53,76.05) ; RC115.1 146.97,75.39 146.97,74.47
JACK_PLUG: length 14.3
  TOP w0.254: v2(15.72,30.95) QA3.5
  IN2 w0.254: v2(13.67,35.49) 13.26,35.9 9.96,35.9 9.63,35.57 JHP1.6
  BOTTOM w0.254: v2(15.72,30.95) 15.43,30.95 14.88,30.4 RA26.1 14.83,30.36 RA35.1 15.65,32.06 DA1.3 16.28,32.19 15.04,33.44 15.04,34.12 v2(13.67,35.49)
JACK_PLUG_DL: length 12.5
  TOP w0.127: QA3.6 16.79,30.6 16.96,30.6 18.46,32.1 18.46,34.22 v3(18.69,34.45)
  TOP w0.254: QA3.6 16.37,29.69 16.42,29.64 CA74.1 ; CA74.1 15.91,28.98 v2(15.72,28.79) ; CA74.1 16.62,28.77 RA31.1 18.06,28.77 18.38,29.09 QA6.2
  BOTTOM w0.254: v2(15.72,28.79) 15.8,28.86 RA20.1 ; RA38.2 16.66,29.42 RA20.1 ; RA20.1 RA26.2
JACK_PLUG_DL#: length 16.6
  TOP w0.203: v2(29.27,33.68) 29.31,33.71 RA75.1
  TOP w0.254: v2(19.03,32.7) QA6.1 18.32,31.52 17.3,30.49 17.3,29.76 RA31.2
  IN4 w0.254: v2(29.27,33.68) 29.27,34.14 28.66,34.76 24.94,34.76 24.36,34.17 20.5,34.17 v2(19.03,32.7)
JTAG_CLK: length 28.7
  TOP w0.127: UE5.B56 180.61,59.18 180.72,59.29 v2(180.72,59.29)
  BOTTOM w0.127: v2(180.72,59.29) 180.94,59.08 180.94,57.43 180.86,57.34 180.67,57.34 180.09,56.76 180.09,56.21 179.34,55.47 177.58,55.47 176.29,54.17 173.93,54.17 v3(172.84,55.26) 171.75,56.36 171.75,57.7 170.44,59.01 170.44,62.53 171.03,63.13 171.84,63.13 172.01,63.29 172.01,64.52 171.73,64.8 171.35,64.8 171.15,65 RPE7.3 171.15,65.74 170.92,65.97 170.92,67.68 171.15,67.9 JDEG1.4
JTAG_RST#: length 17.8
  TOP w0.127: UE5.B47 178.36,61.27 178.44,61.35 179,61.35 v2(179.5,60.84)
  IN2 w0.089: v2(172.47,61.98) 172.47,61.61 176.08,58 176.19,58 178.19,60.01 178.19,61.01 178.49,61.3 179.04,61.3 v2(179.5,60.84)
  BOTTOM w0.127: JTAG1.1 171.4,61.38 RE65.2 RE66.1 CE59.1 174.22,61.4 173.63,61.98 v2(172.47,61.98)
JTAG_TDI: length 26.5
  TOP w0.127: v2(178.18,54.29) 178.66,54.77 178.66,56.58 179.33,57.24 179.65,57.24 179.86,57.46 UE5.A51
  BOTTOM w0.127: v2(178.18,54.29) 177.69,53.8 177.69,53.59 177.37,53.27 173.63,53.27 169.72,57.18 169.72,62.13 169.63,62.21 v3(169.63,62.67) 169.58,62.72 169.58,64.67 170.16,65.25 RPE7.1 170.16,65.64 170.35,65.83 170.35,67.53 170.15,67.73 JDEG1.2
JTAG_TDO: length 28.2
  TOP w0.127: v2(180.17,59.53) 180.17,59.53 180.2,59.5 180.11,59.42 UE5.B55
  BOTTOM w0.127: JDEG1.5 171.65,68.22 171.65,67.93 171.19,67.48 171.19,66.23 171.65,65.77 RPE7.4 171.65,65.26 172.28,64.64 172.28,62.75 171.63,62.1 171.05,62.1 170.69,61.74 170.69,59.19 172.06,57.82 172.06,56.59 172.75,55.91 174.29,55.91 v3(175,55.2) 175.72,54.48 176.19,54.48 177.49,55.78 178.15,55.78 178.56,56.19 178.56,58.84 178.42,58.98 178.42,59.57 178.6,59.75 179.95,59.75 v2(180.17,59.53)
JTAG_TMS: length 26.4
  TOP w0.127: v2(180.52,56.39) 180.39,56.52 180.39,57.07 180.86,57.54 UE5.A53
  BOTTOM w0.127: v2(180.52,56.39) 180.52,56.24 179.45,55.16 177.81,55.16 176.25,53.6 173.89,53.6 v3(171.07,56.43) 169.97,57.53 169.97,61.99 170.06,62.08 170.06,63.21 169.84,63.43 169.84,64.56 170.08,64.8 170.36,64.8 170.66,65.1 170.66,65.36 ; JDEG1.3 170.66,68.22 170.66,65.36 ; 170.66,65.36 RPE7.2
KB_DET#: length 185.1
  TOP w0.127: v2(154.8,47.59) 154.8,46.17 v3(154.52,45.9)
  IN4 w0.081: v2(45.13,21.89) 45.13,21.64 44.86,21.36 44.86,20.75 45.27,20.34 49.28,20.34 50.38,21.44 53.38,21.44 53.42,21.39 53.93,21.39 54.14,21.61 56.71,21.61 59.22,19.1 61.94,19.1 63.98,21.15 66.1,21.15 69.33,24.37 69.33,25.57 71.65,27.89 74.11,27.89 76.93,30.71 77.79,30.71 78.88,31.81 82.65,31.81 84.47,33.63 85.72,33.63 86.17,34.08 86.17,34.7 86.64,35.17 89.92,35.17 90.72,34.36 95.45,34.36 96.41,33.41 96.41,29.99 97.23,29.17 97.23,25.45 97.32,25.36 97.32,23.17 97.76,22.73 99.59,22.73 101.61,20.71 106.61,20.71 107.12,20.2 123.47,20.2 123.87,19.8 144.65,19.8 145.16,20.3 147.49,20.3 147.89,19.9 160.69,19.9 163.66,22.88 163.66,26.13 162.27,27.53 162.27,28.19 163.94,29.86 163.94,33.5 163.09,34.35 162.39,34.35 160.65,36.09 160.65,37.51 156.92,41.24 156.92,43.7 155.94,44.67 155.94,45.48 155.03,46.4 155.03,47.36 v2(154.8,47.59)
  BOTTOM w0.076: UCPU1.BB7 148.68,49.41 149.15,49.41 149.97,48.59 150.23,48.59 150.82,48 153.3,48 153.46,47.83
  BOTTOM w0.127: v2(45.13,21.89) 45.13,21.61 44.85,21.34 44.85,20.92 44.92,20.85 JKB1.5 ; 153.46,47.83 153.9,47.39 154.6,47.39 v2(154.8,47.59) 155.31,47.08 RC288.2
LAN_WAKE#: length 77.7
  TOP w0.127: RC95.2 147.39,48.47 147.02,48.47 146.77,48.71 146.77,49 146.2,49.57 146.2,51.33 145.44,52.09 145.15,52.09 144.93,52.3 144.93,54.48 144.7,54.71 144.12,54.71 143.99,54.83 143.99,55.33 143.68,55.64 v2(143.51,55.64) ; UE5.B27 182.11,67.87 182.11,67.63 182.47,67.27 v2(182.47,67.19)
  IN1 w0.081: v2(182.47,67.19) 181.95,67.71 181.95,69.72 181.84,69.83 181.84,70.52 181.23,71.13 178.95,71.13 177.68,69.86 177.68,69.01 177.09,68.41 176.63,68.41 176.53,68.31 176.17,68.31 176.07,68.41 176.05,68.41 175.95,68.51 174.73,68.51 173.14,66.92 173.14,65.33 172.53,64.72 171.97,64.72 171.15,63.89 171.15,63.26 171.35,63.06 171.54,63.06 171.77,62.83 171.77,62.5 171.76,62.49 171.76,62.47 168.89,59.6 168.89,57.16 170.08,55.96 170.08,54.99 162.22,47.12 159.51,47.12 158.53,46.15 154.43,46.15 153.78,46.8 153.78,47.3 152.98,48.09 152.57,48.09 149.77,50.9 146.85,50.9 145.69,52.05 145.21,52.05 144.96,52.31 144.96,54.36 144.6,54.72 144.11,54.72 143.97,54.86 143.97,55.13 143.51,55.58 v2(143.51,55.64)
  BOTTOM w0.076: UCPU1.AM15 v2(143.51,55.64)
LCD_TST: length 51.2
  TOP w0.127: 176.48,64.43 176.48,64.42 176.57,64.52 177.16,64.52 UE5.A38 ; 176.48,64.43 175.53,64.43 175.35,64.6 174.78,64.6 174.47,64.3 173.66,64.3 RE58.2 172.95,63.84 172.44,64.35 v3(172.14,64.35) ; 176.48,64.43 v2(176.48,64.43)
  IN4 w0.081: v2(194.19,33) 194.11,33 193.08,34.03 193.08,38.41 191.24,40.24 190.24,40.24 189.52,40.97 189.52,43.25 190.31,44.04 190.31,46.73 188.01,49.03 188.01,52.06 186.14,53.94 186.14,55.34 186.72,55.92 186.72,57.18 186.19,57.71 180.71,57.71 179.25,59.18 179.25,59.42 179.01,59.65 178.6,59.65 177.97,60.28 177.97,62.33 177.06,63.24 177.06,63.85 v2(176.48,64.43)
  BOTTOM w0.127: JEDP.19 193.81,33.37 v2(194.19,33)
LCD_VCC_TEST_EN: length 56
  TOP w0.127: v2(176.2,63.92) 177.06,63.92 UE5.A39 ; D94.2 203.36,44.89 201.52,44.89 v3(200.24,46.17) v2(197.38,49.03)
  IN1 w0.081: v2(197.38,49.03) 197.55,49.2 197.55,49.97 194.47,53.05 194.47,62.73 195.8,64.06 195.8,67.41 193.48,69.73 191.52,69.73 191.13,70.12 184.49,70.12 183.74,69.38 183.74,66.39 183.3,65.94 182.76,65.94 182.63,66.07 182.17,66.07 181.43,66.81 179.11,66.81 177.17,64.87 177.17,64.55 176.53,63.92 v2(176.2,63.92)
LDO_EN: length 17.2
  TOP w0.508: v2(63.07,66.8) 63.07,67.5 60.6,69.97 PD205.1 59.52,69.9 PD204.1
  BOTTOM w0.127: v3(63.69,63.35) 64.06,63.71 PR240.2
  BOTTOM w0.381: v2(63.07,66.8) 63.72,66.8 64.18,67.26 64.18,67.76 64.49,68.07 66.42,68.07 PC209.1 66.51,67.45 PU202.1
  BOTTOM w0.508: PR240.2 64.06,65.81 v2(63.07,66.8)
LID_CL_SIO#: length 6.3
  TOP w0.127: UE5.A21 184.36,68.72 184.36,69.59 v3(184.79,70.02) 184.89,70.11 CE13.1 184.43,71.41 184.43,72.2 184.66,72.42 184.66,72.96 184.4,73.21 RE25.2 RE26.2
LID_SW_IN#: length 67.9
  TOP w0.127: v3(183.08,75.45) 182.58,74.94 v2(182.58,74.3) 182.75,74.13 RE26.1
  IN4 w0.089: v2(182.58,74.3) 182.32,74.05 182.32,72.35 184.19,70.48 184.19,69.09 184.73,68.54 184.73,66.73 185.55,65.92 185.55,65.39 185.74,65.2 186.73,65.2 188.19,63.74 188.19,61.21 189.64,59.76 189.64,59.38 191.26,57.76 191.26,54.2 191.95,53.51 191.95,53.2 195.87,49.28 195.87,36.14 198.65,33.36 198.65,25.76 199.31,25.1 v2(199.97,25.1)
  BOTTOM w0.127: v2(199.97,25.1) 199.44,24.57 199.44,21.23 198.8,20.59 198.8,19.57 198.67,19.44 198.02,19.44 197.31,18.73 JIO1.44
LINE1-VREFO_L: length 7.4
  TOP w0.127: UA2.31 24.61,29.48
  TOP w0.203: 24.61,29.48 24.06,29.48 24.04,29.49 24.01,29.49
  TOP w0.254: 24.01,29.49 23.44,29.49 23.31,29.62 21.74,29.62 21.13,29.02 v2(20.79,29.02)
  BOTTOM w0.127: v2(20.79,29.02) 21.37,29.02 v3(21.46,28.93)
  BOTTOM w0.254: RA48.1 20.55,28.77 v2(20.79,29.02)
LINE1-VREFO_R: length 9.4
  TOP w0.203: UA2.30 23.91,29.88
  TOP w0.254: v2(21,29.57) 21.56,30.13 v3(22.71,30.13) 23.34,30.13 23.6,29.88 23.91,29.88
  IN1 w0.254: v2(17.81,30.31) 18.54,30.31 18.9,29.96 20.78,29.96 21,29.74 v2(21,29.57)
  BOTTOM w0.254: v2(17.81,30.31) 17.56,30.07 RA49.1
LINE1_L: length 12.9
  TOP w0.203: UA2.22 26.26,33.13 25.86,33.54 v2(25.63,33.54)
  TOP w0.381: v2(19.1,28.85) 19.6,28.36 CA70.1
  IN4 w0.254: v2(25.63,33.54) 25.63,33.43 25.25,33.05 23.47,33.05 22.76,32.34 20.63,32.34 19.77,31.48 19.77,29.51 v2(19.1,28.85)
  BOTTOM w0.127: v2(25.63,33.54) 25.61,33.54 v3(24.73,34.42)
LINE1_L_C: length 7.7
  TOP w0.127: v3(13.58,28.97) 13.58,28.7 13.96,28.31 18.78,28.31 19.65,27.44 CA70.2
  TOP w0.254: RA50.1 CA70.2
LINE1_R: length 12.3
  TOP w0.203: v2(26.31,33.74) 26.31,33.54 26.66,33.19 UA2.21
  IN4 w0.254: v2(18.45,30.95) 21.15,33.64 24.36,33.64 24.84,34.12 25.93,34.12 v2(26.31,33.74)
  BOTTOM w0.127: v2(26.31,33.74) v3(26.31,34.94)
  BOTTOM w0.254: CA71.1 v2(18.45,30.95)
LINE1_R_C: length 2
  BOTTOM w0.127: v3(19.45,29.76) 19.1,29.41 CA71.2
  BOTTOM w0.254: RA51.1 CA71.2
LPC_AD0: length 51.9
  TOP w0.127: v2(179.91,69.45) 179.86,69.41 179.86,68.72 UE5.A30
  IN3 w0.089: v2(144.74,48.89) 146.52,50.67 150.27,50.67 152.28,52.68 154.5,52.68 157.72,55.9 158.82,55.9 162.77,59.85 164.94,59.85 168.08,62.99 169.24,62.99 171,64.75 172.34,64.75 172.8,65.22 172.8,65.95 175.13,68.28 176.66,68.28 178.52,70.14 179.22,70.14 v2(179.91,69.45)
  BOTTOM w0.076: v2(144.74,48.89) 144.53,49.1 144.53,49.79 144.59,49.91 144.59,50.05 144.52,50.28 144.52,50.4 144.59,50.61 144.69,50.72 144.8,50.83 UCPU1.AY13
  BOTTOM w0.127: v3(181.42,68.1) 181.26,68.1 v2(179.91,69.45) 179.91,69.94 180.65,70.68 180.65,71.22 JLPDE1.3
LPC_AD1: length 55.2
  TOP w0.127: UE5.B32 179.61,67.28 v2(179.55,67.22)
  IN3 w0.089: v2(179.55,67.22) 179.12,66.79 178.13,66.79 177.7,66.35 176,66.35 175.46,65.82 175.46,65.24 174.88,64.65 174.24,64.65 169.52,59.93 167.21,59.93 166.42,59.14 166.42,58.1 165.58,57.26 161.71,57.26 159.36,54.91 159.36,54 158.24,52.89 157.17,52.89 155.09,50.81 152.04,50.81 150.61,49.38 148.33,49.38 146.66,47.71 146.66,47.43 146.19,46.96 v2(145.9,46.96)
  BOTTOM w0.076: UCPU1.BA13 145.09,50.04 145.09,49.43 145.38,49.13 145.38,47.48 v2(145.9,46.96)
  BOTTOM w0.127: v2(179.55,67.22) 179.5,67.27 v3(179.5,68.33) 179.45,68.39 179.45,70.05 179.25,70.25 179.25,71.6 179.57,71.92 180.75,71.92 181.15,71.51 JLPDE1.4
LPC_AD2: length 52.2
  TOP w0.127: v2(179.01,69.64) 179.01,69.61 179.36,69.26 179.36,68.72 UE5.A31
  IN3 w0.089: v2(179.01,69.64) 179.1,69.56 179.1,69.43 177.62,67.95 175.98,67.95 175.07,67.05 174.2,67.05 173.02,65.86 173.02,64.99 172.56,64.54 171.09,64.54 169.33,62.77 168.17,62.77 164.96,59.56 164.89,59.56 164.41,59.08 164.41,58.95 163.6,58.14 161.37,58.14 158.91,55.68 157.81,55.68 154.59,52.46 152.37,52.46 150.36,50.45 146.94,50.45 144.99,48.5 v2(144.99,48.24)
  BOTTOM w0.076: UCPU1.BB13 144.87,49.61 144.87,49.4 145.14,49.13 145.14,48.39 v2(144.99,48.24)
  BOTTOM w0.127: v2(179.01,69.64) 178.97,69.68 178.97,71.68 179.56,72.27 180.9,72.27 181.65,71.52 181.65,71.22 JLPDE1.5
LPC_AD3: length 58.7
  TOP w0.127: UE5.B33 179.11,67.61 v2(178.71,67.22)
  IN3 w0.089: v2(146.08,47.54) 146.79,48.25 146.79,49.23 147.31,49.76 150.64,49.76 151.92,51.04 155.02,51.04 157.08,53.1 158.15,53.1 159.14,54.09 159.14,55 161.62,57.48 165.49,57.48 166.2,58.19 166.2,59.23 167.12,60.14 169.43,60.14 174.15,64.87 174.79,64.87 175.25,65.33 175.25,65.73 175.25,65.91 175.91,66.57 177.55,66.57 177.98,67 178.5,67 v2(178.71,67.22)
  BOTTOM w0.076: UCPU1.AY12 145.37,51.19 145.09,50.91 145.09,50.37 145.29,50.16 145.29,49.46 145.55,49.2 145.55,47.7 145.7,47.54 v2(146.08,47.54)
  BOTTOM w0.127: v2(178.71,67.22) 178,67.93 178,71.07 179.91,72.98 181.53,72.98 182.15,72.37 182.15,71.22 JLPDE1.6
LPC_FRAME#: length 54.9
  TOP w0.127: v2(180.14,67.22) 180.11,67.24 UE5.B31
  IN3 w0.089: v2(180.14,67.22) 180.14,67.37 179.85,67.65 178.03,67.65 177.9,67.52 176.16,67.52 174.95,66.31 174.08,66.31 173.45,65.68 173.45,64.81 172.74,64.11 171.51,64.11 170.51,63.1 170.51,61.86 169.01,60.36 167.03,60.36 165.98,59.32 165.98,58.27 165.4,57.69 161.53,57.69 158.9,55.06 158.9,54.16 158.06,53.32 156.06,53.32 153.99,51.25 151.83,51.25 150.59,50.02 147.27,50.02 146.58,49.34 146.58,48.81 v2(145.9,48.13)
  BOTTOM w0.076: v2(145.9,48.13) 145.9,49.12 145.56,49.47 145.56,50.5 145.4,50.66 UCPU1.BA12
  BOTTOM w0.127: v2(180.14,67.22) 180.14,67.47 180.35,67.69 181.68,67.69 181.97,67.98 181.97,69.03 181.81,69.19 181.81,70.24 182.14,70.57 182.5,70.57 182.65,70.72 JLPDE1.7
LPM_ZVM_N: length 67
  TOP w0.127: v2(94.11,35.98) 95.48,35.98 96.47,36.97 96.47,43.47 96.16,43.77 93.24,43.77 92.81,43.34 90.88,43.34 90.4,42.86 PR1500.1
  TOP w0.254: PR1511.1 86.17,33.65 v2(86.72,33.65)
  IN2 w0.089: v2(95.25,33.21) 95.87,33.82 98.21,33.82 98.65,33.38 100.18,33.38 102.17,35.38 102.32,35.38 103.78,36.84 103.78,39.02 104.76,40 111.21,40 114.28,43.06 114.28,46.82 114.63,47.18 114.86,47.18 119.13,51.45 119.13,52.51 119.48,52.86 119.48,53.48 v2(119.74,53.74)
  BOTTOM w0.076: v2(119.74,53.74) 120.1,54.1 UCPU1.AR56
  BOTTOM w0.127: v2(86.72,33.65) 86.81,33.74 88.62,33.74 88.73,33.85 89.36,33.85 90.2,34.68 90.2,35.47 90.7,35.98 v2(94.11,35.98) 94.37,35.72 94.37,34.09 v3(94.59,33.87) v2(95.25,33.21)
LX_1.0V: length 1.6
  TOP w0.508: PC703.2 200.06,60.09 v2(200.76,60.79)
LX_1V_PRIM:
  vias: v2(89.39,29.19)
LX_3V:
  vias: v2(84.71,22.44) v2(85.32,22.44) v3(83.03,20.15)
LX_5V:
  vias: v2(57.7,43.96) v2(57.7,42.31) v3(57.48,43.09)
LX_DDR:
  vias: v2(169.35,28.22)
LX_PRIM: length 1.7
  TOP w0.127: v3(197.75,71.86) 197.54,72.06 197.54,73.49
LX_VCC_EDRAM:
  vias: v2(92.44,39.21)
LX_VCCIO:
  vias: v3(171.87,49.53)
MCARD_PCIE_SATA#: length 71.7
  IN4 w0.081: v2(180.65,66.2) 180.65,66.01 184.44,62.22 184.44,59.6 185.26,58.78 186.65,58.78 187.94,57.49 188.62,57.49 188.86,57.25 188.86,53.46 193.02,49.31 v2(193.02,49.28)
  BOTTOM w0.127: v2(180.65,66.2) 181.03,65.81 181.03,65.44 180.7,65.11 178.51,65.11 178.22,65.39 178.22,66.33 177.15,67.4 175.72,67.4 175.48,67.17 174.79,67.17 174.63,67.33 174.63,69.1 173.29,70.44 169.73,70.44 168.62,69.33 167.55,69.33 166.26,70.62 v3(165.71,70.62) 164.65,70.62 164.2,70.16 160.94,70.16 159.4,71.7 156.81,71.7 R2665.2 ; 186.92,39.98 187.44,39.98 187.97,40.51 187.97,40.73 188.57,41.34 188.57,43.4 188.92,43.76 190.15,43.76 191.97,45.58 191.97,48.24 v2(193.02,49.28) ; 186.92,39.98 185.94,39.98 R220.2 185.54,39.57 184.48,39.57 183.76,40.29 JNGFF2.61 ; 186.92,39.98 U683.2
ME_EN: length 14.6
  TOP w0.254: v2(160.17,48.7) 160.12,48.7 159.42,49.4 159.42,49.55 RH24.1 R1191.1
  BOTTOM w0.127: v3(169.76,47.99) 168.62,49.13 166.78,49.13 166.2,49.71 165.16,49.71 164.39,48.95 SW1.2
  BOTTOM w0.254: SW1.2 163.69,47.96 160.9,47.96 v2(160.17,48.7)
ME_FWP_EC: length 44.5
  TOP w0.127: v2(159.99,49.52) 159.99,50.23 v3(159.76,50.46) 159.14,51.08 159.14,51.48 158.97,51.65 158.32,51.65 R1191.2 ; UE5.B1 187.21,59.27 187.57,59.27 187.83,59.01 v2(188.21,59.01)
  IN2 w0.089: v2(180.19,60.38) 180.34,60.38 181.36,61.4 183.67,61.4 184.38,60.69 184.38,59.6 185.12,58.86 188.06,58.86 v2(188.21,59.01)
  IN3 w0.089: v2(180.19,60.38) 180.19,60.19 179.75,59.76 178.72,59.76 178.44,59.47 178.44,57.05 177.82,56.42 176.87,56.42 174.75,54.31 171.99,54.31 171.79,54.1 168.98,54.1 164.52,49.65 161.07,49.65 160.95,49.53 159.99,49.53 v2(159.99,49.52)
  BOTTOM w0.127: v2(159.99,49.52) 160.51,49 161.54,49 161.88,48.66 SW1.3
ME_RESET#: length 2.7
  TOP w0.127: RC227.1 158.19,71.1 RC225.2 157.7,71.6 156.69,71.6 UC12.2
ME_SUS_PWR_ACK: length 78.6
  TOP w0.127: v2(144.43,54.3) 144.1,54.3 143.93,54.13 143.93,53.02 143.7,52.79 143.7,51.79 143.57,51.66 143.57,49.4 142.88,48.7 RC74.2 ; v2(189.63,62.65) 189.27,62.65 v3(189.09,62.83) 188.9,63.02 UE5.A8
  IN3 w0.089: v2(189.63,62.65) 190.49,63.52 190.49,65.88 189.69,66.68 189.69,67.78 189.71,67.8 189.71,67.8 190.38,68.48 190.38,69.13 189.03,70.48 185.12,70.48 183.92,71.69 179.02,71.69 178.62,71.29 174.73,71.29 170.8,67.37 168.68,67.37 168.3,67.75 164.35,67.75 162.84,66.25 161.69,66.25 160.93,65.49 160.93,61.68 160.61,61.36 160.08,61.36 159.47,60.76 159.47,60.5 157.51,58.53 157.05,58.53 156.18,57.66 154.76,57.66 154.22,58.2 151.16,58.2 149.91,56.96 144.81,56.96 144.6,56.75 144.6,56.63 143.96,55.99 143.96,54.76 v2(144.43,54.3)
  BOTTOM w0.076: v2(144.43,54.3) 144.71,54.3 144.88,54.12 UCPU1.AR13
MEC_XTAL1: length 6.7
  TOP w0.127: YE1.1 184.38,52.79 CE62.1 185.6,54.01 185.6,56.04 184.95,56.68 v3(184.95,56.77) 184.95,57.38 184.86,57.47 UE5.A61
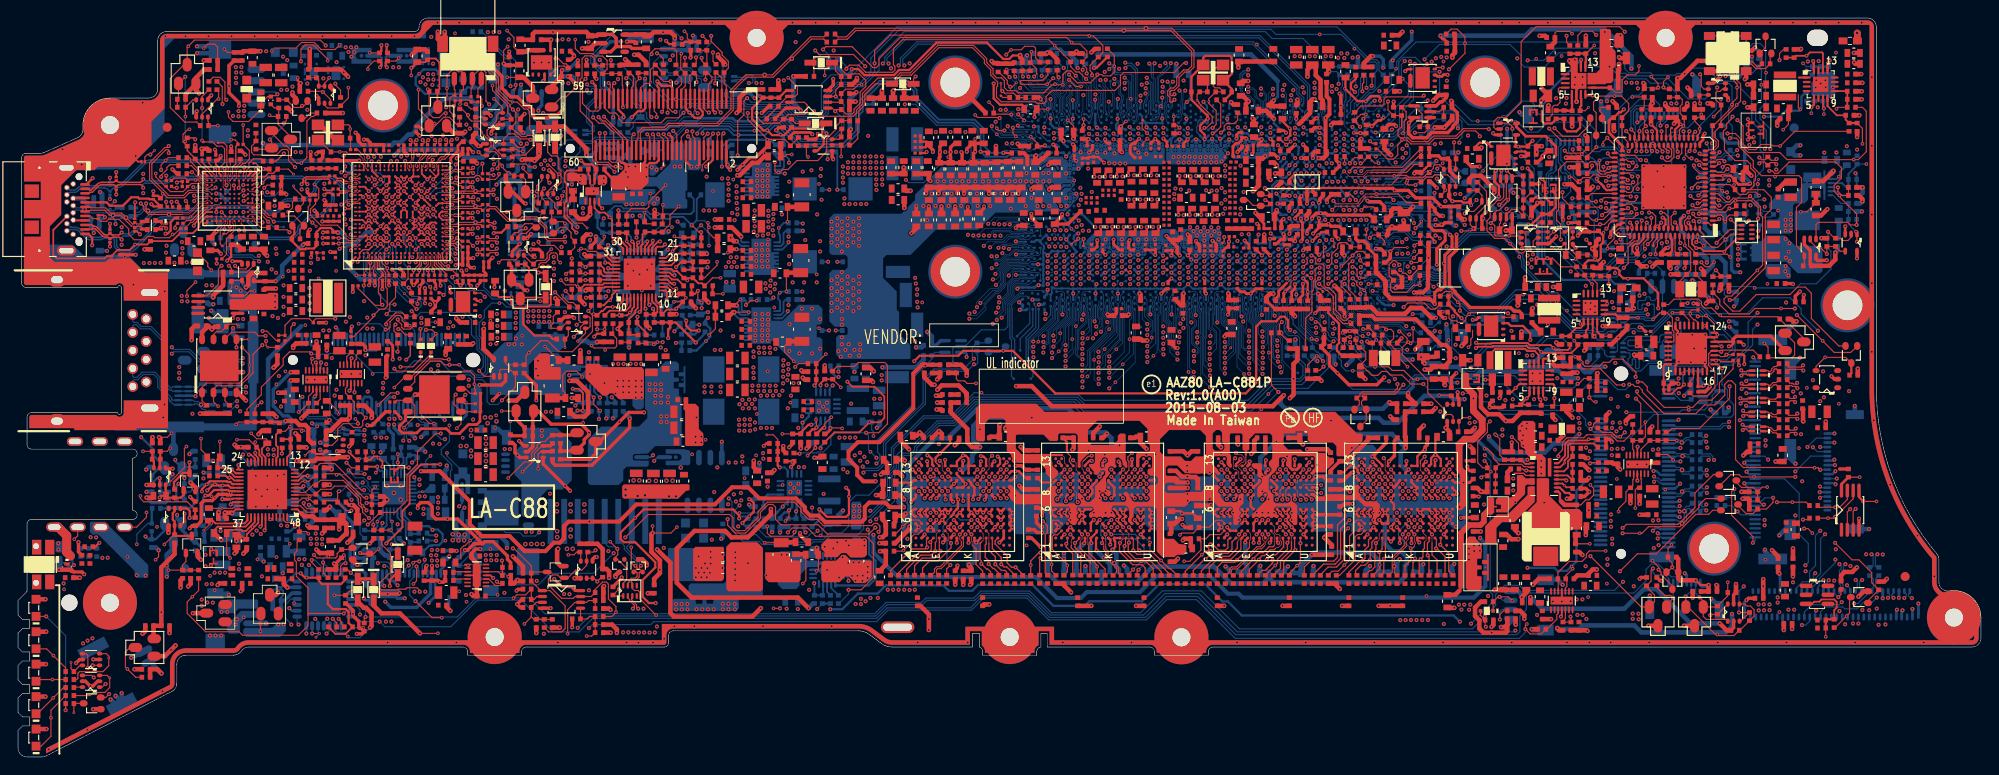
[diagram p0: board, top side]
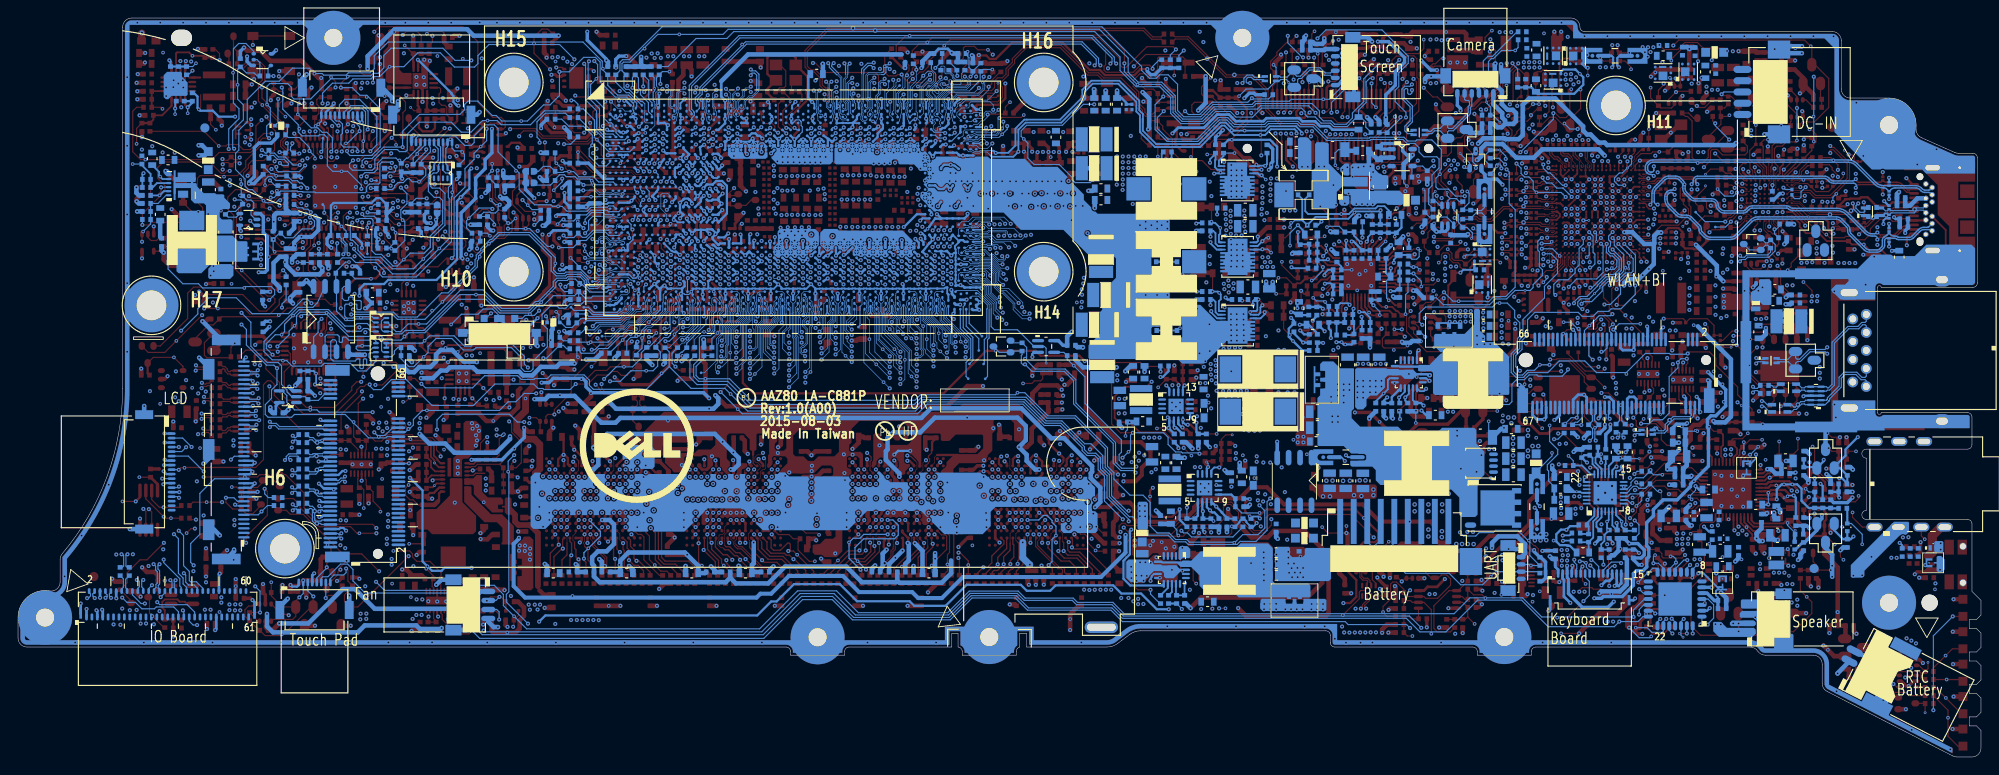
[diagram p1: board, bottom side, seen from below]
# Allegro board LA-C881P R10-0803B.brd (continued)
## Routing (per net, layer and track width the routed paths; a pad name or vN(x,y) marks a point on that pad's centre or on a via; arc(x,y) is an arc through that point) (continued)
MEC_XTAL2: length 3.3
  TOP w0.127: RE62.2 CE53.1 186.88,52.83 186.88,51.9 YE1.2
MEC_XTAL2_R: length 6.3
  TOP w0.127: v3(189.98,55.47) 189.66,55.79 RE62.1 186.16,55.92 185.36,56.72 UE5.A62
MEDIACARD_IRQ#: length 94.8
  IN4 w0.081: v2(199.41,20.39) 199.47,20.44 199.47,20.76 198.56,21.66 192.4,21.66 190.68,19.95 184.57,19.95 184.25,20.27 184.25,21.37 183.95,21.68 182.45,21.68 179.7,24.42 179.7,25.64 174.94,30.4 174.94,37.16 173.36,38.74 173.36,39.41 171.86,40.91 171.86,44.21 166.84,49.23 166.84,50.32 167.8,51.28 167.8,53.3 166.92,54.18 166.92,55.79 165.58,57.13 165.58,60.97 164.8,61.76 164.13,61.76 163.07,62.81 163.07,63.07 159.07,67.08 157.99,67.08 157.59,67.47 154.5,67.47 v2(154.09,67.88)
  BOTTOM w0.127: UCPU1.M1 152.12,66 152.53,65.59 153.35,65.59 154.43,66.68 154.43,67.53 v2(154.09,67.88) 154.09,69.01 155.07,69.99 156.7,69.99 157.48,70.77 RC13.2 ; v2(199.41,20.39) 199.2,20.18 199.2,19.4 198.88,19.08 198.27,19.08 197.91,18.73 197.91,18.41 JIO1.42
MEM_CONFIG0: length 5.1
  TOP w0.127: RH144.1 154.76,53.53 154.76,53.45 RH129.2 153.98,53.68 153.73,53.68 v2(153.36,54.04)
  BOTTOM w0.076: v2(153.36,54.04) 153.25,53.93 152.12,53.93 151.97,53.98 151.92,54.01 151.77,54.06 UCPU1.AP2
MEM_CONFIG1: length 10.8
  TOP w0.127: v2(153.27,54.62) 152.82,55.08 152.58,55.08 152.13,54.63 152.13,53.39 RH139.2 152.29,52.56 152.29,51.83 152.56,51.57 154.09,51.57 154.86,52.34 v3(155.55,52.34) RH150.1
  BOTTOM w0.127: v2(153.27,54.62) 152.81,54.16 152.17,54.16 UCPU1.AP1
MEM_CONFIG2: length 22.6
  TOP w0.127: v2(154.59,54.87) 154.59,54.87 155.27,54.87 RH149.1
  IN1 w0.081: v2(154.59,54.87) 154.59,54.87 155.07,54.87 156.69,56.49 156.69,64.09 157.4,64.8 157.75,64.8 157.95,65.01 157.95,67.28 v2(157.23,68)
  BOTTOM w0.076: v2(154.59,54.87) 154.36,55.1 152.64,55.1 152.4,54.87 152.19,54.87 151.94,54.62 151.34,54.62 150.93,54.22 UCPU1.AP3
  BOTTOM w0.127: RH145.2 156.49,68 v2(157.23,68)
MEM_CONFIG3: length 7.3
  TOP w0.127: v2(154.94,56.75) 155.18,56.98 RH151.1 RH146.2
  BOTTOM w0.076: 154.46,55.56 154.34,55.44 152.51,55.44 152.32,55.25 150.9,55.25 150.53,54.88 UCPU1.AN3
  BOTTOM w0.127: 154.46,55.56 154.61,55.71 154.61,55.8 v3(154.93,56.12) 154.94,56.13 v2(154.94,56.75)
MEM_CONFIG4: length 17.6
  TOP w0.127: RH152.1 155.58,56.09 154.94,55.46 154.94,55.43 v2(154.89,55.38)
  IN1 w0.081: v2(157.48,65.29) 157.48,65.18 156.48,64.18 156.48,56.58 155.29,55.38 v2(154.89,55.38)
  BOTTOM w0.076: v2(154.89,55.38) 154.78,55.27 152.58,55.27 152.38,55.08 151.99,55.08 UCPU1.AN1
  BOTTOM w0.127: RH147.2 158.22,66.02 v3(158.08,65.89) v2(157.48,65.29)
MEM_SMBCLK: length 11
  TOP w0.076: 150.28,64.47 149.68,64.47 v2(149.09,63.88)
  TOP w0.127: 150.28,64.47 v3(152.71,64.47) 152.77,64.54 154.06,64.54 154.28,64.33 155.95,64.33 156.48,64.86 RC12.1 157.05,65.31 157.05,65.54 157.23,65.72 157.73,65.72 QC2.6
  BOTTOM w0.127: v2(149.09,63.88) 148.74,64.22 UCPU1.R7
MEM_SMBDATA: length 13.4
  TOP w0.076: 152.61,63.72 152.37,63.48 148.82,63.48 v2(148.4,63.9)
  TOP w0.127: QC2.3 159.52,63.33 159.52,63.71 158.62,64.6 157.18,64.6 156.92,64.34 156.28,64.34 155.78,63.84 RC14.1 155.41,64.11 154.18,64.11 154.05,64.24 153.13,64.24 152.61,63.72
  BOTTOM w0.127: v2(148.4,63.9) 148.09,64.21 UCPU1.R8
MIC2-VREFO: length 22.5
  TOP w0.203: UA2.29 24.61,30.28 23.96,30.28
  TOP w0.254: RA28.1 8.59,23.33 v2(9.02,23.76) ; v2(20.41,29.47) 20.41,29.73 v3(20.93,30.25) 21.28,30.59 23.16,30.59 23.24,30.51 23.56,30.51 23.8,30.28 23.96,30.28
  IN4 w0.254: v2(20.41,29.47) 20.05,29.12 20.05,25.32 18.49,23.76 v2(9.02,23.76)
  BOTTOM w0.203: RA27.1 8.74,23.48 v2(9.02,23.76)
MONO_IN: length 5.1
  TOP w0.127: CA34.2 29.65,36.14 v3(30.16,36.65)
  TOP w0.203: UA2.16 28.66,33.18 28.83,33.35 28.83,34.39 28.63,34.59 28.63,35.77 CA34.2
MPHYP_PWR_EN: length 45.3
  TOP w0.127: RH557.1 159.02,80.77 159.68,80.77 160.55,79.89 v3(160.55,79.18) 160.55,78.09 v2(158.78,76.31)
  IN1 w0.081: v2(158.78,76.31) 158.59,76.12 158.45,76.12 158.12,75.79 158.12,74.86 158.6,74.38 158.6,72.22 161.29,69.53 161.29,67.68 159.36,65.74 159.36,63.41 157.95,62 157.95,61.33 158.65,60.63 158.65,58.94 158.14,58.43 158.14,56.86 157.75,56.47 157.75,56.24 155.34,53.83 154.42,53.83 v2(154.41,53.84)
  IN3 w0.089: v2(154.41,53.84) 154.14,53.58 152.51,53.58 149.81,56.28 146.77,56.28 146.31,55.81 v2(146.31,55.69)
  BOTTOM w0.076: UCPU1.AM10 146.66,56.05 v2(146.31,55.69)
MSCLK: length 10
  BOTTOM w0.127: JDEG1.6 172.15,68.22 172.15,67.73 172.06,67.63 172.06,67.14 173.08,66.13 RE72.2 172.57,65.26 172.57,64.53 173.27,63.83 v3(173.31,63.83) 174.07,63.83 174.41,64.17 174.63,64.17 175.06,63.74 175.66,63.74 176.02,63.38 176.02,63.23 176.28,62.98 177.04,62.98 RE105.1
MSDATA: length 14.4
  TOP w0.127: v2(171.37,62.66) 171.37,61.98 RE85.1 RE104.1
  IN1 w0.081: v2(172.52,67.42) 172.52,67.37 172.92,66.96 172.92,65.41 172.44,64.93 171.88,64.93 170.93,63.98 170.93,63.11 171.37,62.67 v2(171.37,62.66)
  BOTTOM w0.127: v2(172.52,67.42) 172.52,67.21 RE75.2 173.97,66.46 v3(173.52,66.9) 173.52,67.05 172.65,67.92 172.65,68.22 JDEG1.7
MSM_N: length 62.8
  IN2 w0.089: v2(88.72,25.1) 89.23,25.61 92.66,25.61 93.47,24.8 94.49,24.8 94.69,25 94.69,25.44 94.16,25.97 94.16,28.78 94.06,28.88 94.06,31.15 94.83,31.92 94.83,33.42 95.45,34.04 98.3,34.04 98.62,33.71 100.2,33.71 102.08,35.59 102.23,35.59 103.57,36.93 103.57,39.11 104.67,40.22 111.12,40.22 113.34,42.43 113.34,46.82 113.94,47.43 114.8,47.43 118.91,51.54 118.91,52.6 119.26,52.95 119.26,54.1 119.54,54.37 v2(119.74,54.37)
  BOTTOM w0.076: UCPU1.AP56 120.12,54.75 v2(119.74,54.37)
  BOTTOM w0.127: PR1524.2 83.01,24.42 87.59,24.42 88.04,24.86 88.48,24.86 v2(88.72,25.1)
NB_MUTE#: length 34.5
  TOP w0.127: v2(36.15,15.93) 32.33,15.93 32.18,15.78 ; RA57.1 20.04,18.47 v3(19.34,17.77) 18.77,17.2 18.77,15.93 20.81,13.89 24.53,13.89 24.92,13.51 31.11,13.51 32.18,14.58 32.18,15.78 ; 32.18,15.78 32.18,18.75 30.88,20.05 30.88,21.64 30.69,21.84 30.69,22.59 30.96,22.87 30.96,23.83 RA59.1
  BOTTOM w0.127: UE4.20 36.45,16.23 v2(36.15,15.93)
NB_PSID: length 10.3
  TOP w0.127: v2(28.78,73.54) 28.62,73.39 28.15,73.39 PL102.1 27.69,73.28 26.94,72.53 PD102.1 26.94,71.85 25.6,70.52 23.85,70.52 23.35,71.02 v3(23.35,71.57)
  BOTTOM w0.127: JP100.3 28.53,73.79 v2(28.78,73.54)
NC_B4: length 11
  TOP w0.076: v2(35.69,56.4) 35.89,56.6 37.13,56.6 37.14,56.61 37.65,56.61 37.88,56.84 UT1.B4
  TOP w0.127: v1(33.08,58.89) 32.68,59.29 v2(32.66,59.29) 32.2,59.76 32.2,61.04 32.39,61.23 RT50.2
  IN2 w0.089: v2(32.66,59.29) 33.25,58.71 33.25,56.98 33.66,56.57 35.51,56.57 v2(35.69,56.4)
NC_B5: length 10.8
  TOP w0.076: 36.37,57.95 36.78,57.54 37.66,57.54 UT1.B5
  TOP w0.127: 36.37,57.95 36.37,58.07 35.43,59.01 33.58,59.01 32.45,60.14 32.45,60.8 33.02,61.37 RT48.2 33.17,61.79 33.37,61.99 33.37,63.06 v3(32.89,63.54)
NC_G2: length 11.9
  TOP w0.076: 39.98,55.21 39.98,55.7 UT1.G2
  TOP w0.127: 39.98,55.21 40.07,55.12 40.07,54.48 40.79,53.76 40.79,52.13 40.96,51.96 40.96,50.02 40.63,49.68 40.11,49.68 v2(39.45,49.01) 39.45,48.85 37.25,46.66 RT49.2
NRB_BIT: length 3.5
  TOP w0.127: RC186.2 149.35,53.14 v3(148.84,53.14) 148.79,53.14 148.58,53.35 148.58,54.09 148.29,54.38 v2(148.08,54.38)
  BOTTOM w0.076: UCPU1.AR7 148.28,54.37 148.1,54.37 v2(148.08,54.38)
NTC_IA: length 2.8
  TOP w0.203: PR1064.2 73.86,52.31 73.19,52.98 72.55,52.98 72.55,52.99 72.17,53.36 PU1000.15
P_SYS: length 244.4
  TOP w0.127: v2(182.97,57.14) 182.98,57.14 182.98,57.17 182.86,57.28 UE5.A57 ; v2(46.91,35.9) 46.36,35.9 44.32,33.86 44.32,32.47 43.16,31.31 43.16,28.46 41.83,27.14 PR319.1 40.17,27.14 38.83,25.79 v2(38.81,25.79) ; PR1083.1 64.24,47.48 v2(64.26,47.46)
  IN1 w0.081: v2(46.91,35.9) 48.07,37.05 48.07,41.47 49.3,42.71 49.3,44.4 50.05,45.15 50.79,45.15 52.73,47.09 52.73,49.45 53.17,49.89 61.6,49.89 64.04,47.46 v2(64.26,47.46)
  IN2 w0.089: v2(41.43,15.02) 41.78,15.37 50.63,15.37 51.53,16.27 54.26,16.27 54.86,15.68 65.06,15.68 65.58,15.16 94.73,15.16 95.68,16.11 99.55,16.11 100.94,14.72 108.13,14.72 108.15,14.74 115.78,14.74 116.97,13.55 126.04,13.55 127.22,14.73 130.93,14.73 132.39,13.26 172.84,13.26 174.7,15.12 174.7,21.29 175.65,22.25 175.65,36.9 176.4,37.65 176.54,37.65 178.03,39.14 178.03,40.33 178.6,40.9 179.06,40.9 179.25,41.1 179.99,41.1 182,43.12 182,48.33 183.07,49.4 183.07,52.3 184.39,53.62 184.86,53.62 185.31,54.07 185.31,54.52 183.77,56.07 183.77,56.4 183.06,57.11 183.01,57.11 v2(182.97,57.14)
  IN4 w0.081: v2(38.81,25.79) 38.81,24.84 38.38,24.41 38.38,20.23 41.43,17.18 v2(41.43,15.02)
  BOTTOM w0.127: v2(64.26,47.46) v3(65.09,47.46)
PANEL_BKEN_EC: length 176.2
  TOP w0.127: D72.3 188.96,27.37 188.05,27.37 187.61,26.93 186.17,26.93 181.78,22.54 179.68,22.54 v2(177.75,20.61)
  IN1 w0.089: v2(177.75,20.61) 177.75,20.28 174.07,16.6 166.41,16.6 165.7,17.31 159.51,17.31 156.38,14.18 133.43,14.18 131.24,16.37 127.48,16.37 125.98,14.87 116.59,14.87 115.65,15.81 102.44,15.81 101.03,17.22 94.57,17.22 93.92,16.56 91.8,16.56 90.21,18.15 87.01,18.15 86.52,18.64 71.08,18.64 69.99,17.55 68.68,17.55 67.75,16.62 67.14,16.62 67.01,16.75 60.16,16.75 59.78,17.14 58.85,17.14 57.63,15.92 54.78,15.92 54.45,16.24 50.58,16.24 49.5,15.16 42.99,15.16 41.94,16.2 39.5,16.2 38.97,15.67 38.97,15.26 38.6,14.89 31.97,14.89 31.72,15.15 30.78,15.15 v2(30.33,14.69)
  BOTTOM w0.127: UE4.4 30.29,17.53 29.67,16.9 29.67,15.4 30.33,14.74 v2(30.33,14.69)
PANEL_BKLEN: length 77.7
  TOP w0.127: v2(178.05,24.83) v3(179.93,24.83) 180.19,24.83 180.92,25.55 184.39,25.55 186.52,27.68 186.52,27.95 187.25,28.68 188.96,28.68 D72.2
  IN4 w0.089: v2(178.05,24.83) 178.03,24.84 176.59,24.84 175.77,25.66 175.77,26.73 172.34,30.16 172.34,31.35 171.91,31.78 171.91,36.66 170.07,38.5 170.07,39.73 169.6,40.19 169.6,42.8 168.99,43.41 168.99,44.48 168.05,45.42 167.55,45.42 166.2,46.78 166.2,47.5 165.71,47.99 164.46,47.99 159.61,52.84 159.61,56.36 161.15,57.9 161.15,62.28 160.23,63.19 158.47,63.19 158.11,63.55 156.95,63.55 156.4,64.1 154.6,64.1 153.56,63.05 146.61,63.05 v2(145.84,63.82)
  BOTTOM w0.127: UCPU1.R12 145.49,64.18 v2(145.84,63.82)
PBAT_PRES#: length 201.9
  TOP w0.127: v2(36.45,32.65) 37.01,32.09 PR326.1 ; UE5.A49 178.66,58.02 177.6,58.02 v2(177.57,58) ; v2(66.7,18.65) PR100.2 66.12,17.87 PRP100.1
  IN1 w0.081: v2(177.57,58) 176.92,57.35 176.92,56.72 177.57,56.07 177.57,53.99 177.63,53.94 177.63,53.57 177.32,53.26 176.19,53.26 173.43,50.5 173.43,46.84 171.9,45.31 171.9,43.66 171.47,43.23 171.47,39.61 168.45,36.58 168.45,34.76 167.08,33.39 167.08,32.63 167.75,31.96 167.75,27.98 164.54,24.77 164.54,22.51 161.3,19.27 158.61,19.27 156.82,17.48 152.26,17.48 150.89,16.11 135.13,16.11 134.06,17.18 133.16,17.18 132.04,18.29 126.68,18.29 125.83,17.44 116.74,17.44 116.19,17.99 112.21,17.99 110.64,19.56 109.79,19.56 109.59,19.76 102.65,19.76 102.27,20.15 96.58,20.15 94.3,22.43 92.66,22.43 89.28,25.81 82.78,25.81 81.89,24.93 79.38,24.93 78.7,25.61 76.04,25.61 76.04,25.6 71.25,20.82 69.18,20.82 67.01,18.65 v2(66.7,18.65) 66.57,18.78 66.12,18.78 64.57,20.33 63.35,20.33 62.51,21.16 54.89,21.16 54.68,20.95 52.18,20.95 50.82,19.58 49.55,19.58 48.13,18.16 45.37,18.16 v2(45.19,18.34)
  IN4 w0.081: v2(36.45,32.65) 37.8,31.3 37.8,30.31 38.08,30.03 38.78,30.03 39.19,29.63 39.19,28.51 40.04,27.66 40.04,25.47 39.58,25.02 39.58,23.69 39.12,23.23 39.12,20.89 39.93,20.07 41.68,20.07 43.85,17.91 44.81,17.91 45.19,18.29 v2(45.19,18.34)
PBAT_SMBCLK: length 166.4
  TOP w0.127: PRP100.3 68.16,17.74 68.16,17.74 68.16,17.61 68.07,17.52 68.07,17.45 68.48,17.05 68.63,16.9 68.63,16.64 v2(68.81,16.46) ; v2(181.71,55.78) 181.71,56.44 181.91,56.63 181.91,57.18 182.36,57.63 182.36,57.82 UE5.A56
  IN1 w0.089: v2(181.71,55.78) 181.71,55.79 181.52,55.6 181.52,55.3 182,54.82 182,53.39 181.15,52.54 181.15,51.21 180.11,50.17 180.11,49.72 179.49,49.09 178.91,49.09 177.48,47.67 177.48,47.13 177.15,46.8 177.15,46.5 174.8,44.15 174.8,41.2 175,41 175,38.25 173.97,37.21 173.97,35.49 175.26,34.2 175.26,26.42 176.83,24.85 177.17,24.85 179.2,22.82 179.2,21.12 174.24,16.16 166.19,16.16 165.89,16.46 162.09,16.46 161.34,15.71 159.63,15.71 158.97,15.05 158.97,14.63 158.09,13.75 133.25,13.75 131.06,15.93 127.66,15.93 126.16,14.44 116.41,14.44 115.47,15.37 102.26,15.37 100.9,16.74 94.75,16.74 94.14,16.13 91.51,16.13 89.92,17.72 86.83,17.72 86.34,18.21 71.26,18.21 70.01,16.96 68.8,16.96 68.63,16.79 68.63,16.64 v2(68.81,16.46)
  BOTTOM w0.127: RE53.2 181.95,57.55 181.95,57.24 181.52,56.81 181.52,55.98 181.71,55.79 v2(181.71,55.78)
PBAT_SMBDAT: length 166.6
  TOP w0.127: PRP100.2 67.66,17.67 67.85,17.47 67.85,17.36 68.33,16.89 68.41,16.81 68.41,16.64 v2(68.22,16.46) ; v2(182.32,59.29) 182.11,59.08 182.11,58.67 UE5.B59
  IN1 w0.089: v2(68.22,16.46) 68.42,16.65 68.42,16.88 68.71,17.17 69.92,17.17 71.17,18.42 86.43,18.42 86.92,17.93 90.01,17.93 91.6,16.35 94.05,16.35 94.66,16.96 100.99,16.96 102.35,15.59 115.56,15.59 116.5,14.65 126.07,14.65 127.57,16.15 131.15,16.15 133.34,13.97 158,13.97 158.76,14.72 158.76,15.14 159.54,15.93 161.25,15.93 162,16.68 165.98,16.68 166.28,16.38 174.15,16.38 178.98,21.21 178.98,22.73 177.08,24.63 176.74,24.63 175.04,26.33 175.04,34.11 173.75,35.4 173.75,37.3 174.79,38.34 174.79,40.91 174.59,41.11 174.59,44.24 176.94,46.59 176.94,46.89 177.27,47.22 177.27,47.76 178.82,49.31 179.4,49.31 179.9,49.81 179.9,50.26 180.94,51.3 180.94,52.63 181.79,53.48 181.79,54.73 181.31,55.22 181.31,55.61 v2(181.13,55.79)
  BOTTOM w0.127: v2(182.32,59.29) v3(181.91,58.88) 181.41,58.38 RE52.2 181.72,57.56 181.72,57.32 181.31,56.9 181.31,55.97 v2(181.13,55.79)
PBATT+_C: length 10.2
  TOP w0.127: v3(70.41,25.63) v2(70.41,24.85) 72.45,24.85 v3(73.1,25.5)
  TOP w0.508: v2(70.41,24.85) 70.28,24.72 70.28,22.76 71.22,21.82 v3(71.22,20.79) 71.22,20.41 70.59,19.77 PC102.2
PBTN_SW#: length 100.4
  TOP w0.127: RE33.2 CE21.1 188.82,50.76 188.82,50.2 189.87,49.15 192.09,49.15 192.71,49.77 v3(195.63,49.77) v2(197.16,49.77) ; v2(191.75,79.01) SW2.2 SW2.4
  IN4 w0.081: v2(201.81,30.89) 202.26,30.44 202.26,24.29 206.25,20.3 v2(206.25,17.69)
  IN4 w0.089: v2(201.81,30.89) 201.81,30.92 200.91,31.81 200.91,34.1 199.77,35.24 199.44,35.24 197.59,37.09 196.72,37.09 196.55,37.27 196.55,49.18 197.14,49.78 ; 197.14,49.78 197.14,50.04 192.44,54.75 192.44,59.33 192.68,59.57 192.68,59.89 193.35,60.56 193.35,61.18 193.64,61.47 193.97,61.47 194.18,61.68 194.18,62.08 193.95,62.31 193.53,62.31 193.37,62.15 193.37,61.8 193.29,61.72 192.93,61.36 192.93,61.09 192.62,60.79 192.06,60.79 191.76,61.09 191.76,65.33 192.82,66.38 192.82,66.69 193.31,67.18 193.31,77.45 v2(191.75,79.01) ; 197.14,49.78 v2(197.16,49.77)
  BOTTOM w0.127: JIO1.35 200.01,15.54 200.01,16.12 200.53,16.65 202.47,16.65 202.67,16.44 204.06,16.44 204.78,17.15 205.72,17.15 v2(206.25,17.69) ; v2(201.81,30.89) 200.76,30.89 JAPS1.11
PCH_ALW_ON: length 47.2
  TOP w0.127: v2(189.92,41.13) 189.92,39.8 186.57,36.46 183.52,36.46 183.1,36.04 R1443.1 ; UE5.A34 177.16,66.52 176.77,66.52 176.41,66.88 v2(176.41,66.98)
  IN4 w0.081: 186.95,57.27 186.95,55.86 186.35,55.25 186.35,54.02 188.37,52 188.37,50.58 191.04,47.91 191.04,44.39 189.92,43.27 v2(189.92,41.13)
  IN4 w0.089: 186.95,57.27 186.3,57.93 182.62,57.93 180.66,59.89 178.66,59.89 178.18,60.37 178.18,62.42 177.27,63.33 177.27,66.1 176.41,66.96 v2(176.41,66.98)
PCH_BATLOW#: length 7.1
  TOP w0.127: RC72.1 147.02,48.09 146.4,48.72 v1(146.4,48.85) 145.95,49.3 145.95,51.1 145.28,51.78 145.15,51.78 144.43,52.49 v2(144.38,52.49)
  BOTTOM w0.076: UCPU1.AU13 144.72,52.8 144.41,52.49 v2(144.38,52.49)
PCH_DPWROK: length 3.6
  TOP w0.127: v3(175.49,66.2) 175.49,65.19 175.66,65.01 176.07,65.01 176.43,65.36 v2(176.5,65.36) 176.53,65.39 176.53,65.41 176.64,65.52 UE5.A36
  BOTTOM w0.127: RC221.2 177.09,65.36 v2(176.5,65.36)
PCH_DPWROK_R: length 70.8
  TOP w0.127: RC220.1 143.1,43.52 v3(144.09,44.51) 144.22,44.51 v2(144.81,43.93)
  IN3 w0.089: v2(175.92,65.49) 175.92,65.38 176.47,64.83 180.18,64.83 180.79,64.22 180.79,62.77 179.57,61.55 178.61,61.55 177.9,62.27 174.72,62.27 174.22,61.77 174.22,58.5 174.41,58.31 174.41,57.23 173.3,56.11 171.26,56.11 170.11,57.25 166.51,57.25 166.02,56.76 166.02,52.37 164.28,50.62 158.25,50.62 157.42,49.79 154.23,49.79 152.86,48.42 149.32,48.42 148.29,47.39 148.29,45.95 146.88,44.55 145.83,44.55 145.21,43.93 v2(144.81,43.93)
  BOTTOM w0.127: v2(144.81,43.93) 144.63,44.1 RC215.1 144.22,44.92 144.12,44.92 CC266.1 143.61,45.91 141.48,48.05 141.48,48.52 141.3,48.7 141.3,49.53 UCPU1.BB20 ; v2(175.92,65.49) 175.92,65.02 176.04,64.91 176.63,64.91 RC221.1
PCH_JTAG_TCLK: length 74.1
  TOP w0.127: v2(73.84,71.48) 73.28,70.93 71.91,70.93 71.38,70.39 67.1,70.39 66.67,70.82 66.67,71.11 66.32,71.46 65.63,71.46 65.1,72 JXDP1.55 ; v2(95.05,76.97) 95.05,78.36 96.79,80.1 118.79,80.1 v3(118.87,80.02) 119.3,80.02 120.37,78.95 120.37,78.16 RC86.2 118.95,76.74 118.95,76.16 119.18,75.94 v2(119.18,75.65)
  BOTTOM w0.076: v2(119.18,75.65) 119.18,75.68 119.39,75.46 119.39,74.33 120.13,73.6 120.13,72.65 119.94,72.47 119.94,72.21 120,72.09 120,71.97 120.07,71.86 120.07,71.8 UCPU1.B56
  BOTTOM w0.127: v2(73.84,71.48) 74.61,72.26 79.93,72.26 80.29,71.9 85,71.9 86.36,70.53 88.67,70.53 89.65,71.52 89.65,73.27 91.02,74.63 93.63,74.63 95.05,76.05 v2(95.05,76.97)
PCH_PCIE_WAKE#: length 54
  TOP w0.127: RC67.2 145.54,45.7 v2(145.97,46.14) ; UE5.B46 178.01,61.77 178.6,61.77 178.75,61.62 179.36,61.62 179.58,61.84 179.58,62.15 v2(179.57,62.16)
  IN3 w0.089: v2(145.97,46.14) 146.18,46.14 147.12,47.08 147.12,47.56 148.47,48.91 152.05,48.91 153.47,50.33 155.3,50.33 155.81,50.84 164.19,50.84 165.81,52.46 165.81,56.85 166.85,57.89 166.85,58.96 167.39,59.5 170.68,59.5 171.58,58.6 172.61,58.6 173.83,59.81 173.83,61.71 174.61,62.49 177.98,62.49 178.7,61.77 179.28,61.77 179.57,62.06 v2(179.57,62.16)
  BOTTOM w0.076: 144.65,47.23 144.38,47.5 144.38,48.49 144.25,48.62 144.03,48.62 143.47,49.19 143.47,49.58 UCPU1.BB15
  BOTTOM w0.127: v2(145.97,46.14) 145.53,46.14 144.97,46.7 v3(144.97,46.91) 144.65,47.23
PCH_PLTRST#: length 27.6
  TOP w0.127: 161.79,59.77 UC7.2 ; 161.79,59.77 161.79,60.15 162.94,61.3 162.94,62.77 161.93,63.79 RC226.2 ; 161.79,59.77 161.79,58.85 RC85.2 161.52,58.68 ; 161.52,58.68 161.21,58.38 v2(160.15,58.38) ; 161.52,58.68 161.14,59.06 UC7.1
  IN3 w0.089: v2(146.26,55.01) 146.71,55.46 146.71,55.79 146.97,56.05 149.74,56.05 152.43,53.35 154.56,53.35 158.29,57.08 159.33,57.08 160.15,57.9 v2(160.15,58.38)
  BOTTOM w0.076: v2(146.26,55.01) 146.65,55.4 UCPU1.AN10
PCH_PLTRST#_EC: length 365.9
  TOP w0.127: v2(160.53,60.31) 160.76,60.54 161.52,60.54 162.44,61.45 162.44,61.68 ; v2(189.08,43.14) 188.64,43.57 U15.17 ; 162.44,61.68 162.44,62.34 RC226.1 RC65.1 ; 162.44,61.68 UC7.4 ; v2(182.25,70.06) 182.22,70.09 RE54.2 ; UE5.B30 180.61,67.33 v2(180.72,67.22) ; R104.1 41.89,50.98 41.25,50.34 41.25,49.5 v2(40.9,49.15)
  IN1 w0.081: v2(38.81,40.55) 38.81,42.5 40.39,44.08 40.39,48.64 40.9,49.15 v2(40.9,49.15)
  IN3 w0.089: v2(160.53,60.31) 161.57,60.31 162.71,61.45 162.71,64.85 164.06,66.2 167.54,66.2 168.77,64.97 172.25,64.97 172.59,65.31 172.59,66.04 176.97,70.43 178.98,70.43 179.38,70.82 181.48,70.82 v2(182.25,70.06)
  IN4 w0.081: v2(160.53,60.31) 160.41,60.43 157.49,60.43 156.88,59.81 156.88,58.87 157.17,58.58 157.47,58.58 158.29,57.76 158.29,57.68 158.98,56.99 158.98,52.55 166.48,45.05 166.48,41.48 166.68,41.28 166.68,39.23 167.99,37.91 167.99,34.95 166.94,33.9 166.94,28.91 165.73,27.71 165.73,23.18 161.2,18.65 147.37,18.65 146.98,19.04 145.66,19.04 145.17,18.55 123.35,18.55 123.24,18.67 101.88,18.67 99.07,21.48 97.24,21.48 96.07,22.66 96.07,24.84 95.97,24.94 95.97,27.35 92.24,31.08 92,31.08 91.72,31.35 85.77,31.35 83.8,29.38 81.89,29.38 81.57,29.69 79.27,29.69 75.68,26.09 75.15,26.09 67.09,18.03 63.75,18.03 62.9,17.18 59.04,17.18 55.95,20.27 54.7,20.27 52.92,18.49 49.63,18.49 48.82,17.69 46.41,17.69 45.34,18.75 43.59,18.75 41.85,20.49 41.51,20.49 41.04,20.97 41.04,21.78 40.02,22.8 40.02,24.13 41.06,25.18 41.06,27.23 39.63,28.66 39.63,30.96 37.67,32.93 37.67,34.11 35.93,35.85 35.93,37.91 38.57,40.55 v2(38.81,40.55)
  IN4 w0.089: v2(200.51,24.72) 200.38,24.6 198.2,24.6 196.44,26.35 196.44,34.04 194.64,35.84 194.64,46.36 v2(193.02,47.99) 193.69,48.66 193.69,49.48 193.27,49.9 193.03,49.9 189.29,53.64 189.29,57.43 188.8,57.92 188.12,57.92 187.22,58.81 187.22,60.46 187.07,60.61 187.07,61.5 186.72,61.85 185.41,61.85 181.31,65.96 181.31,66.43 180.72,67.01 v2(180.72,67.22) 180.72,67.37 182.19,68.84 182.45,68.84 182.78,69.17 182.78,69.58 182.3,70.06 v2(182.25,70.06)
  BOTTOM w0.127: v2(200.51,24.72) 200.02,24.23 200.02,20.38 199.49,19.86 199.49,19.2 199.11,18.82 JIO1.38 ; v2(193.02,47.99) 192.47,47.45 192.47,45.72 190.23,43.48 189.42,43.48 v2(189.08,43.14) 189.08,41.33 189.68,40.73 189.68,39.79 190.38,39.1 190.38,38.01 190.07,37.7 187.45,37.7 187.15,38.01 181.51,38.01 178.91,35.41 176.98,35.41 176.84,35.55 175.6,35.55 JNGFF2.50 ; v2(40.9,49.15) 41.08,48.97 42.36,48.97 v3(43.46,47.87) 44,47.32 JNGFF1.44 ; JLPDE1.8 183.15,70.84 182.37,70.06 v2(182.25,70.06)
PCH_POPIRCOMP: length 2.6
  TOP w0.305: v2(142.57,52.49) 142.57,51.27 142.22,50.91 RC89.1
  BOTTOM w0.254: UCPU1.AU16 142.99,52.8 v2(142.57,52.49)
PCH_PWR_EN: length 5
  TOP w0.127: v3(184.07,35.12) R1443.2 R1444.2 R1187.2 180.08,34.13 U717.3
PCH_PWROK: length 97.1
  TOP w0.254: v2(63.02,50.96) 63.07,51.01 PR1027.1 ; v2(141.16,47.39) 140.9,47.65 140.9,48.49 140.54,48.85 140.11,48.85 139.6,48.35 137.97,48.35 137.39,47.76 137.39,41.51 136.22,40.34 115.11,40.34 110.39,45.07 v3(109.32,45.07) 104.88,45.07 104.33,44.52 100.04,44.52 v2(99.44,43.93)
  IN3 w0.203: v2(63.02,50.96) 63.25,50.96 65,49.21 65,47.83 66.39,46.44 68.5,46.44 71.02,43.93 83.92,43.93 84.48,44.48 85.5,44.48 86.06,43.93 96.34,43.93 96.61,43.66 99.17,43.66 v2(99.44,43.93)
  BOTTOM w0.076: v2(141.16,47.39) 141.07,47.48 141.07,49.31 140.87,49.51 140.87,50.05 UCPU1.BA20
PCH_RSMRST#: length 181.3
  TOP w0.127: v2(175.76,60.13) 176.07,60.43 176.32,60.43 176.68,60.79 176.68,60.92 176.79,61.02 UE5.A45 ; v2(144.86,43.32) 144.45,42.91 RC75.2 ; RC124.1 71.6,77.5 71.02,78.09 v2(70.9,78.09)
  IN3 w0.089: v2(144.86,43.32) 144.91,43.32 145.92,44.33 146.97,44.33 148.5,45.86 148.5,47.3 149.41,48.21 154.56,48.21 155.71,49.36 157.6,49.36 158.42,50.18 164.44,50.18 166.45,52.19 166.45,56.58 166.69,56.82 169.94,56.82 171.09,55.66 174.48,55.66 175.15,56.33 175.15,59.51 v2(175.76,60.13) ; v2(171.76,72.5) 171.37,72.88 171.37,76.58 169.54,78.42 155.64,78.42 155.54,78.52 151.99,78.52 151.21,79.29 92.82,79.29 90.58,77.05 84.94,77.05 83.86,75.97 80.37,75.97 79.31,77.03 76.97,77.03 75.97,78.03 73.4,78.03 73.18,78.25 72.49,78.25 72.33,78.09 v2(70.9,78.09)
  IN4 w0.081: v2(171.76,72.5) 172.12,72.5 174.31,70.31 174.31,68.74 173.81,68.24 173.81,66.77 173.35,66.31 173.35,64.45 173.44,64.36 173.44,62.75 174.61,61.58 174.61,61.46 175.3,60.78 175.3,60.59 v2(175.76,60.13)
  BOTTOM w0.076: UCPU1.AY17 142.38,50.83 142.27,50.72 142.17,50.61 142.1,50.4 142.1,50.28 142.17,50.05 142.17,49.91 142.11,49.79 142.11,47.71 143.89,45.93 144.12,45.93 RC215.2
  BOTTOM w0.127: RC215.2 145.24,44.81 145.24,43.7 v2(144.86,43.32)
PCH_RTCRST#: length 97
  TOP w0.127: v2(178.79,41.34) 179.18,41.34 179.4,41.11 179.82,41.11 180.24,40.7 180.24,40.49 182.62,38.11 186.18,38.11 187.13,39.06 188.3,39.06 189.38,40.15 189.38,41.36 189.77,41.74 190.14,41.74 190.58,41.31 190.58,33 191.45,32.13 199.3,32.13 v3(199.34,32.09) 199.75,32.09 v2(199.98,31.86) ; v2(155.93,41.39) 154.57,41.39 153.57,42.38 152.27,42.38 151.87,42.78 151.31,42.78 150.88,42.35 150.22,42.35 149.21,43.37 CMOS1.1 148.95,43.49 149.54,44.09 149.54,44.94 149.06,45.42 RC57.1 148.44,45.81 CC25.1
  IN4 w0.081: v2(142.6,55.64) 143.1,56.14 145.52,56.14 145.83,55.83 145.83,52.96 146.09,52.7 146.26,52.7 146.52,52.45 146.52,51.94 151.96,46.5 152.72,46.5 153.2,46.02 154.06,46.02 154.62,45.47 154.62,44.71 154.36,44.46 154.36,43.37 156,41.74 156,41.45 v2(155.93,41.39)
  BOTTOM w0.076: UCPU1.AM16 v2(142.6,55.64)
  BOTTOM w0.127: v2(199.98,31.86) 200,31.89 JAPS1.9 ; v2(178.79,41.34) 178.79,41.19 178.37,40.76 177.49,40.76 176.37,41.89 174.75,41.89 171.87,39.01 167.27,39.01 164.89,41.39 160.59,41.39 160.1,40.89 159.57,40.89 159.45,40.78 156.54,40.78 v2(155.93,41.39)
PCH_RTCX1: length 23.1
  TOP w0.127: v3(154.18,43.31) 153.21,44.28 YC2.1 152.88,45.17 CC23.1 152.63,46.44 152.63,47.18 152.36,47.44 v2(151.8,47.44) 151.54,47.71 RC54.2
  IN1 w0.089: v2(141.68,55.64) 142.15,55.18 142.15,52.25 143.46,50.94 145.26,50.94 146.22,49.97 149.28,49.97 v2(151.8,47.44)
  BOTTOM w0.127: UCPU1.AM18 141.73,55.64 v2(141.68,55.64)
PCH_RTCX2: length 16.6
  TOP w0.127: RC296.1 150.47,47.08 RC54.1 149.61,47.48 v2(149.25,47.48)
  IN1 w0.081: v2(149.25,47.48) 147.27,49.46 146.07,49.46 145.06,50.47 143.27,50.47 141.68,52.05 141.22,52.05 140.34,52.94 140.34,55.3 140.73,55.69 v2(140.77,55.69)
  BOTTOM w0.127: UCPU1.AM20 140.87,55.69 v2(140.77,55.69)
PCH_RTCX2_R: length 8.9
  TOP w0.127: RC296.2 151.23,46.67 CC26.1 151.23,45.13 YC2.2 151.37,43.29 152.08,43.29 152.48,42.89 153.78,42.89 154.75,41.92 v3(155.31,41.92)
PCH_RTD3_CIO_PWR_EN: length 8.2
  BOTTOM w0.127: UCPU1.H5 149.93,67.17 152.25,67.17 v3(153.57,68.49) 153.85,68.77 153.85,69.15 155.65,70.95 RC248.1
PCH_SMB_ALERT#: length 10.1
  TOP w0.076: v2(147.14,64.99) 147.71,64.42 149.3,64.42 149.77,64.9 150.26,64.9 150.28,64.87 150.3,64.87
  TOP w0.127: 150.3,64.87 154.07,64.87 154.94,65.74 RC23.1
  BOTTOM w0.127: v2(147.14,64.99) 146.79,64.64 UCPU1.R10
PCH_SPI_CLK: length 32.3
  BOTTOM w0.089: 153.94,51.97 153.52,51.97 153.06,52.43 151.4,52.43 UCPU1.AV2
  BOTTOM w0.127: 176.52,47.95 176.25,47.67 176.25,47.58 175.87,47.2 175.36,47.2 174.51,48.05 v3(173.37,48.05) 172.48,48.05 168.7,51.83 166.2,51.83 164.13,49.76 161.19,49.76 160.41,50.54 160.11,50.54 158.42,52.23 158.42,52.74 158.02,53.13 156.97,53.13 156.81,53.3 155.45,53.3 154.98,52.83 154.98,52.52 154.44,51.97 153.94,51.97 ; 176.52,47.95 176.79,48.21 176.94,48.21 RP5.7 ; 176.52,47.95 176.76,47.71 176.94,47.71 RP5.6
PCH_SPI_CLK_TPM: length 19
  TOP w0.127: U15.19 188.21,44.58 188.75,44.58 188.9,44.42 189.35,44.42 v2(189.56,44.64) 190.28,44.64 C135.1
  BOTTOM w0.127: RP5.3 178.1,47.71 178.67,47.71 179.06,48.1 180.18,48.1 180.46,47.81 181.53,47.81 183.36,49.64 186.6,49.64 188.24,48.01 188.24,47.18 v3(188.56,46.85) 189.26,46.85 190.26,45.86 190.26,45.34 v2(189.56,44.64)
PCH_SPI_CS0#: length 46.3
  IN3 w0.089: v2(180.84,49.11) 180.89,49.11 181.38,48.62 v2(184.13,48.62)
  BOTTOM w0.089: 153.89,52.2 153.55,52.2 153.14,52.61 151.09,52.61 UCPU1.AU3
  BOTTOM w0.127: 153.89,52.2 154.35,52.2 154.76,52.61 154.76,52.92 155.4,53.55 156.92,53.55 157.08,53.39 158.1,53.39 158.65,53.94 158.65,55.49 161.1,57.94 164.41,57.94 165.18,57.17 165.31,57.17 166.2,56.27 166.2,56.1 166.72,55.59 166.72,55.2 166.85,55.07 166.85,54.38 v3(170.72,50.5) 172.66,48.57 175.71,48.57 176.26,49.11 180.83,49.11 v2(180.84,49.11) ; v2(184.13,48.62) 184.52,48.23 184.52,47.11 185.01,46.62 UH8.1
PCH_SPI_CS2#: length 62.5
  TOP w0.127: RH127.1 192.53,45.15 189.17,45.15 v2(188.99,44.97) 188.88,45.08 U15.20 187.92,45.08 187.59,44.75 187.59,43.43 188.28,42.75 188.28,40.92 187.42,40.06 185.85,40.06 RC230.2
  IN3 w0.089: v2(180.64,49.66) 180.19,49.21 180.19,48.88 181.75,47.33 182.63,47.33 183.95,46.01 187.91,46.01 188.68,45.24 188.72,45.24 v2(188.99,44.97)
  BOTTOM w0.089: 153.93,52.41 153.64,52.41 153.24,52.82 152.19,52.82 UCPU1.AU1
  BOTTOM w0.127: v2(180.64,49.66) 180.35,49.37 176.15,49.37 175.61,48.82 173.49,48.82 170.82,51.49 170.09,51.49 167.1,54.48 167.1,55.18 166.97,55.31 166.97,55.69 166.46,56.2 166.46,56.38 165.41,57.43 165.28,57.43 164.51,58.2 160.98,58.2 158.19,55.41 v3(158.19,54.77) 158.19,54.52 158.39,54.31 158.39,54.05 157.99,53.65 157.18,53.65 157.02,53.81 155.35,53.81 154.55,53 154.55,52.69 154.26,52.41 153.93,52.41
PCH_SPI_DO2_XDP: length 115.2
  TOP w0.127: JXDP1.60 64.1,66.22 64.32,66 65.48,66 65.96,65.52 v2(66.29,65.52)
  IN1 w0.089: v2(66.29,65.52) 66.29,65.41 66.75,64.96 66.75,64.65 67.48,63.93 70.57,63.93 71.72,65.07 78.27,65.07 79.4,66.2 79.97,66.2 80.21,65.96 82.49,65.96 83.84,67.32 99.06,67.32 100.4,65.98 107.33,65.98 107.98,66.63 109.48,66.63 109.78,66.93 111.27,66.93 112.12,67.78 113.47,67.78 113.78,67.47 117.32,67.47 117.45,67.6 118.14,67.6 118.36,67.37 118.36,66.94 118.64,66.66 119.15,66.66 120.35,65.46 123.08,65.46 123.82,66.2 123.82,67.27 124.07,67.52 134.44,67.52 134.72,67.24 134.72,66.94 135.05,66.61 136.27,66.61 137.86,65.02 137.86,60.81 139.96,58.7 143.95,58.7 144.18,58.48 148.5,58.48 149.51,57.47 149.51,55.72 149.87,55.36 149.87,53.86 152.58,51.14 155.35,51.14 156.79,52.59 157.46,52.59 v2(157.63,52.41)
  BOTTOM w0.127: v2(157.63,52.41) 157.63,52.08 157.2,51.65 RC11.1
PCH_SPI_DO_XDP: length 127.2
  TOP w0.127: v2(66.19,64.93) 66.19,64.93 65.38,65.74 64.22,65.74 63.74,66.22 63.74,70.33 62.38,71.69 62.38,75.22 62.59,75.43 62.59,77.48 62.92,77.8 63.66,77.8 63.98,77.48 RC133.2 RC128.1
  IN1 w0.089: v2(66.19,64.93) 66.19,64.75 67.23,63.71 70.66,63.71 71.81,64.86 78.69,64.86 79.48,64.07 79.93,64.07 81.61,65.74 82.58,65.74 83.93,67.1 98.97,67.1 100.31,65.77 107.42,65.77 108.07,66.42 109.57,66.42 109.87,66.72 111.36,66.72 112.21,67.56 113.38,67.56 113.69,67.25 117.2,67.25 118.05,66.4 119.1,66.4 120.27,65.24 125.76,65.24 127.79,67.27 133.4,67.27 134.42,66.25 136.09,66.25 137.64,64.7 137.64,60.72 139.88,58.49 143.86,58.49 144.09,58.26 148.41,58.26 149.29,57.38 149.29,55.63 149.65,55.27 149.65,53.77 152.49,50.92 155.82,50.92 v2(157.07,52.18)
  BOTTOM w0.127: v2(157.07,52.18) 156.72,52.54 RC10.1
PCH_SPI_IO2: length 32.6
  BOTTOM w0.076: UCPU1.AW2 151.49,51.63 151.98,51.14 152.45,51.14
  BOTTOM w0.127: 152.45,51.14 154.03,51.14 154.23,50.94 154.89,50.94 RC11.2 ; RP6.6 176.95,44.92 177.3,44.92 177.47,45.09 177.47,46.06 177.27,46.26 175.31,46.26 v3(174.93,46.65) 174.5,47.08 172.67,47.08 168.95,50.79 165.88,50.79 164.34,49.26 160.98,49.26 160.21,50.03 159.57,50.03 158.41,51.19 156.06,51.19 RC11.2 ; RC11.2 RH59.2
PCH_SPI_IO3: length 42.1
  BOTTOM w0.076: 152.58,50.55 152.53,50.51 151.99,50.51 151.84,50.66 151.4,50.66 151.18,50.88 151.18,51.02 150.91,51.29 150.24,51.29 149.96,51.57 149.96,52.04 150.22,52.29 150.22,52.84 UCPU1.AU4
  BOTTOM w0.127: RP6.5 176.94,44.42 176.35,44.42 176.05,44.73 176.05,45.04 175.67,45.42 RH56.2 RH58.2 175.31,44.2 174.42,43.31 173.89,43.31 v3(172.79,44.41) 172.31,44.88 172.31,45.55 171.43,46.44 169.67,46.44 168.4,45.17 167.25,45.17 167,45.42 163.06,45.42 161.98,44.34 161.98,43.16 161.6,42.78 160.93,42.78 160.66,43.06 160.66,43.94 159.08,45.52 159.08,47.51 159.66,48.1 159.66,49.11 158.74,50.03 158,50.03 157.77,49.8 157.04,49.8 156.58,50.26 155.29,50.26 154.99,50.55 152.58,50.55
PCH_SPI_SI: length 34
  BOTTOM w0.076: UCPU1.AV3 150.7,52.2 151,51.9 151.77,51.9 151.85,51.82
  BOTTOM w0.127: 176.94,47.21 177.28,47.21 177.5,47.43 177.5,48.37 177.15,48.71 RP5.8 ; 176.94,47.21 176.44,47.21 176.17,46.95 175.24,46.95 174.85,47.33 172.77,47.33 168.8,51.31 v3(167,51.31) 166.03,51.31 164.24,49.51 161.08,49.51 160.31,50.29 160,50.29 158.14,52.15 158.14,52.63 157.89,52.88 156.87,52.88 156.72,53.03 155.97,53.03 RC10.2 155.3,52.54 154.37,51.6 152.48,51.6 152.25,51.82 151.85,51.82 ; 176.94,47.21 RP5.5
PCH_SPI_SI_TPM: length 15.2
  TOP w0.127: U15.21 189,45.57 v2(189.03,45.55)
  BOTTOM w0.127: v2(189.03,45.55) 187.73,46.85 187.73,47.25 v3(187.13,47.86) 186.91,48.07 186.91,48.97 186.52,49.36 183.43,49.36 181.32,47.24 179.77,47.24 179.46,47.54 178.99,47.54 178.66,47.21 RP5.4
PCH_SPI_SO: length 34.1
  IN2 w0.089: v2(150.32,51.72) 150.32,51.75 153.72,48.35 154.61,48.35 155.25,47.71 155.25,47.25 159.28,43.21 v2(161.24,43.21)
  BOTTOM w0.127: RP6.7 RP6.8 172.96,45.92 v3(172.7,46.19) 172.15,46.73 169.42,46.73 168.27,45.58 167.56,45.58 167.21,45.93 163.09,45.93 161.62,44.46 161.62,43.6 v2(161.24,43.21) ; UCPU1.AW3 150.43,51.64 150.32,51.75 v2(150.32,51.72)
PCH_SPI_SO_TPM: length 13.1
  TOP w0.127: U15.24 188.21,48.1 187.33,48.98 v3(187.3,48.98) 187.22,48.9 v2(186.39,48.9)
  BOTTOM w0.127: v2(186.39,48.9) 186.18,49.1 183.54,49.1 181.1,46.66 178.61,46.66 178.1,46.14 RP6.1
PCH_TBT_FORCE_PWR: length 3
  TOP w0.127: v2(148.92,69.94) 148.31,70.54 RC247.1 149,71.31 v3(149.56,71.31)
  BOTTOM w0.127: v2(148.92,69.94) 148.59,70.26 UCPU1.D7
PCI_CLK_LPC0: length 14.7
  BOTTOM w0.076: UCPU1.AW9 147.22,51.44 147,51.22 146.94,51.03 146.94,50.61 146.86,50.53 146.86,49.6 147.18,49.28 147.32,49.28 148.81,47.79 148.81,47.36 149.07,47.1 149.45,47.1 149.68,47.33 150.14,47.33 150.78,46.69
  BOTTOM w0.127: 150.78,46.69 151,46.69 152.37,45.32 153.37,45.32 153.88,44.8 155.31,44.8 155.45,44.95 155.45,45.07 RC18.1 155.8,45.18 155.8,44.49 v3(155.68,44.37)
PCI_CLK_LPC1: length 11.3
  BOTTOM w0.076: 150.99,47.39 150.57,47.39 149.94,48.03 149.07,48.03 147.65,49.44 147.65,50.02 147.47,50.2 147.47,50.85 147.34,50.99 UCPU1.AY9
  BOTTOM w0.127: 150.99,47.39 152.34,46.03 v3(154.28,46.03) 155.52,46.03 RC22.1
PCIE_PRX_CARDTX_N6: length 106.9
  IN2 w0.076: 142.44,70.37 142.43,70.36 142.39,70.36 142.24,70.21 142.24,69.25 142.04,69.05 142.04,68.82 141.81,68.59 v2(141.68,68.59)
  IN2 w0.102: v2(202.11,21.4) 202.33,21.61 202.33,22.02 201.93,22.42 201.18,22.42 199.04,24.55 199.04,26 192.33,32.71 192.33,43.45 191.9,43.88 191.9,45.94 190.81,47.04 190.81,53.03 190.2,53.64 190.2,57.38 190.48,57.66 190.48,59.82 190.3,60 190.3,62.64 189.43,63.51 188.51,63.51 187.11,64.92 185.72,64.92 185.32,65.31 185.32,65.8 184.84,66.29 184.84,67.19 184.02,68.01 177.66,68.01 176.23,69.43 173.7,69.43 173.32,69.05 165.28,69.05 164.48,68.25 160.55,68.25 159.7,69.1 159.55,69.1 158.38,70.27 157.95,70.27 157.39,70.82 152.62,70.82 152.26,70.47 150.31,70.47 149.47,71.31 143.38,71.31 142.44,70.37
  BOTTOM w0.127: JIO1.28 202.11,18.58 202.25,18.72 202.25,19.04 202.11,19.18 202.11,20.68 202.29,20.86 202.29,21.22 v2(202.11,21.4) ; UCPU1.G18 141.84,68.59 v2(141.68,68.59)
PCIE_PRX_CARDTX_P6: length 107.1
  IN2 w0.076: v2(141.68,69.18) 141.94,69.18 142.08,69.32 142.08,70.28 142.27,70.48 142.27,70.52 142.28,70.53
  IN2 w0.102: 142.28,70.53 143.29,71.54 149.57,71.54 150.41,70.7 152.17,70.7 152.52,71.05 157.49,71.05 158.04,70.49 158.48,70.49 159.64,69.33 159.79,69.33 160.64,68.47 164.39,68.47 165.19,69.27 173.23,69.27 173.61,69.66 176.33,69.66 177.75,68.23 184.12,68.23 185.06,67.28 185.06,66.38 185.55,65.9 185.55,65.41 185.81,65.15 187.2,65.15 188.61,63.74 189.52,63.74 190.52,62.73 190.52,60.09 190.7,59.91 190.7,57.57 190.42,57.29 190.42,53.73 191.03,53.13 191.03,47.13 192.13,46.03 192.13,43.97 192.55,43.54 192.55,32.81 199.26,26.09 199.26,24.65 201.27,22.64 202.02,22.64 202.55,22.11 202.55,21.61 v2(202.77,21.4)
  BOTTOM w0.127: v2(202.77,21.4) 202.54,21.17 202.54,20.76 202.36,20.57 202.36,19.29 202.5,19.15 202.5,18.81 202.71,18.6 JIO1.26 ; UCPU1.F18 141.92,68.94 v2(141.68,69.18)
PCIE_PRX_SSDTX_N9: length 79.5
  IN4 w0.091: v2(181.94,24.24) 181.78,24.4 181.02,24.4 180.24,25.19 180.24,25.71 175.34,30.62 175.34,37.99 172.25,41.08 172.25,46.94 171.33,47.86 171.33,51.85 168.91,54.27 168.91,55.83 166.38,58.36 166.38,61.29 165.3,62.37 165.3,62.62 164.26,63.66 163.6,63.66 162.66,64.6 162.66,65.72 162.33,66.05 162.03,66.05 160.58,67.5 159.14,67.5 157.54,69.1 157,69.1 155.3,70.8 152.6,70.8 152.38,70.58 150.36,70.58 149.6,71.34 145.45,71.34 144.37,70.27 143.69,70.27 143.56,70.4 142.55,70.4 142.36,70.22 140.51,70.22 139.69,69.39 139.09,69.39 v2(138.96,69.26)
  BOTTOM w0.127: JNGFF2.5 183.15,24.3 182.42,24.3 182.32,24.4 182.1,24.4 v2(181.94,24.24) ; v2(138.96,69.26) 138.96,69.22 139,69.26 139,69.33 139.25,69.59 UCPU1.E22
PCIE_PRX_SSDTX_N10: length 81.4
  IN4 w0.091: v2(184.38,27.24) 184.38,27.31 184.23,27.47 181.18,27.47 175.95,32.7 175.95,38.87 173.67,41.15 173.67,42.68 173.06,43.29 173.06,47.12 171.94,48.23 171.94,52.33 170.65,53.62 170.65,55 166.98,58.66 166.98,62.19 164.88,64.3 163.86,64.3 163.33,64.83 163.33,66.01 162.71,66.63 162.51,66.63 161.15,67.99 160.92,67.99 160.22,68.69 159.21,68.69 155.96,71.94 144.65,71.94 144.47,71.76 143.04,71.76 142.93,71.65 139.48,71.65 138.57,70.73 138.57,69.66 138.35,69.45 138.12,69.45 138,69.34 v2(138,69.18)
  BOTTOM w0.127: JNGFF2.17 183.15,27.3 183.93,27.3 184.06,27.43 184.19,27.43 v2(184.38,27.24) ; UCPU1.F25 137.76,68.94 v2(138,69.18)
PCIE_PRX_SSDTX_N11: length 81.9
  IN4 w0.091: v2(135.33,69.89) 135.57,69.65 135.57,69.4 135.81,69.16 136.53,69.16 137.62,70.25 137.62,70.83 139.05,72.26 142.67,72.26 142.8,72.38 144.18,72.38 144.35,72.55 149.68,72.55 150.37,73.24 154.03,73.24 154.58,73.8 156.67,73.8 157.43,73.04 157.43,72.09 158.51,71.01 159.89,71.01 160.97,69.94 161.77,69.94 166.08,65.63 166.08,64.54 167.95,62.66 167.95,60.97 169.14,59.78 169.14,57.9 172.93,54.11 172.93,48.98 174.22,47.69 174.55,47.69 180.26,41.98 180.26,34.28 181.15,33.39 181.15,32.26 180.85,31.96 180.85,30.93 181.08,30.69 181.38,30.69 v2(181.53,30.54)
  BOTTOM w0.127: v2(181.53,30.54) 181.7,30.7 181.87,30.7 182.16,30.42 182.32,30.42 182.44,30.29 JNGFF2.29 ; v2(135.33,69.89) 135.63,69.59 UCPU1.E28
PCIE_PRX_SSDTX_P9: length 79.5
  IN4 w0.091: v2(181.94,24.82) 181.71,24.6 181.1,24.6 180.43,25.27 180.43,25.79 175.53,30.7 175.53,38.07 172.44,41.16 172.44,47.02 171.53,47.94 171.53,51.93 169.1,54.35 169.1,55.91 166.57,58.44 166.57,61.37 165.5,62.45 165.5,62.7 164.34,63.85 163.68,63.85 162.86,64.68 162.86,65.8 162.41,66.24 162.11,66.24 160.66,67.69 159.22,67.69 157.62,69.29 157.08,69.29 155.38,70.99 152.52,70.99 152.3,70.77 150.44,70.77 149.68,71.54 145.37,71.54 144.29,70.46 143.77,70.46 143.64,70.6 142.47,70.6 142.28,70.41 140.43,70.41 139.61,69.58 139.26,69.58 v2(138.97,69.87)
  BOTTOM w0.127: UCPU1.E23 138.69,69.59 v2(138.97,69.87) ; v2(181.94,24.82) 182.11,24.65 182.17,24.65 182.32,24.8 183.15,24.8 JNGFF2.7
PCIE_PRX_SSDTX_P10: length 81.4
  IN4 w0.091: v2(137.95,69.89) 137.95,69.76 138.06,69.65 138.27,69.65 138.37,69.74 138.37,70.81 139.4,71.84 142.85,71.84 142.96,71.96 144.39,71.96 144.57,72.13 156.04,72.13 159.29,68.88 160.3,68.88 161,68.19 161.23,68.19 162.59,66.83 162.79,66.83 163.53,66.09 163.53,64.91 163.94,64.49 164.96,64.49 167.17,62.27 167.17,58.74 170.84,55.08 170.84,53.7 172.14,52.41 172.14,48.31 173.25,47.2 173.25,43.37 173.86,42.76 173.86,41.23 176.14,38.95 176.14,32.78 181.26,27.66 184.19,27.66 v2(184.38,27.85)
  BOTTOM w0.127: v2(137.95,69.89) 137.95,69.83 137.7,69.59 UCPU1.E25 ; v2(184.38,27.85) 184.21,27.68 184.01,27.68 183.9,27.8 183.15,27.8 JNGFF2.19
PCIE_PRX_SSDTX_P11: length 81.9
  IN4 w0.091: v2(181.53,31.13) 181.29,30.89 181.16,30.89 181.04,31.01 181.04,31.88 181.35,32.18 181.35,33.47 180.45,34.36 180.45,42.06 174.63,47.89 174.3,47.89 173.13,49.06 173.13,54.19 169.33,57.98 169.33,59.86 168.15,61.05 168.15,62.74 166.27,64.62 166.27,65.71 161.85,70.13 161.05,70.13 159.97,71.21 158.59,71.21 157.62,72.17 157.62,73.12 156.75,73.99 154.5,73.99 153.95,73.43 150.29,73.43 149.6,72.74 144.27,72.74 144.1,72.58 142.72,72.58 142.59,72.45 138.97,72.45 137.43,70.91 137.43,70.33 136.45,69.35 135.89,69.35 135.76,69.48 135.76,69.73 135.91,69.88 v2(136.17,69.88)
  BOTTOM w0.127: v2(181.53,31.13) 181.7,30.96 181.98,30.96 182.27,30.67 182.4,30.67 182.53,30.8 183.15,30.8 JNGFF2.31 ; v2(136.17,69.88) 136.45,69.59 UCPU1.E27
PCIE_PRX_TBTX_N1: length 119.2
  TOP w0.127: v2(46.85,68.46) 46.69,68.3 46.69,68.09 CT3.1
  IN1 w0.091: v2(144.43,67.91) 144.63,68.12 144.9,68.12 145.21,68.43 145.21,71.03 143.4,72.84 143.4,74.46 142.04,75.82 138.63,75.82 137.15,74.33 137.15,73.7 136.83,73.39 131.03,73.39 130.34,74.08 130.34,75.73 129.85,76.22 123.97,76.22 123.75,76 122.53,76 122.18,75.65 122.18,74.53 121.89,74.24 121.45,74.24 120.98,74.71 116.45,74.71 116.07,75.1 116.07,75.78 115.67,76.18 109.6,76.18 108.99,75.57 108.99,74.81 105.44,71.26 100.63,71.26 100.3,71.59 92.94,71.59 92.44,71.09 87.6,71.09 86.93,70.42 85.74,70.42 85.37,70.79 83.51,70.79 83.09,70.37 74.22,70.37 72.41,68.55 63.35,68.55 61.48,70.43 56.81,70.43 56.49,70.1 51.28,70.1 48.97,67.79 46.89,67.79 46.65,68.03 46.65,68.27 v2(46.85,68.46)
  BOTTOM w0.127: UCPU1.H13 144.7,67.64 v2(144.43,67.91)
PCIE_PRX_TBTX_N1_C: length 3.2
  TOP w0.076: UT1.V22 45.48,65.34 45.48,66.34 45.57,66.42 45.61,66.42 45.62,66.43
  TOP w0.127: CT3.2 46.63,67.15 46.63,66.92 46.39,66.68 45.88,66.68 45.63,66.44 45.63,66.44 45.62,66.43
PCIE_PRX_TBTX_N2: length 120.5
  TOP w0.127: CT7.1 43.71,68.12 43.71,68.31 v2(43.56,68.46)
  IN1 w0.091: v2(146.25,68.61) 146.06,68.81 145.94,68.81 145.84,68.71 145.84,68.31 144.86,67.33 144.06,67.33 143.71,67.67 143.71,70.14 143.42,70.43 143.42,71.68 142.56,72.55 142.56,73.01 142.11,73.46 141.92,73.65 141.92,74.17 141.08,75.02 139.47,75.02 138.79,74.33 138.79,73.06 137.62,71.89 129.3,71.89 128.92,71.51 127.76,71.51 127.38,71.89 126.49,71.89 126.09,71.49 123.72,71.49 122.56,72.66 122.56,73.12 122.23,73.44 121.13,73.44 120.64,73.93 115.29,73.93 115.09,74.13 112.27,74.13 111.44,73.3 108.61,73.3 105.77,70.45 100.29,70.45 100,70.75 93.52,70.75 93.04,70.27 87.88,70.27 87.25,69.63 85.34,69.63 84.99,69.99 83.85,69.99 83.41,69.55 79.55,69.55 77.76,67.76 62.96,67.76 61.08,69.65 57.36,69.65 56.35,68.64 54.7,68.64 54.49,68.42 50.92,68.42 50.89,68.39 50.87,68.39 49.38,66.9 44.93,66.9 43.8,68.03 43.8,68.23 v2(43.56,68.46)
  BOTTOM w0.127: UCPU1.G11 146.12,68.61 v2(146.25,68.61)
PCIE_PRX_TBTX_N2_C: length 2.6
  TOP w0.076: UT1.P22 43.28,65.26 43.28,65.26 43.18,65.36 43.18,65.77 43.73,66.32 43.73,66.41 43.7,66.45 43.7,66.47
  TOP w0.127: CT7.2 43.67,67.22 43.67,66.49 43.7,66.47
PCIE_PRX_TBTX_P1: length 119.1
  TOP w0.127: CT1.1 46.27,67.94 46.43,68.11 46.43,68.29 v2(46.26,68.46)
  IN1 w0.091: v2(144.43,68.65) 144.43,68.46 144.58,68.31 144.82,68.31 145.02,68.51 145.02,70.95 143.21,72.76 143.21,74.38 141.96,75.62 138.71,75.62 137.34,74.25 137.34,73.62 136.91,73.2 130.95,73.2 130.15,74 130.15,75.65 129.77,76.03 124.05,76.03 123.83,75.8 122.61,75.8 122.38,75.57 122.38,74.45 121.97,74.05 121.37,74.05 120.9,74.52 116.37,74.52 115.88,75.02 115.88,75.7 115.59,75.99 109.68,75.99 109.18,75.49 109.18,74.73 105.52,71.06 100.55,71.06 100.22,71.39 93.02,71.39 92.52,70.9 87.68,70.9 87.01,70.22 85.66,70.22 85.29,70.6 83.59,70.6 83.17,70.17 74.3,70.17 72.49,68.36 63.27,68.36 61.4,70.23 56.89,70.23 56.57,69.91 51.36,69.91 49.05,67.6 46.81,67.6 46.44,67.97 46.44,68.28 v2(46.26,68.46)
  BOTTOM w0.127: UCPU1.G13 144.78,68.29 v2(144.43,68.65)
PCIE_PRX_TBTX_P1_C: length 3.2
  TOP w0.076: UT1.V23 45.26,65.46 45.21,65.41 45.11,65.41 45.03,65.5 45.03,65.86 45.31,66.14 45.31,66.41 45.44,66.53 45.44,66.58 45.46,66.59
  TOP w0.127: CT1.2 46.38,67.18 46.38,67.03 46.29,66.93 45.77,66.93 45.46,66.62 45.46,66.59
PCIE_PRX_TBTX_P2: length 120.4
  TOP w0.127: CT5.1 44.11,67.94 43.97,68.09 43.97,68.33 44.09,68.46 v2(44.22,68.46)
  IN1 w0.091: v2(44.22,68.46) 43.99,68.23 43.99,68.11 45.01,67.09 49.3,67.09 50.83,68.61 54.41,68.61 54.62,68.83 56.27,68.83 57.28,69.84 61.16,69.84 63.04,67.95 77.68,67.95 79.47,69.75 83.33,69.75 83.77,70.18 85.07,70.18 85.42,69.82 87.17,69.82 87.8,70.46 92.96,70.46 93.44,70.94 100.08,70.94 100.37,70.65 105.69,70.65 108.53,73.49 111.36,73.49 112.19,74.32 115.17,74.32 115.37,74.12 120.72,74.12 121.21,73.63 122.31,73.63 122.75,73.2 122.75,72.74 123.8,71.69 126.01,71.69 126.41,72.08 127.46,72.08 127.84,71.7 128.84,71.7 129.22,72.08 137.54,72.08 138.59,73.14 138.59,74.41 139.39,75.21 141.16,75.21 142.11,74.25 142.11,73.73 142.75,73.09 142.75,72.63 143.61,71.76 143.61,70.51 143.91,70.22 143.91,67.75 144.14,67.52 144.78,67.52 145.64,68.39 145.64,68.79 145.86,69 145.98,69 v2(146.23,69.25)
  BOTTOM w0.127: UCPU1.F11 146.11,69.25 v2(146.23,69.25)
PCIE_PRX_TBTX_P2_C: length 2.8
  TOP w0.076: 43.92,66.49 43.92,66.49 43.89,66.46 43.89,66.25 43.59,65.94 43.59,65.83 43.66,65.75 43.66,65.41 43.61,65.36 43.49,65.36 43.42,65.43 UT1.P23
  TOP w0.127: 43.92,66.49 43.92,67.29 43.99,67.36 CT5.2
PCIE_PRX_WLANTX_N5: length 128.1
  IN1 w0.091: v2(142.6,69.18) 142.6,69.32 142.46,69.46 142.28,69.46 142.05,69.7 142.05,69.96 142.04,69.97 142.04,70.37 142.25,70.58 142.25,71.02 141.96,71.31 138.94,71.31 137.98,70.35 137.48,70.35 137.35,70.21 136.4,70.21 136.3,70.32 135.05,70.32 134.95,70.21 129.13,70.21 129.08,70.27 123.19,70.27 122.2,71.26 118.5,71.26 117.55,72.21 112.8,72.21 111.15,70.56 109.62,70.56 108.43,69.38 108.05,69.38 107.4,68.73 100.17,68.73 99.52,69.38 94.03,69.38 92.99,68.33 80.01,68.33 78.22,66.54 65.31,66.54 63.86,65.08 63.86,63.53 59.16,58.84 59.16,56.87 56.25,53.96 52.06,53.96 50.96,52.85 50.28,52.85 49.77,52.35 49.77,51.05 46.56,47.84 46.56,46.18 44.69,44.31 44.69,39.9 42.82,38.03 41.73,38.03 41.58,37.88 41.58,37.73 v2(41.78,37.52)
  BOTTOM w0.127: v2(142.6,69.18) 142.64,69.22 142.98,69.22 143.06,69.15 UCPU1.F16 ; v2(41.78,37.52) 41.72,37.52 41.6,37.64 41.6,38 41.75,38.15 JNGFF1.35
PCIE_PRX_WLANTX_P5: length 128.1
  IN1 w0.091: v2(41.2,37.52) 41.39,37.71 41.39,37.96 41.65,38.23 42.74,38.23 44.5,39.98 44.5,44.39 46.37,46.26 46.37,47.92 49.58,51.13 49.58,52.43 50.2,53.04 50.88,53.04 51.98,54.15 56.17,54.15 58.96,56.95 58.96,58.92 63.66,63.61 63.66,65.16 65.23,66.73 78.14,66.73 79.93,68.53 92.91,68.53 93.95,69.57 99.6,69.57 100.25,68.92 107.32,68.92 107.97,69.57 108.35,69.57 109.54,70.75 111.07,70.75 112.72,72.4 117.63,72.4 118.58,71.45 122.28,71.45 123.27,70.46 129.16,70.46 129.21,70.41 134.87,70.41 134.97,70.51 136.38,70.51 136.48,70.41 137.27,70.41 137.4,70.54 137.9,70.54 138.86,71.5 142.04,71.5 142.44,71.1 142.44,70.5 142.23,70.29 142.23,70.05 142.24,70.04 142.24,69.78 142.36,69.66 142.44,69.66 142.64,69.86 v2(142.64,69.87)
  BOTTOM w0.127: UCPU1.E16 142.9,69.59 142.64,69.85 v2(142.64,69.87) ; JNGFF1.33 41.25,38.1 41.35,38 41.35,37.67 v2(41.2,37.52)
PCIE_PTX_CARDRX_N6: length 113.5
  IN2 w0.102: v2(205.66,22.49) 205.83,22.66 205.83,23.35 202.11,27.07 200.32,27.07 195.51,31.88 195.51,35.65 194.06,37.11 194.06,45.82 192.33,47.54 192.33,58.62 192.45,58.74 192.45,59.86 191.56,60.75 191.56,63.21 191.39,63.38 191.39,64.12 189.97,65.54 189.97,67.02 185.85,71.13 180.8,71.13 179.83,72.1 178.77,72.1 178.18,72.69 177.61,72.69 176.48,73.82 169.86,73.82 169.44,73.39 167.66,73.39 165.19,70.93 161.13,70.93 159.89,72.17 158.7,72.17 156.34,74.53 152.16,74.53 151.6,75.09 144.22,75.09 144.07,75.24 143.69,75.24 143.19,74.74 141.52,74.74 141.12,74.34 141.12,74.16 140.76,73.8 140.75,73.8 v2(140.34,73.39)
  BOTTOM w0.076: UCPU1.D20 140.31,71.21 140.31,71.59 140.43,71.71 140.43,72.07 140.6,72.24 140.6,73.12 140.56,73.16 v2(140.34,73.39)
  BOTTOM w0.127: v2(205.66,22.49) 205.75,22.49 205.84,22.41 205.84,21.19 205.69,21.04 CH14.1
PCIE_PTX_CARDRX_N6_C: length 1.9
  BOTTOM w0.127: CH14.2 205.87,19.72 205.87,18.78 205.71,18.62 JIO1.16
PCIE_PTX_CARDRX_P6: length 113.7
  IN2 w0.102: v2(140.34,74.02) 140.67,74.02 140.89,74.25 140.89,74.43 141.43,74.96 143.09,74.96 143.6,75.47 144.16,75.47 144.31,75.31 151.69,75.31 152.25,74.76 156.43,74.76 158.79,72.39 159.99,72.39 161.23,71.15 165.1,71.15 167.56,73.62 169.34,73.62 169.77,74.04 176.57,74.04 177.7,72.91 178.28,72.91 178.87,72.32 179.92,72.32 180.89,71.35 185.95,71.35 190.19,67.11 190.19,65.63 191.61,64.21 191.61,63.48 191.78,63.3 191.78,60.85 192.67,59.96 192.67,58.65 192.56,58.53 192.56,47.63 194.28,45.91 194.28,37.2 195.73,35.75 195.73,31.97 200.41,27.3 202.2,27.3 206.06,23.44 206.06,22.76 v2(206.32,22.49)
  BOTTOM w0.076: UCPU1.C20 140.6,72 140.77,72.17 140.77,73.19 140.73,73.23 140.73,73.63 v2(140.34,74.02)
  BOTTOM w0.127: v2(206.32,22.49) 206.21,22.49 206.09,22.37 206.09,21.19 206.24,21.04 CH13.1
PCIE_PTX_CARDRX_P6_C: length 1.9
  BOTTOM w0.127: CH13.2 206.12,19.77 206.12,18.83 206.31,18.64 206.31,18.41 JIO1.14
PCIE_PTX_SSDRX_N9: length 90.8
  IN4 w0.091: v2(187.33,27.36) 187.33,27.5 187.2,27.63 186.86,27.63 186.6,27.89 186.6,28.39 186.97,28.76 187.66,28.76 188.02,29.13 188.02,30 187.55,30.47 185.92,30.47 183.67,32.72 183.67,37.14 182,38.81 182,43.53 177.62,47.91 177.62,50.3 176.33,51.6 176.33,51.77 174.69,53.41 174.69,55.5 173.99,56.2 173.99,56.57 173.58,56.98 172.78,56.98 172.19,57.57 172.19,57.93 172.18,57.93 172.18,57.95 170.72,59.41 170.72,60.98 170.11,61.59 170.11,63.41 170.27,63.56 170.27,64.69 166.68,68.28 166.68,69.5 164.49,71.69 161.47,71.69 158.77,74.39 158.34,74.39 157.26,75.47 153.12,75.47 152.69,75.9 147.71,75.9 147.24,76.37 145.92,76.37 145.77,76.52 140.9,76.52 138.71,74.33 138.71,74.08 138.45,73.82 138.11,73.82 137.92,73.63 v2(137.92,73.5)
  BOTTOM w0.076: v2(137.92,73.5) 138.09,73.67 138.18,73.67 138.39,73.46 138.39,72.95 138.22,72.79 138.22,72.07 138.39,71.9 138.62,71.9 138.68,71.84 UCPU1.B23
  BOTTOM w0.127: v2(187.33,27.36) 187.17,27.52 186.92,27.52 CD39.1
PCIE_PTX_SSDRX_N9_C: length 4.2
  BOTTOM w0.127: CD39.2 185.44,27.57 185.25,27.57 185.15,27.47 185.15,26.18 184.88,25.92 v4(184.65,25.92) 184.25,25.92 184.13,25.79 183.15,25.79 JNGFF2.11
PCIE_PTX_SSDRX_N10: length 84.7
  IN4 w0.091: v2(139.26,73.51) 139.83,74.08 139.83,74.58 141.17,75.93 145.52,75.93 145.69,75.76 146.99,75.76 147.45,75.29 151.74,75.29 152.17,74.86 157.03,74.86 158.42,73.47 158.42,72.5 158.84,72.08 160.22,72.08 161.37,70.93 163.14,70.93 169.63,64.44 169.63,63.82 169.49,63.68 169.49,61.36 170.11,60.74 170.11,59.16 171.6,57.68 171.6,56.84 173.92,54.51 173.92,52.93 174.97,51.89 174.97,51.38 176.23,50.12 176.23,48.47 181.4,43.3 181.4,38.35 182.92,36.83 182.92,32.64 186.02,29.53 187.16,29.53 v2(187.4,29.3)
  BOTTOM w0.076: UCPU1.D23 138.93,70.62 138.93,70.82 138.97,70.96 138.97,71.07 139.03,71.27 139.05,71.35 139.1,71.5 139.11,71.52 139.11,71.55 139.11,71.8 139.08,71.89 139.08,71.89 139.08,72.08 139.1,72.14 139.11,72.17 139.11,72.54 138.95,72.7 138.95,73.2 v2(139.26,73.51)
  BOTTOM w0.127: CD45.1 186.98,29.48 187.21,29.48 v2(187.4,29.3)
PCIE_PTX_SSDRX_N10_C: length 3
  BOTTOM w0.127: JNGFF2.23 183.15,28.79 183.9,28.79 184.04,28.93 184.49,28.93 184.83,29.27 185.05,29.49 185.43,29.49 CD45.2
PCIE_PTX_SSDRX_N11: length 93.8
  IN4 w0.091: v2(136.5,74.38) 136.6,74.28 136.76,74.28 137.33,74.85 138.07,74.85 140.52,77.3 146.15,77.3 146.28,77.16 147.58,77.16 147.63,77.11 147.63,77.1 147.99,76.75 147.99,76.75 148.01,76.73 154.18,76.73 154.43,76.49 156.85,76.49 157.49,77.12 159.26,77.12 160.27,78.13 164.3,78.13 166.83,75.6 166.83,72.82 169.42,70.23 169.42,69.53 170.5,68.45 170.5,65.57 171.07,65 171.07,63.23 170.92,63.08 170.92,61.9 172.77,60.05 172.77,59.55 175.54,56.78 175.54,54.27 178.45,51.36 178.45,50.08 182.91,45.62 182.91,39.73 185.36,37.27 185.36,33.65 186.49,32.52 187.66,32.52 188.01,32.17 188.01,31.66 187.81,31.45 187.6,31.45 v2(187.4,31.25)
  BOTTOM w0.076: v2(136.5,74.38) 136.64,74.24 137.05,74.24 137.4,73.89 137.4,73.39 138.06,72.73 138.06,71.9 138.25,71.71 138.25,71.62 138.41,71.47 138.41,71.21 138.12,70.92 UCPU1.D24
  BOTTOM w0.127: v2(187.4,31.25) 187.27,31.39 186.98,31.39 CD53.1
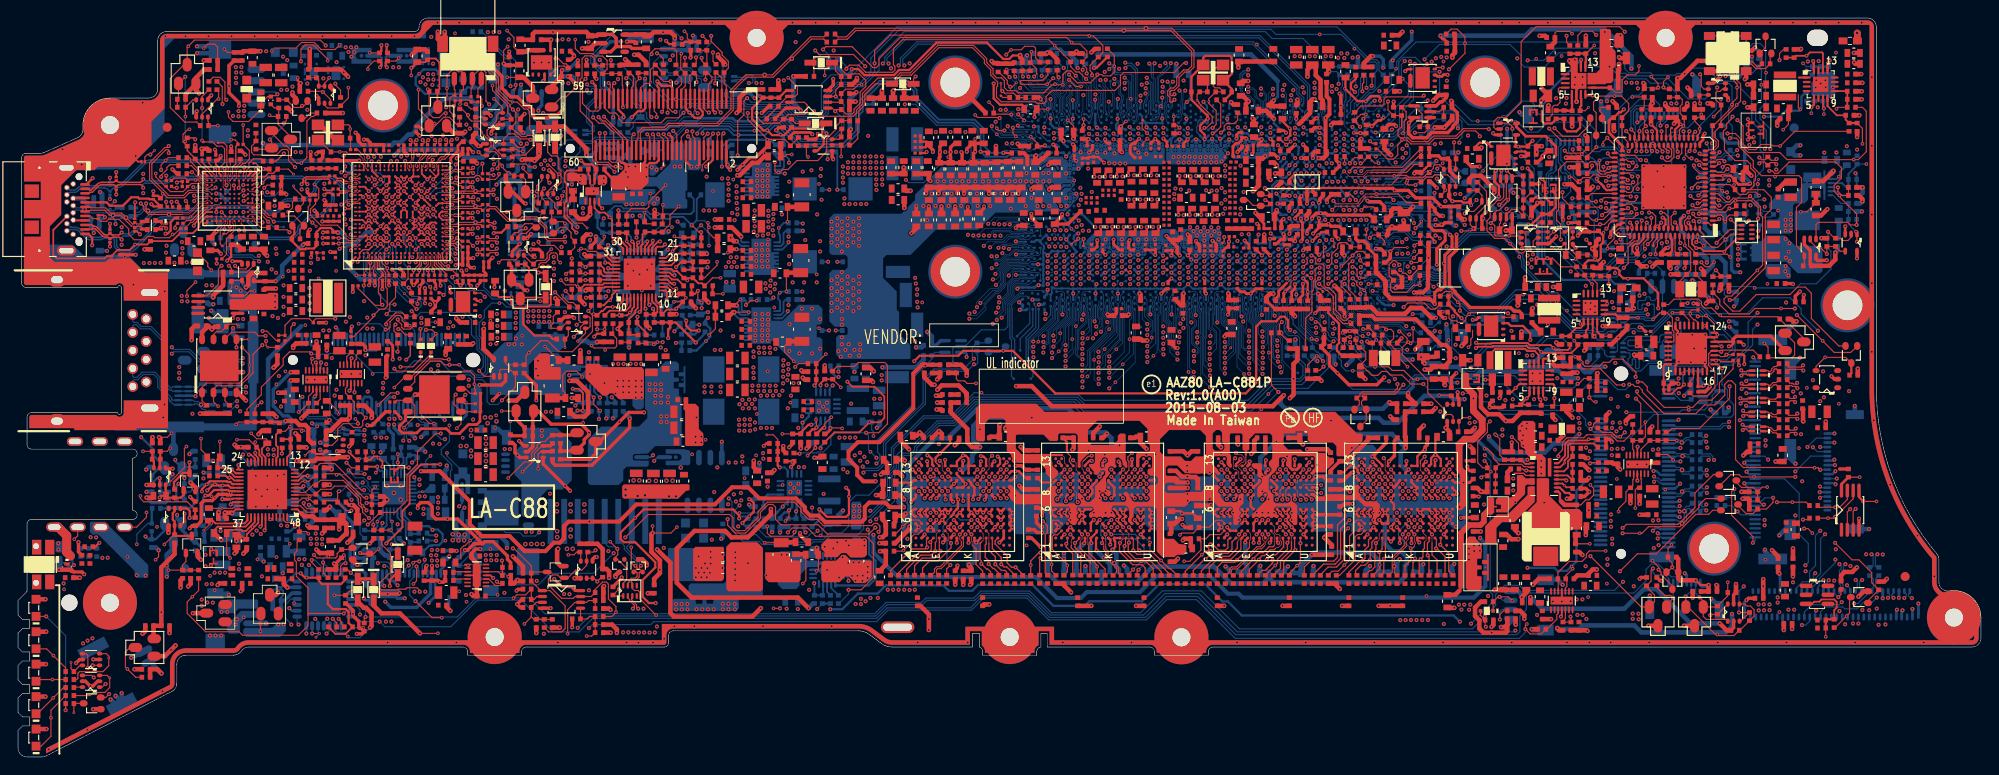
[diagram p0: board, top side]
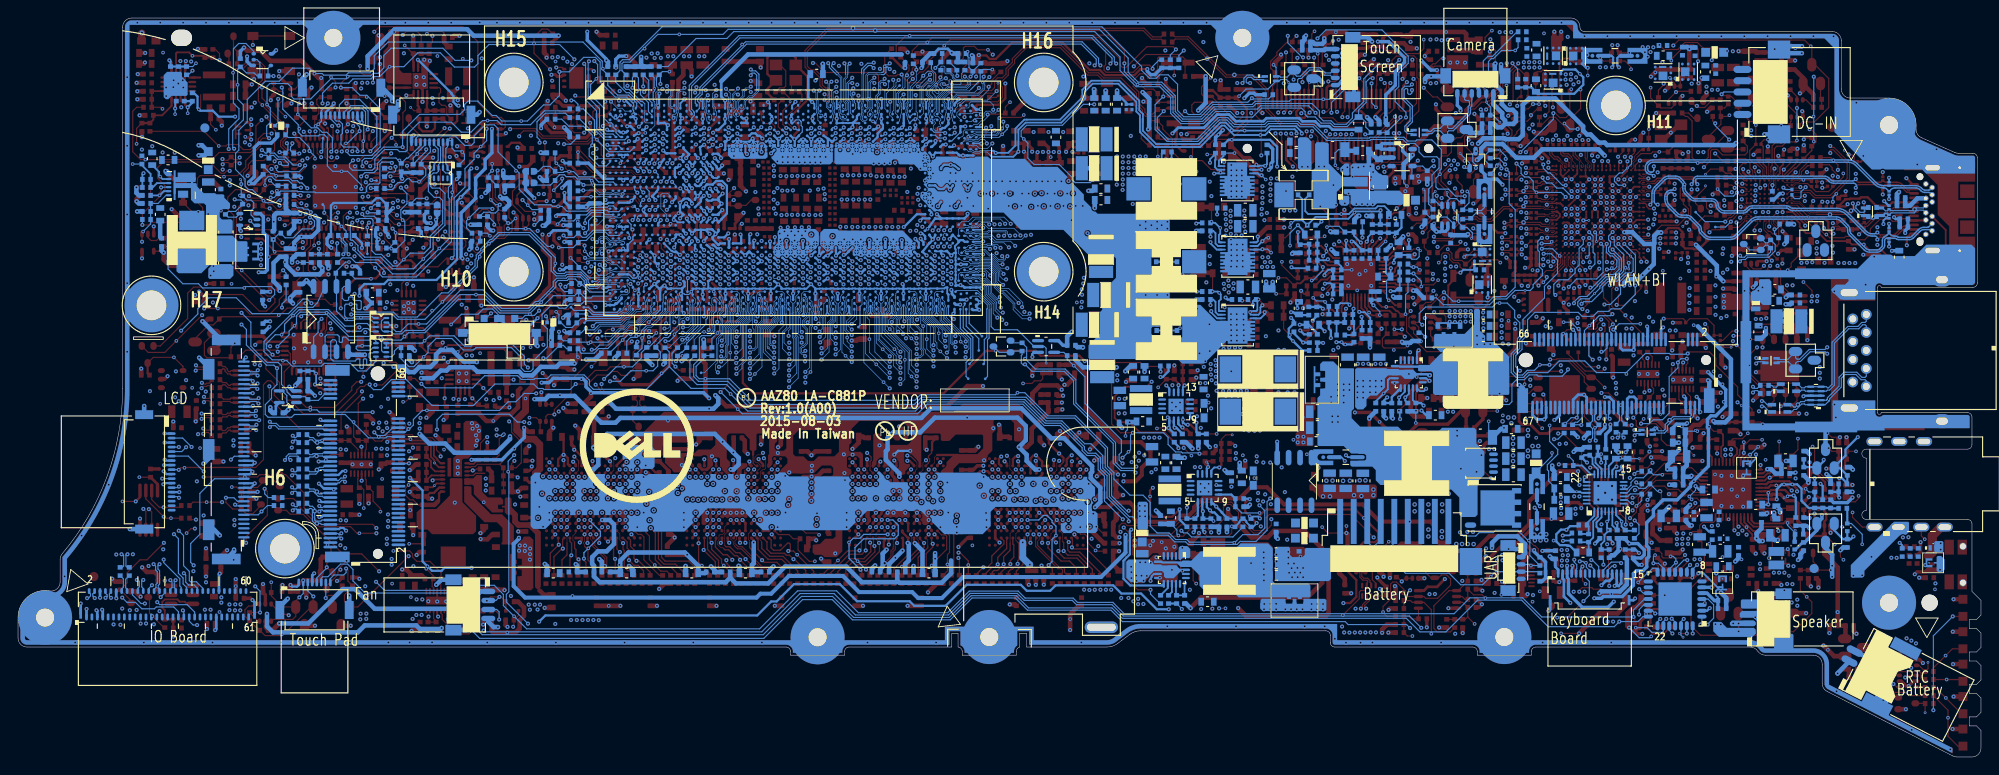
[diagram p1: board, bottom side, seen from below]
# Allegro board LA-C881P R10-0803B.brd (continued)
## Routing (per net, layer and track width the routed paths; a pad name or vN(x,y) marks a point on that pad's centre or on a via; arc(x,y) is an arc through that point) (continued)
PCIE_PTX_SSDRX_N11_C: length 3
  BOTTOM w0.127: CD53.2 185.43,31.39 184.76,31.39 184.26,31.89 183.93,31.89 183.83,31.79 JNGFF2.35
PCIE_PTX_SSDRX_P9: length 90.9
  IN4 w0.091: v2(187.33,28.03) 187.12,27.82 186.94,27.82 186.79,27.97 186.79,28.31 187.05,28.57 187.74,28.57 188.21,29.05 188.21,30.08 187.63,30.67 186,30.67 183.86,32.8 183.86,37.22 182.19,38.89 182.19,43.61 177.82,47.99 177.82,50.38 176.52,51.68 176.52,51.85 174.88,53.49 174.88,55.58 174.18,56.28 174.18,56.65 173.66,57.17 172.86,57.17 172.38,57.65 172.38,58.01 172.37,58.01 172.37,58.03 170.92,59.49 170.92,61.06 170.31,61.67 170.31,63.33 170.46,63.48 170.46,64.77 166.87,68.36 166.87,69.58 164.57,71.88 161.55,71.88 158.85,74.58 158.42,74.58 157.34,75.67 153.2,75.67 152.77,76.1 147.79,76.1 147.32,76.56 146,76.56 145.85,76.71 140.82,76.71 138.52,74.41 138.52,74.16 138.37,74.01 138.09,74.01 v2(137.92,74.18)
  BOTTOM w0.076: UCPU1.A23 138.68,72.12 138.63,72.07 138.46,72.07 138.39,72.14 138.39,72.72 138.55,72.88 138.55,73.52 137.92,74.16 v2(137.92,74.18)
  BOTTOM w0.127: v2(187.33,28.03) 187.08,27.78 186.84,27.78 186.67,27.95 CD43.1
PCIE_PTX_SSDRX_P9_C: length 4.2
  BOTTOM w0.127: CD43.2 185.42,27.82 185.15,27.82 184.89,27.57 v4(184.89,27.27) 184.89,26.29 184.78,26.17 184.2,26.17 184.07,26.29 JNGFF2.13
PCIE_PTX_SSDRX_P10: length 84.8
  IN4 w0.091: v2(187.4,29.93) 187.2,29.73 186.1,29.73 183.11,32.72 183.11,36.91 181.59,38.43 181.59,43.38 176.42,48.55 176.42,50.2 175.16,51.46 175.16,51.97 174.12,53.01 174.12,54.59 171.79,56.92 171.79,57.76 170.31,59.24 170.31,60.82 169.69,61.44 169.69,63.6 169.82,63.74 169.82,64.52 163.22,71.12 161.45,71.12 160.3,72.27 158.92,72.27 158.61,72.58 158.61,73.55 157.11,75.06 152.25,75.06 151.82,75.49 147.53,75.49 147.07,75.95 145.77,75.95 145.6,76.12 141.09,76.12 139.63,74.66 139.63,74.16 139.53,74.05 139.35,74.05 v2(139.26,74.14)
  BOTTOM w0.076: v2(139.26,74.14) 138.79,73.67 138.79,72.64 138.95,72.47 138.95,72.2 138.91,72.11 138.91,71.85 138.93,71.82 138.95,71.77 138.95,71.57 138.9,71.42 138.83,71.32 138.67,71.32 138.61,71.26 138.61,71.09 UCPU1.C23
  BOTTOM w0.127: CD46.1 186.99,29.74 187.21,29.74 v2(187.4,29.93)
PCIE_PTX_SSDRX_P10_C: length 3
  BOTTOM w0.127: JNGFF2.25 183.97,29.29 184.08,29.18 184.39,29.18 v4(184.65,29.45) 184.95,29.74 185.43,29.74 CD46.2
PCIE_PTX_SSDRX_P11: length 93.7
  IN4 w0.091: v2(136.5,73.8) 136.5,73.62 136.6,73.52 136.8,73.52 136.96,73.67 136.96,74.2 137.41,74.66 138.15,74.66 140.6,77.11 146.07,77.11 146.2,76.97 147.49,76.97 147.91,76.55 147.91,76.55 147.93,76.54 154.1,76.54 154.35,76.3 156.93,76.3 157.57,76.93 159.34,76.93 160.35,77.94 164.22,77.94 166.63,75.52 166.63,72.74 169.23,70.15 169.23,69.45 170.31,68.37 170.31,65.49 170.88,64.92 170.88,63.31 170.72,63.16 170.72,61.82 172.58,59.97 172.58,59.47 175.35,56.7 175.35,54.19 178.26,51.28 178.26,50 182.71,45.54 182.71,39.65 185.17,37.19 185.17,33.57 186.41,32.33 187.58,32.33 187.82,32.09 187.82,31.74 187.73,31.65 187.57,31.65 v2(187.38,31.84)
  BOTTOM w0.076: UCPU1.C24 138.12,71.16 138.01,71.05 137.92,71.05 137.72,71.26 137.72,71.36 138,71.64 138,71.73 137.89,71.83 137.89,72.66 137.23,73.32 137.23,73.83 136.98,74.08 136.7,74.08 136.5,73.87 v2(136.5,73.8)
  BOTTOM w0.127: CD51.1 186.99,31.64 187.18,31.64 v2(187.38,31.84)
PCIE_PTX_SSDRX_P11_C: length 3
  BOTTOM w0.127: JNGFF2.37 183.81,32.29 183.96,32.14 184.37,32.14 v4(184.65,31.86) 184.86,31.65 185.44,31.65 CD51.2
PCIE_PTX_TBRX_N1: length 106.6
  TOP w0.127: v2(48.12,68.46) 48.13,68.46 48.13,68.47 48.03,68.47 47.91,68.35 47.91,68.14 CT4.2
  IN1 w0.091: v2(48.12,68.46) 48.13,68.46 48.13,68.47 47.83,68.76 47.83,68.94 49.47,70.58 49.92,70.58 49.97,70.52 56.31,70.52 56.62,70.82 61.7,70.82 62.78,69.74 71.87,69.74 72.92,70.8 82.93,70.8 83.34,71.21 85.6,71.21 85.97,70.83 86.78,70.83 88.02,72.07 93.16,72.07 95.52,74.43 96.21,74.43 98.13,76.35 98.13,76.52 v2(98.35,76.74)
  BOTTOM w0.127: v2(98.35,76.74) 98.17,76.92 98.17,77.43 99.84,79.11 136.98,79.11 141.89,74.2 141.89,73.56 142.41,73.04 142.41,72.78 142.22,72.58 142.22,71.96 UCPU1.B17
PCIE_PTX_TBRX_N1_C: length 3.3
  TOP w0.076: UT1.Y22 46.18,65.14 46.41,65.36 46.41,65.76 46.43,65.78 46.43,65.78 46.76,66.12 46.81,66.12 46.82,66.13 46.82,66.13
  TOP w0.127: CT4.1 47.85,67.1 47.85,66.83 47.37,66.35 47.05,66.35 46.84,66.13 46.82,66.13
PCIE_PTX_TBRX_N2: length 112.4
  TOP w0.127: CT8.2 45.31,68.07 45.31,68.26 v2(45.52,68.46)
  IN1 w0.091: v2(45.52,68.46) 45.31,68.67 45.31,69 45.96,69.64 47.69,69.64 49.68,71.64 53.97,71.64 54.59,72.26 58.8,72.26 59.44,71.61 59.64,71.41 62.1,71.41 63.13,70.38 69.07,70.38 70.79,72.09 79.46,72.09 79.65,71.9 86.07,71.9 86.84,72.68 92.13,72.68 92.58,73.14 93.31,73.14 96.38,76.2 96.38,76.72 v2(96.6,76.95)
  BOTTOM w0.127: UCPU1.D16 143.07,70.88 142.77,71.19 142.77,71.49 142.82,71.55 142.82,71.63 143.07,71.88 143.07,74.43 137.71,79.8 98.67,79.8 96.42,77.55 96.42,77.12 v2(96.6,76.95)
PCIE_PTX_TBRX_N2_C: length 2.7
  TOP w0.076: 44.78,66.29 44.77,66.29 44.76,66.29 44.74,66.29 44.56,66.11 44.56,65.34 UT1.T22
  TOP w0.127: 44.78,66.29 44.79,66.28 45.26,66.76 45.26,67.18 CT8.1
PCIE_PTX_TBRX_P1: length 106.6
  TOP w0.127: CT2.2 47.66,68.13 47.66,68.4 47.57,68.49 v2(47.49,68.49)
  IN1 w0.091: v2(97.71,76.74) 97.94,76.52 97.94,76.43 96.13,74.62 95.44,74.62 93.08,72.26 87.94,72.26 86.7,71.03 86.05,71.03 85.68,71.4 83.26,71.4 82.85,70.99 72.84,70.99 71.79,69.94 62.86,69.94 61.78,71.02 56.54,71.02 56.23,70.71 50.05,70.71 50,70.77 49.39,70.77 47.64,69.02 47.64,68.64 v2(47.49,68.49)
  BOTTOM w0.127: UCPU1.A17 142.51,72.4 142.67,72.56 142.67,73.15 142.15,73.67 142.15,74.3 137.09,79.36 99.74,79.36 97.91,77.54 97.91,76.95 97.79,76.82 97.79,76.82 v2(97.71,76.74)
PCIE_PTX_TBRX_P1_C: length 3.4
  TOP w0.076: 46.66,66.3 46.64,66.28 46.64,66.23 46.31,65.9 46.08,65.9 45.95,65.77 45.95,65.47 46.03,65.39 46.13,65.39 46.18,65.44 UT1.Y23
  TOP w0.127: 46.66,66.3 46.66,66.31 46.95,66.6 47.26,66.6 47.6,66.94 47.6,67.23 CT2.1
PCIE_PTX_TBRX_P2: length 112.5
  TOP w0.127: CT6.2 44.86,67.94 45.06,68.14 45.06,68.31 v2(44.91,68.46)
  IN1 w0.091: v2(44.91,68.46) 45.12,68.68 45.12,69.08 45.88,69.83 47.61,69.83 49.6,71.83 53.89,71.83 54.51,72.45 58.88,72.45 59.58,71.75 59.72,71.61 62.18,71.61 63.21,70.57 68.99,70.57 70.71,72.29 79.54,72.29 79.73,72.09 85.99,72.09 86.76,72.87 92.05,72.87 92.5,73.33 93.23,73.33 96.18,76.28 96.18,76.72 v2(95.96,76.95)
  BOTTOM w0.127: v2(95.96,76.95) 96.16,77.15 96.16,77.65 98.56,80.05 137.81,80.05 143.33,74.53 143.33,71.78 143.07,71.53 UCPU1.C16
PCIE_PTX_TBRX_P2_C: length 2.7
  TOP w0.076: 44.61,66.46 44.6,66.45 44.6,66.38 44.4,66.18 44.4,66.04 44.11,65.75 44.11,65.5 44.2,65.41 44.29,65.41 44.34,65.47 UT1.T23
  TOP w0.127: CT6.1 45.01,67.16 45.01,66.86 44.61,66.46
PCIE_PTX_WLANRX_N5: length 132.2
  IN1 w0.091: v2(141.22,72.86) 141.22,72.94 141.08,73.08 140.89,73.08 140.69,72.88 140.69,72.64 140.05,72 138.67,72 137.95,71.28 129.52,71.28 129.16,70.92 127.51,70.92 127.15,71.28 126.75,71.28 126.31,70.85 123.44,70.85 122.43,71.87 118.73,71.87 117.28,73.31 115.01,73.31 114.91,73.41 112.7,73.41 111.95,72.66 108.82,72.66 106.01,69.86 100.03,69.86 99.8,70.09 93.73,70.09 92.66,69.02 91.05,69.02 90.4,69.68 88.13,69.68 87.39,68.94 79.78,68.94 77.99,67.15 65.01,67.15 63.22,65.36 63.22,63.74 58.47,58.99 58.47,57.03 56.01,54.57 51.79,54.57 50.68,53.46 50.02,53.46 49.29,52.73 48.86,52.73 48.66,52.53 48.66,50.78 45.95,48.07 45.95,46.43 44.07,44.56 44.07,40.8 42.19,38.92 41.63,38.92 40.69,37.98 40.69,37.17 40.01,36.48 40.01,35.65 40.21,35.44 v2(40.31,35.44)
  BOTTOM w0.076: UCPU1.C19 141.16,70.76 141.07,70.67 140.95,70.67 140.88,70.74 140.88,70.8 140.84,70.84 140.84,71.2 140.98,71.35 141.29,71.35 141.38,71.43 141.43,71.57 141.43,71.75 141.37,71.94 141.37,72.09 141.43,72.21 141.43,72.71 141.28,72.86 v2(141.22,72.86)
  BOTTOM w0.127: CH11.1 40.16,36.03 40.08,35.95 40.08,35.53 40.17,35.44 v2(40.31,35.44)
PCIE_PTX_WLANRX_N5_C: length 2
  BOTTOM w0.127: CH11.2 40.12,37.31 40.12,37.96 40.25,38.09 40.25,38.77 JNGFF1.29
PCIE_PTX_WLANRX_P5: length 132.3
  IN1 w0.091: v2(39.65,35.44) 39.81,35.6 39.81,36.56 40.5,37.25 40.5,38.06 41.55,39.11 42.11,39.11 43.88,40.88 43.88,44.64 45.75,46.51 45.75,48.15 48.46,50.86 48.46,52.61 48.78,52.92 49.21,52.92 49.94,53.65 50.6,53.65 51.71,54.76 55.93,54.76 58.28,57.11 58.28,59.07 63.03,63.82 63.03,65.44 64.93,67.34 77.91,67.34 79.7,69.14 87.31,69.14 88.05,69.87 90.48,69.87 91.13,69.21 92.58,69.21 93.65,70.28 99.88,70.28 100.11,70.05 105.93,70.05 108.74,72.86 111.87,72.86 112.62,73.61 114.99,73.61 115.09,73.51 117.36,73.51 118.81,72.06 122.51,72.06 123.52,71.04 126.23,71.04 126.67,71.47 127.23,71.47 127.59,71.11 129.08,71.11 129.44,71.47 137.87,71.47 138.59,72.2 139.97,72.2 140.5,72.72 140.5,72.96 140.81,73.28 141.11,73.28 v2(141.28,73.44)
  BOTTOM w0.076: v2(141.28,73.44) 141.59,73.12 141.59,72.18 141.56,72.08 141.56,71.89 141.59,71.8 141.59,71.55 141.58,71.5 141.53,71.35 141.53,71.24 141.52,71.18 141.38,70.69 141.38,70.58 UCPU1.D19
  BOTTOM w0.127: v2(39.65,35.44) 39.74,35.44 39.83,35.53 39.83,35.83 39.64,36.03 CH12.1
PCIE_PTX_WLANRX_P5_C: length 2
  BOTTOM w0.127: JNGFF1.27 39.75,38.77 39.75,38.03 39.86,37.92 39.86,37.33 CH12.2
PCIE_RBIAS: length 18.8
  TOP w0.203: UT1.N16 v2(42.82,62.79)
  TOP w0.305: RT1.2 49.25,68.28 48.81,67.85 48.81,67.26 48.01,66.46 v2(48.01,66)
  IN3 w0.102: v2(42.82,62.79) 42.93,62.68 43.56,62.68 44.55,61.69 46.24,61.69 46.76,62.21 46.76,64.16 46.34,64.58 44.61,64.58
  IN3 w0.152: 43.94,63.91 v2(42.82,62.79)
  IN3 w0.254: v2(48.01,66) 47.87,66 47.47,65.6 45.63,65.6 43.94,63.91
PCIE_RCOMPN: length 2
  TOP w0.305: v3(148.21,69.25) 148.93,69.25 v2(148.95,69.23) 148.95,69.22 RC45.1
  BOTTOM w0.254: UCPU1.F5 149.46,68.96 v2(148.95,69.23)
PCIE_RCOMPP: length 3.4
  TOP w0.305: 149.58,70.14 150.06,70.14 v2(150.22,69.99) 150.23,69.99 150.89,70.64 151.2,70.64 v3(151.51,70.96)
  BOTTOM w0.254: v2(150.22,69.99) 149.82,69.99 149.43,69.59 UCPU1.E5
PCIE_WAKE#: length 227.4
  TOP w0.127: UE5.B8 187.21,62.77 186.91,62.77 v2(186.46,62.32) ; v3(46.15,37) 45.67,37 45.62,37.05 45.02,37.65 v2(44.86,37.65)
  IN1 w0.089: v2(186.46,62.32) 186.21,62.32 185.76,61.86 182.57,61.86 181.64,60.92 181.64,58.99 180.9,58.25 179.5,58.25 178.38,57.13 178.38,54.8 178.63,54.56 178.63,53.52 178.14,53.03 176.26,53.03 175.13,51.91 175.13,50.96 175.54,50.55 175.54,49.08 174.74,48.28 174.74,47.85 172.11,45.22 172.11,43.57 171.7,43.17 171.7,39.54 169.9,37.74 169.9,35.17 172.31,32.76 172.31,21.17 171.56,20.42 162.75,20.42 161.39,19.06 158.71,19.06 156.91,17.27 152.35,17.27 150.98,15.9 134.14,15.9 131.96,18.08 126.77,18.08 125.92,17.23 116.65,17.23 116.11,17.78 112.12,17.78 111.66,18.23 103.14,18.23 101.45,19.91 96.49,19.91 94.18,22.22 92.58,22.22 89.19,25.6 82.86,25.6 81.98,24.71 79.29,24.71 78.61,25.4 76.13,25.4 71.34,20.61 69.26,20.61 66.9,18.25 66.35,18.25 64.52,20.08 63.29,20.08 62.42,20.95 54.98,20.95 54.77,20.74 52.27,20.74 50.9,19.37 49.64,19.37 48.22,17.95 47.05,17.95 47.03,17.94 43.8,17.94 43.54,18.2 43.54,19.72 42.51,20.74 42.51,21.79 41.92,22.39 41.03,22.39 37.78,25.63 37.78,31.36 39.26,32.84 40.2,32.84 42.34,34.98 42.34,35.42 44.58,37.65 v2(44.86,37.65)
  BOTTOM w0.127: RE120.2 45.47,37.65 v2(44.86,37.65) 44.75,37.76 JNGFF1.47 ; RE86.1 v2(186.46,62.32)
PD_EE_CLK: length 23.9
  TOP w0.127: v2(26.49,63.61) 26.15,63.61 U722.A3 ; v2(27.46,46.73) 26.68,46.73 26.28,47.14 23.71,47.14 22.96,46.39 UT6.6
  IN1 w0.081: v2(27.46,46.73) 27.69,46.97 27.69,48.61 27.63,48.67 27.63,53.04 25.48,55.19 25.48,56.88 25.94,57.34 25.94,63.06 v2(26.49,63.61)
PD_EE_CS#: length 31.9
  TOP w0.076: U722.B3 v2(24.99,63.47)
  TOP w0.127: v2(24.85,45.45) 25.69,44.61 v1(25.69,43.46) 25.69,42.6 24.58,41.49 20.89,41.49 20.42,41.02 UT6.1 20.42,39.53 R1477.2
  IN1 w0.081: v2(24.99,63.47) 25.52,62.95 25.52,57.51 25.06,57.06 25.06,55.02 26.89,53.19 26.89,49.94 26.42,49.48 26.42,48.03 24.85,46.46 v2(24.85,45.45)
PD_EE_DI: length 26.3
  TOP w0.076: U722.B4 25.76,62.72 26.44,62.72 v2(26.49,62.77)
  TOP w0.127: v2(24.24,45.45) 24.23,45.45 UT6.5 v1(25.57,46.34)
  IN1 w0.081: v2(26.49,62.77) 26.49,62.67 26.15,62.33 26.15,57.26 25.69,56.8 25.69,55.28 27.84,53.13 27.84,48.76 27.98,48.62 27.98,46 26.65,44.67 24.46,44.67 24.24,44.9 v2(24.24,45.45)
PD_EE_DO: length 34.5
  TOP w0.127: R1475.2 27.71,64.32 v2(27.12,63.72) 27.12,63.62 26.7,63.21 26.25,63.21 U722.A4 ; v2(27.1,45.7) 26.07,44.67 26.07,42.6 24.66,41.19 22.06,41.19 21.69,40.83 UT6.2 21.69,39.43 v3(22.2,38.92)
  IN1 w0.081: v2(27.1,45.7) 26.63,46.17 26.63,49.39 27.1,49.86 27.1,53.28 25.27,55.11 25.27,56.97 25.73,57.43 25.73,63.41 26.33,64.01 26.83,64.01 v2(27.12,63.72)
PD_EE_WP#: length 1.6
  TOP w0.127: UT6.3 22.96,39.53 R1474.2
PD_HOLD#: length 3.9
  TOP w0.127: v1(24.49,47.77) 24.23,48.03 23.39,48.03 R1476.2 22.57,47.2 22.01,47.2 21.69,46.88 UT6.7
PD_OVP: length 2
  TOP w0.127: PR288.1 91.39,68.86 PR253.2 91.09,68.55 PQ218.6
PD_SENSEN: length 32.8
  TOP w0.076: v2(27.13,59.32) 26.73,59.32 26.07,59.97 U722.A10
  TOP w0.127: v3(39.02,78.14) PR236.2
  TOP w0.254: PR236.2 40.32,78.35 v2(40.32,78.99)
  IN1 w0.254: v2(40.32,78.99) 40.36,78.94 40.36,78.34 39.73,77.7 38.63,77.7 37.37,76.44 37.37,75.34 35.07,73.05 34.12,73.05 30.15,69.08 30.15,67.08 30.6,66.63 31,66.63 31.39,67.01 v2(31.39,67.11)
  IN3 w0.254: v2(27.13,59.32) 27.13,59.47 27.66,60.01 28.86,60.01 29.38,60.53 29.38,62.12 29.23,62.27 29.23,64.71 31.27,66.75 31.27,66.99 v2(31.39,67.11)
PD_SENSEP: length 29.8
  TOP w0.076: v2(26.73,59.84) 26.34,60.23 25.76,60.23 25.51,59.97 U722.B10
  TOP w0.254: PR238.2 40.9,78.23 40.9,78.98 v2(40.92,78.99)
  IN1 w0.254: v2(30.8,67.13) 30.53,67.39 30.53,68.92 34.28,72.67 35.23,72.67 37.75,75.18 37.75,76.28 38.79,77.32 39.89,77.32 40.87,78.31 40.87,78.94 v2(40.92,78.99)
  IN3 w0.254: v2(30.8,67.13) 30.87,67.05 30.87,66.89 28.85,64.87 28.85,62.11 29,61.96 29,60.69 28.7,60.39 27.51,60.39 26.96,59.84 v2(26.73,59.84)
PECI_EC: length 78.7
  IN2 w0.089: v2(157.88,68.11) 157.71,67.94 157.71,66.97 159.58,65.1 161.88,65.1 162.54,64.44 166.04,64.44 166.11,64.37 168.02,64.37 168.25,64.6 171.43,64.6 171.53,64.49 174.62,64.49 174.7,64.57 175.35,64.57 175.58,64.34 175.58,64.33 175.66,64.25 175.66,63.52 v2(175.33,63.19)
  IN4 w0.081: v2(157.88,68.11) 157.75,68.11 157.34,68.51 155.12,68.51 154.69,68.94 151.69,68.94 151.61,68.87 150.44,68.87 149.66,69.66 149.66,69.88 148.92,70.62 145.57,70.62 145.06,70.11 145.06,67.7 144.83,67.48 138.02,67.48 137.39,68.11 128.52,68.11 128.41,68.22 126.93,68.22 126.59,68.56 126.59,70.19 125.73,71.05 125.33,71.05 122.44,73.95 121.41,73.95 120.68,74.68 120.68,75.12 v2(120.7,75.14)
  BOTTOM w0.076: UCPU1.A54 121.34,72.47 121.45,72.58 121.45,73.64 120.63,74.46 120.63,75.07 v2(120.7,75.14)
  BOTTOM w0.127: RE61.2 174.89,57.3 174.89,59.41 175.34,59.85 175.34,60.72 174.66,61.4 174.66,62.51 v2(175.33,63.19)
PECI_EC_R: length 4.3
  TOP w0.127: UE5.A48 176.91,59.52 176.48,59.09 176.48,58.86 v2(176.25,58.63)
  BOTTOM w0.127: CE68.1 176.63,56.47 RE61.1 175.92,57.19 v3(175.92,58.16) 175.92,58.3 v2(176.25,58.63)
PME#: length 1.1
  TOP w0.127: v2(145.39,52.49) 145.5,52.49 T115.1
  BOTTOM w0.076: UCPU1.AU11 145.7,52.8 v2(145.39,52.49)
POWER_SW_IN#: length 13.3
  TOP w0.127: RE31.2 188.93,53.3 RE33.1 ; RE31.2 189.81,53.32 CE49.1 ; RE31.2 188.95,53.45 v2(188.39,54.01) ; v2(185.92,59.48) 186.11,59.29 UE5.B67
  IN2 w0.089: v2(185.92,59.48) 186.28,59.85 188.01,59.85 188.62,59.24 188.62,58.44 188.04,57.85 188.04,56.85 188.52,56.37 188.52,54.14 v2(188.39,54.01)
  BOTTOM w0.127: RE33.1 188.06,53.68 v2(188.39,54.01)
PS_ID: length 190.7
  TOP w0.127: v2(30.74,65.45) 30.01,66.18 30.01,67.23 29.82,67.42 29.29,67.42 28.68,66.81 26.19,66.81 25.92,67.08 25.92,67.78 26.39,68.26 PR103.2 PR102.2 ; v2(182.4,66.53) 182.83,66.1 183.29,66.1 183.74,66.56 183.74,67.5 183.61,67.63 UE5.B24
  IN1 w0.081: v2(182.4,66.53) 182.47,66.53 182.86,66.15 183.21,66.15 183.54,66.48 183.54,69.46 184.18,70.11 184.18,72.37 v2(184.02,72.53)
  IN3 w0.089: v2(156.07,77.41) 156.03,77.45 155.19,77.45 154.53,78.11 151.76,78.11 151.04,78.84 93,78.84 90.76,76.59 85.1,76.59 84.04,75.54 80.19,75.54 79.14,76.59 70.83,76.59 68.68,78.74 63.27,78.74 62.76,78.23 62.43,78.23 61.96,78.7 57.87,78.7 52.97,73.81 52.97,72.13 52.62,71.78 52.19,71.78 51.3,70.89 51.3,69.67 48.69,67.06 45.36,67.06 44.65,66.35 44.25,66.35 43.27,67.33 34.07,67.33 33.05,66.31 31.6,66.31 v2(30.74,65.45)
  BOTTOM w0.127: v2(156.07,77.41) 157.72,79.06 165.55,79.06 166.78,77.83 166.78,76.94 167.15,76.56 169.38,76.56 170.96,78.14 173.46,78.14 175,76.6 v3(176.58,76.6) 177.68,75.5 178.4,75.5 178.65,75.24 180.65,75.24 181.12,74.77 182.91,74.77 184.02,73.66 v2(184.02,72.53)
PTP_DIS#: length 162.8
  BOTTOM w0.127: UE4.21 37.5,15.58 38.06,15.02 v2(40.13,15.02) 40.69,14.46 48.02,14.46 50.97,17.41 55.85,17.41 59.37,13.88 62.26,13.88 63.77,15.39 95.28,15.39 96.43,16.54 105.69,16.54 107.04,17.9 112.05,17.9 114.46,15.49 125.1,15.49 127.43,17.82 130.87,17.82 135.12,13.57 166.3,13.57 166.65,13.91 166.65,15.63 167.37,16.35 167.37,17.98 167.59,18.2 179.3,18.2 180.65,19.54 180.65,20.81 181.24,21.41 182.02,21.41 183.43,20 184,20 184.16,19.84 184.16,19.36 JTP1.6
PTP_INT#_EC: length 98.5
  TOP w0.127: v2(179.17,65.96) 179.17,65.97 179.15,66 179.15,66.02 179.1,66.07 178.69,66.07 178.49,66.27 178.01,66.27 UE5.B37 ; v2(188.47,57.06) 189.92,58.51 191.24,58.51 RPE5.2 ; v3(181.36,21.76) 182.04,21.08 v2(182.04,20.79) 182.31,20.52 182.31,20.24 183.57,18.98 Q40.1
  IN1 w0.081: v2(172.29,53.88) 172.29,58.13 173.18,59.03 173.18,60.86 173.78,61.46 173.78,62.89 174.56,63.68 175.62,63.68 176.3,63 176.63,63 177.44,63.8 177.44,64.82 178.58,65.96 v2(179.17,65.96) ; v2(182.04,20.79) 182.68,21.42 182.68,42.87 187.65,47.84 188.42,47.84 189.93,49.35 190.97,49.35 191.14,49.52 191.14,51 190.53,51.61 190.53,53.13 189.6,54.06 189.6,54.95 188.47,56.08 v2(188.47,57.06)
  IN3 w0.089: v2(172.29,53.88) 169.06,53.88 164.61,49.43 161.16,49.43 160.85,49.11 159.44,49.11 v2(159.23,48.91)
  IN4 w0.081: v2(188.47,57.06) 188.08,57.06 186.56,58.57 185.18,58.57 184.23,59.52 184.23,61.01 180.33,64.91 179.52,64.91 179.17,65.27 v2(179.17,65.96)
  BOTTOM w0.127: v2(159.23,48.91) 159.11,48.78 DZ3.1
PTP_INT#_R: length 5.8
  TOP w0.127: v3(183.47,23.53) 183.08,23.15 R1299.2 183.08,21.98 183.55,21.51 v2(183.55,21.05) 183.02,20.52 Q40.3
  BOTTOM w0.127: JTP1.5 184.66,19.36 184.66,19.87 183.55,20.98 v2(183.55,21.05)
PWM1_GT: length 15.3
  TOP w0.127: v2(80.77,50.16) 80.8,50.16 81.27,50.64 v3(81.97,50.64)
  TOP w0.203: PU1000.12 71.63,52.16 72.01,52.16 72.49,51.68 v2(72.49,51.39)
  IN3 w0.203: v2(80.77,50.16) 80.77,50.18 80.82,50.18 80.82,50.19 80.8,50.21 80.8,50.58 80.11,51.27 74.32,51.27 73.71,50.66 72.9,50.66 72.49,51.06 v2(72.49,51.39)
  BOTTOM w0.203: v2(80.77,50.16) 80.77,50.18 80.82,50.18 80.82,50.19 80.8,50.21 80.8,50.57 80.6,50.76 PR1117.1 80.29,50.63 80.29,49.61 80.43,49.48 PU1102.8
PWM2_GT: length 15.2
  TOP w0.127: PU1000.13 71.51,52.56 72.03,52.56 72.64,51.95 v2(73.03,51.95)
  TOP w0.508: v2(80.24,57.74) 79.22,58.76 PR1108.1
  IN3 w0.203: v2(80.24,57.74) 79.5,57.74 78.77,57.01 78.77,56.02 77.78,55.03 77.78,54.21 75.79,52.23 73.3,52.23 v2(73.03,51.95)
  BOTTOM w0.203: PU1101.8 80.39,57.1 80.24,57.25 v2(80.24,57.74)
PWM_IA: length 23.8
  TOP w0.203: PU1000.22 70.36,56.52 71.04,57.21 v2(71.22,57.21)
  IN4 w0.203: v2(79.43,65.59) 79.48,65.64 80.08,65.64 80.77,64.95 80.77,59.4 78.25,56.88 73.36,56.88 72.31,55.84 71.73,55.84 71.22,56.34 v2(71.22,57.21)
  BOTTOM w0.203: PR1104.1 79.22,65.79 v2(79.43,65.59) 79.45,65.62 80.09,65.62 80.14,65.57 PU1100.8
PWM_VSA: length 7.3
  TOP w0.203: PU1000.30 67.16,56.4 65.91,57.64 65.91,59.62 v3(65.66,59.88) 65.13,60.41 64.47,60.41 63.97,60.91 PU1305.3
PWR_SRC_LIMIT: length 115.1
  TOP w0.127: U722.G10 23.01,60.04 v2(22.6,60.45) ; PR216.1 57.81,60.49 57.28,61.02 v2(57.28,62.24) ; PU201.1 90.33,72.01 v2(90.68,71.66) 90.86,71.84 PC205.1 91.4,71.84 91.89,71.35 92.58,71.35 92.77,71.55 92.77,71.89 93.45,72.56 93.45,73.78 94.06,74.4 94.06,75.08 93.33,75.81 92.54,75.81 PR227.2 92.15,75.52 91.36,76.32 91.36,77.54 91.22,77.68 88.56,77.68 PD201.2 88.32,76.66 PR226.2
  IN1 w0.081: v2(57.28,62.24) 57.28,61.58 55.6,59.9 52.35,59.9 v2(52.15,60.11)
  IN3 w0.089: v2(52.15,60.11) 52.03,59.99 52.03,53.64 51.33,52.94 49.94,52.94 49.54,52.55 49.54,52.13 48.88,51.47 47.65,51.47 47.45,51.67 46.79,51.67 46.48,51.37 38.75,51.37 37.9,52.22 37.9,53.7 37.08,54.53 34.57,54.53 33.24,55.86 31.17,55.86 30.27,56.77 29.26,56.77 28.92,57.11 25.26,57.11 24.11,58.26 24.11,59.15 23.65,59.61 23.06,59.61 22.6,60.08 v2(22.6,60.45)
  BOTTOM w0.127: v2(90.68,71.66) 91.39,70.95 91.39,69.75 90.2,68.56 87,68.56 84.62,70.94 83.57,70.94 82.81,70.19 79.5,70.19 79.15,70.54 75.79,70.54 75.44,70.19 74.02,70.19 72.5,68.67 67.89,68.67 67.79,68.77 64.03,68.77 63.6,68.35 62.72,68.35 62.6,68.48 60.94,68.48 59.88,67.42 59.88,65.26 60.03,65.11 v3(60.03,64.67) 60.48,64.22 60.48,63.24 60.25,63.01 59.09,63.01 58.32,62.24 v2(57.28,62.24)
PWR_SRC_ON: length 186.9
  TOP w0.127: PR218.2 61.18,49.98 59.59,51.56 v2(59.59,51.57) ; UE5.B42 178.26,63.77 178.47,63.56 179,63.56 v2(179.22,63.78)
  IN3 w0.089: v2(50.14,69.73) 50.58,70.17 50.58,72.34 58.51,80.26 69.98,80.26 71.39,78.84 72.17,78.84 72.35,79.02 73.33,79.02 73.66,78.69 78.57,78.69 80.64,76.62 83.6,76.62 84.68,77.69 89.11,77.69 89.74,78.33 89.74,78.83 90.87,79.96 151.5,79.96 152.27,79.18 155.17,79.18 155.49,79.51 158.19,79.51 158.73,80.04 167.83,80.04 168.37,79.51 172.27,79.51 177.6,74.18 178.99,74.18 v2(179.63,74.81)
  IN4 w0.081: v2(52.64,65.2) 52.64,65.2 52.14,65.7 52.14,66.1 51.71,66.53 51.71,68.08 50.14,69.65 v2(50.14,69.73)
  IN4 w0.089: v2(179.63,74.81) 178.33,73.52 178.33,72.98 177.5,72.14 177.5,71.23 177.69,71.04 177.69,69.27 177.93,69.03 177.93,64.04 178.36,63.61 179.05,63.61 v2(179.22,63.78)
  BOTTOM w0.127: v2(52.64,65.2) 52.35,64.91 52.35,64.76 52.34,64.75 52.34,64.4 52.35,64.39 52.35,61.39 51.69,60.73 51.69,52.13 52.74,51.08 54.07,51.08 54.61,50.53 54.93,50.53 54.98,50.58 v3(57.95,50.58) 58.6,50.58 v2(59.59,51.57)
PWR_SRC_ON_PC: length 53.2
  TOP w0.076: 24.77,59.17 24.77,59.7 24.51,59.95 U722.D10
  TOP w0.127: 24.77,59.17 25.12,58.81 v2(25.12,58.43)
  TOP w0.508: v2(59.61,50.91) 59.86,50.67 PR229.2
  IN2 w0.508: v2(29.46,49.06) 30.74,50.35 30.74,56.24 28.55,58.43 v2(25.12,58.43)
  IN3 w0.406: v2(29.46,49.06) 31.13,49.06 36.81,43.39 38.33,43.39 38.92,42.8 41.15,42.8 41.58,42.38 43.89,42.38 51.05,49.54 52.02,49.54 52.88,50.4 54.99,50.4 55.51,50.91 v2(59.61,50.91)
PWR_TB_DOCK#: length 249.1
  TOP w0.127: v2(30,60.49) 30.46,60.94 30.46,61.63 R1440.2
  IN1 w0.089: v2(40.82,15.02) 40.82,14.72 42.27,13.26 49.53,13.26 51.14,14.88 53.67,14.88 53.69,14.85 53.7,14.85 54.37,14.18 58.57,14.18 59.44,15.05 70.37,15.05 71.03,15.71 94.04,15.71 94.84,16.51 100.72,16.51 102.07,15.16 115.36,15.16 116.36,14.16 126.31,14.16 127.79,15.63 130.94,15.63 133.05,13.52 174.88,13.52 180.7,19.34 180.7,25.49 178.48,27.7 178.48,30.86 179.17,31.56 179.17,34.63 180.32,35.77 180.32,40.5 179.72,41.09 179.21,41.09 178.99,40.88 177.67,40.88 176.56,41.99 176.56,43.97 176.93,44.35 178.35,44.35 179.05,45.04 182.94,45.04 186.35,48.46 187.11,48.46 v2(188.52,49.87)
  IN2 w0.089: v2(30,60.49) 30,59.04 31.17,57.87 31.17,48.53 32.65,47.04 32.65,45.75 34.87,43.53 34.87,41.46 34.3,40.89 34.3,39.32 34.77,38.85 34.77,32.53 35.27,32.03 35.27,31.47 33.98,30.18 33.98,25.66 34.37,25.27 34.37,23.06 33.21,21.9 33.21,21.15 37.82,16.54 38.91,16.54 40.03,15.43 40.41,15.43 v2(40.82,15.02)
  BOTTOM w0.127: RE35.2 188.06,50.72 188.52,50.26 v2(188.52,49.87)
PWRBTN_LED#: length 66.3
  TOP w0.127: v2(181.24,59.85) 181.24,59.1 181.11,58.97 UE5.B57
  IN4 w0.081: v2(181.24,59.85) 181.24,59.67 182.76,58.14 186.39,58.14 187.8,56.73 187.8,54.62 187.62,54.44 187.62,53.73 189.38,51.97 189.38,50.22 193.5,46.1 193.5,34.25 193.82,33.93 194.96,33.93 195.8,33.09 195.8,26.08 198.17,23.71 200.4,23.71 201.47,22.64 203.2,22.64 205.16,20.68 205.16,19.39 203.09,17.32 202.5,17.32 v2(202.36,17.18)
  BOTTOM w0.127: JIO1.41 198.21,15.54 198.21,16.08 199.03,16.9 202.08,16.9 v2(202.36,17.18) ; v2(181.24,59.85) v1(180.65,59.85)
REM_DIODE1_N: length 74.3
  TOP w0.127: UE5.B13 186.96,65.27 186.54,65.69 v2(186.55,65.7) ; v2(138.35,63.13) 138.96,62.52 CE47.1 138.06,62.29 QE3.3
  IN3 w0.127: v2(138.35,63.13) 138.48,63 138.48,62.62 139.01,62.09 140.64,62.09 141.38,61.34 142.45,61.34 142.95,60.84 144.84,60.84 145.41,60.27 151.7,60.27 153.54,62.11 157.33,62.11 157.86,62.65 157.86,64.53 160.45,67.12 162.48,67.12 164.53,69.16 169,69.16 169.49,68.67 170.87,68.67 171.77,69.57 171.77,70.48 172.19,70.9 173.05,70.9 174.46,72.32 177.28,72.32 177.77,72.81 180.49,72.81 181.05,73.36 184.15,73.36 184.73,72.78 184.73,72.25 185.56,71.43 189.26,71.43 191.21,69.48 191.21,67.8 v2(190.75,67.34)
  BOTTOM w0.127: 189.97,67.27 189.97,67.16 189.82,67.01 189.36,67.01 188.92,66.58 188.17,66.58 187.55,65.96 187.28,65.7 v2(186.55,65.7) ; 189.97,67.27 190.22,67.01 190.37,67.01 190.7,67.34 v2(190.75,67.34) ; 189.97,67.27 CE58.1
REM_DIODE1_P: length 75.9
  TOP w0.127: QE3.1 136.45,61.81 137.05,61.21 137.84,61.21 QE3.2 138.75,61.16 CE47.2 138.62,61.72 138.47,61.72 v2(138.39,61.8) ; UE5.A13 188.37,65.52 v2(188.75,65.91)
  IN3 w0.127: v2(190.83,66.73) 190.7,66.73 190.32,67.12 190.32,67.55 191,68.22 191,69.39 189.17,71.21 185.41,71.21 184.48,72.14 184.48,72.68 184.05,73.11 181.15,73.11 180.59,72.55 177.88,72.55 177.39,72.06 174.57,72.06 173.15,70.65 172.29,70.65 172.02,70.38 172.02,69.46 170.97,68.41 169.39,68.41 168.88,68.92 164.65,68.92 163.39,67.67 162.59,66.86 160.55,66.86 158.08,64.39 158.08,62.56 157.42,61.9 153.63,61.9 151.79,60.05 145.26,60.05 144.73,60.59 142.85,60.59 142.35,61.09 141.28,61.09 140.53,61.83 138.9,61.83 138.69,61.62 138.54,61.62 138.39,61.77 v2(138.39,61.8)
  BOTTOM w0.127: 189.97,66.54 CE58.2 ; 189.97,66.54 189.97,66.63 189.84,66.76 189.46,66.76 189.03,66.33 188.27,66.33 187.8,65.86 187.8,65.72 187.88,65.65 188.5,65.65 v2(188.75,65.91) ; 189.97,66.54 190.2,66.77 190.8,66.77 v2(190.83,66.73)
REM_DIODE2_N: length 311.2
  TOP w0.127: v2(186.25,66.2) 186.36,66.2 186.43,66.14 186.65,66.14 187.02,65.77 UE5.B14 ; v2(193.22,66.52) 193.46,66.28 193.85,66.28 CE67.1 194.53,66.21 194.98,66.21 v2(195.12,66.35)
  IN1 w0.127: v2(186.25,66.2) 187.33,66.2 187.69,66.56 187.69,67.09 188.45,67.84 189.05,67.84 190.68,66.22 192.7,66.22 192.78,66.3 192.99,66.3 v2(193.22,66.52) ; v2(93.73,32.22) 93.42,32.22 92.68,32.97 92.33,32.97 91.25,34.05 90.86,34.05 90.86,34.04 90.24,34.04 89.08,35.2 82.31,35.2 81.94,34.83 79.51,34.83 77.12,37.22 72.71,37.22 72.23,36.74 70.23,36.74 68.31,38.66 63.05,38.66 61.36,36.97 53.51,36.97 53.13,36.58 51.28,36.58 50.88,36.99 49.87,36.99 47.13,34.25 46.69,34.25 46.51,34.43 46.51,34.55 46.69,34.73 v2(46.76,34.73)
  IN2 w0.127: v2(106.06,44.19) 106.53,43.72 106.53,43.42 106.23,43.12 102.6,43.12 100.91,41.44 100.91,35.87 99.82,34.78 98.2,34.78 98.07,34.65 95.17,34.65 94.29,33.77 94.29,32.77 v2(94.23,32.72)
  IN3 w0.127: v2(26.73,55.62) 27.2,55.15 27.2,54.85 26.81,54.46 26.81,48.55 28.64,46.72 30.38,46.72 31.85,45.25 31.85,43.98 33.69,42.14 33.69,40.51 34.98,39.23 38.59,39.23 39.85,37.96 39.85,36.74 40.41,36.18 45.67,36.18 46.53,35.31 46.53,34.96 v2(46.76,34.73) ; v2(195.12,66.35) 195.38,66.1 195.55,66.1 195.96,65.69 195.96,61.63 193.16,58.83 192.95,58.83 191.62,57.5 188.2,57.5 186.32,55.62 186.32,54.01 184.52,52.2 179.84,52.2 179.32,51.69 179.32,51 178.88,50.55 178.88,48.57 178.44,48.13 178.44,46.14 179.25,45.32 179.66,45.32 182.11,42.88 182.11,39.47 180.16,37.52 174.01,37.52 173.4,38.13 172.37,38.13 170.92,36.69 169.57,36.69 168.76,37.5 167.04,37.5 166.52,36.98 164.46,36.98 164.05,36.57 164.05,34.65 164.52,34.18 164.52,31 163.46,29.94 163.46,26.92 162.08,25.54 161.82,25.29 161.82,24.75 156.39,19.31 107,19.31 106.16,18.47 103.29,18.47 102.12,19.64 99.16,19.64 96.89,21.91 95.65,21.91 94.95,22.62 94.95,23.65 93.64,24.96 93.64,26.24 93.86,26.46 93.86,28.13 94.38,28.65 94.38,32.57 v2(94.23,32.72)
  BOTTOM w0.127: v2(93.73,32.22) 93.91,32.04 95.35,32.04 96.03,32.72 96.03,34.89 100.43,39.29 100.43,41.87 101.61,43.05 104.92,43.05 v2(106.06,44.19) 105.89,44.36 105.89,45.45 CE48.2 107.43,45.96 QE4.3 ; QE11.1 25.67,56.27 QE11.2 23.9,56.79 23.67,56.79 CE57.2 23.34,56.03 23.66,55.71 25.99,55.71 26.24,55.46 26.56,55.46 v2(26.73,55.62)
REM_DIODE2_P: length 310.3
  TOP w0.127: v2(195.1,65.77) 194.91,65.96 194.45,65.96 CE67.2 193.8,66.02 193.37,66.02 v2(193.22,65.87) ; v2(189.34,66.1) 189.14,66.3 188.6,66.3 188.31,66.02 188.06,66.02 UE5.A14
  IN1 w0.127: v2(93.8,31.56) 93.73,31.56 92.57,32.71 92.22,32.71 91.14,33.79 90.96,33.79 90.96,33.79 90.13,33.79 88.98,34.95 82.41,34.95 82.04,34.58 79.4,34.58 77.01,36.97 72.81,36.97 72.33,36.49 70.12,36.49 68.21,38.4 63.16,38.4 61.47,36.71 53.62,36.71 53.24,36.33 51.18,36.33 50.77,36.74 49.98,36.74 47.23,33.99 46.58,33.99 46.25,34.32 46.25,34.58 v2(46.05,34.78) ; v2(193.22,65.87) 193.05,66.04 192.88,66.04 192.8,65.96 190.57,65.96 188.95,67.59 188.55,67.59 187.94,66.98 187.94,66.63 188.24,66.33 189.11,66.33 v2(189.34,66.1)
  IN2 w0.127: v2(106.07,43.57) 105.88,43.38 102.5,43.38 100.66,41.54 100.66,35.98 99.72,35.04 98.09,35.04 97.96,34.91 95.07,34.91 94.03,33.87 94.03,33.44 v2(93.9,33.31)
  IN3 w0.127: v2(195.1,65.77) 195.22,65.89 195.23,65.88 195.46,65.88 195.75,65.6 195.75,61.72 193.07,59.05 192.86,59.05 191.53,57.71 188.11,57.71 186.11,55.71 186.11,54.09 184.43,52.42 179.75,52.42 179.11,51.78 179.11,51.08 178.66,50.64 178.66,48.66 178.22,48.22 178.22,46.05 179.16,45.1 179.57,45.1 181.85,42.82 181.85,39.57 180.02,37.74 174.1,37.74 173.49,38.35 172.28,38.35 170.83,36.9 169.66,36.9 168.85,37.72 166.95,37.72 166.43,37.2 164.37,37.2 163.84,36.66 163.84,34.56 164.31,34.09 164.31,31.09 163.24,30.03 163.24,27.04 161.61,25.41 161.61,24.84 156.3,19.53 106.91,19.53 106.07,18.68 103.38,18.68 102.21,19.86 99.24,19.86 96.98,22.13 95.74,22.13 95.16,22.71 95.16,23.74 93.85,25.05 93.85,26.15 94.08,26.37 94.08,28.04 94.6,28.56 94.6,32.02 94.68,32.09 94.68,33 94.38,33.3 93.92,33.3 v2(93.9,33.31) ; v2(26.75,55) 26.59,54.85 26.59,48.41 28.53,46.47 30.28,46.47 31.6,45.14 31.6,43.87 33.44,42.03 33.44,40.41 34.87,38.97 38.48,38.97 39.6,37.85 39.6,36.63 40.31,35.92 45.56,35.92 46.28,35.21 46.28,35.01 v2(46.05,34.78)
  BOTTOM w0.127: v2(26.75,55) 26.54,55.2 26.14,55.2 25.88,55.46 23.53,55.46 22.84,56.16 22.84,56.87 CE57.1 23.67,57.04 23.9,57.04 QE11.3 ; QE4.1 108.93,44.9 107.68,44.9 QE4.2 107.53,45.04 CE48.1 106.4,44.64 106.48,44.55 106.48,43.71 106.27,43.49 106.15,43.49 v2(106.07,43.57) 105.3,42.8 101.72,42.8 100.69,41.76 100.69,39.19 96.28,34.79 96.28,32.61 95.45,31.78 94.03,31.78 v2(93.8,31.56)
REM_DIODE3_N: length 64.6
  TOP w0.127: v2(188.79,67.11) 188.79,67.08 188.23,66.52 188.06,66.52 UE5.A15 ; QE10.3 148.3,38.56 148.82,39.08 148.82,39.56 CE66.2 148.69,39.84 148.9,40.04 148.9,40.25 149.17,40.52 152.68,40.52 153.06,40.91 v2(153.06,41.39)
  IN3 w0.127: v2(153.06,41.39) 153.21,41.39 153.31,41.49 153.31,41.74 153.64,42.07 154.86,42.07 155.11,42.33 156.36,42.33 158.46,44.43 158.61,44.57 158.85,44.81 158.85,45.98 160.59,47.72 161.27,47.72 162.15,48.6 165.73,48.6 167.11,49.97 167.11,50.61 169.3,52.81 173.22,52.81 173.58,53.17 175.75,53.17 177.71,55.13 181.76,55.13 182.25,55.61 182.25,56.19 181.76,56.67 181.76,58.4 181.67,58.5 181.67,64 183.49,65.82 183.49,67.53 184.1,68.13 186.11,68.13 186.73,68.75 187.51,68.75 187.77,68.49 187.77,68.32 v2(187.98,68.11)
  BOTTOM w0.127: v2(187.98,68.11) 187.87,68 187.87,67.29 CE39.1 188.23,67.11 v2(188.79,67.11)
REM_DIODE3_P: length 66
  TOP w0.127: v2(153.72,41.31) 153.31,40.9 153.31,40.8 152.78,40.27 149.28,40.27 149.15,40.14 149.15,40 149.32,39.84 CE66.1 149.07,39.46 149.07,39.08 QE10.2 149.6,37.31 QE10.1 ; UE5.B16 186.69,66.77 186.58,66.88 186.58,66.9 186.59,66.91 v2(186.59,66.96)
  IN3 w0.127: v2(153.72,41.31) 153.53,41.5 153.53,41.66 153.73,41.86 154.95,41.86 155.2,42.11 156.45,42.11 158.62,44.28 158.7,44.36 159.06,44.72 159.06,45.89 160.68,47.5 161.36,47.5 162.24,48.38 165.82,48.38 167.32,49.88 167.32,50.52 169.39,52.59 173.31,52.59 173.67,52.96 175.84,52.96 177.8,54.91 181.85,54.91 182.46,55.52 182.46,56.28 181.98,56.76 181.98,58.49 181.89,58.59 181.89,63.91 183.71,65.73 183.71,67.44 184.19,67.92 186.2,67.92 186.82,68.53 187.42,68.53 187.55,68.4 187.55,68.28 v2(187.37,68.1)
  BOTTOM w0.127: v2(186.59,66.96) 186.65,67.01 CE39.2 187.3,67.01 187.58,67.29 187.58,67.7 187.38,67.9 187.38,68.09 v2(187.37,68.1)
REM_DIODE4_N: length 16.8
  TOP w0.127: QE8.3 194.41,77.93 CE51.1 193.88,76.39 192.83,76.39 192.33,76.89 191.06,76.89 190.7,76.54 190.7,75.11 191.14,74.67 191.14,72.78 v3(190.7,72.35) 190.7,72.28 188.95,70.53 CE60.1 188.29,69.4 188.29,68.75 188.67,68.36 188.67,67.75 188.06,67.14 UE5.A16
REM_DIODE4_P: length 18.7
  TOP w0.127: UE5.B17 187.21,67.27 187.51,67.27 187.63,67.4 187.96,67.4 188.42,67.86 188.42,68.26 188.04,68.64 CE60.2 188.13,70.06 190.29,72.23 190.29,72.68 190.74,73.13 v3(190.74,74.27) 190.74,74.71 190.42,75.03 190.42,76.62 190.95,77.15 192.43,77.15 192.94,76.64 193.22,76.64 CE51.2 193.5,77.82 QE8.2 193.9,78.72 QE8.1
RESET_OUT#: length 159.9
  TOP w0.127: RE2.2 174.12,66.66 v2(175.13,67.67) ; UE5.B39 178.32,65.27 178.49,65.11 179.1,65.11 179.55,65.57 179.6,65.57 179.6,65.55 v2(179.59,65.55) ; v2(65.79,77.33) 65.79,76.84 RC129.1
  IN3 w0.089: v2(65.79,77.33) 64.38,75.92 62.94,75.92 62.5,75.48 62.5,73.9 62.85,73.56 63.61,73.56 65.84,75.79 69.66,75.79 70.26,75.19 70.26,74.79 70.77,74.27 76.26,74.27 77.21,75.22 78.03,75.22 79.74,73.51 90.07,73.51 90.52,73.96 91.96,73.96 92.63,74.63 99.33,74.63 102.33,71.64 106.42,71.64 108.26,73.48 110.07,73.48 110.2,73.62 111.55,73.62 112.43,74.5 119.2,74.5 119.45,74.25 121.96,74.25 122.28,74.58 122.28,75.49 122.67,75.87 123.9,75.87 124.23,76.21 129.52,76.21 130.33,77.02 130.33,77.6 130.56,77.83 139.88,77.83 140.78,76.93 145.46,76.93 145.81,76.57 151.57,76.57 152.92,75.22 153.29,75.22 153.95,75.22 154.17,75.01 156.71,75.01 v2(157.73,76.03)
  BOTTOM w0.127: v2(179.59,65.55) 179.63,65.6 179.63,66.16 179.36,66.42 178.51,66.42 177.26,67.67 v2(175.13,67.67) 175.13,69.43 173.26,71.31 168.78,71.31 168.27,71.82 168.27,72.39 167.88,72.78 166.79,72.78 165.19,71.18 164.74,71.18 164.14,70.57 v3(161.98,70.57) 161.29,70.57 159.5,72.36 158.77,72.36 157.73,73.4 v2(157.73,76.03) 156.65,76.03 155.05,77.63 153.73,77.63 153.21,77.11 153.21,74.91 151.53,73.23 150.26,73.23 149.5,72.47 149.5,72.23 149.57,72.15 149.57,71.81 149.5,71.74 149.5,71.57 UCPU1.B6
RESET_OUT#_R: length 11.6
  TOP w0.127: JXDP1.47 67.1,74.51 67.04,74.56 67.04,75.56 CC33.1 RC129.2 RC128.2 65.36,76.32 65.36,77.28 64.87,77.78 64.04,77.78 63.76,78.06 62.38,78.06 61.83,78.61 v3(61.83,79.61)
RING2:
  vias: v2(8.06,24.39) v2(8.66,24.37) v2(28.36,34.11) v2(28.37,33.49)
RING2_R: length 4.2
  TOP w1.016: 5.82,22.31 5.4,22.73 5.4,24.56 4.45,25.51 JHP1.4
  vias: v3(15.42,25.53)
RTD3_CIO_PWR_EN: length 250
  TOP w0.127: UT1.F1 39.74,55.46 39.74,55.07 39.85,54.96 39.85,54.33 40.44,53.74 RT39.2 40.02,53.05 40.02,52.17 39.99,52.14 39.99,51.51 40.23,51.27 40.23,50.36 v2(40.43,50.17) 40.38,50.12 39.6,50.12 37.73,51.99 RT26.2 ; v2(95.48,24.98) 95.63,25.13 95.63,25.64 95.34,25.93 94.99,25.93 94.73,25.67 89.36,25.67 88.67,26.37 87.72,26.37 86.87,27.22 86.87,27.56 86.15,28.28 83.16,28.28 82.12,27.24 82.12,26.6 80.64,25.12 79.7,25.12 79.32,25.49 79.32,26.54 78.96,26.91 69.93,26.91 v2(67.39,24.37)
  IN1 w0.081: v2(159.93,68.17) 159.93,67.69 160.21,67.41 160.21,66.89 159.15,65.83 159.15,63.49 157.72,62.06 157.72,57.11 155.08,54.47 155.04,54.47 v2(154.86,54.29)
  IN2 w0.089: v2(95.48,24.98) 95.73,24.98 96.22,24.49 97.43,24.49 98.55,23.38 98.55,22.27 103.53,17.29 106,17.29 107.13,18.42 108.02,18.42 115.56,18.42 116.37,17.6 117.1,17.6 118.56,16.15 124.94,16.15 126.79,18 126.79,18 127.05,18.26 131.1,18.26 132.09,17.27 156.8,17.27 158.66,19.12 161.96,19.12 164.17,21.34 164.17,30.6 162.32,32.46 162.32,33.76 163.77,35.21 163.77,37.38 162.2,38.95 162.2,40.61 163.97,42.38 163.97,46.92 158.33,52.56 158.33,54.41 157.66,55.08 156.72,55.08 155.94,54.29 v2(154.86,54.29) ; v2(67.39,24.37) 64.92,24.37 61.27,20.71 51.58,20.71 51.04,20.18 39.45,20.18 37.9,21.73 37.34,21.73 37.1,21.96 37.1,22.97 37.44,23.31 37.44,30.95 38.53,32.04 38.53,34.58 38.86,34.91 38.86,36.25 39.19,36.58 39.19,36.97 38.94,37.22 38.41,37.22 38.01,37.61 38.01,39.31 38.39,39.69 38.39,40.69 39.13,41.43 39.13,46.71 39.85,47.43 39.85,49.59 v2(40.43,50.17)
  BOTTOM w0.127: v2(159.93,68.17) 159.93,68.49 160.22,68.78 160.22,70.5 159.29,71.43 157.07,71.43 RC248.2
RTD3_USB_PWR_EN: length 8.4
  TOP w0.127: RT52.2 33.19,55.94 RT40.2 33.16,55.44 33.28,55.32 v2(33.28,55.25) ; v2(38.93,56.94) 38.91,56.93 38.91,56.93 38.9,56.94 38.9,56.95 38.6,56.65 UT1.D4
  IN2 w0.089: v2(33.28,55.25) 36.12,55.25 36.44,55.58 37.56,55.58 v2(38.93,56.94)
RUN_ON: length 6.1
  TOP w0.127: UE5.B9 187.21,63.27 186.5,63.27 v2(186.41,63.19)
  BOTTOM w0.127: v3(190.4,63.46) 190.4,64.04 190.04,64.4 189.65,64.4 189.22,63.97 187.79,63.97 R250.2 187,63.19 v2(186.41,63.19)
RUN_ON#: length 5.1
  TOP w0.127: v3(188.14,71.05) 188.98,71.89 RE84.2 188.39,72.94 188.39,73.71 188.54,73.86 188.86,73.86 189.11,74.11 189.45,74.11 QE12.5 QE12.6
RUN_ON_EC: length 28.4
  TOP w0.127: v2(186.64,75.75) 186.77,75.62 186.77,74.43 187.09,74.11 187.55,74.11 QE12.2
  IN1 w0.081: v2(189.86,63.98) 191.93,63.98 192.01,64.06 192.56,64.06 v2(193.04,63.58)
  IN4 w0.081: v2(189.86,63.98) 190.09,64.21 190.09,66.84 184.77,72.16 184.77,72.9 186.64,74.76 v2(186.64,75.75)
  BOTTOM w0.127: v1(193.14,64.09) 193.04,63.99 v2(193.04,63.58) 193.04,62.42 RE98.2 192.42,61.8 191.95,61.8 191.66,61.51 191.66,60.91 191.95,60.62 191.95,60.15 191.45,59.65 UC10.2 ; R250.1 188.14,63.41 R249.1 189.29,63.41 v2(189.86,63.98)
RUN_ON_P: length 378.2
  TOP w0.127: UC9.2 164.38,69.68 163.96,69.68 163.75,69.88 163.75,70.52 164.21,70.98 165.13,70.98 166.79,72.63 166.79,79.38 168.45,81.04 177.72,81.04 v2(178.28,80.48) ; v2(163.32,37.24) 163.32,37.24 163.04,36.96 163.04,36.04 161.97,34.97 161.97,32.65 162.53,32.09 PR611.1 163.04,32.55 v2(162.73,32.86) ; PR901.1 173.65,43.83 173.65,43.57 173.85,43.37 175.47,43.37 175.9,43.8 176.57,43.8 176.93,44.15 178.06,44.15 179.53,42.68 179.53,42.22 v2(179.49,42.18) ; v2(179.52,39.76) 180.06,39.22 R1445.1 ; U719.3 52.23,19.75 52.95,19.03 53.52,19.03 R290.2 53.34,19.26 v2(53.14,19.46) ; U720.5 37.33,40.48 v2(37.34,40.47)
  IN2 w0.089: v2(77.59,32.14) 78.85,32.14 81.53,29.45 81.53,25.89 80.75,25.1 79.5,25.1 79.32,25.28 75.7,25.28 73.92,23.5 72.64,23.5 72.52,23.63 71.4,23.63 71.27,23.5 65.35,23.5 64.69,22.84 64.69,22.08 64.24,21.62 63.33,21.62 61.98,20.28 55.22,20.28 54.74,19.8 53.48,19.8 v2(53.14,19.46) ; v2(162.73,32.86) 164.39,31.2 164.39,21.25 162.05,18.9 158.75,18.9 156.9,17.05 151.94,17.05 150.83,15.93 133.11,15.93 131.01,18.04 127.14,18.04 125.03,15.93 118.47,15.93 117.01,17.39 116.28,17.39 115.47,18.2 107.94,18.2 107.94,18.2 107.22,18.2 106.09,17.07 103.45,17.07 98.34,22.18 98.34,23.01 v2(97.94,23.4)
  IN3 w0.089: v2(179.49,42.18) 179.77,42.18 180.31,41.65 180.31,40.28 179.79,39.76 v2(179.52,39.76) 179.33,39.57 177.52,39.57 176.54,40.55 174.35,40.55 173.63,39.83 171.06,39.83 170.48,39.25 166.39,39.25 165.81,38.68 164.18,38.68 163.61,39.25 162.49,39.25 160.62,37.39 160.62,34.27 162.03,32.86 v2(162.73,32.86) ; v2(86.57,36.52) 86.57,36.25 87.78,35.04 89.96,35.04 90.16,34.84 96.1,34.84 97.05,33.89 97.05,24.29 v2(97.94,23.4) ; v2(193.77,61.88) 193.77,61.6 192.48,60.31 192.18,60.31 190.2,58.33 186.84,58.33 185.37,56.86 185.37,55.84 184.48,54.95 184.48,54.1 183.53,53.15 179.61,53.15 178.14,51.68 178.14,51.27 178.05,51.17 178.05,48.95 177.08,47.98 177.08,46.2 181.17,42.1 181.17,39.78 180.06,38.67 174.04,38.67 173.75,38.97 171.41,38.97 170.79,38.34 166.7,38.34 166.17,37.81 163.89,37.81 v2(163.32,37.24)
  IN4 w0.081: v2(193.77,61.88) 193.75,61.88 193.14,61.27 193.14,61 192.71,60.58 191.97,60.58 191.67,60.88 191.55,61 191.55,65.42 192.6,66.47 192.6,66.78 193.1,67.27 193.1,71.61 191.71,73 190.85,73 189.45,71.61 186.02,71.61 185.62,72.01 185.62,72.89 187.04,74.31 187.04,75.91 186.31,76.64 182.12,76.64 v2(178.28,80.48) ; v2(86.57,36.52) 85.24,36.52 83.68,34.96 79.86,34.96 77.59,32.69 v2(77.59,32.14) ; v2(53.14,19.46) 52.38,18.7 49.54,18.7 48.74,17.9 46.49,17.9 45.43,18.96 43.68,18.96 41.94,20.7 41.6,20.7 41.25,21.06 41.25,21.87 40.23,22.88 40.23,24.05 41.27,25.09 41.27,27.31 39.84,28.74 39.84,31.05 37.91,32.98 37.91,34.16 36.14,35.93 36.14,37.82 38.2,39.89 38.81,39.89 39.27,40.34 39.27,40.73 38.94,41.06 37.92,41.06 v2(37.34,40.47)
  BOTTOM w0.127: UC10.4 193.6,59.9 194.49,59.9 RE99.1 194.46,60.54 193.68,60.54 192.89,61.33 RE98.1 192.89,61.63 193.07,61.81 193.7,61.81 v2(193.77,61.88)
RUNPWROK: length 10.6
  TOP w0.127: v2(183.06,67.17) 183.06,67.22 182.61,67.66 UE5.B26 ; QE12.3 187.55,73.46 186.66,73.46 RE83.2 186.56,72.58 186.61,72.53 v2(186.64,72.53)
  BOTTOM w0.127: v2(186.64,72.53) 186.77,72.4 v3(186.77,71.31) 185.28,69.82 184.55,69.82 184.05,69.32 183.54,69.32 182.93,68.71 182.93,67.29 v2(183.06,67.17)
SA_B+:
  vias: v2(67.49,61.32) v2(68.07,61.32) v2(68.68,61.35) v2(69.32,61.35) v3(70.17,62.52)
SA_SNUB: length 4
  BOTTOM w0.127: v3(71.64,65.66) 71.68,65.7 71.68,67.01 71.3,67.4 PR1086.2
  BOTTOM w0.508: PC1086.1 70.46,67.27 PR1086.2
SATA_PRX_SSDTX_N2: length 101.1
  IN4 w0.091: v2(134.34,69.81) 134.34,69.7 134.47,69.58 134.65,69.58 134.74,69.67 134.74,70.61 135.88,71.74 135.88,76.93 138.25,79.3 152.33,79.3 152.94,78.69 155.74,78.69 155.95,78.89 159.17,78.89 159.5,79.22 167.83,79.22 168.34,78.71 168.84,78.71 171.55,76 171.55,74.15 170.97,73.57 170.51,73.57 170.26,73.31 170.26,72.93 172,71.18 172,69.18 173.2,67.97 173.2,67.02 172.75,66.56 172.75,64.1 172.82,64.02 172.82,62.49 173.97,61.35 173.97,59.78 177.13,56.61 177.13,56.2 178.81,54.52 178.81,53.94 181.56,51.18 181.56,48.46 185.19,44.83 185.19,43.62 185.49,43.33 185.49,39.15 188.19,36.45 v2(188.19,32.95)
  BOTTOM w0.127: v2(134.34,69.81) 134.57,69.59 UCPU1.E30 ; v2(188.19,32.95) 188.05,33.09 188.05,33.34 187.76,33.64 186.9,33.64 R2664.1
SATA_PRX_SSDTX_N2_C: length 2.8
  BOTTOM w0.127: JNGFF2.43 183.89,33.79 184.04,33.65 185.07,33.65 185.18,33.55 185.43,33.55 R2664.2
SATA_PRX_SSDTX_P2: length 101.1
  IN4 w0.091: v2(187.58,32.95) 187.43,33.1 187.43,33.23 187.53,33.33 187.88,33.33 188,33.45 188,36.37 185.29,39.07 185.29,43.25 185,43.54 185,44.75 181.37,48.38 181.37,51.1 178.61,53.86 178.61,54.44 176.94,56.12 176.94,56.53 173.77,59.7 173.77,61.27 172.63,62.41 172.63,63.94 172.55,64.02 172.55,66.64 173.01,67.1 173.01,67.89 171.81,69.1 171.81,71.1 170.06,72.85 170.06,73.39 170.43,73.76 170.89,73.76 171.36,74.23 171.36,75.92 168.76,78.52 168.26,78.52 167.75,79.03 159.58,79.03 159.25,78.7 156.03,78.7 155.82,78.49 152.86,78.49 152.25,79.11 138.33,79.11 136.07,76.85 136.07,71.66 134.93,70.53 134.93,69.59 134.73,69.39 134.58,69.39 v2(134.37,69.18)
  BOTTOM w0.127: UCPU1.F30 134.83,68.97 134.61,69.18 v2(134.37,69.18) ; R2663.1 186.67,33.29 186.76,33.38 187.65,33.38 187.8,33.24 187.8,33.1 187.65,32.95 v2(187.58,32.95)
SATA_PRX_SSDTX_P2_C: length 2.8
  BOTTOM w0.127: JNGFF2.41 183.91,33.29 184.01,33.4 v4(184.69,33.4) 184.97,33.4 185.07,33.29 185.44,33.29 R2663.2
SATA_PTX_SSDRX_N2: length 90.4
  IN4 w0.091: v2(187.33,34.98) 186.92,35.39 186.52,35.39 186.31,35.6 186.31,37.19 183.47,40.03 183.47,45.49 179.78,49.18 179.78,50.47 179.11,51.15 179.11,51.64 177.6,53.14 177.6,53.98 175.94,55.65 175.94,56.85 173.18,59.61 173.18,60.39 171.87,61.7 171.87,62.4 172.02,62.55 172.02,63.71 171.63,64.1 171.63,65.06 170.94,65.74 170.94,69.91 170.59,70.27 170.05,70.27 167.14,73.18 167.14,75.77 164.37,78.55 159.96,78.55 159.5,78.09 156.24,78.09 156.02,77.87 152.58,77.87 151.94,78.51 140.75,78.51 138.1,75.86 136.71,75.86 v2(136.5,75.65)
  BOTTOM w0.076: UCPU1.A25 137.65,72.31 137.73,72.24 137.73,72.1 137.62,71.99 137.36,71.99 137.3,72.05 137.3,72.14 137.24,72.42 137.24,72.81 136.69,73.36 136.36,73.36 135.81,73.92 135.81,74.13 135.85,74.18 135.85,74.2
  BOTTOM w0.127: CD47.1 186.96,35.18 187.13,35.18 v2(187.33,34.98) ; 135.85,74.2 135.85,75.66 136.08,75.89 136.36,75.89 136.5,75.75 v2(136.5,75.65)
SATA_PTX_SSDRX_N2_C: length 2.9
  BOTTOM w0.127: JNGFF2.47 183.86,34.79 183.95,34.89 v4(184.61,34.89) 184.87,34.89 185.17,35.19 185.44,35.19 CD47.2
SATA_PTX_SSDRX_P2: length 90.3
  IN4 w0.091: v2(136.5,76.29) 136.74,76.05 138.02,76.05 140.67,78.7 152.02,78.7 152.66,78.06 155.94,78.06 156.16,78.28 159.42,78.28 159.88,78.74 164.45,78.74 167.34,75.85 167.34,73.26 170.13,70.46 170.67,70.46 171.14,69.99 171.14,65.82 171.82,65.14 171.82,64.18 172.21,63.79 172.21,62.47 172.06,62.32 172.06,61.78 173.37,60.47 173.37,59.69 176.13,56.93 176.13,55.73 177.8,54.06 177.8,53.22 179.3,51.72 179.3,51.23 179.97,50.55 179.97,49.26 183.67,45.57 183.67,40.11 186.5,37.27 186.5,35.68 186.6,35.58 187.26,35.58 v2(187.33,35.65)
  BOTTOM w0.076: 135.6,74.2 135.6,74.18 135.64,74.13 135.64,73.85 136.29,73.2 136.62,73.2 137.07,72.75 137.07,72.41 137.13,72.13 137.13,71.98 137.32,71.79 UCPU1.B25
  BOTTOM w0.127: 135.6,74.2 135.6,75.77 135.97,76.14 136.36,76.14 v2(136.5,76.29) ; CD44.1 187,35.43 187.11,35.43 v2(187.33,35.65)
SATA_PTX_SSDRX_P2_C: length 2.9
  BOTTOM w0.127: CD44.2 185.43,35.45 185.06,35.45 184.76,35.14 184.07,35.14 183.92,35.29 JNGFF2.49
SD_PWR_EN: length 61.7
  TOP w0.127: U716.5 171.7,15.37 171.43,15.1 R1178.1 R1176.1 172.31,15.53 v2(172.26,15.58)
  IN3 w0.089: v2(161.23,14.79) 162.49,14.79 163.66,15.97 167.43,15.97 168.57,14.83 171.06,14.83 171.27,15.03 171.72,15.03 v2(172.26,15.58)
  IN4 w0.081: v2(154.15,45.19) 153.9,44.95 153.9,43.18 155.5,41.58 155.5,41.21 156.03,40.67 156.6,40.67 160.01,37.26 160.01,34.52 160.45,34.09 161.2,34.09 161.79,33.49 v2(162.76,33.49)
  BOTTOM w0.076: UCPU1.BA9 147.22,50.15 147.49,49.88 147.49,49.37 149,47.86 149.86,47.86 150.77,46.95 151.04,46.95 152.29,45.71 153.29,45.71
  BOTTOM w0.127: 153.29,45.71 153.81,45.19 v2(154.15,45.19) ; v2(161.23,14.79) 163.63,17.19 163.63,18.04 163.35,18.32 163.35,31.58 v3(163.42,31.66) 163.42,32.83 v2(162.76,33.49)
SD_RCOMP: length 2
  TOP w0.127: RC96.1 147.84,62.44 148.43,61.86 v2(148.43,61.82)
  BOTTOM w0.127: UCPU1.AB7 148.74,61.51 v2(148.43,61.82)
SIO_EXT_SCI#: length 56.8
  TOP w0.127: v3(175.87,67.92) 175.87,68.23 v2(176.35,68.71) 177.16,67.89 UE5.A33 ; v2(148.08,55.01) 147.98,55.01 147.66,54.68 147.66,51.87 148.69,50.83 RC237.2
  IN1 w0.081: v2(148.08,55.01) 148.54,54.55 148.54,53.58 149.43,52.69 149.43,52.05 152.93,48.55 154.79,48.55 156.62,46.72 158.5,46.72 159.36,47.58 162.06,47.58 166.72,52.23 166.72,55.5 167.3,56.08 167.3,56.66 167.19,56.77 167.19,60.63 168.15,61.59 168.15,62.14 168.77,62.76 169.15,62.76 170.09,63.7 170.09,64.32 171.73,65.97 171.93,65.97 172.22,66.26 172.22,66.8 172.1,66.92 172.1,67.61 173.08,68.59 174.09,68.59 174.4,68.89 176.16,68.89 v2(176.35,68.71)
  BOTTOM w0.076: UCPU1.AN7 148.48,55.4 v2(148.08,55.01)
SIO_EXT_SMI#: length 68.1
  TOP w0.127: UE5.A6 188.06,62.02 188.48,62.02 v2(188.72,61.78)
  BOTTOM w0.127: v2(188.72,61.78) 188.93,61.78 189.2,61.51 190.36,61.51 v3(190.57,61.72) 191.82,62.97 192.25,62.97 192.62,63.33 192.62,64.14 193.67,65.19 193.67,66.99 193.31,67.35 193.31,69.55 192.37,70.48 192.37,72.96 190.35,74.99 188.81,74.99 187.36,76.44 185.5,76.44 184.9,75.84 184.07,75.84 183.9,75.66 181.41,75.66 181.15,75.92 178.74,75.92 178.28,76.37 178.28,77.8 176.74,79.34 155.12,79.34 152.98,77.2 152.98,76.31 RC236.2 152.38,74.53 151.29,73.45 150.05,73.45 149.16,72.55 149.16,72.1 UCPU1.A6
SIO_EXT_WAKE#: length 60.8
  TOP w0.127: UE5.B5 186.9,61.27 186.59,60.96 186.06,60.96 v2(185.8,61.22) ; v2(157.28,57.87) 157.46,57.87 v3(157.77,57.56)
  IN3 w0.089: v2(157.28,57.87) 157.46,57.87 159.91,60.32 159.91,60.58 160.26,60.93 161.58,60.93 162.28,61.63 162.28,65.03 164.57,67.32 167.26,67.32 168.52,66.06 171.99,66.06 176.79,70.86 178.8,70.86 179.2,71.26 183.74,71.26 184.94,70.05 187.8,70.05 188.81,69.04 188.81,67.75 188.33,67.27 188.33,63.57 186.61,61.86 186.16,61.86 185.8,61.5 v2(185.8,61.22)
  BOTTOM w0.076: 152.14,58.48 151.6,58.48 151.42,58.66 151.42,58.97 151.26,59.14 151.05,59.14 150.82,59.37 UCPU1.AD3
  BOTTOM w0.127: 152.14,58.48 152.3,58.48 152.32,58.45 153.99,58.45 154.78,57.67 155.19,57.67 RC283.2 156.14,57.64 157.05,57.64 v2(157.28,57.87)
SIO_PWRBTN#: length 173.4
  TOP w0.127: UE5.B58 181.61,58.99 181.71,59.09 181.71,60 181.3,60.41 v2(180.99,60.41) ; JXDP1.41 68.6,74.21 68.56,74.25 68.56,74.89 v2(68.99,75.32) 68.81,75.5 CC269.1 69.21,75.9 69.23,75.88 RC241.2
  IN1 w0.081: v2(135.79,58) 134.98,58.81 134.98,65.33 133.28,67.02 127.86,67.02 125.82,64.98 120.19,64.98 118.98,66.19 117.96,66.19 117.12,67.04 113.6,67.04 113.3,67.35 112.29,67.35 111.45,66.51 109.96,66.51 109.66,66.21 108.21,66.21 107.56,65.56 100.04,65.56 v2(98.53,64.04)
  IN2 w0.089: v2(180.99,60.41) 180.88,60.41 180.43,59.96 179.93,59.96 179.73,59.75 178.76,59.75 177.17,58.16 177.17,57.56 176.9,57.29 176.49,57.29 172.67,61.1 167.44,61.1 v2(166.39,62.15)
  IN3 w0.089: v2(68.99,75.32) 68.99,74.93 69.86,74.05 78.56,74.05 78.65,73.97 78.67,73.97 80.16,72.47 82.46,72.47 83.06,73.08 90.11,73.08 90.49,72.7 91.31,72.7 92.81,74.2 94.38,74.2 96.15,72.42 v2(98.4,72.42) ; v2(166.39,62.15) 166.38,62.14 164.96,62.14 164.6,61.78 163.34,61.78 162.21,60.64 162.21,59.59 158.73,56.11 157.63,56.11 154.41,52.9 152.19,52.9 150.18,50.88 146.43,50.88 146.11,50.56 145.46,50.56 144.29,49.39 144.29,49.1 143.81,48.62 v2(143.52,48.62) 142.97,49.18 142.97,51.55 142.16,52.36 142.16,56.45 141.81,56.8 138.18,56.8 136.95,58.03 136.95,58.18 136.72,58.41 136.21,58.41 136.15,58.36 136.15,58.36 v2(135.79,58)
  BOTTOM w0.076: v2(143.52,48.62) 143.3,48.84 143.3,50.07 UCPU1.BA15
  BOTTOM w0.127: v2(98.4,72.42) 99.6,72.42 101.93,70.1 105.89,70.1 106.5,69.49 106.5,68.87 v3(106.21,68.58) 105.76,68.12 105.76,66.45 105.05,65.74 102.27,65.74 100.84,64.31 100.84,64.07 100.51,63.74 98.83,63.74 v2(98.53,64.04)
SIO_RCIN#: length 65.1
  TOP w0.127: v2(181.31,69.43) 181.36,69.37 181.36,68.72 UE5.A27
  IN1 w0.081: v2(181.31,69.43) 181.31,68.77 180.58,68.04 178.96,68.04 177.24,66.33 175.92,66.33 175.44,65.85 175.44,65.03 173.57,63.16 173.57,61.54 172.97,60.95 172.97,59.11 171.84,57.98 171.84,54.52 171.34,54.02 171.34,54.01 169.39,52.06 169.39,52.06 167.51,50.18 167.51,49.16 166.42,48.07 166.42,46.93 161.93,42.44 161.03,42.44 160.18,43.29 157.29,43.29 155.94,41.94 154.96,41.94 153.87,40.85 152.96,40.85 v2(152.12,41.69)
  BOTTOM w0.076: UCPU1.AW13 144.58,51.22 144.4,50.66 144.4,50.58 144.35,50.42 144.35,50.27 144.41,50.06 144.41,49.94 144.37,49.83 144.37,48.74 144.55,48.56 144.55,47.9 145.12,47.32
  BOTTOM w0.127: v2(152.12,41.69) 150.98,41.69 149.81,42.86 v3(148.11,42.86) 147.35,42.86 146.84,43.37 146.84,43.98 146.53,44.28 146.53,44.94 RC16.2 147.04,45.65 146.15,46.54 145.7,46.54 145.42,46.82 145.42,47.03 145.12,47.32
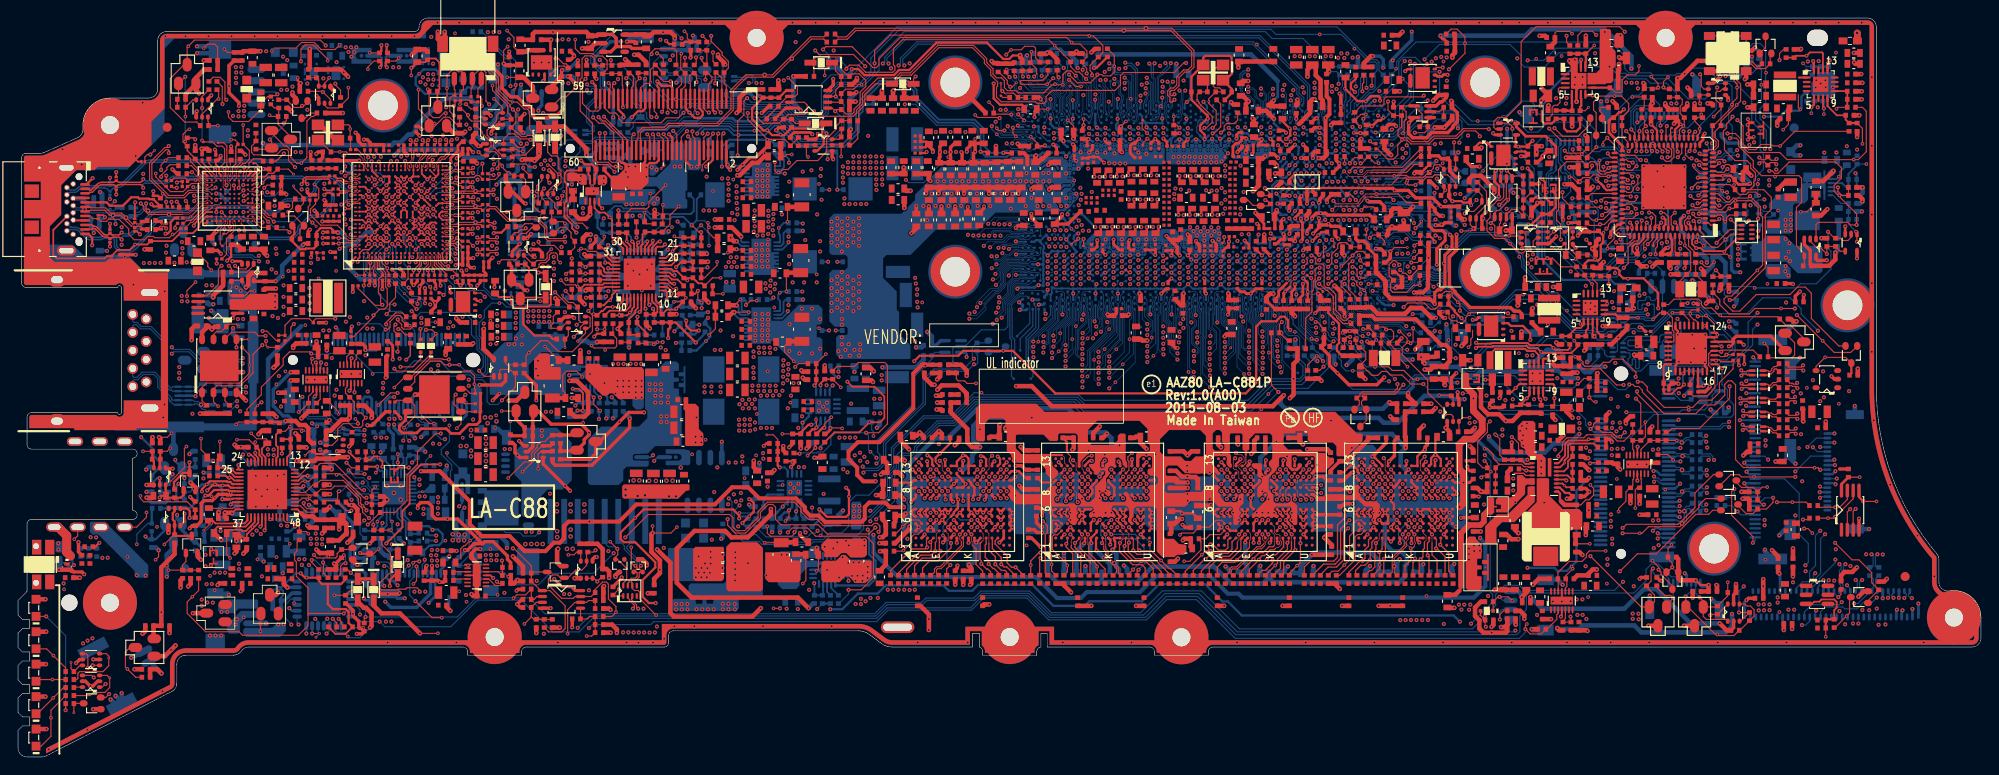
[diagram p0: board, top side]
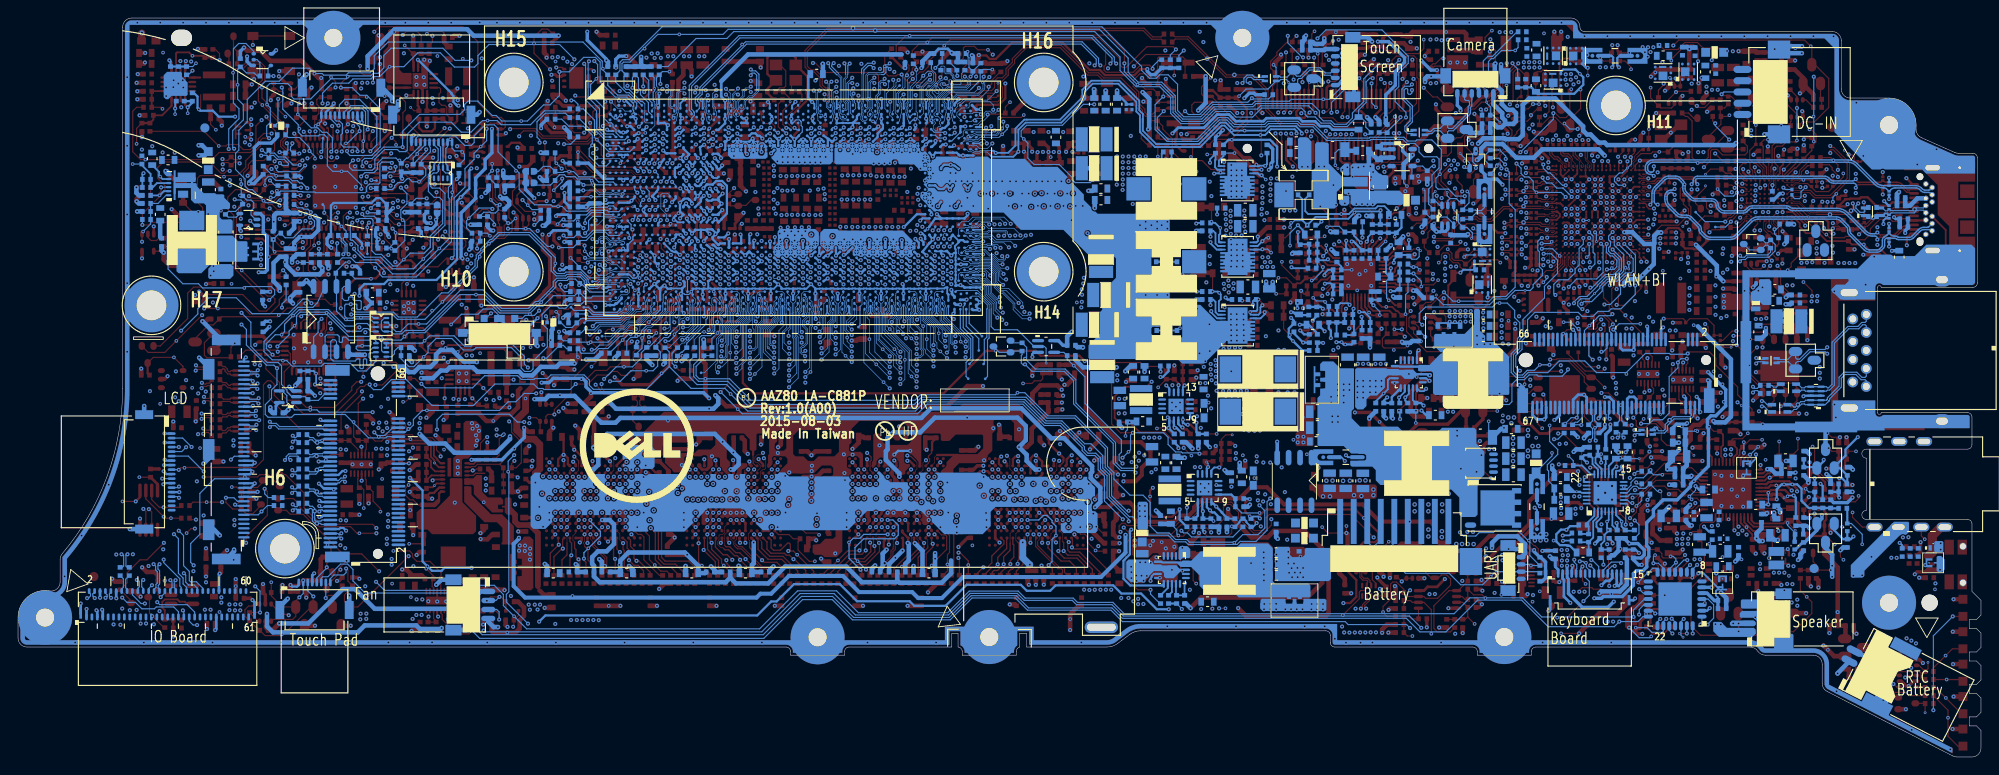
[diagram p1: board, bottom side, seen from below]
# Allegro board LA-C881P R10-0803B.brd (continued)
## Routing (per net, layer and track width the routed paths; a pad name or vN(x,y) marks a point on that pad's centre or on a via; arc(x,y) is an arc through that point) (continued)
SIO_SLP_A#: length 114.2
  TOP w0.127: v2(181.89,67.19) 181.89,67.27 181.61,67.54 UE5.B28
  IN1 w0.081: v2(181.89,67.19) 181.74,67.34 181.74,69.63 181.61,69.76 181.61,70.44 181.15,70.9 179.03,70.9 177.9,69.77 177.9,68.92 177.22,68.23 177.21,68.23 177.18,68.2 176.72,68.2 176.6,68.09 176.1,68.09 175.99,68.2 175.96,68.2 175.93,68.23 175.92,68.23 175.86,68.3 174.84,68.3 173.35,66.81 173.35,65.24 172.07,63.96 172.07,62.48 169.1,59.51 169.1,57.25 170.3,56.05 170.3,54.9 162.31,46.92 159.6,46.92 158.61,45.93 153.42,45.93 152.5,46.85 152.5,47.46 149.49,50.47 146.42,50.47 145.41,51.47 144.83,51.47 144.45,51.85 144.07,51.85 143,52.92 143,54.7 142.69,55.01 v2(142.6,55.01)
  IN4 w0.089: v2(197.21,31.68) 196.77,32.12 196.77,34.02 194.98,35.81 194.98,48.49 193.36,50.12 193.12,50.12 189.51,53.73 189.51,57.51 188.89,58.13 188.21,58.13 187.44,58.9 187.44,60.55 187.29,60.7 187.29,62.31 186.87,62.72 186.17,62.72 186.14,62.69 184.88,62.69 181.89,65.68 v2(181.89,67.19)
  BOTTOM w0.076: UCPU1.AN16 v2(142.6,55.01)
  BOTTOM w0.127: v2(197.21,31.68) 198.91,33.39 200.76,33.39 JAPS1.6
SIO_SLP_S0#: length 166.2
  TOP w0.127: v2(185.25,50.36) 184.79,50.36 RE92.1 ; v2(169.67,55.36) 170.26,55.36 171.22,54.39 PR1400.1 ; PR1411.1 195.91,78.52 195.45,78.06 v2(195.45,77.33) ; v2(165.81,69.71) 165.81,69.92 165.4,70.33 UC9.1
  IN1 w0.081: v2(165.81,69.71) 167.41,71.31 167.41,71.96 169.36,73.9 175.52,73.9 177.75,76.13 177.75,76.26 178.31,76.82 179.78,76.82 180.6,76 184.29,76 184.94,75.35 187.15,75.35 189.13,77.33 v2(195.45,77.33) ; v2(169.67,55.36) 169.67,54.88 162.14,47.34 159.43,47.34 158.44,46.36 156.68,46.36 154.7,48.34 152.63,48.34 148.93,52.03 147.02,52.03 146.34,52.71 146.08,52.71 145.66,53.13 v2(145.39,53.13)
  IN2 w0.089: v2(199.95,28.76) 201.02,29.83 201.02,40.5 199.71,41.8 v2(199.71,47.3) 199.71,51.03 203.3,54.62 203.3,66.79 203.53,67.01 203.53,72.91 201.75,74.68 201.75,76.21 201.24,76.72 196.06,76.72 v2(195.45,77.33)
  BOTTOM w0.127: v2(199.95,28.76) 200.08,28.89 JAPS1.15 ; v2(199.71,47.3) 197.86,49.16 197.86,49.73 196.63,50.96 193.6,50.96 191.84,49.2 187.8,49.2 186.17,50.82 185.72,50.82 v2(185.25,50.36) ; v2(145.39,53.13) 145.71,53.45 UCPU1.AT11 ; v2(169.67,55.36) 169.42,55.61 169.42,62.03 168.22,63.24 168.22,65.3 167.21,66.3 167.21,66.99 v3(166.46,67.73) 165.81,68.39 v2(165.81,69.71)
SIO_SLP_S3#: length 395
  TOP w0.127: UC11.1 51.78,42.24 v2(51.16,42.85) ; RT119.1 38.46,52.41 v2(38.37,52.32) ; UE5.A35 177.16,66.02 176.52,66.02 176.43,65.93 176.4,65.96 176.37,65.92 v2(176.33,65.92)
  IN1 w0.081: v2(177.24,43.72) 177.44,43.93 183.44,43.93 187.56,48.05 188.33,48.05 189.85,49.56 190.68,49.56 190.93,49.81 190.93,50.91 190.32,51.52 190.32,53.04 189.39,53.97 189.39,54.86 187.91,56.35 187.91,57.21 188.16,57.46 189.27,57.46 190.38,58.57 191.11,58.57 v2(192.04,59.5) 189.77,61.77 v2(189.77,62.07)
  IN2 w0.089: v2(38.37,52.32) 38.37,51.58 35.7,48.91 35.7,44.5 35.08,43.88 35.08,41.37 34.51,40.8 34.51,39.41 34.98,38.94 34.98,32.62 35.5,32.11 35.5,30.55 34.65,29.7 34.59,29.7 34.2,29.31 34.2,25.75 34.59,25.36 34.59,22.97 33.43,21.8 33.43,21.24 37.91,16.76 39,16.76 40.12,15.64 42.14,15.64 42.18,15.6 50.56,15.6 51.45,16.49 54.35,16.49 54.95,15.89 65.15,15.89 65.67,15.38 94.64,15.38 95.59,16.33 99.63,16.33 101.03,14.94 108.04,14.94 108.95,15.85 111.22,15.85 111.82,15.24 115.58,15.24 117.06,13.76 125.95,13.76 128.03,15.85 130.11,15.85 132.44,13.52 172.79,13.52 174.49,15.21 174.49,21.38 175.44,22.34 175.44,36.99 176.1,37.65 176.1,40.44 176.45,40.8 176.45,42.58 176.85,42.97 176.85,43.33 v2(177.24,43.72)
  IN3 w0.089: v2(189.77,62.07) 190,61.84 192.41,61.84 193.63,63.07 193.63,66.67 v2(194.43,67.46) ; v2(157.81,38.34) 158.11,38.64 160.42,38.64 162.53,40.75 163.2,40.75 164.57,42.12 170.04,42.12 170.53,42.61 171.89,42.61 172.49,43.22 173.08,43.22 173.53,42.76 174.62,42.76 175.58,43.72 v2(177.24,43.72)
  IN4 w0.081: v2(143.51,54.37) 143.92,53.97 143.92,52.38 144.22,52.08 144.64,52.08 145.06,51.66 145.55,51.66 148.46,48.74 148.46,45.79 148.86,45.39 150,45.39 150.43,45.83 152.45,45.83 153.46,44.81 153.46,43.03 155.08,41.41 155.08,41.03 155.86,40.25 156.43,40.25 157.81,38.87 v2(157.81,38.34)
  IN4 w0.089: v2(198.55,34.4) 197.92,34.4 196.09,36.23 196.09,49.36 192.28,53.17 192.28,53.48 191.47,54.29 191.47,57.85 190.47,58.85 190.47,61.38 v2(189.77,62.07)
  BOTTOM w0.076: UCPU1.AP15 v2(143.51,54.37)
  BOTTOM w0.127: v2(51.16,42.85) 51.62,43.31 51.62,44.53 50.93,45.23 50.93,46.23 50.31,46.84 50.31,48.52 49.49,49.34 44.69,49.34 44.25,48.9 43.05,48.9 42.49,49.45 41.31,49.45 41.03,49.73 39.95,49.73 38.37,51.31 v2(38.37,52.32) ; v2(198.55,34.4) 199.54,35.39 JAPS1.2 ; v2(189.77,62.07) 189.4,62.07 R249.2 188.67,62.8 186.83,62.8 186.78,62.74 186.24,62.74 186.19,62.69 184.88,62.69 184.8,62.62 179.29,62.62 179.13,62.78 179.13,63.27 178.82,63.57 177.8,63.57 177.65,63.72 177.65,65.79 177.44,66.01 176.42,66.01 v2(176.33,65.92) ; UC10.1 191.56,59 192.06,59.5 v2(192.04,59.5) ; U729.1 191.66,78.31 192.52,79.17 193.32,79.17 193.91,78.58 193.91,72.56 193.3,71.95 193.3,70.83 194.43,69.69 v2(194.43,67.46)
SIO_SLP_S4#: length 155.7
  TOP w0.127: v2(171.63,67.27) 171.9,67 173.6,67 R252.2 ; UE5.B36 179.39,66.77 179.91,66.25 v2(180.06,66.25) ; UC8.1 v2(204.05,57.17)
  IN1 w0.081: v2(199.16,34.38) 199.16,35.24 198.5,35.9 198.5,44.73 196.75,46.48 196.75,50.47 194.26,52.96 194.26,60.61 v2(193.81,61.05) 194.26,61.5 194.26,62.81 195.52,64.07 195.52,67.07 193.07,69.52 191.43,69.52 191.13,69.82 184.65,69.82 184.41,69.59 184.41,69.19 184.57,69.03 184.57,66.39 183.35,65.17 182.41,65.17 180.98,66.6 180.41,66.6 v2(180.06,66.25)
  IN2 w0.089: v2(180.06,66.25) 179.91,66.25 179.76,66.4 178.77,66.4 177.56,67.61 177.49,67.61 176.82,68.28 172.64,68.28 v2(171.63,67.27)
  IN3 w0.089: v2(180.06,66.25) 180.01,66.2 180.01,65.3 181,64.31 181,62.68 179.66,61.34 178.43,61.34 178.22,61.12 178.22,57.13 177.73,56.64 176.78,56.64 174.66,54.52 171.9,54.52 171.7,54.32 168.89,54.32 164.53,49.96 158.51,49.96 157.84,49.29 157.84,48.57 155.5,46.23 155.5,44.2 154.47,43.18 151.37,43.18 151.1,42.91 144.45,42.91 139.7,47.66 139.7,48.32 140.1,48.73 141.1,48.73 141.61,48.22 142.82,48.22 143.36,47.67 v2(144.02,47.67)
  IN4 w0.081: v2(204.05,57.17) 203.48,57.74 203.48,58.9 202.66,59.72 200.26,59.72 198.93,61.05 v2(193.81,61.05)
  BOTTOM w0.076: v2(144.02,47.67) 143.41,47.67 142.97,48.11 142.97,50.63 UCPU1.BA16
  BOTTOM w0.127: JAPS1.5 200.76,33.89 199.65,33.89 v2(199.16,34.38)
SIO_SLP_S5#: length 101.6
  TOP w0.127: UE5.A18 185.86,68.72 185.86,69.13 v2(186.11,69.38)
  IN3 w0.089: v2(144.04,47.08) 144.73,47.76 145.19,47.76 145.42,47.99 145.42,48.57 147.08,50.24 150.44,50.24 151.68,51.47 153.9,51.47 155.97,53.54 157.97,53.54 158.69,54.25 158.69,55.15 161.44,57.91 165.31,57.91 165.77,58.36 165.77,60.06 168.26,62.56 169.42,62.56 171.18,64.32 172.65,64.32 173.23,64.9 173.23,65.77 174.18,66.72 175.05,66.72 176.07,67.74 177.79,67.74 178.94,68.89 185.62,68.89 v2(186.11,69.38)
  IN4 w0.081: 199.71,34.66 199.96,34.41 v2(199.96,34.39)
  IN4 w0.089: v2(186.11,69.38) 186.54,68.94 186.54,67.83 187.76,66.61 187.76,65.09 190.68,62.17 190.68,58.94 191.69,57.94 191.69,54.38 192.5,53.57 192.5,53.26 196.3,49.45 196.3,37.21 196.63,36.88 197.5,36.88 199.71,34.66
  BOTTOM w0.076: UCPU1.AY16 142.95,51.12 142.64,50.81 142.64,50.39 142.81,50.22 142.81,47.95 143.68,47.08 v2(144.04,47.08)
  BOTTOM w0.127: v2(199.96,34.39) 199.97,34.39 200.76,34.39 JAPS1.4
SIO_SLP_SUS#: length 190.7
  TOP w0.127: v2(176.73,55.7) 177.06,55.7 177.75,55.01 RC97.1 ; v2(171.83,80.03) 171.83,79.31 PR801.1 ; v2(179.64,40.57) 179.64,40.32 181.97,38 R1444.1 ; v2(153.26,47.23) 153.27,47.24 153.35,47.24 154.13,46.46 154.13,45.97 153.59,45.43 153.59,44.66 156.42,41.83 156.42,40.42 158.3,38.55 v2(158.3,38.01) 159.03,38.01 159.23,37.8 QE13.2 ; v2(194.32,65.03) 194.66,65.03 194.92,64.77 195.27,64.77 196.53,66.02 201.69,66.02 202.32,65.39 202.32,64.23 201.51,63.42 201.51,62.77 204.01,60.27 v2(204.01,59.04) 203.34,59.04 203.05,59.33 199.75,59.33 199.51,59.09 UC13.1
  IN1 w0.081: v2(143.51,55.01) 143.51,54.95 143.97,54.49 143.97,52.32 144.22,52.06 144.54,52.06 144.92,51.68 145.5,51.68 146.51,50.68 149.58,50.68 153.03,47.23 v2(153.26,47.23) ; v2(198.45,76.16) 197.64,76.16 194.39,79.4 189.18,79.4 186.19,76.41 180.77,76.41 176.51,80.68 172.23,80.68 171.83,80.28 v2(171.83,80.03) ; v2(176.73,55.7) 176.73,55.74 176,56.47 176,57.88 175.84,58.04 175.84,58.8 178.4,61.36 180.09,61.36 182.47,63.73 188.06,63.73 188.57,64.25 189.56,64.25 189.69,64.37 190.25,64.37 190.78,64.91 192.61,64.91 192.79,64.74 193.72,64.74 194.02,65.03 v2(194.32,65.03)
  IN2 w0.089: v2(176.73,55.7) 176.87,55.56 177.71,55.56 180.3,58.15 182.93,58.15 184,57.08 184,56.19 185.6,54.59 185.6,53.93 185.06,53.4 184.48,53.4 183.29,52.21 183.29,49.31 182.26,48.28 182.26,42.19 180.64,40.57 v2(179.64,40.57)
  IN3 w0.089: v2(198.45,76.16) 200.28,76.16 203.51,72.93 203.51,67.01 203.35,66.86 203.35,59.72 204.01,59.06 v2(204.01,59.04) ; v2(179.64,40.57) 179.51,40.71 177.9,40.71 176.98,41.62 173.91,41.62 173.19,40.9 171.4,40.9 171.24,41.06 167.93,41.06 167.41,41.57 164.33,41.57 163.29,40.53 162.62,40.53 160.1,38.01 v2(158.3,38.01)
  BOTTOM w0.127: PR700.2 v2(204.01,59.04) ; UCPU1.AN15 143.58,55.01 v2(143.51,55.01) ; PR1412.1 198.91,75.7 v2(198.45,76.16)
SIO_SLP_SUS#_R: length 5.2
  TOP w0.127: UE5.B52 178.61,58.67 177.64,58.67 177.1,58.13 177.1,57.48 176.38,56.77 v3(176.38,56.41) RC97.2
SIO_SLP_WLAN#: length 51
  TOP w0.127: v2(144.11,46.3) 143.64,46.3 v3(143.52,46.42) ; v2(178.96,62.2) 178.88,62.27 UE5.B45
  IN3 w0.089: v2(144.11,46.3) 144.35,46.54 146.2,46.54 146.89,47.23 146.89,47.63 148.4,49.15 150.76,49.15 152.17,50.55 155.22,50.55 155.74,51.07 156.91,51.07 159.58,53.74 159.58,54.82 161.8,57.04 165.67,57.04 166.63,58.01 166.63,59.05 167.3,59.71 170.77,59.71 171.67,58.82 172.52,58.82 173.61,59.9 173.61,61.8 174.52,62.71 178.45,62.71 v2(178.96,62.2)
  BOTTOM w0.127: UCPU1.BB17 142.38,47.82 143.9,46.3 v2(144.11,46.3)
SLEEVE:
  vias: v2(9.36,22.1) v2(9.95,22.11) v2(27.72,34.15) v2(27.77,33.55)
SLEEVE_R: length 20.3
  TOP w0.127: JHP1.3 6.62,25.09 6.62,24.54 v3(6.24,24.16)
  TOP w0.254: QA1.3 18.47,26.12 v2(18.47,27.01)
  IN1 w0.508: JHP1.3 6.62,24.89 7.42,24.09 7.42,23.25 7.75,22.92 10.99,22.92 11.59,22.31 15.98,22.31 18.42,24.75 18.42,26.96 v2(18.47,27.01)
SM_PG_CTRL: length 109.3
  TOP w0.127: PR609.1 162.54,31.2 v2(162.37,31.03)
  IN2 w0.089: v2(162.37,31.03) 162.8,30.59 162.8,28.93 162.15,28.28 162.15,27.62 162.95,26.82 162.95,21.5 161.65,20.2 158.26,20.2 156.31,18.25 132.74,18.25 131.58,19.41 126.57,19.41 125.06,17.91 118.85,17.91 117.18,19.57 106.95,19.57 105.61,18.23 104.01,18.23 99.61,22.64 99.61,24.26 98.79,25.08 98.61,25.08 98.61,25.08 97.87,25.08 95.56,27.39 95.56,28.1 94.34,29.32 94.34,31.12 95.25,32.04 v2(95.25,32.57)
  BOTTOM w0.127: UC2.4 102.84,44.9 101.76,44.9 RE60.2 101.4,44.15 v3(100.67,43.42) 99.42,42.17 99.42,39.23 95.38,35.2 95.38,33.81 95.63,33.56 95.63,32.95 v2(95.25,32.57)
SM_RCOMP0: length 4.6
  TOP w0.076: v2(141.68,53.74) 141.25,53.3 141.25,53.02 140.82,52.59 140.77,52.59
  TOP w0.305: RC5.1 139.55,50.89 139.88,51.22 139.88,51.7 140.77,52.59
  BOTTOM w0.254: UCPU1.AR18 142.12,54.08 v2(141.68,53.74)
SM_RCOMP1: length 3.6
  TOP w0.076: v2(141.68,53.1) 141.15,52.57 141.15,52.18
  TOP w0.305: RC6.1 140.44,51.47 v3(140.61,51.64) 141.15,52.18
  BOTTOM w0.254: UCPU1.AT18 142.12,53.43 v2(141.68,53.1)
SM_RCOMP2: length 2.6
  TOP w0.305: RC7.1 141.33,51.62 141.68,51.98 v2(141.68,52.47)
  BOTTOM w0.254: UCPU1.AU18 142.12,52.78 v2(141.68,52.47)
SML1_SMBCLK: length 41.7
  TOP w0.127: UE5.B6 187.21,61.77 186.93,61.77 186.61,61.45 v2(186.37,61.45)
  IN2 w0.089: v2(155.09,62.87) 155.42,62.87 156.11,63.56 158.54,63.56 158.66,63.68 165.72,63.68 166.75,62.65 168.86,62.65 169.67,61.83 171.73,61.83 172.28,62.38 172.63,62.38 174.04,60.98 174.04,60.46 174.99,59.51 177.15,59.51 177.98,60.33 177.98,61.1 178.4,61.52 180.98,61.52 181.09,61.64 186.18,61.64 v2(186.37,61.45)
  BOTTOM w0.076: v2(155.09,62.87) 155.07,62.9 153.85,62.9 153.4,62.44 152.02,62.44 151.88,62.38 151.75,62.38 151.52,62.45 151.52,62.45 151.39,62.45 151.17,62.37 151.02,62.37 150.82,62.17 UCPU1.W3
  BOTTOM w0.127: RC15.1 155.63,62.87 v2(155.09,62.87)
SML1_SMBDAT: length 45.8
  TOP w0.127: v3(154.07,63.7) 154.3,63.47 v2(155.06,63.47) ; v2(188.79,61.2) 188.78,61.19 188.59,61.19 188.26,61.52 188.16,61.52 188.16,61.52 UE5.A5
  IN2 w0.089: v2(155.06,63.47) 155.72,63.47 156.02,63.77 158.45,63.77 158.57,63.89 165.81,63.89 166.84,62.86 168.95,62.86 169.76,62.05 171.64,62.05 172.19,62.6 172.72,62.6 174.25,61.07 174.25,60.55 175.08,59.73 177.06,59.73 177.76,60.42 177.76,61.19 178.31,61.74 180.89,61.74 181,61.85 186.7,61.85 187.41,61.15 188.74,61.15 v2(188.79,61.2)
  BOTTOM w0.076: v2(155.06,63.47) 154.14,63.47 153.27,62.6 151.98,62.6 151.85,62.55 151.77,62.55 151.57,62.6 151.55,62.61 151.36,62.61 151.23,62.57 150.76,62.57 UCPU1.V3
  BOTTOM w0.127: v2(155.06,63.47) 155.3,63.71 RC17.1
SNB_1.0V: length 2
  BOTTOM w0.508: PR702.2 202.03,57.72 PC701.1
SNUB_1.8VA: length 3.8
  TOP w0.127: PC807.1 170.54,80.33 170.73,80.52 172.18,80.52 v3(172.44,80.26)
  TOP w0.508: PR803.2 170.54,79.33 PC807.1
SNUB_1.8VU: length 2.2
  TOP w0.127: v2(162.83,41.87) PR903.2
  TOP w0.508: PC907.1 163.59,40.46 PR903.2
SNUB_1V_PRIM: length 2.8
  BOTTOM w0.127: PR1516.2 89.22,25.19 89.22,24.74 v3(89.05,24.57)
  BOTTOM w0.508: PC1519.1 PR1516.2
SNUB_PRIM: length 2.7
  TOP w0.127: v3(195.86,69.61) 196.44,70.2 PC1419.1
  TOP w0.508: 196.57,71.97 196.44,71.84 PC1419.1
SNUB_VCC_EDRAM: length 2.7
  BOTTOM w0.127: v3(94.92,35.62) 94.92,36.1 94.72,36.31 PC1510.1
  BOTTOM w0.508: PR1505.2 93.76,37.17 PC1510.1
SNUB_VCCIO: length 1.4
  TOP w0.508: PC1410.1 168,48.15 PR1403.2
SPI_CLK_VROM: length 11.4
  BOTTOM w0.127: RP5.2 178.1,48.21 178.35,48.21 178.75,48.61 180.39,48.61 180.56,48.44 181.43,48.44 182.47,49.48 UH8.6 182.47,52.84 182.55,52.92 RC29.2 182.55,53.84 181.47,54.92 v3(181.08,54.92)
SPI_IO2_VROM: length 13.1
  BOTTOM w0.127: RP6.3 178.1,44.92 178.36,44.92 178.43,44.84 178.76,44.84 178.87,44.73 178.87,44.38 178.64,44.14 178.64,43.73 178.91,43.46 179.02,43.46 179.13,43.56 179.13,44.09 179.21,44.18 179.4,44.18 179.49,44.08 179.49,43.18 179.57,43.1 179.79,43.1 179.88,43.19 179.88,44.08 179.98,44.18 180.16,44.18 180.41,43.94 182.84,43.94 183.11,44.21 183.11,46.1 182.92,46.29 182.66,46.29 182.47,46.11 UH8.3
SPI_IO3_VROM: length 25.4
  BOTTOM w0.127: UH8.7 184.48,50.65 184.59,50.4 185.09,49.9 186.73,49.9 190.52,46.11 190.52,44.99 189.6,44.07 188.51,44.07 v3(188.42,43.98) 187.99,43.98 187.39,43.38 184.14,43.38 183.83,43.68 180.93,43.68 180.07,42.83 179.17,42.83 178.1,43.91 RP6.4
SPI_SI_VROM: length 12.8
  BOTTOM w0.127: RP5.1 178.36,48.71 178.51,48.86 180.49,48.86 180.66,48.69 181.33,48.69 181.56,48.92 181.56,50.12 181.43,50.25 v2(180.88,50.25) 180.29,50.25 180.21,50.17 180.21,49.74 180.11,49.64 179.84,49.64 179.73,49.75 179.73,50.55 179.83,50.66 180.52,50.66 180.62,50.76 180.62,50.96 180.71,51.05 181.07,51.05 181.13,50.99 181.13,50.76 181.23,50.66 181.59,50.66 181.84,50.91 181.84,52 181.62,52.22 UH8.5
SPI_SO_VROM: length 13
  BOTTOM w0.127: RP6.2 178.1,45.42 178.44,45.42 178.73,45.13 180.1,45.13 180.29,45.32 180.29,45.52 180.18,45.63 v3(179.63,45.63) 178.74,45.63 178.63,45.74 178.63,46.12 178.76,46.25 181.11,46.25 181.45,46.59 181.71,46.59 181.8,46.5 181.8,46.1 181.9,46.01 182.08,46.01 182.17,46.1 182.17,46.67 182.34,46.84 183.56,46.84 183.74,46.66 UH8.2
SPK_L+_C:
  vias: v2(22.58,16.09) v2(23.22,16.09) v3(21.82,18.5)
SPK_L-_C:
  vias: v2(24.15,14.71) v2(24.29,15.28) v3(25.04,15.5)
SPK_OUT_L+: length 1.5
  TOP w0.203: v2(27.36,25.15) 27.46,25.26 27.46,26.63
  vias: v2(24.52,21.45) v2(24.51,20.84) v2(26.94,24.74)
SPK_OUT_L-:
  vias: v3(26.57,21.93)
SPK_OUT_R+:
  vias: v3(30.15,23.66)
SPK_OUT_R-:
  vias: v3(28.68,22.18)
SPK_R+_C:
  vias: v2(28.87,14.71) v2(29.46,14.74) v3(30.63,17.08)
SPK_R-_C: length 0.9
  TOP w0.127: v2(26.9,14.82) v3(26.9,13.94)
  vias: v2(27.49,14.82)
SPKR: length 217.9
  TOP w0.127: v2(149.86,52.49) 150.74,52.49 RC183.2 ; v2(27.01,39.35) 26.95,39.35 v1(26.59,39) 26.29,38.69 RA25.1
  IN3 w0.089: v2(27.01,39.35) 28.48,40.82 31.37,40.82 32,40.19 32,39.66 32.67,38.99 33.27,38.99 35.94,36.32 35.94,27.59 36.6,26.94 40.99,26.94 v2(42.11,25.82)
  IN4 w0.081: v2(149.86,52.49) 149.87,52.49 149.84,52.46 149.84,50.99 152.41,48.41 154.34,48.41 154.47,48.28 155.07,48.28 155.44,47.91 155.44,47.25 155.44,46.57 156.36,45.66 156.36,44.85 157.33,43.87 157.33,41.41 161.08,37.66 162.32,37.66 162.98,37.01 162.98,37 163.66,36.32 163.66,35.03 164.68,34.01 164.68,23.61 160.77,19.69 147.8,19.69 147.4,20.1 145.24,20.1 144.74,19.59 123.78,19.59 123.38,19.99 107.03,19.99 106.52,20.5 101.52,20.5 99.5,22.52 97.67,22.52 97.11,23.09 97.11,25.27 97.02,25.36 97.02,29.09 96.2,29.91 96.2,33.32 95.37,34.15 90.64,34.15 89.83,34.96 86.73,34.96 86.38,34.61 86.38,33.92 85.88,33.42 84.56,33.42 82.74,31.6 78.97,31.6 77.87,30.5 77.02,30.5 74.2,27.68 71.74,27.68 69.54,25.48 69.54,24.29 66.19,20.94 64.07,20.94 62.02,18.9 59.13,18.9 56.63,21.4 54.23,21.4 54.01,21.18 53.34,21.18 53.29,21.23 50.47,21.23 49.33,20.1 44.4,20.1 43.81,20.69 43.81,22.1 42.39,23.51 42.39,25.54 v2(42.11,25.82)
  BOTTOM w0.127: v2(149.86,52.49) 149.87,52.49 149.58,52.21 UCPU1.AW5
SRTCRST#: length 16
  TOP w0.127: RC56.1 147.17,45.55 CC24.1 147.47,46.62 v2(147.8,46.62)
  IN2 w0.089: v2(141.68,55.01) 141.75,55.01 142.14,54.62 142.14,52.41 143.66,50.89 146.1,50.89 148.18,48.8 148.18,47 v2(147.8,46.62)
  BOTTOM w0.076: UCPU1.AN18 v2(141.68,55.01)
  BOTTOM w0.127: v3(146.98,47.06) 147.42,46.62 v2(147.8,46.62)
SS_1.8VA: length 7.7
  TOP w0.127: v3(179.86,76.68) 179.86,76.1 179.46,75.7 178.57,75.7 178,75.13 178,73.87 177.87,73.74 177.25,73.74 176.74,74.25 PC806.1
  TOP w0.254: PC806.1 176.61,74.28 174.66,74.28 PU800.9
SS_1.8VU: length 3
  TOP w0.203: PC906.1 170.47,39.08 v2(170.47,39.81) 170.47,41.25 170.33,41.38 PU900.9
SS_1V_PRIM: length 3.9
  TOP w0.127: v3(85.16,26.18) 85.54,26.57 v2(85.54,27.37)
  BOTTOM w0.254: PC1520.1 84.56,26.63 85.07,27.14 85.31,27.14 v2(85.54,27.37) 85.9,27.72 PU1501.7
SS_PRIM: length 2.7
  TOP w0.203: PU1401.7 200.28,72.07 v2(200.38,71.97)
  BOTTOM w0.127: v3(200.38,71.33) v2(200.38,71.97)
  BOTTOM w0.203: PC1420.1 200.38,72.65 v2(200.38,71.97)
SS_VCC_EDRAM: length 3.1
  TOP w0.127: v3(88.54,37.42) 88.6,37.37 v2(88.6,36.56)
  TOP w0.254: v2(88.6,36.56) 88.39,36.36 88.14,36.36 87.73,35.95 PC1511.1
  BOTTOM w0.254: v2(88.6,36.56) 88.67,36.64 88.75,36.64 89.06,36.95 89.06,37.36 PU1500.7
SS_VCCIO: length 1.7
  TOP w0.203: PU1400.7 174.72,46.82 PC1411.1
SSD_DEVSLP: length 73.9
  TOP w0.127: v2(174.43,32.59) 174.52,32.67 R1376.2
  IN2 w0.089: v2(174.43,32.59) 174.64,32.59 175.22,33.17 175.22,37.08 175.88,37.74 175.88,40.56 176.24,40.92 176.24,42.67 176.63,43.06 176.63,43.77 177.01,44.15 180.44,44.15 181.36,45.07 181.36,48.3 182.64,49.58 182.64,51.38 181.04,52.98 179.42,52.98 177.52,51.08 175.53,51.08 174.9,51.71 174.9,53.09 175.1,53.29 175.1,56.93 173.2,58.82 172.46,58.82 172.26,58.63 171.43,58.63 170.59,59.47 165.14,59.47 163.61,60.99 157.89,60.99 156.63,62.25 154.8,62.25 154.26,62.79 154.26,63.67 154.91,64.32 155.1,64.32 155.39,64.6 155.39,65.01 154.32,66.07 153.44,66.07 153.24,66.28 153.24,67.09 152.43,67.9 v2(152.43,67.93)
  BOTTOM w0.127: UCPU1.J3 151.17,67.83 152.32,67.83 v2(152.43,67.93) ; v2(174.43,32.59) 174.48,32.55 175.6,32.55 JNGFF2.38
SSD_IFDET: length 81
  TOP w0.127: RC51.2 150.85,67.47 151.99,66.33 152.62,66.33 153.1,66.81 153.1,67.91 153.64,68.45 154.13,68.45 154.55,68.03 156.56,68.03 157.18,68.65 159.66,68.65 160.48,69.47 161.73,69.47 162.2,69 v2(162.2,68.88)
  IN4 w0.081: v2(156.41,72.86) 156.41,72.5 158.52,70.39 159.72,70.39 160.49,69.62 161.47,69.62 v2(162.2,68.88) 162.2,68.64 165.63,65.21 165.63,64.37 167.56,62.44 167.56,60.77 168.68,59.65 168.68,57.81 171.78,54.71 171.78,53.43 172.54,52.66 172.54,48.81 174.55,46.81 174.55,41.24 177.52,38.26 v2(178.46,38.26)
  BOTTOM w0.127: U683.4 188.5,40.63 187.99,40.12 187.99,39.38 187.12,38.52 v3(185.4,38.52) 184.63,38.52 184.38,38.26 v2(178.46,38.26) ; v2(156.41,72.86) 156.1,72.86 155.68,72.44 R2665.1 155.08,71.92 153.85,70.68 153.85,69.66 152.68,68.49 150.48,68.49 UCPU1.G4
SSD_PCIE_WAKE#: length 6.8
  TOP w0.127: v2(178.28,36.03) v3(177.78,35.53) 177.77,35.52 177.36,35.52 177.11,35.76 176.87,36.01 175.79,36.01 R1377.1
  BOTTOM w0.127: v2(178.28,36.03) 177.94,35.68 177.09,35.68 176.23,36.54 175.6,36.54 JNGFF2.54
SSD_PWR_EN: length 79.3
  TOP w0.127: R1188.2 R1446.1 178.19,35.06 177.46,35.06 176.76,35.75 174.08,35.75 173.75,35.43 171.87,35.43 171.37,34.92 171.37,34.06 170.92,33.61 v2(170.92,33.36)
  IN2 w0.089: v2(170.92,33.36) 168.93,35.35 168.93,37.95 167.82,39.06 167.82,40.16 168.47,40.82 168.47,43.1 168.65,43.29 168.65,47.39 167.26,48.78 167.26,50.43 166.64,51.05 166.64,55.43 v2(163.44,58.63)
  IN4 w0.081: v2(145.79,59.57) 145.83,59.57 146.27,59.13 148.35,59.13 149.41,58.07 150.21,58.07 151.13,57.15 151.13,54.7 154.79,51.04 155.01,51.04 155.29,51.32 155.29,55.77 154.49,56.56 154.49,59.41 154.73,59.64 155.75,59.64 157.01,58.37 157.34,58.37 157.68,58.03 157.68,57.49 v2(158.52,56.65)
  BOTTOM w0.076: v2(145.79,59.57) 145.85,59.63 145.85,60.21 146.48,60.84 146.48,62.39 146.33,62.54 145.72,62.54 145.49,62.31 UCPU1.W12
  BOTTOM w0.127: v2(163.44,58.63) v3(161.48,58.63) 161.03,58.63 159.06,56.65 v2(158.52,56.65)
SUS_ON_EC: length 77.5
  TOP w0.127: 192.14,62.95 193.7,62.95 194.54,62.11 194.54,60.78 193.87,60.12 193.87,54.3 190.28,50.7 v2(189.94,50.7) ; 192.14,62.95 192.61,63.43 192.61,63.85 192.79,64.03 192.79,64.82 192.25,65.35 192.25,65.76 191.83,66.18 190.53,66.18 189.34,67.37 189.34,68.57 189.31,68.61 189.31,68.63 189.24,68.7 189.24,69.45 189.59,69.8 189.59,70.26 190.08,70.76 190.08,70.89 v2(190.25,71.05) ; 192.14,62.95 R251.1 ; v2(169.9,69.73) 171.25,68.39 RE68.1 R252.1 ; UC8.2 203.4,57.66 203.05,57.31 202.44,57.31 202.18,57.57 RE95.2 201.55,57.57 v2(200.84,58.28)
  IN1 w0.081: v2(169.9,69.73) 169.9,69.94 170.55,70.58 176.08,70.58 177.8,72.3 180.77,72.3 181.01,72.06 181.59,72.06 182.47,72.94 184.23,72.94 185.39,71.78 189.52,71.78 v2(190.25,71.05)
  BOTTOM w0.127: v2(189.94,50.7) 189.33,51.31 189.33,51.82 189.71,52.2 192.55,52.2 v3(192.7,52.05) 197.32,52.05 197.79,52.51 199.53,52.51 201.16,54.15 201.16,56.13 200.84,56.45 v2(200.84,58.28)
SUS_ON_P: length 393.6
  TOP w0.127: v2(178.16,41.28) 177.37,41.28 175.59,43.06 173.53,43.06 PR900.1 ; v2(175.11,80.12) 174.69,80.54 173.55,80.54 173.08,80.07 PR800.1 ; UC13.2 198.86,57.49 198.86,57.24 199.49,56.6 199.92,56.6 v2(200.71,55.81) RE97.1 RE95.1 202.2,56.13 UC8.4 ; PR607.1 166.5,34.1 166.5,34.81 165.81,35.5 v2(165.75,35.5) ; UZ23.4 50.73,51.48 51.37,51.48 v2(51.79,51.06)
  IN1 w0.081: v2(175.11,80.12) 175.69,79.54 177.35,79.54 180.69,76.2 186.62,76.2 187.95,77.53 191.17,77.53 191.78,78.14 195.36,78.14 197.84,75.66 197.84,69.2 199.24,67.8 199.24,57.28 v2(200.71,55.81)
  IN3 w0.089: v2(200.71,55.81) 201.14,55.38 201.14,53.78 199.31,51.95 199.31,47.05 202.26,44.1 202.26,35.04 201.17,33.94 188,33.94 185.98,31.92 185.98,26.87 181.24,22.13 178.71,22.13 177.04,20.46 177.04,19.55 174.33,16.84 163.34,16.84 162.16,15.66 159.67,15.66 158.97,16.36 158.97,18.13 165.1,24.26 165.1,28.02 166.4,29.32 166.4,34.81 165.72,35.49 165.75,35.49 v2(165.75,35.5) ; v2(165.03,39.6) 165.03,39.52 164.8,39.29 164.21,39.29 163.95,39.54 163.95,40.86 164.45,41.36 167.32,41.36 167.84,40.84 171.15,40.84 171.31,40.68 173.28,40.68 174,41.4 176.89,41.4 177.81,40.49 178.93,40.49 179.25,40.16 179.89,40.16 180.09,40.37 180.09,40.71 179.77,41.03 179.32,41.03 179.22,40.92 178.52,40.92 v2(178.16,41.28)
  IN4 w0.081: v2(51.79,51.06) 50.42,51.06 47.22,47.86 47.22,46.41 41.05,40.24 41.05,40.01 40.64,39.61 39.34,39.61 36.91,37.17 36.91,35.46 38.12,34.25 38.12,33.06 40.05,31.13 40.05,28.83 41.48,27.4 41.48,25 40.44,23.96 40.44,22.97 41.45,21.95 41.45,21.14 41.69,20.91 42.03,20.91 43.76,19.17 45.51,19.17 46.58,18.1 48.65,18.1 50.85,20.3 52.91,20.3 52.95,20.26 54.39,20.26 54.61,20.47 56.04,20.47 59.13,17.39 62.81,17.39 63.67,18.24 67,18.24 67.85,19.1 67.85,21.13 73.04,26.32 75.61,26.32 79.21,29.92 81.64,29.92 81.98,29.58 83.72,29.58 85.69,31.56 87.48,31.56 88.29,32.37 91.85,32.37 92.57,31.64 92.57,31.04 94.14,29.47 95.45,29.47 96.18,28.75 96.18,25.03 96.27,24.93 96.27,22.74 97.33,21.69 99.16,21.69 101.18,19.67 106.18,19.67 106.69,19.16 123.04,19.16 123.44,18.76 145.09,18.76 145.59,19.26 147.06,19.26 147.46,18.86 161.12,18.86 165.52,23.27 165.52,27.8 166.42,28.69 166.42,34.83 v2(165.75,35.5) 165.18,36.08 165.18,39.45 v2(165.03,39.6)
SUSACK#: length 67.3
  TOP w0.127: v2(185.57,62.26) 185.97,61.87 186.62,61.87 187.03,62.27 UE5.B7
  IN3 w0.089: v2(146.25,54.37) 145.85,54.78 145.85,55.83 146.55,56.52 150.12,56.52 150.5,56.9 152.3,56.9 152.56,56.64 154.22,56.64 154.8,57.23 156.29,57.23 156.85,56.68 157.3,56.68 157.75,57.12 157.75,57.85 160.12,60.23 160.12,60.49 160.35,60.72 161.67,60.72 162.5,61.54 162.5,64.94 164.66,67.1 167.17,67.1 168.43,65.85 172.08,65.85 176.88,70.65 178.89,70.65 179.29,71.04 183.65,71.04 184.85,69.83 187.71,69.83 188.6,68.95 188.6,67.84 188.11,67.36 188.11,65.08 186.74,63.71 185.53,63.71 185.31,63.49 185.31,62.52 v2(185.57,62.26)
  BOTTOM w0.127: v2(146.25,54.37) 145.88,54.75 UCPU1.AP11
SUSCLK: length 187.5
  TOP w0.127: R1255.2 43,46.85 42.37,47.48 v2(42.19,47.48) ; R2662.2 173.76,42.01 173.16,41.41 v2(173.05,41.41)
  IN2 w0.089: v2(79.43,29.14) 77.57,29.14 76.1,27.67 64.52,27.67 63.16,26.31 60.11,26.31 58.1,24.3 56.12,24.3 55.59,24.84 53.45,24.84 46.14,32.15 44.44,32.15 43.75,31.47 42.3,31.47 41.52,32.25 41.52,32.94 42.39,33.8 44.03,33.8 45.28,35.05 45.28,35.78 44.63,36.43 44.17,36.43 43.49,37.12 43.49,46.19 v2(42.19,47.48)
  IN4 w0.081: v2(94.57,26.16) 94.57,26.33 95.16,26.92 95.16,27.57 92.07,30.66 91.82,30.66 91.55,30.93 89,30.93 87.02,28.96 81.72,28.96 81.41,29.26 80.88,29.26 80.5,28.89 79.68,28.89 v2(79.43,29.14)
  BOTTOM w0.076: RC48.1 145.54,45.42 144.3,46.67 143.84,46.67 142.64,47.86 142.64,49.87 142.38,50.13 UCPU1.BA17
  BOTTOM w0.127: 145.55,43.33 143.13,40.9 139.37,40.9 v3(138.74,40.28) 136.86,38.39 118.23,38.39 117.22,39.4 106.2,39.4 103.83,37.04 102.09,37.04 99.48,34.43 99.48,34.11 99.08,33.71 98.22,33.71 97.7,33.19 97.7,31.96 96.97,31.23 96.97,28.78 94.57,26.37 v2(94.57,26.16) ; 145.55,43.33 145.55,44.95 RC48.1 ; 145.55,43.33 148.08,40.8 153.97,40.8 154.41,41.24 154.41,41.81 155,42.4 158.67,42.4 159.08,42 160.46,42 160.56,41.89 161.96,41.89 162.38,42.31 166.03,42.31 167.38,40.96 172.6,40.96 v2(173.05,41.41)
SW_1.8VA:
  vias: v3(171.27,77.78)
SW_1.8VU:
  vias: v3(166.54,44.81)
SYS_RESET#: length 97.6
  TOP w0.127: v2(163.21,69.67) 163.15,69.73 160.37,69.73 159.55,68.91 157.07,68.91 156.45,68.28 154.66,68.28 154.24,68.7 153.39,68.7 153.13,68.96 153.13,69.53 153.52,69.92 RC224.2 RC291.2 152.01,71.8 v2(152.01,72.73)
  IN1 w0.081: v2(163.21,69.67) 163.27,69.6 163.27,69.07 163.57,68.77 166.27,68.77 168.51,71.01 175.9,71.01 177.74,72.84 180.33,72.84 180.85,73.36 184.4,73.36 184.63,73.13 187.77,73.13 188.7,72.2 191.13,72.2 192.2,71.13 192.38,71.13 196.01,67.5 196.01,62.89 194.68,61.55 194.68,53.14 197.79,50.02 197.79,45.73 198.7,44.81 198.7,36.08 199.57,35.21 199.57,30.39 v2(199.95,30.01)
  BOTTOM w0.076: v2(152.01,72.73) 152.01,72.72 151.28,71.99 150.8,71.99 150.47,71.66 UCPU1.B5
  BOTTOM w0.127: v2(199.95,30.01) 200.07,29.89 200.76,29.89 JAPS1.13
SYS_RESET#_R: length 7.5
  TOP w0.127: v3(153.67,69.2) 153.79,69.32 153.79,70.52 154.02,70.75 154.02,71.59 RC224.1 153.68,72.25 154.9,72.25 UC12.4 155.47,71.68 155.79,71.36 155.79,70.2 RC290.2
SYSTEM_WAKE#: length 4.5
  TOP w0.127: R1462.2 31.29,58.51 QT19.3 30.66,60.03 29.47,60.03 R1439.2
TBT_AUX_N: length 57.1
  TOP w0.076: U722.J2 21.76,63.72 20.89,63.72 20.67,63.95 20.32,63.95 19.38,64.89 v2(19.31,64.89)
  TOP w0.127: R1478.2 18.84,64.85 19.26,64.85 v2(19.31,64.89) ; CT42.2 52.97,64.09 53.37,64.49 v2(53.37,64.7)
  IN3 w0.089: v2(19.31,64.89) 19.05,64.64 19.05,61.59 19.62,61.02 22.76,61.02 23.15,60.63 23.15,60.13 23.46,59.83 23.97,59.83 24.96,58.84 25.38,58.84 26.88,57.33 29.01,57.33 29.35,56.98 30.36,56.98 31.26,56.08 33.56,56.08 34.22,55.42 39.54,55.42 41.83,53.12 47.18,53.12 47.68,52.62 48.43,52.62 49.12,53.32 49.42,53.32 49.85,53.76 49.85,58.63 50.32,59.1 50.86,59.1 51.66,59.91 51.66,61.35 51.93,61.62 51.93,63.44 52.53,64.04 52.73,64.04 52.86,64.18 52.92,64.18 53.16,64.41 53.16,64.47 53.37,64.68 v2(53.37,64.7)
TBT_AUX_N_C: length 7.9
  TOP w0.127: v2(45.42,62.15) 45.75,61.82 UT1.W15 ; CT42.1 51.54,64.14 51.17,64.51 50.81,64.51 50.6,64.3 v2(48.64,64.3)
  BOTTOM w0.127: v2(45.42,62.15) 45.42,62.18 46.37,63.13 47.07,63.13 47.63,63.69 48.19,63.69 48.64,64.14 v2(48.64,64.3)
TBT_AUX_P: length 52.6
  TOP w0.127: CT41.2 52.22,64.63 52.71,64.63 v2(52.76,64.58) ; R1472.2 21.18,65.87 v2(21.88,65.18) 22.01,65.05 22.01,64.47 U722.J1
  IN3 w0.089: v2(21.88,65.18) 22.73,64.32 22.73,63.12 24.78,61.08 25.28,61.08 25.94,60.42 25.94,59.2 26.76,58.38 26.77,58.38 27.18,57.97 29.27,57.97 29.54,57.71 32.39,57.71 33.34,58.66 35.58,58.66 35.98,58.26 35.98,57.71 36.44,57.26 36.44,55.95 36.76,55.63 42.29,55.63 42.98,54.95 42.98,53.6 43.24,53.34 47.27,53.34 47.77,52.84 48.34,52.84 49.03,53.54 49.33,53.54 49.63,53.85 49.63,58.72 50.23,59.32 50.77,59.32 51.45,59.99 51.45,61.44 51.71,61.71 51.71,63.53 v2(52.76,64.58)
TBT_AUX_P_C: length 9.5
  TOP w0.127: UT1.Y15 46.4,61.88 46.14,62.14 v2(46.08,62.14) ; CT41.1 v2(51.54,65.85)
  BOTTOM w0.127: v2(51.54,65.85) 51.03,65.34 51.03,64.74 50.66,64.37 50.17,64.37 49.68,63.89 49.68,63 v3(49.33,62.65) 46.58,62.65 v2(46.08,62.14)
TBT_BATLOW#: length 2.6
  TOP w0.076: UT1.F2 39.52,55.7 39.52,55.15
  TOP w0.127: RT25.2 39.44,53.62 v3(39.44,54.28) 39.44,54.52 39.52,54.6 39.52,55.15
TBT_CC1: length 18.9
  TOP w0.203: v2(19.51,58.96) 19.51,59.09 20.89,60.47 21.01,60.47 ; 9.12,61.54 9.13,61.55 ; 21.01,60.47 21.51,60.47 U722.K9 ; 21.01,60.47 U722.L9
  TOP w0.254: JUSBC1.A5 9.12,61.54 9.12,61.54 ; v2(14.8,61.34) 15.04,61.1 C1279.1 15.8,61.11 D77.1 14.56,61.9 14.5,61.96 13.45,61.96 13.31,62.11 12.57,62.11 11.63,61.17 10.21,61.17 9.83,61.55 9.13,61.55
  IN3 w0.254: v2(19.51,58.96) 19.53,58.96 19.03,58.96 17.81,60.17 15.96,60.17 v2(14.8,61.34)
TBT_CC2: length 24.8
  TOP w0.203: JUSBC1.B5 3.91,58.48 3.91,55.71 4.29,55.33 9.61,55.33 9.86,55.57 10.35,55.57 D86.1 11.04,56.26 12.39,56.26 v3(13,56.87) 14.33,56.87 C1280.1 17.11,57.25 17.98,58.12 19.41,58.12 20.11,58.83 20.11,59.22 20.87,59.97 21.01,59.97 U722.L10 U722.K10
TBT_CIO_PLUG_EVENT#: length 249.3
  TOP w0.076: 45.97,54.36 45.94,54.39 45.94,55.7 UT1.W2
  TOP w0.102: v2(145.82,60.71) 146.22,61.12 148.63,61.12 149.22,61.71 149.22,61.78 149.59,62.15 150.14,62.15
  TOP w0.127: 45.97,54.36 46.06,54.27 v2(46.06,54) 46.2,53.85 RT23.2 ; v2(152.63,61.81) 152.35,62.08 150.53,62.08 150.47,62.15 150.14,62.15
  IN2 w0.089: v2(87.78,18.55) 88.29,18.04 96.06,18.04 96.96,17.15 100.21,17.15 101.61,15.75 107.6,15.75 108.76,16.91 114.93,16.91 115.74,16.09 116.47,16.09 117.93,14.64 125.57,14.64 127.68,16.75 130.47,16.75 132.58,14.64 156.89,14.64 159.68,17.44 163.4,17.44 165.79,19.82 165.79,26.16 166.76,27.13 166.76,33.13 168.49,34.86 168.49,37.77 166.73,39.53 166.73,40.62 166.8,40.69 166.8,42.36 166.39,42.76 166.39,48.17 166.83,48.6 166.83,50.25 166.21,50.87 166.21,55.25 164.14,57.32 158.6,57.32 158.15,57.77 158.15,57.9 157.44,58.61 157.14,58.61 155.38,60.37 154.4,60.37 152.97,61.81 v2(152.63,61.81) ; v2(79.91,25.59) 79.86,25.54 65.76,25.54 61.15,20.93 51.49,20.93 50.95,20.39 39.54,20.39 37.99,21.94 37.53,21.94 37.31,22.16 37.31,22.88 37.66,23.22 37.66,29.46 38.23,30.03 38.74,30.03 39.41,30.7 39.41,31.42 39.23,31.59 39.23,32.48 39.61,32.86 39.94,32.86 41.42,34.34 41.42,35.63 39.84,37.21 39.84,45.67 41.26,47.09 41.26,48.56 42.33,49.63 42.86,49.63 43.37,50.14 43.37,51.39 42.92,51.84 42.92,52.6 43.55,53.22 44.68,53.22 44.96,53.5 45.56,53.5 v2(46.06,54)
  IN3 w0.089: v2(87.78,18.55) 87.76,18.55 86.86,17.66 81.56,17.66 80.32,18.9 80.32,24.7 79.91,25.1 v2(79.91,25.59)
  BOTTOM w0.127: UCPU1.AB12 145.49,61.05 v2(145.82,60.71)
TBT_DBG_CTL1: length 5.7
  TOP w0.127: R1454.2 27.63,63.46 v2(27.33,63.16) ; U722.E4 24.01,62.97 24.01,63.37 v2(23.95,63.43)
  IN2 w0.089: v2(27.33,63.16) 27.3,63.18 26.16,63.18 25.35,63.99 24.26,63.99 23.95,63.68 v2(23.95,63.43)
TBT_DBG_CTL2: length 4.5
  TOP w0.076: U722.D5 24.61,62.57 24.71,62.57 v2(25.02,62.87)
  TOP w0.127: v2(27.65,62.67) 27.75,62.57 R1460.2
  IN2 w0.089: v2(25.02,62.87) 25.65,62.87 26.17,62.36 26.76,62.36 26.93,62.19 27.29,62.19 27.65,62.55 v2(27.65,62.67)
TBT_DDC_CLK: length 3
  TOP w0.076: UT1.Y2 46.4,55.7 46.4,55.12
  TOP w0.127: 46.4,55.12 46.4,54.7 47.47,53.63 RT33.2
TBT_DDC_DATA: length 2.3
  TOP w0.076: 46.18,55.08 UT1.Y1
  TOP w0.127: 46.18,55.08 46.18,54.56 46.84,53.9 RT34.2
TBT_DEBUG3: length 4.6
  TOP w0.076: 20.13,63.88 20.25,63.76 20.6,63.76 20.89,63.47 U722.L3
  TOP w0.127: 20.13,63.88 19.97,64.04 v3(19.7,64.04) 18.98,64.04 RT188.1 18.81,64 18.56,64.25 17.32,64.25 R1463.2
TBT_DEBUG4: length 8
  TOP w0.076: 19.7,63.64 20.1,63.64 20.14,63.6 20.54,63.6 20.9,63.23 21.27,63.23 U722.K3
  TOP w0.127: 19.7,63.64 19.24,63.64 18.91,63.31 RT187.1 18.81,63.23 18.32,62.74 16.91,62.74 16.45,63.21 R1464.2 16.32,63.33 15.28,64.37 v3(15.28,64.76)
TBT_FORCE_PWR: length 260.4
  TOP w0.127: RC247.2 149.02,72.24 151.34,72.24 151.57,72.47 151.57,73.01 151.8,73.25 155.84,73.25 v2(155.98,73.39) ; v2(95.12,25.46) 94.41,24.75 89.79,24.75 88.77,25.77 84.65,25.77 84.05,26.37 84.05,27.72 83.74,28.03 83.26,28.03 82.37,27.14 82.37,26.49 80.73,24.85 79.6,24.85 78.75,25.71 v2(78.75,26.39) ; UT1.H4 40.24,56.93 v2(40.24,56.93) ; v2(44.32,50.28) 44.32,50.65 RT38.2
  IN1 w0.081: v2(155.98,73.39) 156.02,73.35 156.02,66.56 154.4,64.94 154.4,62.57 156.28,60.69 156.28,57.35 154.15,55.22 154.15,54.48 v2(154.2,54.43)
  IN2 w0.089: v2(78.75,26.39) 78.1,25.75 65.59,25.75 61.27,21.43 54.74,21.43 54.56,21.26 51.51,21.26 50.91,20.66 40.06,20.66 38.51,22.21 37.72,22.21 37.53,22.4 37.53,22.79 38,23.26 38,27.64 38.25,27.9 38.25,28.99 38.46,29.19 38.91,29.19 39.62,29.9 39.62,31.5 39.45,31.68 39.45,32.39 39.7,32.65 40.03,32.65 41.63,34.25 41.63,35.72 40.06,37.3 40.06,45.58 41.48,47 41.48,48.47 42.42,49.41 42.96,49.41 43.84,50.28 v2(44.32,50.28) ; v2(154.2,54.43) 153.92,54.16 153.92,51.16 156.23,48.85 156.23,47.65 157.19,46.69 158.42,46.69 158.8,47.07 161.5,47.07 162.41,46.16 162.41,43.59 160.93,42.11 160.93,39.53 160.63,39.23 160.63,36.92 162.11,35.44 162.11,32.37 163.96,30.51 163.96,21.42 161.87,19.34 158.55,19.34 156.7,17.48 132.18,17.48 131.19,18.47 126.96,18.47 126.57,18.09 126.57,18.09 124.85,16.37 118.65,16.37 117.19,17.82 116.46,17.82 115.65,18.63 108.11,18.63 107.04,18.63 105.91,17.51 103.62,17.51 98.77,22.36 98.77,23.47 97.52,24.71 96.33,24.71 95.58,25.46 v2(95.12,25.46)
  BOTTOM w0.127: v2(40.24,56.93) v1(38.89,55.58) 38.6,55.29 38.6,53.93 38.81,53.72 39.47,53.72 40.41,52.78 41.38,52.78 42.03,52.13 42.03,51.7 43.2,50.53 44.08,50.53 v2(44.32,50.28)
TBT_HPD: length 26
  TOP w0.127: v2(30.12,58.23) 29.85,58.51 28.96,58.51 R1437.2 ; v2(42.17,56.95) 42.16,56.95 UT1.M4 ; RT43.2 45.82,52.08 v2(45.73,52.17)
  IN3 w0.089: v2(30.12,58.23) 31.75,59.85 34.7,59.85 36.2,58.35 36.2,57.8 38.15,55.85 41.54,55.85 42.17,56.47 v2(42.17,56.95)
  BOTTOM w0.127: v2(45.73,52.17) 44.85,53.04 42.65,53.04 41.94,53.76 41.94,56.72 v2(42.17,56.95)
TBT_I2C_B_N: length 10.9
  TOP w0.076: 18.22,60.2 18.24,60.2 18.28,60.25 18.99,60.25 20.18,61.44 20.97,61.44 U722.L7
  TOP w0.127: 18.22,60.2 v4(16.76,60.2) 14.48,60.2 14.24,60.44 13.96,60.72 13.96,61.08 v2(13.62,61.43)
  BOTTOM w0.127: v2(13.62,61.43) 13.88,61.17 13.88,60.9 13.42,60.44 12.99,60.44 12.89,60.54 ML7.4
TBT_I2C_B_N_R: length 5.6
  BOTTOM w0.127: JUSBC1.B7 6.38,60.93 7.21,60.93 v4(7.37,60.77) 7.51,60.63 10.02,60.63 10.19,60.79 D90.1 10.38,60.61 10.61,60.61 10.92,60.92 ML7.3
TBT_I2C_B_P: length 10.9
  TOP w0.076: 18.22,60.46 18.24,60.46 18.28,60.41 18.92,60.41 20.11,61.6 20.75,61.6 20.87,61.72 21.26,61.72 U722.K7
  TOP w0.127: 18.22,60.46 14.59,60.46 v4(14.42,60.62) 14.22,60.83 v2(14.22,61.43)
  BOTTOM w0.127: v2(14.22,61.43) 14.13,61.34 14.13,60.8 13.52,60.19 13.01,60.19 ML7.1
TBT_I2C_B_P_R: length 5.6
  BOTTOM w0.127: JUSBC1.B6 6.41,60.68 7.1,60.68 7.41,60.37 9.98,60.37 D91.1 10.39,60.35 10.68,60.35 10.95,60.07 ML7.2
TBT_I2C_CLK: length 67.9
  TOP w0.076: 44.77,55.04 45.03,55.3 45.03,55.68 UT1.U2
  TOP w0.127: v2(24.49,63.15) 24.54,63.2 24.54,63.95 U722.D2 ; 44.77,55.04 44.77,54.59 44.52,54.34 v2(44.52,54.01) 44.52,53.68 RT36.2
  IN1 w0.081: v2(44.52,54.01) 44.39,54.14 44.39,54.3 44.77,54.68 44.77,55.14 44.32,55.59 43.19,55.59 42.77,55.17 42.77,53.33 40.91,51.47 38.41,51.47 36.23,49.3 34.42,49.3 31.73,46.61 31.73,42.64 27.06,37.96 24.48,37.96 23.84,38.6 23.84,45.74 26.18,48.08 26.18,49.63 26.68,50.13 26.68,53.02 24.84,54.85 24.84,56.06 23.89,57.01 23.89,58.36 24.16,58.63 24.16,59.19 23.2,60.15 23.2,61.25 23,61.46 23,62.81 22.74,63.06 22.74,63.63 23.09,63.98 24.41,63.98 24.48,63.97 24.48,63.97 24.56,63.88 v2(24.49,63.15)
TBT_I2C_DATA: length 67.7
  TOP w0.076: U722.D1 24.51,64.47 24.51,64.83 v2(24.66,64.98)
  TOP w0.127: UT1.U1 44.68,55.33 44.68,55.33 44.55,55.21 44.55,54.68 44.3,54.43 44.3,54.43 v2(43.9,54.03) 43.9,53.7 RT35.2
  IN1 w0.081: v2(43.9,54.03) 43.98,54.03 44.18,54.23 44.18,54.39 44.56,54.77 44.56,55.05 44.24,55.38 43.27,55.38 42.97,55.08 42.97,53.25 40.99,51.26 38.49,51.26 36.32,49.09 34.51,49.09 31.94,46.52 31.94,42.55 27.15,37.76 24.39,37.76 23.63,38.51 23.63,45.83 25.97,48.16 25.97,49.72 26.47,50.22 26.47,52.93 24.63,54.77 24.63,55.97 23.68,56.92 23.68,58.44 23.95,58.72 23.95,59.11 22.99,60.07 22.99,61.17 22.79,61.37 22.79,62.72 22.53,62.98 22.53,63.72 23,64.19 24.42,64.19 24.49,64.18 24.5,64.18 24.59,64.25 v2(24.66,64.98)
TBT_I2C_INT#: length 37.4
  TOP w0.127: U722.C1 25.01,64.77 25.07,64.83 25.07,64.85 25.1,64.88 v2(25.1,65.44) ; v2(45.16,50.35) 45.16,50.86 RT47.2 ; v2(40.87,56.31) 41.18,56.62 UT1.J4
  IN3 w0.089: v2(40.87,56.31) 40.68,56.5 37.81,56.5 36.41,57.89 36.41,58.44 34.79,60.06 30.45,60.06 29.29,58.9 26.55,58.9 26.15,59.29 26.15,60.51 25.37,61.29 24.87,61.29 23.54,62.61 23.54,64.6 24.38,65.44 v2(25.1,65.44)
  BOTTOM w0.127: v2(45.16,50.35) 45.16,50.48 44.54,51.1 43.71,51.1 42.55,52.27 42.55,52.33 41.59,53.29 40.62,53.29 39.9,54.01 39.9,55.34 v2(40.87,56.31)
TBT_JTAG_TCK: length 47.7
  TOP w0.127: 49.41,75.27 49.41,74.06 49.12,73.77 RT7.2 ; 49.41,75.27 49.41,75.87 49.25,76.04 48.83,76.04 48.6,76.27 48.22,76.27 47.6,75.65 v3(47.6,74.2) 47.6,73.36 47.5,73.26 v2(47.5,72.09) ; 49.41,75.27 JAR1.3 ; UT1.T4 44.44,56.62 44.13,56.31 v2(44.12,56.31)
  IN4 w0.081: v2(44.12,56.31) 44.32,56.31 47.14,53.49 47.14,53.17 47.73,52.59 48.46,52.59 48.93,53.06 49.44,53.06 49.82,53.44 51.63,53.44 53.58,55.39 53.58,59.63 52.08,61.14 52.08,63.3 52.71,63.93 53.58,63.93 53.99,64.33 53.99,66.06 53.25,66.79 53.25,69.34 51.86,70.73 51.86,71.46 52.27,71.87 52.54,71.87 52.68,72.01 52.68,72.67 52.4,72.94 51.27,72.94 50.16,71.83 47.76,71.83 v2(47.5,72.09)
TBT_JTAG_TDI: length 34.2
  TOP w0.127: JAR1.1 51.41,74.53 51.03,74.15 RT9.2 51.22,73.28 51.46,73.03 v2(51.46,72.25) ; UT1.Y4 v2(46.07,56.94)
  IN4 w0.081: v2(46.07,56.94) 46.07,56.92 46.08,56.92 46.08,56.35 46.14,56.28 46.14,55.39 47.51,54.02 48.61,54.02 49.52,54.93 51.02,54.93 51.45,55.36 51.45,64.16 51.15,64.46 50.75,64.46 50.56,64.27 50.27,64.27 49.87,64.66 49.87,66.75 49.3,67.32 49.3,68.84 47.8,70.33 47.8,71.24 48.19,71.63 50.84,71.63 v2(51.46,72.25)
TBT_JTAG_TDO: length 32.6
  TOP w0.127: UT1.W4 v2(45.43,56.94) ; v2(48.35,71.19) 47.92,71.62 47.92,73.08 48.24,73.4 RT6.2 48.49,74.02 48.41,74.1 JAR1.4
  IN4 w0.081: v2(48.35,71.19) 48.34,71.19 48.34,70.08 49.48,68.94 50.55,68.94 51.5,67.99 51.5,66.44 51.93,66.01 51.93,65.33 51.66,65.05 51.66,54.72 50.8,53.86 49.64,53.86 49.32,53.54 48.64,53.54 48.37,53.81 47.42,53.81 45.49,55.74 45.49,56.88 45.43,56.94 v2(45.43,56.94)
TBT_JTAG_TMS: length 39.7
  TOP w0.127: v2(52.27,72.42) 51.92,72.78 51.92,75.97 51.56,76.32 51.23,76.32 50.41,75.5 JAR1.2 50.41,74.3 50.27,74.16 RT8.2 ; v2(44.78,56.93) 44.79,56.93 UT1.V4
  IN4 w0.081: v2(44.78,56.93) 44.78,56.16 47.35,53.59 47.35,53.26 47.81,52.8 48.37,52.8 48.84,53.27 49.34,53.27 49.73,53.65 50.89,53.65 51.87,54.63 51.87,58.35 52.43,58.91 52.43,59.67 52.58,59.83 52.58,60.34 51.87,61.05 51.87,63.38 52.62,64.13 53.49,64.13 53.78,64.42 53.78,65.97 52.35,67.4 52.35,68.4 51.35,69.4 51.35,71.57 52.2,72.42 v2(52.27,72.42)
TBT_LDO_BMC: length 2.1
  TOP w0.076: U722.E1 24.08,64.54 24.08,65.36
  TOP w0.127: 24.08,65.36 24.65,65.93 CT144.1
TBT_LSRX: length 27.5
  TOP w0.127: UT1.A4 37.18,56.84 36.94,57.08 35.68,57.08 v2(35.59,56.98) RT45.2 ; v2(17.61,63.17) 17.19,63.17 R1464.1
  IN1 w0.081: v2(19.46,63.23) 19.39,63.17 17.61,63.17 v2(17.61,63.17)
  IN3 w0.089: v2(35.59,56.98) 35.52,57.04 34.87,57.04 34.14,56.31 33.3,56.31 32.33,57.28 29.36,57.28 29.09,57.54 26.97,57.54 24.61,59.91 24.61,60.63 23.89,61.35 21.34,61.35 v2(19.46,63.23)
  BOTTOM w0.127: R1461.1 20.98,62.26 20.68,61.96 20.14,61.96 19.97,62.13 19.97,62.72 v2(19.46,63.23)
TBT_LSRX_R: length 1.5
  TOP w0.076: v2(21.92,63.18) 21.71,62.97 21.51,62.97 U722.K4
  BOTTOM w0.127: R1461.2 21.71,62.97 v2(21.92,63.18)
TBT_LSTX: length 33
  TOP w0.127: R1463.1 v2(16.45,64.5) ; UT1.A5 37.44,57.3 36.67,57.3 36.4,57.57 v2(35.59,57.57) 35.54,57.62 RT44.2 ; R1459.1 16.43,61.19 v2(16.43,61.6)
  IN3 w0.089: v2(16.43,61.6) 16.43,64.49 v2(16.45,64.5) 17.17,64.5 18.58,65.91 20.52,65.91 22.35,64.07 22.35,63.19 24.69,60.86 25.19,60.86 25.72,60.33 25.72,59.1 27.06,57.76 29.18,57.76 29.45,57.5 32.42,57.5 33.39,56.52 34.05,56.52 35.09,57.57 v2(35.59,57.57)
  BOTTOM w0.127: v3(16.05,62.49) 16.43,62.11 v2(16.43,61.6)
TBT_LSTX_R: length 5.4
  TOP w0.076: v2(20.04,63.24) 20.04,63.2 20.11,63.13 20.47,63.13 20.47,63.13 20.78,63.13 20.94,62.97 U722.L4
  TOP w0.127: v2(17.03,61.6) 17.03,61.18 R1459.2
  IN1 w0.081: v2(20.04,63.24) 19.5,62.69 18.12,62.69 v2(17.03,61.6)
TBT_PCIE_WAKE#: length 43.3
  TOP w0.076: UT1.W1 45.72,55.45 45.72,55.23 45.77,55.18 45.77,54.56 45.61,54.4
  TOP w0.127: RT22.2 45.57,53.9 v2(45.47,54) 45.47,54.26 45.61,54.4
  IN2 w0.089: v2(45.47,54) 45.46,54 45.46,54 45.13,54 44.58,53.45 43.47,53.45 42.48,52.46 42.48,52.43 41.32,51.27 41.32,50.18 40.28,49.15 40.28,46.42 39.62,45.76 39.62,36.67 39.08,36.13 39.08,34.82 38.75,34.49 38.75,31.85 38.96,31.63 v2(38.96,30.97)
  IN3 w0.089: v2(38.96,30.97) 39.35,30.97 39.82,31.45 44.23,31.45 44.36,31.32 46.22,31.32 46.53,31.63 47.44,31.63 47.97,32.17 47.97,34.66 v2(47.37,35.26)
  BOTTOM w0.127: v2(47.37,35.26) 46.94,35.26 RE120.1
TBT_PD_SBU1: length 3.9
  TOP w0.076: 20.82,60.73 21.27,60.73 21.36,60.82 21.36,60.82 U722.K8
  TOP w0.127: 20.82,60.73 20.76,60.73 19.35,59.32 19.17,59.32 18.64,58.8 R1457.1
TBT_PD_SBU2: length 3.4
  TOP w0.127: R1458.1 18.4,59.22 18.71,59.53 19.21,59.53 20.66,60.97 U722.L8
TBT_PERST_N: length 5.7
  TOP w0.127: UT1.L4 41.56,56.9 41.56,56.9 v2(41.53,56.94) ; R104.2 41.89,53.72 v2(41.51,54.09)
  BOTTOM w0.127: v2(41.53,56.94) 41.57,56.9 41.57,56.02 41.14,55.6 40.88,55.6 40.41,55.13 40.41,54.4 40.72,54.09 v2(41.51,54.09)
TBT_PWR_EN: length 25.5
  TOP w0.127: v2(155.07,58.68) 155.7,59.32 v3(155.7,59.45)
  IN3 w0.089: v2(148.13,52.44) 147.58,51.88 144.02,51.88 143.02,52.88 143.02,55.93 144.03,56.94 144.03,57.54 145.57,59.08 149.92,59.08 150.14,59.31 152.75,59.31 153.37,58.68 v2(155.07,58.68)
  BOTTOM w0.127: v2(155.07,58.68) 155.4,59.01 RH556.1 ; UCPU1.AW7 148.37,52.2 v2(148.13,52.44)
TBT_RBIAS: length 13.5
  TOP w0.127: RT10.1 43.66,50.26 v2(44.22,49.7) ; UT1.H6 40.87,57.59 v2(40.87,57.59)
  BOTTOM w0.127: v2(40.87,57.59) 40.69,57.41 40.69,56.79 39.65,55.75 39.65,53.9 40.51,53.03 41.49,53.03 42.28,52.24 42.28,52.03 v1(42.89,51.42) 43.46,50.85 44.39,50.85 44.74,50.49 44.74,50.08 44.36,49.7 v2(44.22,49.7)
TBT_RESET_N: length 16.1
  TOP w0.127: U722.F11 23.5,59.46 v2(23.5,58.86) ; RT120.1 28.66,46.21 27.61,47.27 v2(27.14,47.27)
  IN3 w0.089: v2(27.14,47.27) 26.81,47.27 25.95,48.13 25.95,54.51 23.5,56.96 v2(23.5,58.86)
TBT_RESET_N_R: length 26.2
  TOP w0.127: RT120.2 29.59,46.8 RT121.2 29.62,47.89 30.36,48.64 32.32,48.64 RT51.2 32.77,48.37 33.03,48.64 v2(35.21,48.64) ; v2(39.58,56.94) 39.57,56.92 39.88,56.62 39.9,56.62 UT1.F4
  IN1 w0.081: v2(35.21,48.64) 35.98,47.86 36.53,47.86 36.84,48.18 37.47,48.18 39,49.7 40.82,49.7 41.33,50.21 v2(41.78,50.21)
  BOTTOM w0.127: v2(39.58,56.94) 38.34,55.69 38.34,53.67 38.55,53.46 39.36,53.46 40.13,52.69 40.13,52.24 39.99,52.1 39.99,51.35 41.14,50.21 v2(41.78,50.21)
TBT_ROM_CLK: length 30.2
  TOP w0.076: v2(48.53,55.84) 48.53,55.93 47.85,56.6 47.33,56.6 47.1,56.83 UT1.AB4
  TOP w0.127: v3(48.95,43.52) v2(47.88,43.52) 47.34,43.52 46.94,43.93 45.77,43.93 44.02,42.18 44.02,41.62 UT5.6
  BOTTOM w0.127: v2(47.88,43.52) 48.93,43.52 49.54,42.91 50.35,42.91 50.87,42.39 51.49,42.39 51.88,42.78 51.88,44.64 51.18,45.34 51.18,46.34 50.82,46.69 50.82,48.55 48.44,50.94 48.44,52.22 46.99,53.67 46.99,55.14 47.69,55.84 v2(48.53,55.84)
TBT_ROM_CS#: length 29.9
  TOP w0.076: UT1.AC3 47.75,56.38 48.08,56.04 48.08,55.66 48.5,55.24 v2(48.58,55.24)
  TOP w0.127: UT5.1 49.15,38.36 48.39,39.12 48.39,40.04 v2(48.57,40.22) ; UT5.1 49.15,36.94 v3(48.69,36.48) ; UT5.1 RT18.2
  IN2 w0.089: v2(48.58,55.24) 48.36,55.46 47.13,55.46 46.94,55.27 46.94,54.62 47.87,53.69 48.47,53.69 49.55,52.61 49.55,50.6 47,48.06 47,44.03 47.29,43.74 47.29,42.33 48.08,41.54 48.08,39.86 48.49,39.46 48.87,39.46 49.05,39.63 49.05,39.96 48.79,40.22 v2(48.57,40.22)
TBT_ROM_DI: length 22.3
  TOP w0.076: v2(48.03,54.97) 47.86,55.15 47.86,56.01 47.72,56.15 47.33,56.15 UT1.AB3
  TOP w0.127: v2(47.8,44.1) 47.14,44.1 47.06,44.18 45.64,44.18 43.58,42.12 UT5.5 42.88,42.12 v3(41.75,41)
  IN2 w0.089: v2(48.03,54.97) 48.13,54.87 48.13,54.33 49.77,52.7 49.77,50.51 47.31,48.05 47.31,45.77 47.9,45.17 47.9,44.2 v2(47.8,44.1)
TBT_ROM_DO: length 29.4
  TOP w0.127: v2(49.63,40.19) 49.15,39.71 UT5.2 49.53,39.2 RT16.2 ; v2(48.73,56.4) 48.72,56.41 48.71,56.41 48.32,56.79 47.73,56.79 47.68,56.84 UT1.AC4
  IN2 w0.089: v2(49.63,40.19) 49.47,40.19 49.26,39.99 49.26,39.54 48.96,39.24 48.4,39.24 47.87,39.77 47.87,41.45 47.07,42.24 47.07,43.65 46.79,43.94 46.79,48.29 48.67,50.17 48.67,52.36 48.17,52.86 47.56,52.86 46.9,53.52 46.9,54.36 46.72,54.53 46.72,55.6 47.52,56.4 v2(48.73,56.4)
  BOTTOM w0.127: v2(48.73,56.4) 47.54,56.4 v3(46.74,55.6)
TBT_ROM_HOLD#: length 5.5
  TOP w0.127: v3(42.83,36.53) 42.83,36.6 44.03,37.8 44.03,39.02 43.46,39.58 UT5.7 42.02,39.58 RT15.2
TBT_ROM_WP#: length 22.9
  TOP w0.127: UT1.V1 45.26,54.95 v2(45.19,54.87) ; v2(46.58,42.81) 50.17,42.81 50.64,42.34 v3(50.64,41.36) 50.64,40.89 50.74,40.79 RT17.2 50.18,40.34 49.67,40.85 UT5.3
  IN2 w0.089: v2(46.58,42.81) 46.58,42.94 46.13,43.4 46.13,48.24 47.65,49.77 47.65,51.47 47.29,51.83 47.29,52.51 46.46,53.34 46.46,54.18 45.77,54.87 v2(45.19,54.87)
TBT_RSENSE: length 10.4
  TOP w0.127: v2(40.87,58.25) 40.87,58.25 UT1.J6 ; RT10.2 43.66,51.77 v2(43.35,52.08)
  BOTTOM w0.127: v2(43.35,52.08) 43.16,52.08 41.7,53.54 40.73,53.54 40.15,54.11 40.15,55.23 40.77,55.85 41.04,55.85 41.31,56.13 41.31,56.52 41.11,56.73 41.11,57.18 41.31,57.39 41.31,57.81 v2(40.87,58.25)
TBT_SBU1: length 12.9
  TOP w0.127: R1457.2 17.98,58.63 17.32,57.98 v3(17.15,57.98) 16.79,57.62 15.17,57.62 15.02,57.76 14.36,57.76 13.99,57.39 12.9,57.39 12.28,58.01 12.28,58.59 11.21,59.67 10.04,59.67 9.82,59.44 9.18,59.44 D78.1 8.29,59.74 7.99,60.04 JUSBC1.A8
TBT_SBU2: length 30.8
  TOP w0.127: v1(15.16,67.33) v2(14.68,66.85) 14.35,66.85 14.07,66.57 D87.1 ; R1458.2 17.43,58.94 v2(17.43,58.7)
  IN1 w0.081: JUSBC1.B8 4.13,62.88 4.13,65.71 4.61,66.18 7.76,66.18 8.37,65.57 13.07,65.57 14.35,66.85 v2(14.68,66.85) 14.88,66.65 14.88,63.75 15.72,62.92 15.72,57.78 15.98,57.52 16.65,57.52 17.43,58.3 v2(17.43,58.7)
TBT_SLP_S3#: length 3.7
  TOP w0.076: RT119.2 38.46,53.81 38.74,54.09 38.74,54.99 39.04,55.29 39.04,55.7 UT1.D2
  TOP w0.127: v3(37.53,53.46) RT119.2
TBT_SRC_CFG1: length 4.7
  TOP w0.127: v2(48.18,53.26) 48.39,53.46 R1403.1 48.22,53.98 47.48,53.98 46.64,54.82 UT1.AA1
  BOTTOM w0.127: v2(48.18,53.26) 48.18,53.06 v3(48.56,52.68)
TBT_SRC_HPD: length 2.4
  TOP w0.127: R1405.1 41.15,53.73 40.97,53.91 v3(40.97,54.25) 40.36,54.85 40.36,55.3 UT1.G1
TBT_SVR_IND:
  vias: v3(35.3,53.95)
TBT_TEST_EN: length 2.8
  TOP w0.127: UT1.E1 39.28,55.46 39.28,55.08 39.09,54.89 v2(39.09,54.83) 39.04,54.77 39.04,53.47 RT3.2
  BOTTOM w0.127: v2(39.09,54.83) v1(39.09,54.16)
TBT_TEST_PWRG: length 3.7
  TOP w0.076: 47.78,57.06 47.34,57.06 UT1.AB5
  TOP w0.127: RT4.2 49.31,56.6 48.93,56.98 v2(48.74,56.98) 48.72,57.01 47.83,57.01 47.78,57.06
  BOTTOM w0.127: v3(47.64,57.17) 47.82,56.98 v2(48.74,56.98)
TBT_TMU_CLK_OUT: length 2.8
  TOP w0.076: UT1.V2 45.49,55.69 45.49,55.18 45.57,55.1 45.57,54.71
  TOP w0.127: 45.57,54.71 45.01,54.16 45.01,53.54 RT37.2
TBT_USB2_D_N: length 39.4
  TOP w0.076: U722.K5 21.35,62.63 21.25,62.73 20.88,62.73 20.76,62.85 19.32,62.85 19.3,62.88 19.28,62.88
  TOP w0.127: v2(16.72,67.02) 16.79,67.09 16.79,67.25 16.65,67.38 16.4,67.38 14.85,65.83 14.85,64.19 16.73,62.31 18.35,62.31 18.92,62.88 19.28,62.88 ; UT1.D20 38.61,64.42 v2(38.93,64.11)
  IN4 w0.091: v2(16.72,67.02) 16.72,67.27 16.88,67.43 17.48,67.43 19.08,69.03 23.25,69.03 24.87,67.4 29.86,67.4 30.02,67.56 37.04,67.56 38.28,66.33 38.28,65.39 39.19,64.48 39.19,64.31 38.99,64.11 v2(38.93,64.11)
TBT_USB2_D_P: length 39.4
  TOP w0.076: U722.L5 20.96,62.52 20.8,62.52 20.67,62.65 19.32,62.65 19.3,62.62 19.28,62.62
  TOP w0.127: v2(16.72,67.8) 16.56,67.64 16.29,67.64 14.59,65.94 14.59,64.09 16.63,62.05 18.45,62.05 19.02,62.62 19.28,62.62 ; v2(39.57,64.08) 39.25,64.4 UT1.E20
  IN4 w0.091: v2(39.57,64.08) 39.38,64.27 39.38,64.56 38.47,65.47 38.47,66.41 37.12,67.76 29.94,67.76 29.78,67.59 24.95,67.59 23.33,69.22 19,69.22 17.4,67.62 16.9,67.62 v2(16.72,67.8)
TBT_USB2_T_N: length 8.5
  TOP w0.076: v2(19.55,61.69) 19.55,61.75 19.77,61.97 U722.L6
  TOP w0.127: v2(16.44,58.65) 16.19,58.9 15.77,58.9 15.65,58.77 ML6.4
  IN1 w0.091: v2(16.44,58.65) 16.83,59.05 17.13,59.05 18.22,60.14 18.22,61.93 18.39,62.11 18.88,62.11 19.02,61.96 19.28,61.96 v2(19.55,61.69)
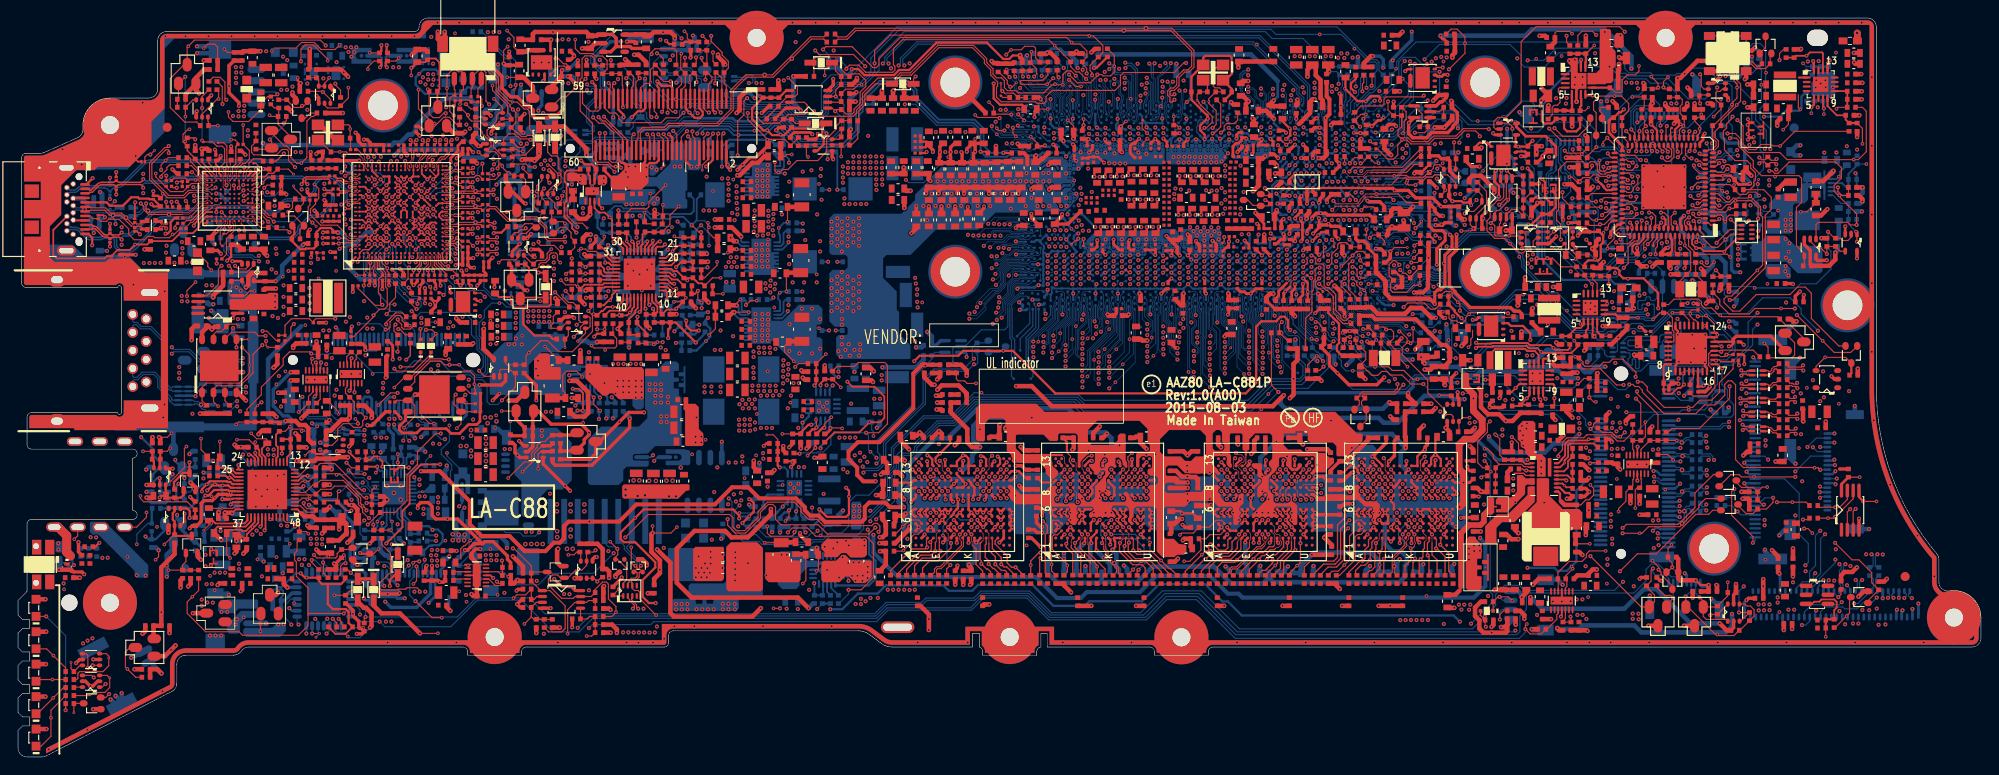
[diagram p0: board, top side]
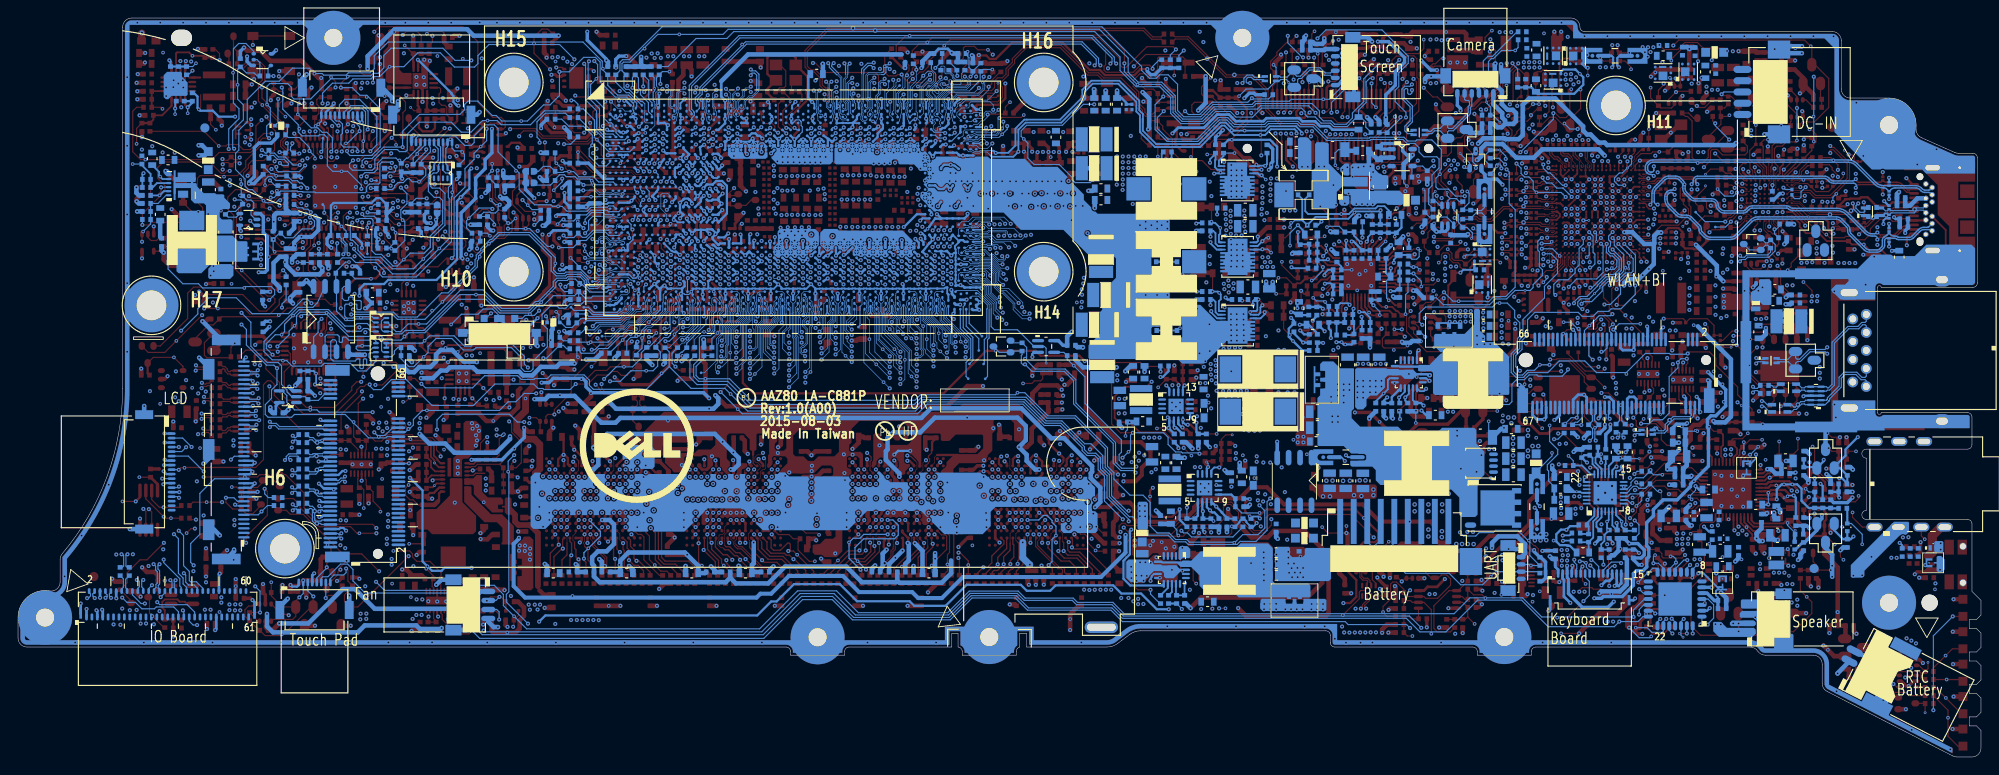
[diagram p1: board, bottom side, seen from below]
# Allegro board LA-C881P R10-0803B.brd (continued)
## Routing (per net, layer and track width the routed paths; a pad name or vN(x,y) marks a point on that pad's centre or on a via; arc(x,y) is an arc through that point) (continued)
TBT_USB2_T_N_R: length 7.7
  TOP w0.127: JUSBC1.A7 7.92,60.54 8.06,60.68 9.62,60.68 10.19,60.11 v4(10.53,60.11) 11.38,60.11 12.59,58.89 12.89,58.89 12.95,58.83 D83.1 13.14,58.89 13.63,58.89 ML6.3
TBT_USB2_T_P: length 8.6
  TOP w0.076: U722.K6 21.33,62.15 21.25,62.23 20.84,62.23 20.79,62.18 19.65,62.18 v2(19.55,62.28)
  TOP w0.127: ML6.1 15.92,59.15 16.35,59.15 v2(16.44,59.24)
  IN1 w0.091: v2(16.44,59.24) 17.05,59.24 18.02,60.22 18.02,62.01 18.31,62.3 18.96,62.3 19.1,62.15 19.42,62.15 v2(19.55,62.28)
TBT_USB2_T_P_R: length 7.6
  TOP w0.127: ML6.2 13.67,59.15 13.15,59.15 D82.1 12.95,59.24 12.86,59.15 12.7,59.15 v4(11.99,59.86) 11.49,60.36 10.3,60.36 9.72,60.94 8.06,60.94 7.95,61.04 JUSBC1.A6
TBT_USB3_RX0_N: length 37
  TOP w0.076: v2(36.3,65.55) 36.23,65.48 36.23,65.06 36.42,64.87 37.07,64.87 37.28,64.66 UT1.A21
  BOTTOM w0.163: JUSBC1.B10 5.59,62.56 arc(5.69,62.63) 5.8,62.65 6.22,62.65 arc(6.46,62.7) 6.67,62.83 6.82,62.98 arc(7,63.1) 7.21,63.14 9.54,63.14 arc(9.79,63.09) 10.01,62.95 D85.1 10.5,63.06 arc(10.59,63.12) 10.69,63.14 10.82,63.14 arc(10.86,63.14) 10.9,63.15 arc(11.4,63.27) 11.82,63.57 12.02,63.76 13.92,65.66 arc(14.29,65.91) 14.73,66 36.41,66 arc(36.6,65.96) 36.75,65.86 36.89,65.72 arc(36.97,65.6) 36.99,65.46 36.99,65.23 36.99,65.23 arc(36.97,65.13) 36.92,65.04 36.87,64.99 arc(36.77,64.92) 36.65,64.9 36.53,64.9 arc(36.37,64.97) 36.3,65.13 v2(36.3,65.55)
TBT_USB3_RX0_P: length 37
  TOP w0.076: UT1.B21 37.73,64.49 37.73,64.49 37.68,64.43 37.27,64.43 37,64.71 36.54,64.71 v2(36.31,64.48)
  BOTTOM w0.163: JUSBC1.B11 5.65,62.96 arc(5.72,62.91) 5.8,62.9 6.22,62.9 arc(6.37,62.93) 6.49,63.01 6.64,63.16 arc(6.9,63.33) 7.21,63.4 D84.1 10.8,63.4 arc(11.26,63.49) 11.64,63.74 13.74,65.84 arc(14.19,66.14) 14.73,66.25 36.41,66.25 arc(36.69,66.19) 36.93,66.03 37.06,65.9 arc(37.2,65.7) 37.24,65.46 37.24,65.23 arc(37.2,65.03) 37.09,64.86 37.09,64.86 37.05,64.81 arc(36.86,64.69) 36.65,64.65 arc(36.49,64.61) 36.35,64.52 v2(36.31,64.48)
TBT_USB3_RX1_N: length 37.4
  TOP w0.076: v2(36.69,61.29) 36.51,61.48 36.51,61.58 36.59,61.67 37.67,61.67 UT1.B15
  TOP w0.163: JUSBC1.A10 8.18,59.04 8.3,58.92 8.4,58.92 arc(8.61,58.88) 8.78,58.76 9.51,58.03 arc(9.62,57.96) 9.74,57.93 9.9,57.93 arc(10,57.95) 10.08,58.01 D79.1 10.28,58.04 arc(10.4,57.96) 10.55,57.93 11.16,57.93 arc(11.22,57.94) 11.28,57.98 v2(11.5,58.2)
  BOTTOM w0.163: v2(36.69,61.29) 36.6,61.39 arc(36.53,61.48) 36.51,61.59 36.51,62.53 arc(36.43,62.91) 36.22,63.24 35.94,63.52 35.23,64.23 arc(34.97,64.4) 34.66,64.46 33.89,64.46 arc(33.58,64.4) 33.32,64.23 33.07,63.97 arc(32.89,63.71) 32.83,63.4 32.83,63.06 arc(32.79,62.85) 32.67,62.67 32.1,62.11 arc(31.93,61.99) 31.71,61.95 29.88,61.95 arc(29.36,61.73) 29.14,61.21 arc(29.12,61.06) 29.04,60.95 28.86,60.77 arc(28.68,60.65) 28.47,60.61 26.36,60.61 arc(26.25,60.63) 26.15,60.69 25.92,60.92 arc(25.66,61.1) 25.35,61.16 21.57,61.16 arc(21.35,61.11) 21.16,60.99 arc(21.04,60.91) 20.9,60.88 15.98,60.88 arc(15.32,60.75) 14.76,60.37 12.7,58.31 arc(12.42,58.12) 12.09,58.06 11.84,58.06 arc(11.65,58.1) v2(11.5,58.2)
TBT_USB3_RX1_P: length 37.4
  TOP w0.076: UT1.A15 37.38,61.83 36.52,61.83 36.34,61.65 36.34,61.53 36.11,61.29 v2(35.87,61.29)
  TOP w0.163: v2(11.5,57.41) 11.28,57.63 arc(11.22,57.67) 11.16,57.68 10.55,57.68 arc(10.4,57.65) 10.28,57.57 D80.1 10.04,57.64 arc(10,57.67) 9.95,57.68 9.74,57.68 arc(9.52,57.72) 9.34,57.85 8.63,58.55 8.6,58.58 arc(8.51,58.64) 8.4,58.66 8.3,58.66 8.18,58.54 JUSBC1.A11
  BOTTOM w0.163: v2(11.5,57.41) 11.5,57.54 arc(11.58,57.73) 11.76,57.81 12.09,57.81 arc(12.51,57.89) 12.87,58.13 14.94,60.19 arc(15.42,60.51) 15.98,60.63 20.9,60.63 arc(21.14,60.68) 21.34,60.81 arc(21.45,60.88) 21.57,60.91 25.35,60.91 arc(25.56,60.86) 25.75,60.74 25.82,60.67 25.97,60.52 arc(26.15,60.4) 26.36,60.36 28.47,60.36 arc(28.78,60.42) 29.04,60.59 29.21,60.77 arc(29.35,60.97) 29.39,61.21 arc(29.54,61.55) 29.88,61.69 31.71,61.69 arc(32.02,61.76) 32.28,61.93 32.85,62.49 arc(33.02,62.76) 33.08,63.06 33.08,63.4 arc(33.12,63.61) 33.24,63.79 33.5,64.05 arc(33.68,64.17) 33.89,64.21 34.66,64.21 arc(34.87,64.17) 35.05,64.05 36.04,63.06 arc(36.2,62.82) 36.26,62.53 36.26,61.66 arc(36.15,61.4) 35.89,61.29 v2(35.87,61.29)
TBT_USB3_TX0_N: length 29.8
  TOP w0.163: v2(31.47,63.56) 31.52,63.61 arc(31.6,63.73) 31.63,63.88 31.63,63.96 arc(31.75,64.25) 32.04,64.37 34.32,64.37 arc(34.46,64.4) CT40.2 ; JUSBC1.A3 7.82,62.54 7.95,62.66 8.23,62.66 8.88,63.32 arc(9.11,63.47) 9.37,63.52 10.49,63.52 arc(10.69,63.48) 10.86,63.37 D76.1 11,63.43 arc(11.1,63.5) 11.22,63.52 13.53,63.52 arc(13.78,63.42) v2(13.89,63.16)
  BOTTOM w0.163: v2(31.47,63.56) 31.62,63.71 arc(31.66,63.78) 31.68,63.85 31.68,63.96 arc(31.61,64.13) 31.45,64.19 17.31,64.19 arc(17.14,64.13) 17,64.03 16.85,63.87 arc(16.63,63.72) 16.37,63.67 14.13,63.67 arc(13.85,63.49) v2(13.89,63.16)
TBT_USB3_TX0_N_C: length 3.1
  TOP w0.076: UT1.B19 37.68,63.95 37.17,63.95 37.06,63.84 36.54,63.84 36.49,63.88 36.47,63.88
  TOP w0.163: 36.47,63.88 36.26,63.88 35.93,64.22 35.41,64.22 CT40.1
TBT_USB3_TX0_P: length 29.8
  TOP w0.163: JUSBC1.A2 7.82,63.04 7.95,62.92 8.12,62.92 8.71,63.5 arc(9.01,63.7) 9.37,63.77 10.49,63.77 arc(10.69,63.81) 10.86,63.93 D75.1 11,63.87 arc(11.1,63.8) 11.22,63.77 13.54,63.77 arc(13.79,63.88) v2(13.89,64.12) ; CT39.2 arc(34.59,63.98) 34.36,64.12 32.04,64.12 arc(31.93,64.07) 31.88,63.96 31.88,63.79 arc(31.95,63.63) v2(32.11,63.56)
  BOTTOM w0.163: v2(32.11,63.56) 32.01,63.66 arc(31.95,63.75) 31.93,63.85 31.93,63.96 arc(31.79,64.3) 31.45,64.45 17.28,64.45 arc(17.03,64.36) 16.83,64.2 16.66,64.04 arc(16.53,63.95) 16.37,63.92 14.23,63.92 arc(14.1,63.95) 14,64.02 v2(13.89,64.12)
TBT_USB3_TX0_P_C: length 3.2
  TOP w0.076: 36.47,63.63 36.49,63.63 36.54,63.68 36.97,63.68 37.15,63.49 37.54,63.49 37.63,63.58 37.63,63.67 37.56,63.74 UT1.A19
  TOP w0.163: 36.47,63.63 36.16,63.63 35.83,63.97 35.41,63.97 CT39.1
TBT_USB3_TX1_N: length 38.9
  TOP w0.163: v2(33.99,62.38) 34.08,62.47 arc(34.22,62.57) 34.39,62.6 34.54,62.6 arc(34.73,62.56) 34.89,62.46 CT38.2
  BOTTOM w0.163: JUSBC1.B3 5.76,58.85 arc(5.81,58.81) 5.87,58.78 arc(5.91,58.77) 5.94,58.77 6.33,58.77 arc(6.66,58.71) 6.94,58.52 7.68,57.77 arc(7.8,57.69) 7.95,57.66 9.12,57.66 arc(9.17,57.67) 9.22,57.68 arc(9.37,57.77) 9.54,57.8 9.65,57.8 arc(10.03,57.95) D89.1 arc(10.26,58.09) 10.42,57.92 10.72,57.73 arc(10.76,57.71) 10.79,57.68 arc(10.91,57.52) 10.95,57.33 10.95,56.77 arc(10.96,56.69) 11,56.63 11.23,56.4 arc(11.37,56.3) 11.54,56.27 12.38,56.27 arc(12.59,56.31) 12.76,56.43 14.43,58.09 arc(14.52,58.23) 14.55,58.38 14.55,58.52 arc(14.6,58.78) 14.75,59 15.43,59.68 arc(15.71,59.87) 16.04,59.94 24.74,59.94 arc(25.19,59.85) 25.57,59.59 27.27,57.89 arc(27.5,57.74) 27.78,57.68 30.06,57.68 arc(30.32,57.73) 30.54,57.88 30.95,58.29 arc(31.01,58.38) 31.03,58.47 31.03,58.6 arc(31.07,58.79) 31.18,58.96 32.11,59.89 arc(32.37,60.07) 32.68,60.13 33.19,60.13 arc(33.44,60.18) 33.65,60.32 34.55,61.21 arc(34.76,61.53) 34.83,61.91 34.83,62.18 arc(34.8,62.34) 34.71,62.47 34.62,62.57 arc(34.52,62.63) 34.4,62.66 arc(34.28,62.63) 34.18,62.57 v2(33.99,62.38)
TBT_USB3_TX1_N_C: length 2.7
  TOP w0.076: 36.26,62.58 36.29,62.58 36.33,62.62 36.53,62.62 36.66,62.75 37.11,62.75 37.26,62.59 37.68,62.59 37.9,62.82 UT1.B17
  TOP w0.163: 36.26,62.58 35.72,62.58 CT38.1
TBT_USB3_TX1_P: length 38.9
  TOP w0.163: CT37.2 34.9,62.98 arc(34.76,62.88) 34.59,62.85 34.23,62.85 arc(34.17,62.86) 34.12,62.9 v2(33.99,63.03)
  BOTTOM w0.163: v2(33.99,63.03) arc(34.12,62.94) 34.27,62.91 34.4,62.91 arc(34.61,62.87) 34.8,62.74 34.89,62.65 34.89,62.65 arc(35.03,62.44) 35.08,62.18 35.08,61.9 arc(34.99,61.43) 34.72,61.04 34.04,60.35 33.83,60.14 arc(33.54,59.95) 33.19,59.88 32.68,59.88 arc(32.47,59.83) 32.29,59.72 31.36,58.78 arc(31.3,58.7) 31.28,58.6 31.28,58.47 arc(31.24,58.28) 31.13,58.11 30.72,57.7 arc(30.42,57.5) 30.06,57.43 27.78,57.43 arc(27.4,57.5) 27.09,57.71 25.39,59.41 arc(25.09,59.61) 24.74,59.68 16.04,59.68 arc(15.8,59.64) 15.61,59.5 14.93,58.83 arc(14.83,58.68) 14.8,58.52 14.8,58.38 arc(14.75,58.13) 14.6,57.92 12.94,56.25 arc(12.68,56.08) 12.38,56.02 11.54,56.02 arc(11.28,56.07) 11.06,56.22 10.82,56.45 arc(10.73,56.59) 10.69,56.77 10.69,57.33 arc(10.63,57.49) 10.47,57.55 D88.1 9.54,57.55 arc(9.45,57.53) 9.37,57.48 arc(9.25,57.43) 9.12,57.41 7.95,57.41 arc(7.71,57.46) 7.51,57.59 6.83,58.27 6.76,58.34 arc(6.56,58.47) 6.33,58.52 5.74,58.52 arc(5.56,58.49) JUSBC1.B2
TBT_USB3_TX1_P_C: length 2.7
  TOP w0.076: 36.26,62.83 36.29,62.83 36.33,62.79 36.46,62.79 36.59,62.91 37.06,62.91 37.2,63.05 37.56,63.05 37.63,62.98 37.63,62.86 37.58,62.82 37.44,62.82 UT1.A17
  TOP w0.163: CT37.1 35.73,62.83 36.26,62.83
TBT_USB_OC0#: length 177.2
  TOP w0.127: v2(18.62,61.7) 18.79,61.52 R1438.2
  IN3 w0.089: v2(148.44,74.41) 148.26,74.41 147.93,74.08 147.93,73.88 146.37,72.32 143.64,72.32 143.15,72.81 143.15,74.46 142.95,74.66 142.75,74.66 142.63,74.77 141.39,74.77 140.77,74.15 140.77,72.86 138.37,70.46 137.54,70.46 137.29,70.21 136.65,70.21 136.54,70.33 135.52,70.33 135.52,70.34 134.6,71.26 129.51,71.26 129.01,70.75 127.64,70.75 127.13,71.26 121.82,71.26 121.2,70.64 117.52,70.64 117.15,70.27 113.71,70.27 113.46,70.03 113.46,69.71 112.96,69.2 111.46,69.2 110.77,68.51 106.94,68.51 106.39,67.96 100.49,67.96 99.11,69.34 93.92,69.34 91.88,67.3 83.68,67.3 82.08,68.91 79.8,68.91 79.23,68.34 74.2,68.34 73.82,68.72 73.82,69.94 73.13,70.63 71.82,70.63 71.54,70.35 61.22,70.35 59.37,72.21 56.44,72.21 55.79,71.55 55.79,70.06 54.97,69.25 54.97,67.76 55.14,67.59 55.14,59.68 54.42,58.96 54.42,54.29 49.44,49.31 44.73,49.31 42.42,47 40.61,47 40.31,47.3 40.31,49.5 37.47,52.35 37.47,53.53 36.92,54.07 32.93,54.07 32.61,54.39 32.34,54.39 30.18,56.55 29.15,56.55 28.84,56.85 24.84,56.85 23.9,57.8 23.9,59.05 23.61,59.33 22.44,59.33 20.98,60.79 19.53,60.79 v2(18.62,61.7)
  BOTTOM w0.127: UCPU1.A9 147.47,72.6 147.83,72.96 147.83,75.09 RC189.1 v2(148.44,74.41)
TBT_VBUS: length 55.6
  TOP w0.254: JUSBC1.A9 6.17,59.54 JUSBC1.B4 ; JUSBC1.B9 6.17,62.04 JUSBC1.A4
  TOP w0.381: v2(52.62,76.98) 52.62,76.6 53.7,75.52 53.7,74.21 54.66,73.25 55.4,73.25 56.36,72.29 56.65,72.29 57.15,71.79 57.15,71.18 57.42,70.91 58.78,70.91 59.08,71.22 59.83,71.22 60.48,71.87 v2(60.48,72.42) ; D123.1 v2(13.06,55.73)
  TOP w0.508: PR264.1 80.98,74.08 80.06,73.16 80.06,71.79 v2(79.73,71.46)
  IN1 w0.508: v2(46.1,75.17) 51.19,75.17 52.62,76.6 v2(52.62,76.98)
  IN3 w0.508: v2(79.73,71.46) 78.15,73.04 65.37,73.04 64.65,72.32 60.58,72.32 v2(60.48,72.42)
  BOTTOM w0.381: v2(8.41,58.15) 8.41,58.4 8.1,58.71 C398.2 C401.2 ; CT9.1 9.86,56.18 v2(9.88,56.16)
  BOTTOM w0.508: C402.2 C397.2 7.87,61.17 7.06,61.99 JUSBC1.B9
  vias: v2(18.24,56.45) v2(18.23,55.86) v2(18.72,54.9) v2(19.31,54.87) v2(19.92,54.83) v2(44.65,74.89) v2(44.93,75.42) v2(45.21,74.63) v2(45.49,75.78) v2(45.52,75.17) v2(45.97,74.58) v2(46.08,75.75) v3(45.47,74.1)
TBT_VBUS_L: length 4.4
  TOP w0.127: v3(21.45,54.02) 21.06,54.42 21.06,54.81 LT106.1 ; U722.J11 22.01,59.18 ; U722.J11 U722.K11 ; U722.J11 U722.J10 ; U722.J11 U722.H11
TCLK_XDP: length 78.9
  TOP w0.127: JXDP1.57 64.6,71.92 64.35,71.67 63.49,71.67 62.64,72.53 62.64,74.91 v2(62.97,75.24) 63.09,75.37 RC139.2 ; v3(117.96,74.41) 117.34,74.41 v2(116.61,75.13)
  IN3 w0.089: v2(118.13,76.26) 118.13,75.65 117.62,75.13 v2(116.61,75.13) 116.3,74.82 109.3,74.82 106.33,71.86 102.42,71.86 99.42,74.85 92.54,74.85 91.87,74.17 90.43,74.17 89.98,73.73 79.83,73.73 78.12,75.43 77.12,75.43 76.45,74.77 76.11,74.77 75.87,75 75.87,75.27 75.72,75.42 70.41,75.42 69.82,76.01 65.75,76.01 65.44,75.7 63.42,75.7 v2(62.97,75.24)
  BOTTOM w0.076: UCPU1.B61 117.52,71.87 117.52,72.09 117.46,72.21 117.46,72.47 117.56,72.57 117.56,74.36 116.79,75.13 v2(116.61,75.13) ; v2(118.13,76.26) 118.13,75.04 118.77,74.41 118.77,72.4 UCPU1.A59
  BOTTOM w0.127: v2(118.13,76.26) 118.13,76.59 RC87.1
TDI_XDP: length 79.3
  TOP w0.127: v2(65.15,69.22) 65.1,69.17 JXDP1.56 ; v2(118.58,75.86) 118.58,76.41 118.09,76.9 RC81.2 118.59,77.66 118.59,78.36 117.84,79.11 117.09,79.11 v3(116.92,79.28) 116.35,79.85 97.91,79.85 95.53,77.47 95.53,76.79 95.24,76.51 94.86,76.51 92.55,78.82 89.63,78.82 v2(89.33,78.52)
  IN1 w0.081: v2(71.27,79.59) 69.81,78.13 69.81,77.38 69,76.57 68.46,76.57 67.89,76.01 67.36,76.01 v2(66.57,75.22)
  IN3 w0.089: v2(71.27,79.59) 71.27,79.52 71.74,79.06 72.08,79.06 72.26,79.24 73.42,79.24 73.75,78.9 78.66,78.9 80.73,76.83 83.51,76.83 84.59,77.91 88.72,77.91 v2(89.33,78.52)
  IN4 w0.081: v2(65.15,69.22) 65.43,69.5 65.43,72.02 66.7,73.29 66.7,75.09 v2(66.57,75.22)
  BOTTOM w0.076: v2(118.58,75.86) 118.58,75.74 119.13,75.19 119.13,72.69 119.29,72.54 119.29,72.18 119.25,72.08 119.25,71.89 119.29,71.8 119.29,71.55 119.28,71.5 119.18,71.16 119.15,71.07 119.15,70.96 119.1,70.78 119,70.61 119,70.51 UCPU1.D59
  BOTTOM w0.127: UCPU1.D59 118.53,70.69 UCPU1.D60 ; v2(89.33,78.52) 89.95,77.89 RC134.2
TDO_XDP: length 94.4
  TOP w0.127: v2(116.62,75.73) 117.53,74.82 118.98,74.82 119.76,75.6 v2(119.76,75.73) 120.23,75.73 120.38,75.58 121.24,75.58 121.64,75.98 v3(121.64,76.64) 121.64,77.83 RC82.2 ; v2(94.01,76.64) 92.69,77.95 88.9,77.95 v2(88.46,78.4) ; v2(63.81,70.98) 64.46,70.33 65.03,70.33 66.1,69.26 66.1,67.33 JXDP1.52
  IN3 w0.089: v2(88.46,78.4) 88.19,78.13 84.5,78.13 83.42,77.05 80.82,77.05 78.75,79.12 74.25,79.12 v2(73.63,79.74)
  IN4 w0.081: v2(94.01,76.64) 94.01,77.48 95.43,78.91 108.76,78.91 108.88,79.02 110.17,79.02 110.34,78.85 117.68,78.85 119.78,76.74 119.78,75.75 v2(119.76,75.73)
  BOTTOM w0.076: UCPU1.A61 117.73,72.32 117.73,74.62 v2(116.62,75.73) ; v2(119.76,75.73) 119.63,75.6 119.63,74.32 120.31,73.65 120.31,72.41 UCPU1.A56
  BOTTOM w0.127: v2(73.63,79.74) 72.69,80.68 66.46,80.68 63.55,77.77 63.55,76.97 64.61,75.91 64.61,74.38 65,73.98 65,72.73 63.81,71.54 v2(63.81,70.98) ; RC135.2 89,77.85 v2(88.46,78.4)
THERMATRIP2#: length 13.6
  TOP w0.127: UE5.B34 178.61,67.87 178.61,68.26 177.98,68.89 CE61.1 RE69.2 178.72,71.69 178.72,72.52 177.9,73.34 v3(177.14,73.34) 175.46,73.34 174.82,72.7 174.82,71.78 175.11,71.5 QE9.1
THERMATRIP3#: length 3.7
  TOP w0.127: RE67.1 190.5,60.13 189.87,60.13 189.59,59.85 189.59,59.55 v3(189.43,59.39) 189.21,59.62 189.21,59.94 189,60.14 188.58,60.14 188.46,60.02 UE5.A2
THERMDA: length 0.5
  TOP w0.127: UT1.AB23 UT1.AC23
THSEL_STRAP: length 16.9
  TOP w0.127: v3(181.23,75.5) 181.99,74.74 v2(181.99,74.28) 181.84,74.13 RE78.1 ; v2(181.31,67.24) 181.28,67.24 181.11,67.41 UE5.B29
  BOTTOM w0.127: v2(181.99,74.28) 180.72,74.28 179.87,73.43 179.11,73.43 177.63,71.94 177.63,67.69 178.57,66.74 180.97,66.74 181.31,67.08 v2(181.31,67.24)
TMS_XDP: length 76.5
  TOP w0.127: JXDP1.58 64.56,67.37 v2(64.56,69.22) ; v2(91.91,76.36) 91.91,76.44 92.25,76.77 93.27,76.77 94.06,75.98 97.06,75.98 97.3,76.22 97.3,76.65 97.13,76.81 97.13,78.58 98.15,79.6 114.37,79.6 v3(115.03,78.93) RC130.2 116.82,76.59 117.39,76.02 117.74,76.02 v2(118.52,75.24)
  IN4 w0.081: v2(64.56,69.22) 64.56,69.16 64.9,68.82 65.38,68.82 65.64,69.08 65.64,71.93 67.04,73.33 67.04,75.63 67.41,76.01 71.83,76.01 72.87,77.05 79.06,77.05 80.3,75.81 85.17,75.81 85.85,75.13 87,75.13 88.23,76.36 v2(91.91,76.36)
  BOTTOM w0.076: v2(118.52,75.24) 118.95,74.81 118.95,72.64 119.12,72.47 119.12,72.21 119.07,72.09 119.07,71.94 119.12,71.75 119.12,71.57 119.04,71.32 119,71.26 118.97,71.2 118.97,71.12 UCPU1.C59
  BOTTOM w0.127: RC131.2 91.16,77.38 91.91,76.62 v2(91.91,76.36) ; UCPU1.C59 118.53,71.34 UCPU1.C60
TOUCH_SCREEN_PD#: length 100.1
  BOTTOM w0.127: JTS.5 71.22,77.76 70.51,77.05 70.51,74.79 72.31,72.98 v3(72.97,72.98) 76.54,72.98 76.76,72.77 80.53,72.77 80.89,72.4 85.21,72.4 86.57,71.04 88.46,71.04 89.15,71.73 89.15,74.65 90.2,75.7 91.13,75.7 91.52,75.32 92.26,75.32 93.14,76.19 93.14,76.62 97.54,81.02 146.35,81.02 149.99,77.37 150.74,77.37 151.02,77.09 151.02,76.17 RC277.2 151.49,74.89 150.32,73.72 150,73.72 UCPU1.A7
TOUCHPAD_INTR#: length 11.2
  BOTTOM w0.076: UCPU1.BA5 149.52,50.31 149.86,49.97 149.86,49.53 150.22,49.17 150.53,49.17 150.71,48.99
  BOTTOM w0.127: 150.71,48.99 151.05,48.65 155.34,48.65 RC272.2 156.32,47.67 157.03,47.67 157.58,48.22 DZ3.2 157.79,48.3 157.79,49.09 v3(158.11,49.41)
TP_PW_EN: length 148.2
  TOP w0.127: U716.3 170.9,15.97 170.74,15.81 170.74,15.27 169.65,14.18 R1175.2 168.99,13.65 167.79,13.65 v2(167.26,14.18) 167.26,14.6 v3(167.41,14.76)
  IN3 w0.089: v2(34.24,13.7) 35.36,14.82 39.39,14.82 40.03,14.19 48.78,14.19 50.4,15.81 55.96,15.81 56.26,15.5 59.64,15.5 61.21,13.93 62.97,13.93 v2(63.35,14.31)
  BOTTOM w0.127: v2(63.35,14.31) 63.73,14.7 70.22,14.7 70.54,15.02 95.27,15.02 96.54,16.29 105.79,16.29 107.15,17.64 111.95,17.64 114.37,15.22 125.22,15.22 127.46,17.46 130.76,17.46 135.06,13.16 166.58,13.16 167.26,13.84 v2(167.26,14.18) ; v2(34.24,13.7) 34.59,14.05 UE4.24
TPM_DET: length 6.3
  TOP w0.127: v2(145.38,54.38) 145.77,54.78 145.77,55.79 146.43,56.45 146.43,56.87 146.63,57.08 147.4,57.08 RH153.1 RH148.2
  BOTTOM w0.127: v2(145.38,54.38) 145.33,54.38 144.97,54.75 UCPU1.AP13
TPM_LPM#: length 18.2
  TOP w0.127: R1006.1 183.14,50.2 183.74,50.8 186.5,50.8 186.79,50.5 186.79,50.12 187.1,49.82 187.94,49.82 188.72,49.03 v3(188.88,49.03) 189.05,48.85 195.22,48.85 RE91.1 196.14,47.94 196.65,47.94 198.16,46.43 Q72.1
TPM_PIRQ#: length 75.2
  TOP w0.127: v2(179.74,41.63) 180.23,41.63 180.78,41.08 180.78,40.69 182.67,38.79 v3(185.37,38.79) 185.82,38.79 186.62,39.59 187.92,39.59 188.79,40.46 188.79,41.55 190.31,43.07 RH126.2 190.18,43.9 188.93,43.9 188.75,44.08 U15.18
  IN2 w0.089: v2(153.65,66.51) 154.19,66.51 155.6,65.1 155.6,64.51 155.19,64.1 155,64.1 154.48,63.58 154.48,62.88 154.89,62.47 156.72,62.47 157.98,61.21 163.7,61.21 165.23,59.69 170.68,59.69 171.52,58.84 172.18,58.84 172.37,59.04 173.29,59.04 175.31,57.01 175.31,53.2 175.12,53.01 175.12,51.79 175.62,51.3 177.43,51.3 179.33,53.2 181.13,53.2 182.86,51.47 182.86,49.49 181.59,48.22 181.59,43.48 v2(179.74,41.63)
  BOTTOM w0.076: UCPU1.M3 151.1,66.43 153.57,66.43 v2(153.65,66.51)
TRST#_XDP: length 84.3
  TOP w0.127: v2(66.9,65.39) 66.9,65.52 66.43,65.99 65.87,65.99 65.6,66.26 JXDP1.54 ; v2(88.32,71.66) 88.88,71.1 92.68,71.1 93.03,71.44 93.03,71.78 93.7,72.46 93.7,73.63 95.41,75.35 97.33,75.35 97.9,75.92 99.01,75.92 102.05,78.96 106.02,78.96 107.49,77.49 107.49,77.07 108.19,76.37 108.19,75.77 108.59,75.37 109.12,75.37 109.45,75.04 109.45,74.28 109.79,73.94 110.72,73.94 110.97,73.69 113.82,73.69 114.72,74.6 v3(115.94,74.6) 115.94,75.72 116.36,76.14 116.82,76.14 v2(117.37,75.59) ; v2(79.86,66.76) 79.86,70.57 80.54,71.26 80.54,72.75 v2(80.9,73.11)
  IN4 w0.081: v2(66.9,65.39) 67.59,66.07 79.17,66.07 v2(79.86,66.76)
  BOTTOM w0.076: UCPU1.C61 117.33,71.41 117.33,72.08 117.31,72.14 117.3,72.17 117.3,72.54 117.39,72.63 117.39,74.25 116.87,74.78 116.44,74.78 116.21,75.02 116.21,75.84 116.45,76.09 116.87,76.09 v2(117.37,75.59) 117.6,75.36 117.6,75.23 118.59,74.24 118.59,71.93 UCPU1.B59
  BOTTOM w0.127: RC136.2 79.05,73.02 80.81,73.02 v2(80.9,73.11) 81.35,72.66 85.31,72.66 86.68,71.29 87.95,71.29 v2(88.32,71.66)
UART0_TX: length 31.5
  BOTTOM w0.127: UCPU1.AB2 151.77,61.15 152.27,61.15 152.42,60.99 154.23,60.99 154.65,60.57 156.9,60.57 157.43,61.1 v3(157.89,61.1) 158.5,61.1 158.67,61.27 160.49,61.27 162.2,62.99 162.2,64.8 164.54,67.14 164.54,69.73 164.96,70.15 165.98,70.15 167.2,68.93 167.2,68.18 167.51,67.87 168.26,67.87 169.3,68.91 173.41,68.91 173.65,68.67 JDEG1.9
UART1_RXD: length 175.7
  IN1 w0.081: v2(66.09,22.61) 66.12,22.64 67.34,22.64 70.26,25.56 72.72,25.56 77.01,29.85 81.98,29.85 83.53,31.4 90.65,31.4 91.49,30.56 91.9,30.56 96.04,26.42 96.04,23.39 97.85,21.58 102.93,21.58 103.19,21.84 110.54,21.84 112.59,19.8 117.49,19.8 118.29,18.99 125.56,18.99 126.13,19.55 132.6,19.55 133.69,18.46 145.71,18.46 146.41,19.16 156.69,19.16 158.05,20.52 160.72,20.52 163.26,23.06 163.26,25.31 164.95,27 164.95,34.1 165.1,34.25 165.1,37.17 165.84,37.91 165.84,39.63 165.81,39.66 165.85,39.69 v2(165.86,39.69)
  IN4 w0.081: v2(154.89,59.24) 155.14,59.24 156.63,57.75 156.63,57.03 158.52,55.14 158.52,52.72 165.76,45.47 165.76,39.79 v2(165.86,39.69)
  BOTTOM w0.127: RH563.2 49.11,20.57 JUART.3 53.84,20.57 v3(54.4,20.01) 55.3,19.11 57.74,19.11 59.01,20.38 63.86,20.38 v2(66.09,22.61) ; v2(154.89,59.24) 154.89,59.68 154.15,60.41 152.87,60.41 152.64,60.18 UCPU1.AC1
UART1_TXD: length 175.2
  IN1 w0.089: v2(57.81,24.93) 59.64,26.76 63.04,26.76 63.75,27.47 72.67,27.47 76.42,31.21 81.4,31.21 83.43,33.24 87.54,33.24 88.11,33.82 88.62,33.82 89.26,33.17 90.89,33.17 92.04,32.03 92.17,32.03 92.76,31.44 92.76,31.18 94.16,29.78 95.09,29.78 96.87,28 96.87,23.74 98.18,22.44 102.58,22.44 102.81,22.67 110.89,22.67 112.93,20.63 117.83,20.63 118.64,19.82 125.2,19.82 125.77,20.4 155.66,20.4 163.85,28.58 163.85,33.63 163.75,33.73 163.75,33.73 163.66,33.83 163.66,37.02 163.78,37.15 163.78,37.15 163.85,37.21 163.85,39.21 163.58,39.48 163.58,39.48 v2(162.94,40.12)
  IN4 w0.089: v2(154.89,58.12) 155.23,58.12 158.3,55.05 158.3,52.63 163.56,47.38 163.56,40.73 v2(162.94,40.12)
  BOTTOM w0.076: UCPU1.AC2 151.32,60 151.56,60 151.68,59.93 151.95,59.93 152.07,59.99 153.17,59.99
  BOTTOM w0.127: v2(154.89,58.12) 154.51,58.51 154.51,59.52 154.04,59.99 153.17,59.99 ; v2(57.81,24.93) 57.4,24.52 56.06,24.52 55.68,24.9 54.11,24.9 53.85,25.15 51.38,25.15 50.06,23.83 50.06,22.35 RH562.2 v3(49.94,21.24) 49.99,21.24 50.11,21.37 JUART.2
UPD_EN1_4#: length 2.3
  TOP w0.127: UE5.B53 179.11,59.07 178.89,59.29 v2(178.87,59.29)
  BOTTOM w0.127: RE107.2 v3(179.05,58.76) 179.05,59.11 v2(178.87,59.29)
UPD_MRESET: length 291.1
  TOP w0.127: R1465.2 22.04,54.76 v2(22.04,54.76) ; v2(27.52,46.15) 27.52,45.67 v1(27.72,45.46) RE90.1 29.16,45.46 29.62,45.92 RT121.1 29.88,46.18 30.28,46.58 30.28,47.71 v2(30.61,48.04) ; v2(193.08,59.73) 193.08,60.98 192.34,61.73 190.4,61.73 189.98,61.3 189.61,61.3 189.03,60.73 188.63,60.73 188.34,61.02 UE5.A4
  IN2 w0.089: v2(30.61,48.04) 31.98,46.67 31.98,44.27 33.37,42.88 33.71,42.88 34.56,42.03 34.56,41.46 34.08,40.98 34.08,39.23 34.55,38.76 34.55,32.25 33.76,31.47 33.76,25.57 34.14,25.19 34.14,23.14 32.99,21.99 32.99,21.06 37.73,16.33 38.33,16.33 39.52,15.13 39.52,15.01 39.91,14.62 42.74,14.62 43.27,15.16 50.72,15.16 51.62,16.06 54.17,16.06 54.77,15.46 64.7,15.46 65.68,14.49 70.88,14.49 v2(70.89,14.47)
  IN3 w0.089: v2(22.04,54.76) 22.04,53.65 25.54,50.15 25.54,47.99 27.38,46.15 v2(27.52,46.15)
  IN4 w0.081: v2(70.89,14.47) 72.04,15.62 112.25,15.62 112.28,15.59 131.79,15.59 134.01,13.37 200.38,13.37 202.53,15.53 203,15.53 204.37,16.9 210.08,16.9 210.58,17.41 210.58,17.98 209.99,18.58 208,18.58 206.46,20.12 206.46,20.39 202.47,24.38 202.47,32.84 198.6,36.71 198.6,41.28 196.97,42.91 196.97,46.96 198.22,48.21 198.22,49.26 192.65,54.83 192.65,59.24 193.08,59.68 v2(193.08,59.73)
UPD_SMBCLK: length 190.9
  TOP w0.076: v2(25.04,62.29) 25.33,62.29 U722.B5
  TOP w0.127: UE5.B49 178.01,60.27 178.87,60.27 v2(179.03,60.44)
  IN3 w0.089: v2(179.05,74.81) 178.66,74.43 177.65,74.43 172.61,79.47 172.61,80.18 172.34,80.45 157.63,80.45 157.09,79.91 155.36,79.91 154.96,79.51 152.43,79.51 151.75,80.18 90.79,80.18 89.84,79.23 87.37,79.23 86.97,78.83 84.57,78.83 83.01,77.26 80.91,77.26 77.7,80.48 58.33,80.48 50.74,72.89 45.88,72.89 41.05,68.06 29.87,68.06 28.3,66.48 28.3,62.68 27.73,62.11 27,62.11 26.77,62.34 25.1,62.34 v2(25.04,62.29)
  IN4 w0.089: v2(179.05,74.81) 178.12,73.88 178.12,73.07 176.71,71.67 176.71,69.21 177.7,68.23 177.7,63.53 178.59,62.64 179.74,62.64 179.98,62.4 179.98,61.95 179.09,61.07 179.09,60.5 v2(179.03,60.44)
  BOTTOM w0.127: v2(179.03,60.44) 178.99,60.39 177.87,60.39 RE88.1
UPD_SMBDAT: length 190.1
  TOP w0.127: U722.A5 26.14,62.34 26.77,62.34 v2(27.06,62.63) ; UE5.B48 178.53,60.77 v2(178.66,60.9)
  IN3 w0.089: v2(27.06,62.63) 27.06,62.78 26.64,63.2 26.31,63.2 26.09,63.43 26.09,63.92 26.95,64.78 27.41,64.78 27.74,65.11 27.74,66.23 29.87,68.36 37.57,68.36 38.14,68.92 41.6,68.92 45.79,73.1 50.65,73.1 58.24,80.69 77.79,80.69 81,77.48 82.92,77.48 85.18,79.74 86.72,79.74 87.38,80.4 152.47,80.4 153.18,79.69 154.72,79.69 155.15,80.12 157,80.12 157.56,80.69 174.11,80.69 174.57,80.23 174.57,77.91 177.65,74.84 v2(178.44,74.84)
  IN4 w0.089: v2(178.66,60.9) 178.4,61.16 178.4,62.5 177.48,63.42 177.48,68.14 176.44,69.18 176.44,71.7 177.9,73.16 177.9,74.3 v2(178.44,74.84)
  BOTTOM w0.127: v3(29.23,63.02) 28.46,62.24 27.46,62.24 v2(27.06,62.63) ; v2(178.66,60.9) 178.24,61.32 RE87.1
UPD_SMBINT#: length 185
  TOP w0.076: U722.B6 25.33,61.8 25.24,61.71 v2(25.04,61.71)
  TOP w0.127: UE5.A42 174.58,62.52 RE3.2 174.55,61.63 v2(175.08,61.63)
  IN3 w0.089: v2(171.83,73.12) 171.65,73.3 171.65,76.61 169.62,78.64 155.68,78.64 155.56,78.75 152.06,78.75 151.3,79.51 92.2,79.51 89.95,77.26 84.85,77.26 83.78,76.18 80.46,76.18 79.4,77.25 77.06,77.25 76.06,78.25 73.49,78.25 73.15,78.59 72.53,78.59 72.35,78.41 71.21,78.41 69.8,79.83 62.14,79.83 61.44,79.14 57.69,79.14 51.87,73.31 51.87,72.07 50.86,71.07 50.86,69.85 48.56,67.55 30.42,67.55 29.94,67.06 29.94,66.54 28.52,65.12 28.52,62.6 27.71,61.79 27.71,61.53 26.84,60.66 26.36,60.66 25.31,61.71 v2(25.04,61.71)
  IN4 w0.081: v2(171.83,73.12) 171.83,73.08 174.68,70.24 174.68,68.81 174.02,68.15 174.02,66.68 173.56,66.23 173.56,64.53 173.65,64.44 173.65,62.84 174.85,61.64 175.08,61.64 v2(175.08,61.63)
USB1_DET#: length 48.7
  TOP w0.127: v3(188.2,54.91) 187.7,54.41 187.22,54.41 186.79,54.83 v2(186.79,54.9)
  IN4 w0.081: v2(186.79,54.9) 187.27,54.42 187.27,53.79 189.17,51.89 189.17,50.07 193.29,45.96 193.29,34.12 193.68,33.72 194.87,33.72 195.58,33 195.58,25.96 198.1,23.45 200.1,23.45 v2(201.65,21.9)
  BOTTOM w0.127: JIO1.36 199.71,18.83 199.86,18.97 199.86,19.78 201.65,21.58 v2(201.65,21.9) ; RE34.2 CE22.1 186.77,54.87 v2(186.79,54.9)
USB2_EN: length 5.9
  TOP w0.127: U699.4 24.85,52.88 23.76,52.88 R1216.1 23.72,52.74 23.72,52.08 23.47,51.82 23.47,51.32 23.6,51.18 US2.4 25.17,51.18 25.71,51.72 v3(26.24,51.72)
USB2_ID: length 8
  BOTTOM w0.127: v3(157.81,56.53) 156.21,56.53 RC19.1 155.42,57.31 154.77,57.31 153.86,58.23 152.61,58.23 152.26,57.88 151.12,57.88 150.82,58.18 UCPU1.AG3
USB2_PWR_EN: length 242.4
  TOP w0.127: v3(39.98,39.05) 41.32,40.39 v2(42.11,40.39) ; v2(23.4,54.5) 23.67,54.23 RC293.2 25.4,53.81 26.15,54.56 U699.1
  IN1 w0.081: v2(42.34,44.2) 42.31,44.2 41.35,43.24 41.35,41.16 v2(42.11,40.39)
  IN4 w0.081: v2(42.11,40.39) 42.24,40.27 42.24,39.85 41.45,39.07 41.26,39.07 39.23,37.04 39.23,35.28 39.82,34.68 39.95,34.68 41.09,33.54 41.09,31.78 42.04,30.83 42.04,29.75 42.16,29.63 42.16,29.07 42,28.9 42,28.42 42.2,28.22 42.2,26.74 45.35,23.59 50.79,23.59 50.92,23.71 52.92,23.71 53.91,22.72 58.94,22.72 60.09,21.57 65.93,21.57 68.91,24.55 68.91,25.74 71.48,28.31 73.94,28.31 76.78,31.15 77.61,31.15 78.69,32.23 82.48,32.23 83.82,33.57 83.82,34.11 85.3,35.59 90.09,35.59 90.9,34.78 95.63,34.78 96.82,33.58 96.82,30.17 97.64,29.35 97.64,25.62 97.73,25.53 97.73,24.25 98.83,23.15 99.77,23.15 100.95,21.97 110.64,21.97 111.72,20.89 116.95,20.89 117.7,21.64 124.06,21.64 125.46,20.24 144.5,20.24 144.98,20.72 147.66,20.72 148.06,20.32 160.51,20.32 163.13,22.93 163.13,25.69 161.67,27.15 161.67,29.6 163.52,31.45 163.52,33.33 162.92,33.93 162.22,33.93 160.22,35.93 160.22,37.35 156.47,41.09 156.47,41.91 155.5,42.88 155.5,45.33 154.37,46.47 v2(154.37,46.87) ; v2(23.4,54.5) 23.62,54.29 23.62,52.15 23.19,51.72 23.19,43.2 24.83,41.56 25.64,41.56 25.93,41.27 27.08,41.27 28.53,42.72 29.38,42.72 29.86,42.24 31.08,42.24 31.97,43.13 34.94,43.13 35.51,43.7 41.83,43.7 v2(42.34,44.2)
  BOTTOM w0.076: v2(154.37,46.87) 154.12,46.87 153.18,47.81 150.65,47.81 150.09,48.37 149.19,48.37 148.15,49.41 148.15,49.79 148.19,49.9 148.2,50.05 148.16,50.2 148.16,50.4 148.19,50.52 148.21,50.55 148.26,50.68 UCPU1.AY7
USB3RN1: length 107.5
  IN2 w0.076: 149.36,67.67 149.33,67.7 149.14,67.7 148.46,68.38 148.46,68.73 148.23,68.96 147.9,68.96 147.68,68.73 147.68,68.35 147.43,68.1 147.35,68.1 v2(147.17,67.92)
  IN2 w0.102: 149.36,67.67 151.36,67.67 152.22,68.54 155.24,68.54 155.75,69.05 158.09,69.05 158.71,68.43 158.71,67.3 159.56,66.46 166.06,66.46 166.67,65.85 172.43,65.85 172.94,66.35 174.97,66.35 176,67.39 176.58,67.39 177.55,66.41 177.55,65.84 178.53,64.86 181.68,64.86 182.91,63.64 187.44,63.64 189.14,61.94 189.14,61.39 189.21,61.32 189.21,46.98 190.32,45.87 190.32,32.19 201.83,20.68 201.94,20.68 205.65,16.98 209.54,16.98 210.15,17.58 v2(210.15,17.63)
  BOTTOM w0.127: UCPU1.H8 147.45,67.64 v2(147.17,67.92) ; v2(210.15,17.63) 210,17.63 209.76,17.87 209.76,18.08 209.91,18.23 JIO1.2
USB3RN2: length 164.9
  IN1 w0.076: 147.4,69.63 147.41,69.62 147.42,69.62 147.43,69.62 147.64,69.41 147.64,68.99 147.53,68.88 147.53,67.77 147.76,67.53 147.91,67.53 v2(148.12,67.33)
  IN1 w0.091: v2(24.31,38.91) 24.59,39.19 24.68,39.19 24.88,39.39 24.88,41.24 30.29,46.65 30.29,46.86 31.22,47.8 31.22,53.87 30.72,54.37 30.72,62.32 30.16,62.88 30.16,63.99 31.81,65.64 33.61,65.64 35.16,67.19 40.79,67.19 47.05,73.45 60.96,73.45 61.78,72.62 63.75,72.62 64.21,72.17 69.14,72.17 70.33,73.36 80.21,73.36 80.39,73.54 85.9,73.54 86.69,74.33 91.43,74.33 93.18,76.08 93.18,77.16 94.06,78.04 108.08,78.04 108.88,77.24 115.19,77.24 115.46,77.5 119.58,77.5 120.15,78.07 139.69,78.07 140.91,76.85 144.99,76.85 147.04,74.8 147.04,69.99 147.4,69.63
  BOTTOM w0.127: v2(148.12,67.33) 148.46,66.99 UCPU1.J6 ; v2(24.31,38.91) 24.07,38.91 23.45,38.29 ML13.1
USB3RN2_RC_CON: length 12.1
  BOTTOM w0.127: ML13.2 21.01,38.29 20.74,38.56 20.5,38.56 19.89,39.18 19.58,39.18 19.5,39.09 DI1.10 DI1.1 17.28,39.09 17.04,39.34 16.95,39.42 16.87,39.52 16.87,39.53 16.78,39.63 16.78,39.75 15.5,41.04 15.5,42.03 15.09,42.44 13.88,42.44 13.31,41.87 12.87,41.87 12.72,41.73 12.72,41.54 12.72,41.54 JUSB2.5
USB3RP1: length 107.6
  IN2 w0.076: v2(147.12,68.6) 147.12,68.6 147.12,68.4 147.25,68.27 147.37,68.27 147.51,68.41 147.51,68.8 147.83,69.13 148.3,69.13 148.63,68.79 148.63,68.45 149.21,67.86 149.33,67.86 149.36,67.89
  IN2 w0.102: 149.36,67.89 151.26,67.89 152.13,68.76 155.14,68.76 155.66,69.28 158.19,69.28 158.94,68.53 158.94,67.4 159.65,66.68 166.15,66.68 166.76,66.07 172.34,66.07 172.84,66.58 174.87,66.58 175.91,67.61 176.67,67.61 177.78,66.51 177.78,65.93 178.62,65.08 181.77,65.08 183,63.86 187.54,63.86 189.36,62.03 189.36,61.49 189.43,61.42 189.43,47.08 190.55,45.96 190.55,32.28 201.92,20.91 202.04,20.91 205.75,17.2 209.45,17.2 209.68,17.43 209.68,17.65 209.58,17.75 209.41,17.75 v2(209.3,17.64)
  BOTTOM w0.127: JIO1.4 209.31,18.41 209.31,18.31 209.51,18.11 209.51,17.85 v2(209.3,17.64) ; v2(147.12,68.6) 147.42,68.29 UCPU1.G8
USB3RP2: length 164.8
  IN1 w0.076: v2(148.11,67.93) 148.11,67.89 147.93,67.7 147.83,67.7 147.69,67.83 147.69,68.81 147.8,68.92 147.8,69.48 147.55,69.74 147.55,69.76 147.54,69.76
  IN1 w0.091: 147.54,69.76 147.23,70.07 147.23,74.88 145.07,77.05 140.99,77.05 139.77,78.27 120.07,78.27 119.5,77.7 115.38,77.7 115.11,77.43 108.96,77.43 108.16,78.23 93.98,78.23 92.99,77.24 92.99,76.16 91.35,74.52 86.61,74.52 85.82,73.73 80.31,73.73 80.13,73.56 70.25,73.56 69.06,72.36 64.29,72.36 63.83,72.82 61.86,72.82 61.04,73.64 46.97,73.64 40.71,67.38 35.08,67.38 33.53,65.83 31.73,65.83 29.97,64.07 29.97,62.8 30.53,62.24 30.53,54.29 31.03,53.79 31.03,47.88 30.09,46.94 30.09,46.73 24.69,41.32 24.69,39.47 24.6,39.38 24.42,39.38 v2(24.31,39.49)
  BOTTOM w0.127: ML13.4 23.72,39.09 24.12,39.49 v2(24.31,39.49) ; UCPU1.H6 148.38,67.64 148.11,67.9 v2(148.11,67.93)
USB3RP2_RC_CON: length 12.3
  BOTTOM w0.127: JUSB2.6 12.72,43.11 12.72,42.26 12.87,42.12 13.2,42.12 13.78,42.69 14.98,42.69 15.19,42.69 15.75,42.13 15.75,41.14 17.04,39.86 17.04,39.72 17.06,39.69 17.07,39.68 17.1,39.64 17.14,39.59 DI1.2 DI1.9 19.45,39.59 19.61,39.43 20,39.43 v4(20.32,39.1) 20.61,38.82 20.74,38.82 21.01,39.09 ML13.3
USB3TN1: length 111.1
  IN2 w0.102: v2(143.87,74.25) 144.02,74.1 144.37,74.1 145.25,73.21 148.54,73.21 148.8,73.47 155.18,73.47 156.4,72.25 158.01,72.25 158.5,71.76 159.69,71.76 160.96,70.49 166.29,70.49 166.52,70.72 176.87,70.72 177.9,69.69 177.9,69.4 178.36,68.94 185.7,68.94 188.32,66.33 188.32,65.11 188.8,64.62 190.11,64.62 190.89,63.84 190.89,63.29 191.15,63.02 191.15,60.35 191.33,60.17 191.33,57.71 191.92,57.13 191.92,47.33 193.21,46.04 193.21,33.19 207.95,18.45 207.95,17.82 v2(208.1,17.66)
  BOTTOM w0.076: UCPU1.C13 145.15,71.01 145.21,71.08 145.21,71.21 145.09,71.32 144.89,71.32 144.76,71.45 144.72,71.57 144.72,71.75 144.78,71.94 144.78,72.09 144.72,72.21 144.72,73.7 144.37,74.05 144.07,74.05 v2(143.87,74.25)
  BOTTOM w0.127: JIO1.8 208.11,18.18 207.92,17.99 207.92,17.84 v2(208.1,17.66)
USB3TN2: length 163.1
  IN1 w0.091: v2(145.8,73.82) 145.58,74.04 145.35,74.04 143.15,76.23 140.23,76.23 139.01,77.45 120.88,77.45 120.32,76.89 115.7,76.89 115.39,76.59 109.32,76.59 107.32,74.59 107.32,73.69 105.29,71.67 102.66,71.67 100.1,74.23 100.1,76.49 99.17,77.43 94.89,77.43 94.62,77.15 94.62,76.01 92.32,73.72 87.02,73.72 85.81,72.51 79.97,72.51 79.76,72.73 70.56,72.73 69.41,71.58 63.83,71.58 63.41,72 61.54,72 60.69,72.86 47.3,72.86 40.96,66.52 40.96,66.01 40.25,65.29 37.18,65.29 36.51,65.96 34.8,65.96 33.81,64.97 32.8,64.97 32.46,64.63 31.64,64.63 30.84,63.83 30.84,63.05 31.4,62.48 31.4,57.98 32.23,57.14 32.23,55.96 31.9,55.63 31.9,47.59 30.88,46.57 30.88,46.4 27.02,42.54 27.02,41.07 26.66,40.71 25.56,40.71 v2(25.3,40.45)
  BOTTOM w0.076: UCPU1.B13 144.99,71.79 145.16,71.97 145.34,71.97 145.59,72.22 145.59,73.21 145.4,73.41 145.4,73.85 145.47,73.93 145.69,73.93 v2(145.8,73.82)
  BOTTOM w0.127: v2(25.3,40.45) 25.09,40.65 24.79,40.65 C621.1
USB3TN2_C: length 1.6
  BOTTOM w0.127: ML12.1 22.5,40.58 22.71,40.79 23.03,40.79 23.47,40.34 C621.2
USB3TN2_RC_CON: length 14.5
  BOTTOM w0.127: JUSB2.8 12.72,47.82 12.87,47.96 13.12,47.96 13.56,47.52 14.67,47.52 16.27,45.92 16.27,41.25 16.81,40.71 17.04,40.71 17.16,40.59 17.74,40.59 DI1.4 DI1.7 19.18,40.59 19.18,40.59 19.47,40.59 19.59,40.71 19.91,40.71 20.05,40.58 ML12.2
USB3TP1: length 111
  IN2 w0.102: v2(143.87,73.62) 143.87,73.72 144.01,73.87 144.27,73.87 145.16,72.99 148.64,72.99 148.89,73.24 155.09,73.24 156.31,72.02 157.92,72.02 158.4,71.54 159.6,71.54 160.87,70.27 166.38,70.27 166.61,70.5 176.78,70.5 177.68,69.6 177.68,69.3 178.26,68.72 185.61,68.72 188.09,66.24 188.09,65.02 188.71,64.4 190.02,64.4 190.67,63.75 190.67,63.19 190.93,62.93 190.93,60.26 191.11,60.08 191.11,57.62 191.69,57.04 191.69,47.24 192.99,45.95 192.99,33.09 207.72,18.36 207.72,17.81 207.57,17.66 v2(207.49,17.66)
  BOTTOM w0.076: UCPU1.D13 144.75,70.6 144.75,70.78 144.7,70.96 144.7,71.07 144.68,71.14 144.65,71.22 144.62,71.35 144.62,71.35 144.56,71.55 144.56,71.8 144.59,71.89 144.59,72.08 144.56,72.18 144.56,73.63 144.3,73.89 144.01,73.89 143.87,73.74 v2(143.87,73.62)
  BOTTOM w0.127: JIO1.10 207.51,18.25 207.67,18.09 207.67,17.81 207.52,17.66 v2(207.49,17.66)
USB3TP2: length 163.1
  IN1 w0.091: v2(145.8,74.46) 145.58,74.24 145.43,74.24 143.23,76.43 140.31,76.43 139.09,77.65 120.8,77.65 120.24,77.09 115.62,77.09 115.31,76.78 109.24,76.78 107.12,74.67 107.12,73.77 105.21,71.87 102.74,71.87 100.29,74.31 100.29,76.57 99.25,77.62 94.81,77.62 94.42,77.23 94.42,76.09 92.24,73.91 86.94,73.91 85.73,72.7 80.05,72.7 79.84,72.92 70.48,72.92 69.33,71.77 63.91,71.77 63.49,72.2 61.62,72.2 60.77,73.05 47.22,73.05 40.77,66.6 40.77,66.09 40.17,65.48 37.26,65.48 36.59,66.15 34.72,66.15 33.73,65.16 32.72,65.16 32.38,64.83 31.56,64.83 30.64,63.91 30.64,62.97 31.2,62.4 31.2,57.9 32.04,57.06 32.04,56.04 31.71,55.71 31.71,47.67 30.68,46.65 30.68,46.48 26.82,42.62 26.82,41.15 26.58,40.9 25.48,40.9 v2(25.3,41.08)
  BOTTOM w0.076: v2(145.8,74.46) 145.8,74.33 145.56,74.1 145.41,74.1 145.23,73.92 145.23,73.34 145.43,73.14 145.43,72.29 145.27,72.13 145.17,72.13 UCPU1.A13
  BOTTOM w0.127: v2(25.3,41.08) 25.12,40.91 24.81,40.91 C623.1
USB3TP2_C: length 1.6
  BOTTOM w0.127: C623.2 23.22,41.23 23.03,41.04 22.71,41.04 22.37,41.38 ML12.4
USB3TP2_RC_CON: length 14.6
  BOTTOM w0.127: 17.74,41.09 17.16,41.09 17.04,40.97 16.91,40.97 16.52,41.36 16.52,46.02 14.77,47.77 13.67,47.77 13.23,48.22 12.87,48.22 12.72,48.36 JUSB2.9 ; 17.74,41.09 DI1.5 ; 17.74,41.09 18.89,41.09 ; 18.89,41.09 19.47,41.09 19.59,40.97 19.9,40.97 20.31,41.38 ML12.3 ; 18.89,41.09 DI1.6
USB20_N1: length 96.5
  IN2 w0.102: v2(159.46,62.47) 159.46,62.48 159.64,62.67 159.64,62.91 160,63.28 164.3,63.28 166.88,60.7 172.5,60.7 176.52,56.68 177.93,56.68 180.02,58.78 184.07,58.78 185.01,57.84 186.43,57.84 188.11,56.15 188.11,54.49 187.96,54.33 187.96,49.11 186.61,47.77 186.61,37.59 189.86,34.34 189.86,29.59 192.06,27.39 193.6,27.39 194.54,26.45 194.54,24.4 196.63,22.3 196.63,21.57 199.01,19.2 200.34,19.2 200.48,19.34 200.48,19.47 v2(200.33,19.62)
  IN4 w0.091: v2(159.46,62.47) 159.44,62.48 159.31,62.48 159.23,62.41 159.23,62.15 159.34,62.04 159.67,62.04 159.73,61.99 159.73,61.66 159.33,61.26 156.7,61.26 156.19,61.78 153.3,61.78 151.78,60.26 147.6,60.26 147.5,60.36 147.5,60.62 147.6,60.73 147.71,60.73 v2(147.74,60.7)
  BOTTOM w0.127: UCPU1.AB9 147.44,61 v2(147.74,60.7) ; JIO1.34 200.31,18.63 200.47,18.79 200.47,19.48 v2(200.33,19.62)
USB20_N2: length 180.5
  IN1 w0.091: v2(149.62,59.58) 149.41,59.79 149.41,59.97 149.74,60.3 150.08,60.3 152.55,62.77 152.55,64.48 154.79,66.72 154.79,68.43 154.52,68.69 154.52,69.63 154.97,70.07 154.97,70.74 154.65,71.06 154.65,74.26 153.83,75.08 153.12,75.08 151.51,76.69 151.51,78.42 150.47,79.46 93.17,79.46 90.61,76.89 85.31,76.89 83.85,75.44 80.77,75.44 79.5,74.17 70,74.17 68.8,72.96 64.62,72.96 64.13,73.45 62.06,73.45 61.27,74.24 58.18,74.24 57.21,75.21 52.64,75.21 51.82,74.38 46.87,74.38 40.52,68.03 34.86,68.03 33.35,66.52 31.58,66.52 31.2,66.14 30.51,66.14 29.17,64.8 29.17,53.82 30.43,52.56 30.43,49.11 29.94,48.61 29.94,47.62 29.51,47.19 29.51,46.97 26.62,44.09 25.12,44.09 v2(24.94,44.27)
  BOTTOM w0.127: ML11.1 24.04,44.12 24.79,44.12 v2(24.94,44.27) ; UCPU1.AD6 149.39,59.81 v2(149.62,59.58)
USB20_N2_CONN: length 11.1
  IN4 w0.091: JUSB2.2 14.23,45.3 14.32,45.21 16.81,45.21 v2(17.06,45.46)
  BOTTOM w0.127: ML11.2 22.55,44.11 21.46,44.11 DI2.2 20.57,44.31 20.41,44.14 20.13,44.14 19.06,45.22 17.31,45.22 v2(17.06,45.46)
USB20_N3: length 155.9
  IN1 w0.091: v2(153.59,57.13) 153.45,57.27 153.45,57.53 153.12,57.86 152.79,57.86 151.38,59.27 150.29,59.27 150.19,59.17 144.34,59.17 144.22,59.29 140.23,59.29 139.11,60.41 139.11,63.28 138.5,63.89 138.5,64.47 138.97,64.95 138.97,67.15 138.01,68.12 123.6,68.12 123.22,67.73 123.22,66.92 122.8,66.51 121.56,66.51 121.26,66.8 121.26,67.36 120.86,67.77 118.96,67.77 116.89,69.83 114.66,69.83 114.28,69.45 114.28,68.92 114.02,68.67 112.12,68.67 110.97,67.52 109.75,67.52 109.59,67.69 109.01,67.69 108.67,67.34 107.86,67.34 107.14,66.63 100.58,66.63 99.29,67.92 83.56,67.92 82.22,66.57 81.06,66.57 80.27,67.36 79.6,67.36 78.37,66.13 65.46,66.13 64.34,65 64.34,62.44 63.78,61.87 62.76,61.87 59.6,58.71 59.6,56.73 56.42,53.55 52.84,53.55 49.84,50.55 49.84,48.78 45.11,44.05 45.11,39.37 41.5,35.77 41.5,35.39 41.05,34.93 39.55,34.93 39.22,35.26 39.22,35.8 38.91,36.1 38.63,36.1 v2(38.46,36.28)
  BOTTOM w0.076: v2(153.59,57.13) 153.41,57.31 153.41,57.52 153.2,57.74 152.51,57.74 152.07,57.3 151.98,57.3 151.86,57.25 151.75,57.25 151.53,57.32 151.38,57.32 151.22,57.26 151.04,57.26 150.79,57.38 150.65,57.38 UCPU1.AH3
  BOTTOM w0.127: ML10.1 37.82,36.14 38.32,36.14 v2(38.46,36.28)
USB20_N3_R: length 6.7
  BOTTOM w0.127: ML10.2 36.42,36.42 36.22,36.62 35.97,36.62 35.87,36.52 35.87,36.32 35.75,36.2 35.22,36.2 35.04,36.39 35.04,36.89 v4(34.55,37.38) 34.16,37.77 32.28,37.77 32.14,37.92 32.14,38.04 32.25,38.16 JNGFF1.5
USB20_N4: length 101.9
  IN1 w0.091: v2(81.94,74.79) 81.74,74.79 81.62,74.67 81.62,74.5 81.78,74.34 85.54,74.34 87.04,75.84 90.52,75.84 93.54,78.87 150.2,78.87 150.92,78.15 150.92,76.44 152.89,74.47 153.6,74.47 153.95,74.12 153.95,73.39 153.76,73.21 153.76,68.32 152.66,67.23 152.2,67.23 151.87,66.89 151.87,62.95 150.04,61.12 146.91,61.12 146.66,60.87 146.66,60.51 146.89,60.28 147.29,60.28 147.51,60.05 147.51,59.81 v2(147.74,59.58)
  BOTTOM w0.127: UCPU1.AD9 147.44,59.89 v2(147.74,59.58) ; v2(81.94,74.79) 81.79,74.94 81.79,75.32 81.44,75.67 80.86,75.67 80.61,75.42 79.56,75.42 ML9.1
USB20_N4_CONN: length 9.6
  BOTTOM w0.127: JTS.3 71.91,76.16 72.16,75.9 72.77,75.9 73.35,76.48 74.58,76.48 75.51,75.55 75.94,75.55 76.2,75.81 DI4.2 77,75.44 77.72,75.44 77.8,75.52 ML9.2 78.22,76.52 v3(78.5,76.81)
USB20_N5: length 129.6
  IN1 w0.091: v2(63.14,74.63) 63.3,74.48 64.96,74.48 65.74,73.69 68.65,73.69 70.73,75.77 79.93,75.77 80.21,76.05 83.62,76.05 85.2,77.63 90.48,77.63 92.91,80.06 150.91,80.06 152.12,78.84 152.12,76.91 153.34,75.69 154.06,75.69 155.34,74.42 155.34,71.41 155.63,71.12 155.63,66.72 154.01,65.1 154.01,61.75 153.21,60.96 153.21,59.23 154.71,57.73 154.71,57.26 153.6,56.15 v2(153.6,55.84)
  BOTTOM w0.076: v2(153.6,55.84) 153.35,56.1 153.35,56.31 153.13,56.53 152.73,56.53 152.63,56.63 152.63,56.95 152.52,57.06 152.31,57.06 UCPU1.AJ1
  BOTTOM w0.127: L55.4 63.08,69.17 63.61,69.17 63.93,69.48 63.93,69.99 63.35,70.57 63.35,72.15 64.26,73.06 64.26,74.12 63.95,74.43 63.35,74.43 v2(63.14,74.63)
USB20_N5_CONN: length 9.4
  BOTTOM w0.127: L55.3 61.39,69.05 61.27,69.17 60.94,69.17 60.62,69.49 60.02,69.49 DI3.3 59.18,69.36 59.06,69.49 58.54,69.49 56.64,71.39 56.64,72.08 56.5,72.22 JCAM.4
USB20_P1: length 96.5
  IN2 w0.102: v2(200.91,19.62) 200.71,19.41 200.71,19.25 200.44,18.97 198.91,18.97 196.41,21.48 196.41,22.21 194.32,24.3 194.32,26.36 193.51,27.17 191.97,27.17 189.64,29.5 189.64,34.25 186.39,37.49 186.39,47.86 187.73,49.2 187.73,54.43 187.89,54.58 187.89,56.06 186.33,57.62 184.91,57.62 183.97,58.56 180.12,58.56 178.02,56.46 176.43,56.46 172.41,60.48 166.78,60.48 164.21,63.05 160.1,63.05 159.86,62.82 159.86,62.66 160.04,62.48 v2(160.04,62.47)
  IN4 w0.091: v2(147.1,60.7) 147.31,60.49 147.31,60.28 147.52,60.06 151.86,60.06 153.38,61.59 156.11,61.59 156.62,61.07 159.41,61.07 159.94,61.6 159.94,62.38 160.04,62.48 v2(160.04,62.47)
  BOTTOM w0.127: v2(147.1,60.7) 146.79,61.01 UCPU1.AB10 ; JIO1.32 200.91,18.41 200.91,18.6 200.73,18.79 200.73,19.43 v2(200.91,19.62)
USB20_P2: length 180.5
  IN1 w0.091: v2(149.01,59.59) 149.18,59.59 149.22,59.63 149.22,60.05 149.66,60.49 150,60.49 152.35,62.85 152.35,64.56 154.6,66.8 154.6,68.35 154.33,68.61 154.33,69.71 154.78,70.15 154.78,70.66 154.46,70.98 154.46,74.18 153.75,74.89 153.04,74.89 151.32,76.61 151.32,78.34 150.39,79.27 93.25,79.27 90.69,76.7 85.39,76.7 83.93,75.24 80.85,75.24 79.58,73.97 70.08,73.97 68.88,72.77 64.54,72.77 64.05,73.26 61.98,73.26 61.19,74.05 58.1,74.05 57.13,75.01 52.72,75.01 51.9,74.19 46.95,74.19 40.6,67.84 34.94,67.84 33.43,66.32 31.66,66.32 31.28,65.95 30.59,65.95 29.36,64.72 29.36,53.9 30.62,52.64 30.62,49.03 30.13,48.53 30.13,47.54 29.7,47.11 29.7,46.89 26.7,43.9 25.17,43.9 v2(24.94,43.67)
  BOTTOM w0.127: v2(149.01,59.59) 149.08,59.65 149.08,59.92 148.94,60.07 UCPU1.AD7 ; v2(24.94,43.67) 24.74,43.86 24.05,43.86 ML11.4
USB20_P2_CONN: length 11
  IN4 w0.091: JUSB2.3 14.23,44.92 14.32,45.01 16.8,45.01 v2(17.06,44.75)
  BOTTOM w0.127: v2(17.06,44.75) 17.28,44.97 18.95,44.97 20.03,43.89 20.37,43.89 20.57,43.68 DI2.3 21.37,43.85 22.55,43.85 ML11.3
USB20_P3: length 155.8
  IN1 w0.091: v2(153,57.13) 153.25,57.39 153.25,57.45 153.04,57.67 152.71,57.67 151.3,59.07 150.37,59.07 150.27,58.97 144.26,58.97 144.14,59.1 140.15,59.1 138.91,60.33 138.91,63.2 138.3,63.81 138.3,64.55 138.78,65.03 138.78,67.07 137.93,67.92 123.68,67.92 123.41,67.65 123.41,66.84 122.88,66.31 121.48,66.31 121.07,66.72 121.07,67.28 120.78,67.57 118.88,67.57 116.81,69.64 114.74,69.64 114.47,69.37 114.47,68.84 114.1,68.47 112.2,68.47 111.05,67.33 109.67,67.33 109.51,67.5 109.09,67.5 108.75,67.15 107.94,67.15 107.22,66.44 100.5,66.44 99.21,67.73 83.64,67.73 82.3,66.38 80.98,66.38 80.19,67.17 79.68,67.17 78.45,65.93 65.54,65.93 64.53,64.92 64.53,62.36 63.86,61.68 62.84,61.68 59.79,58.63 59.79,56.65 56.5,53.36 52.92,53.36 50.03,50.47 50.03,48.7 45.3,43.97 45.3,39.29 41.7,35.69 41.7,35.31 41.13,34.74 39.47,34.74 39.03,35.18 39.03,35.72 38.83,35.91 38.64,35.91 v2(38.43,35.7)
  BOTTOM w0.076: v2(153,57.13) 153,57.14 153.25,57.38 153.25,57.45 153.13,57.57 152.58,57.57 152.14,57.14 152.01,57.14 151.89,57.09 151.72,57.09 151.5,57.15 151.41,57.15 151.25,57.1 151.19,57.1 151.18,57.09 151.02,57.09 150.9,57.15 150.76,57.21 150.58,57.21 150.5,57.13 150.5,56.97 150.6,56.87 UCPU1.AJ3
  BOTTOM w0.127: v2(38.43,35.7) 38.24,35.89 37.76,35.89 ML10.4
USB20_P3_R: length 6.7
  BOTTOM w0.127: JNGFF1.3 31.75,38.19 31.88,38.05 31.88,37.81 32.18,37.51 34.06,37.51 34.78,36.79 34.78,36.28 35.12,35.95 36.26,35.95 ML10.3
USB20_P4: length 101.8
  IN1 w0.091: v2(81.1,74.79) 81.26,74.79 81.43,74.62 81.43,74.42 81.7,74.15 85.62,74.15 87.12,75.65 90.6,75.65 93.62,78.67 150.12,78.67 150.72,78.07 150.72,76.36 152.81,74.28 153.52,74.28 153.75,74.04 153.75,73.47 153.57,73.29 153.57,68.4 152.58,67.42 152.12,67.42 151.67,66.97 151.67,63.03 149.96,61.31 146.83,61.31 146.47,60.95 146.47,60.43 146.81,60.08 147.21,60.08 147.32,59.97 147.32,59.8 147.1,59.59 v2(147.1,59.58)
  BOTTOM w0.127: v2(81.1,74.79) 81.43,74.79 81.53,74.89 81.53,75.21 81.33,75.41 80.96,75.41 80.72,75.17 79.62,75.17 ML9.4 ; UCPU1.AD10 146.79,59.9 v2(147.1,59.58)
USB20_P4_CONN: length 13.2
  BOTTOM w0.127: JTS.2 71.91,75.36 72.21,75.65 72.87,75.65 73.45,76.23 74.47,76.23 75.41,75.29 75.68,75.29 75.82,75.15 75.82,74.68 DI4.3 77.08,75.18 77.69,75.18 77.85,75.02 ML9.3 79.11,74.12 81.54,74.12 v3(82.33,73.33)
USB20_P5: length 129.6
  IN1 w0.091: v2(63.13,74.01) 63.13,74.07 63.35,74.29 64.88,74.29 65.66,73.5 68.73,73.5 70.81,75.57 80.01,75.57 80.29,75.85 83.7,75.85 85.28,77.44 90.56,77.44 92.99,79.87 150.83,79.87 151.93,78.76 151.93,76.83 153.26,75.5 153.98,75.5 155.14,74.34 155.14,71.33 155.43,71.04 155.43,66.8 153.81,65.18 153.81,61.83 153.02,61.04 153.02,59.15 154.52,57.65 154.52,57.34 v2(153.02,55.84)
  BOTTOM w0.076: UCPU1.AJ2 151.65,56.87 151.93,56.59 152.44,56.59 152.66,56.37 153.06,56.37 153.18,56.24 153.18,56.01 v2(153.02,55.84)
  BOTTOM w0.127: L55.1 63.09,69.42 63.51,69.42 63.67,69.59 63.67,69.89 63.09,70.47 63.09,72.26 64.01,73.17 64.01,74.01 63.84,74.18 63.7,74.18 63.61,74.09 63.61,73.67 63.49,73.54 63.3,73.54 63.13,73.7 v2(63.13,74.01)
USB20_P5_CONN: length 9.4
  BOTTOM w0.127: L55.2 61.39,69.55 61.27,69.42 61.04,69.42 60.72,69.74 60.02,69.74 DI3.2 59.18,69.87 59.06,69.74 58.65,69.74 56.9,71.5 56.9,72.19 56.76,72.33 56.76,72.74 56.87,72.86 57.19,72.86 57.3,72.97 JCAM.5
USB_OC1#: length 98.2
  IN4 w0.081: v2(202.95,19.06) 201.93,20.07 201.22,20.07 199.24,22.06 192.91,22.06 191.54,23.43 191.54,24.6 189.87,26.27 187.33,26.27 182.52,31.07 182.52,36.67 180.95,38.24 180.95,42.12 174.75,48.32 174.32,48.32 173.46,49.18 173.46,54.42 169.72,58.15 169.72,60.54 169.1,61.16 169.1,62.55 168,63.66 168,65.41 167.59,65.82 167.01,65.82 164.14,68.69 164.14,69.35 162.97,70.52 161.16,70.52 160.05,71.64 158.71,71.64 158.01,72.34 158.01,73.28 156.92,74.38 152.1,74.38 151.59,74.89 149.89,74.89 149.63,74.63 v2(149.63,74.25)
  BOTTOM w0.127: JIO1.24 203.31,18.41 203.31,18.69 v2(202.95,19.06) ; v2(149.63,74.25) 149.63,75.4 RC185.1 148.97,75.35 148.97,74.23 148.74,74 148.74,73.5 147.86,72.62 147.86,71.61 147.47,71.22 UCPU1.C9
USB_OC2#: length 186.1
  TOP w0.127: v2(22.58,54.5) 22.24,54.16 22.24,52.45 20.98,51.18 19.99,51.18 US2.5
  IN2 w0.089: v2(64.54,77.35) 64.54,78.72 62.68,80.59 57.94,80.59 56.11,78.76 43.33,78.76 42.02,77.45 39.58,77.45 38.49,76.35 36.27,76.35 35.86,75.94 34.69,75.94 34.29,76.35 33.47,76.35 32.9,75.79 32.9,74.8 31.24,73.13 28.62,73.13 27.56,74.2 23.79,74.2 22.2,72.6 22.2,69.39 20.8,67.99 20.8,67.02 18.9,65.12 18.9,64.34 19.04,64.2 19.04,57.94 21.57,55.41 21.57,54.44 21.82,54.19 22.26,54.19 v2(22.58,54.5)
  BOTTOM w0.076: 148.26,72.48 148.26,71.54 148.31,71.48 148.31,70.52 148.15,70.36 UCPU1.D9
  BOTTOM w0.127: v2(64.54,77.35) 65.02,76.87 66.87,76.87 68.48,75.27 68.48,72.73 69.75,71.46 69.75,70.9 70.43,70.21 71.73,70.21 72.1,70.59 72.98,70.59 73.41,71.03 73.41,71.69 74.24,72.51 80.42,72.51 80.78,72.15 85.1,72.15 86.47,70.79 88.56,70.79 89.4,71.62 89.4,73.38 90.91,74.89 93.52,74.89 94.63,75.99 94.63,77.55 97.83,80.75 139.01,80.75 139.58,80.19 v3(144.43,80.19) 146.82,80.19 149.9,77.11 150.63,77.11 150.8,76.94 150.8,76.16 RC188.1 150.57,75.47 150.57,74.3 150.36,74.08 150.01,74.08 148.68,72.75 148.54,72.75 148.26,72.48
USB_OC3#: length 4.4
  BOTTOM w0.076: UCPU1.B9 147.47,71.84 147.21,72.09 147.21,72.73
  BOTTOM w0.127: RC191.1 147.23,75.38 147.23,74.25 v1(147.17,74.19) 147.17,73.94 147.33,73.77 147.33,72.85 147.21,72.73
USB_PWR_SHR_DET_R#: length 6.7
  TOP w0.127: v2(183.86,59.32) 184.11,59.06 UE5.B63
  IN3 w0.089: v2(183.86,59.32) 184.86,58.31 184.86,56.83 v2(184.43,56.4)
  BOTTOM w0.127: CE56.1 RE36.2 ; RE36.2 RE34.1 ; RE36.2 184.38,56.35 v2(184.43,56.4)
USB_PWR_SHR_EN_R#: length 179.1
  IN3 w0.089: v2(62.1,14.33) 62.1,14.34 60.73,15.72 56.35,15.72 56.05,16.02 50.31,16.02 48.69,14.4 40.12,14.4 39.48,15.04 38.31,15.04 37.94,15.41 v2(37.94,15.8)
  IN4 w0.081: v2(203.73,17.03) 200.29,13.58 166.44,13.58 166.15,13.87 v2(166.15,14.03)
  BOTTOM w0.127: JIO1.18 205.11,17.98 204.15,17.03 v2(203.73,17.03) ; UE4.19 37.41,16.88 37.92,16.37 37.92,15.82 v2(37.94,15.8) ; v2(62.1,14.33) 63.41,15.64 95.17,15.64 96.43,16.9 100.36,16.9 100.84,17.38 106.16,17.38 106.94,18.15 112.16,18.15 114.55,15.76 124.89,15.76 127.27,18.13 131.03,18.13 135.28,13.89 166.01,13.89 v2(166.15,14.03)
USB_PWR_SHR_VBUS_EN_R: length 177.1
  TOP w0.127: v2(38.55,15.54) 38.41,15.4 RE89.1
  IN2 w0.089: v2(197.94,14.64) 196.91,13.61 189.27,13.61 187.43,15.45 184.13,15.45 181.2,18.37 179.15,18.37 v2(178.09,19.44)
  BOTTOM w0.127: v2(178.09,19.44) 177.14,18.49 167.14,18.49 166.58,19.05 164.97,19.05 163.96,18.04 163.96,16.8 v3(162.77,15.61) 161.37,14.22 135.53,14.22 131.31,18.43 126.99,18.43 124.56,16.01 114.66,16.01 112.26,18.41 106.83,18.41 106.06,17.63 100.73,17.63 100.25,17.15 96.32,17.15 95.07,15.9 58.47,15.9 56.7,17.66 50.86,17.66 48.74,15.54 v2(38.55,15.54) 38.55,16.32 37.34,17.53 UE4.18 ; JIO1.39 198.81,15.54 198.81,15.08 198.37,14.64 v2(197.94,14.64)
USB_VBUS_EN_L: length 53.1
  TOP w0.127: v2(37.92,18.63) 37.74,18.44 36.84,18.44 RE59.1 v3(35.09,17.95) ; U699.2 25.5,54.39 25.28,54.16 24.42,54.16 v2(24.09,54.5)
  IN1 w0.081: v2(37.92,18.63) 35.71,20.84 35.71,21.68 34.6,22.79 34.6,25.74 34.1,26.23 34.1,32.28 33.1,33.28 33.1,35.34 31.57,36.86 31.57,36.86 29.96,38.48 28.33,38.48 27.4,37.55 24.3,37.55 23.42,38.42 23.42,53.84 v2(24.09,54.5)
  BOTTOM w0.127: UE4.17 37.47,18.18 v2(37.92,18.63)
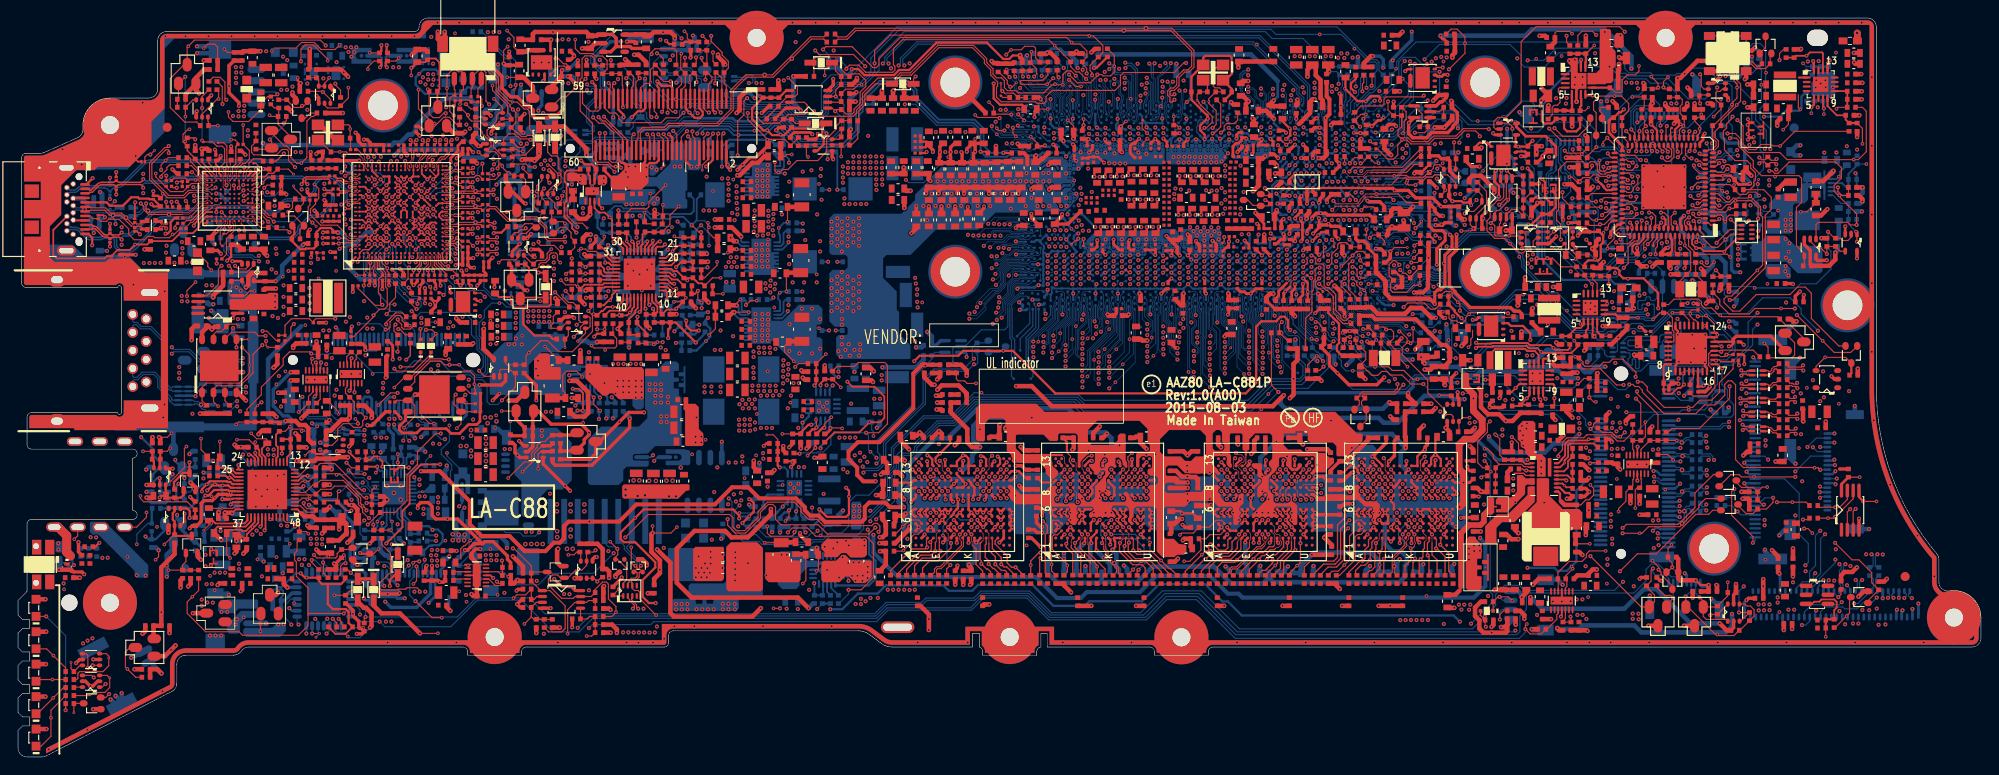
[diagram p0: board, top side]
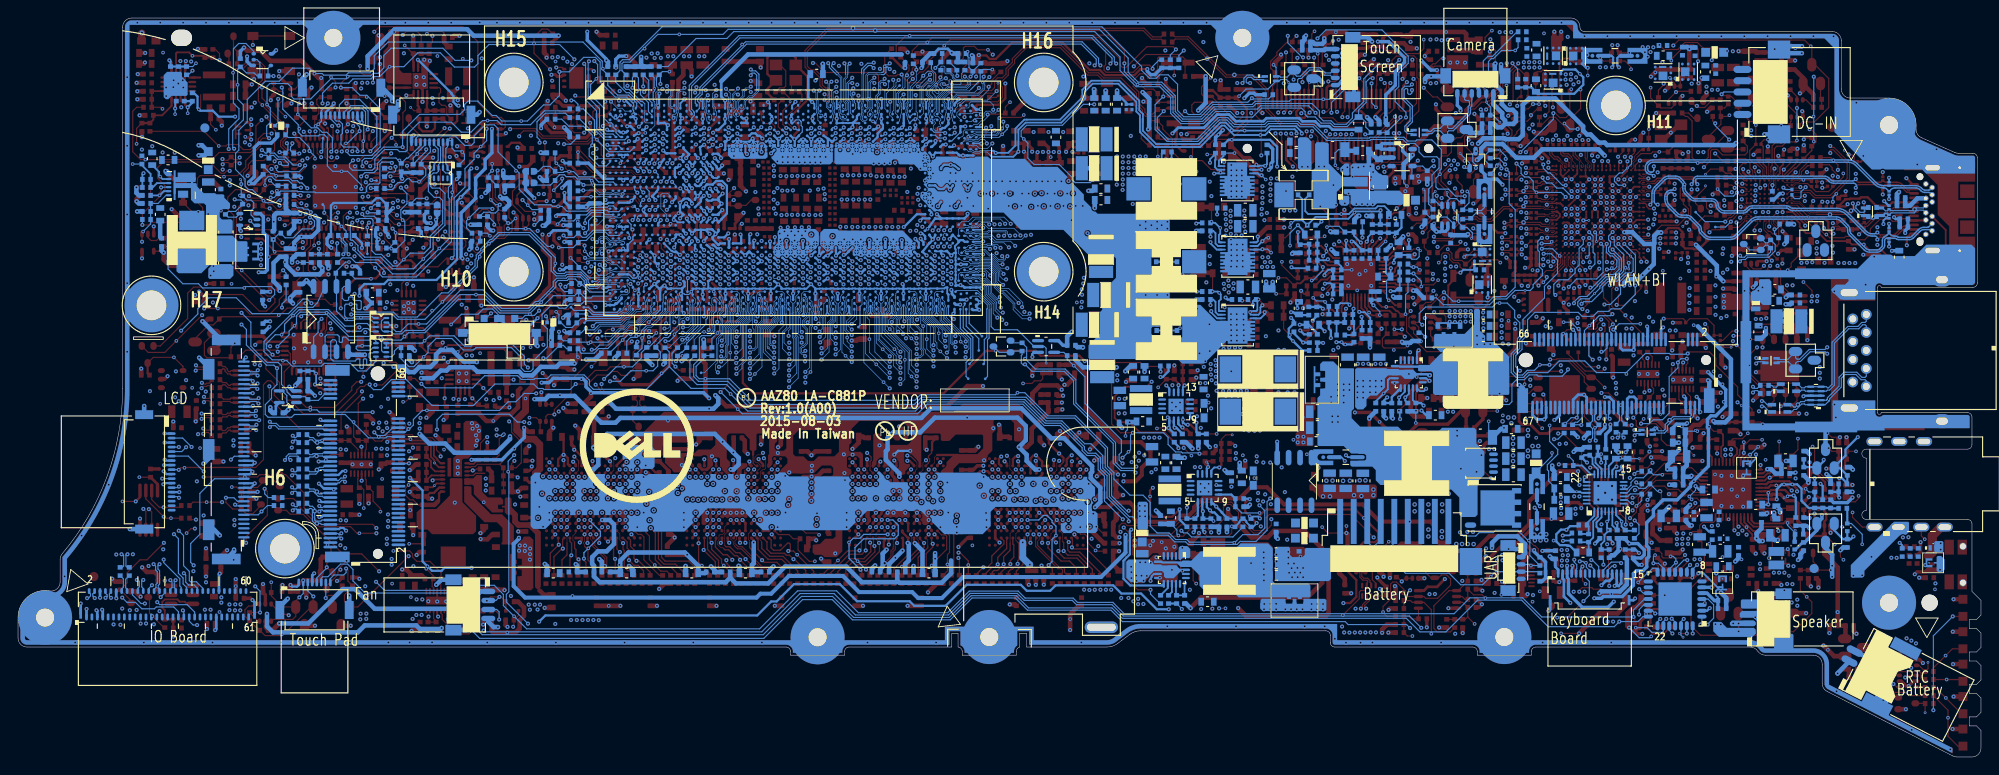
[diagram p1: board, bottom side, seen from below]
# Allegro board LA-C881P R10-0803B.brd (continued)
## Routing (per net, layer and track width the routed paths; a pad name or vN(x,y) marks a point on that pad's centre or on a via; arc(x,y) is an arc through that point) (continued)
USBC_MCP23017_SMBCLK: length 337.6
  TOP w0.127: UE5.B4 186.84,60.77 186.78,60.7 185.56,60.7 v2(185.32,60.46) ; v2(203.29,27.5) 202.98,27.19 U48.2 ; R1441.1 17.7,65.72 16.83,65.72 16.52,65.4 16.52,65.18 15.88,64.54 v2(15.88,64.37)
  IN1 w0.081: v2(15.88,64.37) 15.88,64.51 16.27,64.9 16.79,64.9 16.88,64.81 18.54,64.81 19.08,64.27 20.4,64.27 21.08,63.6 21.08,61.44 20.15,60.51 20.15,58.38 20.76,57.77 20.76,56.62 21.15,56.23 21.15,54.35 22.8,52.7 22.8,38.16 24.05,36.91 28.72,36.91 29.58,37.77 29.78,37.77 32.47,35.08 32.47,33.02 32.87,32.63 32.87,27.64 32.61,27.39 32.61,25.56 30.73,23.68 30.73,21.64 31.06,21.32 v2(31.5,21.32) 32.26,20.56 35.14,20.56 37.68,18.01 41.33,18.01 43.34,16.01 46.91,16.01 47.59,16.68 49.83,16.68 50.27,17.13 54.58,17.13 55.44,17.99 60.13,17.99 60.5,17.62 60.74,17.62 v2(61.19,18.07) ; v2(185.32,60.46) 185.35,60.46 185.57,60.68 187.12,60.68 188.5,59.3 188.94,59.3 189.19,59.56 189.19,60.13 188.26,61.06 188.26,62.28 189.33,63.36 189.92,63.36 191.17,62.1 191.17,61.5 192.65,60.02 192.65,57.34 192.14,56.83 192.14,43.91 193.23,42.82 193.23,38.39 198.78,32.84 198.78,29.37 199.8,28.36 202.44,28.36 v2(203.29,27.5)
  IN3 w0.089: v2(95.11,31.28) 96.26,30.12 96.26,23.85 99.52,20.59 104.82,20.59 105.25,20.16 156.03,20.16 160.86,24.99 160.86,28.18 161.03,28.35 161.03,28.81 163.66,31.45 163.66,33.81 162.64,34.84 162.64,37.27 163.05,37.68 163.41,37.68 163.76,38.03 166.08,38.03 166.61,38.56 170.7,38.56 171.32,39.18 173.83,39.18 174.12,38.89 179.98,38.89 180.96,39.87 180.96,41.99 176.86,46.08 176.86,48.09 177.66,48.89 177.66,51.09 177.92,51.36 177.92,52.24 179.26,53.58 182.15,53.58 184.01,55.44 184.01,57.55 183.44,58.12 183.44,59.47 183.85,59.88 184.12,59.88 184.7,60.46 v2(185.32,60.46)
  IN4 w0.081: v2(61.19,18.07) 61.92,18.07 64.25,20.39 66.23,20.39 69.96,24.12 69.96,25 72.07,27.11 74.26,27.11 77.1,29.96 78.05,29.96 79.25,31.16 84.11,31.16 84.94,31.99 84.94,32.61 85.33,33 87.26,33 88.08,33.82 88.66,33.82 89.08,33.4 91.99,33.4 93.41,31.99 93.41,31.39 93.72,31.07 94.9,31.07 v2(95.11,31.28)
  BOTTOM w0.127: UE4.8 31.99,20.83 31.99,20.83 v2(31.5,21.32) ; RE73.1 186.81,60.94 186.26,60.94 186.11,60.79 185.65,60.79 v2(185.32,60.46)
USBC_MCP23017_SMBCLK_R: length 3.2
  TOP w0.076: 20.37,64.17 20.39,64.14 20.73,64.14 20.83,64.04 20.94,64.04 U722.L2
  TOP w0.127: R1441.2 19.24,65.62 19.92,64.93 19.92,64.61 20.37,64.17
USBC_MCP23017_SMBDAT: length 338.2
  TOP w0.127: R1442.1 16.68,66.51 v3(16.38,66.2) 15.88,65.71 v2(15.88,65.14) ; U48.3 203.63,27.25 v2(203.9,27.52) ; RE71.1 190.36,60.88 v2(189.89,60.88) 189.48,60.47 188.49,60.47 188.43,60.52 188.06,60.52 UE5.A3
  IN1 w0.081: v2(203.9,27.52) 203.49,27.11 203.13,27.11 202.9,27.34 202.9,27.59 202.34,28.15 199.71,28.15 198.57,29.29 198.57,29.46 198.57,32.76 193.02,38.31 193.02,42.74 191.91,43.84 191.91,56.9 192.44,57.43 192.44,59.93 190.96,61.41 190.96,62.02 189.83,63.15 189.42,63.15 189.06,62.79 189.06,62.39 189.25,62.2 189.25,61.58 189.89,60.93 v2(189.89,60.88) ; v2(15.88,65.14) 16.38,65.65 19.12,65.65 20.29,64.49 20.48,64.49 21.29,63.68 21.29,61.35 20.96,61.03 20.96,59.73 21.17,59.52 21.17,56.5 21.36,56.32 21.36,54.44 23.01,52.79 23.01,38.25 24.14,37.12 28.64,37.12 29.5,37.98 29.86,37.98 32.68,35.16 32.68,33.11 33.08,32.71 33.08,27.56 32.82,27.3 32.82,25.47 31.78,24.43 31.78,22.75 32.19,22.33 32.19,21.4 v2(32.28,21.31) 32.35,21.31 32.9,20.76 35.23,20.76 37.77,18.22 41.42,18.22 43.43,16.22 46.82,16.22 47.5,16.89 49.74,16.89 50.18,17.34 54.16,17.34 54.83,18.01 54.83,18.62 55.07,18.86 59.82,18.86 v2(60.59,18.08)
  IN3 w0.089: v2(93.42,33.76) 93.63,33.97 95.62,33.97 96.52,33.07 96.52,23.89 99.58,20.84 104.96,20.84 105.4,20.39 116.85,20.39 118.35,21.89 124.2,21.89 125.6,20.49 155.94,20.49 160.53,25.08 160.53,28.3 160.81,28.58 160.81,28.9 163.39,31.49 163.39,33.77 162.42,34.75 162.42,37.36 162.96,37.9 163.31,37.9 163.66,38.24 165.99,38.24 166.52,38.78 170.61,38.78 171.24,39.4 173.92,39.4 174.2,39.12 179.9,39.12 180.74,39.96 180.74,41.88 176.64,45.98 176.64,48.2 177.44,49 177.44,51.18 177.71,51.44 177.71,52.33 179.17,53.8 182.01,53.8 183.68,55.47 183.68,57.5 183.15,58.04 183.15,59.79 183.3,59.94 183.3,60.58 183.54,60.82 184.44,60.82 184.49,60.77 185.01,60.77 185.12,60.87 185.57,60.87 185.7,60.74 189.63,60.74 189.89,61 v2(189.89,60.88)
  IN4 w0.081: v2(60.59,18.08) 60.59,18.1 60.97,18.48 62.04,18.48 64.17,20.61 66.15,20.61 69.76,24.21 69.76,25.09 71.99,27.32 74.17,27.32 77.01,30.16 77.97,30.16 79.17,31.37 82.8,31.37 84.65,33.21 87.18,33.21 87.91,33.94 87.91,34.49 88.13,34.71 89.79,34.71 90.55,33.95 93.23,33.95 v2(93.42,33.76)
  BOTTOM w0.127: v2(32.28,21.31) 32.64,20.95 32.64,20.61 32.64,20.61 UE4.9
USBC_MCP23017_SMBDAT_R: length 4.2
  TOP w0.076: U722.K2 21.26,64.23 20.9,64.23 20.75,64.37 20.47,64.37
  TOP w0.127: R1442.2 19.03,66.51 19.14,66.39 19.14,66.07 20.14,65.07 20.14,64.7 20.47,64.37
USBCOMP: length 2.5
  TOP w0.127: v2(149.06,60.69) 149.41,61.05 v1(149.6,61.05) 150.37,61.05 RC44.1
  BOTTOM w0.127: v2(149.06,60.69) 149.06,60.72 149.39,61.05 UCPU1.AB6
VCI_IN3#: length 6.6
  TOP w0.127: UE5.B68 186.61,58.42 187.06,57.97 187.06,57.45 187.97,56.55 188.59,56.55 v3(189.46,57.41) 190.06,58.01 191.24,58.01 RPE5.3
VID0_EDRAM_VR: length 3.6
  BOTTOM w0.254: PU1500.9 87.76,38.16 87.76,37.81 v2(87.05,37.1) 87.05,36.06 PR1504.2 PR1508.1
VID0_EOPIO_VR: length 5.9
  BOTTOM w0.127: v3(80.04,27.08) 82.03,27.08 PR1518.1
  BOTTOM w0.254: PR1518.1 PR1515.2 83.18,29.11 PU1501.9
VID0_PRIM_CORE: length 4.4
  TOP w0.127: PR1419.2 201.95,72.09 v3(201.78,71.92)
  TOP w0.203: PR1419.2 PR1415.2 PR1418.1 202.95,73.89 201.58,73.89 PU1401.9
VID0_VCCIO: length 3.9
  TOP w0.127: PR1405.2 v3(179.76,48.75)
  TOP w0.254: PR1407.1 177.26,49.12 PU1400.9
  TOP w0.508: PR1407.1 177.67,48.75 PR1405.2
VID1_EDRAM_VR: length 4.6
  TOP w0.127: PR1507.1 v3(84.81,35.85)
  TOP w0.254: PR1507.1 PR1503.2 86.84,36 87.71,36.86 v2(88.01,36.86)
  BOTTOM w0.203: v2(88.01,36.86) 88.24,36.86 88.56,37.18 PU1500.8
VID1_EOPIO_VR: length 3.5
  BOTTOM w0.203: PR1514.2 PR1517.1
  BOTTOM w0.254: PU1501.8 85.16,28.07 85.14,28.07 v2(84.86,27.79) 84.25,27.18 84.25,27.14 83.67,26.55 PR1517.1
VID1_PRIM_CORE: length 7.8
  TOP w0.127: v3(204.65,68.04) 204.65,69.75 PR1414.2
  TOP w0.203: 200.78,72.24 201.81,71.21 PR1417.1 202.79,70.72 PR1420.2
  TOP w0.254: PR1414.2 PR1420.2 ; 200.78,72.24 200.78,73.09 PU1401.8
VID1_VCCIO: length 2.7
  TOP w0.127: PR1404.2 176.61,46.69 PR1406.1
  TOP w0.203: PR1406.1 175.22,47.21 PU1400.8
VIDALERT_N: length 78.7
  TOP w0.127: PR1024.1 61.01,53.81 v2(60.81,53.6)
  IN4 w0.081: v2(116.03,76.46) 115.42,77.07 111.43,77.07 110.67,77.83 110.67,78.16 110.06,78.77 108.97,78.77 108.89,78.7 102.18,78.7 101.95,78.47 95.59,78.47 94.41,77.3 94.41,76.39 94.13,76.11 92.86,76.11 92.63,75.88 88.08,75.88 86.88,74.68 83.5,74.68 82.59,75.6 80.21,75.6 78.97,76.84 72.95,76.84 71.91,75.8 71.12,75.8 67.59,72.27 67.59,70.54 66.97,69.92 66.97,67.96 64.37,65.36 64.37,62.37 63.45,61.44 63.45,60.5 62.56,59.61 62.56,57.37 61.62,56.43 61.62,56.19 60.81,55.38 v2(60.81,53.6)
  BOTTOM w0.127: v2(116.03,76.46) 115.42,77.07 RC153.2 115.27,77.28 RC152.2
VIDSCLK: length 81
  TOP w0.127: RC155.2 113.41,77.12 RC158.2 112.91,77.58 112.91,78.67 112.72,78.86 111.7,78.86 111.3,78.47 v3(110.19,78.47) v2(109.65,77.94) ; v2(60.83,53.02) 60.94,52.92 PR1125.1
  IN4 w0.081: v2(109.65,77.94) 109.6,77.99 102.65,77.99 99.25,74.58 87.48,74.58 87.1,74.2 83.11,74.2 82.96,74.35 80.24,74.35 78.17,76.42 73.28,76.42 71.24,74.38 71.24,74.27 71.81,73.7 71.81,73.57 71.71,73.47 71.58,73.47 71.01,74.04 70.9,74.04 70.56,73.7 70.56,73.59 71.08,73.07 71.08,72.96 70.97,72.84 70.85,72.84 70.33,73.36 70.22,73.36 70.1,73.24 70.1,73.13 70.62,72.61 70.62,72.5 70.5,72.38 70.39,72.38 69.87,72.9 69.76,72.9 69.64,72.78 69.64,72.67 70.16,72.15 70.16,72.04 70.04,71.92 69.93,71.92 69.41,72.44 69.3,72.44 68.94,72.08 68.94,70.81 67.38,69.26 67.38,67.78 65.4,65.8 65.4,62.81 63.87,61.27 63.87,60.33 62.98,59.44 62.98,57.2 62.04,56.26 62.04,54.22 v2(60.83,53.02)
VIDSCLK_R: length 12.2
  TOP w0.127: v2(114.86,75.32) v3(114.18,74.65) 111.32,74.65 111.2,74.76 111.2,74.96 111.3,75.07 113.67,75.07 114.28,75.67 RC155.1
  BOTTOM w0.076: UCPU1.A63 116.31,72.39 116.31,73.18 116.71,73.58 116.71,73.77 115.43,75.05 115.3,75.05 115.03,75.32 v2(114.86,75.32)
VIDSOUT: length 77.1
  TOP w0.127: v2(61.44,55.33) PR1025.1
  IN4 w0.081: v2(113.59,75.57) 114.45,75.57 115.16,76.29 115.16,76.67 115.01,76.82 111.39,76.82 110.46,77.75 110.46,78.08 109.99,78.55 109.15,78.55 109.07,78.47 102.24,78.47 102.04,78.27 95.67,78.27 94.62,77.21 94.62,76.3 94.22,75.9 92.95,75.9 92.72,75.67 88.17,75.67 86.97,74.47 83.42,74.47 82.5,75.39 79.5,75.39 78.26,76.63 73.19,76.63 68.63,72.07 68.63,70.8 67.17,69.34 67.17,67.87 64.58,65.28 64.58,62.28 63.66,61.36 63.66,60.41 62.77,59.52 62.77,57.29 61.83,56.35 61.83,55.72 v2(61.44,55.33)
  BOTTOM w0.127: v2(113.59,75.57) 113.64,75.62 RC157.2 113.64,76.3 114.47,77.12 RC154.2
VIDSOUT_R: length 13.7
  BOTTOM w0.076: UCPU1.D64 115.93,70.8 116.08,70.8 116.19,70.69 116.19,70.58 116.03,70.42 116.03,70.29 116.21,70.11 116.21,69.68 116.05,69.53 115.82,69.53 115.77,69.58 115.77,69.86 115.7,69.94 115.52,69.94 115.47,69.99 115.47,70.16 115.57,70.27 115.57,70.49 115.42,70.65 115.42,70.77 115.7,71.05 115.98,71.05 116.18,71.26 116.18,71.39 115.89,71.68 115.89,73.21 114.65,74.44 112.67,74.44 112.45,74.67 112.45,74.83 112.57,74.95 112.97,74.95 113.21,75.19 113.77,75.19 113.97,75.4 113.97,75.65 RC154.1
VL: length 6.2
  TOP w0.127: v3(62.69,38.42) 62.67,38.44
  TOP w0.203: v3(62.69,38.42) 62.69,40.37 62.21,40.85 v2(61.57,40.85) ; 62.67,38.44 v2(62.08,38.44)
  BOTTOM w0.203: v2(61.57,40.85) 61.82,40.6 62.26,40.6 PU501.15
  BOTTOM w0.254: v2(62.08,38.44) 61.57,37.93 PC523.1
VRALERT#: length 15.4
  IN4 w0.089: v2(145.37,55.72) 144.97,55.32 144.97,54.21 144.99,54.18 144.99,52.32 145.24,52.08 145.72,52.08 150.22,47.58 150.22,47.33 v2(149.84,46.95)
  BOTTOM w0.076: v2(145.37,55.72) 145.7,56.05 UCPU1.AM11
  BOTTOM w0.127: RC73.1 v3(150.72,46.27) 150.04,46.95 v2(149.84,46.95)
VSA_SEN+: length 99.3
  TOP w0.127: v2(68.63,57.64) 68.66,57.67 PR1077.2 68.61,58.3 PC1072.2 ; RC168.2 140.06,68.59 v2(140.72,67.93) 140.82,67.93 141.17,68.29 v3(141.22,68.29)
  IN2 w0.089: v2(68.63,57.64) 68.78,57.49 69.24,57.49 69.66,57.91 73.62,57.91 73.95,57.58 76.9,57.58 77.89,58.57 77.89,60.68 76.84,61.73 76.84,66.51 78.07,67.74 80,67.74 81.03,66.71 81.81,66.71 82.81,67.71 96.33,67.71 97.68,66.37 97.68,65.3 98.3,64.68 98.79,64.68 98.94,64.54 111.01,64.54 111.68,65.21 115.16,65.21 116.15,66.2 116.46,66.2 116.94,66.68 119.08,66.68 119.28,66.89 119.28,67.32 119.58,67.62 120.17,67.62 120.28,67.73 123.33,67.73 123.77,68.18 126.39,68.18 126.65,68.44 126.65,70.12 126.95,70.42 127.15,70.42 128.19,71.46 128.8,71.46 129.54,72.19 137.34,72.19 138.53,71 138.53,68.47 138.89,68.11 139.32,68.11 139.52,68.31 140.34,68.31 v2(140.72,67.93)
  BOTTOM w0.127: PC1072.2 68.66,59.34 PR1077.2 68.66,57.67 v2(68.63,57.64) ; UCPU1.H20 141.01,67.64 v2(140.72,67.93)
VSA_SEN-: length 99.5
  TOP w0.127: v2(139.8,67.89) 140.06,67.64 RC166.1
  TOP w0.203: PU1000.26 68.76,56.57 68.71,56.63 68.71,56.98 v2(68.81,57.08)
  IN2 w0.089: v2(139.8,67.89) 138.02,67.89 137.52,68.4 137.52,71.3 136.98,71.83 129.69,71.83 128.96,71.1 128.34,71.1 127.51,70.27 127.51,68.39 127.09,67.97 123.86,67.97 123.42,67.52 120.37,67.52 120.17,67.32 120.17,66.89 119.75,66.47 118.3,66.47 117.58,65.74 116.92,65.74 116.46,65.29 115.85,65.29 114.88,64.32 98.85,64.32 98.7,64.47 98.21,64.47 97.46,65.21 97.46,66.28 96.24,67.5 82.9,67.5 81.9,66.49 80.94,66.49 79.91,67.52 78.16,67.52 77.05,66.42 77.05,61.82 78.11,60.77 78.11,58.48 76.99,57.36 73.86,57.36 73.53,57.69 69.75,57.69 69.33,57.27 69,57.27 v2(68.81,57.08)
  BOTTOM w0.127: UCPU1.H21 140.06,67.64 v2(139.8,67.89) ; PC1074.1 70.59,58.26 71.22,58.89 72.48,58.89 v3(72.57,58.8)
  BOTTOM w0.203: v2(68.81,57.08) 69.57,57.84 PC1077.1 PC1074.1
VSET_5085: length 3.4
  TOP w0.127: UE5.A17 186.36,68.72 186.36,69 186.59,69.22 v3(186.59,69.71) 186.59,70.01 186.03,70.57 CE55.1 RE77.1
WLAN_WIGIG60GHZ_DIS#: length 43.4
  TOP w0.127: v2(41.76,43.09) 42.03,42.82 43.92,42.82 45.82,44.73 DZ1.1 ; RE14.2 35.86,14.78 35.86,15.03 35.59,15.31 v2(35.59,15.32)
  IN4 w0.081: v2(41.76,43.09) 41.57,43.28 35.68,43.28 34.85,42.45 34.85,41.4 34.73,41.28 34.73,39.56 35.05,39.24 35.05,34.94 34.79,34.69 34.79,33.48 33.93,32.62 33.93,27.85 35.15,26.63 35.15,22.18 34.65,21.68 34.65,16.69 35.56,15.77 35.56,15.34 v2(35.59,15.32)
  BOTTOM w0.127: v2(35.59,15.32) 35.59,15.31 35.89,15 UE4.22
WLAN_WIGIG60GHZ_DIS#_R: length 3.3
  TOP w0.127: v2(45.26,47.41) 45.92,47.41 v3(46.35,46.98) 46.35,46.84 DZ1.2
  BOTTOM w0.127: v2(45.26,47.41) 45,47.14 JNGFF1.48
XCLK_BIASREF: length 2.3
  TOP w0.127: v2(128.87,69.83) 128.59,70.11 RC52.1 v3(128.25,71.08)
  BOTTOM w0.076: v2(128.87,69.83) 128.64,69.59 UCPU1.E42
XDP_DBRESET#: length 119.2
  TOP w0.127: JXDP1.48 67.1,67.33 67.1,68.62 65.14,70.58 64.89,70.58 64.47,71 v2(64.41,71) ; UC12.1 156.44,70.7 RC290.1 156.44,69.63 156.08,69.27 v2(154.99,69.27)
  IN3 w0.089: v2(154.99,69.27) 153.19,69.27 152.98,69.07 152.4,69.07 152.04,69.43 152.04,71.97 151.54,72.48 151.54,74.25 150.9,74.89 149.28,74.89 149.22,74.84 148.18,74.84 147.71,74.37 147.71,73.97 146.28,72.54 143.73,72.54 143.37,72.89 143.37,74.55 143.04,74.88 142.84,74.88 142.72,74.99 140.35,74.99 139.88,74.52 139.88,73.29 139.98,73.19 139.98,72.37 138.28,70.67 137.45,70.67 137.2,70.43 136.74,70.43 136.63,70.54 135.61,70.54 134.68,71.47 129.42,71.47 128.92,70.96 127.73,70.96 127.22,71.47 121.74,71.47 121.13,70.86 117.75,70.86 117.37,71.24 114.26,71.24 113.25,70.23 113.25,69.8 112.9,69.45 111.35,69.45 110.64,68.74 106.86,68.74 106.3,68.18 100.58,68.18 99.2,69.55 93.83,69.55 91.79,67.52 83.77,67.52 82.17,69.12 78.99,69.12 78.02,70.09 74.07,70.09 73.31,70.85 71.73,70.85 71.45,70.57 64.9,70.57 64.47,71 v2(64.41,71)
  BOTTOM w0.127: CC32.1 66.75,69.27 RC137.2 65.89,69.38 64.41,70.85 v2(64.41,71)
XDP_OBS0: length 5.4
  TOP w0.127: JXDP1.21 73.6,73.05 73.6,74.01 74.04,74.46 74.04,74.66 74.05,74.67 74.05,75.85 RC239.2 73.54,76.35 73.54,77.98 v3(73.6,78.04)
XDP_OBS0_R: length 63.2
  TOP w0.127: RC239.1 74,76.81 v2(74,77.61)
  IN4 w0.081: v2(120.1,75.12) 120.1,75.45 120.17,75.53 120.17,77.98 118.85,79.31 116.73,79.31 116.66,79.24 110.59,79.24 110.41,79.41 93.43,79.41 92.86,78.84 92.86,78.7 93.5,78.06 93.5,77.93 93.4,77.83 93.27,77.83 92.63,78.47 92.49,78.47 92.4,78.38 92.4,78.24 93.04,77.6 93.04,77.47 92.94,77.37 92.8,77.37 92.17,78.01 92.03,78.01 91.94,77.92 91.94,77.78 92.57,77.14 92.57,77.01 92.48,76.91 92.34,76.91 91.7,77.55 91.57,77.55 90.98,76.96 88.28,76.96 87.51,76.19 80.46,76.19 78.05,78.6 74.99,78.6 v2(74,77.61)
  BOTTOM w0.076: UCPU1.C55 120.77,71.62 120.64,71.75 120.64,74.2 120.4,74.45 120.4,74.82 v2(120.1,75.12)
XDP_OBS1: length 3.3
  TOP w0.127: RC240.2 73.61,75.27 73.61,74.64 73.1,74.12 JXDP1.23
XDP_OBS1_R: length 67.9
  TOP w0.127: v2(70.3,78) 70.3,78.2 70.68,78.59 72.83,78.59 73.09,78.33 73.09,76.89 RC240.1
  IN3 w0.089: v2(72.07,71.5) 72.59,72.01 75.56,72.01 76.87,70.7 78.28,70.7 79.25,69.73 82.42,69.73 83.48,68.68 85.46,68.68 86.56,69.78 89.21,69.78 89.84,70.41 91.47,70.41 91.95,70.88 99.45,70.88 100.35,69.99 106.61,69.99 108.84,72.22 110.58,72.22 110.72,72.36 118.56,72.36 119.01,71.91 120.51,71.91 121.04,72.44 v2(121.04,72.71)
  BOTTOM w0.076: v2(121.04,72.71) 121.04,71.51 121.09,71.46 121.09,71.23 120.77,70.92 UCPU1.D55
  BOTTOM w0.127: v2(72.07,71.5) 72.07,72.61 70.08,74.61 70.08,77.78 v2(70.3,78)
XDP_OBS2_R: length 3.6
  BOTTOM w0.076: UCPU1.B54 121.62,71.95 121.62,73.89 121.2,74.31 T10.1
XDP_OBS3_R: length 3.8
  BOTTOM w0.076: T11.1 120.02,74.51 120.47,74.05 120.47,71.46 120.21,71.19 UCPU1.C56
XDP_PRSNT_PIN1: length 12.1
  TOP w0.127: JXDP1.1 78.6,74.46 78.35,74.71 78.35,75.94 RC122.1 78.82,76.44 78.82,77.2 78.13,77.89 78.13,78.19 76.91,79.41 v2(76.91,80.02) ; v2(75.22,77.63) 75.25,77.61 75.25,77.01 RC121.1
  BOTTOM w0.127: v2(76.91,80.02) 76.91,79.24 75.31,77.63 v2(75.22,77.63)
XTAL24_IN: length 8.2
  TOP w0.127: v2(131.65,69.81) 131.87,69.81 132.5,70.44 132.5,71.08 131.04,72.54 131.04,72.67 v1(130.83,72.87) 130.83,73.53 CC21.1 RC46.2 131.98,74.62 YC1.3
  BOTTOM w0.127: v2(131.65,69.81) 131.61,69.81 131.61,69.79 131.41,69.59 UCPU1.E37
XTAL24_OUT: length 10.7
  TOP w0.127: v2(132.56,69.81) 132.94,70.19 132.94,71.71 132.13,72.52 v1(132.13,72.73) 132.13,73.05 RC46.1 CC22.1 133.31,74.25 132.82,74.25 132.63,74.44 132.63,76.16 133.26,76.79 YC1.1
  BOTTOM w0.127: UCPU1.E35 132.3,69.81 v2(132.56,69.81)
XTAL_25_IN: length 7.3
  TOP w0.076: 38.08,66.59 38.27,66.41 38.27,66.21 38.58,65.89 38.58,65.35 38.65,65.28 38.66,65.28 UT1.D22
  TOP w0.127: 38.08,66.59 37.71,66.96 36.61,66.96 36.42,67.14 v3(35.7,67.14) CT43.1 33.41,68.45 YT1.1
XTAL_25_OUT: length 2.5
  TOP w0.076: UT1.D23 38.82,65.58 38.82,65.94 38.47,66.29 38.47,66.61 38.22,66.87
  TOP w0.127: RT11.2 37.69,67.4 38.22,66.87
XTAL_25_OUT_R: length 4
  TOP w0.127: YT1.3 35.49,70.15 36.68,70.15 36.86,69.98 v3(36.86,69.68) CT44.1 36.89,68.63 RT11.1
N15438182:
  vias: v2(45,27.55) v2(44.98,26.95) v3(43.54,27.01)
N15438615: length 2.5
  BOTTOM w0.203: PU300.3 42.1,26.59 42.67,26.02 42.67,25.56 PR305.2
N15438635: length 11.5
  TOP w0.127: PQ302.1 39.47,22.56 v3(40,23.09)
  TOP w0.254: v2(37.95,22.64) 38.02,22.56 PQ302.1
  IN2 w0.254: v2(40.44,25.97) 38.53,24.06 38.53,23.22 v2(37.95,22.64)
  BOTTOM w0.203: PU300.6 40.9,27.26 40.9,25.7 40.39,25.18 PC318.2
  BOTTOM w0.254: v2(40.44,25.97) 40.36,25.89 PC318.2 ; PR307.2 PR310.2 38.33,23.02 v2(37.95,22.64)
N15438982: length 5.7
  BOTTOM w0.203: PR317.1 PR314.2 42.14,23.61 41.78,23.96 41.78,24.65 PR312.2 41.49,25.42 v3(41.49,26.12) 41.3,26.32 41.3,27.26 PU300.5
N15439291: length 3.6
  BOTTOM w0.203: PU300.7 40.5,26.84 39.88,26.22 v3(39.88,26.12) 39.88,25.59 39.66,25.36 PC330.1 39.4,25.1 38.53,25.1 PR315.2
N15439295: length 5.4
  TOP w0.127: v2(39.42,25.79) 39.44,25.79 39.44,25.77 39.47,25.74 PC331.1 PR318.2 v3(41.38,25.18)
  BOTTOM w0.127: PU300.8 39.31,28.11 39.21,28.01 39.21,27.35 39.42,27.14 39.42,25.82 39.44,25.8 39.44,25.79 v2(39.42,25.79)
N15439512: length 4.7
  TOP w0.127: v3(39.63,29.97) 39.27,29.6 PC332.1 PR322.1 ; PR322.1 39.11,28.18 v2(38.68,28.18) ; PR322.1 PR319.2
  BOTTOM w0.127: v2(38.68,28.18) 38.89,28.18 39.22,28.51 39.47,28.51 PU300.9
N15440461: length 3.7
  BOTTOM w0.127: PU300.10 39.65,28.91 39.19,28.91 38.91,29.19 37.67,29.19 PR316.2 37.64,28.45 38.24,27.85 v3(38.24,27.85)
N15440728: length 4.8
  TOP w0.203: v2(40.44,32.22) 40.44,32.77 v3(40.02,33.2) 39.85,33.36 39.47,33.36 39.09,32.98 PR325.2 38.58,33 PR327.1
  BOTTOM w0.203: PU300.16 40.9,31.83 40.51,32.22 v2(40.44,32.22)
N15440949: length 3.3
  TOP w0.127: v2(39.85,32.22) 39.85,31.71 v3(39.7,31.55)
  TOP w0.203: PR326.2 38.74,32.22 v2(39.85,32.22)
  BOTTOM w0.203: v2(39.85,32.22) 39.85,32.04 40.13,31.76 40.42,31.76 40.5,31.68 PU300.15
N15441413: length 1.9
  BOTTOM w0.203: PR323.1 41.63,32.52 41.7,32.44 PU300.18
N15442134: length 39.8
  IN2 w0.203: v2(70.46,33.49) 70.59,33.49 70.65,33.55 70.73,33.55 71.3,34.11 71.3,34.81 69.52,36.58 58.55,36.58 56.6,38.54 50.75,38.54 48.37,36.17 48.37,34.84 46.2,32.67 v2(43.71,32.67)
  BOTTOM w0.203: v2(70.46,33.49) 70.24,33.27 PR313.3 ; PU300.20 42.5,31.9 43.1,32.5 43.1,33.19 43.4,33.49 PC335.1
  BOTTOM w0.254: PC335.1 44.03,33.49 PC334.2 43.75,32.67 v2(43.71,32.67)
N15442185: length 43.7
  TOP w0.127: v2(42.14,32.67) v3(42.14,33.61)
  IN2 w0.203: v2(70.59,32.85) 70.59,32.93 71.63,33.98 71.63,34.94 69.66,36.92 58.69,36.92 56.73,38.87 50.57,38.87 48.04,36.34 48.04,34.98 46.19,33.13 43.2,33.13 42.74,32.67 v2(42.14,32.67)
  BOTTOM w0.203: PR313.2 70.97,33.27 70.59,32.88 v2(70.59,32.85) ; v2(42.14,32.67) 42.14,33.12 PC335.2 42.77,33.22 42.77,32.64 42.1,31.97 PU300.19
  BOTTOM w0.254: PC335.2 PC336.1
N18244124: length 3.7
  BOTTOM w0.127: v3(54.62,37.25) 54.62,35.89 PR321.2
  BOTTOM w0.508: PR321.2 53.26,36.41 PC333.1
N18292747: length 13.8
  TOP w0.127: PQ100.2 28.14,69.22 29.57,67.8 29.81,67.8 29.81,67.79 30.26,67.34 30.26,66.53 30.93,65.87 31.4,65.87 v3(31.44,65.91) 32.05,66.53 32.05,70.57 32.56,71.08 32.79,71.08 PR105.1 32.44,71.46 31.87,70.89 PQ101.1
N20931556: length 4.6
  BOTTOM w0.127: PR324.1 v1(37.93,33.11)
  BOTTOM w0.203: PU300.17 41.3,31.36 41.3,32.29 PC337.1 PR324.1
N22878624: length 6.1
  TOP w0.127: PR101.1 28.05,71.08 v3(27.91,71.21) ; PR101.1 28.93,71.15 PR104.1 28.46,72.02 PL102.2 ; PR101.1 28.85,70.21 30.23,68.84 PQ100.1
N22878630: length 6.2
  TOP w0.127: v2(29.49,70.32) 29.77,70.6 PR101.2 ; v2(27.94,68.51) 28.14,68.31 PQ100.3 28.02,67.45 PR103.1
  BOTTOM w0.127: v2(27.94,68.51) 29.49,70.06 v2(29.49,70.32)
N22878645: length 3.9
  TOP w0.127: PR104.2 PR106.1 29.82,72.91 30.66,72.07 31.34,72.07 v2(31.52,72.25) 31.71,72.25 32.12,72.67 PQ101.2
N28314143: length 1.2
  TOP w0.127: T7.1 123.2,53.78 v2(123.39,53.78)
  BOTTOM w0.127: v2(123.39,53.78) 123.06,53.45 UCPU1.AT52
N28323796: length 1.2
  TOP w0.127: v2(127.05,54.37) 127.19,54.37 T8.1
  BOTTOM w0.076: UCPU1.AP43 v2(127.05,54.37)
N28323807: length 1.2
  TOP w0.127: T21.1 127.37,55.33 v2(127.05,55.01)
  BOTTOM w0.127: v2(127.05,55.01) 127.45,55.4 UCPU1.AN43
N28344853: length 2.7
  TOP w0.127: T18.1 144.49,51.95 144.27,51.95 143.99,52.23 143.99,52.72 v2(144.38,53.1)
  BOTTOM w0.076: v2(144.38,53.1) 144.72,53.45 UCPU1.AT13
N28375965: length 1.4
  TOP w0.127: T1.1 124.81,68.1 v2(125.31,68.6)
  BOTTOM w0.127: v2(125.31,68.6) 125.38,68.6 125.68,68.29 UCPU1.G46
N28375966: length 2.2
  TOP w0.127: v2(125.28,69.23) 124.74,69.78 124.74,70.6 T2.1
  BOTTOM w0.127: v2(125.28,69.23) 125.57,68.94 UCPU1.F46
N28424999: length 10.4
  BOTTOM w0.089: UCPU1.AW71 111.28,51.45 110.06,50.22 110.06,49.62
  BOTTOM w0.127: 110.06,49.62 110.06,46.49 110.24,46.31 110.24,42.22 T113.1
N28425002: length 9.1
  BOTTOM w0.089: 110.26,49.77 110.26,50.17 111.23,51.14 111.94,51.14 UCPU1.AW70
  BOTTOM w0.127: T114.1 110.59,43.69 110.59,46.32 110.31,46.6 110.31,49.72 110.26,49.77
N28769860: length 3.4
  TOP w0.203: PU1400.5 173.72,47.95 173.38,47.61 172.9,47.61 172.19,46.9 PR1409.1 171.32,46.69 PR1408.2
N28769975: length 2.6
  TOP w0.203: PU1400.6 174.22,47.56 173.97,47.3 PR1425.1 PR1410.1
N28771761: length 3.3
  TOP w0.127: PR1400.2 PR1423.2 173.84,53.3 v3(174.65,52.49) 174.72,52.41 PU1400.14
N28771835: length 6.3
  TOP w0.203: PU1401.14 200.28,78.08 200.16,78.19 198.84,78.19 v3(198.46,77.81) 197.28,77.81 PR1424.2 PR1411.2
N28842863: length 4.2
  TOP w0.127: v1(154.15,56.54) 152.72,56.54 v2(152.28,56.1)
  TOP w0.381: CC204.1 151.79,54.87 152.27,55.35 152.27,56.08 v2(152.28,56.1)
  BOTTOM w0.203: v2(152.28,56.1) 152.2,56.18 151.81,56.18 UCPU1.AL1
N28843886: length 3.3
  TOP w0.381: v2(147.2,48.89) 147.2,49.38 CC214.1
  BOTTOM w0.127: v2(147.2,48.89) 147.2,48.87 v3(147.81,48.26)
  BOTTOM w0.152: UCPU1.BB10 146.55,49.62 147.2,48.97 v2(147.2,48.89)
N28856399: length 4.3
  BOTTOM w0.089: 112.27,49.24 112.27,50.16 UCPU1.BA70
  BOTTOM w0.127: 112.27,49.24 112.27,48.12 T16.1
N28856402: length 7.4
  BOTTOM w0.127: T17.1 111.86,43.99 111.86,46.57 112.93,47.63 112.93,49.97 112.77,50.13 UCPU1.BA68
N28857231: length 8.5
  BOTTOM w0.127: UCPU1.BB68 113.25,47.55 112.1,46.39 112.1,44.3 112.62,43.78 112.62,42.22 T12.1
N28857234: length 5.2
  BOTTOM w0.127: T13.1 111.2,46.42 112.6,47.81 UCPU1.BB69
N28857237: length 1.6
  TOP w0.127: T14.1 144.87,56.4 v2(145,56.54)
  BOTTOM w0.127: UCPU1.AK13 144.84,56.72 145,56.56 145,56.54 v2(145,56.54)
N28857240: length 1.4
  TOP w0.127: v2(145.81,57.4) 146.03,57.18 T15.1
  BOTTOM w0.127: v2(145.81,57.4) 145.49,57.08 UCPU1.AK12
N28861827: length 8.2
  BOTTOM w0.076: UCPU1.C64 115.72,71.44 115.72,73.15 114.58,74.28 112.6,74.28 112.28,74.6 112.28,74.9 112.5,75.12 112.9,75.12 113.13,75.35 113.13,75.83 RC120.1
N28891648: length 6.7
  BOTTOM w0.076: UCPU1.BB11 145.99,49.5 146.62,48.87 146.62,48.59 147.52,47.69 147.91,47.69 148.11,47.5
  BOTTOM w0.127: RC245.2 149.2,44.74 148.57,45.37 v3(148.57,46.49) 148.34,46.71 148.34,47.26 148.11,47.5
N28938912: length 3.4
  BOTTOM w0.127: RC29.1 CC8.2 180.77,53.43 180.41,53.06 v3(178.64,53.06)
N29263363: length 3.6
  TOP w0.254: v2(198.98,72.09) 199.28,72.39 PU1401.5
  BOTTOM w0.127: v3(198.98,71.43) v2(198.98,72.09)
  BOTTOM w0.254: v2(198.98,72.09) 198.48,72.6 PR1421.1 PR1422.1
N29708559: length 7.9
  BOTTOM w0.076: 151.28,49.11 151,49.39 150.88,49.39 150.67,49.59 150.67,49.79 150.47,50 150.47,50.56 UCPU1.AY4
  BOTTOM w0.127: 151.28,49.11 154.08,49.11 154.51,49.54 156.1,49.54 T126.1
N29708561: length 4.4
  BOTTOM w0.127: T127.1 154.52,49.9 153.95,49.34 151.35,49.34 UCPU1.BB3
N29708599: length 5
  BOTTOM w0.089: 153.73,52.77 153.62,52.77 153.39,53 152.45,53 152.27,53.17 151.82,53.17 151.74,53.25 150.11,53.25 149.77,52.91 149.56,52.91 UCPU1.AU5
  BOTTOM w0.127: T128.1 153.73,52.77
N29708601: length 5.7
  BOTTOM w0.076: 153.01,53.46 152.53,53.46 152.42,53.57 152.02,53.78 151.61,53.88 151.49,53.84 149.81,53.84 149.46,53.48 UCPU1.AT5
  BOTTOM w0.127: T129.1 153.76,54.73 153.76,53.82 153.4,53.46 153.01,53.46
N29708639: length 6.1
  BOTTOM w0.076: UCPU1.BB5 149.59,49.56 150.17,48.98 150.44,48.98 151,48.42
  BOTTOM w0.127: T130.1 154.71,48.42 151,48.42
N30191461: length 4.1
  BOTTOM w0.127: PR1519.2 v2(88.11,27.67)
  BOTTOM w0.203: PR1519.2 PR1520.1
  BOTTOM w0.254: PU1501.5 86.9,26.77 PR1520.1
N30191517: length 4.2
  TOP w0.127: v2(90.15,36.51) 91.39,36.51 v3(91.44,36.46)
  TOP w0.254: PR1506.2 89.71,35.85 90.15,36.28 v2(90.15,36.51)
  BOTTOM w0.254: PU1500.5 90.06,36.59 v2(90.15,36.51) 89.51,35.87 PR1506.2
N30191518: length 4.6
  TOP w0.127: v2(89.46,36.53) 89.46,36.92 v3(90.25,37.7)
  TOP w0.254: v2(89.46,36.53) 89.28,36.53 88.62,35.87 PR1510.1
  BOTTOM w0.127: PU1500.6 89.56,37.36
  BOTTOM w0.254: PR1510.1 88.62,35.87 89.28,36.53 v2(89.46,36.53) 89.56,36.63 89.56,37.36
N30191539: length 3.8
  TOP w0.127: PR1500.2 v3(91.3,41.02)
  TOP w0.203: PR1500.2 PR1522.2 89.06,41.47 89.06,41.28 v2(89.04,41.26)
  BOTTOM w0.203: v2(89.04,41.26) 89.06,41.24 PU1500.14
N30191541: length 3.1
  TOP w0.254: PR1523.2 PR1511.2 86.09,32.51 v2(85.76,32.18)
  BOTTOM w0.127: v1(85.92,32.72) 85.76,32.57 v2(85.76,32.18)
  BOTTOM w0.254: PU1501.14 85.9,32.04 v2(85.76,32.18)
N30191542: length 7.7
  TOP w0.254: v2(81.13,28.61) 81.23,28.61 81.64,28.2 81.64,27.22 v3(81.14,26.72) 81.14,26.72 v2(80.38,25.96)
  BOTTOM w0.203: v2(80.38,25.96) 80.38,25.93 80.47,25.84 80.47,25.83 80.76,25.54 PR1525.2 81.51,26.04 81.51,26.18 81.75,26.42 81.89,26.42 ; 81.89,26.42 PR1524.1 ; 81.89,26.42 81.99,26.42 82.27,26.15 82.27,26.04 PR1514.1
  BOTTOM w0.254: PR1515.1 81.18,28.66 v2(81.13,28.61)
N30201864: length 2.8
  BOTTOM w0.203: PR1521.1 PR1527.1
  BOTTOM w0.254: PU1501.6 86.4,27.34 v2(86.34,27.27) PR1521.1
N30340494: length 2.8
  TOP w0.127: RC232.2 117.13,70 v3(116.47,70.66)
  TOP w0.508: RC232.2 117.13,68.66 v2(117.09,68.61)
  BOTTOM w0.254: v2(117.09,68.61) 117.41,68.29 UCPU1.G61
N31739843: length 8.2
  BOTTOM w0.076: T121.1 151.99,46.69 151.1,47.58 150.65,47.58 150.04,48.19 149.13,48.19 147.98,49.34 147.98,49.83 148.03,49.94 148.03,50.06 147.96,50.27 147.96,50.35 148.06,50.62 148.07,50.71 148.05,50.76 UCPU1.AY8
N40373163: length 0.9
  TOP w0.508: RD115.1 CD186.2
N40373501: length 2.6
  TOP w0.508: v3(154.24,40.38) 154.24,40 RD116.1 CD187.2
N40376778: length 3.9
  TOP w0.127: CD185.2 104.12,41.96 104.34,41.74 105.03,41.74 105.31,41.45 v3(106.29,41.45)
  TOP w0.508: CD185.2 104.09,42.63 RD112.1
N48756972: length 5.3
  TOP w0.127: RTCR1.1 13.06,8.85 v3(12.13,9.77) 11.91,9.99 11.91,11.64 12.42,12.15 D122.1
N49522242: length 3.9
  BOTTOM w0.203: PU300.1 42.9,26.76 43.71,25.94 PC311.1 43.54,25.56 PC310.2 44.37,24.75 PR304.2
N49522275: length 6
  BOTTOM w0.203: PR303.2 44.35,23.83 PC310.1 ; PU300.2 42.5,26.67 43.03,26.15 43.03,24.34 PC310.1 ; PC309.2 43.54,22.75 PC310.1
N49570867: length 5.8
  BOTTOM w0.127: PU700.1 201.38,62.33 202.29,61.43 PC700.1 PR701.1 PR700.1 203.1,59.14 v3(203.94,58.3)
N49570895: length 6.2
  BOTTOM w0.127: v3(205.09,65.79) PR707.1
  BOTTOM w0.203: PC707.2 203.1,64.7 204.06,65.67 PR707.1 ; PU700.4 202.39,63.68 202.87,63.2 PR704.2
  BOTTOM w0.254: PR704.2 PC707.2
N49571010: length 2.7
  BOTTOM w0.203: PC712.1 202.16,64.92 202.16,64.51 v3(202.04,64.4) 201.78,64.13 PU700.5
N49571039: length 3.1
  TOP w0.127: PC703.1 198.49,60.49 v3(197.81,60.49)
  TOP w0.508: PC703.1 PR703.2
N49753304: length 6.6
  TOP w0.127: RA16.2 17.32,24.67 v3(16.24,23.58)
  TOP w0.254: QA9.1 17.52,24.53 RA16.2 QA1.2 17.37,26.15 17.17,26.35 17.17,27.06 17.37,27.26 QA1.5
N49753333: length 5.4
  TOP w0.127: RA57.2 RA18.2 RA41.1 ; RA41.1 v3(16.68,20.74) ; RA41.1 18.26,21.31 18.63,21.68 18.63,22.63 QA9.2
N49753452: length 2.9
  TOP w0.127: RA37.2 v3(13.87,33.92)
  TOP w0.254: QA3.3 15.07,32.09 15.07,32.85 RA39.1 14.9,33.05 RA37.2
N49753456: length 3.1
  TOP w0.127: CA40.1 16.54,33.92 v3(16.89,34.27)
  TOP w0.254: QA3.2 15.72,32.97 RA39.2 15.79,33.05 CA40.1
N49755927: length 4.9
  TOP w0.127: v3(24.21,36.92) 24.46,37.17 RA24.2
  TOP w0.254: CA34.1 28.88,37.17 CA33.1 R7.1 RA25.2 RA24.2
N49756342: length 6.1
  TOP w0.127: CA106.1 30.25,36.18 30.45,36.38 31.55,36.38 v1(31.68,36.25)
  TOP w0.203: RA75.2 29.36,35.26 CA106.1 RA76.2 30.25,33.67 29.86,33.28 UA2.13
N49981946: length 10.1
  IN4 w0.254: JHP1.5 14.45,35.01 16.49,32.98 v2(17.45,32.98)
  BOTTOM w0.254: v2(17.45,32.98) 17.45,32.83 DA1.2 18.31,32.17 RA30.1 RA19.2
N50165058: length 19
  TOP w0.127: v2(164.6,65.08) 164.5,64.98 PU400.7 164.5,63.81 164.85,63.46 164.85,62.11 164.51,61.77 164.17,61.77 163.34,60.94 163.34,59.85 162.99,59.49 162.99,58.42 163.86,57.55 164.97,57.55 v3(165.56,56.95) 166.57,55.94 167.01,55.94 167.31,56.24 167.31,57.96 167,58.27 ; 167,58.27 PQ400.1 ; 167,58.27 167.73,58.27 168.78,59.32 PR403.2
  BOTTOM w0.127: PR400.2 164.69,64.98 v2(164.6,65.08)
N50165456: length 5.7
  TOP w0.127: PU400.3 165.15,60.19 165.71,60.76 166.3,60.76 PC406.1 PR412.1 PR409.2 167.06,61.81 PR408.1
N50165462: length 12.9
  TOP w0.127: PR408.2 166.62,63.11 165.73,63.11 165.46,62.84 165.46,61.8 164.31,60.64 164.11,60.64 163.85,60.37 PU400.1 163.85,59.66 v2(163.42,59.24) 163.58,59.24 163.86,58.95 163.86,57.91 163.97,57.81 166.6,57.81 PQ400.2
  BOTTOM w0.127: v3(162.6,59.77) 163.13,59.24 v2(163.42,59.24) 163.81,59.62 PR411.2
N50170477: length 6.4
  TOP w0.127: PC404.1 171.74,56.84 PU401.4 170.99,56.35 168.5,56.35 168.12,56.73 168.12,57.24 168.5,57.62 PQ400.5
N50170488: length 4.3
  TOP w0.127: PU402.1 PU402.2 172.06,57.17 172.06,56.52 172.87,55.71 PC404.2 PR407.1
N50196545: length 6.8
  TOP w0.127: PU402.4 174.41,57 v2(174.01,57.39) ; PU401.2 169.72,57.62 v2(170.41,58.3)
  IN3 w0.089: v2(170.41,58.3) 170.15,58.04 170.15,57.52 170.74,56.93 172.73,56.93 172.73,56.93 173.06,56.93 173.07,56.93 173.55,56.93 v2(174.01,57.39)
N50196918: length 2.2
  TOP w0.127: PQ400.6 PU401.1 169.71,59 PR404.2
N50197891: length 6.3
  TOP w0.127: v2(165.2,65.06) 165.8,64.46 PU400.5 166.09,64.47 PR402.2 PR406.1
  BOTTOM w0.127: PR400.1 164.69,63.41 PC403.1 165.58,64.68 v2(165.2,65.06) v3(165.2,65.83)
N50203343: length 3.6
  TOP w0.127: PQ400.3 166.88,56.88 v2(166.88,56.42)
  BOTTOM w0.127: v3(165.45,57.82) 165.74,58.12 PR405.1 PR401.2 166.88,56.88 v2(166.88,56.42)
N50266801: length 19.1
  TOP w0.381: PD301.1 PD302.1 39.47,18.84 40.23,18.09 v3(41,18.09) 42.25,18.09 v2(42.34,18.18)
  IN3 w0.508: v2(42.82,23.68) 42.62,23.48 42.62,20.59 42.9,20.31 42.9,18.74 v2(42.34,18.18)
  BOTTOM w0.381: PR305.1 42.29,24.22 v2(42.82,23.68)
  BOTTOM w0.508: v2(42.34,18.18) 42.15,18.37 40.06,18.37 39.29,19.14 39.29,21.93 PR307.1
N50638473: length 6.6
  TOP w0.127: QH8.3 9.05,9.05 9.89,9.05 v1(10.17,8.77) 10.17,7.71 9.63,7.16 8.37,7.16 8.03,6.82 R916.1
N52012553: length 3
  TOP w0.127: RE57.1 RE63.1 183.86,56.05 183.86,57.82 UE5.A59
N52091760: length 2.2
  TOP w0.127: RE70.2 175.67,72.09 v1(175.53,71.95) 175.53,71.65 175.76,71.42 QE9.2
N52092863: length 2.8
  TOP w0.127: v3(179.12,73.24) CE52.1 180.44,72.12 RE80.2
N52116668: length 7.5
  TOP w0.127: UE5.B61 183.16,58.71 183.16,59.91 182.65,60.41 v2(182.31,60.41)
  IN1 w0.081: v2(182.4,57.01) 182.4,57.57 182.88,58.05 182.88,60.01 182.49,60.41 v2(182.31,60.41)
  BOTTOM w0.127: v2(182.4,57.01) 182.45,56.96 182.45,55.89 RE64.1
N52475257: length 4.5
  TOP w0.127: R1255.1 43.54,44.54 v2(43.07,44.08)
  BOTTOM w0.127: v2(43.07,44.08) 43.5,44.51 JNGFF1.42
N52558730: length 5
  TOP w0.127: RE22.2 35.41,19.9 35.79,20.28 35.79,21.16 36.12,21.5 v2(36.35,21.5)
  BOTTOM w0.127: UE4.13 35.24,20.95 35.79,21.5 v2(36.35,21.5) 36.35,22.22 v3(36.16,22.4)
N52558748: length 4.4
  TOP w0.127: RE23.2 33.9,20.39 33.9,21.53 v2(33.85,21.58)
  BOTTOM w0.127: v3(34.44,22.26) 34.13,22.26 33.85,21.98 33.85,21.59 v2(33.85,21.58) 34.59,20.84 UE4.12
N52558768: length 3.5
  TOP w0.127: v2(32.59,21.85) 32.59,21.6 RE27.2
  BOTTOM w0.127: v2(32.59,21.85) 32.96,21.85 33.94,20.87 33.94,20.63 33.94,20.63 UE4.11
N52571191: length 3.9
  TOP w0.127: RE24.2 36.55,20.81 v2(36.93,20.43)
  BOTTOM w0.127: UE4.14 35.89,20.78 36.04,20.94 36.42,20.94 v2(36.93,20.43) 36.99,20.43 v3(38.05,19.38)
N52708219: length 4.9
  TOP w0.127: D81.1 R886.1 164.21,17.76 v2(164.39,17.76) 165.35,17.76 v3(165.79,17.33)
  BOTTOM w0.127: v2(164.39,17.76) 164.78,17.37 165.62,17.37 JFAN1.2
N52893865:
  vias: v3(174.22,17.74)
N52893916: length 2.9
  TOP w0.127: U716.10 171.7,18.77 171.86,18.93 171.86,19.64 C1258.1 171.73,20.11 v3(172.51,20.89)
N52894141: length 8.6
  TOP w0.127: U716.12 170.9,19.74 C1257.1 170.87,20.46 172.11,21.71 173.55,21.71 174.03,22.19 174.03,22.54 174.36,22.87 v3(176.16,22.87)
N52922903:
  vias: v3(177.41,30.85)
N52922958:
  vias: v3(182.78,29.67)
N52922960: length 4.9
  TOP w0.127: U717.10 179.28,30.87 179.18,30.77 179.18,30.14 C1292.1 178.87,29.88 178.42,29.43 178.42,28.39 177.6,27.57 v3(177.6,27.22)
N52923110: length 4.3
  TOP w0.127: v3(179.45,27.62) 179.45,29.65 179.68,29.88 C1163.1 180.11,30.06 180.11,30.84 180.08,30.88 U717.12
N52925836: length 2.5
  TOP w0.127: 49.12,22.02 49.12,23.09 49.48,23.45 49.6,23.45 v3(50.17,24.02)
N52925896:
  vias: v3(49.76,17.23)
N52925901: length 1.6
  TOP w0.127: U719.10 48.38,20.55 C1278.1
N52926051: length 1.6
  TOP w0.127: C355.1 48.47,19.75 U719.12
N52930519:
  vias: v3(39.35,42.5)
N52930580: length 1.6
  TOP w0.127: C1293.1 37.54,44.59 37.54,44.17 37.33,43.96 37.33,43.53 U720.10
N52930730: length 1.6
  TOP w0.127: U720.12 36.53,43.87 36.47,43.93 36.47,44.42 C1167.1
N52934489:
  vias: v3(28.68,41.36)
N52934545: length 2.1
  TOP w0.127: v1(35.55,38.02) 35.55,38.33 34.37,39.52 34.27,39.52 R1318.1
N52934547: length 3.3
  TOP w0.127: U664.10 32.72,40.5 32.23,40.01 C1214.1 31.23,38.28 v3(31.12,38.28)
N52934693: length 1.7
  TOP w0.127: U664.12 33.52,39.68 C1212.1
N53314393: length 5.1
  BOTTOM w0.127: PU300.11 39.65,29.31 39.25,29.31 39.01,29.55 39.01,29.61 38.59,30.04 38.19,30.04 37.96,29.81 37.23,29.81 PR309.2 35.88,29.46 v3(35.56,29.46)
N53314401: length 5.5
  BOTTOM w0.127: v3(35.35,31.32) 36.34,31.32 PR311.2 37.46,30.98 38.34,30.98 38.84,30.48 38.84,30.15 39.27,29.71 PU300.12
N54037762: length 4
  BOTTOM w0.127: v3(45.77,33.41) 45.24,32.88 PR320.1
  BOTTOM w0.203: PR320.1 44.27,32.34 43.29,31.36 42.9,31.36 PU300.21
N54529025: length 3.5
  TOP w0.127: v3(175.08,39.41) 174.82,39.41 v2(174.35,39.89) R2662.1
  BOTTOM w0.127: JNGFF2.60 174.5,40.04 v2(174.35,39.89)
N55884547: length 3.6
  TOP w0.127: v3(76.68,46.82) 77.38,47.52 PR1113.1
  TOP w0.254: PC1126.1 PR1113.1
N55884553: length 4.2
  TOP w0.127: v2(79.48,49.36) v3(81.1,49.36)
  TOP w0.508: v2(79.48,49.36) 79.35,49.36 78.84,48.85 PR1113.2
  BOTTOM w0.203: PU1102.6 79.93,48.68 79.48,49.13 v2(79.48,49.36)
N55884555: length 3.6
  TOP w0.127: v3(80.16,50.77) 79.73,50.35 v2(79.73,50.12)
  TOP w0.508: PC1126.2 v2(79.73,50.12)
  BOTTOM w0.203: PU1102.7 80.17,49.08 79.96,49.28 79.96,49.89 v2(79.73,50.12)
N55884618: length 3.5
  BOTTOM w0.203: PR1119.1 84.67,51.65 v3(84.52,51.5) 84.35,51.33 84.35,50.8 84.56,50.59 84.56,49.55 84.48,49.48 PU1102.1
N55884697: length 2.6
  TOP w0.127: v3(85.86,66.86) 85.31,66.86 85.08,66.63 PR1100.1
  TOP w0.508: PC1106.1 PR1100.1
N55884703: length 6
  TOP w0.508: PR1100.2 82.8,66.63 82.1,65.93 81.47,65.93 80.09,64.55 v2(79.83,64.55)
  BOTTOM w0.127: v3(79.36,64.08) v2(79.83,64.55)
  BOTTOM w0.203: v2(79.83,64.55) 80.02,64.55 80.24,64.77 PU1100.6
N55884705: length 5.5
  TOP w0.381: PC1106.2 83.22,67.86 81.86,66.51 81.18,66.51 v3(80.4,65.73) v2(79.83,65.16)
  BOTTOM w0.203: v2(79.83,65.16) 79.84,65.17 PU1100.7
N55884733: length 3.1
  BOTTOM w0.127: PR1103.1 v3(82.83,67.01)
  BOTTOM w0.203: PU1100.1 84.46,65.57 84.56,65.67 84.56,66.18 84.05,66.68 PR1103.1
N55885434: length 2.9
  TOP w0.508: PC1116.2 79.41,57.24 v2(79.73,57.24)
  BOTTOM w0.127: v3(79.08,57.61) 79.35,57.61 v2(79.73,57.24)
  BOTTOM w0.203: v2(79.73,57.24) 80.26,56.7 PU1101.7
N55885436: length 3.6
  TOP w0.127: PC1116.1 77.19,57.62 76.56,58.25 v3(76.56,59.27)
  TOP w0.508: PR1105.1 PC1116.1
N55885442: length 2.8
  TOP w0.406: PR1105.2 v2(79.73,56.35)
  BOTTOM w0.127: v3(78.77,55.96) 79.15,56.35 v2(79.73,56.35)
  BOTTOM w0.203: v2(79.73,56.35) 79.77,56.3 PU1101.6
N55885470: length 3.2
  BOTTOM w0.203: PU1101.1 84.43,57.1 84.56,57.23 84.56,57.93 84.41,58.07 v3(84.41,58.7) 84.98,59.27 PR1110.1
N55952897:
  vias: v2(170.79,42.04)
N55952962: length 1.7
  TOP w0.203: PR906.1 169.01,39.55 v2(168.91,39.65) 168.72,39.84 PU900.7
N56035968:
  vias: v3(176.07,80.45)
N56036060: length 3
  TOP w0.127: PR806.1 173.88,71.71 v1(174.25,72.08)
  TOP w0.254: PU800.7 173.42,73.07 173.46,73.03 173.46,72.27 173.33,72.15 PR806.1
N56040428: length 3.8
  TOP w0.203: PR605.1 PR603.2 PC609.2 171.94,31.25 PU600.16
N56040853: length 6.9
  TOP w0.127: PC605.1 173.41,27.97 173.97,28.53 174.31,28.53 174.83,29.05 174.83,29.83 v3(174.47,30.19)
  TOP w0.254: PU600.12 170.89,29.45 171.09,29.24 171.09,28.49 171.22,28.36
  TOP w0.508: 171.22,28.36 171.61,27.97 PC605.1
N56041706:
  vias: v3(170.55,34.11)
N56042868: length 2
  TOP w0.203: PC607.1 172.36,29.93 171.8,29.93 v1(171.62,30.11) 171.38,30.35 170.7,30.35 PU600.14
N56044469: length 1.6
  TOP w0.127: PU600.3 167.7,31.7 167.6,31.8 v2(167.35,31.8) 167.12,31.8 166.95,31.96 PC614.1
N56047927: length 2.6
  TOP w0.127: v3(174.41,23.66) PC604.1
  TOP w0.508: PR602.2 172.82,24.53 PC604.1
N56242723: length 4.2
  BOTTOM w0.076: UCPU1.AW50 123.82,51.54 124.16,51.2 124.16,50.2 124.31,50.05
  BOTTOM w0.127: 124.31,50.05 124.38,49.98 124.38,47.89 T19.1
N56561744: length 3.6
  TOP w0.127: UA2.35 24.11,27.88 23.83,27.59 v1(22.66,27.59) 21.21,27.59 CA86.2
N56561748: length 6.2
  TOP w0.127: CA86.1 21.18,25.74 v1(20.61,25.17)
  TOP w0.203: UA2.37 25.46,26.24 25.13,25.92 21.91,25.92 21.61,26.22 CA86.1
N56563648: length 4.9
  TOP w0.127: v3(25.87,35.92) 26.48,35.31 27.51,35.31 27.66,35.16 CA107.2
  TOP w0.203: CA107.2 27.07,34.23 27.07,33.65 27.46,33.25 UA2.19
N56565297: length 3.4
  TOP w0.203: UA2.7 31.49,29.88 v2(31.67,30.06)
  BOTTOM w0.127: v3(32.36,28.91) 31.67,29.59 v2(31.67,30.06)
  BOTTOM w0.254: CA108.2 31.29,29.68 v2(31.67,30.06)
N56565952: length 5.9
  TOP w0.127: v3(22.39,35.01) CA109.1
  TOP w0.203: RA77.1 22.84,32.09 23.45,31.47 23.68,31.47 24.08,31.08 UA2.27
  TOP w0.254: RA77.1 22.15,32.99 CA109.1
N56567001: length 7.2
  TOP w0.127: CA110.2 23.15,22.46 v3(23.54,22.07)
  TOP w0.203: UA2.39 26.26,26.05 25.29,25.08 24.92,25.08 24.79,25.21 23.51,25.21 CA110.2
N56594221: length 4.4
  TOP w0.076: RA54.2 26.42,34.42
  TOP w0.127: 26.42,34.42 25.64,35.2 v3(24.29,35.2)
  TOP w0.203: UA2.20 27.06,33.23 26.77,33.52 26.77,34.07 RA54.2
N56696147: length 5.9
  BOTTOM w0.127: PR200.3 55.09,60.97 55.44,60.62 56.02,60.62 56.09,60.69 PR222.2 57.48,60.69 PR221.2 57.51,60.79 56.81,61.49 56.81,62.56 v3(57,62.76)
N56696285: length 3.2
  BOTTOM w0.127: PU200.5 59.16,61.4 59.16,61.4 59.16,61.72 58.91,61.96 ; PR221.1 57.88,61.63 58.22,61.96 58.91,61.96 ; 58.91,61.96 59.23,62.29 v1(59.23,62.67)
N56699994: length 8.3
  TOP w0.127: 56.69,54.01 57.05,54.01 57.24,54.2 57.62,54.2 57.81,54.39 57.81,54.64 58.02,54.85 58.57,54.85 58.96,55.24 58.96,55.73 59.17,55.94 59.67,55.94 59.86,55.75 59.86,55.61 59.86,55.6 59.86,55.33 59.86,55.33 59.86,55.17 v3(60.17,54.86)
  TOP w0.203: PQ204.2 56.69,54.29 PR207.1 PR201.2
N56700271: length 4.5
  TOP w0.127: PQ206.6 57.1,54.7 PR207.2 57.61,55.1 58.46,55.1 58.7,55.34 58.7,55.88 v3(59.17,56.35)
N56700855: length 5.2
  TOP w0.127: PR290.1 55.93,58.86 56.24,59.18 57.08,59.18 PD200.1 57.03,58.76 56.37,58.1 55.83,58.1 55.47,57.74 PQ206.2
N56701480: length 5.1
  TOP w0.127: PD200.2 59.5,58.11 60.17,58.78 60.78,58.78 61.37,58.2 61.37,57.64 PR289.2 61.77,56.52 PR213.2
N56701483: length 2.5
  TOP w0.127: v3(60.69,59.2) 60.49,59.41 PD200.3 59.21,59.6 PR216.2
N56704062: length 4.9
  TOP w0.127: v3(38.83,76.31) 38.83,76.55 39.5,77.22 PR236.1
  TOP w0.254: PR236.1 40.3,77.03 40.3,76.67 v2(40.17,76.54)
  BOTTOM w0.254: 39.31,77.81 40.11,77.81 40.36,77.56 40.36,76.73 v2(40.17,76.54)
N56704064: length 4.5
  TOP w0.127: v3(42.25,77.57) 41.91,77.22 PR238.1
  TOP w0.254: PR238.1 40.81,77.03 40.81,76.67 v2(40.93,76.54)
  BOTTOM w0.254: v2(40.93,76.54) 40.82,76.66 40.82,77.63 41,77.81 PR231.2
N56704066: length 12
  BOTTOM w0.254: PR241.1 PR232.2 49.87,74.3 PC206.2 49.16,73.59 45.14,73.59 44.13,74.6 44.13,75.43 v3(44.5,75.81) 44.98,76.28 45.02,76.28 46.36,76.29 46.61,76.03 PQ210.3
N56704068: length 27.8
  TOP w0.127: v2(34.14,78.95) 33.54,79.55 19.57,79.55 v3(18.89,78.87) 18.77,78.75 PQ205.1 18.42,76.82 16.89,75.29 16.89,72.07 18.5,70.46 19.82,70.46 PR212.1
N56704069: length 10.5
  TOP w0.127: v2(43.64,76.48) v3(43.64,75.62)
  TOP w0.203: PC208.2 45.2,77.11 PR237.2 45.59,77.5 46.33,77.5 46.76,77.07 46.76,74.1 PR244.1 46.53,72.17 PQ214.1
  TOP w0.254: v2(43.64,76.48) 44.27,77.11 PC208.2
  BOTTOM w0.254: v2(43.64,76.48) 43.81,76.48 44.25,76.92 PQ212.3
N56704070: length 21.6
  TOP w0.216: v2(57.76,53.75) 58.18,53.75 PD202.1 58.55,52.89 59.11,52.33 59.11,51.76 59.11,51.75 59.11,50.21 59.11,50.2 59.11,50.2 58.9,50 56.41,50 56.26,49.84 55.12,49.84 54.74,50.22 v2(54.74,51) 54.7,51.04 53.35,51.04 PC200.2
  TOP w0.254: PR210.1 59.35,46.38 58.97,46.76 57.32,46.76 56.05,48.03 56.05,49.63 56.26,49.84
  BOTTOM w0.216: PR202.2 57.45,54.06 v2(57.76,53.75)
  BOTTOM w0.254: PQ201.3 56.21,54.21 PR202.2 ; v2(54.74,51) 54.7,51.04 PQ200.3
N56704076: length 3.7
  BOTTOM w0.127: PR225.2 56.72,59.67 PR222.1 56.02,60.37 55.38,60.37 55.09,60.08 PR200.2
N56704097: length 2.9
  TOP w0.203: PD202.2 55.85,50.98 PQ204.1
N56712400: length 48.3
  TOP w0.127: PQ215.2 58.78,63.92 v2(58.98,63.71) ; PR287.2 92.25,70.61 PR288.2 90.79,70.01 90.79,69.68 89.73,68.61 89.73,67.17 88.74,66.18 86.42,66.18 85.43,65.19 84.89,65.19 84.56,64.86 v3(84.39,64.86) 84.16,64.86 83.99,65.03 v2(83.99,66.02)
  IN3 w0.089: v2(58.98,63.71) 59.72,63.71 61.25,65.25 61.25,66.4 59.46,68.2 59.46,69.22 59.87,69.63 71.84,69.63 72.12,69.91 72.83,69.91 73.1,69.64 73.1,68.37 73.88,67.59 79.77,67.59 80.97,66.39 83.62,66.39 v2(83.99,66.02)
N56713700: length 4.6
  TOP w0.127: PQ213.2 56.31,64.07 PR242.1 PR233.2 54.89,64.63 54.79,64.63 54.47,64.94 54.22,64.94 53.74,65.42 v3(53.74,65.57)
N56715138:
  vias: v3(48.49,80.3)
N56715373: length 3.7
  TOP w0.127: PR219.1 32.26,75.37 PR208.2 33.36,75.13 33.36,74.44 PQ207.3 PQ207.2 34.01,74.44 34.01,74.76 34.52,75.27 v3(34.52,75.37)
N56726680: length 2.3
  TOP w0.127: v1(60.69,45.44) PR210.2 61.06,46.75 PQ208.6
N56726937: length 6.1
  TOP w0.127: PR267.2 PR263.1 PR272.1 57.23,15.27 56.95,15.55 ; 56.95,15.55 PC216.1 57.51,17.16 58.18,17.16 PU203.3 ; 56.95,15.55 56.95,15.53 v3(56.19,14.77)
N56728350: length 0.8
  TOP w0.381: PC200.1 52.86,52.78 v2(52.86,52.13)
N56729247: length 10.9
  TOP w0.127: PR211.1 PR204.2 17.81,73.11 PQ205.2 v2(18.55,75.48)
  BOTTOM w0.127: v2(18.55,75.48) v3(18.55,68.3)
N56731386: length 9.7
  TOP w0.127: PR245.1 PR235.2 48.73,70.14 47.88,70.99 47.23,70.99 46.15,69.91 45.62,69.91 PQ214.2 45.62,70.75 44.43,71.94 v3(44.43,74.05)
N56741861: length 6.5
  BOTTOM w0.127: PU200.3 58.51,59.15 59.27,59.91 PC203.1 61.19,59.91 PR223.2 61.7,62.82 v1(61.89,63.01)
N56744237: length 17
  TOP w0.508: PQ214.3 48.36,69.22 PR235.1 49.45,69.22 v2(49.62,69.39) ; v2(43.69,77.9) 44.29,78.51 PC208.1 45.2,78.51 PR237.1
  IN2 w0.508: v2(49.62,69.39) 49.07,69.93 49.07,74.97 46.14,77.9 v2(43.69,77.9)
N56766808: length 4.4
  TOP w0.127: v3(87.08,19.24) 87.41,19.58 PR500.2
  TOP w0.508: PC504.1 87.35,22.5 PR500.2
N56766869: length 4
  BOTTOM w0.203: PR506.2 67.16,39.46 v3(66.28,40.33) 65.81,40.8 65.81,41.82 65.6,42.03 65.04,42.03 PU501.9
N56766888: length 1.6
  BOTTOM w0.203: PU500.12 90.23,19.21 90.23,18.75 PR503.2
N56767069: length 1.9
  BOTTOM w0.203: PR510.2 64.57,39.35 v2(64.57,39.89) 63.94,40.52 63.94,40.93 PU501.12
N56767083: length 8.2
  TOP w0.508: PC517.1 61.79,37.78 62.87,37.78 63.27,38.18 63.27,40.47 62,41.74 v2(61.19,41.74)
  BOTTOM w0.203: v2(61.19,41.74) 61.26,41.74 61.55,42.03 PU501.17
N56767132: length 3.2
  TOP w0.127: v3(58.48,45.54) 59.98,44.04 PC512.1
  TOP w0.508: PR505.2 PC512.1
N56767142: length 1.8
  BOTTOM w0.127: 89.22,17.03 PR504.1 88.67,16.44 v2(88.67,16.42)
  BOTTOM w0.254: PR504.1 PC511.2
N56767422: length 2.2
  BOTTOM w0.127: PR511.1 v3(62.71,37.06)
  BOTTOM w0.508: PC525.2 PR511.1
N56821674: length 3.4
  TOP w0.076: 26.31,59.37 26.26,59.43 26.26,59.57 26.1,59.72 25.26,59.72 U722.C10
  TOP w0.127: 26.31,59.37 26.92,58.76 R1437.1
N56821678: length 11.9
  TOP w0.076: v2(21.98,61.84) 22.12,61.97 22.51,61.97 U722.H6
  TOP w0.127: v2(17.61,61.62) 17.88,61.35 R1438.1
  IN3 w0.089: v2(17.61,61.62) 18.45,62.46 18.45,65.15 18.99,65.69 20.43,65.69 21.28,64.84 21.28,62.53 v2(21.98,61.84)
N56822218: length 5
  TOP w0.076: U722.E11 24.1,59.38 24.1,58.5 23.93,58.34
  TOP w0.127: 23.93,58.34 23.65,58.05 R1468.1 23.34,57.74 23.13,57.53 23.13,55.77 R1465.1
N56822254: length 4.9
  TOP w0.076: 20.42,61.22 21.74,61.22 21.84,61.32 22.36,61.32 U722.H7
  TOP w0.127: 20.42,61.22 v1(19.12,59.92) 19.01,59.81 C618.1
N56822270: length 1.3
  TOP w0.127: v2(23.14,63.46) 23.01,63.59 23.01,63.97 U722.G2
  BOTTOM w0.127: v2(23.14,63.46) 23.15,63.45 R1473.1
N56822627: length 7.5
  TOP w0.076: 22.54,65.49 22.54,64.99 22.76,64.77 22.76,63.22 U722.G4
  TOP w0.127: TC29.1 21.59,68.25 22.07,67.78 22.65,67.78 22.92,67.51 22.92,65.95 22.54,65.56 22.54,65.49
N56822629: length 6.2
  TOP w0.076: 23.32,64.96 23.32,64.62 23.27,64.57 23.27,63.86 23.58,63.55 23.58,63.04 U722.F4
  TOP w0.127: 23.32,64.96 23.32,65.48 23.17,65.62 23.17,67.81 22.83,68.16 TC25.1
N56822683: length 2.8
  TOP w0.076: U722.E10 24.01,59.93 23.76,59.68 23.76,59.29 23.9,59.14 23.9,58.66 23.67,58.43
  TOP w0.127: 23.67,58.43 23.55,58.32 23.38,58.32 23.12,58.05 TC36.1
N56822685: length 3.1
  TOP w0.076: 22.44,58.4 22.44,58.66 23.01,59.23 U722.G11
  TOP w0.127: TC38.1 22.44,56.92 22.44,58.4
N56856077: length 1.8
  TOP w0.076: 23.55,65.79 23.55,64.51 U722.F1
  TOP w0.127: RT190.1 23.55,66.15 23.55,65.79
N56859240: length 5.5
  TOP w0.076: 23.8,64.78 23.77,64.75 23.77,64.23 23.69,64.15 23.69,64.15 U722.F2
  TOP w0.127: v3(23.64,68.5) 24.07,68.5 24.4,68.17 R1471.2
  TOP w0.152: 23.8,64.78 23.8,65.46 24.17,65.82 24.17,67.75 R1471.2
N56859647: length 7.3
  TOP w0.076: 24.57,65.49 24.26,65.18 24.26,64.22 U722.E2
  TOP w0.127: v3(24.98,70.13) R1471.1 25.66,67.3 25.66,66.32 25.21,65.86 24.95,65.86 24.57,65.49
N56975718: length 1.2
  TOP w0.127: T183.1 189.13,64.02 UE5.A10
N56975734: length 1.1
  TOP w0.127: T184.1 183.36,69.68 183.36,68.72 UE5.A23
N56977728: length 2.9
  TOP w0.127: U15.27 186.41,48.2 186.09,48.51 185.95,48.51 185.55,48.91 v3(185.55,49.18) 185.55,49.44 185.73,49.62 R60.1
N56984382: length 2.3
  TOP w0.127: UE5.B23 184.11,67.2 v2(184.16,67.15)
  BOTTOM w0.127: v2(184.16,67.15) 184,67.32 T187.1
N56984398: length 1.3
  TOP w0.127: v2(178.61,64.02) 178.36,64.27 178.01,64.27 UE5.B41
  BOTTOM w0.127: v2(178.61,64.02) 178.56,63.97 T188.1
N56984414: length 2.9
  TOP w0.127: UE5.B62 183.61,58.87 183.43,59.05 183.43,59.98 v2(183.84,60.39)
  BOTTOM w0.127: T189.1 183.84,61.14 v2(183.84,60.39)
N57034346: length 4.2
  BOTTOM w0.076: UCPU1.AC3 150.61,60.18 150.96,59.84 151.51,59.84 151.63,59.76 152,59.76 152.12,59.83 152.69,59.83 153.49,59.03 T124.1
N57034424: length 4.9
  TOP w0.076: 27.03,60.9 27.03,61.22 26.8,61.45 26.39,61.45 26.17,61.23 24.75,61.23 U722.D7
  TOP w0.127: R1439.1 27.8,60.13 27.03,60.9
N57037386: length 3.2
  TOP w0.127: v1(30.58,63.37) 30.58,63.2 31.67,62.1 R1440.1 31.67,61.44 QT19.1
N57146881: length 10.5
  BOTTOM w0.076: T192.1 141.66,42.63 140.33,43.96 140.33,46.4 139.81,46.92 139.81,47.89 139.64,48.06 139.64,48.61 139.83,48.8 139.83,49.16 139.52,49.46 139.52,49.83 139.54,49.86 139.57,49.94 139.57,50.06 139.51,50.27 139.51,50.42 139.56,50.58 139.56,50.66 139.74,51.22 139.96,51.44 UCPU1.AW22
N57177583:
  vias: v3(152.91,76.38)
N57177874: length 1.2
  TOP w0.127: UZ22.4 164.81,48.79 165.88,48.79 RZ76.2
N57177931: length 2.1
  TOP w0.127: v3(160.94,45.47) 161.21,45.74 161.21,46.39 161.39,46.58 161.39,47.36
N57178338:
  vias: v3(162.56,65.04)
N57182329: length 4.6
  TOP w0.127: v3(36.66,74.27) 36.66,73.14 35.79,72.27 PR228.2 35.54,72.02 34.34,72.02 34.01,72.35 PQ207.5
N57280922: length 7.2
  TOP w0.076: 27.28,60.29 26.9,60.66 26.26,60.66 26.21,60.71 25.75,60.71 U722.B9
  TOP w0.127: 27.28,60.29 27.69,59.87 27.91,59.87 v2(28.38,59.41)
  BOTTOM w0.127: v2(28.38,59.41) 30.61,59.41 T193.1
N57280925: length 4.2
  TOP w0.076: 27.28,59.89 27.28,59.93 26.74,60.47 26.01,60.47 U722.A9
  TOP w0.127: v2(27.75,59.41) 27.75,59.42 27.28,59.89
  BOTTOM w0.127: v2(27.75,59.41) 28.34,58.81 T194.1
N57281646: length 1.3
  TOP w0.127: UE5.A55 181.86,57.51 181.46,57.1 T185.1
N57313034: length 3.5
  TOP w0.127: RC49.2 147.8,51.27 146.81,52.26 146.81,52.72 v2(147.2,53.11)
  BOTTOM w0.076: v2(147.2,53.11) 147.54,53.45 UCPU1.AT8
N57313074: length 3.6
  TOP w0.127: v2(148.12,53.11) 148.56,52.67 148.56,52.38 148.94,52 149.14,52 v3(149.36,51.78) 149.58,51.56 149.58,50.83
  BOTTOM w0.127: v2(148.12,53.11) 147.94,53.11 UCPU1.AU8
N57317696: length 9.1
  TOP w0.127: RC9.2 158.78,49.2 158.78,48.7 159.07,48.41 159.61,48.41 159.81,48.22 160.36,48.22 160.64,48.49 160.64,48.77 v3(161,49.13) 161.21,49.34 165.23,49.34 v2(165.33,49.23)
  BOTTOM w0.127: SW1.1 165.9,48.66 v2(165.33,49.23)
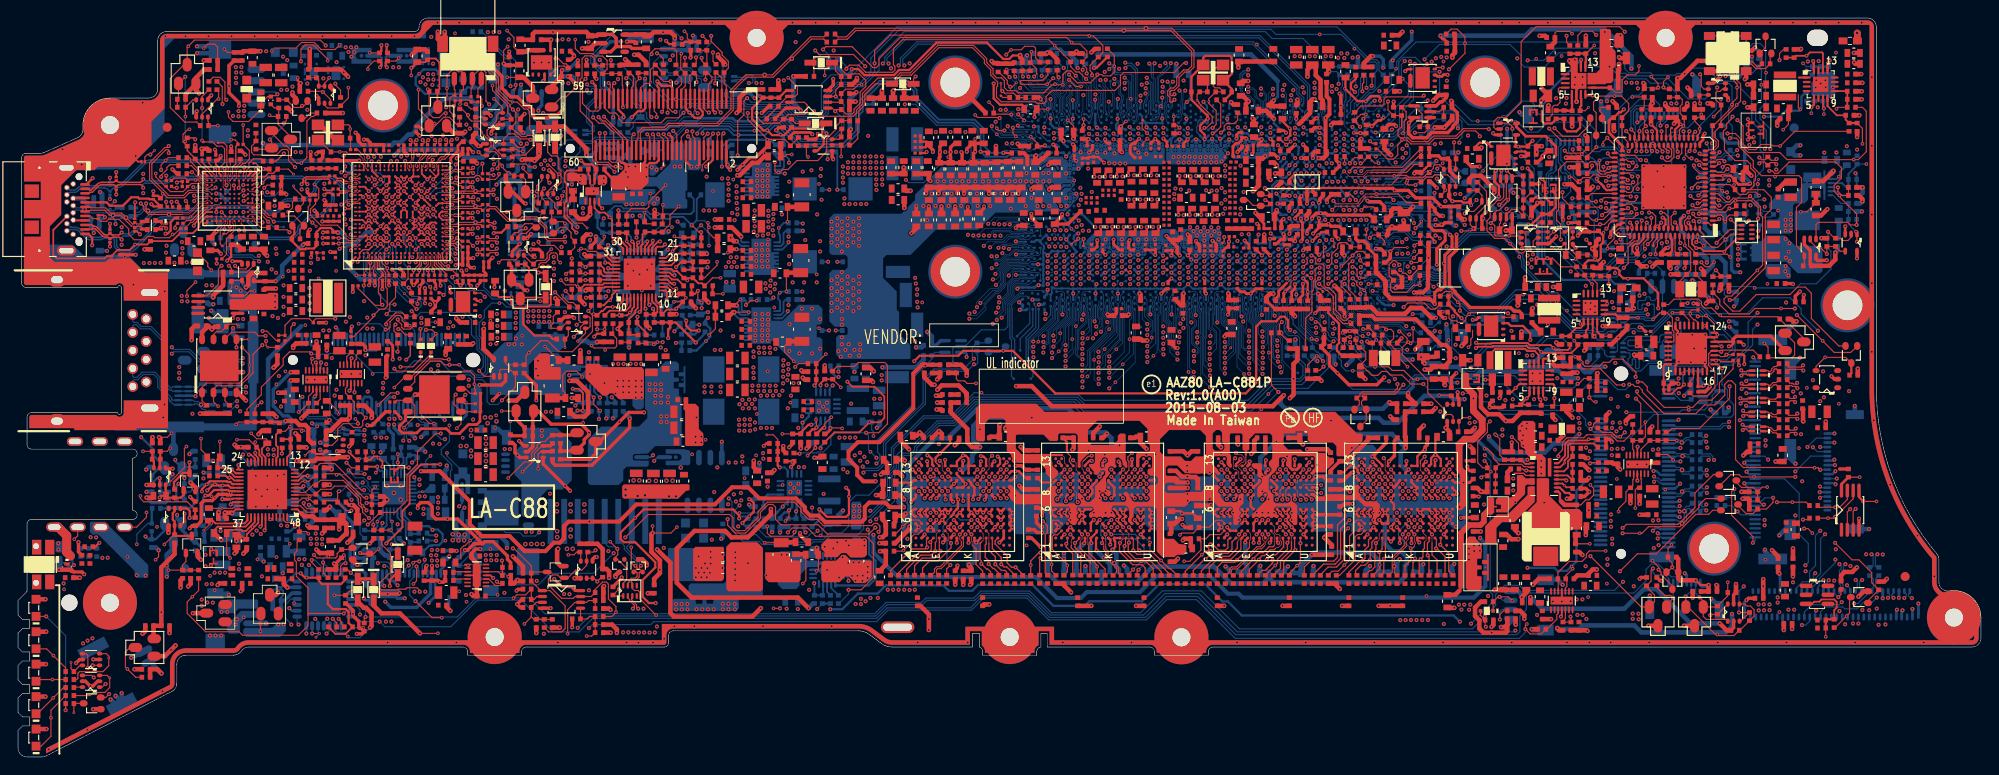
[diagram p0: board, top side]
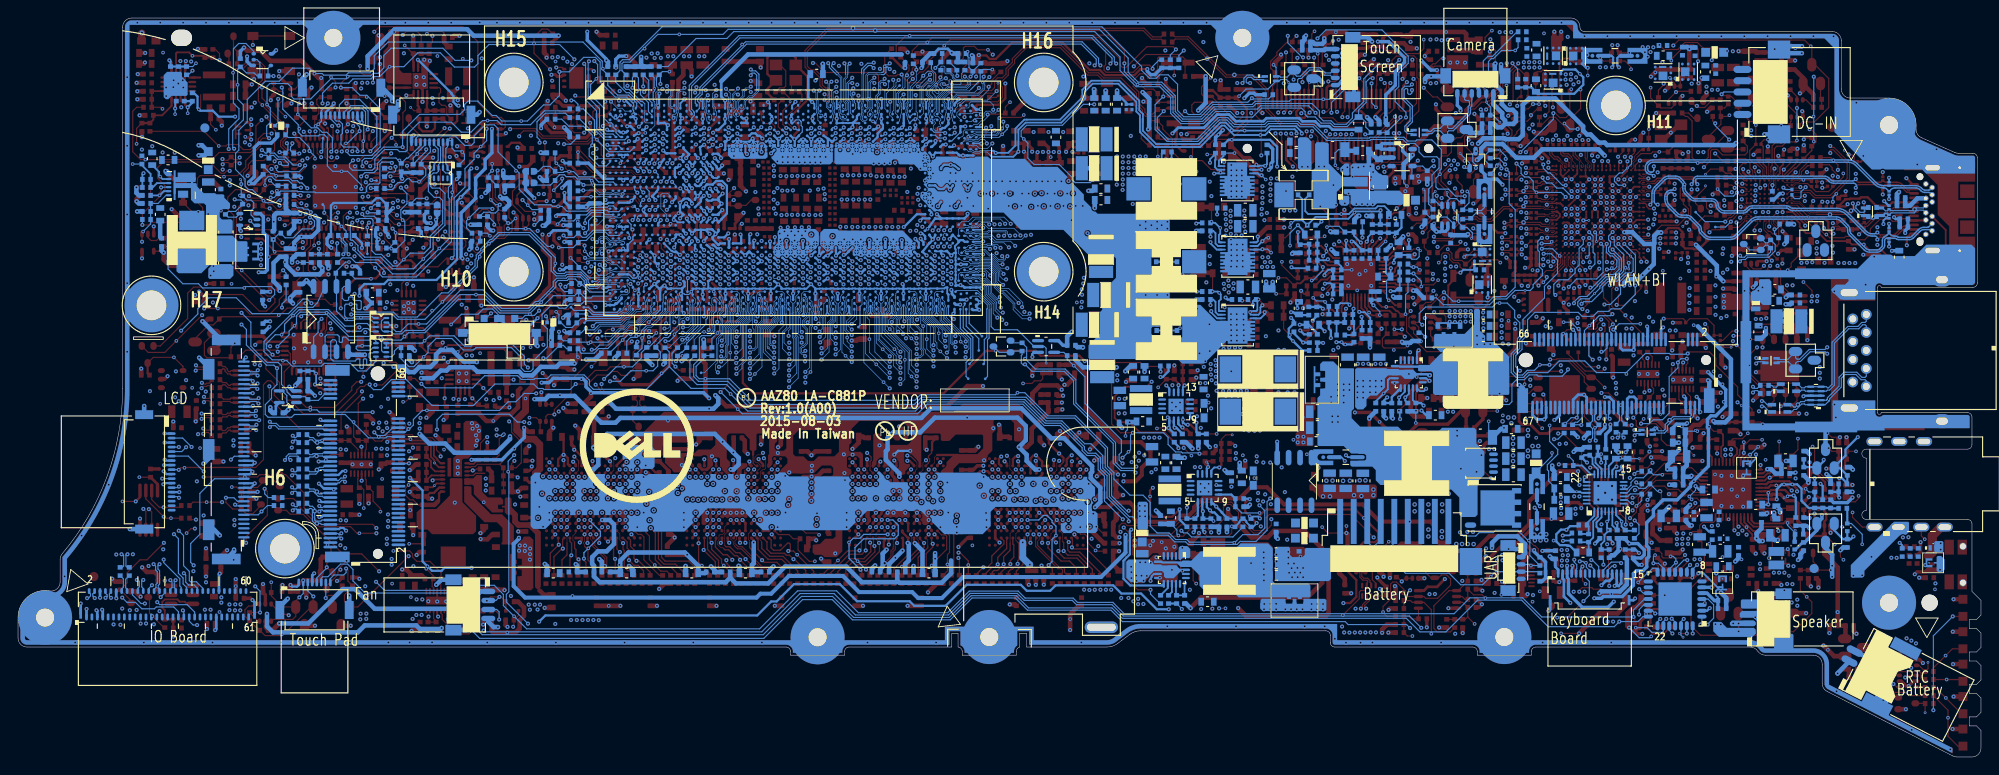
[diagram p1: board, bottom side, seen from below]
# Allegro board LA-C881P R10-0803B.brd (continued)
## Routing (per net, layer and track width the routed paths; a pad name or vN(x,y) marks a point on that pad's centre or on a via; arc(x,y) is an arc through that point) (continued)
N57319429: length 1.8
  TOP w0.127: v2(117.65,57.51) 117.45,57.31 117.3,57.31 T195.1
  BOTTOM w0.254: v2(117.65,57.51) 117.65,57.44 117.34,57.13 UCPU1.AK62
N57319432: length 1.9
  TOP w0.127: v2(118.24,57.49) 118.24,56.75 T196.1
  BOTTOM w0.254: UCPU1.AL61 117.86,56.57 117.86,57.09 118.24,57.46 v2(118.24,57.49)
N57408632: length 6.4
  TOP w0.127: RT164.2 38.46,67.03 38.86,66.63 v2(38.86,66.56) ; UT1.F19 39.9,63.76 v2(39.58,63.44)
  BOTTOM w0.127: v2(38.86,66.56) 38.77,66.47 38.77,65.82 39.24,65.35 v1(39.24,65.35) 39.25,65.35 39.79,64.8 40.13,64.8 40.67,64.26 40.67,63.88 40.24,63.44 v2(39.58,63.44)
N57526872: length 17.1
  TOP w0.076: v2(22.91,58.56) 22.91,58.84 23.27,59.19 23.27,59.73 U722.F10
  TOP w0.152: v2(19.66,68.54) 19.5,68.7 RT201.1
  IN1 w0.081: v2(22.91,58.56) 21.55,59.91 21.55,60.73 22.4,61.58 22.4,62.67 22.32,62.75 22.32,64.05 19.18,67.19 19.18,68.06 v2(19.66,68.54)
  BOTTOM w0.127: RT200.1 22.34,58.94 22.72,58.56 v2(22.91,58.56) 22.91,58.06 RT199.1
N57670088: length 2.1
  TOP w0.127: T116.1 143.37,53.15 v2(143.49,53.15)
  BOTTOM w0.127: v2(143.49,53.15) 143.52,53.11 UCPU1.AW15
N57912451: length 23.4
  IN3 w0.203: v2(75.79,59.01) 75.79,58.84 75.92,58.71 76.57,58.71 77.07,58.2 77.5,58.2 78.41,59.11 79.75,59.11 80.29,59.66 80.29,60.8 80.94,61.45 85.51,61.45 85.84,61.12 89.5,61.12 90.3,61.92 90.3,62.67 v2(90.02,62.95)
  BOTTOM w0.127: v3(76.67,56.74) 76.67,58.14 v2(75.79,59.01)
  BOTTOM w0.203: PR1130.2 v2(90.02,62.95) ; v2(75.79,59.01) 75.03,58.25 PR1102.1
N57965459: length 1.2
  BOTTOM w0.127: PQ201.2 57.11,55.71 v3(57.35,55.48)
N58401690: length 1.1
  BOTTOM w0.127: RE107.1 T197.1
N58453857: length 4.2
  TOP w0.127: R536.2 201.62,14.36 v3(202.9,15.63) 203.23,15.96 203.23,17.6 Q71.1
N58842401: length 1.8
  TOP w0.127: T125.1 149.63,57.99 v2(149.63,58.53)
  BOTTOM w0.127: UCPU1.AD4 150.17,59.47 149.78,59.09 149.78,58.68 v2(149.63,58.53)
N58864976: length 4.9
  TOP w0.127: v3(180.57,37.17) 180.57,35.53 180.16,35.12 R1445.2 R1446.2 179.17,34.15 179.28,34.04 U717.5
N59153523: length 6
  TOP w0.127: U15.3 183.11,46.07 183.63,46.07 183.73,46.18 183.73,47.23 183.57,47.4 183.57,48.72 183.01,49.28 R1006.2 182.15,49.28 v3(181.43,48.56)
N59418764: length 4.1
  TOP w0.076: 25.32,64.8 25.32,64.63 25.27,64.57 25.27,64.23 U722.C2
  TOP w0.127: R1436.1 26.95,66.38 26.11,66.38 25.63,65.9 25.63,65.36 25.32,65.06 25.32,64.8
N59418771: length 3.1
  TOP w0.076: U722.B2 25.76,64.22 26.19,64.22
  TOP w0.127: TC35.1 26.37,65.89 26.8,65.46 26.8,64.83 26.19,64.22
N59894012: length 2.8
  TOP w0.127: v3(183.57,49.28) RE92.2 185.41,48.51 185.41,47.88 U15.29
N59894959: length 1.6
  TOP w0.127: RC230.1 185.52,41.69 185.91,42.08 185.91,42.77 U15.13
N60736253: length 6.4
  TOP w0.127: v3(53.67,38.39) PQ221.2
  TOP w0.381: PR276.1 54.76,35.65 PR275.2 PC218.2 55.27,37.47 PQ221.2
N60748906: length 10.3
  TOP w0.127: v3(54.39,30.96) 56.16,32.73 56.69,32.73 56.99,33.03 56.99,33.74 57.6,34.35 57.6,34.59 58.01,35 58.45,35 59.15,35.7 PR279.1
  TOP w0.381: PQ222.2 61.78,35.73 PR278.2 59.33,35.73 PR279.1
N60750593: length 5.1
  TOP w0.127: v3(55.98,31.64) 57.29,32.95 57.29,33.67 58.14,34.53 PQ223.3
  TOP w0.381: PQ223.3 59.04,34.53 PR279.2
N60753752: length 3.4
  TOP w0.127: PQ223.2 57.98,33.88 57.71,33.62 v3(57.71,31.98)
  TOP w0.381: PQ223.2 59.23,33.88 PR277.2
N60757042: length 5.1
  TOP w0.127: v3(53.33,54.86) 53.65,55.18 55.25,55.18 55.47,55.41 PQ206.5 55.47,56.04 55.65,56.22 56.3,56.22 56.93,55.58 PR280.1
N60757502: length 2.9
  TOP w0.381: PQ223.6 55.68,33.23 v3(55.43,33.49) 55.14,33.77 55.14,34.6 54.89,34.86 PR276.2
N60799582: length 25.3
  TOP w0.254: PR1072.1 65.13,46.97 PR1067.2 64.26,46.97 v2(63.93,46.64)
  IN4 w0.254: v2(83.82,50.99) 82.34,50.99 79.42,48.07 77.09,48.07 75.67,46.64 72.72,46.64 72.31,47.05 70.41,47.05 70,46.64 v2(63.93,46.64)
  BOTTOM w0.254: v2(83.82,50.99) 83.59,50.76 PH1007.2
N60799583: length 3.4
  TOP w0.203: PU1000.8 69.96,50.27 v2(70.05,50.17)
  BOTTOM w0.203: PC1088.2 71.1,50.35 70.23,50.35 v2(70.05,50.17)
  BOTTOM w0.254: PR1061.2 71.45,49.16 PC1088.2
N60799590: length 2.2
  TOP w0.127: PR1098.1 68.83,45.91 PC1014.2 69.83,46.03 v3(70.94,46.03)
N60799626: length 5.5
  TOP w0.203: PU1000.5 68.76,49.82 68.48,49.54 68.48,49.27 67.77,48.56 PR1093.2 67.77,47 PR1065.2 67.92,46.85 PR1098.2
N60799629: length 0.9
  TOP w0.127: PR1065.1 67.77,46.03 PC1095.2
N60799635: length 3.9
  TOP w0.203: PR1122.2 PC1021.2 67.58,49.01 v3(67.9,49.32) 68.13,49.55 68.13,49.72 68.36,49.95 68.36,51.01 PU1000.4
N60799636: length 5.8
  TOP w0.127: PR1122.1 66.02,47.1 PC1020.2 66.42,46.44 66.42,45.57 66.23,45.39 63.9,45.39 v3(63.63,45.66)
N60799645: length 4.2
  TOP w0.203: PU1000.3 67.96,50.02 67.45,49.51 65.63,49.51 PR1072.2
N60799650: length 3.9
  TOP w0.203: PU1000.2 67.56,51.01 67.56,50.27 v2(67.41,50.12)
  BOTTOM w0.127: v2(67.41,50.12) 66.7,49.42 v3(66.7,49.04)
  BOTTOM w0.203: v2(67.41,50.12) 67.67,50.38 PC1131.2 PR1099.2
N60799669: length 3
  BOTTOM w0.127: PC1088.1 72.37,50.01 72.97,50.61 73.76,50.61 v3(74.1,50.95)
  BOTTOM w0.203: PR1087.2 PC1088.1
N60799680: length 34.6
  IN2 w0.254: v2(91.05,42.16) 88.59,42.16 87.88,41.46 87.88,39.4 86.41,37.93 86.41,37.17 84.25,35.01 79.32,35.01 74.14,40.19 74.14,43.57 71.68,46.03 v2(71.53,46.03)
  BOTTOM w0.254: PH1005.1 90.15,42.81 90.79,42.16 v2(91.05,42.16) ; v2(71.53,46.03) 70.97,46.03 70.71,45.78 v3(70.54,45.78) 69.83,45.78 PR1088.2
N60799687: length 3.1
  TOP w0.127: PR1025.2 62.64,54.7 v2(62.97,54.36) 63.3,54.7 PR1028.1
  BOTTOM w0.127: v3(62.25,54.04) 62.58,54.36 v2(62.97,54.36) 63.25,54.36 PR1074.2
N60799688: length 2.5
  TOP w0.203: PU1000.35 65.14,53.76 65.02,53.88 65.02,54.19 PR1028.2
N60799689: length 3.8
  TOP w0.127: PR1024.2 62.51,53.65 v2(62.97,53.65) 63.45,53.65 PR1076.1
  BOTTOM w0.127: PR1063.2 63.42,53.65 v2(62.97,53.65) 62.1,52.79 v3(62.1,52.21)
N60799690: length 2.1
  TOP w0.203: PR1076.2 64.96,53.36 PU1000.36
N60799691: length 5.7
  TOP w0.127: PR1070.1 v2(62.97,52.92) PR1125.2
  BOTTOM w0.127: v2(62.97,52.92) PR1084.2 63.58,51.58 63.85,51.31 v3(63.85,49.14)
N60799692: length 1.9
  TOP w0.203: PR1070.2 64.56,52.96 PU1000.37
N60799709: length 2.7
  TOP w0.203: PU1000.40 65.89,51.24 65.89,51.01 65,50.12 PR1029.2
N60799711: length 2.9
  TOP w0.203: PU1000.39 65.13,52.16 65.05,52.08 64.69,52.08 PR1095.2 PR1027.2
N60799723: length 5
  TOP w0.127: PR1094.1 64.49,55.77 64.16,56.1 63.24,56.1 62.98,56.36 62.36,56.36 v1(62.19,56.19)
  TOP w0.203: PR1094.1 65.28,55.58 65.9,54.96 PU1000.32
N60799725: length 3.8
  TOP w0.127: v3(65.06,57.74) 65.06,57.48 64.49,56.91 PR1121.1
  TOP w0.203: PU1000.31 66.41,55.36 65.98,55.36 64.75,56.6 PR1121.1
N60799730:
  vias: v2(62.35,63.84) v2(62.46,64.47) v2(72.87,65.52) v2(73.47,65.51)
N60799760: length 7.7
  IN3 w1.016: 62.71,61.93 62.87,61.78 64.21,61.78 64.64,62.21 69.98,62.21 70.08,62.32
  vias: v2(62.68,60.91) v2(62.68,60.33) v2(70.59,61.43) v2(70.97,61.93)
N60799765: length 6.4
  IN3 w1.016: 70.35,66.43 65.66,66.43 65,65.77 65,64.98
  vias: v2(65,64.22) v2(64.98,63.63) v2(70.31,65.44) v2(70.85,65.16)
N60799773: length 5.8
  TOP w0.127: PC1082.1 61.52,61.87 60.94,61.29 60.94,60.07 61.77,59.23 62.62,59.23 v1(63.14,58.71)
  TOP w0.508: PR1082.1 PC1082.1
N60799776: length 2.5
  TOP w0.508: v3(63.49,60.19) 63.01,59.71 62.25,59.71 61.57,60.39 PC1082.2
N60799787: length 1.4
  TOP w0.203: PR1059.1 63.3,64.63 63.47,64.46 PU1305.7
N60799795: length 4
  TOP w0.203: PR1085.1 PC1069.1 73.23,56.73 v3(72.63,56.13) 71.86,55.36 PU1000.20
N60799808: length 2.1
  TOP w0.127: v3(72.83,57.79) 72.97,57.64 PC1069.2
  TOP w0.203: PC1069.2 74.88,57.64 PR1068.1
N60799810: length 24.4
  IN4 w0.203: v2(89.84,66.33) 89.28,65.77 86.16,65.77 85.88,65.49 84.84,65.49 84.4,65.06 84.4,61.91 83.87,61.38 81.43,61.38 81.1,61.05 81.1,59.27 78.05,56.22 78.05,55.3 77.09,54.34 v2(76.51,54.34)
  BOTTOM w0.203: v2(76.51,54.34) 76.4,54.24 PR1097.2 ; v2(89.84,66.33) 89.81,66.35 PH1009.1
N60799827: length 4
  TOP w0.127: PR1083.2 64.26,49.01
  TOP w0.203: 64.26,49.01 64.75,49.49 64.87,49.49 65.33,49.95 v3(65.99,49.95) 66.47,49.95 67.16,50.63 PU1000.1
N60799848: length 19.4
  TOP w0.127: v3(75.82,50.4) 75.44,50.78 v2(75.44,51.72)
  TOP w0.203: PR1064.1 74.73,52.23 PR1126.2 75.11,51.39 v2(75.44,51.72)
  IN3 w0.203: v2(75.44,51.72) 75.97,51.72 77.5,53.25 79.62,53.25 80.37,54 80.37,56.28 81.42,57.34 84,57.34 84.76,58.1 v2(84.76,60.21)
  BOTTOM w0.203: PH1008.2 v2(84.76,60.21)
N60799854: length 2.2
  BOTTOM w0.127: PR1123.1 v3(69.82,54.06)
  BOTTOM w0.203: PC1064.2 70.97,54.42 PR1123.1
N60799880: length 3.6
  TOP w0.127: v3(77.57,54.95) 77.57,54.57 76.18,53.17 PR1081.1
  TOP w0.203: PC1090.2 75.82,53.2 PR1081.1
N60799887: length 2
  TOP w0.127: v3(78.21,51.39) PC1096.1
  TOP w0.254: PR1096.2 77.06,52.26 PC1096.1
N60799908: length 2.2
  BOTTOM w0.127: PR1090.2 66.88,56.39 v3(66.06,57.21)
  BOTTOM w0.203: PR1090.2 66.88,55.36 PC1089.1
N60799928: length 2.2
  TOP w0.127: v3(69.52,60.41) PC1072.1 69.75,59.17 PR1073.2
N60799936: length 2.1
  TOP w0.127: PR1060.2 71.55,59.24 PC1134.1 v3(71.55,61.27)
N60799950: length 3.1
  TOP w0.203: PU1000.28 67.96,56.74 67.54,57.16 v3(67.54,57.24) PC1068.1 PR1075.1
N60799960: length 7.2
  TOP w0.127: PC1068.2 PR1092.1 67.54,60.35 68.02,60.84 69.78,60.84 70.01,61.07 70.01,61.62 v3(71.86,63.46)
N60799970: length 9.9
  IN1 w0.203: v2(73.18,59.42) 65.35,59.42 v2(65,59.78)
  BOTTOM w0.203: v2(73.18,59.42) 73.58,59.01 PH1006.1 ; PR1089.2 64.87,59.65 v2(65,59.78)
N60799989: length 6.9
  TOP w0.127: PR1124.2 61.86,52.4 60.76,52.4 v3(60.24,52.92)
  TOP w0.203: PR1124.2 62.87,52.41 64.87,52.41 65.02,52.56 PU1000.38
N60799994: length 7.1
  TOP w0.203: v2(65.48,54.24) 65.56,54.16 PU1000.34
  BOTTOM w0.127: PC1007.1 65.96,52.85 65.96,50.92 v3(65.71,50.67)
  BOTTOM w0.203: PR1080.1 66.02,53.68 65.63,53.3 PC1007.1 65.51,54.21 v2(65.48,54.24)
N60799995: length 6
  TOP w0.203: PU1000.33 66.41,54.56 65.82,54.56 65.53,54.85 v2(65.15,54.85)
  BOTTOM w0.127: v3(62.47,56.41) 62.48,56.41 62.34,56.27 62.34,55.51 62.61,55.23 63.14,55.23 63.48,55.57 PR1066.1
  BOTTOM w0.203: PR1066.1 63.6,55.71 PC1005.1 65.15,55.18 v2(65.15,54.85)
N60800026: length 12.4
  BOTTOM w0.203: PR1136.2 74.98,61.93 74.98,60.57 74.67,60.26 72.43,60.26 72.43,60.25 v3(70.98,60.25) 70.13,60.25 69.52,60.87 67.18,60.87 66.93,61.12 66.19,61.12 65.7,60.63 PR1091.1
N61074629: length 7.6
  TOP w0.127: Q72.2 197.13,45.97 197.13,44.59 196.85,44.3 194.29,44.3 RH127.2 194.18,45.47 v3(193.76,45.89)
N61450237: length 3.1
  TOP w0.127: R289.2 v3(204.35,31.05)
  TOP w0.305: R289.2 202.33,30.27 U48.8
N61547946: length 4.6
  TOP w0.127: v3(54.28,75.42) R2670.1
  TOP w0.508: QZ9.1 57.12,74.38 56.08,75.42 R2670.1
N61553916: length 5.2
  TOP w0.127: R2671.1 55.54,78.25 55.03,78.77 55.03,79.84 v3(54.27,80.6)
  TOP w0.508: R2671.1 56.37,78.25 56.55,78.43 UZ26.6
N62098363:
  vias: v3(202.04,39.19)
N63073614: length 2.3
  TOP w0.127: v3(56.03,67.22) 55.53,67.22 55.31,67.45 PR248.2 54.79,67.4 PQ216.5
N63073655: length 1.2
  TOP w0.127: PR251.2 51.54,71 51.72,70.82 PQ217.5
N63092271: length 6
  TOP w0.127: PR217.2 20.42,73.29 PQ209.2 v2(20.42,72.01)
  BOTTOM w0.127: v2(20.42,72.01) v3(20.42,68.41)
N63092515: length 4
  TOP w0.127: PQ209.5 20.42,71.33 22.1,73.01 v3(22.25,73.01) 22.25,73.87 PR220.2
N63216045: length 1
  TOP w0.127: QH8.6 6.25,7.75 R913.1
N63216077: length 7
  TOP w0.127: R912.1 6.52,8.59 6.64,8.72 6.64,9.29 6.82,9.47 9.42,9.47 10.07,10.12 v1(10.07,11.01) 10.07,11.2 9.8,11.47 9.05,11.47 QH9.3
N63216109: length 2.4
  TOP w0.127: QH9.6 6.88,10.17 R911.1 5.88,9.8 v1(5.88,10.5)
N63239426: length 2.1
  TOP w0.127: Q41.1 6.22,5.95 R910.1 v1(6.2,4.91)
N63254653: length 7.7
  TOP w0.127: v2(61.67,46.62) 62.38,47.33 62.38,47.68 62.92,48.22 PQ208.2 62.46,48.22 62.21,48.47 62.21,49.82 PR218.1 61.58,50.44 61.07,50.44 60.43,51.09 v1(60.43,51.27)
  BOTTOM w0.127: v2(61.67,46.62) 62.13,47.08 PR283.1
N63877984: length 4.3
  TOP w0.127: PR229.1 59.39,48.88 59.39,48.13 59.13,47.88 v1(59.13,47.61) 59.17,47.57 PR282.1 60.22,47.57 60.87,48.22 PQ208.5
N64008725: length 3.1
  TOP w0.127: v3(157.68,40.14) 158.98,40.14 R78.2 159.23,39.89 QE13.5 QE13.6
N64008885: length 2.5
  TOP w0.127: 159.88,37.23 QE13.3 ; 159.88,37.23 159.88,37.24 160.3,37.65 v3(161.06,37.65) ; 159.88,37.23 159.88,36.18 R79.2
N64546397: length 6.8
  TOP w0.127: PR284.2 59.54,60.99 59.54,61.46 58.78,62.23 PQ215.5 58.78,62.76 59.91,63.89 59.91,64.72 58.96,65.67 v3(58.78,65.67)
N64546409: length 67.4
  TOP w0.127: v2(99.59,75.51) 99.37,75.29 PD206.2
  IN2 w0.089: v2(84.98,75.08) 85.01,75.04 87.06,75.04 88.49,76.47 91.4,76.47 92.74,77.81 98.97,77.81 99.59,77.19 v2(99.59,75.51)
  IN3 w0.089: v2(52.73,66.37) 52.39,66.37 52.02,66.73 52.02,69.36 53.83,71.17 53.83,74.36 57.96,78.49 61.87,78.49 62.34,78.02 62.85,78.02 63.36,78.53 68.59,78.53 70.74,76.37 79.05,76.37 80.1,75.32 83.27,75.32 83.9,74.69 84.59,74.69 v2(84.98,75.08)
  BOTTOM w0.127: v2(52.73,66.37) 52.73,66.68 v1(53.4,67.36) PR291.2 55,66.8 55,66.16 PR285.1
N64570632: length 13.7
  TOP w0.127: v2(56.86,68.49) 56.76,68.58 55.76,68.58 55.47,68.87 55.32,68.87 55.04,69.15 54.46,69.15 53.88,68.57 PQ216.6 53.33,68.05 53.04,68.33 v1(53.04,69.12) ; v2(58.36,63.09) 58.13,62.86 PQ215.4 58.13,62.03 PR286.2
  IN1 w0.081: v2(56.86,68.49) 56.92,68.42 56.92,65.01 58.36,63.57 v2(58.36,63.09)
N64571386: length 9.1
  TOP w0.127: PR247.1 51.51,69.38 51.51,69.2 52.49,68.22 52.49,67.82 52.07,67.4 PQ216.2 52.21,67.17 52.91,67.17 53.34,66.74 53.34,65.45 v2(53.21,65.32)
  BOTTOM w0.127: v2(53.21,65.32) 53.21,65.57 v1(53.45,65.81) 53.73,65.81 53.86,65.68 53.86,65.27 PR285.2
N64571512: length 24.8
  TOP w0.127: PR286.1 57.71,61.53 57.71,62.56 57.57,62.7 v2(57.57,62.76) 57.57,63.41 58.13,63.96 PQ215.3 ; v1(55.04,74.04) 55.22,74.21 v2(55.22,74.57)
  IN4 w0.081: v2(57.57,62.76) 57.57,63.92 56.95,64.54 56.95,67.58 57.28,67.9 57.28,68.94 56.79,69.43 56.79,71.81 56.44,72.17 56.44,73.35 v2(55.22,74.57)
  BOTTOM w0.127: v2(55.22,74.57) 55.22,77.24 54.71,77.75 54.2,77.75 51.47,80.48 PR243.2
N64625473: length 19.7
  TOP w0.254: PQ218.3 88.43,67.25 88.68,67.25 89.4,67.97 89.4,68.58 89.23,68.74 89.23,69.85 PD203.1 89.08,70.32 88.49,69.73 85.95,69.73 PR258.1 85.83,69.81 85.02,69 83.67,69 v3(83.13,69.54) 82.71,69.54 81.46,70.79 81.46,71.97 PR264.2 PR268.1 PC211.1 85.23,73.96 PU201.5
N64625477: length 21.2
  TOP w0.127: PD203.2 86.28,70.32 PR258.2 PC212.1 ; PC212.1 84.89,70.77 84.43,70.32 82.67,70.32 81.94,71.04 v2(81.94,71.46) ; PC212.1 85.46,71.29 87.23,71.29 87.56,71.63 87.56,72.35 87.25,72.66 85.61,72.66 PU201.7 ; PR265.1 86.59,68.72 PR252.2 85.7,67.9 85.07,68.54 83.17,68.54 80.98,70.73 v2(80.98,71.46)
  IN1 w0.081: v2(80.98,71.46) v2(81.94,71.46)
N64625485: length 3.2
  TOP w0.127: v3(87.67,66.58) 87.48,66.77 PC213.1 ; PC213.1 87.55,67.9 88.43,67.9 PQ218.2 ; PC213.1 PR265.2
N64625491: length 2.3
  TOP w0.127: v3(91.34,66.63) PR274.1 90.33,67.9 PQ218.5
N64625687: length 6.9
  TOP w0.127: v3(85.46,75.37) 86.48,74.35 86.48,73.55 86.23,73.31 85.61,73.31 ; PR254.2 83.08,70.93 PR269.1 84.38,72.3 85.39,73.31 85.61,73.31 ; 85.61,73.31 PU201.6
N64925547: length 0.6
  TOP w0.356: CC125.1 R9.2
N64926554: length 0.6
  TOP w0.127: R10.2 CC225.1
N65247919:
  vias: v1(36.09,36.42)
N65247927: length 2.8
  TOP w0.127: R80.2 32.3,33.92 v1(31.85,33.47)
  TOP w0.254: R80.2 33.1,33.61 33.86,33.61 QE14.3
N119009545: length 2
  TOP w0.127: PQ209.6 21.07,70.56 21.13,70.49 PR212.2 v3(22.17,70.06)
N119009632: length 1.7
  TOP w0.254: v3(31.03,75.37) 31.03,75.08 v2(31.34,74.76)
  TOP w0.508: v2(31.34,74.76) 31.27,74.68 PR209.1
N119967293: length 11.6
  TOP w0.127: v2(51.11,67.12) 51.48,66.74 51.98,66.74 PQ216.3 ; PR244.2 45.62,71.38 46.05,70.95 46.74,70.95 47.23,71.44 v2(47.45,71.44)
  BOTTOM w0.127: v2(47.45,71.44) 47.45,70.77 v2(51.11,67.12)
N119982384: length 2.4
  BOTTOM w0.127: v1(60.55,62.76) 60.81,62.51 PR214.2 60.53,61.69 60.04,61.21 PU200.6
N122715521: length 2.6
  TOP w0.127: PQ209.3 19.42,72.92 PR211.2 18.58,72.08 v3(18.58,71.07)
N122716790: length 3.3
  TOP w0.127: PR242.2 56.05,65.25 v2(56.05,65.36)
  BOTTOM w0.127: PQ224.1 56.39,66.92 56.39,66.05 56.05,65.71 v2(56.05,65.36)
N122717029: length 23.8
  TOP w0.127: PQ213.1 54.38,60.64 v2(54.23,60.49)
  IN4 w0.081: v2(54.23,60.49) 54.61,60.87 54.61,66.32 54,66.93 54,69.48 53.48,70 53.48,73.27 v2(54.65,74.44)
  BOTTOM w0.127: v2(54.65,74.44) 54.65,77.17 54.33,77.49 54.1,77.49 53.19,78.4 v3(51.68,78.4) 51.36,78.72 PR239.1
N122717329: length 8.5
  TOP w0.127: v3(52.82,73.03) 53.76,72.09 PQ217.3 53.38,71.47 53.09,71.18 53.09,70.6 52.05,69.55 52.05,69.02 52.76,68.31 52.76,67.69 53.7,66.75 PQ216.4
N122717720: length 3.7
  TOP w0.127: PQ217.6 51.62,70.17 51.24,70.56 50.33,70.56 49.93,70.96 v2(49.93,71.22) 49.24,71.92 PR245.2
N122719403: length 21.5
  TOP w0.127: PQ215.6 59.43,62.95 60.25,63.77 60.25,65.06 60,65.31 60,66.47 59.77,66.7 59.19,66.7 58.77,67.12 58.77,68.17 58.21,68.72 57.71,68.72 56.77,69.66 56.77,71.63 56.5,71.9 56.17,71.9 55.41,72.67 v1(54.84,72.67) 54.7,72.81 54.53,72.81 53.32,74.02 53.32,75.33 51.98,76.67 v2(51.98,76.98)
  BOTTOM w0.127: v2(51.98,76.98) 51.98,76.92 51.41,76.35 PR241.2
N122723381: length 5.1
  TOP w0.127: PU201.2 89.85,72.66 91.27,72.66 PR230.1 PR224.2 91.83,74.11 92.75,74.11 93.27,74.63 v3(93.59,74.63)
N122728402: length 3.9
  TOP w0.127: v1(62.08,46.14) 62.96,47.02 PQ208.1 63.27,47.57 63.48,47.77 63.48,48.73 63.33,48.87 PQ208.3
N122733349: length 5.8
  TOP w0.127: PU203.5 62.42,16.51 62.42,15.34 PC214.1 63.2,15.33 63.45,15.58 PR262.1 PR270.1 PR266.2 63.65,13.42 v3(63.09,13.42)
N122733365: length 7
  TOP w0.127: PR259.2 PR271.1 63.3,17.36 63.1,17.16 PU203.6 61.81,17.16 60.99,16.34 v3(60.99,13.67)
N122733968: length 2.4
  TOP w0.127: v3(61.06,22.44) 61.7,22.44 62,22.74 PR257.2 62.44,22.63 PQ219.6
N122734452: length 4.9
  TOP w0.127: PU203.2 57.91,17.81 57.58,17.81 57.25,17.48 PR273.1 PR260.2 56.31,17.99 55.35,17.99 v3(54.98,17.63)
N122772225: length 3.3
  TOP w0.127: PQ207.6 34.66,72.97 33.84,73.79 v2(33.84,73.79) 33.75,73.87 PR209.2
N122777610: length 5.6
  TOP w0.127: PQ217.2 53.81,70.77 PR250.2 54.71,71.13 54.33,71.51 54.33,72.28 52.65,73.97 v3(52.65,74.5)
N122777613: length 5.5
  TOP w0.127: PR249.2 54.97,65.79 56.39,65.79 56.71,65.48 v2(57.35,65.48)
  BOTTOM w0.127: v1(57.8,66.96) 56.73,65.9 PQ224.2 57.2,65.33 v2(57.35,65.48)
N123360127: length 4.3
  TOP w0.127: RT12.1 39.09,67 39.52,66.57 v2(39.52,66.6) ; UT1.H19 v2(40.23,64.09)
  IN4 w0.081: v2(40.23,64.09) 40.23,64.1 40.23,64.27 39.62,64.88 39.62,66.47 39.52,66.57 v2(39.52,66.6)
N123360144: length 5.2
  TOP w0.127: v2(48.57,65.74) 48.95,66.13 RT5.1 ; v2(46.08,63.44) 46.4,63.12 UT1.Y18
  BOTTOM w0.127: v2(48.57,65.74) 48.57,65.34 48.03,64.8 47.8,64.8 46.44,63.44 v2(46.08,63.44)
N123760602: length 14.9
  TOP w0.127: PQ206.3 54.82,57.87 55.16,58.2 55.46,58.2 55.75,58.49 56.16,58.49 v2(56.34,58.67)
  IN1 w0.081: v2(60.7,65.56) 59.38,64.23 59.38,63.38 56.34,60.34 v2(56.34,58.67)
  BOTTOM w0.127: PR240.1 63.14,65.49 PU202.4 61.95,65.57 PR246.1 60.95,65.56 v2(60.7,65.56)
N123959194: length 4.8
  BOTTOM w0.127: v1(56.54,57.54) 56.44,57.64 56.44,58.17 57.02,58.76 PR225.1 57.51,58.84 57.98,59.31 57.98,60.17 58.51,60.7 58.51,61.2 PU200.4

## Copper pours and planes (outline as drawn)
+0.6VS on TOP (solid shape): 163.81,28.66 163.81,27.14 163.55,26.88 163.17,26.88 163.04,27.01 163.04,28.66 163.17,28.79 163.68,28.79
+0.6VS on TOP: 94.84,18.71 94.84,19.39 95.1,19.64 103.23,19.64 103.48,19.39 103.48,19.14 103.73,18.88 106.4,18.88 106.66,19.14 106.66,19.39 106.78,19.52 114.53,19.52 114.66,19.39 114.66,18.88 114.78,18.75 116.56,18.75 116.69,18.88 116.69,19.39 116.82,19.52 144.76,19.52 144.88,19.39 144.88,18.88 145.14,18.63 145.52,18.63 145.9,18.25 146.79,18.25 147.04,18.5 147.04,19.26 147.3,19.52 159.61,19.52 159.87,19.77 160,19.77 160.12,19.64 160.12,19.49 160.44,19.17 160.44,18.18 159.61,17.36 96.2,17.36
+0.6VSP on TOP (solid shape): 167.29,30.92 168.23,30.92 168.3,30.85 168.3,30.29 168.23,30.22 167.4,30.22 167.23,30.06 167.23,29.17 165.2,27.14 164.06,27.14 163.98,27.22 163.98,27.51 164.54,27.51 164.54,28.02 163.98,28.02 163.98,28.55 164.24,28.81 165.69,28.81 166.32,29.43 166.32,31.25 166.33,31.27 166.86,31.27 166.86,31.27 166.94,31.27
+1.0V_CLK on TOP: 142.47,70.82 142.47,66.63 141.2,65.36 140.95,65.36 140.18,66.13 140.18,66.51 140.44,66.76 141.33,66.76 141.83,67.27 141.83,70.32 142.34,70.82
+1.0V_CLK on IN2: 140.31,67.14 141.71,67.14 141.96,66.89 141.96,66.13 141.33,65.49 140.31,65.49 140.18,65.62 140.18,67.01
+1.0V_MPHYAON on IN2: 142.22,67.01 148.4,67.01 148.81,67.42 152.34,67.42 152.63,67.13 152.63,66.29 152.24,65.9 150.46,65.9 150.1,66.25 144.63,66.25 144.5,66.13 142.22,66.13 142.09,66.25 142.09,66.89
+1.0V_MPHYGT on TOP: 151.74,80.48 151.87,80.35 151.87,78.19 151.74,78.06 150.09,78.06 148.82,76.79 148.82,76.29 148.57,76.03 146.79,76.03 146.28,75.52 144.88,75.52 144.63,75.78 144.63,77.3 144.76,77.43 146.03,77.43 146.28,77.68 146.28,80.22 146.53,80.48
+1.0V_MPHYGT on TOP: 145.26,65.36 145.26,64.47 144.63,63.84 143.1,63.84 142.72,64.22 142.72,65.49 143.1,65.87 144.76,65.87
+1.0V_MPHYGT on IN1: 148.82,78.32 146.66,78.32 146.28,77.94 146.28,76.41 147.55,75.14 147.55,70.57 148.95,69.17 148.95,67.52 148.44,67.01 143.23,67.01 142.22,66 142.22,62.06 142.34,61.93 145.9,61.93 146.66,62.7 150.34,62.7 151.36,63.71 151.36,67.14 154.03,69.81 154.03,73.11
+1.0V_MPHYGT on VCC: 143.08,63.33 141.96,64.45 141.96,66.4 142.85,67.29 142.85,71.48 144.12,72.75 144.12,75.8 146.51,78.19 148.08,78.19 148.44,77.83 148.44,77.41 145.64,74.61 145.64,71.31 144.25,69.91 144.25,67.8 145.01,67.04 145.01,63.94 144.4,63.33
+1.0V_PRIM_CORE on TOP: 140.82,77.3 142.47,77.3 142.6,77.17 142.6,75.4 143.1,74.89 143.1,73.62 142.85,73.36 142.34,73.36 141.96,73.75 141.96,74.13 140.69,75.4 140.69,77.17
+1.0V_PRIM_CORE on TOP: 191.87,71.33 192.63,71.33 193.02,70.95 193.02,70.57 192.76,70.32 192.51,70.32 192.38,70.19 192.38,68.79 192.51,68.67 192.89,68.67 193.02,68.54 193.02,67.78 192.89,67.65 192.09,67.65 191.62,68.12 191.62,71.08
+1.0V_PRIM_CORE on BOTTOM: 191.66,71.11 192.3,71.11 192.52,70.89 192.52,70.03 193.17,69.39 193.17,67.87 192.84,67.54 191.93,67.54 191.62,67.86 191.62,71.06
+1.0V_PRIM_CORE on IN1: 140.18,63.59 141.2,63.59 141.45,63.33 141.45,62.44 142.47,61.43 142.47,60.03 141.96,59.52 140.82,59.52 139.93,60.41 139.93,63.33
+1.0V_PRIM_CORE on IN3: 141.71,74.89 142.85,74.89 143.23,74.51 143.23,72.6 143.87,71.97 143.87,67.9 141.33,65.36 141.33,62.82 140.95,62.44 138.41,62.44 138.15,62.19 138.15,61.55 138.41,61.3 140.44,61.3 141.2,60.54 141.58,60.54 141.96,60.16 141.96,58.89 141.71,58.63 135.99,58.63 135.36,59.27 135.36,69.94 136.18,70.76 139.48,70.76 141.45,72.73 141.45,74.63
+1.0V_PRIM_CORE on VCC: 140.8,59.52 139.8,60.52 139.8,66.91 140.44,67.54 140.44,80.73 192.89,80.73 192.89,67.65 181.56,67.65 173.82,75.4 161.75,75.4 158.7,78.44 154.68,78.44 151.99,75.76 151.99,62.42 149.48,59.9 142.36,59.9 141.98,59.52 ; 1 cut-out
+1.0V_PRIM_COREP on TOP: 198.35,75.52 198.87,75.52 198.92,75.47 198.92,75.34 198.85,75.27 197.71,75.27 196.7,74.25 194.92,74.25 194.41,73.75 194.41,71.59 194.67,71.33 194.67,68.41 194.54,68.28 193.4,68.28 193.27,68.41 193.27,75.95 193.73,76.41 197.46,76.41
+1.0V_VCCST on TOP: 152.25,73.75 151.99,73.49 150.98,73.49 150.72,73.75 150.72,75.52 150.75,75.55 150.75,76.59 150.93,76.77 151.92,76.77 152.25,76.44
+1.0V_VCCST on IN4: 125.45,70.57 124.69,70.57 124.56,70.44 124.56,68.41 125.2,67.78 125.83,67.78 125.83,70.19
+1.0V_VCCSTG on TOP: 160.5,65.87 160.25,66.13 160.25,69.43 160.38,69.55 161.39,69.55 161.52,69.43 161.52,68.02 161.34,67.84 161.34,67.12 161.11,66.89 161.11,65.97 161.01,65.87
+1.0V_VCCSTG on BOTTOM: 119.74,78.7 119.99,78.44 119.99,77.3 119.74,77.05 119.1,77.05 118.72,77.43 117.83,77.43 117.2,78.06 117.2,78.44 117.45,78.7
+1.0VA on TOP: 156.82,76.41 156.82,75.52 156.95,75.4 158.73,75.4 158.98,75.14 158.98,74.13 158.85,74 155.04,74 154.92,74.13 154.92,77.23 154.2,77.94 154.2,77.94 153.75,78.39 152.57,78.39 152.38,78.58 152.38,79.33 152.53,79.48 154.44,79.48 154.92,79.95 154.92,80.48 155.04,80.6 156.57,80.6 157.96,79.21 158.73,79.21 158.98,78.95 158.98,77.56 158.34,76.92 157.58,76.92 157.2,76.54 156.95,76.54
+1.0VA on TOP: 164.06,68.03 165.58,68.03 165.71,67.9 165.71,67.01 165.96,66.76 166.35,66.76 166.73,66.38 167.87,66.38 168,66.25 168,65.74 167.36,65.11 166.85,65.11 166.47,65.49 164.06,65.49 163.93,65.62 163.93,67.9
+1.0VA on BOTTOM: 190.67,54.19 190.48,54.38 190.48,56.98 190.73,57.24 192,57.24 192,57.23 192.13,57.23 192.2,57.17 192.2,56.78 191.63,56.78 191.63,56.22 192.2,56.22 192.2,55.97 191.65,55.97 191.65,55.41 192.2,55.41 192.2,55.13 192.2,55.13 192.2,54.33 192.06,54.19
+1.0VA on VCC: 169.88,53.81 169.65,54.04 169.65,63.33 152.5,63.33 152.5,75.54 154.89,77.94 158.49,77.94 161.54,74.89 173.61,74.89 181.35,67.14 192.89,67.14 192.89,55.31 191.39,53.81
+1.0VA on IN4: 140.18,57.11 140.18,56.22 140.06,56.09 138.91,56.09 138.53,56.47 136.75,56.47 136.5,56.73 136.5,61.43 138.28,63.2 141.07,63.2 141.96,64.09 145.01,64.09 146.66,62.44 146.66,59.9 145.9,59.14 140.06,59.14 139.29,58.38 139.29,58
+1.0VAP on BOTTOM (solid shape): 197.21,56.73 200.13,56.73 200.23,56.63 200.23,53.91 200,53.68 197.46,53.68 196.19,54.95 192.42,54.95 192.35,55.02 192.35,57.13 192.45,57.24 193.4,57.24 194.03,57.87 196.06,57.87
+1.0VAP on TOP: 193.9,57.74 193.9,55.2 194.16,54.95 196.19,54.95 196.44,54.7 196.83,54.7 196.95,54.82 196.95,56.98 196.06,57.87 194.03,57.87
+1.0VS_VCCIO on TOP: 170.16,55.97 170.54,55.58 170.54,54.38 170.39,54.24 169.96,54.24 169.95,54.25 169.95,54.78 168.59,54.78 168.59,54.24 168.54,54.19 167.62,54.19 166.35,55.46 166.35,55.69 166.4,55.74 167.11,55.74 167.34,55.97
+1.0VS_VCCIO on TOP: 137.7,57.64 137.7,56.79 137.64,56.73 136.88,56.73 136.23,56.08 135.98,56.08 135.33,55.43 134.2,55.43 134.09,55.54 134.09,56.35 134.21,56.47 134.6,56.47 134.72,56.6 134.72,57.08 134.79,57.14 134.79,57.47 134.72,57.54 134.72,57.54 134.72,58.12 134.6,58.25 133.96,58.25 133.83,58.38 133.83,58.89 133.96,59.01 137.14,59.01 137.39,58.76 137.39,57.96
+1.0VS_VCCIO on BOTTOM: 134.67,56.55 134.67,57.06 135.08,57.46 135.61,57.46 135.89,57.18 135.89,55.94 135.38,55.43 134.26,55.43 134.14,55.56 134.14,56.02
+1.0VS_VCCIO on IN1: 125.58,57.74 125.83,58 128.04,58 129.06,56.98 133.6,56.98 134.75,58.12 135.61,58.12 135.87,57.87 135.87,56.09 135.13,55.36 132.75,55.36 132.24,55.87 129.57,55.87 129.07,55.36 126.06,55.36 125.58,55.84
+1.0VS_VCCIO on IN3: 127.1,58.12 127.99,58.12 128.25,57.87 129.13,57.87 130.53,56.47 134.6,56.47 134.98,56.85 134.98,57.36 135.23,57.62 136.5,57.62 136.75,57.36 136.75,54.95 136.5,54.7 129.52,54.7 128.63,55.58 128.63,56.09 126.98,57.74 126.98,58
+1.0VS_VCCIO on VCC: 146.26,50.12 145.11,51.27 143.46,51.27 142.34,52.39 142.34,52.51 142.28,52.58 142.28,54.65 141.41,55.52 138.58,55.52 137.95,54.89 128.83,54.89 128.56,55.16 128.56,55.92 127.82,56.66 127.23,56.66 127.23,58.12 128.39,58.12 130.17,56.35 133.68,56.35 135.1,57.76 135.1,62.82 139.29,62.82 139.29,60.3 140.59,59.01 142.19,59.01 142.57,59.39 149.69,59.39 152.5,62.21 152.5,62.82 169.14,62.82 169.14,52.51 166.75,50.12
+1.0VS_VCCIO on IN4: 127.1,58.89 127.1,56.98 128.75,55.33 135.23,55.33 135.74,55.84 135.74,57.87 133.96,59.65 128.5,59.65 128.12,60.03 127.74,60.03 127.74,59.52
+1.0VS_VCCIOP on TOP: 168.12,51.77 167.74,51.39 167.49,51.39 167.36,51.27 167.36,50.25 167.49,50.12 170.79,50.12 171.17,50.5 172.6,50.5 172.62,50.49 173.31,50.49 173.37,50.55 173.37,50.72 172.7,51.39 170.38,51.39 170.03,51.75 170.03,52.64 170.43,53.04 170.43,53.99 170.33,54.1 168.26,54.1 168.12,53.96
+1.2V_DDR on TOP (solid shape): 161.77,24.34 161.77,24.22 162.41,23.58 162.41,22.01 161.91,22.01 161.91,21.27 162.41,21.27 162.41,20.82 161.92,20.82 161.92,20.05 162.41,20.05 162.41,18.75 162.15,18.5 160.88,18.5 160.63,18.75 160.63,24.09 161.01,24.47 161.65,24.47
+1.2V_DDR on TOP (solid shape): outline of 92 points within 143.36,25.74 151.34,30.18
+1.2V_DDR on TOP (solid shape): outline of 1634 points within 106.27,22.18 149.2,39.2
+1.2V_DDR on BOTTOM (solid shape): outline of 203 points within 147.17,31.71 150.72,34.63
+1.2V_DDR on IN1 (solid shape): outline of 1109 points within 130.91,21.61 144.12,31.45
+1.2V_DDR on IN2 (solid shape): 144.5,32.34 144.5,30.82 144.25,30.57 144.25,30.18 144.28,30.02 144.37,29.89 144.37,29.68 144.25,29.55 144,29.55 143.92,29.63 142.77,29.63 142.22,30.18 142.22,30.83 142.24,30.85 142.31,30.87 142.63,30.75 142.88,30.85 142.95,30.88 143.02,30.85 143.3,30.75 143.55,30.88 143.63,30.92 143.71,30.88 144.34,31.12 143.7,31.34 143.63,31.3 143.55,31.33 143.5,31.38 143.45,31.41 143.4,31.5 143.63,31.9 143.4,32.3 143.45,32.39 143.61,32.58 143.61,32.84 143.62,32.93 143.7,32.98 143.87,32.98
+1.2V_DDR on IN2 (solid shape): 141.54,33.53 141.57,33.44 141.51,33.36 141.43,32.77 142,32.94 142.02,32.98 142.85,32.98 142.94,32.93 142.95,32.84 142.94,32.58 143.1,32.39 143.16,32.3 143.1,32.21 143.06,32.19 143.02,32.15 142.95,32.12 142.88,32.15 142.34,32.12 142.45,31.59 142.51,31.5 142.45,31.41 142.41,31.39 142.38,31.35 142.31,31.33 142.23,31.35 142.22,31.37 142.22,31.58 141.83,31.96 141.03,31.96 141.02,32 140.89,32.19 140.67,32.26 140.64,32.26 140.5,32.41 140.47,32.5 140.54,32.58 140.77,32.95 140.45,33.27 140.37,33.33 140.39,33.44 140.56,33.61 141.45,33.61
+1.2V_DDR on IN4 (solid shape): outline of 2689 points within 138.28,21.04 162.28,29.55
+1.2V_DDR on TOP: 152.5,26.5 152.76,26.5 152.88,26.63 153.14,26.63 153.26,26.5 154.03,26.5 154.15,26.63 154.41,26.63 154.66,26.37 154.66,26.12 154.79,25.99 155.04,25.99 155.42,26.37 155.42,27.01 155.04,27.39 155.04,27.9 155.3,28.15 155.3,28.79 154.66,29.42 154.66,29.55 154.41,29.8 154.41,30.95 155.42,31.96 155.42,33.23 155.93,33.74 156.31,33.74 156.57,33.49 156.57,32.72 156.31,32.47 156.31,32.22 156.44,32.09 156.69,32.09 156.95,32.34 156.95,32.98 157.2,33.23 157.46,33.23 157.58,33.11 157.58,32.22 157.71,32.09 157.96,32.09 158.09,32.22 158.09,33.23 158.34,33.49 158.34,35.39 157.96,35.77 157.96,38.5 157.65,38.82 156.82,38.82 156.69,38.69 155.68,38.69 155.55,38.57 155.55,37.8 156.06,37.3 156.06,35.01 154.92,33.87 153.9,33.87 152.5,32.47 152.5,32.22 153.01,31.71 153.01,31.45 153.52,30.95 153.52,30.44 153.01,29.93 153.01,27.52 152.38,26.88 152.38,26.63
+1.2V_DDR on TOP: 97,28.41 97.51,28.41 97.89,28.03 98.78,28.03 99.04,27.77 101.07,27.77 101.19,27.64 101.19,27.39 101.07,27.26 101.07,27.01 101.19,26.88 101.19,26.63 101.07,26.5 101.07,26.12 101.45,25.74 101.7,25.74 102.21,26.25 102.21,26.37 101.96,26.63 101.96,26.76 102.21,27.01 102.21,27.14 101.96,27.39 101.96,27.64 102.46,28.15 102.46,29.17 102.34,29.3 102.08,29.3 101.58,28.79 101.58,28.41 101.45,28.28 100.18,28.28 99.8,28.66 99.8,29.17 99.67,29.3 99.67,29.68 99.8,29.8 99.8,29.93 99.67,30.06 98.65,30.06 98.27,29.68 97,29.68 96.88,29.55 96.88,28.53
+1.2V_DDR on TOP: 124.44,47.33 124.69,47.58 124.69,48.35 125.07,48.73 127.23,48.73 127.48,48.47 127.48,47.08 127.61,46.95 128.37,46.95 128.5,47.08 128.5,47.96 128.88,48.35 129.52,48.35 129.9,47.96 137.01,47.96 137.64,48.6 139.55,48.6 139.68,48.73 139.68,49.11 139.55,49.23 139.29,49.23 139.04,49.49 139.04,49.74 138.66,50.12 133.71,50.12 133.45,50.38 133.45,52.03 133.71,52.28 138.28,52.28 138.41,52.41 138.41,53.17 138.15,53.43 127.74,53.43 127.48,53.17 127.48,52.41 127.61,52.28 127.86,52.28 127.99,52.16 127.99,51.52 128.12,51.39 128.75,51.39 129.26,51.9 130.28,51.9 130.53,51.65 130.53,49.87 130.28,49.62 125.71,49.62 125.2,50.12 122.4,50.12 122.15,49.87 122.15,48.47 123.29,47.33
+1.2V_DDR on TOP: 164.19,49.11 164.31,48.98 164.31,47.96 164.57,47.71 165.2,47.71 165.33,47.58 166.09,47.58 166.35,47.33 166.35,46.31 166.22,46.19 164.57,46.19 164.19,46.57 162.66,46.57 162.54,46.69 162.54,48.98 162.66,49.11
+1.2V_DDR on BOTTOM: 154.92,26.63 157.58,26.63 159.49,24.72 160.76,24.72 161.39,25.36 161.39,31.58 160.38,32.6 155.68,32.6 155.42,32.85 155.42,34.38 155.68,34.63 161.14,34.63 162.92,32.85 162.92,19.01 162.66,18.75 161.27,18.75 160.63,19.39 156.69,19.39 156.31,19.77 156.31,22.31 154.66,23.96 154.66,26.37
+1.2V_DDR on BOTTOM: 122.02,35.07 133.39,35.07 133.96,34.5 133.96,33.49 132.56,32.09 132.56,31.52 132.31,31.26 131.99,31.26 131.67,31.58 130.02,31.58 129.9,31.45 129.32,31.45 129.13,31.64 126.85,31.64 126.4,31.2 125.58,31.2 124.31,32.47 124.31,33.55 123.74,34.12 122.02,34.12 121.77,34.38 121.77,34.82
+1.2V_DDR on BOTTOM: 106.91,37.17 111.23,37.17 111.61,36.79 111.61,32.09 111.1,31.58 106.91,31.58 106.53,31.96 106.53,33.61 107.16,34.25 107.16,34.88 106.4,35.65 106.4,36.66
+1.2V_DDR on IN1: 101.35,28.17 101.58,28.4 101.58,28.91 101.83,29.17 104.24,29.17 105.13,28.28 106.78,28.28 107.04,28.53 107.04,28.79 107.16,28.91 107.52,28.91 108.09,28.34 109.93,28.34 110.1,28.51 110.1,30.2 110.34,30.44 110.34,33.36 110.59,33.61 111.48,33.61 111.86,33.23 111.86,24.72 110.72,23.58 99.8,23.58 98.02,25.36 98.02,28.66 98.15,28.79 98.53,28.79 98.78,28.53 99.16,28.53 99.53,28.17
+1.2V_DDR on IN2: 153.39,30.57 153.71,30.57 154.53,29.74 154.53,29.23 154.79,28.98 155.11,28.98 155.23,28.85 155.23,28.6 155.04,28.41 154.41,28.41 154.34,28.34 154.34,27.64 154.53,27.45 154.53,26.95 154.41,26.82 154.03,26.82 153.9,26.95 153.9,28.09 153.33,28.66 153.33,30.5
+1.2V_DDR on IN2: outline of 580 points within 104.75,18.12 162.78,58.25
+1.2V_DDR on IN2: 120.94,27.52 121.26,27.52 121.51,27.26 121.51,27.01 121.01,26.5 121.01,24.22 121.77,23.45 121.77,22.95 121.64,22.82 121.01,22.82 119.36,24.47 119.36,25.87 119.1,26.12 119.1,27.26 119.61,27.77 119.61,29.68 119.74,29.8 120.88,29.8 121.01,29.68 121.01,28.47 120.82,28.28 120.82,27.64
+1.2V_DDR on IN2: 97.89,33.23 100.43,33.23 101.7,34.5 104.88,34.5 105.13,34.25 105.13,31.07 105.39,30.82 105.39,30.06 105.13,29.8 100.05,29.8 99.67,29.42 99.67,27.64 99.42,27.39 97.77,27.39 97.51,27.64 97.51,32.85
+1.2V_DDR on IN3: 102.46,37.55 98.91,33.99 98.91,31.07 98.65,30.82 98.15,30.82 97.89,31.07 97.89,35.01 100.94,38.06 100.94,41.36 100.43,41.87 100.43,47.08 100.81,47.46 102.08,47.46 102.46,47.08
+1.2V_DDRP on TOP (solid shape): 168.3,29.97 168.3,28.3 166.04,26.04 164.67,26.04 164.06,25.43 164.06,23.88 164.16,23.78 164.16,23.58 162.92,23.58 162.79,23.71 162.79,25.61 164.11,26.93 165.33,26.93 167.49,29.09 167.49,29.93 167.58,30.02 168.24,30.02
+1.2V_DDRP on TOP: 162.79,23.83 170.66,23.83 171.3,23.2 171.3,21.17 170.66,20.53 168.76,20.53 167.74,19.52 162.64,19.52 162.61,19.54 162.61,23.66
+1.8VA on TOP: 167.62,70.7 168.63,70.7 168.76,70.57 168.76,69.55 168.63,69.43 167.62,69.43 167.49,69.55 167.49,70.57
+1.8VA on TOP: 32.36,43.27 32.49,43.14 32.49,42.63 32.36,42.5 31.34,42.5 31.22,42.38 29.54,42.38 29.39,42.53 29.39,43.14 29.52,43.27
+1.8VAP on TOP: 168.89,72.73 169.27,72.35 169.27,71.33 168.76,70.82 167.49,70.82 167.23,71.08 167.23,76.79 167.49,77.05 167.49,77.61 167.84,77.96 168.76,77.96 168.89,77.83
+1.8VS_AUDIO on TOP: 31.09,39.84 31.22,39.71 31.22,38.41 30.94,38.13 29.03,38.13 28.93,38.24 28.93,38.89 28.83,38.98 28.3,38.98 28.16,39.13 28.16,39.65 28.35,39.84
+1.8VU on TOP (solid shape): 161.01,42.5 161.01,41.11 160.76,40.85 160.19,40.85 160.12,40.92 160.12,42.5 160.25,42.63 160.88,42.63
+1.8VU on BOTTOM (solid shape): outline of 6402 points within 98.02,24.72 160.93,31.71
+1.8VU on TOP: 160,28.53 160,28.41 159.36,27.77 159.11,27.77 158.6,27.26 158.6,27.01 158.85,26.76 158.85,26.63 158.6,26.37 158.6,26.12 158.98,25.74 158.98,24.98 159.11,24.85 159.49,24.85 159.87,25.23 159.87,25.99 159.61,26.25 159.61,26.88 160.25,27.52 162.03,27.52 162.15,27.64 162.15,28.28 162.03,28.41 161.01,28.41 160.76,28.66 160.12,28.66
+1.8VUP on TOP: 161.77,45.04 163.81,45.04 163.93,44.92 163.93,43.01 163.81,42.88 163.04,42.88 162.79,42.63 162.79,41.11 162.41,40.73 161.77,40.73 161.27,41.23 161.27,41.61 161.65,41.61 161.77,41.74 161.77,42.25 161.65,42.38 161.27,42.38 161.27,42.76 161.52,43.01 161.52,44.79
+3.3VDX_SSD on TOP: 175.87,41.87 176.44,41.87 178.03,40.28 178.03,39.33 178.28,39.07 178.28,37.8 178.03,37.55 178.03,36.03 177.9,35.9 177.14,35.9 176.89,36.15 175.87,36.15 175.74,36.28 175.74,36.66 175.87,36.79 176.51,36.79 176.63,36.92 176.63,37.8 176.89,38.06 176.89,38.57 176.63,38.82 176,38.82 175.74,39.07 175.74,41.74
+3.3VDX_SSD on TOP: 176.89,31.84 176.89,28.53 177.14,28.28 177.14,23.58 177.01,23.45 174.98,23.45 174.85,23.58 174.85,31.96 174.98,32.09 176.63,32.09
+3.3VDX_SSD on BOTTOM: 176.51,41.74 178.16,40.09 178.16,36.15 177.9,35.9 176.76,35.9 176.51,36.15 176.51,37.55 176.25,37.8 173.58,37.8 173.08,38.31 173.08,40.47 174.35,41.74
+3.3VDX_SSD on BOTTOM: 177.49,27.7 177.78,27.41 177.78,23.58 177.52,23.33 173.58,23.33 173.36,23.55 173.36,26.81 174.25,27.7
+3.3VDX_SSD on IN2: 178.92,37.93 179.3,37.55 179.3,26.37 178.41,25.49 178.41,24.22 177.39,23.2 176.25,23.2 175.62,23.83 175.62,36.92 176.63,37.93
+3V_LDO on BOTTOM: 60.39,65.91 61.87,65.91 62.71,66.76 62.71,66.89 62.97,67.14 63.48,67.14 63.73,67.4 63.73,67.65 63.6,67.78 62.71,67.78 62.59,67.65 62.59,67.14 61.7,66.25 61.15,66.25 60.9,66.51 60.55,66.51 60.3,66.25 60.3,66
+3V_PCH on TOP: 181.26,25.99 181.19,26.07 181.19,26.34 181.33,26.48 181.33,27.26 181.2,27.39 180.57,27.39 180.44,27.52 180.44,28.66 180.57,28.79 182.09,28.79 182.35,28.53 182.35,26.12 182.22,25.99
+3V_PCH on TOP: 180.32,45.39 180.23,45.3 179.3,45.3 178.16,44.15 175.87,44.15 175.24,43.52 173.97,43.52 173.84,43.65 173.84,44.03 175.11,45.3 177.14,45.3 179.13,47.29 180.09,47.29 180.2,47.18 180.2,46.91 180.32,46.79
+3V_PCH on IN1: 156.06,50.5 155.68,50.12 155.68,47.2 155.8,47.08 157.33,47.08 157.58,47.33 157.58,50.25 157.33,50.5
+3V_PCH on IN1: 138.91,58.51 139.42,58.51 139.8,58.12 146.41,58.12 147.04,57.49 147.04,56.6 146.79,56.35 145.01,56.35 144.63,55.97 138.91,55.97 138.66,56.22 138.66,58.25
+3V_PCH on IN2: 147.8,62.95 149.71,62.95 151.84,60.82 151.84,58.56 152.22,58.17 152.22,56.14 152.88,55.48 152.88,54.06 152.76,53.93 151.99,53.93 146.41,59.52 140.31,59.52 139.42,58.63 139.42,58.12 139.17,57.87 138.41,57.87 137.52,58.76 137.52,63.71 138.53,64.73 146.03,64.73
+3V_PCH on IN3: 157.66,62.96 157.62,62.91 156.66,62.91 155.21,64.37 154.63,64.37 154.35,64.65 154.35,65.21 156.63,67.5 157.8,67.5 158.24,67.94 158.24,68.93 159.39,70.08 159.94,70.08 160.1,69.93 160.1,69.39 159.11,68.39 159.11,67.42 158.27,66.58 157.22,66.58 156.82,66.18 156.82,64.19 157.66,63.35
+3V_PCH on IN3: 159.11,42.76 159.11,41.11 159.61,40.6 160.5,40.6 161.14,41.23 162.54,41.23 163.68,42.38 166.73,42.38 168,43.65 172.06,43.65 172.31,43.9 173.46,43.9 173.84,43.52 174.09,43.52 174.6,44.03 174.6,47.08 173.2,48.47 167.11,48.47 165.58,46.95 163.3,46.95
+3V_PCH on IN3: 182.35,26.12 182.22,25.99 178.54,25.99 176.89,27.64 176.89,32.72 177.78,33.61 177.78,35.01 179.3,36.53 179.93,36.53 182.6,39.2 182.6,43.14 178.87,46.87 178.87,47.2 179.13,47.47 180.68,47.47 183.87,44.28 183.87,37.3 182.09,35.52 180.82,35.52 180.19,34.88 179.55,34.88 179.3,34.63 179.3,33.99 179.68,33.61 182.22,33.61 182.35,33.49
+3V_PCH on IN4: 157.33,50.5 157.07,50.5 156.44,49.87 156.44,48.35 156.57,48.22 156.57,47.08 158.6,45.04 158.6,42.38 159.36,41.61 159.36,41.11 159.49,40.98 160.57,40.98 160.76,41.17 160.76,47.08
+3V_PCH on IN4: 148.06,77.94 152.76,77.94 153.01,77.68 153.01,77.17 152.76,76.92 148.06,76.92 147.8,77.17 147.8,77.68
+3V_PCH_DSW on IN2: 142.22,58.25 142.6,58.25 143.1,57.74 146.53,57.74 150.6,53.68 150.6,52.16 149.71,51.27 147.42,51.27 146.66,52.03 146.66,53.81 146.41,54.06 142.98,54.06 142.85,54.19 142.85,56.09 141.96,56.98 141.96,58
+3V_TBT on TOP: 37.95,56.5 37.88,56.5 37.84,56.47 36.54,56.47 36.17,56.09 36.17,55.76 36.02,55.61 32.94,55.61 32.79,55.46 32.36,55.46 31.8,56.02 31.29,56.02 31.24,55.97 31.24,52.8 31.3,52.74 31.7,52.74 32.58,53.63 34.18,53.63 34.9,54.34 36.25,54.34 36.94,55.03 36.94,55.31 37.45,55.83 37.56,55.83 38.03,56.29 38.03,56.42
+3V_TBT on TOP: 45.7,47.71 45.82,47.84 45.82,48.6 45.44,48.98 45.44,49.62 45.95,50.12 45.95,50.38 45.82,50.5 45.31,50.5 44.55,49.74 44.55,47.84 44.68,47.71
+3V_TBT on BOTTOM: 25.48,50.1 24.41,50.1 24.12,49.81 24.12,47.58 24.24,47.46 25.11,47.46 25.22,47.57 25.22,49.15 25.54,49.46 25.54,50.03
+3V_TBT on IN1: 40.34,59.16 32.31,59.16 31.9,58.75 31.9,57.87 32.41,57.36 32.41,55.98 32.03,55.61 32.03,53.6 32.34,53.29 38.3,53.29 40.46,55.45 40.46,59.04
+3V_TBT on IN4: 44.17,55.52 47.22,52.47 47.22,49.74 44.66,47.19 40.9,47.19 38.99,49.09 38.24,49.09 36.14,47 27.41,47 26.73,47.68 25.6,47.68 25.16,48.12 24.35,48.12 24.09,48.37 24.09,49.06 26.62,51.59 26.62,52.1 27.19,52.67 29.56,52.67 32.02,55.13 35.05,55.13 36.42,56.49 37.05,56.49 38.02,55.52
+3V_TBT_PWR on TOP: 47.09,47.71 47.31,47.93 47.94,47.93 48.36,48.35 48.36,50.89 48.24,51.01 47.73,51.01 46.33,49.62 46.33,47.84 46.46,47.71
+3V_TBT_S0 on BOTTOM (solid shape): 24.62,52.93 24.62,52.3 24.92,52 24.96,52 25.09,51.82 25.31,51.76 25.55,51.51 25.55,50.51 25.48,50.43 24.48,50.43 24.21,50.16 23.33,50.16 23.26,50.23 23.26,52.78 23.49,53.02 24.54,53.02
+3V_TBT_S0 on IN4: 25.84,51.31 24.65,51.31 24.65,51.31 24.16,51.31 24.01,51.46 24.01,53.97 24.33,54.29 24.33,54.78 26.52,56.97 30.49,56.97 32.31,58.79 36.85,58.79 37.21,59.15 42.38,59.15 42.69,59.46 42.69,60.54 43.57,61.42 44.22,61.42 44.5,61.14 44.5,59.2 44.95,58.76 44.95,57.4 43.18,55.63 38.12,55.63 37.11,56.64 36.27,56.64 34.9,55.27 31.97,55.27 29.77,53.06 27.07,53.06 26.4,52.39 26.4,51.87
+3V_VC on BOTTOM: 55.09,19.01 57.63,19.01 58.78,20.15 63.86,20.15 64.11,20.41 66.65,20.41 67.03,20.02 67.03,15.96 66.78,15.71 65.51,15.71 63.86,17.36 55.22,17.36 54.97,17.61 54.97,18.88
+3VA_TBT on IN3: 46.58,51.77 46.46,51.65 39.47,51.65 39.35,51.77 39.35,53.17 39.47,53.3 43.16,53.3 43.41,53.04 46.46,53.04 46.58,52.92
+3VALW on BOTTOM (solid shape): 75.19,17 75.95,17 75.95,17.55 76.38,17.55 76.38,17.02 77.16,17.02 77.16,17.55 79.79,17.55 79.95,17.4 79.95,17.14 79.99,17.1 79.99,16.47 79.71,16.19 73.17,16.19 73.17,16.19 72.77,16.19 72.62,16.34 72.62,17.39 72.78,17.55 75.19,17.55
+3VALW on TOP: 172.07,16.72 173.08,16.72 174.35,15.45 174.35,14.69 174.22,14.56 172.95,14.56 172.82,14.69 172.82,15.58 172.45,15.95 172.06,15.95 172,16.01 172,16.65
+3VALW on TOP: 37.69,41.87 40.56,41.87 40.74,41.68 40.74,39.96 40.36,39.58 37.62,39.58 37.54,39.66 37.54,40.19 37.69,40.34 37.69,40.98 37.62,41.06 37.62,41.79
+3VALW on TOP: 173.1,34.53 174.57,34.53 174.73,34.38 174.73,33.99 174.47,33.74 173.2,33.74 173.08,33.87 173.08,34.5
+3VALW on TOP: 178.28,33.11 178.92,33.11 178.98,33.17 178.98,34.46 178.68,34.76 176.76,34.76 176.63,34.63 176.63,33.23 176.89,32.98 178.16,32.98
+3VALW on TOP: 57,75.4 57.89,75.4 58.01,75.52 58.01,76.16 58.14,76.29 59.28,76.29 59.54,76.54 59.54,77.3 60.17,77.94 60.68,77.94 60.81,78.06 60.81,78.57 61.32,79.08 61.32,79.97 61.19,80.1 59.79,80.1 59.41,79.71 59.41,78.32 59.03,77.94 57,77.94 56.74,77.68 56.74,75.65
+3VALW on TOP: 50.52,50.38 50.9,50.38 51.92,49.36 51.92,47.39 51.73,47.2 50.78,47.2 50.65,47.33 50.65,47.71 50.39,47.96 50.39,48.73 50.01,49.11 48.62,49.11 48.49,49.23 48.49,51.65 48.62,51.77 50.14,51.77 50.27,51.65 50.27,50.63
+3VALW on TOP: 180.44,33.11 182.22,33.11 182.35,33.23 182.35,34.25 182.22,34.38 180.82,34.38 180.38,33.93 180.38,33.17
+3VALW on TOP: 25.76,70.44 26.65,70.44 26.77,70.32 26.77,69.94 26.65,69.81 26.26,69.81 25.88,69.43 25.88,68.79 25.76,68.67 25.25,68.67 25.12,68.79 25.12,69.81
+3VALW on TOP: 169.39,16.6 169.52,16.72 170.54,16.72 170.6,16.66 170.6,16.01 170.43,15.83 169.01,15.83 168.76,15.58 168.38,15.58 168.25,15.71 168.25,15.96 168.89,16.6
+3VALW on TOP: 169.65,66.89 170.41,66.89 170.66,66.63 170.66,62.57 170.54,62.44 170.28,62.44 170.16,62.57 170.16,63.59 169.39,64.35 169.39,66.63
+3VALW on TOP: 35.13,41.87 36.17,41.87 36.25,41.79 36.25,41.16 36.17,41.08 36.17,39.58 36.04,39.46 35.15,39.46 35.03,39.58 35.03,41.77
+3VALW on TOP: 198.22,41.23 198.98,41.23 199.14,41.39 200.56,41.39 200.64,41.31 200.64,39.66 200.23,39.25 197.71,39.25 197.66,39.3 197.66,39.73 198.2,40.27 198.2,41.21
+3VALW on TOP: 35.03,44.15 35.03,44.41 34.65,44.79 34.01,44.79 33.88,44.66 33.88,43.39 33.76,43.27 33.76,42.63 33.88,42.5 34.52,42.5 34.65,42.63 34.65,43.77
+3VALW on BOTTOM: 200.89,65.45 200.55,65.11 200.55,63.99 200.32,63.99 200.32,65.3 199.87,65.74 199.87,67.14 200,67.27 200.76,67.27 200.89,67.14
+3VALW on BOTTOM: 29.06,19.64 29.19,19.77 29.19,19.9 28.55,20.53 28.55,21.68 28.42,21.8 27.79,21.8 26.77,20.79 26.77,19.8 26.92,19.64
+3VALW on IN1: 41.5,76.29 41.38,76.41 41.38,76.67 42.01,77.3 43.54,77.3 45.06,78.83 59.41,78.83 60.55,79.97 61.32,79.97 61.44,79.84 61.44,77.43 60.55,76.54 56.11,76.54 55.35,77.3 52.68,77.3 52.43,77.56 45.95,77.56 44.68,76.29
+3VALW on IN2: 174.47,33.74 173.08,33.74 171.81,35.01 171.81,36.28 171.3,36.79 171.3,38.31 171.93,38.95 171.93,52.66 172.7,53.43 172.7,54.57 171.93,55.33 171.93,57.36 172.95,58.38 173.2,58.38 173.46,58.12 173.46,57.49 174.22,56.73 174.22,53.04 173.46,52.28 173.46,47.33 173.84,46.95 177.78,46.95 177.9,46.82 177.9,46.44 177.65,46.19 173.71,46.19 173.33,45.81 173.33,39.71 172.57,38.95 172.57,38.31 172.19,37.93 172.19,37.42 172.57,37.04 172.57,35.65 173.2,35.01 174.47,35.01 174.73,34.76 174.73,33.99
+3VALW on IN2: 34.52,44.03 34.9,44.03 35.28,44.41 35.28,47.71 32.11,50.89 32.11,58.12 32.36,58.38 32.36,63.97 31.09,65.24 31.09,67.27 28.55,69.81 25.38,69.81 24.99,69.43 24.99,68.92 25.25,68.67 27.28,68.67 29.19,66.76 29.19,64.09 30.33,62.95 30.33,59.27 31.34,58.25 31.34,48.47 33.5,46.31 33.5,45.04
+3VALW on IN3: 41,39.71 40.74,39.46 35.41,39.46 33.63,41.23 33.63,43.01 32.23,44.41 32.23,45.3 30.46,47.08 28.53,47.08 26.98,48.62 26.98,52.91 27.37,53.3 28.84,53.3 28.99,53.14 28.99,52.65 28.99,52.65 28.79,52.45 28.39,52.45 28.15,52.21 28.15,48.71 28.62,48.23 31.33,48.23 34.9,44.66 34.9,44.54 36.68,42.76 38.08,42.76 38.96,41.87 40.6,41.87 41,41.48
+3VALW on VCC: 108.09,12.57 108.03,12.68 107.95,12.79 107.95,14.97 104.61,14.97 104.61,13.47 96.99,13.47 96.76,13.51 96.55,13.62 95.22,14.62 94.29,15.1 93.26,15.27 72.7,15.27 72.17,15.19 71.7,14.96 66.65,20 66.65,20.89 51.64,35.9 47.83,35.9 44.78,38.95 40.72,38.95 39.85,39.81 39.85,46.21 42.12,48.47 51.69,48.47 52.57,47.58 68.96,47.58 69.72,46.82 88.49,46.82 88.49,44.3 89.15,43.65 96.62,43.65 96.62,36.17 98.02,34.78 98.02,33.89 99.16,32.75 99.16,24.49 103.25,20.41 158.07,20.41 160.23,22.56 170.26,22.56 171.55,23.86 171.55,34.65 175.09,38.19 198.33,38.19 201.63,41.49 204.93,41.49 204.93,40.92 206.72,30.76 211.87,21.81 211.87,19.41 212.68,17.68 214.52,17.18 215.93,16.79 216.54,15.47 216.54,13.47 132.59,13.47 131.7,13.23 131.05,12.57 127.13,12.57 126.48,13.23 125.59,13.47 115.47,13.47 115.47,14.97 112.23,14.97 112.23,12.89 112.11,12.74 112,12.57
+3VALW on IN4: 25.25,68.67 25.76,68.67 27.29,70.2 27.29,70.89 27.01,71.17 26.36,71.17 25.12,69.94 25.12,68.79
+3VALW on IN4: 38.2,77.39 38.2,76.22 38.49,75.93 42.19,75.93 42.52,76.26 42.52,77.51 42.23,77.79 38.61,77.79
+3VALW_5085 on TOP: 192,58.38 192.63,58.38 192.76,58.51 192.76,61.03 192.24,61.55 191.11,61.55 190.98,61.43 190.98,59.52 191.24,59.27 191.62,59.27 192,58.89
+3VALW_5085 on BOTTOM: 170.16,64.6 171.81,64.6 171.93,64.47 171.93,63.46 171.81,63.33 170.03,63.33 169.9,63.46 169.9,64.35
+3VALW_5085 on IN2: 175.36,64.6 175.49,64.47 175.49,63.97 174.47,62.95 170.03,62.95 168.89,64.09 168.89,64.47 169.01,64.6
+3VALW_5085 on IN2: 180.82,70.95 184,70.95 184.25,70.7 184.25,69.55 184,69.3 180.44,69.3 180.19,69.55 180.19,70.44 179.81,70.82 178.41,70.82 177.52,71.71 177.52,71.97 177.9,72.35 178.28,72.35 178.79,71.84 179.93,71.84
+3VALWP on TOP (solid shape): 82.65,23.2 82.65,18.63 82.4,18.37 78.84,18.37 78.59,18.63 78.59,23.33 79.1,23.83 82.02,23.83
+3VALWP on BOTTOM (solid shape): 82.65,23.2 82.65,17.99 82.37,17.71 74.51,17.71 74.4,17.81 74.4,19.01 74.65,19.26 78.33,19.26 78.59,19.52 78.59,23.2 79.1,23.71 82.14,23.71
+3VLP on BOTTOM: 88.75,20.35 88.75,19.77 87.22,18.25 87.22,16.39 87.07,16.24 85.95,16.24 85.83,16.37 85.83,17.87 87.35,19.39 87.35,20.28 87.53,20.46 88.64,20.46
+3VS on TOP: 40.49,45.68 40.62,45.55 41.25,45.55 41.38,45.42 41.38,44.54 41.12,44.28 40.87,44.28 40.49,44.66 39.1,44.66 38.9,44.86 38.9,45.71 38.53,46.07 38.53,47.63 39.15,48.25 40.22,48.25 40.49,47.98
+3VS on IN3: 184.76,44.28 189.97,44.28 190.48,44.79 192.63,44.79 193.14,44.28 193.14,37.55 192.89,37.3 184.51,37.3 184.25,37.55 184.25,43.77
+3VS on IN4: 39.44,47.8 37.5,47.8 36.48,46.79 27.33,46.79 26.57,47.55 25.4,47.55 25.04,47.92 23.66,47.92 23.51,47.76 23.51,43.3 24.69,42.12 26.76,42.12 29.57,44.93 38.46,44.93 39.71,46.18 39.71,47.53
+3VS_AUDIO on TOP: 33.76,38.44 34.77,38.44 34.9,38.31 34.9,36.92 34.77,36.79 33.83,36.79 33.4,36.36 32.41,36.36 32.36,36.41 32.36,37.55 32.74,37.93 33.5,37.93 33.63,38.06 33.63,38.31
+3VS_CR on TOP: 174.98,20.53 176,20.53 180.19,16.34 180.19,14.94 179.93,14.69 177.39,14.69 174.73,17.36 174.73,20.28
+3VS_CR on BOTTOM: 197.21,15.96 197.21,15.2 197.08,15.07 196.32,15.07 196.19,15.2 196.19,16.21 195.81,16.6 195.81,19.39 196.7,20.28 196.7,22.69 196.44,22.95 194.79,22.95 194.29,23.45 194.29,26.5 193.9,26.88 193.65,26.88 193.52,27.01 193.52,27.14 193.4,27.26 192.25,27.26 192.13,27.39 192.25,27.52 193.65,27.52 193.78,27.64 194.54,27.64 195.05,27.14 195.05,23.96 195.3,23.71 197.46,23.71 197.84,23.33 197.84,19.64 196.95,18.75 196.95,18.25 197.46,17.74 197.46,16.21
+3VS_CR on IN3: 188.57,16.98 179.81,16.98 178.79,15.96 178.79,14.06 179.3,13.55 198.22,13.55 198.98,14.31 198.98,19.64 198.35,20.28 195.56,20.28 190.6,15.33 190.22,15.33
+3VS_NGFF on TOP: 31.22,48.22 34.27,48.22 35.15,47.33 36.42,47.33 36.55,47.2 36.55,46.31 36.42,46.19 33.63,46.19 33.38,46.44 30.58,46.44 30.46,46.57 30.46,47.46
+3VS_NGFF on TOP: 50.14,46.31 50.01,46.19 46.97,46.19 46.84,46.31 46.84,47.08 47.64,47.88 47.99,47.88 48.21,48.09 48.62,48.09 49.38,47.33 50.01,47.33 50.14,47.2
+3VS_NGFF on BOTTOM: 49.56,45.55 49.76,45.75 49.76,47.71 49.12,48.35 47.73,48.35 47.47,48.09 47.47,47.46 47.73,47.2 48.74,47.2 48.84,47.1 48.84,45.63 48.92,45.55
+3VS_NGFF on BOTTOM: 31.42,45.55 32.08,45.55 32.16,45.63 32.16,47 32.49,47.33 33.25,47.33 33.63,46.95 34.52,46.95 34.77,47.2 34.77,48.17 34.57,48.37 31.34,48.37 31.09,48.12 31.09,45.88
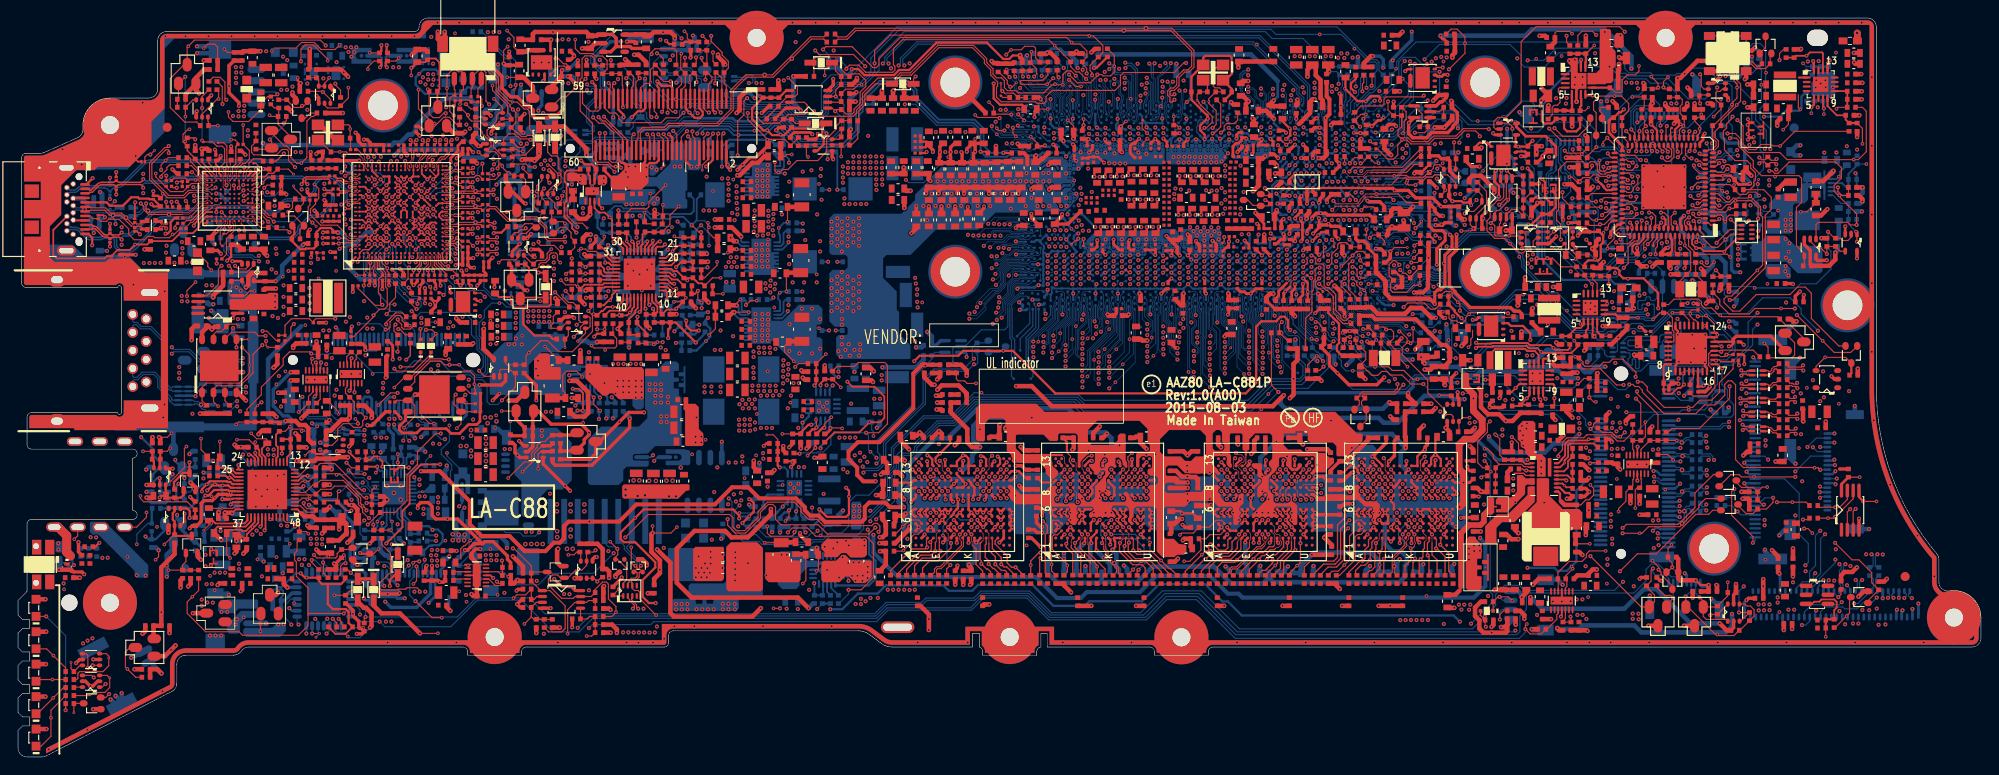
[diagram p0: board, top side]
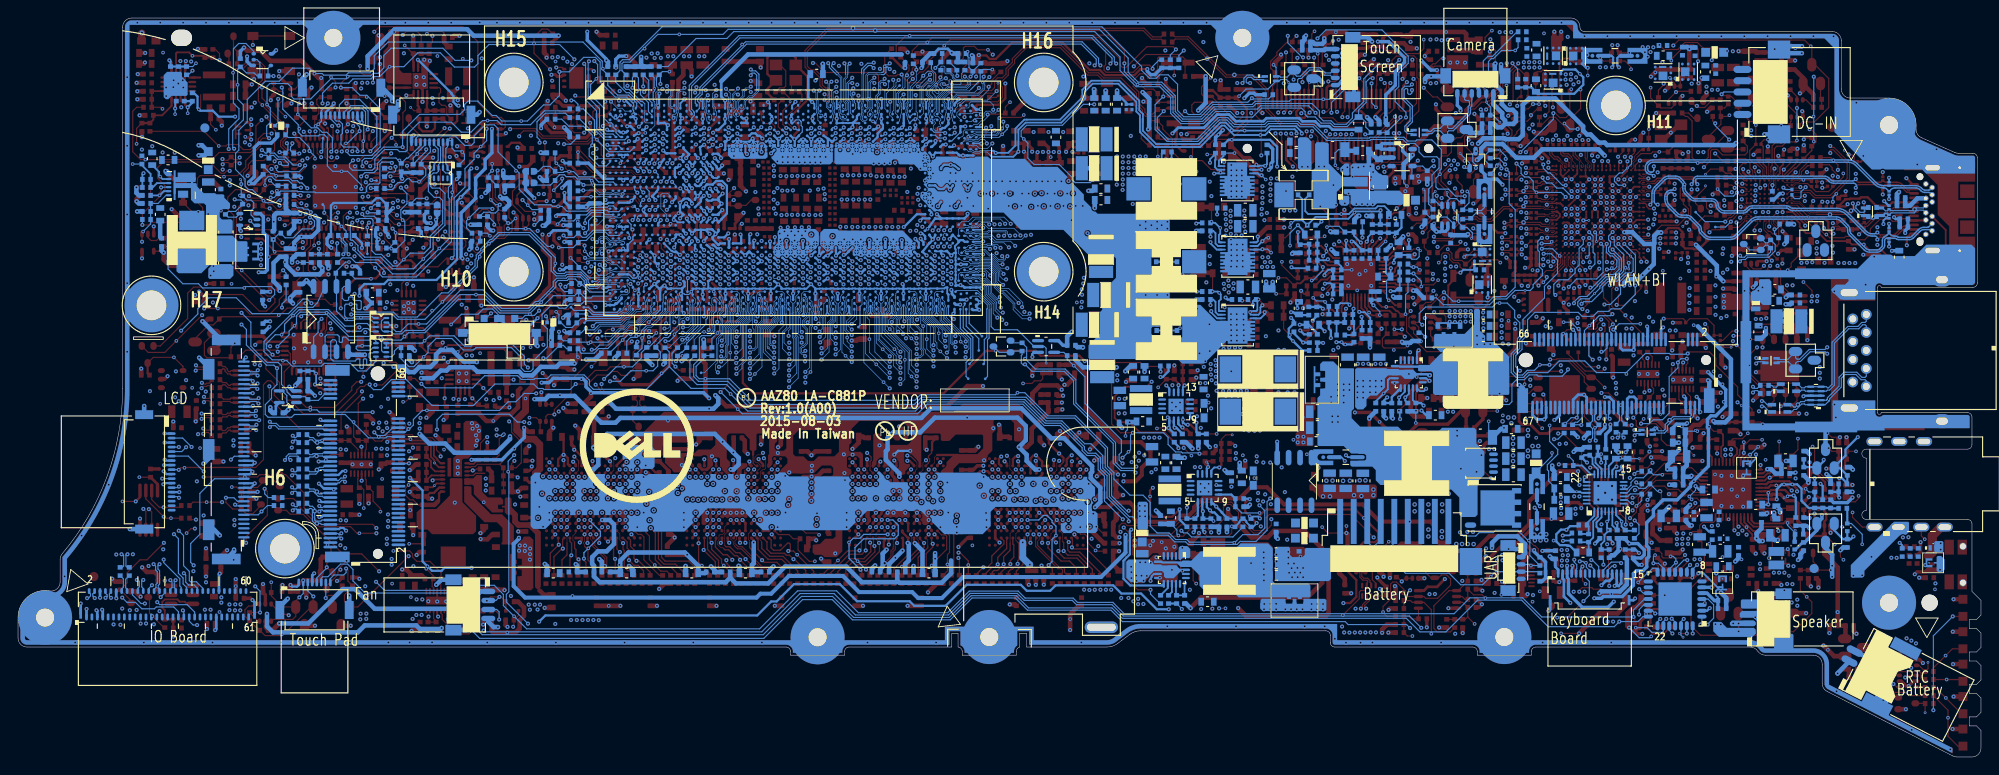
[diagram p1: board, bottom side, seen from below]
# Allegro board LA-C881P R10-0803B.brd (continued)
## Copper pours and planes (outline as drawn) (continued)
+3VS_NGFF on IN3: 37.06,48.35 34.14,48.35 33.63,47.84 33.63,47.2 34.14,46.69 34.65,46.69 37.57,43.77 38.58,43.77 39.09,43.27 44.55,43.27 48.62,47.33 48.62,47.96 47.6,48.98 46.97,48.98 44.74,46.76 38.65,46.76
+3VS_TP on TOP: 168.5,17.48 169.27,17.48 169.39,17.36 169.39,16.85 169.27,16.72 167.62,16.72 167.49,16.85 167.49,17.87 167.62,17.99 168,17.99
+3VS_TP on IN1: 187.17,19.9 190.6,19.9 190.98,19.52 190.98,14.44 190.73,14.18 188.95,14.18 188.7,14.44 188.7,17.61 187.68,18.63 187.17,18.63 186.92,18.88 186.92,19.64
+3VS_TPM on TOP: 182.09,40.6 182.68,40.01 183.56,40.01 184.22,40.67 184.56,40.67 184.63,40.6 184.63,40.04 183.93,39.33 182.22,39.33 180.95,40.6 180.95,48.07 181.12,48.23 181.66,48.23 182.21,48.78 183.07,48.78 183.36,48.48 183.36,47.96 183.26,47.86 182.45,47.86 182.09,47.5
+3VS_TPM on IN1: 190.22,45.93 191.11,45.04 191.11,43.14 187.3,39.33 183.87,39.33 183.62,39.58 183.62,40.73 183.87,40.98 185.27,40.98 186.54,42.25 186.54,43.77 188.7,45.93
+5V_USB_P2 on TOP: 20.78,50.66 20.78,49.16 20.65,49.03 17.93,49.03 17.76,49.21 17.76,51.27 17.88,51.39 18.82,51.39 18.97,51.24 18.97,50.99 19.23,50.73 20.7,50.73
+5V_USB_P2 on BOTTOM: 20.55,51.39 20.55,50 20.8,49.74 20.8,46.82 20.68,46.69 16.87,46.69 15.47,48.09 13.95,48.09 13.69,48.35 13.69,49.87 14.2,50.38 16.99,50.38 18.26,51.65 20.3,51.65
+5VALW on TOP (solid shape): 28.87,51.39 28.87,49.74 28.74,49.62 23.6,49.62 23.47,49.74 23.47,50.69 23.6,50.82 25.12,50.82 25.69,51.39 27.66,51.39 27.79,51.52 28.74,51.52
+5VALW on TOP: 193.14,16.09 194.41,16.09 194.54,16.21 194.54,17.48 194.03,17.99 193.52,17.99 193.4,17.87 193.4,17.23 193.02,16.85 193.02,16.21
+5VALW on TOP: 28.43,53.48 27.41,54.5 27.41,55.08 27.53,55.2 27.92,55.2 27.95,55.24 27.95,55.86 27.89,55.93 27.89,57.13 27.79,57.24 24.36,57.24 24.23,57.36 24.23,59.39 24.49,59.65 26.14,59.65 27.53,58.25 29.57,58.25 29.95,57.87 29.95,56.74 29.5,56.3 29.5,55.77 29.82,55.46 29.82,54.44 28.86,53.48
+5VALW on TOP: 51.61,19.47 52.25,19.47 52.91,18.8 53.9,18.8 54.23,18.47 54.23,17.64 54.08,17.48 51.69,17.48 51.54,17.64 51.54,19.39
+5VALW on TOP: 51.6,20.85 51.54,20.91 51.54,21.37 50.9,22.01 50.9,22.72 51.09,22.9 51.57,22.9 52.03,23.37 52.53,23.37 53.52,22.38 53.52,21.61 52.76,20.85
+5VALW on BOTTOM: 192.13,18.75 195.05,18.75 195.17,18.63 195.17,16.34 194.92,16.09 194.92,15.07 194.79,14.94 192,14.94 191.87,15.07 191.87,16.98 192,17.1 192,18.63
+5VALW on BOTTOM: 58.01,47.71 58.01,47.2 57.3,47.2 56.38,48.12 56.38,49.6 56.48,49.7 61.14,49.7 61.41,49.44 61.41,47.34 61.24,47.18 60.05,47.18 60.05,47.71 59.23,47.71 59.23,47.18 58.83,47.18 58.83,47.71
+5VALW on GND2: 153.39,13.65 153.39,15.35 157.43,19.39 176.4,19.39 177.54,18.25 193.29,18.25 194.54,17 194.54,14.67 193.42,13.55 153.5,13.55
+5VALW on IN3: 53.34,22.54 53.34,18.78 52.81,18.25 51.79,18.25 51.54,18.5 51.54,22.41 51.79,22.67 53.21,22.67
+5VALW on IN3: 96.24,17.87 96.24,18.75 96.75,19.26 102.34,19.26 103.35,18.25 106.02,18.25 106.66,18.88 156.69,18.88 156.95,18.63 156.95,15.45 156.44,14.94 133.33,14.94 131.67,16.6 100.81,16.6 100.05,17.36 96.75,17.36
+5VALW on VCC: outline of 95 points within 1.27,1.27 88.49,80.73 ; 3 cut-outs
+5VALW on IN4: 165.58,14.69 174.6,14.69 175.49,13.8 193.9,13.8 194.79,14.69 194.79,16.72 194.03,17.48 179.05,17.48 176,20.53 166.73,20.53 161.77,15.58 153.26,15.58 153.03,15.35 153.03,13.7 153.18,13.55 164.44,13.55
+5VALW on IN4: 77.98,23.86 78.28,23.96 78.38,24.26 79.79,25.68 84.62,25.68 84.68,25.74 91.8,25.74 92.43,25.1 92.81,25.1 93.96,23.96 94.34,23.96 97.13,21.17 98.78,21.17 99.8,20.15 99.8,18.5 99.42,18.12 92.74,18.12 90.2,15.58 71.22,15.58 70.84,15.2 70.84,13.67 70.71,13.55 67.16,13.55 66.9,13.8 66.9,16.09 74.52,23.71 77.83,23.71
+5VALWP on BOTTOM (solid shape): 56.24,49.62 56.24,48.01 57.29,46.95 60.55,46.95 60.68,46.82 60.68,45.62 59.97,44.92 58.08,44.92 56.67,43.51 56.67,41.05 55.81,40.19 52.45,40.19 52.35,40.29 52.35,44.42 53.97,46.04 54.95,46.04 55.02,46.11 55.02,46.74 55.6,47.32 55.6,49.62 55.73,49.74 56.11,49.74
+5VALWP on TOP: 53.7,49.74 54.2,49.74 54.33,49.62 54.33,47.63 54.79,47.16 56.11,47.16 56.49,46.78 56.49,45.68 56.36,45.55 53.7,45.55 53.57,45.68 53.57,49.62
+5VS on TOP: 45.95,19.14 47.09,19.14 47.22,19.01 47.22,16.72 46.97,16.47 45.31,16.47 44.81,16.98 44.81,17.36 45.82,18.37 45.82,19.01
+5VS_AUDIO on TOP: 23.11,20.74 23.22,20.63 23.22,19.87 23.04,19.69 21.16,19.69 20.9,19.95 20.9,20.61 21.03,20.74
+5VS_AUDIO on TOP: 47.45,21.04 47.35,20.94 46.41,20.94 46.28,21.07 46.28,21.4 46.13,21.55 45.82,21.55 45.7,21.68 45.7,23.07 45.87,23.25 47.4,23.25 47.45,23.2
+5VS_AUDIO on BOTTOM: 21.57,21.93 23.6,21.93 23.72,21.8 23.72,20.28 23.6,20.15 21.69,20.15 21.44,20.41 21.44,21.8
+5VS_AUDIO on BOTTOM: 28.8,23.83 31.98,23.83 32.36,23.45 34.9,23.45 35.28,23.83 35.28,25.23 34.65,25.87 34.65,27.14 33.5,28.28 32.36,28.28 31.6,27.52 31.6,27.01 31.73,26.88 33.12,26.88 33.25,26.76 33.25,25.99 32.23,24.98 30.58,24.98 30.33,24.72 28.8,24.72 28.68,24.6 28.68,23.96
+5VS_AUDIO on VCC: 34.32,20.53 31.6,23.25 31.6,26.73 31.34,26.99 31.34,28.55 31.58,28.79 32.13,28.79 32.87,28.05 32.87,26.78 35.3,24.34 37.46,24.34 38.6,23.2 46.48,23.2 46.71,22.97 46.71,20.89 46.35,20.53
+5VS_AUDIO on IN4: 32.99,23.45 33.93,23.45 34.14,23.66 34.14,24.98 33.88,25.23 31.98,25.23 28.42,21.68 21.82,21.68 21.57,21.42 21.57,20.02 21.82,19.77 29.31,19.77
+AVDD1 on BOTTOM: 22.71,24.85 22.71,25.36 22.58,25.49 21.52,25.49 21.06,25.02 21.06,23.99 21.81,23.23 21.81,22.27 21.9,22.18 23.47,22.18 23.6,22.31 23.6,23.45 23.47,23.58 22.58,23.58 22.2,23.96 22.2,24.34
+AVDD1 on BOTTOM: 22.2,33.61 23.47,33.61 23.48,33.6 24.02,33.6 24.16,33.46 24.16,31.33 23.9,31.07 21.95,31.07 21.82,31.2 21.82,32.47 22.07,32.72 22.07,33.49
+PVDD1 on TOP: 26.95,25.92 26.95,27.02 27.01,27.07 27.11,27.07 27.16,27.02 27.16,25.49 26.11,24.43 25.87,24.43 25.75,24.54 25.75,24.72
+PVDD1 on BOTTOM: 27.28,25.87 27.28,25.61 26.61,24.94 26.61,24.38 26.77,24.22 27.41,24.22 27.79,24.6 28.42,24.6 28.55,24.47 28.55,22.18 28.42,22.06 27.66,22.06 27.53,22.18 27.53,22.56 27.28,22.82 26.39,22.82 25.63,23.58 25.63,25.49 26.49,26.35 26.8,26.35
+PVDD2 on TOP: 28.98,27.09 29.14,27.09 29.19,27.03 29.19,26.08 29.4,25.88 30.26,25.88 30.34,25.8 30.34,25.51 30.23,25.41 29.17,25.41 28.94,25.64 28.94,27.04
+PVDD2 on BOTTOM: 29.59,26.96 31.29,26.96 31.55,26.7 32,26.7 32.11,26.6 32.11,26.09 32.06,26.04 30.48,26.04 30.33,25.89 30.33,25.54 30.2,25.41 27.97,25.41 27.74,25.64 27.74,26.63 27.88,26.78 29.41,26.78
+VBUS_DC_SS on BOTTOM: 44.81,78.89 47.54,78.89 47.66,78.76 47.66,76.86 47.54,76.73 44.81,76.73 44.68,76.86 44.68,78.76
+VCC0V9_CIO on IN3: 48.88,60.54 49.21,60.21 49.21,54.63 48.24,53.65 45.11,53.65 42.98,55.79 42.98,60.26 43.26,60.54
+VCC0V9_DP on BOTTOM: 44.55,59.14 44.93,58.76 47.22,58.76 48.87,57.11 48.87,54.82 48.49,54.44 48.49,53.93 48.74,53.68 49.89,53.68 50.14,53.93 50.14,59.65 47.98,61.81 45.95,61.81 45.7,62.06 44.68,62.06 44.55,61.93
+VCC0V9_DP on IN1: 40.99,60.11 41.94,61.07 42.43,61.07 42.62,61.27 42.62,62.24 43.31,62.92 44.47,62.92 45.11,62.29 45.11,56.38 44.55,55.83 41.77,55.83 40.99,56.61
+VCC0V9_PCIE on TOP: 41,68.28 42.39,68.28 42.52,68.16 42.52,67.01 42.77,66.76 42.77,66.38 42.65,66.25 42.39,66.25 42.14,66.51 41.12,66.51 40.87,66.76 40.87,68.16
+VCC0V9_PCIE on IN1: 42.27,61.17 41.5,61.17 41.25,61.43 41.25,66.38 42.27,67.4 43.92,67.4 44.3,67.01 44.3,64.09 42.52,62.32 42.52,61.43
+VCC0V9_USB on BOTTOM: 48.71,66.79 45.06,66.79 41.68,63.41 41.68,62.21 42.05,61.85 44.06,61.85 48.36,66.15 48.82,66.15 48.95,66.28 48.95,66.54
+VCC_CORE on BOTTOM (solid shape): outline of 541 points within 127.36,65.76 134.55,68.73
+VCC_CORE on BOTTOM (solid shape): outline of 683 points within 128.94,55.39 133.99,58.9
+VCC_CORE on TOP: outline of 104 points within 90.78,55.33 134.8,73.36 ; 2 cut-outs
+VCC_CORE on BOTTOM: 91.67,62.32 91.03,62.32 90.78,62.06 90.78,60.92 91.03,60.66 97.26,60.66 97.77,61.17 97.77,63.59 98.02,63.84 98.02,69.94 98.27,70.19 100.31,70.19 101.58,68.92 106.15,68.92 106.32,69.1 106.32,69.43 105.82,69.94 101.83,69.94 99.54,72.22 95.35,72.22 95.23,72.09 94.08,72.09 93.96,71.97 93.96,71.46 93.57,71.08 93.57,69.3 91.16,66.89 91.16,63.59 91.42,63.33 91.92,63.33 92.05,63.2 92.05,62.7
+VCC_CORE on IN1: 129.26,57.11 128.12,58.25 125.71,58.25 125.2,57.74 125.2,56.85 124.82,56.47 116.82,56.47 116.56,56.73 116.56,58.68 115.39,59.85 112.83,59.85 112.12,59.14 102.08,59.14 98.91,55.97 94.46,55.97 94.08,56.35 94.08,59.65 92.81,60.92 91.67,60.92 91.29,61.3 91.29,66.51 91.67,66.89 97.51,66.89 97.89,66.51 97.89,64.09 98.27,63.71 98.91,63.71 100.56,65.36 107.67,65.36 108.31,66 109.7,66 110.47,66.76 117.07,66.76 117.83,66 118.85,66 120.63,64.22 125.32,64.22 127.94,66.84 133.2,66.84 134.47,65.57 134.47,58.25 133.33,57.11
+VCC_CORE on IN2: 128.12,67.4 132.94,67.4 134.21,66.13 134.21,57.62 133.58,56.98 130.91,56.98 130.4,57.49 130.4,58 129.77,58.63 128.5,58.63 127.99,59.14 127.99,65.74 127.48,66.25 127.48,66.76
+VCC_CORE on IN3: 130.91,56.98 134.21,56.98 134.98,57.74 134.98,66.89 134.47,67.4 128.12,67.4 127.48,66.76 127.48,59.14 128.37,58.25 129.64,58.25
+VCC_CORE on VCC: 130.38,56.85 128.6,58.63 127.23,58.63 127.23,62.29 126.57,62.95 118.06,62.95 117.81,63.2 116.92,63.2 116.16,63.97 96.9,63.97 93.6,60.66 89,60.66 89,69.58 93.55,74.13 104.24,74.13 104.24,77.17 123.69,77.17 124.18,76.69 124.18,72.88 125.96,71.1 125.96,68.31 126.74,67.52 134.24,67.52 134.6,67.16 134.6,57.98 133.47,56.85
+VCC_CORE on GND3: 91.77,61.05 91.42,61.4 91.42,67.16 96.35,72.09 104.98,72.09 108.16,75.27 112.9,75.27 118.47,69.7 118.47,68.56 118.87,68.16 119.12,68.16 119.63,67.65 127.33,67.65 128.35,68.67 134.49,68.67 134.6,68.56 134.6,65.47 132.58,63.46 118.32,63.46 114.89,66.89 107.69,66.89 106.8,66 98.68,66 93.72,61.05
+VCC_EDRAM on TOP: 116.71,61.15 116.71,64.37 117.25,64.91 117.94,64.91 118.34,64.51 118.34,63.64 118.8,63.18 119.51,63.18 120.12,62.57 121.77,62.57 122.02,62.32 122.66,62.32 122.78,62.19 122.78,61.55 122.66,61.43 120.75,61.43 120.37,61.81 118.21,61.81 118.09,61.68 118.09,61.17 117.83,60.92 116.94,60.92
+VCC_EDRAM on BOTTOM: 117.07,64.92 117.01,64.86 117.01,64.54 117.45,64.09 117.45,63.46 117.01,63.01 117.01,62.89 117.07,62.82 117.64,62.82 117.83,62.63 117.83,62 117.01,61.17 117.01,61.05 117.08,60.97 118.26,60.97 118.39,61.1 118.39,64.7 118.17,64.92
+VCC_EDRAM on BOTTOM: 94.69,37.78 94.82,37.65 96.18,37.65 96.34,37.81 96.34,39.84 96.2,39.97 94.82,39.97 94.69,39.85
+VCC_EDRAM on GND3: 92.79,37.3 91.92,38.16 91.92,43.41 93.57,45.06 93.57,60.54 93.93,60.54 98.89,65.49 107.01,65.49 107.9,66.38 114.68,66.38 118.11,62.95 118.34,62.95 118.34,60.52 116.58,58.76 111.59,58.76 109.43,60.92 99.44,60.92 96.62,58.1 96.62,37.66 96.26,37.3
+VCC_EDRAM_P on BOTTOM: 92.43,42.38 94.59,42.38 95.84,41.13 96.26,41.13 96.36,41.03 96.36,40.22 96.29,40.15 94.78,40.15 94.59,40.34 91.86,40.34 91.31,39.79 91.31,39.6 91.24,39.53 90.48,39.53 90.42,39.6 90.42,40.37
+VCC_EOPIO on GND2 (solid shape): outline of 3393 points within 91.03,35.01 119.48,64.47
+VCC_EOPIO on TOP: 116.94,59.9 118.09,59.9 118.34,60.16 118.34,60.66 118.72,61.05 119.86,61.05 119.99,60.92 119.99,60.28 119.86,60.16 119.36,60.16 118.72,59.52 118.72,58.76 118.97,58.51 118.97,58.25 118.72,58 116.94,58 116.56,58.38 116.56,59.52
+VCC_EOPIO on BOTTOM: 93.4,34.25 93.4,35.39 93.12,35.67 90.81,35.67 90.53,35.39 90.53,34.2 90.72,34.01 93.16,34.01
+VCC_EOPIO on BOTTOM: 117.3,59.47 117.09,59.47 116.99,59.37 116.99,58.33 117.09,58.23 117.25,58.23 117.45,58.43 117.83,58.43 118.01,58.25 118.24,58.25 118.24,59.11 118.14,59.22 117.55,59.22
+VCC_EOPIO_P on TOP: 88.67,32.33 88.67,31.52 88.93,31.25 92.32,31.25 92.42,31.35 92.42,32.16 92.19,32.4 88.74,32.4
+VCC_EOPIO_P on BOTTOM: 91.77,29.59 91.32,30.05 88.96,30.05 88.52,30.49 87.3,30.49 87.26,30.53 87.26,30.68 87.32,30.74 87.43,30.74 88.05,31.36 88.05,32.06 88.46,32.47 90.64,32.47 91.38,33.21 92.67,33.21 92.74,33.14 92.74,29.84 92.49,29.59
+VCC_GT on BOTTOM (solid shape): outline of 1246 points within 118.21,55.46 128.8,58.59
+VCC_GT on BOTTOM (solid shape): outline of 2406 points within 90.02,44.15 127.23,68.21
+VCC_GT on TOP: 91.16,44.15 89.89,45.42 89.89,59.52 90.4,60.03 97,60.03 102.46,65.49 110.97,65.49 111.61,66.13 112.37,66.13 113.01,65.49 115.8,65.49 115.93,65.62 115.93,66 116.05,66.13 116.56,66.13 116.82,66.38 116.82,66.89 116.88,66.95 117.46,66.95 117.58,67.06 117.58,67.4 117.7,67.52 118.85,67.52 118.97,67.65 118.97,68.03 119.1,68.16 119.74,68.16 120.12,67.78 121.51,67.78 121.9,67.4 121.9,66.89 122.66,66.13 124.18,66.13 124.31,66.25 124.31,66.63 123.67,67.27 123.67,67.65 123.8,67.78 126.72,67.78 126.85,67.65 126.85,67.4 126.47,67.01 126.47,65.87 126.59,65.74 126.59,64.98 126.52,64.91 118.16,64.91 117.96,65.11 117.09,65.11 116.59,64.6 116.59,60.05 116.33,59.8 116.33,58.23 116.94,57.62 119.23,57.62 119.36,57.74 119.36,58.38 119.43,58.45 126.77,58.45 127.36,57.87 127.36,52.66 125.96,51.27 122.4,51.27 116.43,45.3 100.05,45.3 98.91,44.15 ; 1 cut-out
+VCC_GT on TOP: 114.78,73.87 124.05,73.87 124.77,73.16 124.77,72.68 124.66,72.58 114.66,72.58 114.35,72.88 114.35,73.44
+VCC_GT on IN2: 100.69,62.95 110.97,62.95 111.61,62.32 115.16,62.32 116.56,63.71 117.7,63.71 118.47,64.47 118.47,65.36 118.97,65.87 119.99,65.87 120.37,66.25 123.04,66.25 124.18,67.4 124.56,67.4 124.69,67.27 124.69,66.63 125.07,66.25 126.72,66.25 127.74,65.24 127.74,57.36 127.36,56.98 120.5,56.98 120.24,56.73 120.24,55.71 119.86,55.33 118.72,55.33 118.47,55.58 118.47,59.39 117.73,60.13 114,60.13 112.12,58.25 112.12,57.11 110.08,55.08 108.94,55.08 108.31,54.44 108.31,52.41 105.51,49.62 102.08,49.62 98.91,46.44 98.91,45.3 97.64,44.03 91.16,44.03 90.65,44.54 90.65,45.81 91.16,46.31 91.16,47.58 90.91,47.84 89.64,47.84 89.51,47.96 89.51,59.39 90.53,60.41 98.15,60.41
+VCC_GT on IN3: 121.39,73.36 121.64,73.62 124.69,73.62 124.82,73.49 124.82,72.48 124.69,72.35 121.64,72.35 121.39,72.6
+VCC_GT on IN3: 98.15,60.41 90.02,60.41 88.37,58.76 88.37,44.92 89.13,44.15 98.78,44.15 99.04,44.41 99.04,46.44 100.56,47.96 102.34,47.96 105.13,45.17 106.66,45.17 112.5,51.01 116.69,51.01 118.21,52.54 118.21,57.49 118.97,58.25 126.47,58.25 126.98,58.76 126.98,64.73 125.58,66.13 118.09,66.13 117.7,65.74 116.69,65.74 116.43,66 116.05,66 115.29,65.24 111.99,65.24 110.97,64.22 101.96,64.22
+VCC_GT on VCC: 89.36,44.15 89,44.51 89,60.16 93.81,60.16 97.11,63.46 115.95,63.46 116.71,62.7 117.6,62.7 117.85,62.44 126.36,62.44 126.72,62.08 126.72,56.66 125.12,56.66 124.86,56.41 117.24,56.41 117.17,56.47 114,56.47 109.68,60.79 102.1,60.79 96.62,55.31 96.62,44.15
+VCC_GT on IN4: 119.74,71.21 120.37,70.57 121.13,70.57 122.15,69.55 122.15,66.63 124.05,64.73 125.71,64.73 126.98,63.46 126.98,56.85 126.72,56.6 125.45,56.6 124.31,55.46 121.26,55.46 120.88,55.84 120.24,55.84 119.86,55.46 111.86,55.46 110.34,56.98 110.34,57.74 111.1,58.51 111.1,59.39 109.96,60.54 101.96,60.54 96.5,55.08 96.5,44.15 95.99,43.65 90.53,43.65 89.89,44.28 89.89,52.92 91.42,54.44 91.42,55.2 90.02,56.6 90.02,59.65 90.65,60.28 95.35,60.28 99.92,64.86 109.2,64.86 111.61,67.27 115.55,67.27 116.56,68.28 116.56,70.1 114.02,72.64 114.02,73.11 114.15,73.24 117.61,73.24 119.64,71.21
+VCC_SA on BOTTOM (solid shape): outline of 374 points within 134.66,66.38 139.04,68.73
+VCC_SA on TOP: 75.95,60.38 78.08,60.38 79.15,61.45 79.15,64.4 78.92,64.63 76.05,64.63 75.72,64.3 75.72,60.61
+VCC_SA on BOTTOM: 76.18,68.61 76.35,68.79 78.08,68.79 79.1,67.78 79.1,61.05 78.4,60.35 75.98,60.35 75.79,60.54 75.79,61.3 76.37,61.87 76.37,62.76 76.18,62.95
+VCC_SA on BOTTOM: 138.63,57.49 138.63,56.9 138.56,56.83 137.44,56.83 137.36,56.9 137.36,58.12 137.47,58.23 137.9,58.23
+VCC_SA on IN1: 137.39,63.33 137.39,60.66 138.02,60.03 138.02,57.87 137.77,57.62 136.63,57.62 135.61,58.63 135.61,63.33 135.87,63.59 137.14,63.59
+VCC_SA on VCC: 71.33,60.28 70.84,60.77 70.84,80.73 139.93,80.73 139.93,67.75 139.29,67.12 139.29,63.33 135.1,63.33 135.1,67.37 134.45,68.03 126.95,68.03 126.47,68.52 126.47,71.31 124.69,73.09 124.69,76.9 123.91,77.68 103.73,77.68 103.73,74.63 93.34,74.63 88.49,69.79 88.49,60.28
+VCCPLL_OC on TOP: 160.12,46.06 160.12,47.84 159.49,48.47 159.11,48.47 159.09,48.46 158.38,48.46 158.22,48.29 158.22,46.31 159.03,45.5 159.73,45.5 159.88,45.65 159.88,45.81
AGND on TOP: 21.57,32.48 21.57,31.07 21.44,30.95 20.93,30.95 20.68,30.69 20.17,30.69 20.04,30.82 20.04,33.49 20.3,33.74 21.44,33.74 21.87,33.31 21.87,32.78
AGND on TOP: 21.95,21.99 22.39,21.99 22.45,22.06 22.45,23.26 22.33,23.39 20.8,23.39 20.55,23.14 20.55,22.25 20.8,21.99 21.44,21.99 21.44,22.56 21.95,22.56
AGND on BOTTOM: 5.17,20.88 5.1,20.95 5.1,21.31 5.66,21.31 5.66,21.8 5.1,21.8 5.1,22.42 5.38,22.69 7.21,22.69 7.34,22.56 7.34,21.17 7.06,20.88
AGND on GND1, GND2, GND3: 5.8,21.04 5.31,21.53 5.31,23.94 4.65,24.6 1.26,24.6 1.26,25.86 1.33,26.03 1.5,26.11 12.72,26.11 13.46,26.73 12.98,27.57 12.98,32.95 13.46,33.79 12.72,34.42 1.5,34.42 1.33,34.49 1.26,34.66 1.26,36.03 24.97,36.03 25.23,36.28 29.59,36.28 30.07,35.79 30.07,32.45 29.97,32.34 25.4,32.34 24.99,31.94 24.99,28.77 24.95,28.72 21.52,28.72 20.93,28.13 20.93,26.14 21.59,25.49 25.23,25.49 25.88,26.14 25.88,26.97 25.92,27.01 26.6,27.01 26.62,26.99 26.62,24.75 25.83,23.96 25.83,23.05 25.09,22.31 21.02,22.31 19.75,21.04
AGND on VCC: 5.8,21.04 5.31,21.53 5.31,23.94 4.65,24.6 2.27,24.6 2.27,25.09 12.72,25.09 14.35,26.17 13.99,28.09 13.99,32.43 14.35,34.35 12.72,35.43 2.27,35.43 2.27,36.03 24.97,36.03 25.23,36.28 29.59,36.28 30.07,35.79 30.07,32.45 29.97,32.34 25.4,32.34 24.99,31.94 24.99,28.77 24.95,28.72 21.52,28.72 20.93,28.13 20.93,26.14 21.59,25.49 25.23,25.49 25.88,26.14 25.88,26.97 25.92,27.01 26.6,27.01 26.62,26.99 26.62,24.75 25.83,23.96 25.83,23.05 25.09,22.31 21.02,22.31 19.75,21.04
GND on TOP (solid shape): 6.33,20.66 6.33,20.53 6.2,20.41 5.82,20.41 5.69,20.53 4.42,20.53 4.29,20.66 4.29,20.91 4.42,21.04 5.94,21.04
GND on TOP (solid shape): 75.54,38.82 75.54,36.41 76.05,35.9 76.05,34.63 75.92,34.5 74.14,34.5 74.02,34.63 74.02,39.07 74.14,39.2 75.16,39.2
GND on TOP (solid shape): 74.52,30.18 74.52,29.68 74.4,29.55 74.14,29.55 73.25,28.66 67.22,28.66 67.03,28.85 67.03,30.06 67.22,30.25 74.46,30.25
GND on TOP (solid shape): 78.33,23.2 78.33,19.77 78.08,19.52 75.16,19.52 74.91,19.77 74.91,23.07 75.16,23.33 78.21,23.33
GND on TOP (solid shape): 67.54,65.87 69.7,65.87 69.95,65.62 69.95,63.71 69.19,62.95 66.02,62.95 65.76,63.2 65.76,64.35 65.89,64.47 66.52,64.47 67.29,65.24 67.29,65.62 67.03,65.87 67.03,66 67.41,66
GND on TOP (solid shape): 64.87,43.27 69.19,43.27 69.44,43.01 69.44,39.84 69.32,39.71 66.65,39.71 66.02,40.34 65.63,40.34 65.38,40.09 64.87,40.09 62.97,42 62.97,43.52 63.09,43.65 64.49,43.65
GND on TOP (solid shape): 92.43,21.8 94.59,21.8 94.72,21.68 94.72,20.02 93.98,19.29 92.92,19.29 92.18,20.02 91.8,20.02 91.16,19.39 89.38,19.39 89.13,19.64 89.13,21.55 89.36,21.78 90.78,21.78 91.44,22.44 91.8,22.44
GND on TOP (solid shape): 168.38,37.04 168.38,33.74 168.5,33.61 169.06,33.61 169.49,33.19 169.49,31.12 168.55,31.12 168.55,32.93 168.38,33.11 167.87,33.11 167.23,33.74 167.23,34.1 167.03,34.3 166.93,34.3 166.73,34.5 166.73,34.91 166.4,35.24 166.4,36.71 166.98,37.3 168.12,37.3
GND on TOP (solid shape): 173.08,77.56 173.08,76.93 173.04,76.9 173.04,75.97 173.13,75.88 174.02,75.88 174.02,74.18 173.25,74.18 173.04,73.97 173.04,73.02 173.2,72.86 173.2,72.6 173.08,72.48 172.82,72.48 172.7,72.6 172.7,72.89 172.79,72.99 172.79,74.08 172.69,74.18 172.32,74.18 172.32,76.03 172.29,76.05 172.29,76.69 171.93,77.05 171.93,77.43 172.06,77.56 172.57,77.56 172.63,77.62 173.01,77.62
GND on TOP (solid shape): outline of 249 points within 0.65,0.39 217.56,81.75
GND on BOTTOM (solid shape): 4.93,22.18 4.93,20.66 4.8,20.53 4.29,20.53 4.04,20.79 4.04,21.93 4.42,22.31 4.8,22.31
GND on BOTTOM (solid shape): 5.18,23.83 5.18,22.82 5.06,22.69 4.29,22.69 4.17,22.82 4.17,23.83 4.29,23.96 5.06,23.96
GND on BOTTOM (solid shape): 75.79,68.59 75.79,65.36 75.54,65.11 74.4,65.11 74.27,65.24 74.27,68.28 74.75,68.77 75.62,68.77
GND on BOTTOM (solid shape): 196.7,54.19 196.7,53.17 196.57,53.04 194.29,53.04 193.9,53.43 193.9,54.44 194.16,54.7 196.19,54.7
GND on BOTTOM (solid shape): 201.65,75.65 201.65,73.24 201.4,72.98 201.14,72.98 200.76,73.36 199.11,73.36 198.98,73.49 198.98,74.84 199.62,75.47 199.62,75.9 199.75,76.03 201.27,76.03
GND on BOTTOM (solid shape): 78.33,23.2 78.33,19.77 78.08,19.52 72.37,19.52 72.11,19.77 72.11,23.07 72.24,23.2 74.91,23.2 75.03,23.07 75.03,22.44 75.29,22.18 76.43,22.18 76.68,22.44 76.68,23.2 76.81,23.33 78.21,23.33
GND on BOTTOM (solid shape): 69.95,65.62 69.95,64.6 69.85,64.5 67.97,64.5 67.67,64.19 67.67,63.97 67.79,63.84 67.79,63.2 67.57,62.98 66.05,62.98 65.76,63.26 65.76,64.45 65.85,64.54 66.35,64.54 66.36,64.55 66.41,64.55 66.6,64.73 66.76,64.73 67.28,65.25 67.28,65.69 67.46,65.87 69.7,65.87
GND on BOTTOM (solid shape): 94.84,21.66 94.84,19.9 94.34,19.39 93.02,19.39 91.77,20.63 90.88,20.63 90.65,20.41 90.65,20.02 90.46,19.83 89.57,19.83 88.77,20.63 87.84,20.63 87.78,20.69 87.78,20.81 87.85,20.89 88.91,20.89 89.28,21.26 90.88,21.26 90.96,21.34 91.71,21.34 92.29,21.92 94.59,21.92
GND on BOTTOM (solid shape): 69.44,43.01 69.44,38.82 69.19,38.57 68.56,38.57 68.17,38.95 68.17,39.71 67.79,40.09 67.03,40.09 66.14,40.98 66.14,42 65.79,42.35 64.35,42.35 63.98,41.98 62.98,41.98 62.61,42.35 61.54,42.35 61.32,42.12 61.06,42.12 60.94,42.25 60.94,42.5 61.04,42.6 62.62,42.6 62.99,42.97 64.58,42.97 64.66,43.05 65.89,43.05 65.97,43.14 69.32,43.14
GND on BOTTOM (solid shape): 9.98,25.77 10,25.74 10.01,25.74 14.45,21.29 14.45,20.02 14.33,19.9 13.18,19.9 12.93,20.15 12.93,20.66 8.99,24.6 8.94,24.6 8.92,24.61 8.69,24.72 8.44,24.65 8.41,24.63 8.38,24.65 8.32,24.68 8.24,24.71 7.98,24.98 7.98,25.99 8.09,26.11 9.64,26.11
GND on BOTTOM (solid shape): 200.55,61.81 200.32,61.81 200.32,63.13 198.62,63.13 198.62,61.81 198.6,61.81 198.22,61.43 197.16,61.43 196.95,61.21 196.95,58.31 196.71,58.07 194.1,58.07 193.99,58.18 193.99,59.5 194.16,59.67 194.54,59.67 194.56,59.65 195.17,59.65 195.43,59.9 195.43,60.54 195.17,60.79 194.41,60.79 194.29,60.92 194.29,61.43 194.92,62.06 194.92,62.32 195.05,62.44 195.81,62.44 195.94,62.57 197.21,62.57 197.97,63.33 197.97,63.59 198.07,63.69 200.55,63.69
GND on BOTTOM (solid shape): 7.09,55.83 7.1,55.83 7.35,55.58 9.8,55.58 9.98,55.76 12.12,55.76 13.86,54.02 26.48,54.02 26.48,36.22 10.69,36.22 10.69,36.49 1.25,36.49 1.25,37.71 1.33,37.88 1.5,37.96 2.52,37.96 10.78,37.96 10.87,37.94 10.96,37.88 11.1,37.79 11.27,37.76 11.59,37.89 11.72,38.21 11.72,38.74 11.73,38.74 11.73,39.57 16.47,39.57 16.47,37.02 25.68,37.02 25.68,53.22 14.69,53.22 14.69,52.8 15.09,52.41 16.1,52.41 16.61,51.9 16.61,51.77 15.6,50.76 11.73,50.76 11.73,51.08 11.72,51.08 11.72,52.11 11.59,52.43 11.27,52.56 11.1,52.53 10.96,52.44 10.89,52.39 10.8,52.37 10.78,52.36 0.95,52.36 0.65,52.6 0.65,56.47 1.04,56.85 6.07,56.85
GND on BOTTOM (solid shape): outline of 203 points within 0.65,0.44 217.56,81.75
GND on IN1 (solid shape): 16.47,36.49 1.25,36.49 1.25,37.71 1.33,37.88 1.5,37.96 2.56,37.96 10.78,37.96 10.87,37.94 10.96,37.88 11.1,37.79 11.27,37.76 11.59,37.89 11.72,38.21 11.72,38.74 11.73,38.74 11.73,39.57 16.47,39.57
GND on IN1 (solid shape): outline of 187 points within 0.65,0.39 217.56,81.75
GND on IN2 (solid shape): 16.47,36.49 1.25,36.49 1.25,37.71 1.33,37.88 1.5,37.96 2.42,37.96 10.78,37.96 10.87,37.94 10.96,37.88 11.1,37.79 11.27,37.76 11.59,37.89 11.72,38.21 11.72,38.74 11.73,38.74 11.73,39.57 16.47,39.57
GND on IN2 (solid shape): outline of 191 points within 0.65,0.42 217.56,81.75
GND on IN3 (solid shape): 16.47,36.49 1.25,36.49 1.25,37.71 1.33,37.88 1.5,37.96 2.31,37.96 10.78,37.96 10.87,37.94 10.96,37.88 11.1,37.79 11.27,37.76 11.59,37.89 11.72,38.21 11.72,38.74 11.73,38.74 11.73,39.57 16.47,39.57
GND on IN3 (solid shape): outline of 188 points within 0.65,0.43 217.56,81.75
GND on IN3 (solid shape): outline of 19020 points within 99.04,20.81 159.87,57.74
GND on IN4 (solid shape): 16.47,36.49 1.25,36.49 1.25,37.71 1.33,37.88 1.5,37.96 2.31,37.96 10.78,37.96 10.87,37.94 10.96,37.88 11.1,37.79 11.27,37.76 11.59,37.89 11.72,38.21 11.72,38.74 11.73,38.74 11.73,39.57 16.47,39.57
GND on IN4 (solid shape): outline of 186 points within 0.65,0.43 217.56,81.75
GND on TOP: 168.34,43.09 168.45,42.99 169.32,42.99 169.32,41.28 168.55,41.28 168.34,41.07 168.34,40 168.5,39.84 168.5,39.58 168.38,39.46 168.12,39.46 168,39.58 168,39.88 168.09,39.98 168.09,41.14 167.95,41.28 167.62,41.28 167.62,43.01 167.62,43.01 167.62,43.16 167.5,43.28 167.5,44.14 167.23,44.41 167.23,44.66 167.39,44.82 168.19,44.82 168.34,44.66
GND on TOP: 127.41,66.96 127.41,58.83 127.61,58.63 128.5,58.63 128.75,58.89 129.39,58.89 129.52,58.76 129.52,58.25 129.39,58.12 128.63,58.12 128.37,57.87 127.61,57.87 126.85,58.63 119.1,58.63 118.97,58.76 118.97,59.52 119.36,59.9 119.99,59.9 120.12,60.03 120.12,61.05 119.99,61.17 118.34,61.17 118.27,61.24 118.27,61.61 118.34,61.69 120.24,61.69 120.75,61.17 122.53,61.17 123.04,60.66 126.59,60.66 126.7,60.77 126.7,61.68 123.04,61.68 122.91,61.81 122.91,62.32 122.78,62.44 122.15,62.44 121.9,62.7 120.24,62.7 120.12,62.82 120.12,63.08 119.86,63.33 118.87,63.33 118.59,63.61 118.59,64.6 118.72,64.73 126.59,64.73 126.7,64.83 126.7,65.9 126.59,66 126.59,66.89 126.98,67.27 127.1,67.27
GND on TOP: 132.18,63.08 132.18,61.43 132.44,61.17 133.2,61.17 133.33,61.05 133.33,60.66 133.2,60.54 128.63,60.54 128.5,60.66 128.5,61.05 128.63,61.17 129.39,61.17 129.64,61.43 129.64,63.08 129.39,63.33 128.75,63.33 128.63,63.46 128.63,63.97 128.75,64.09 133.33,64.09 133.45,63.97 133.45,63.59 133.33,63.46 132.56,63.46
GND on TOP: 22.07,63.2 22.58,63.2 22.71,63.08 22.71,62.82 22.84,62.7 24.11,62.7 24.23,62.57 24.23,62.44 24.49,62.19 24.74,62.19 24.87,62.06 24.87,61.43 25.12,61.17 25.5,61.17 25.63,61.05 25.63,60.92 24.99,60.28 23.22,60.28 22.71,60.79 22.45,60.79 22.33,60.66 22.33,60.41 22.2,60.28 21.82,60.28 21.69,60.41 21.69,60.79 22.07,61.17 22.71,61.17 22.84,61.3 22.84,62.06 22.58,62.32 21.95,62.32 21.82,62.44 21.82,62.95
GND on TOP: 197.68,25.59 196.77,25.59 196.67,25.7 195.94,25.7 195.85,25.78 195.85,26.86 196.05,27.07 197.38,27.07 197.55,26.89 197.55,26.48 197.79,26.24 197.79,25.7
GND on TOP: 194.16,54.7 196.19,54.7 196.7,54.19 196.7,53.3 196.44,53.04 195.68,53.04 195.56,52.92 195.56,52.41 195.43,52.28 194.03,52.28 193.9,52.41 193.9,54.44
GND on TOP: 29.85,49.02 29.82,49.04 29.82,49.23 29.07,49.98 29.07,53.01 29.07,53.02 29.07,53.54 29.95,54.42 29.95,55.62 29.69,55.89 29.69,56.2 29.81,56.33 30.96,56.33 31.11,56.18 31.11,56.02 31.12,56.01 31.12,52.84 30.82,52.54 30.82,49.1 30.73,49.02
GND on TOP: 58.52,38.95 60.05,38.95 60.17,38.82 60.17,37.8 60.05,37.68 58.52,37.68 58.4,37.8 58.4,38.82
GND on TOP: 135.1,79.59 145.77,79.59 146.15,79.21 146.15,77.81 146,77.66 135.08,77.66 134.98,77.76 134.98,79.46
GND on TOP: 89.26,40.73 89.51,40.98 89.51,41.36 89.64,41.49 90.53,41.49 90.65,41.36 90.65,41.11 90.15,40.6 90.15,38.19 90.02,38.06 88.06,38.06 88.06,38.06 87.79,38.06 87.73,38.12 87.73,40.6 87.86,40.73
GND on TOP: 165.08,32.22 165.96,32.22 166.09,32.09 166.09,29.42 165.71,29.04 165.08,29.04 164.95,29.17 164.95,32.09
GND on TOP: 29.44,73.49 29.02,73.91 27.97,73.91 27.33,73.28 26.59,73.28 26.45,73.41 26.45,74.08 26.02,74.51 23.98,74.51 23.77,74.72 23.77,76.55 24.01,76.79 25.18,76.79 25.42,77.03 25.42,77.19 25.53,77.3 26.39,77.3 26.52,77.17 26.52,75.9 26.77,75.65 30.2,75.65 30.84,75.02 30.84,73.75 30.58,73.49
GND on TOP: 199.9,77.45 200.06,77.29 200.06,76.79 199.9,76.64 199.9,75.62 200.03,75.5 200.88,75.5 200.88,73.8 200.1,73.8 199.92,73.62 199.92,71.97 199.82,71.87 199.59,71.87 199.47,71.99 199.47,72.32 199.64,72.5 199.64,73.62 199.47,73.8 199.17,73.8 199.17,75.51 198.88,75.81 198.88,76.16 198.22,76.81 198.22,77.3 198.37,77.45
GND on TOP: 52.24,49.62 53.32,49.62 53.44,49.49 53.44,45.81 53.2,45.56 52.26,45.56 52.1,45.72 52.1,47.07 52.17,47.14 52.17,49.55
GND on TOP: 28.77,49.49 25.9,49.49 25.63,49.22 25.63,48.29 25.76,48.16 28.66,48.16 29.08,48.57 29.08,49.18
GND on TOP: 173.71,52.54 174.22,52.54 174.35,52.41 174.35,50.93 174.56,50.72 175.32,50.72 175.32,49.02 173.62,49.02 173.62,50.96 173.6,50.98 173.6,52.42
GND on TOP: 83.67,62.14 84.3,61.5 84.3,58 83.67,57.36 83.67,54.64 84.18,54.14 84.18,52.54 84.43,52.28 84.43,45.42 85.66,44.19 85.66,40.94 84.56,39.84 84.56,36.28 84.18,35.9 79.99,35.9 79.73,36.15 79.73,39.58 80.11,39.96 80.11,44.92 80.24,45.04 80.49,45.04 80.87,45.42 80.87,48.85 81.13,49.11 81.13,51.27 81.51,51.65 81.51,53.17 81,53.68 81,56.73 81.38,57.11 81.38,61.43 81,61.81 81,64.98 81.64,65.62 82.53,65.62 82.91,66 83.41,66 83.67,65.74
GND on TOP: 53.06,30.44 52.05,30.44 51.66,30.82 51.66,35.77 51.54,35.9 51.54,37.93 51.79,38.19 53.19,38.19 53.32,38.06 53.32,35.65 53.19,35.52 53.19,30.57
GND on TOP: 51.92,80.73 54.08,80.73 54.33,80.48 54.33,80.18 53.65,79.5 53.65,78.32 53.39,78.06 52.05,78.06 51.79,78.32 51.79,80.6
GND on TOP: 135.23,67.4 137.01,67.4 137.26,67.14 137.26,66.89 136.75,66.38 136.75,62.95 136.25,62.44 135.48,62.44 135.23,62.19 135.23,61.68 136.88,60.03 136.98,60.03 137.16,59.85 137.16,59.29 137.01,59.14 133.96,59.14 133.83,59.27 133.83,59.78 133.96,59.9 134.6,59.9 134.72,60.03 134.72,65.44 134.9,65.62 134.9,66.25 135.1,66.25 135.23,66.38 135.23,66.89 135.1,67.01 135.1,67.27
GND on TOP: 20.61,20.91 22.26,20.91 22.45,21.1 22.45,21.61 22.26,21.8 21.76,21.8 21.76,22.37 21.63,22.37 21.63,21.8 20.74,21.8 20.55,21.61 20.55,20.98
GND on TOP: 71.22,45.68 72.24,45.68 72.49,45.42 72.49,44.28 72.37,44.15 71.48,44.15 71.35,44.28 71.35,45.04 71.1,45.3 71.1,45.55
GND on TOP: 193.9,59.78 194.92,60.79 194.92,62.32 195.05,62.44 195.81,62.44 196.32,62.95 197.46,62.95 197.59,62.82 197.59,61.68 196.95,61.05 196.95,58.19 196.83,58.07 194.1,58.07 193.9,58.27
GND on TOP: 87.1,31.1 87.1,29.55 86.72,29.17 84.43,29.17 84.05,29.55 84.05,31.07 83.8,31.33 81.64,31.33 81.38,31.58 81.38,33.53 81.85,33.99 81.85,33.99 82.07,34.21 83.69,34.21 83.78,34.12 83.78,32.32 84.32,31.78 85.9,31.78 87.22,33.1 87.73,33.1 88.38,33.75 89.85,33.75 89.98,33.63 89.98,32.73 89.79,32.55 88.54,32.55
GND on TOP: 16.23,57.11 16.23,55.84 16.36,55.71 16.36,54.7 16.49,54.57 17.5,54.57 17.63,54.7 17.63,56.35 17.88,56.6 19.15,56.6 19.28,56.73 19.28,57.74 19.15,57.87 17.88,57.87 17.25,57.24 16.36,57.24
GND on TOP: 85.89,42.57 86.61,42.57 86.65,42.53 86.65,41.8 86.84,41.61 86.84,41.3 86.78,41.23 86.02,41.23 85.83,41.42 85.83,42.5
GND on TOP: 44.55,42.5 50.14,42.5 50.39,42.25 50.39,42 50.14,41.74 48.36,41.74 48.11,41.49 48.11,38.19 48.74,37.55 48.74,37.04 48.62,36.92 48.11,36.92 47.85,37.17 45.31,37.17 44.3,38.19 44.3,39.46 43.79,39.96 43.79,40.34 44.43,40.98 44.43,42.38
GND on BOTTOM: 67.54,55.71 70.59,55.71 70.84,55.46 70.84,54.7 70.59,54.44 70.59,53.81 70.84,53.55 71.35,53.55 71.48,53.43 71.48,51.14 71.22,50.89 68.81,50.89 68.56,51.14 66.4,51.14 66.14,51.39 66.14,53.43 67.29,54.57 67.29,55.46
GND on BOTTOM: 29.69,31.84 25.63,31.84 24.99,31.2 24.99,27.39 25.12,27.26 27.15,27.26 27.46,26.96 29.34,26.96 29.79,27.42 31.06,27.42 31.22,27.57 31.22,28.41 31.09,28.53 30.33,28.53 29.95,28.91 29.95,31.58
GND on BOTTOM: 90.19,40.34 90.19,38.09 90.16,38.06 88.46,38.06 88.46,39.76 89.18,39.76 89.43,40.01 89.43,41.5 89.27,41.67 87.31,41.67 86.96,41.32 85.92,41.32 85.82,41.41 85.82,42.49 85.87,42.54 89.96,42.54 90.6,41.9 91.13,41.9 91.42,42.19 91.42,43.51 91.65,43.74 94.76,43.74 95.24,43.26 95.24,42.7 95.01,42.47 92.31,42.47
GND on BOTTOM: 29.31,23.58 30.2,23.58 30.46,23.33 31.85,23.33 32.11,23.07 32.11,21.93 31.85,21.68 31.09,21.68 29.57,20.15 29.31,20.15 29.06,20.41 29.06,21.8 29.19,21.93 29.19,23.45
GND on BOTTOM: 22.91,52.8 20.42,52.8 20.26,52.65 20.26,52.01 20.42,51.85 21.45,51.85 22.07,51.23 22.07,50.14 22.13,50.08 22.9,50.08 23.04,50.22 23.04,52.66
GND on BOTTOM: 99.04,69.94 100.31,69.94 101.83,68.41 105.05,68.41 105.49,67.98 105.49,66.48 105.26,66.25 101.7,66.25 100.56,65.11 100.56,64.09 100.31,63.84 99.04,63.84 98.78,64.09 98.78,69.68
GND on BOTTOM: 1.55,24.11 1.55,22.46 2.59,22.46 2.59,24.11
GND on BOTTOM: 46.84,15.96 48.49,15.96 50.27,17.74 53.19,17.74 53.7,18.25 53.7,19.14 53.57,19.26 52.17,19.26 51.41,20.02 50.65,20.02 49.63,19.01 48.49,19.01 47.85,19.64 46.71,19.64 46.58,19.52 46.58,16.21
GND on BOTTOM: 74.14,39.2 75.16,39.2 75.54,38.82 75.54,36.41 76.51,35.43 76.51,34.66 76.36,34.5 74.14,34.5 74.02,34.63 74.02,39.07
GND on BOTTOM: 201.4,67.4 201.4,65.87 201.52,65.74 202.16,65.74 202.29,65.87 202.29,66.38 202.54,66.63 203.56,66.63 203.81,66.38 204.32,66.38 204.45,66.51 204.45,67.52 203.94,68.03 202.03,68.03
GND on BOTTOM: 58.52,38.57 60.17,38.57 60.3,38.44 60.3,37.55 60.17,37.42 58.52,37.42 58.4,37.55 58.4,38.44
GND on BOTTOM: 71.27,76.64 72.31,76.64 72.87,77.2 72.87,77.94 72.7,78.11 72.42,78.11 72.31,78.01 72.31,77.66 71.91,77.25 71.25,77.25 71.15,77.15 71.15,76.77
GND on BOTTOM: 202.16,16.47 202.41,16.21 204.06,16.21 204.45,16.6 207.11,16.6 207.37,16.34 207.37,14.44 207.24,14.31 200.51,14.31 200.38,14.44 200.38,16.09 200.76,16.47
GND on BOTTOM: 87,30.72 87,29.01 85.3,29.01 85.3,30.72 86.11,30.72 86.27,30.88 86.27,32.76 86.09,32.95 84.74,32.95 84.21,32.41 84.21,31.6 83.81,31.2 81.51,31.2 81.45,31.26 81.45,32.18 82.15,32.88 82.36,32.88 82.57,32.67 83.25,32.67 84.21,33.64 86.11,33.64 86.11,33.63 86.28,33.63 86.54,33.37 87.11,33.37 87.23,33.49 88.59,33.49 88.78,33.69 90.97,33.69 91.02,33.64 91.02,32.98 90.72,32.67 88.42,32.67 87.82,32.08 87.82,31.53
GND on BOTTOM: 17.62,44.4 17.82,44.6 18.9,44.6 19.28,44.22 19.28,41.78 19.12,41.63 17.79,41.63 17.62,41.79
GND on BOTTOM: 73.53,75.8 74.57,75.8 74.91,75.47 74.91,74.74 74.6,74.43 73,74.43 72.77,74.66 72.77,75.04
GND on BOTTOM: 81.51,66.13 83.54,66.13 83.67,66 83.67,61.93 84.3,61.3 84.3,58 83.64,57.34 83.64,53.45 84.3,52.79 84.3,50.5 83.65,49.85 83.65,45.83 85.69,43.79 85.69,40.97 84.56,39.84 84.56,36.92 83.92,36.28 82.14,36.28 81.76,35.9 79.99,35.9 79.73,36.15 79.73,43.65 81.37,45.29 81.37,50.13 81.08,50.43 81.08,51.22 81.38,51.52 81.38,66
GND on BOTTOM: 47.87,27.84 46.81,27.84 46.78,27.88 46.45,27.88 46.35,27.77 46.35,26.55 46.67,26.23 47.83,26.23 47.95,26.35 47.95,27.77
GND on BOTTOM: 96.37,54.7 99.67,54.7 99.92,54.44 99.92,52.28 100.56,51.65 100.56,46.57 99.92,45.93 99.29,45.93 98.91,46.31 98.91,48.73 97.77,49.87 97.77,52.66 97.38,53.04 96.37,53.04 96.24,53.17 96.24,54.57
GND on BOTTOM: 53.19,33.49 53.53,33.14 54.55,33.14 54.59,33.11 54.59,31.07 53.95,30.44 52.05,30.44 51.66,30.82 51.66,35.6 51.66,35.62 51.38,35.91 51.1,35.91 51.06,35.95 51.06,37.45 51.79,38.19 53.19,38.19 53.32,38.06 53.32,35.65 53.19,35.52
GND on BOTTOM: 18.83,59.14 17.31,59.14 16.55,58.38 16.23,58.38 15.85,58 15.85,55.65 15.98,55.52 16.42,55.52 16.68,55.77 16.68,56.98 16.93,57.24 17.76,57.24 18.07,56.92 18.39,56.92 19.09,57.62 19.09,58.89
GND on BOTTOM: 98.78,42.88 99.04,42.63 99.04,41.49 98.78,41.23 95.99,41.23 95.23,42 95.23,42.5 95.61,42.88
GND on BOTTOM: 1.55,18.61 1.55,20.26 2.59,20.26 2.59,18.61
GND on BOTTOM: 73.38,30.31 67.29,30.31 67.03,30.06 67.03,29.04 67.29,28.79 71.73,28.79 71.86,28.66 73.25,28.66 73.64,29.04 73.64,30.06
GND on BOTTOM: 9.63,13.55 10.26,12.91 10.26,12.02 8.61,10.37 7.09,10.37 6.2,11.26 6.2,12.28 7.47,13.55
GND on BOTTOM: 85.45,17.87 85.57,17.74 85.57,16.34 85.45,16.21 84.43,16.21 84.3,16.34 84.3,17.74 84.43,17.87
GND on BOTTOM: 55.09,49.87 55.47,49.49 55.47,47.41 55.37,47.31 55.11,47.31 54.89,47.09 54.89,46.2 54.87,46.18 53.79,46.18 53.15,45.53 52.22,45.53 52.06,45.69 52.06,49.03 52.91,49.87
GND on BOTTOM: 180.82,43.65 183.62,43.65 184.63,42.63 184.63,40.85 184.38,40.6 180.82,40.6 180.57,40.85 180.57,43.39
GND on BOTTOM: 182.47,23.96 183.87,23.96 184,23.83 184,21.68 183.87,21.55 180.82,21.55 180.7,21.68 180.7,23.33 181.08,23.71 182.22,23.71
GND on BOTTOM: 58.65,28.66 63.98,28.66 64.24,28.41 64.24,22.18 62.59,20.53 58.4,20.53 57.89,20.02 55.35,20.02 55.22,20.15 55.22,23.33 55.86,23.96 57.76,23.96 58.4,24.6 58.4,28.41
GND on GND1: outline of 166 points within 0.26,0.26 217.56,81.75 ; 7 cut-outs
GND on IN1: 13.93,65.01 8.1,65.01 6.85,63.76 6.85,58.99 8.51,57.33 9.48,57.33 9.51,57.36 9.83,57.36 10.12,57.07 13.2,57.07 14.6,58.47 14.6,64.34
GND on IN1: 83.41,49.74 81.76,49.74 81.38,49.36 81.38,46.31 81.76,45.93 83.41,45.93 83.67,46.19 83.67,49.49
GND on IN1: 34.02,64.81 32.89,64.81 32.54,64.46 31.72,64.46 31.01,63.75 31.01,63.12 31.61,62.52 32.29,62.52 33.51,61.29 35.67,61.29 36,60.97 37.2,60.97 38.49,62.26 38.49,64.92 38.28,65.13 37.12,65.13 36.47,65.78 34.99,65.78
GND on IN1: 11.72,50.63 11.72,52.11 11.4,52.54 10.89,52.36 0.9,52.36 0.73,52.44 0.65,52.61 0.65,56.98 5.94,56.98 7.34,55.58 11.37,55.58 12.92,54.04 14.86,54.04 16.61,52.28 16.61,50.89 16.36,50.63
GND on IN1: 80.87,51.52 80.87,64.6 81.76,65.49 82.65,65.49 83.16,66 83.41,66 83.67,65.74 83.67,61.05 84.3,60.41 84.3,51.39 84.18,51.27 81.13,51.27
GND on GND2: outline of 166 points within 0.26,0.26 217.56,81.75 ; 6 cut-outs
GND on IN2: 11.72,50.76 11.72,52.11 11.4,52.54 10.89,52.36 0.9,52.36 0.73,52.44 0.65,52.61 0.65,56.85 6.07,56.85 7.98,54.95 12.93,54.95 16,51.88 16.38,51.88 16.49,51.77 16.49,51.06 16.18,50.76
GND on IN3: 11.72,50.76 11.72,52.11 11.4,52.54 10.89,52.36 0.9,52.36 0.73,52.44 0.65,52.61 0.65,56.85 6.07,56.85 7.98,54.95 12.93,54.95 15.85,52.03 16.26,52.03 16.51,51.77 16.51,51.55 15.72,50.76
GND on VCC: 191.6,53.3 193.4,55.1 193.4,80.73 198.73,80.73 199.05,80.9 199.41,80.95 199.92,80.95 200.28,80.9 200.61,80.73 204.93,80.73 204.93,42 201.42,42 198.12,38.69 174.88,38.69 171.04,34.86 171.04,24.07 170.05,23.07 160.02,23.07 157.86,20.91 103.46,20.91 99.67,24.7 99.67,32.96 98.53,34.1 98.53,34.99 97.13,36.39 97.13,55.1 102.32,60.28 109.47,60.28 113.79,55.97 117.17,55.97 117.24,56.03 125.02,56.03 125.28,56.28 127.66,56.28 128.18,55.76 128.18,55 128.67,54.5 138.1,54.5 138.74,55.14 141.25,55.14 141.31,55.07 141.42,54.76 141.73,54.65 141.9,54.49 141.9,52.58 141.83,52.51 141.83,52.18 143.25,50.76 144.9,50.76 146.05,49.62 166.96,49.62 169.65,52.3 169.65,53.07 169.88,53.3 ; 1 cut-out
GND on VCC: 2.27,36.53 2.27,36.94 10.53,36.94 12,36.94 12.74,38.21 12.74,52.11 12,53.38 10.53,53.38 1.67,53.38 1.67,65.72 2.49,65.72 2.96,65.77 3.41,65.92 4.55,66.42 4.55,58.02 8.63,53.93 20.78,53.93 22.07,55.22 22.07,65 24.21,67.14 27.43,67.14 27.79,66.78 27.79,57.34 26.77,56.32 26.77,54.34 27.79,53.32 27.79,36.89 27.68,36.79 25.02,36.79 24.76,36.53
GND on IN4: 8.97,55.79 8.53,56.23 7.05,56.23 6.2,57.08 5.38,57.08 4.76,57.71 4.76,63.56 5.37,64.18 7.19,64.18 7.86,64.85 10.54,64.85 10.95,64.49 11.36,64.85 12.21,64.85 15.25,67.89 24,67.89 24.7,67.2 36.5,67.2 37.44,66.26 37.44,63.2 37.26,63.01 37.26,60.99 37.01,60.75 36.66,60.75 36.55,60.87 35.85,60.87 35.28,60.29 35.28,59.36 35.05,59.14 32.5,59.14 30.47,57.11 27.04,57.11 25.16,58.99 16.11,58.99 12.92,55.79
GND on IN4: 11.72,50.76 11.72,52.11 11.4,52.54 10.89,52.36 0.9,52.36 0.73,52.44 0.65,52.61 0.65,56.85 6.07,56.85 6.83,56.09 8.36,56.09 10.77,53.68 14.2,53.68 15.93,51.95 16.36,51.95 16.51,51.8 16.51,51.55 15.72,50.76
GND on GND3: outline of 166 points within 0.26,0.26 217.56,81.75 ; 11 cut-outs
GNDA_CHG on TOP: 40.23,34.76 41.5,33.49 41.5,32.22 41.12,31.84 41.12,31.07 41.38,30.82 42.52,30.82 42.77,30.57 42.77,28.41 42.01,27.64 39.98,27.64 39.85,27.77 39.85,31.07 40.74,31.96 40.74,32.72 39.22,34.25 38.33,34.25 38.08,33.99 38.08,33.61 37.95,33.49 37.31,33.49 37.19,33.61 37.19,34.38 37.57,34.76
VCC0V9_LVR_OUT on IN3: 31.99,65.49 41,65.49 41.25,65.24 41.25,60.54 41.63,60.16 41.63,58.25 41.38,58 37.57,58 31.85,63.71 31.85,65.36
VCC0V9_SVR on TOP: 34.01,52.53 34.01,49.19 33.69,48.87 31.44,48.87 31.22,49.09 31.22,52.48 31.29,52.55 31.88,52.55 32.05,52.72 33.82,52.72
VCC0V9_SVR on TOP: 35.92,60.91 36.58,60.25 36.58,58.92 36.46,58.8 36.08,58.8 36,58.88 36,59.74 35.92,59.81 33.59,59.81 33.56,59.84 33.56,60.75 33.73,60.91
VCC0V9_SVR on BOTTOM: 42.52,58.12 42.39,58 38.81,58 38.33,57.51 36.78,57.51 35.79,58.51 35.54,58.51 35.28,58.25 35.28,57.49 35.92,56.85 35.92,53.84 33.5,51.42 33.5,49.44 33.27,49.21 32.04,49.21 31.85,49.39 31.85,57.18 35.12,60.45 36.67,60.45 37.31,61.1 37.31,63.25 37.69,63.64 39.61,63.64 40.45,62.8 40.45,60.14 40.77,59.83 42.39,59.83 42.52,59.7
VCC0V9_SVR on IN2: 41.33,58.25 42.32,59.25 42.39,59.32 42.39,59.65 42.27,59.78 40.74,59.78 40.36,60.15 40.36,63.46 39.98,63.84 36.14,63.84 35.06,62.76 35.06,58.58 35.4,58.25
VCC0V9_SVR on IN4: 35.79,58.89 36.68,58.89 37.19,59.4 39.77,59.4 40.03,59.14 42.22,59.14 42.45,59.36 42.45,59.87 42.41,59.83 40.73,59.83 40.54,60.02 40.54,62.36 39.45,63.46 38.71,63.46 38.2,62.95 37.72,62.95 37.34,62.56 37.34,60.96 37.14,60.76 35.95,60.76 35.41,60.22 35.41,59.27
VCC3V3_TBT_LDO on TOP: 40.87,39.71 41.38,39.71 41.5,39.58 41.5,39.2 41.63,39.07 43.54,39.07 43.79,38.82 43.79,38.06 43.66,37.93 42.77,37.93 42.01,38.69 41.63,38.69 41.5,38.57 41.5,38.06 41.38,37.93 40.87,37.93 40.74,38.06 40.74,39.58
VIN_1V_PRIM on TOP: 83.54,29.3 81.89,29.3 80.75,30.44 80.11,30.44 79.99,30.57 79.99,31.45 80.11,31.58 80.87,31.58 81.38,31.07 83.54,31.07 83.8,30.82 83.8,29.55
VIN_1V_PRIM on BOTTOM: 84.8,31.07 85.05,30.82 85.05,29.55 84.98,29.49 80.41,29.49 80.33,29.57 80.33,30.73 80.67,31.07
VIN_PRIM on TOP: 203.43,74.63 203.18,74.38 202.23,74.38 202.12,74.27 201.18,74.27 201.13,74.32 201.13,75.51 201.27,75.65 201.91,75.65 202.03,75.78 202.03,77.03 201.36,77.71 201.36,79.83 201.62,80.1 203.05,80.1 203.43,79.71
VIN_VCC_EDRAM on TOP: 87.48,38.31 87.35,38.19 86.08,38.19 85.7,38.57 85.7,38.83 85.38,39.15 85.38,40.15 85.76,40.53 85.76,41.04 85.89,41.17 87.29,41.17 87.48,40.98
VIN_VCC_EDRAM on BOTTOM: 88.21,40.38 88.21,38.59 88.15,38.53 85.99,38.53 85.7,38.82 85.7,38.94 85.43,39.21 85.43,40.2 85.74,40.51 85.74,41.07 85.85,41.18 87.4,41.18
VIN_VCCIO on TOP: 175.65,49.49 177.78,49.49 178.03,49.74 178.03,50.63 178.54,51.14 178.54,52.54 178.44,52.64 177.06,52.64 176.89,52.46 176.89,51.39 176.24,50.75 175.65,50.75 175.58,50.67 175.58,49.56
VIN_VCCIO on BOTTOM: 178.16,52.28 178.28,52.16 178.28,50.89 178.03,50.63 178.03,49.61 177.94,49.52 176.76,49.52 176.17,50.1 176.17,52.1 176.35,52.28
+AC_IN on BOTTOM: 53.7,61.17 53.82,61.05 54.59,61.05 54.65,61.11 54.65,62.57 54.9,62.82 55.35,62.82 55.54,62.63 55.54,61.11 55.6,61.05 55.92,61.05 56.05,61.17 56.55,61.17 56.62,61.24 56.62,62.44 57.22,63.05 57.89,63.05 59.02,64.18 59.49,64.18 59.67,64.35 59.67,66.7 59.61,66.76 58.14,66.76 56.3,64.92 55.93,64.92 55.78,64.77 55.32,64.77 55.03,64.47 55.03,64.12 54.86,63.95 53.9,63.95 53.7,63.75
+AC_IN on BOTTOM: 48.02,78.18 48.38,78.18 48.62,77.94 50.65,77.94 50.9,77.68 50.9,75.02 50.78,74.89 48.87,74.89 48.74,75.02 48.74,75.4 48.49,75.65 47.09,75.65 47.09,75.9 47.35,76.16 47.73,76.16 47.97,76.4 47.97,78.12
+AC_IN on IN4: 48.24,75.78 48.24,78.06 49.76,79.59 58.4,79.59 59.16,78.83 59.16,74.13 60.81,72.48 60.81,70.1 59.89,69.19 59.89,65.5 59.5,65.11 57.25,65.11 57,65.36 57,69.05 56.43,69.62 56.43,73.68 55.35,74.76 49.25,74.76
+DC_IN on TOP: 26.77,77.56 26.77,76.16 26.9,76.03 30.84,76.03 31.6,76.79 31.6,77.56 31.22,77.94 27.15,77.94
+DC_IN on BOTTOM: 29.19,78.19 29.95,78.95 31.09,78.95 31.22,78.83 31.22,78.32 31.34,78.19 33.38,78.19 33.5,78.06 33.5,77.43 33.38,77.3 32.23,77.3 32.11,77.17 32.11,75.81 31.95,75.65 31.62,75.65 30.86,76.41 29.19,76.41 29.06,76.54 29.06,77.17 29.19,77.3
+DC_IN_SS on BOTTOM: 32.36,77.17 33.38,77.17 33.63,76.92 33.63,76.41 33.88,76.16 36.3,76.16 36.42,76.03 36.42,75.02 36.3,74.89 32.36,74.89 32.23,75.02 32.23,77.05
+DCIN_JACK on TOP: 23.6,78.7 23.6,77.94 23.72,77.81 26.26,77.81 26.52,78.06 28.41,78.06 28.62,78.27 28.62,78.64 28.44,78.83 23.72,78.83
+DCIN_JACK on BOTTOM: 28.68,74.76 28.42,74.51 26.65,74.51 26.63,74.52 25.54,74.52 25.35,74.71 25.35,78.53 25.77,78.95 28.83,78.95 29.06,78.72 29.06,77.56 28.68,77.17
+INV_PWR_SRC on TOP: 197.08,24.98 200.38,24.98 201.65,23.71 201.65,17.99 201.4,17.74 197.84,17.74 197.65,17.93 197.65,18.31 197.21,18.75 195.3,18.75 193.27,20.79 193.27,26.37 193.52,26.63 195.43,26.63 195.7,26.36 195.7,25.65 195.85,25.5 196.55,25.5
+INV_PWR_SRC on BOTTOM: 192.13,26.5 193.9,26.5 194.03,26.37 194.03,24.98 193.78,24.72 192.25,24.72 192.13,24.85
+LCDVDD on TOP: 192.63,32.34 192.51,32.47 192.51,35.52 192.63,35.65 194.41,35.65 194.84,35.21 197.16,35.21 197.97,36.03 197.97,37.68 198.45,38.16 198.45,39.07 198.5,39.12 199.44,39.12 199.55,39.02 199.55,37.57 199.79,37.32 202.28,37.32 202.53,37.07 202.53,31.35 202.34,31.16 200.48,31.16 200.34,31.3 200.34,32.32 199.18,33.49 195.3,33.49 194.16,32.34
+LCDVDD on BOTTOM: 194.16,34.38 193.52,33.74 190.97,33.74 189.61,32.38 189.61,29.82 188.96,29.17 188.96,27.61 188.8,27.44 188.2,27.44 188.05,27.59 188.05,32.04 188.69,32.68 188.69,34.96 189.25,35.52 193.9,35.52 194.16,35.26
+PBATT on BOTTOM: 74.02,29.04 78.21,29.04 78.72,28.53 78.72,25.74 78.46,25.49 77.83,25.49 77.32,24.98 77.32,23.96 77.06,23.71 75.67,23.71 75.54,23.83 75.54,26.76 75.29,27.01 74.02,27.01 73.76,27.26 73.76,28.79
+PP_HV on TOP: 25.96,62.19 28.55,62.19 28.68,62.06 28.68,60.79 28.42,60.54 27.53,60.54 26.77,61.3 25.38,61.3 25.25,61.43 25.25,61.55 25.38,61.68 25.45,61.68
+PP_HV on IN1: 28.7,60.57 26.63,60.57 26.34,60.86 26.34,62.09 27.42,63.17 27.42,69.76 31.02,73.37 31.02,74.97 31.27,75.22 32.51,75.22 32.77,74.95 32.77,73.05 29.04,69.31 29.04,60.91
+PWR_SRC_AC on BOTTOM: 48.74,32.34 49.76,32.34 50.14,31.96 50.14,30.69 50.27,30.57 50.27,28.41 50.14,28.28 49.89,28.28 49.76,28.41 49.76,30.06 49.63,30.18 49,30.18 48.87,30.06 48.87,28.41 48.62,28.15 48.36,28.15 48.24,28.28 48.24,31.84
+RTCVCC on TOP: 192,58.25 193.14,58.25 193.27,58.12 193.27,57.36 193.14,57.24 192,57.24 191.87,57.36 191.87,58.12
+RTCVCC on IN2: 140.31,56.85 141.07,56.85 141.45,56.47 141.45,52.79 143.49,50.76 144.25,50.76 144.5,50.5 144.5,49.23 144.25,48.98 143.1,48.98 140.18,51.9 140.18,56.73
+SDC_IN on TOP: 45.24,22.27 43.14,22.27 42.63,21.76 41.92,21.76 41.76,21.93 41.76,23.22 41.88,23.34 41.88,24.33 42.4,24.85 44.93,24.85 45.06,24.98 45.06,25.82 45.34,26.11 48.61,26.11 49.99,24.72 49.99,23.87 49.48,23.35 45.72,23.35 45.44,23.07 45.44,22.46
+SDC_IN on BOTTOM: 48.24,27.39 48.62,27.39 48.74,27.26 48.74,25.49 48.87,25.36 49.63,25.36 49.76,25.49 49.76,27.26 49.89,27.39 50.14,27.39 50.27,27.26 50.27,23.83 50.01,23.58 48.36,23.58 48.11,23.83 48.11,27.26
+SDC_IN on BOTTOM: 35.41,79.15 35.41,77.43 34.9,76.92 34.9,76.41 37.57,76.41 37.95,76.79 39.73,76.79 39.85,76.92 39.85,77.17 39.6,77.43 38.57,77.43 38.36,77.64 38.36,77.98 38.57,78.19 40.11,78.19 40.23,78.31 40.23,79.08 40.11,79.21 36.05,79.21 36.05,79.21 35.46,79.21
+SDC_IN on IN2: 37.82,79.33 37.82,77.56 37.31,77.05 36.17,77.05 35.79,76.67 33.38,76.67 32.11,75.4 29.69,75.4 28.55,74.25 23.72,74.25 21.95,72.48 21.95,69.43 20.17,67.65 20.17,66.59 18.71,65.13 18.71,57.98 19.91,56.77 19.91,55.58 26.37,49.13 26.37,44.19 28.75,41.8 31.28,41.8 33.12,39.96 33.12,39.2 34.1,38.22 34.1,36.65 34.4,36.36 34.4,33.16 34.41,33.15 34.41,33.06 33.26,31.91 33.26,26.49 33.26,26.39 31.09,24.22 31.09,23.41 30.11,22.43 30.11,20.21 30.2,20.12 30.2,17.23 27.41,14.44 20.55,14.44 19.91,15.07 19.91,19.9 21.06,21.04 24.61,21.04 26.39,22.82 26.39,23.71 27.15,24.47 27.15,28.28 29.04,30.16 29.04,35.7 28.25,36.49 24.15,36.49 17.48,43.15 17.48,50.77 14.78,53.48 14.78,53.51 11.89,56.4 11.89,64.74 16.99,69.84 16.99,78.7 17.76,79.46 37.69,79.46
+SDC_IN on IN3: 23.72,15.96 23.98,16.21 34.65,16.21 35.54,15.33 46.76,15.33 50.65,19.21 50.65,24.6 49.89,25.36 48.62,25.36 47.6,24.34 47.6,20.91 46.08,19.39 30.58,19.39 29.57,20.41 26.01,20.41 24.99,19.39 19.91,19.39 19.41,18.88 19.41,16.21 19.66,15.96
+VCHGR on TOP: 76.3,34.25 71.32,34.25 70.96,33.88 70.96,32.59 70.33,31.96 67.79,31.96 67.67,31.84 67.67,30.95 68.17,30.44 76.18,30.44 76.64,30.9 76.64,33.9
+VCHGR on BOTTOM: 77.06,34.25 70.97,34.25 70.84,34.12 70.84,33.87 70.97,33.74 72.62,33.74 72.87,33.49 72.87,32.98 72.62,32.72 71.1,32.72 70.33,31.96 67.79,31.96 67.67,31.84 67.67,30.95 68.17,30.44 77.06,30.44 77.32,30.69 77.32,33.99
+VREFCA on BOTTOM: 103.35,20.28 102.85,20.79 102.85,25.99 103.48,26.63 108.31,26.63 110.47,24.47 115.29,24.47 117.7,26.88 120.12,26.88 120.24,26.76 120.24,26.12 119.61,25.49 119.61,24.85 118.85,24.09 117.96,24.09 117.07,23.2 115.93,23.2 114.15,21.42 110.59,21.42 110.59,21.17 109.7,20.28 ; 1 cut-out
+VREFCA on BOTTOM: 139.55,26.63 139.8,26.37 139.8,24.34 140.44,23.71 140.44,21.93 139.29,20.79 139.29,20.02 139.04,19.77 138.53,19.77 138.28,20.02 138.28,21.93 136.75,23.45 136.75,26.37 137.01,26.63
+VREFCA on IN2: 99.54,26.76 104.12,26.76 104.24,26.63 104.24,25.36 103.35,24.47 101.78,24.47 101.02,23.71 100.81,23.71 100.56,23.45 100.56,23.07 100.69,22.95 101.02,22.95 101.91,22.06 104.14,22.06 104.45,21.75 104.45,21.04 104.29,20.89 100.99,20.89 99.82,22.06 99.82,24.32 99.42,24.72 99.42,26.63
-DCIN_JACK on TOP: 26.01,74.25 26.26,74 26.26,72.48 25.63,71.84 25.63,71.08 25.38,70.82 23.93,70.82 23.62,71.13 23.62,74.13 23.75,74.25
-DCIN_JACK on BOTTOM: 28.42,70.7 28.68,70.95 28.68,72.86 28.42,73.11 24.7,73.11 24.7,73.1 24.29,73.1 24.16,72.97 24.16,70.89 24.35,70.7
B+ on TOP (solid shape): 178.16,80.1 178.16,78.83 178.03,78.7 177.27,78.7 177.14,78.83 177.14,80.1 177.39,80.35 177.9,80.35
B+ on BOTTOM (solid shape): 93.57,28.21 93.57,25.36 93.45,25.23 92.56,25.23 92.43,25.36 92.43,27.64 92.43,27.65 92.43,28.15 92.61,28.33 93.46,28.33
B+ on BOTTOM (solid shape): 73.33,43.61 73.33,42.84 72.77,42.84 72.77,42.08 73.33,42.08 73.33,41.64 72.77,41.64 72.77,40.88 73.33,40.88 73.33,40.14 73.64,39.84 73.64,34.63 73.51,34.5 70.71,34.5 69.95,33.74 69.95,33.74 69.87,33.66 68.44,33.66 68.21,33.43 68.21,33.06 68.39,32.88 69.96,32.88 69.99,32.85 69.99,32.38 69.83,32.22 67.54,32.22 67.16,31.84 67.16,30.69 66.65,30.18 63.48,30.18 63.22,30.44 63.22,35.19 64.69,36.66 68.89,36.66 69.83,37.6 69.83,38.39 69.57,38.64 69.57,42.63 69.58,42.64 69.58,43.07 69.63,43.13 71.08,43.13 71.86,43.9 73.04,43.9
B+ on TOP: 71.17,43.21 71.86,43.9 73.25,43.9 73.51,43.65 73.51,34.63 73.38,34.5 70.08,34.5 69.83,34.76 69.83,41.75 69.53,42.05 69.53,43.04 69.71,43.21
B+ on TOP: 197.08,18.37 197.4,18.06 197.4,16.91 197.71,16.6 199.11,16.6 199.75,17.23 201.4,17.23 201.65,16.98 201.65,16.21 201.08,15.64 200.25,15.64 200,15.39 200,14.06 199.75,13.8 199.11,13.8 197.65,15.26 195.62,15.26 194.92,15.96 194.92,18.12 195.17,18.37
B+ on TOP: 179.17,52.84 180.57,52.84 180.82,52.59 180.82,50.43 180.57,50.17 179.93,50.17 179.68,50.43 179.68,51.44 179.55,51.57 179.17,51.57 179.05,51.7 179.05,52.71
